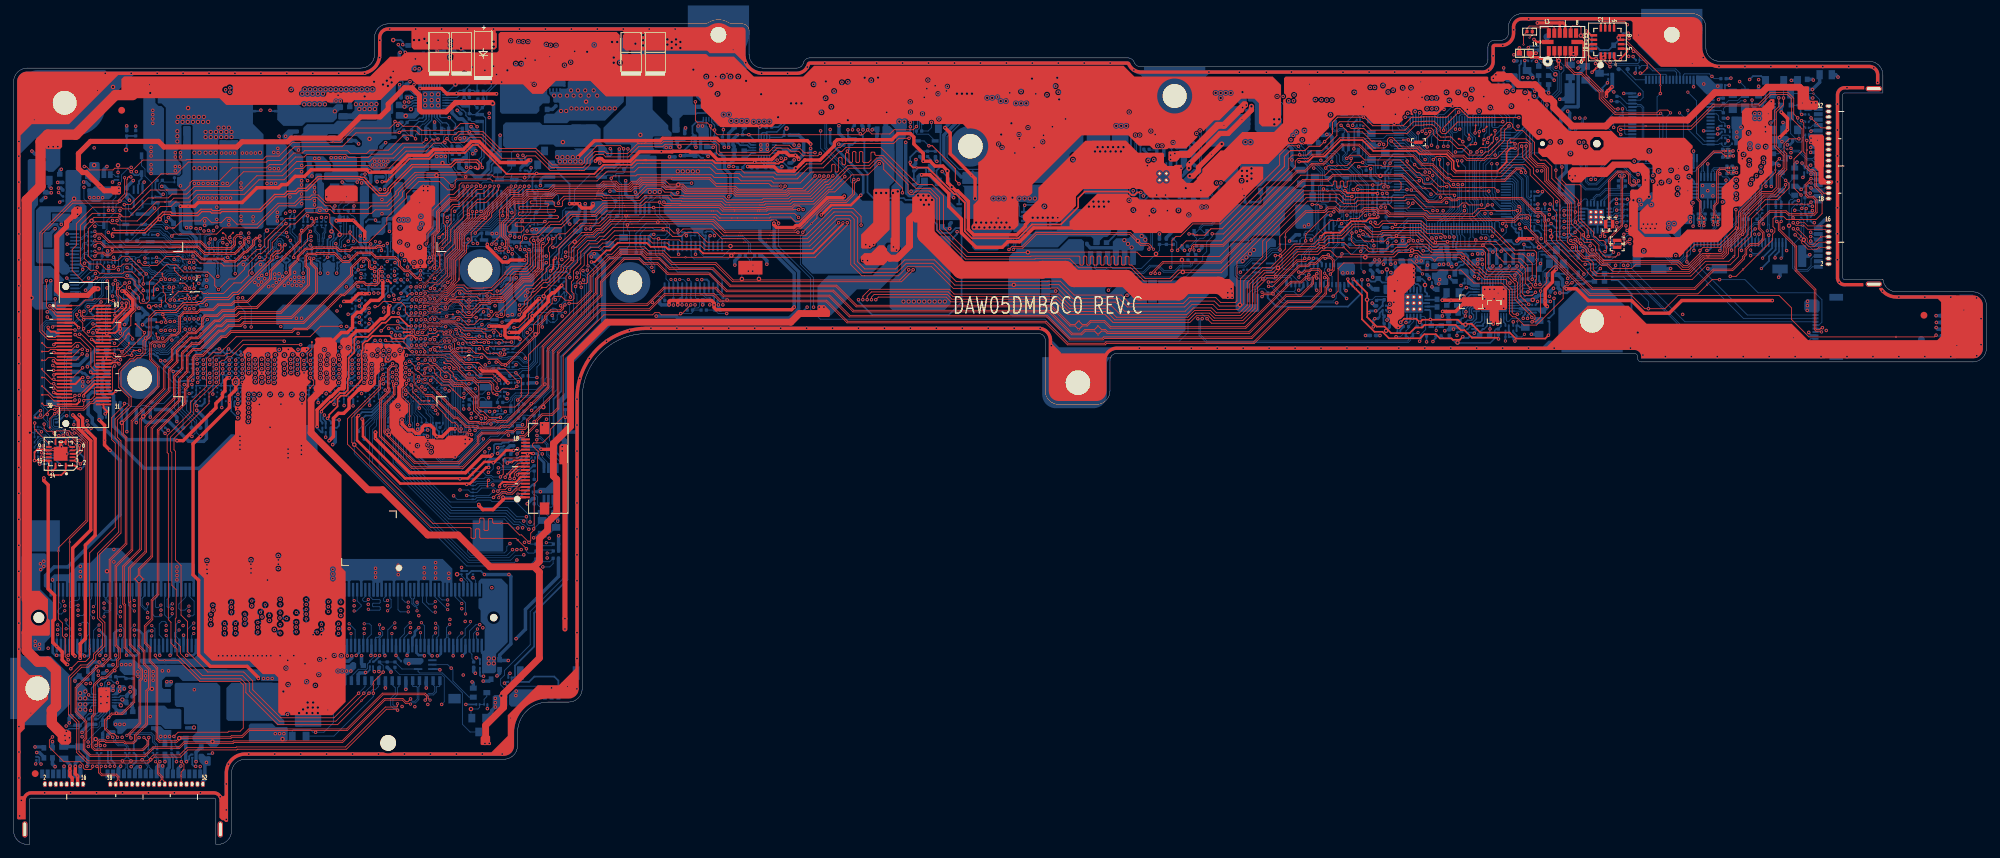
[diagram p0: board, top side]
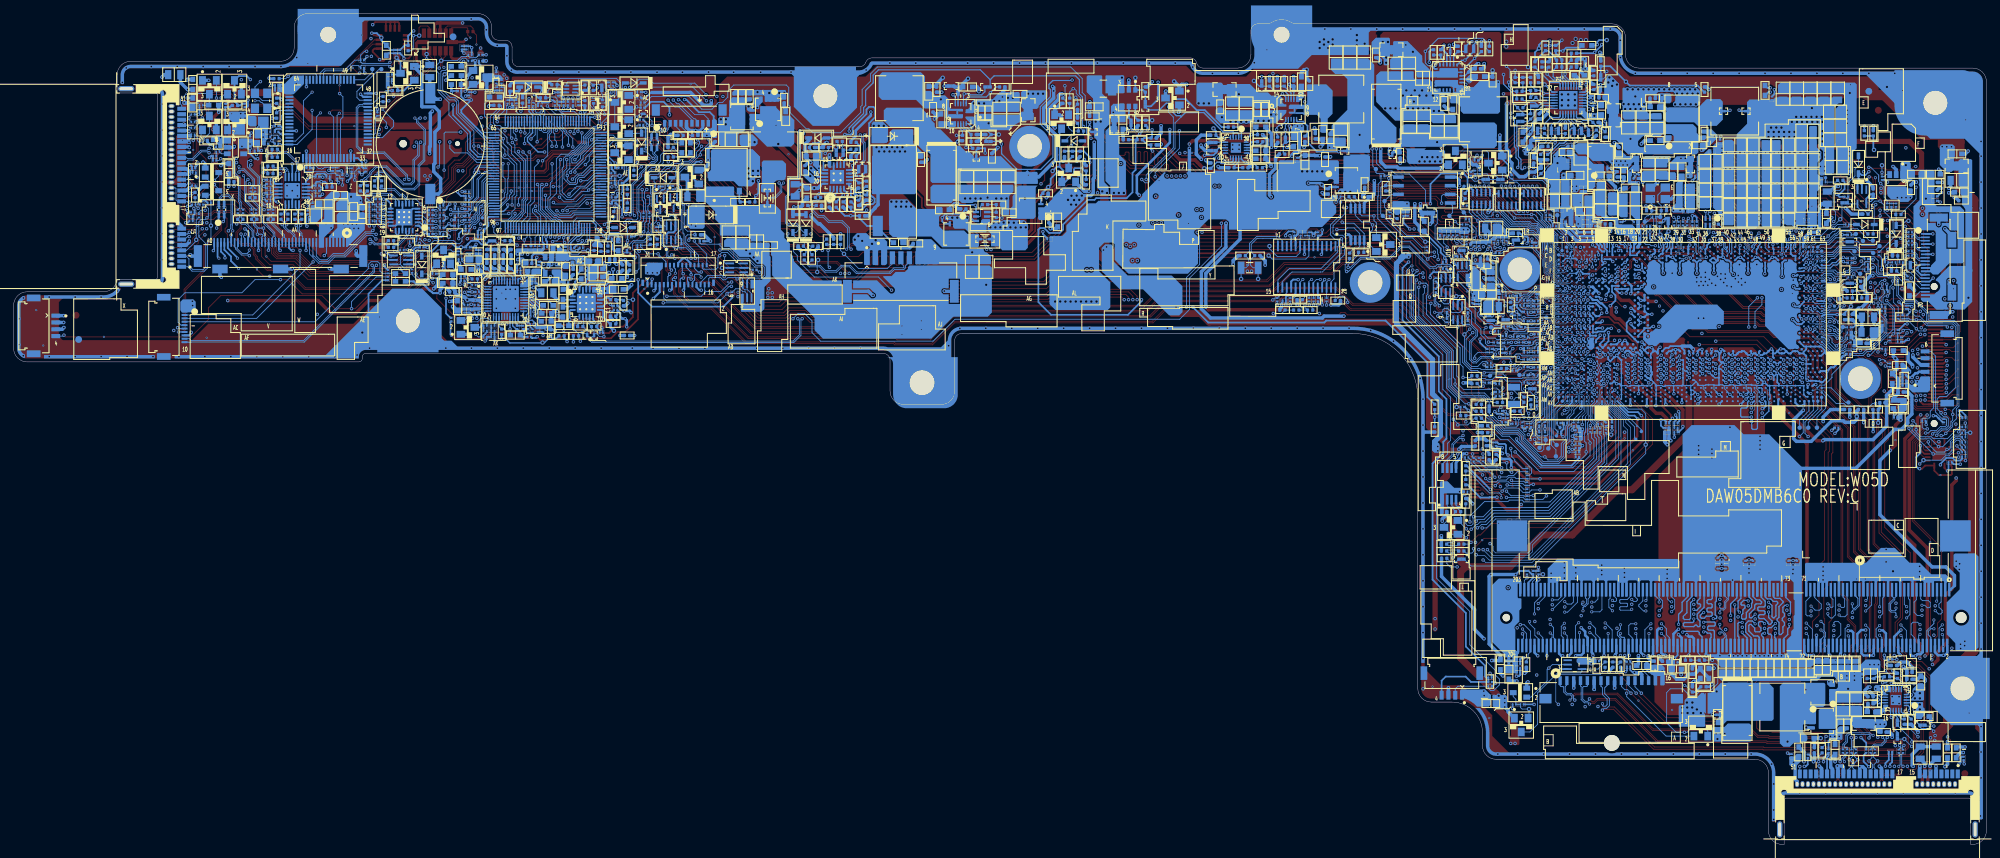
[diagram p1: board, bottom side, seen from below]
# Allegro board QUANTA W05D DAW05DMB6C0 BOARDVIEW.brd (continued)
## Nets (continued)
M_B_DQSN6: JDIM1.169 U20.AN21
M_B_DQSN7: JDIM1.186 U20.AN18
M_B_DQSP0: JDIM1.29 U20.AN58
M_B_DQSP1: JDIM1.47 U20.AN55
M_B_DQSP2: JDIM1.12 U20.AL42
M_B_DQSP3: JDIM1.64 U20.AL49
M_B_DQSP4: JDIM1.137 U20.AM28
M_B_DQSP5: JDIM1.154 U20.AM25
M_B_DQSP6: JDIM1.171 U20.AM21
M_B_DQSP7: JDIM1.188 U20.AM18
M_B_ODT0: JDIM1.116 R460.2
M_B_ODT1: JDIM1.120 R459.2
M_B_RAS#: JDIM1.110 U20.AM35
M_B_WE#: JDIM1.113 U20.AK35
MAG_DRDY: U1.9 U5.35
MAIND: PC116.1 PQ11.4 PU6.10
MAIND3.3V: PC114.1 PQ10.4 PU6.12
MAINON: PR4.2 PR35.2 PR129.2 PU6.2 PU6.4 U7.99
MBATLED0#: CN6.12 R222.2 U7.105
MBCLK: C112.1 PC136.1 PD8.1 PR95.2 PR121.2 R107.2 U7.77
MBCLK2: C134.1 CN11.10 Q21.4 R132.2 R235.2 R485.2 U7.79 U21.8
MBDATA: C119.1 PC135.1 PD7.1 PR96.2 PR120.2 R125.2 U7.78
MBDATA2: C155.1 CN11.9 Q21.1 R151.2 R241.2 R482.2 U7.80 U21.7
MINICAR_PME#: CN5.1 Q12.1 Q13.1 R120.1
MPHY_PWREN: PR51.2 R321.1 R324.1 U20.Y2
MUTE_LED_CNTL: R161.2 R176.1 U7.82 U18.40
NB670BST: PR21.2 PU4.10
NB670BST_S: PC25.1 PR21.1
NB670EN: PC23.2 PR22.1 PU4.13
NB670ENLDO: PR23.1 PR24.2 PU4.12
NB670PG: PR68.1 PU4.4
NB670SW: PC25.2 PL5.1 PR63.2 PU4.8 PU4.9 PU4.15 PU4.16
NB670VOUT: PC80.1 PR78.1 PU4.7
NB671BST: PR43.2 PU5.10
NB671BST_S: PC50.1 PR43.1
NB671EN: PC73.2 PR71.1 PU5.13
NB671FB: PR62.1 PR70.2 PR76.2 PU5.12
NB671PG: PR26.1 PU5.4
NB671SW: PC50.2 PL4.1 PR30.2 PU5.8 PU5.9 PU5.15 PU5.16
NBSWON1#: C230.1 CN10.4 Q5.3 R84.2 U7.19
OS1_1: R147.2 R167.1 U12.4
OS2_1: R133.2 R134.1 U12.15
OVT_DETC: D4.2 Q8.2 R53.1
PCH_DISP_ON: R91.2 U8.3 U20.C6
PCH_DPST_PWM: R168.2 R248.1 R249.1 U20.B8
PCH_DPST_PWM_R: C219.1 CN7.17 R249.2 R262.1
PCH_EDP_BLON: R127.1 R128.1 R129.1 U20.A9
PCH_HOME_BUTTON#: R345.1 U7.45 U20.Y3
PCH_INVRMEN: R423.2 U20.AV7
PCH_OPI_RCOMP: R439.2 U20.AW15
PCH_POWER_BUTTON#: R219.1 U7.47 U20.L3
PCH_ROTATE#: R204.1 U7.46 U20.R5
PCH_SLP_S0_N: R142.1 R444.2 U20.AF3
PCH_SLP_WLAN_N: TP51.1 U20.AM5
PCH_SPI1_CLK: R238.2 U20.AA3
PCH_SPI1_CLK_R: C98.1 R144.1 R238.1 TP72.1 U9.6
PCH_SPI1_SI: R87.2 U20.AA2
PCH_SPI1_SI_R: R87.1 R210.1 TP66.1 U9.5
PCH_SPI1_SO: R159.2 U20.AA4
PCH_SPI1_SO_R: R159.1 R229.1 TP70.1 U9.2
PCH_SPI_CS0#: R173.2 U20.Y7
PCH_SPI_CS0#_R: R145.1 R173.1 TP73.1 U9.1
PCH_SPI_IO2: R131.2 U20.Y6
PCH_SPI_IO3: R141.1 U20.AF1
PCH_SUSCLK: R228.2 R311.2 TP20.1
PCH_SUSCLK_L: R311.1 U20.AE6
PCH_THRMTRIP#: R213.1 U20.D60
PCH_VOL_DOWN#: R190.1 U7.44 U20.U7
PCH_VOL_UP#: R273.1 U7.43 U20.L4
PCI_PME#: TP39.1 U20.AD4
PCI_SERR#: R214.1 TP29.1 U7.68 U20.V6
PCIE_CLKREQ0#: R291.1 U20.U2
PCIE_CLKREQ3#: R199.1 U20.N1
PCIE_CLKREQ4#: R216.1 U20.U5
PCIE_CLKREQ5#: R294.1 U20.T2
PCIE_CLKREQ_CR#: CN13.10 R313.1 U20.Y5
PCIE_CLKREQ_WLAN#: R152.2 R338.1 U20.AD1
PCIE_IREF: R164.2 U20.B27
PCIE_RCOMP: R174.1 U20.A27
PCIE_RXN2_CARD: CN13.2 U20.F15
PCIE_RXN3_WLAN: CN5.23 U20.G11
PCIE_RXP2_CARD: CN13.1 U20.G15
PCIE_RXP3_WLAN: CN5.25 U20.F11
PCIE_TXN2_CARD: C173.2 CN13.5
PCIE_TXN2_CARD_C: C173.1 U20.B31
PCIE_TXN3_WLAN: C171.2 CN5.31
PCIE_TXN3_WLAN_C: C171.1 U20.C29
PCIE_TXP2_CARD: C174.2 CN13.4
PCIE_TXP2_CARD_C: C174.1 U20.A31
PCIE_TXP3_WLAN: C172.2 CN5.33
PCIE_TXP3_WLAN_C: C172.1 U20.B30
PCIE_WAKE#: CN13.12 Q12.3 R360.1 U7.72 U20.AJ5
PD#: D10.2 Q18.3 R237.1 R245.2 U18.39
PIRQC#: R203.1 U20.N4
PIRQD#: R272.2 R285.1 U20.N2
PIRQD#_L: R39.1 R212.1 R239.1 R272.1
PLTRST#: CN5.17 CN5.22 CN13.11 R307.1 R383.2 U7.13 U15.16 U20.AG7
PM_BATLOW#: R428.1 U20.AN4
PM_EXTTS#0: JDIM1.198 R462.2 U21.6
PM_THRMTRIP#: C19.1 Q4.1 R32.1 R213.2
PROC_DETECT#: TP81.1 U20.D61
PROC_OPI_RCOMP: R440.2 U20.AY15
PROCHOT#: R261.2 U20.K63
PROCPWRGD: R200.2 TP78.1 U20.C61
PWR_DEBUG: CN1.53 R96.1 R97.2 TP67.1 U20.H59
R_SPK+: C210.1 CN6.39 U18.37
R_SPK-: C211.1 CN6.38 U18.36
REGN6V: PC87.2 PD4.2 PR109.2 PU7.16
REQ_WLAN#: CN5.7 R152.1
RF_LINK#: CN5.46 R52.1 U7.114
RF_OFF: Q6.2 R396.1 TP55.1 U20.AM2
RSMRST#: R401.2 R409.1 U7.95 U20.AW6
RTC_RST#: C15.1 R22.2 R31.2 R447.2 U20.AU7
RTC_X1: C278.1 R386.1 U20.AW5 Y4.1
RTC_X2: C281.1 R386.2 U20.AY5 Y4.2
S5_ON: PR22.2 PR71.2 U7.101
SATA0GP: R304.1 TP10.1 U7.48 U20.U1
SATA1GP: CN14.51 R303.1 R314.1 TP88.1 U20.V1
SATA_IREF: R155.2 U20.A12
SATA_RCOMP: R169.2 U20.C12
SATA_RXN0: C64.1 R4.1 U20.J8
SATA_RXN0_C: C64.2 U10.4
SATA_RXN0_DC: C159.2 CN6.16 R487.2
SATA_RXN0_DC_1: R4.2 R487.1
SATA_RXN0_DC_L: C159.1 U10.12
SATA_RXN1: C353.1 U20.J5
SATA_RXN1_C: C353.2 CN14.25
SATA_RXP0: C74.1 R5.1 U20.H8
SATA_RXP0_C: C74.2 U10.5
SATA_RXP0_DC: C158.2 CN6.17 R488.2
SATA_RXP0_DC_1: R5.2 R488.1
SATA_RXP0_DC_L: C158.1 U10.11
SATA_RXP1: C354.1 U20.H5
SATA_RXP1_C: C354.2 CN14.23
SATA_TXN0: C57.1 R3.1 U20.A17
SATA_TXN0_C: C57.2 U10.2
SATA_TXN0_DC: C160.2 CN6.15 R486.2
SATA_TXN0_DC_1: R3.2 R486.1
SATA_TXN0_DC_L: C160.1 U10.14
SATA_TXN1: C351.1 U20.B15
SATA_TXN1_C: C351.2 CN14.31
SATA_TXP0: C52.1 R2.1 U20.B17
SATA_TXP0_C: C52.2 U10.1
SATA_TXP0_DC: C161.2 CN6.14 R481.2
SATA_TXP0_DC_1: R2.2 R481.1
SATA_TXP0_DC_L: C161.1 U10.15
SATA_TXP1: C350.1 U20.A15
SATA_TXP1_C: C350.2 CN14.33
SCLK: PR57.1 PR97.2 PU3.5
SDIO: PR55.1 PR89.2 PU3.3
SDIO_CLK: RP2.3 U20.E3
SDIO_CMD: RP2.2 U20.F4
SDIO_D1: RP2.1 U20.E4
SDIO_D2: RP3.2 U20.C3
SDIO_D3: RP2.9 U20.E2
SDVO_CLK: CN8.26 R184.2 U20.B9
SDVO_DATA: CN8.6 R185.2 U20.C9
SENSE_A: CN8.1 R327.2
SENSE_A_1: C361.2 R327.1 R334.1 U18.13
SERIRQ: R215.1 U7.3 U15.27 U20.T4
SIO_EXT_SCI#: R426.1 TP102.1 U7.20 U20.AU2
SIO_EXT_SMI#: R337.1 U7.32 U20.AC1
SLATE_EC_RESET: Q14.1 U7.49
SLP_A#: R449.2 TP63.1 U20.AL5
SLP_LAN#: TP45.1 U20.AJ7
SLP_S0#_EC: R142.2 U7.1
SLP_S5#: R452.2 U20.AP5
SLP_SUS#: R382.1 U20.AP4
SLP_SUS#_EC: R382.2 U7.115
SLP_SUS_ON: R247.1 U7.100
SM_DRAMRST#: R456.1 U20.AV15
SM_INTRUDER#: R410.2 U20.AU6
SM_RCOMP_0: R394.1 U20.AU60
SM_RCOMP_1: R393.1 U20.AV60
SM_RCOMP_2: R417.1 U20.AU61
SM_VREF: C342.1 R467.1 U20.AP49
SMB_ME0_CLK: R378.2 U20.AN1
SMB_ME0_DAT: R369.2 U20.AK1
SMB_ME1_CLK: Q21.3 R264.2 U20.AU3
SMB_ME1_DAT: Q21.6 R268.2 U20.AH3
SMB_PCH_CLK: Q22.6 R315.2 U20.AP2
SMB_PCH_DAT: Q22.3 R300.2 U20.AH1
SMB_RUN_CLK: CN1.57 JDIM1.202 Q22.1 R299.2 R332.2
SMB_RUN_DAT: CN1.56 JDIM1.200 Q22.4 R312.2 R331.2
SMBALERT#: R377.1 U20.AN2
SMC: CN9.5 PR121.1
SMD: CN9.6 PR120.1
SMDDR_VREF_DQ1_M1: R355.2 R367.1 R376.2 R384.2 R387.1
SMDDR_VREF_DQ1_M3: C279.1 R376.1 U20.AP51
SML0ALERT#: R370.2 U20.AL2
SML1ALERT#: R403.2 TP96.1 U20.AU4
SPKR: R305.2 R309.2 U20.V2
SRTC_RST#: C16.1 R23.2 R31.1 U20.AV6
SUS_STAT#: TP44.1 U20.AG4
SUSACK#: R371.2 R372.1 R390.2 U20.AK2
SUSACK#_EC: R371.1 U7.17
SUSB#: R442.2 R443.2 U7.6 U20.AT4
SUSC#: R450.2 U7.16 U20.AJ6
SUSON: PR131.2 U7.98
SUSWARN#: R390.1 R397.2 R404.1 U20.AV4
SUSWARN#_EC: R397.1 U7.112
SWCLK: TP64.1 U5.49
SWDIO: TP65.1 U5.46
SWN: PR1.2 PR39.1
SYS_I: PC118.1 PR99.1 R207.1 U7.66
SYS_PWROK: C275.1 R230.1 R342.1 R346.1 U16.4 U20.AG2
SYS_RESET#: R356.1 R357.1 R446.2 U20.AC3
TD_IREF: R172.1 U20.B12
TEMP_MBAT: PC43.2 PR118.2 U7.63
TEST_A4: TP71.1 U20.A4
TEST_A60: TP79.1 U20.A60
TEST_A62: TP80.1 U20.A62
TEST_AV1: TP105.1 U20.AV1
TEST_AW1: TP103.1 U20.AW1
TEST_AW63: TP98.1 U20.AW63
TEST_AY60: TP97.1 U20.AY60
TEST_B2: TP13.1 U20.B2
THER_CPU: R69.1 R72.2
THER_GPU: R68.1 R71.2
THRM_ALERT_HW#1: R49.2 U7.103
THRM_MOINTOR: C22.2 C45.2 R61.1 R62.2 U7.74
THRM_MOINTOR1: C43.2 C194.2 R62.1 R68.2 R69.2 R206.1
TPM_PP: R194.1 R195.1 U15.7
TPM_XIN: C202.1 U15.13 Y3.2
TPM_XOUT: C203.1 U15.14 Y3.1
TS_INTB#: R293.1 U20.P4
TS_ON: C55.1 CN11.2 R25.2 R70.1 R73.2 U7.29
TSENSE: PC27.1 PR17.1 PU3.13
UART0_CTS: RP3.6 U20.G1
UART0_RTS: RP1.9 U20.J2
UART0_RXD: RP1.7 U20.J1
UART0_TXD: RP2.7 U20.K3
UART1_CTS: RP1.6 U20.J4
UART1_RST: RP1.8 U20.J3
UART1_RXD: RP3.4 U20.K4
UART1_TXD: RP3.7 U20.G2
UNDOCK_INT#: R162.2 R211.1 U7.81
UNDOCK_INT#_L: C189.2 CN8.27 R211.2 R212.2
USB30_RX1+: C96.1 R7.1 U20.H20
USB30_RX1+_C: C96.2 U12.12
USB30_RX1+_DC: CN6.33 R7.2 U12.19
USB30_RX1-: C97.1 R6.1 U20.G20
USB30_RX1-_C: C97.2 U12.11
USB30_RX1-_DC: CN6.34 R6.2 U12.20
USB30_RX3+: R474.2 U20.F17
USB30_RX3+_R: CN14.20 R474.1
USB30_RX3-: R473.2 U20.G17
USB30_RX3-_R: CN14.22 R473.1
USB30_TX1+: C90.1 R8.1 U20.B34
USB30_TX1+_C: C90.2 U12.9
USB30_TX1+_DC: C187.2 CN6.31 R8.2
USB30_TX1+_DC_C: C187.1 U12.22
USB30_TX1-: C91.1 R9.1 U20.C33
USB30_TX1-_C: C91.2 U12.8
USB30_TX1-_DC: C193.2 CN6.32 R9.2
USB30_TX1-_DC_C: C193.1 U12.23
USB30_TX3+: C348.2 U20.C31
USB30_TX3+_R: C348.1 CN14.38
USB30_TX3-: C349.2 U20.C30
USB30_TX3-_R: C349.1 CN14.36
USB+_CAMERA: L2.3 R63.1 U20.AP8
USB+_COMBO: CN8.23 U20.AM8
USB+_CR: CN8.20 U20.AT10
USB+_LEFT: CN8.11 U20.AT7
USB+_SENSOR: R34.1 U5.45 U20.AL15
USB+_TP: CN8.8 U20.AN13
USB+_TS: L12.2 R135.1 U20.AP13
USB+_WLAN: CN5.38 U20.AN11
USB-_CAMERA: L2.2 R64.1 U20.AR8
USB-_COMBO: CN8.9 U20.AN8
USB-_CR: CN8.12 U20.AR10
USB-_LEFT: CN8.22 U20.AR7
USB-_SENSOR: U5.44 U20.AM15
USB-_TP: CN8.25 U20.AM13
USB-_TS: L12.3 R136.1 U20.AR13
USB-_WLAN: CN5.36 U20.AP11
USB_BIAS: R380.1 U20.AJ10 U20.AJ11
USB_OC1#: R373.1 TP92.1 U20.AL3
USB_OC2#: R407.1 TP104.1 U20.AT1
USB_OC3#: R379.1 TP52.1 U20.AH2
USB_OC4#: R422.1 TP101.1 U20.AV3
USBP2+_C: CN3.10 L2.4 R63.2
USBP2-_C: CN3.9 L2.1 R64.2
USBP7+_C: CN11.6 L12.1 R135.2
USBP7-_C: CN11.7 L12.4 R136.2
VBOOT: PR15.1 PU3.14
VIBRATOR _OUT#: C276.1 CN12.3 R38.2 R274.1 U7.54
VOL_DOWN#: C283.1 CN12.5 R224.2 U7.109
VOL_UP#: C284.1 CN12.6 R225.2 U7.110
VOLMUTE#: D10.1 U7.121
VR_HOT#: PR54.1 PU3.2
VR_RDY: PR60.1 PU3.6
VR_SVID_ALERT#: C235.2 PR56.2 R276.2 R277.2
VR_SVID_CLK: PR57.2 U20.N63
VR_SVID_DATA: PR55.2 R55.2 R265.2
VREFOUT_C: C265.1 R322.1 U18.19
VRON: PR52.2 U7.34
WLAN_LED#: CN5.44 R48.2 R52.2
XCLK_BIASREF: R180.2 U20.C26
XDP_BPM0: CN1.41 U20.J60
XDP_BPM1: CN1.42 U20.H60
XDP_DBRESET_N: C260.2 CN1.7 R308.1
XDP_PRDY#_CPU: CN1.33 TP61.1 U20.J62
XDP_PREQ#_CPU: CN1.32 TP62.1 U20.K62
XDP_RST: CN1.8 R307.2
XDP_TCK0: CN1.59 R270.2 R278.2 R295.2 U20.E60
XDP_TCK1: CN1.58 R301.2
XDP_TDI: CN1.3 R424.2 R427.1
XDP_TDI_CPU: R253.2 U3.6 U20.F63
XDP_TDI_R: R427.2 R429.1 U3.5
XDP_TDO: CN1.5 R433.2 R436.2 R437.2 U3.2
XDP_TDO_CPU: R258.2 U3.3 U20.F62
XDP_TMS: CN1.2 R416.2 U3.9
XDP_TMS_CPU: R244.2 U3.8 U20.E61
XDP_TRST#: CN1.4 U3.12
XDP_TRST#_CPU: R361.2 U3.11 U20.AU62 U20.E59
XTAL24_IN: C137.1 R154.1 TP76.1 U20.A25 Y2.1
XTAL24_OUT: C138.1 R154.2 TP74.1 U20.B25 Y2.3
XTL_IN: C25.2 U5.5 Y1.3
XTL_OUT: C36.2 U5.6 Y1.1
N52444: PC140.2 PR122.2 PU8.5
N175071: PC47.1 PC60.1 PR37.2 PR41.1
N175281: PR52.1 PR53.2 PU3.1
N180533: PR46.1 PU2.5
N220342: PC120.1 PR81.1 PR82.1 PR83.2 PU7.6
N242734: PR11.2 PR17.2 PR28.1
N243140: PC29.2 PR35.1 PU2.1
N16845323: C28.2 C33.2 U4.1
N16845325: C14.2 U4.3
N16846403: Q5.2 R24.2
N16847081: Q5.1 R28.2
N16889934: R67.2 R70.2 U6.3
N16894218: CN14.12 R476.1
N16894369: CN7.18 R269.2
N16944248: PQ4.2 PR33.1 PR34.2
N16946334: PR51.1 PU6.1
N16946514: PC104.1 PQ5.4 PU6.9
N16955305: PQ12.6 PR110.1 PR111.2 PR114.2
N16955311: PQ12.5 PR114.1
N16955315: PQ12.2 PR110.2
N16955333: PQ12.1 PR113.1
N17009890: PC77.2 PR63.1
N17010003: PR76.1 PR88.1
N17010113: PC28.2 PR30.1
N17010150: PC79.2 PU5.11
N17010852: PC26.2 PR25.1 PU5.6
N17011739: PR67.1 PU4.3
N17011968: PR27.1 PU5.3
N17026582: Q18.2 R260.1
N17026606: C218.1 U18.1
N17026675: R252.2 U14.3
N17026679: C209.1 U14.4
N17026786: C261.2 U18.25
N17026790: C256.2 U18.26
N17027367: C266.1 U18.20
N17027369: C267.1 U18.21
N17027467: C270.1 Q23.3 R317.2
N17027622: C238.2 U18.29
N17056548: R58.1 R60.2 U5.15
N17056549: R65.1 R66.2 U5.16
N17056550: R88.2 R89.1 U5.17
N17056551: R76.2 R77.1 U5.20
N17056552: R78.2 R79.1 U5.21
N17056553: R80.2 R86.1 U5.22
N17056596: R34.2 U5.43
N17056616: R20.2 U5.60
N17056622: C37.2 R56.2 U5.7
N17056680: C8.1 U1.6
N17056681: C1.1 U1.12
N17056682: C1.2 U1.13
N17057085: D9.2 R129.2 R143.2
N17058760: R310.2 R318.2 R319.2 R330.2
N17058774: C226.1 U19.17
N17058778: C234.2 U19.15 U19.16
N17058793: C254.1 U19.4
N17058795: C240.1 U19.2
N17058821: C226.2 U19.18
N17058851: R335.1 U19.6
N17096515: R137.2 R146.2 U12.5
N17096516: R130.2 R138.2 U12.7
N17096525: R122.2 R123.2 U12.14
N17099741: C213.2 R234.1
N17099744: C212.2 R233.1
N17099747: C210.2 R231.1
N17099750: C211.2 R232.1
N17118471: CN14.44 R472.2
N17161794: Q19.3 R483.2 R484.2
N17161796: Q19.5 Q19.6 R221.2
N17179576: R193.2 U15.9
N17179620: C251.2 R297.1
N17184096: Q20.2 Q20.5 R257.2
N17184191: CN14.14 R475.1
N17187862: R45.2 U7.56
N17232057: D2.1 R49.1 R50.1
N17274037: TP1.1 U7.57
N17345972: C342.2 R470.2
N17367414: C363.1 U23.14
N17439687: TP75.1 U7.91
N17486948: R105.2 R109.1 U10.8
N17486952: R106.2 R111.1 U10.18
N17486954: R126.1 R139.2 U10.17
N17486955: R115.1 R119.2 U10.9
N17486967: R99.2 R101.1 U10.19
N17486969: R95.1 R98.2 U10.7
N17490098: TP9.1 U7.55
N17490148: TP5.1 U7.59
N17490164: TP2.1 U7.60
N17490215: TP8.1 U7.61
N17490231: TP4.1 U7.62
N17490548: R39.2 U7.51
N17490556: TP6.1 U7.52
N17490564: TP3.1 U7.53
N17679694: C34.2 Q7.2 R43.2
N19259806: R302.1 U20.U3
N19299291: R171.1 U20.C35
N19299303: R170.1 U20.C34
N19299315: R434.1 U20.AK8
N19299327: R432.1 U20.AL8
N19301607: TP22.1 U20.P60
N19301610: TP87.1 U20.P61
N19301613: TP23.1 U20.N59
N19301616: TP26.1 U20.N61
N19301674: TP95.1 U20.AW14
N19301676: TP100.1 U20.AY14
N19341308: Q27.1 R459.1 R460.1
N20856073: C279.2 R395.1
N20883509: C185.2 C191.2 U7.124
N20883800: R206.2 R207.2 U7.102
N20883858: TP77.1 U7.106
N20884583: D8.2 U7.116
N20884623: R1.1 U7.30
N21174483: C128.1 R110.1
N21758480: Q4.2 R40.1 R46.1
N21762370: TP82.1 U20.C62
N21762386: TP83.1 U20.C63
N21762388: TP99.1 U20.AV63
N21762392: TP94.1 U20.AU63
N21810180: C26.2 D3.2 R29.1 R35.2 R36.1
N21813127: CN2.3 R445.1 R448.1
N21954661: C208.2 R247.2 R254.2 R255.1 U17.3
N22163425: R451.1 U21.4
N22182298: CN1.1 R344.1
N22183490: CN2.15 R443.1 R444.1
N22646069: C345.2 Q25.3 Q26.2 R471.2
N24211466: R235.1 U13.8
N24211476: R241.1 U13.7
N24212148: Q3.3 R43.1 R44.2
N24468332: CN5.45 R54.1
N24811948: R17.1 U7.69
N31839427: C133.1 R108.2
N33084308: PQ9.3 PR102.2
N38782190: PC152.2 PR132.1
N41545033: PR47.2 PR48.2 PU2.6
N41545044: PR48.1 PR59.2
N41545080: PC68.1 PR49.2 PU2.4
N41583684: PR6.2 PU1.6
N41583721: PC21.1 PR16.1
N41583760: PC42.2 PR36.1
N41915855: PC40.2 PR38.1
N41915908: PR10.2 PR40.1
N41916085: PC22.2 PR18.2 PR19.1
N41916105: PR2.2 PR3.2 PR29.2
N41916134: PC31.1 PR32.2
N41916242: PR14.2 PU3.16
N44133821: TP40.1 U20.AL32
N44134111: TP57.1 U20.AP32
N73864983: PQ8.3 PR82.2
N73866209: PR72.1 PR87.1 PU7.10
N73866453: PQ4.3 PQ8.2 PR94.2 PR98.2
N73866532: PC41.1 PR42.1
N80459806: CN5.5 R124.1
N122990257: CN1.35 R366.2
N124847733: CN2.2 R442.1
N124847739: CN2.4 R452.1
N124847742: CN2.6 R449.1
N124847745: CN2.9 R447.1
N124847750: CN2.11 R441.1
N124847755: CN2.13 R446.1
N124847822: CN2.5 R450.1
N167749240: TP11.1 U20.B51
N167821380: TP106.1 U20.AV2
N1677602219: TP12.1 U20.A51
N1677602244: TP85.1 U20.L60

Pads without a net: CN2 16 17 18 19 20; CN3 11 12; CN5 3 30 32 42 47 49 53 54; CN8 32 33; CN10 5 6; CN11 11 12; CN12 7 8; CN13 17 18; CN14 1 3 5 7 8 10 11 13 16 17 19 30 32 42 45 46 47 49 53 54; FAN1 5 6; JDIM1 77 122 125 207 208; PU4 5; PU5 5; PU6 3 7 11; U1 8; U5 2 3 4 8 9 10 11 14 23 24 25 29 30 33 34 37 38 39 40 41 42 50 51 52 53 54 56 57 61 62; U6 4; U7 21 39 40 41 58 85 86 87 88 89 104 107 108; U11 1; U12 24; U13 6; U15 1 2 3 6 12; U18 4 14 15 16; U20 A5 A6 A8 A21 A23 A29 A33 A37 A39 A49 A53 AA23 AA59 AB21 AB23 AC2 AC4 AC20 AC58 AC59 AD2 AD23 AD59 AD60 AE59 AE60 AF2 AF4 AF20 AG58 AH60 AH61 AH62 AH63 AJ61 AJ62 AK60 AK61 AK62 AK63 AL1 AL11 AM10 AM11 AM60 AM61 AM62 AM63 AN10 AN61 AN62 AP7 AP33 AP35 AP36 AP60 AP61 AP62 AP63 AR32 AR35 AR36 AR38 AR51 AT2 AU10 AU12 AU15 AU17 AU19 AU21 AU23 AU25 AU27 AU29 AU31 AU34 AU35 AU36 AU37 AU39 AU40 AU41 AU42 AU43 AU44 AU52 AU54 AU56 AU58 AV10 AV17 AV18 AV19 AV21 AV22 AV23 AV25 AV26 AV27 AV29 AV30 AV31 AV35 AV37 AV40 AV42 AV44 AV50 AV52 AV53 AV54 AV56 AV57 AV58 AV62 AW10 AW17 AW18 AW19 AW21 AW22 AW23 AW25 AW26 AW27 AW29 AW30 AW31 AW34 AW36 AW39 AW41 AW43 AW49 AW52 AW53 AW54 AW56 AW57 AW58 AY8 AY17 AY19 AY21 AY23 AY25 AY27 AY29 AY31 AY34 AY36 AY37 AY39 AY41 AY42 AY43 AY52 AY54 AY56 AY58 B5 B6 B14 B21 B22 B23 B29 B33 B37 B38 B39 B43 B49 B50 B53 B54 C5 C15 C17 C21 C22 C23 C37 C42 C43 C46 C47 C49 C50 C51 C53 D1 D9 D11 D15 D17 D58 E1 E5 E6 E8 E10 E13 E15 E18 F5 F6 F8 F10 F13 F18 F22 G10 G13 H6 H10 H18 H22 J6 J20 J21 J58 K10 K18 K21 L11 L59 M20 M21 N23 N58 N60 P20 R20 R23 T23 T59 U10 U59 V21 V59 W23 Y4 Y20 Y22; U22 1; U* 1; U*#2 1; U*#3 1; U*#4 1; U*#5 1; U*#6 1; Y1 2 4

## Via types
v1: diameter 0.305, hole 0.152, TOP to BOTTOM, 212 vias
v2: diameter 0.508, hole 0.254, TOP to BOTTOM, 2873 vias
v3: diameter 0.457, hole 0.254, TOP to BOTTOM, 237 vias
v4: diameter 0.66, hole 0.33, TOP to BOTTOM, 109 vias
v5: diameter 0.61, hole 0.356, TOP to BOTTOM, 309 vias

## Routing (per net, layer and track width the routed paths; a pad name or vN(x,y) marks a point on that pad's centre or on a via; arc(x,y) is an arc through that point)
51216VBST:
  vias: v2(15.11,19.27)
51216VBST_S: length 1.2
  BOTTOM w0.508: PC143.1 17.4,20.14 17.49,20.05 PR125.1
51216VDDQSNS: length 32
  IN1 w0.508: v2(13.96,23.65) 13.96,24.06 15.28,25.38 17.39,25.38 18.13,26.12 23.89,26.12 25.8,24.21 34.03,24.21 37.94,20.3 39.01,20.3 v2(40.23,19.08)
  BOTTOM w0.178: PU8.9 13.68,23.06 13.71,23.09 13.71,23.4 v2(13.96,23.65)
  BOTTOM w0.254: PR126.1 40.17,19.03 v2(40.23,19.08)
81101VCC: length 7.6
  BOTTOM w0.178: PU3.28 64.08,108.08 64.38,107.78
  BOTTOM w0.508: 64.38,107.78 64.38,107.42 65.28,106.52 PC61.2 65.91,106.52 66.54,105.9 66.54,105.01 v2(66.92,104.63) 66.92,104.42 67.68,103.66 67.68,103.51 PR66.1
81101VRMP: length 7.2
  BOTTOM w0.178: PU3.7 60.19,106.79 60.06,106.66 59.56,106.66 59.22,106.33 58.09,106.33 PC64.1
  BOTTOM w0.203: PC64.1 57.2,105.44 57.06,105.44 56.68,105.06 56.42,105.06 PR64.1 55.87,104.76 55.87,106.02 v2(56,106.15)
81101VSN: length 5.5
  BOTTOM w0.178: PC47.2 67.32,108.92 66.26,108.92 66.02,108.68 PR37.1 65.78,108.44 65.34,108.88 PU3.26
81101VSP: length 5.8
  BOTTOM w0.178: PU3.27 65.19,108.48 65.81,107.85 66.01,107.85 66.41,107.45 66.41,107.03 PC60.2 67.29,106.15 PR45.1
+0.75V_DDR_VTT: length 1.1
  BOTTOM w0.178: PU8.1 11.53,20.4 11.3,20.17 v2(11.3,19.66)
  vias: v5(9.77,22.2) v5(9.77,21.44) v5(10.53,22.46) v5(10.51,21.44) v5(69.77,27.31) v5(69.77,26.57) v5(70.53,27.31) v5(70.5,26.57)
+1.5V: length 439.5
  TOP w0.508: v2(54.1,82.79) 54.22,82.67 54.22,80.5 53.61,79.89 52.44,79.89 51.55,79 51.55,78.72 50.97,78.14 50.46,78.14 49.78,77.45 49.78,75.93 49.01,75.16 48.13,75.16 46.6,73.64 ; v2(77.46,58.02) 78.86,58.02 79.27,58.43 ; v2(228.01,81.59) 229.51,81.59 231.23,79.86 237.6,79.86 239.45,78.01 243.12,78.01 244.98,79.86 v2(258.26,79.86)
  TOP w1.016: 262.63,110.83 262.27,111.18 257.52,111.18 256.74,110.39 249.83,110.39 245.81,106.38 234.74,106.38 233.85,105.49 228.87,105.49 226.18,108.18 226.18,108.97 225.67,109.48 225.05,109.48 224.4,110.13 224.4,110.57 223.41,111.56 221,111.56 219.8,112.76 218.56,112.76 ; 76.43,40.77 77.21,41.55 77.21,44.94 78.42,46.15 78.42,47.27 79.75,48.6 79.75,53.6 79.27,54.08 79.27,58.86 81.78,61.37 81.78,71.33 87.14,76.69 114.14,76.69 115.41,77.96 119.37,77.96 ; 76.43,40.77 69.94,40.77 65.28,45.43 60.81,45.43 54.17,52.08 52.04,52.08 43.68,60.43 43.68,65.26 44.95,66.53 ; 76.43,40.77 77.21,40 77.21,27.36 71.95,22.1 71.95,20.12 69.31,17.48 69.31,15.63 69.46,15.47
  IN1 w0.508: CN5.6 266.04,86.83 259.07,79.86 v2(258.26,79.86)
  IN1 w1.016: v2(217.67,113.01) 217.67,112.88 v2(217.29,112.5) 217.24,112.45 212.93,112.45 212.88,112.4 182.57,112.4 177.84,107.68 172.71,107.68 171.86,106.83 167.97,106.83 162.12,112.68 136.01,112.68 132.99,109.66 132.99,109.07
  IN2 w0.508: CN14.6 6.2,9.93 6.09,10.04 v2(6.09,11.41) ; CN14.48 26.2,9.91 26.23,9.94 26.23,10.57 26.74,11.08 v2(26.74,11.46) ; CN14.28 18.2,9.89 18.15,9.94 ; 16.96,9.94 17.26,10.24 v2(17.26,11.41)
  IN2 w1.016: 6.19,9.94 28.24,9.94 32.45,14.15 50.31,14.15 53.18,17.02 56.84,17.02 58.51,15.35 68.57,15.35
  BOTTOM w0.254: v2(17.26,11.41) 18.03,12.17 18.03,13.07 C352.1 ; C359.1 26.23,11.74 26.51,11.46 v2(26.74,11.46) ; C73.1 262.95,98.06 262.83,97.95 v2(262.76,97.95) ; v2(264.43,91.29) 264.15,91.29 263.9,91.55 C167.1 ; U20.J15 54.4,82.49 v2(54.1,82.79) ; L16.1 226.79,83.8 R260.2
  BOTTOM w0.508: C356.1 5.71,11.79 v2(6.09,11.41) ; v2(77.46,58.02) 77.06,58.43 75.14,58.43 R431.2 ; v2(228.01,81.59) 227.45,82.15 227.45,82.94 226.71,83.67 L16.1
  vias: v1(262.68,108.87) v2(69.21,14.83) v2(69.85,14.83) v2(118.31,78.9) v2(118.99,78.9) v2(129.2,87.74) v2(129.66,87.28) v2(264.03,108.9) v2(264.66,108.9) v5(129.13,95.66) v5(129.84,95.89) v5(130.07,106.15) v5(130.8,106.15)
+1.05V: length 168.7
  TOP w0.254: CN1.9 6.27,75.11 6.09,75.29 5.45,75.29 5.07,75.67 v2(5.07,75.93) ; v2(15.66,75.7) 15.51,75.7 14.93,75.11 CN1.52
  TOP w0.508: v2(15.92,81.26) 16.2,81.26 v1(16.56,80.89) 17.5,79.95 17.5,78.63 15.56,76.69 15.56,75.8 v2(15.66,75.7) ; v2(117.05,102.85) 116.55,103.35 103.62,103.35 103.28,103.69 95.3,103.69 94.96,103.35 92.81,103.35 85.3,103.35 v5(82.87,100.92)
  IN1 w0.508: v2(5.07,75.93) 5.07,76.43 6.37,77.73 6.37,77.86 7.54,79.02 10.89,79.02 v2(10.94,78.97) 11.19,79.23 11.19,80.12 12.03,80.96 13.17,80.96 13.24,81.02 14.35,81.02 14.47,81.13 15.79,81.13 v2(15.92,81.26)
  IN2 w0.508: v2(193.39,107.14) 191.28,107.14 189.9,105.76 187.56,105.76 185.74,103.94 179.9,103.94 172.52,96.56 167.6,96.56 165.63,98.53 156.64,98.53 154.36,100.81 144.25,100.81 143.95,101.11 143.95,104.08 142.16,105.86 138.7,105.86 136.85,104.02 136.44,104.02 135.6,104.86 134.69,104.86 133.16,103.33 132.17,103.33 130.94,102.1 119.58,102.1 118.83,102.85 v2(117.05,102.85)
  BOTTOM w0.254: 55.14,72.55 54.76,72.92 U20.AG14 ; 55.14,72.55 55.51,72.92 U20.AG13 ; 55.14,72.55 v2(55.11,72.55) ; C250.1 11.08,79.11 v2(10.94,78.97) ; v2(50.59,73.77) 50.21,73.39 U20.AF22 ; U20.AG17 53.16,72.92 v2(53.5,72.58) 53.85,72.92 U20.AG16 ; R46.2 196.97,108.18 196.11,109.05 194.25,109.05 193.39,108.18 v2(193.39,107.14)
  BOTTOM w0.305: v2(55.74,78.12) 55.74,78.72 56.47,79.45 56.67,79.45 57.17,79.95 U20.P9 57.83,79.99 57.83,80.02 U20.N8 ; U20.J11 56.31,82.49 v2(56,82.81) 56.1,82.91 56.17,82.91 U20.H11 ; U20.H15 54.18,83.46 v2(54.11,83.46)
  BOTTOM w0.508: v2(53.84,96.17) 53.81,96.17 53.74,96.25 53.18,96.25 L11.2 ; v2(21.76,96.63) 22.17,96.63 22.92,95.87 R118.1
  vias: v2(15.66,75.06) v2(44.21,100.74) v2(44.85,100.74) v2(52.72,99.78) v2(53.03,100.34) v2(53.36,99.78) v2(53.69,100.34) v2(53.99,99.78) v2(54.32,100.34) v2(54.35,78.19) v2(54.37,78.8) v2(54.65,99.78) v2(54.96,100.34) v2(56.63,91.7) v2(57.27,91.7) v2(57.9,91.7) v2(58.4,74.22) v2(58.46,73.31) v5(79.82,100.92) v5(80.21,100.28) v5(80.59,100.92) v5(80.97,100.28) v5(81.35,100.92) v5(81.73,100.28) v5(82.11,100.92) v5(82.49,100.28) v5(83.25,100.28)
+1.05V_MODPHY: length 68.1
  TOP w0.508: v2(115.28,100.61) 115.28,100.75 114.89,101.15 113.92,101.15 113.45,101.62 112.37,101.62 111.5,100.75 111.32,100.58 103.34,100.58 102.24,101.68 99.34,101.68 99.24,101.78 96.8,101.78 96.72,101.71 91.91,101.71 90.54,100.34 86.69,100.34 86.34,100.69 85.78,100.69 v2(85.44,100.35)
  IN2 w0.508: v2(85.44,100.35) 85.44,99.9 82.42,96.88 78.43,96.88 77.92,97.39 72.76,97.39 72.38,97.01 72.38,96.95 71.07,95.64 64.48,95.64 63.62,96.5 61.61,96.5 61.1,95.99 v2(60.83,95.99)
  BOTTOM w0.381: U20.L10 57.78,80.93 U20.M9 ; U20.L10 57.33,81.38 v2(56.89,80.93) ; U20.L10 57.78,81.82 U20.K9 57.81,81.88 v2(58.34,81.88)
  BOTTOM w0.508: v2(115.28,100.61) 116.02,101.35 116.02,103.43 115.31,104.15 PR65.1
  vias: v1(59.63,94.24) v2(58.82,84.77) v2(59.73,84.87) v2(60.19,96.65) v2(60.19,96.02) v2(60.83,96.63)
+1.05V_S2:
  vias: v4(80.66,103.13)
+1.05VS5:
  vias: v2(19.4,74.35)
+1.8VREF: length 4.5
  BOTTOM w0.178: PU8.6 12.48,23.16 12.31,23.32 12.31,23.73 12.94,24.36 PC139.1 13.08,24.36 13.45,24.36 13.71,24.62 PR124.1 14.21,24.86 v2(14.85,25.51)
+1.35VSUS: length 110.8
  TOP w0.102: 37.84,67.52 37.84,67.52 37.84,71.58 37.84,71.58
  TOP w0.127: 41.8,71.99 41.14,71.33 41.14,68.71 41.17,68.69
  TOP w0.152: 34.03,68.94 34.03,71.43 ; 36.92,68.33 36.92,68.79 ; 35.93,70.34 35.93,71.61 ; 36.82,71.61 36.89,71.54 36.89,69.51 ; 40.2,69.58 40.2,70.21 ; 34.99,68.94 34.99,71.46 ; 35.96,68.15 35.96,67.57
  TOP w0.178: 42.16,69.58 42.16,71.35
  IN1 w0.508: v2(73.78,30.21) 71.62,30.21 69.77,28.35 65.57,28.35 65.22,28 65.22,27.36 64.39,26.54 58.04,26.54 v2(58.03,26.52) v2(42.79,26.52)
  BOTTOM w0.178: U20.AN33 42.91,69.5 v2(42.65,69.24)
  BOTTOM w0.203: U20.AR48 33.94,68.2 33.59,67.85 v2(33.57,67.85)
  BOTTOM w0.254: v2(32.91,64) 32.75,64 32.41,64.33 32.41,64.98 U20.AY50 ; v2(39.25,64.66) 39.24,64.66 U20.AY40 ; U20.AY44 35.67,65.03 v2(36.08,64.61) ; U20.AJ31 44.34,72.52 44.73,72.91 44.73,73.17 46.42,73.17 46.68,72.91 47.11,72.91 U20.AH26 ; U20.AY35 41.96,65.08 v2(42.36,64.68) ; U20.AP43 36.92,68.93 36.64,69.21 v2(36.45,69.21) ; U20.AJ37 40.34,72.2 v2(40.34,72.68) ; U20.AJ33 v2(43.04,72.71)
  BOTTOM w0.356: JDIM1.118 42.95,30.24 43.22,30.51 43.7,30.51 v2(43.98,30.79) ; JDIM1.124 44.75,30.34 v2(45.2,30.79)
  BOTTOM w0.508: R466.1 43.17,26.14 v2(42.79,26.52) ; v2(73.78,30.21) 75.16,31.59 75.16,34.5 80.01,39.35 R455.2 ; R384.1 11.52,66.43 10.94,65.84 10.94,63.2 11.55,62.59 11.55,61.88 12.49,60.94 13.45,60.94 19.17,55.22 29.58,55.22 ; 44.73,73.17 43.5,73.17 v2(43.04,72.71)
  vias: v1(46.14,19.74) v2(28.39,41.05) v2(28.39,40.39) v2(28.42,39.76) v2(30.09,27.69) v2(30.73,27.69) v2(31.36,27.69) v2(32,27.69) v2(32.63,27.69) v2(33.24,59.92) v2(33.24,59.29) v2(33.24,58.65) v2(33.24,58.02) v2(33.27,27.69) v2(33.92,27.69) v2(34.56,27.69) v2(34.84,41.15) v2(34.86,40.5) v2(34.86,39.86) v2(35.2,27.69) v2(35.85,27.7) v2(36.49,27.69) v2(37.13,27.69) v2(37.28,38.82) v2(37.66,61.26) v2(37.78,27.7) v2(38.87,41.78) v2(38.87,41.14) v2(39.13,27.72) v2(40.3,58.04) v2(40.3,57.41) v2(40.3,56.77) v2(41.14,27.72) v2(42.26,58.54) v2(42.26,57.9) v2(42.26,57.27) v5(9.77,20.55) v5(9.77,19.82) v5(10.53,20.55) v5(10.53,19.79) v5(41.93,19.28) v5(42.51,19.82) v5(43.05,19.28) v5(43.17,20.83) v5(43.2,20.1) v5(43.93,20.1) v5(43.88,19.28) v5(43.98,20.83) v5(44.67,20.1) v5(44.67,19.28)
+1.35VSUS_S:
  vias: v4(39.61,22.45)
+3.3VS5_S:
  vias: v4(92.04,104.2)
+3V: length 468.6
  TOP w0.254: 231.26,116.74 231.26,117.25 231.52,117.51 U23.15 ; 231.26,116.74 231.26,115.88 231.72,115.42 v2(232.38,115.42) 232.76,115.04 233.08,115.04 ; 231.26,116.74 231.38,116.86 U23.16 ; v2(5.7,54.84) 5.73,54.84 6.15,55.26 U3.14 ; 233.08,115.04 233.08,114.68 v1(232.44,114.04) v2(231.79,113.39) ; 233.08,115.04 U23.1 ; U23.5 236.7,116.86 236.97,116.59 236.97,116.39 235.96,115.37 v2(235.96,115.25) 235.78,115.07 235.37,115.07 235.03,115.41 U23.4
  TOP w0.381: U1.14 223.64,117.84 v2(223.26,118.22) ; C2.2 222.6,115.8 222.83,115.58 223.94,115.58 224.15,115.37 225.21,115.37 225.45,115.61 U1.1
  TOP w0.508: v2(223.56,116.18) C2.2 ; v2(114.62,78.9) 114.24,78.52 103.19,78.52 102.86,78.85 v2(102.86,79.23) 102.86,79.49 102.49,79.86 97.53,79.86 ; v2(96.26,79.23) 96.26,79.74 96.39,79.86 97.53,79.86 ; 97.53,79.86 v2(97.53,79.23) ; 72.43,76.05 72.15,75.77 72.15,74.71 72.46,74.4 74.13,74.4 v2(74.36,74.18) ; 72.43,76.05 73.3,76.92 74.28,76.92 75.01,77.66 75.01,77.99 77.18,80.16 v2(77.18,80.17) ; 72.43,76.05 71.42,76.05 71.37,76.1 v2(69.82,76.1) ; v2(55.24,79.1) 55.06,78.92 55.06,77.88 54.37,77.2 53.92,77.2 52.14,75.42 50.36,75.42 49.17,74.22 ; v2(44.57,61.37) 44.57,63.81 46.52,65.77 46.68,65.77 47.82,66.91 48.25,66.91
  IN1 w0.254: v2(201.08,111.44) 201.08,110.7 200.42,110.04 197.3,110.04 197.2,109.94 196.44,109.94 195.85,110.52 192.32,110.52 v2(191.18,109.38) ; v2(221.63,112.63) 220.36,112.63 218.31,110.57 215.59,110.57 214.83,109.81 214.32,109.81 v2(214.01,109.5)
  IN1 w0.508: 24,10.19 23.92,10.27 v2(23.92,12.15) ; CN14.24 16.6,10.19 16.6,10.19 ; 22.6,10.19 22.6,11.77 v2(22.22,12.15) ; v2(14.17,11.46) 14.17,10.32 14.29,10.19 ; CN14.2 4.6,10.18 4.59,10.19 ; v2(3.24,11.82) 3.09,11.97 1.95,11.97 ; v2(69.13,39.63) 69.13,48.75 69,48.87 69,51.59 68.37,52.23 68.37,55.2 69.16,55.99 69.97,55.99 71.06,57.08 v2(71.06,57.41) ; v2(3.4,13.49) 2.02,13.49 1.95,13.57 ; v2(72.64,27.01) 72.89,26.75 v2(72.89,25.13) 74.67,23.35 74.67,21.19 70.2,16.72 53.69,16.72 51.76,14.79 33.47,14.79 30.73,12.04 v2(28.31,12.04) 28.31,10.57 27.8,10.06 CN14.52
  IN1 w1.524: 27.93,10.19 2.71,10.19 1.95,10.95 1.95,16.52 7.1,21.67 7.1,22.59
  IN2 w0.508: v2(77.64,75.98) 79.09,77.42 v2(79.09,77.68) 79.09,77.98 77.18,79.89 v2(77.18,80.17) 79.37,80.17 v2(79.54,79.99) 80.43,79.99 81.68,81.23 v2(81.68,83.24) ; v2(115.33,102.67) 115.61,102.67 116.07,102.21 v2(117.04,102.21) ; v2(237.81,115.7) 237.81,113.57 v2(238.12,113.26) ; v2(67.81,25.13) 68.06,25.38 72.64,25.38 v2(72.89,25.13) ; v2(72.74,39.63) 71.49,40.87 71.49,44.05 73.09,45.65 76.01,45.65 76.51,46.14 76.51,49.11 77.36,49.97 v2(77.36,51.8) ; v2(235.96,115.25) 235.93,115.22 235.93,114.66 235.33,114.06 235.33,113.24
  BOTTOM w0.127: v2(237.99,100.34) C72.2
  BOTTOM w0.254: R106.1 244.7,95.99 v2(244.37,96.32) 244.8,96.75 R99.1 ; C358.1 28.59,12.32 v2(28.31,12.04) ; v2(226.2,80.19) 226.2,77.98 225.53,77.31 R310.1 ; R128.2 v2(13.94,93.12) ; v2(201.08,111.44) 201.08,111.59 201.4,111.9 R25.1 ; R139.1 246.75,92.35 246.75,90.91 v2(246.63,90.78) ; CN14.41 23.4,12.77 23.18,12.98 C347.1 23.92,12.72 v2(23.92,12.15) ; Q22.5 v2(77.64,75.98) ; C4.2 C3.2 223.87,116.49 v2(223.56,116.18) ; R53.2 197.24,105.45 196.89,105.11 196.89,102.21 v2(196.82,102.14) ; U15.24 98.19,80.78 98.16,80.75 C242.1 97.9,80.23 97.53,79.86 v2(97.53,79.23) ; Q21.2 79.39,83.8 79.62,84.03 81.25,84.03 81.68,83.6 v2(81.68,83.24) ; R47.2 236.29,107.98 v2(236.26,108.01) ; RP1.5 75.43,96.12 75.68,96.37 v2(75.68,96.65) ; R337.2 68.87,74.63 v2(68.39,74.63) 67.9,74.63 R338.2 ; U10.16 246.39,94.99 246.25,94.85 246.25,94.59 v2(246.63,94.21) ; C360.1 3.34,11.92 v2(3.24,11.82) ; v2(201.01,95.59) 201.01,95.13 201.13,95 R116.1 ; R77.2 v2(241.57,98.9) 241.42,98.75 R89.2 ; v2(58.41,78.03) 58.23,77.84 U20.V8 58.05,77.57 57.78,77.3 U20.W9 ; R469.2 72.65,24.89 v2(72.89,25.13) ; v2(44.57,61.37) 44.57,61.14 45.18,60.53 C291.2 C289.1 ; U5.32 239.15,100.78 238.52,100.16 238.52,99.47 238.33,99.28 C72.2 ; R98.1 252.6,96.98 v2(252.95,96.63) 252.67,96.35 R105.1 ; JDIM1.199 67.25,38.46 66.57,39.15 C307.1 66.75,39.67 67.23,40.15 R457.2 68.61,40.15 v2(69.13,39.63) ; C38.2 250.53,104.32 v2(250.23,104.32) 250.19,104.28 U5.13 ; R302.2 68.27,78.21 68.94,78.88 R291.2 69.41,79.2 69.77,78.84 R290.1 69.59,78.58 69.59,78.06 69.79,77.86 v2(69.79,77.69) R305.1 ; R14.2 237.81,115.61 v2(237.81,115.7) ; C84.1 243.77,98.21 244.06,98.51 245.15,98.51 245.34,98.32 C83.1 v2(246.07,98.07) 246.79,97.36 U10.20 ; R299.1 79.24,77.83 v2(79.09,77.68) 79.24,77.53 R312.1 ; RP3.10 69.08,93.38 v2(68.65,92.94) 68.5,93.1 68.5,95.38 68.28,95.6 RP2.5 ; v2(240.68,97.39) 240.08,97.99 R86.2 240.07,98.16 R79.2 ; RP2.10 65.4,93.53 64.84,92.97 v2(64.76,92.97) ; v2(38.98,103.99) 39.11,103.87 EC2.1 ; R160.1 64.1,91.78 63.77,91.45 v2(63.67,91.45) 63.67,91.37 63.68,91.36 R177.2 ; v2(225.39,91.7) R161.1 R151.1 ; U20.K16 U20.K14 54.97,81.13 54.48,80.63 54.48,79.86 v2(55.24,79.1) ; v2(74.36,74.18) 74.36,73.7 73.4,72.74 R356.2 ; R293.2 66.92,79.1 v2(66.87,79.05) 66.4,79.05 R294.2 ; R314.2 66.95,76.81 v2(66.87,76.89) 66.79,76.81 66.37,76.81 R313.2 ; R18.2 238.24,114.01 238.24,113.39 v2(238.12,113.26) ; R119.1 252.57,94.44 v2(252.98,94.85) ; R287.2 66.97,79.86 v2(66.87,79.96) 66.86,79.98 66.68,79.98 66.46,79.76 R288.2 ; Q21.5 79.39,80.14 v2(79.54,79.99) ; R219.2 R218.2 v2(66.74,88.88) ; R308.2 12.31,79.13 v2(12.84,79.66) ; v2(245.66,99.32) 245.69,99.34 C67.2 246.2,99.35 U5.19 ; U10.10 251.31,94.99 251.45,94.85 251.45,94.59 251.2,94.34 v2(250.94,94.34) ; v2(224.86,94.04) 224.86,93.34 R132.1 ; v2(14.17,11.46) 14.17,11.77 13.85,12.08 EC15.1 ; v2(195.01,91.17) 194.68,90.84 R185.1 R184.1 ; v2(77.18,80.17) 77.48,79.87 77.55,79.87 77.64,79.78 Q22.2 ; R346.2 v2(67.58,73.72) R345.2 ; U10.6 251.26,96.99 251.46,97.2 v2(251.46,97.54) ; v2(232.38,115.42) 232.38,115.59 C364.2 C365.2 234.67,116.17 C362.2 ; U20.T9 v2(58.4,79) 58.4,78.7 U20.U8 ; R324.2 69.41,75.7 v2(69.82,76.1) 69.87,76.05 R320.2 ; CN3.1 186.89,106.95 187.47,107.52 189.07,107.52 190.92,109.38 v2(191.18,109.38) ; v2(198.16,89.59) 198.49,89.26 R201.1 ; U15.19 101.44,80.93 101.74,80.62 102.61,80.62 102.88,80.36 C243.1 102.88,79.24 v2(102.86,79.23) ; EC12.1 3.53,62.72 3.86,63.05 v2(3.95,63.05) ; v2(74.03,101.2) 74.03,100.94 74.54,100.44 EC5.1 ; RP1.10 72.89,93.53 73.27,93.15 73.27,92.87 v2(73.17,92.77) 73.14,92.74 73.02,92.74 72.43,93.32 72.43,95.36 72.22,95.57 RP3.5 ; R38.1 v2(214.01,109.5) ; v2(66.87,78.14) 66.84,78.16 66.4,78.16 R304.2 ; R248.2 14.89,86 v2(14.67,86.21) ; v2(69.52,80.54) 69.49,80.57 R273.2 R285.2 ; v2(5.7,54.84) 5.57,54.98 C295.2
  BOTTOM w0.279: 101.62,89.39 101.62,89.01 101.44,88.83 U15.10 ; 101.62,89.39 C181.1 ; 101.62,89.39 101.34,89.39 101.15,89.57 101.15,90.47 101.21,90.53
  BOTTOM w0.305: v2(227.07,80.99) 227.1,80.96 228.12,80.96 228.28,81.11 228.64,81.36 228.64,81.38 229.59,82.32 230.54,82.32 230.61,82.34 230.95,82.68 R259.2 ; U5.48 v2(236.44,110.28) ; v2(187.37,88.6) 187.39,88.58 R209.1
  BOTTOM w0.406: U13.1 91.37,94.19 90.79,94.77 C115.1
  BOTTOM w0.508: v2(214.52,83.39) 214.22,83.7 L14.2 ; R269.1 10.66,81.39 v2(10.56,81.39) ; v2(72.64,27.01) 71.49,27.01 C319.1 71.37,27.79 73.02,29.44 73.02,39.35 v2(72.74,39.63) v2(69.13,39.63) ; C115.1 90.24,95.1 89.88,95.46 v2(89.88,97.46) ; C357.1 4.44,12.83 3.78,13.49 v2(3.4,13.49) ; PR77.2 114.72,101.88 115.33,102.49 v2(115.33,102.67) ; v2(96.26,79.23) 95.12,79.23 94.85,79.49 R286.1 ; CN14.52 27.8,9.25 28.09,9.54 28.09,11.82 v2(28.31,12.04) ; v2(67.81,25.13) 67.56,25.38 R462.1 ; v2(22.22,12.15) C346.1 22.85,12.58 22.85,11.31 22.6,11.06 CN14.39 ; L17.1 226.81,82.25 226.81,81.7 227.07,81.45 v2(227.07,80.99) ; L18.1 225.16,79.84 225.26,79.74 v2(225.67,79.74) ; v2(114.62,78.9) 114.62,83.85 109.59,88.88 109.59,93.07 ; PR61.2 57.77,103.61 v2(57.8,103.61) ; 117.04,98.35 v2(117.04,102.21) ; R197.2 188.28,89.51 v2(187.37,88.6) ; R430.2 72.91,58.54 72.26,57.89 71.65,57.89 71.16,57.41 v2(71.06,57.41)
  vias: v2(3.17,29.82) v2(3.19,29.19) v2(3.8,29.39) v2(3.78,28.76) v2(3.93,41.2) v2(3.98,40.37) v2(4.44,41.59) v2(4.44,40.82) v2(10.15,67.92) v2(10.15,67.29) v2(10.63,23.6) v2(11.17,94.98) v2(11.27,23.65) v2(11.8,94.98) v2(12.44,94.98) v2(12.44,25.46) v2(12.44,24.82) v2(13.07,94.98) v2(47.62,25.46) v2(48.25,25.46) v2(48.89,25.46) v2(49.52,25.46) v2(70.27,89.69) v2(70.93,89.72) v2(76.14,90.28) v2(76.78,90.28) v2(187.9,104.12) v2(188.36,104.58) v2(209.36,85.17) v2(210,85.2) v2(225.54,80.5) v2(226.38,80.96) v2(248.2,111.66) v2(250.26,111.36) v2(253.05,104.6) v2(253.05,103.87) v2(253.66,105.31) v5(97.53,98.84) v5(98.26,98.84) v5(99,98.84) v5(99.74,98.84) v5(100.47,98.84) v5(130.68,79.72) v5(131.44,79.72) v5(132.2,79.72) v5(132.96,79.72) v5(133.72,79.72) v5(134.49,79.72) v5(135.25,79.72) v5(136.01,79.72) v5(136.75,79.72)
+3V_AVDD: length 4.6
  BOTTOM w0.203: U18.22 214.24,78.72 214.09,78.57 214.09,78.06 214.39,77.75 214.39,77.25 214.11,76.97 213.53,76.97 213.2,76.64 v4(213.2,76.33)
  BOTTOM w0.254: R317.1 v2(220.22,76.74)
  vias: v2(209.29,82.3) v2(209.42,82.94) v2(210.15,75.42) v2(211.45,75.67)
+3V_AVDD_2:
  vias: v1(214.11,82.91)
+3V_DEEP_SUS: length 292.7
  TOP w0.305: CN2.1 74.41,50.98 74.22,50.78 72.08,50.78 v2(71.87,50.98)
  TOP w0.508: v2(57.04,62.31) 57.04,61.75 57.93,60.86 58.57,60.86 59.07,60.37 59.56,60.37 60.01,60.82 60.01,61.22 60.34,61.55 61.21,61.55 61.71,61.04 61.71,60.33 v2(62.17,59.87) 62.96,59.87 64.11,61.03 v2(64.83,61.03) ; v2(68.46,69.92) 68.86,69.51 70.87,69.51 72.59,67.8 v2(72.59,67.77) ; v2(69.57,88.12) 69.57,87.75 71.8,85.53 72.66,85.53 72.94,85.81 v2(75.04,85.81) ; v2(68.32,49.92) 68.32,49.74 68.9,49.15 70.4,49.15 71.87,50.63 v2(71.87,50.98) ; v2(72.79,75.19) 74.19,75.19 76.17,77.17 v2(76.17,77.6) 76.42,77.6 78.52,79.69 78.52,80.4 79.13,81.02 79.4,81.02 v2(80.48,82.1) ; v2(9.77,27.34) v1(9.77,28.25) 9.77,29.44 10.53,30.21 10.53,43.95 11.97,45.38 11.97,59.57 10.13,61.41 10.13,62.59 v2(9.64,63.07)
  IN1 w0.508: v2(68.32,49.92) 68.32,51.14 67.66,51.8 67.66,58.22 v2(68.98,59.54) ; v2(70.22,37.7) 69.97,37.95 69.97,48.72 71.87,50.63 v2(71.87,50.98) ; v2(75.04,85.81) 75.68,85.81 77.44,87.56 77.97,87.56 78.68,88.27 78.82,88.27 78.87,88.32 79.91,88.32 79.98,88.4 79.99,88.39 80.52,88.39 80.89,88.76 80.89,88.8 81.68,89.59 v2(81.68,91.09)
  IN2 w0.508: v2(9.77,27.34) 9.77,28.55 10.06,28.84 27.16,28.84 28.94,27.06 42.18,27.06 42.28,27.16 43.68,27.16 44.44,26.4 50.16,26.4 50.52,26.03 50.52,25.23 51.24,24.51 51.96,24.51 52.32,24.87 52.32,26.01 52.87,26.57 55.88,26.57 57.02,27.71 57.02,27.88 57.51,28.38 67.96,28.38 72.18,32.6 72.18,34 70.22,35.96 v2(70.22,37.7) ; v2(17.01,94.59) 17.52,94.09 17.52,84.92 17.72,84.71 17.72,81.21 16.88,80.37 15.89,80.37 15.27,79.75 15.27,79.14 12.57,76.43 v2(11.65,76.43) 12.62,75.47 12.62,65.7 10.59,63.67 10.24,63.67 v2(9.64,63.07) ; v2(81.68,91.09) 81.68,88.5 81.41,88.23
  IN2 w1.016: 73.4,78.72 73.4,79.56 73.44,79.59 73.44,81.12 76.32,84 76.32,84.31
  BOTTOM w0.254: R377.2 67.21,67.65 v2(66.87,67.65) 66.53,67.65 R378.1 ; R348.2 71.76,73.64 71.3,73.64 v2(71.29,73.63) 70.83,73.63 R349.1 ; R413.2 67.76,61 v2(67.76,60.79) 68.14,61.17 R408.2 ; R369.1 66.95,70.08 v2(66.89,70.03) 66.4,70.03 R370.1 ; R333.2 66.82,74.91 v2(66.84,74.88) ; U20.AA9 U20.AC9 57.17,75.19 57.04,75.32 56.1,75.32 55.64,75.77 v2(55.08,75.77) ; v2(71.87,50.98) 72.97,50.98 73.02,50.93 74.31,50.93 76.18,52.8 R448.2 ; v2(62.17,59.87) 62.46,60.17 R422.2 62.1,60.98 62.1,61.6 62.06,61.64 R404.2 R403.1 ; v2(55.95,71.89) 56.35,72.29 U20.AH11 ; U20.AE21 51.23,73.79 U20.AE20 52.82,75.38 52.82,76.59 52.32,77.1 v2(52.32,77.13) ; R372.2 68.8,69.58 v2(68.46,69.92) ; R264.1 80.51,82.32 80.51,82.1 ; R400.2 70.3,63.18 70.55,63.43 70.55,63.51 v2(70.63,63.58) 70.71,63.66 R396.2 ; R315.1 v2(76.17,77.6) R300.1 ; v2(68.39,72.8) 67.95,72.8 R352.2 R358.2 ; R373.2 67.15,68.89 66.95,69.09 v2(66.9,69.09) 66.6,69.09 R374.2 ; U11.5 17.63,94.84 17,95.48 C109.2 ; v2(80.48,82.1) 80.51,82.1 ; 80.51,82.1 80.51,81.94 80.61,81.84 80.61,81.83 R268.1 ; v2(72.79,75.19) 72.34,75.19 R325.2 ; R326.2 12.85,75.56 11.97,76.43 v2(11.65,76.43) ; R438.2 59.82,56.72 60.91,55.63 65.3,55.63 68.98,59.31 v2(68.98,59.54) ; R425.1 65.65,60.74 65.71,60.8 v2(65.71,61.02) 65.71,61.18 65.65,61.24 R406.2 ; R205.2 69.47,88.22 v2(69.57,88.12) ; R379.2 72.61,67.8 v2(72.59,67.77) 72.14,67.77 72.14,67.75 R381.2 ; R412.1 56.24,62.31 v2(57.04,62.31) ; R363.2 66.95,71.2 v2(66.87,71.28) 66.79,71.2 R364.2 ; R426.2 64.81,61.02 v2(64.83,61.03) 64.83,61.53 R407.2
  BOTTOM w0.508: v2(81.68,91.09) 81.35,91.42 R140.1 ; C109.2 16.63,94.98 v2(17.01,94.59)
  vias: v2(72.59,77.65) v2(73.22,77.81)
+3V_DVDD: length 11.3
  TOP w0.508: v2(225.21,79) 224.91,79.3 v1(224.91,79.81) 224.91,81.51 225.98,82.58 225.98,83.93 v2(226.51,84.46)
  BOTTOM w0.203: 221.18,78.72 221.17,78.72 U18.9
  BOTTOM w0.254: 225.21,86.29 224.9,86.61 R237.2
  BOTTOM w0.508: v2(226.51,84.46) 226.51,86.06 226.28,86.29 225.21,86.29
+3V_DVDD-IO: length 8.3
  BOTTOM w0.203: 221.06,79.67 220.91,79.52 U18.7
  BOTTOM w0.508: 221.06,79.67 221.3,79.91 222.24,79.91 222.29,79.96 v4(223.08,79.96) 223.51,80.4 223.72,80.4 223.94,80.62 224.52,80.62 224.9,81.01 C236.1 224.9,81.35 225.19,81.64 L17.2 L16.2
+3V_RTC: length 270
  IN2 w0.508: 56.89,66.65 56.89,65.84 59.68,63.05 59.68,62.21 59.96,61.93 59.96,61.37 59.55,60.97 v2(59.31,60.97) 59.31,59.66 59.94,59.03 59.94,57.94 61.89,55.99 63.33,55.99 64.85,54.46 66.16,54.46 68.58,52.04 68.58,51.94 70.25,50.27 73.8,50.27 74.73,51.2 v2(74.73,60.5) v2(74.73,61.63) 74.74,61.64 74.74,63.56 75.66,64.47 75.66,69.47 76.31,70.12 76.31,71.85 86.45,82 86.45,83.9 88.89,86.34 92.42,86.34 92.63,86.14 93.65,86.14 94.91,86.14 96.84,84.21 102.58,84.21 106.09,80.7 111.96,80.7 112.69,81.44 127.33,81.44 127.6,81.17 152.01,81.17 152.55,80.62 153.8,80.62 156.89,77.54 172.12,77.54 172.92,78.34 183.13,78.34 186.28,81.49 186.28,86.19 188.38,88.3 188.38,88.84 189.18,89.64 190.46,89.64 190.67,89.85 194.96,89.85 196.04,90.92 196.29,90.92 196.5,90.92 196.89,91.32 198.28,91.32 199.04,90.56 200.14,90.56 202.67,93.08 202.87,93.08 203.28,93.5 205.73,93.5 206.98,94.75 208.32,94.75 209.52,95.94 213.02,95.94 213.78,96.7 218.33,96.7 219.55,95.48 219.55,88.88 220.95,87.48 228.03,87.48 228.54,86.97 229.23,86.97 229.99,87.74 229.99,88.98 230.62,89.62 230.62,99.45 v2(228.62,101.45) ; v2(220.21,110.72) 220.59,111.1 222.36,111.1 222.89,110.57 224.3,110.57 226.81,108.06 227.83,108.06 v2(228.21,107.68)
  BOTTOM w0.254: v2(56.76,72.55) 57.13,72.92 U20.AG10
  BOTTOM w0.508: v2(228.21,107.68) 228.5,107.38 228.5,102.53 228.62,102.42 v2(228.62,101.45) ; v2(220.21,110.72) D1.3 ; R415.2 74.58,61.47 v2(74.73,61.63) ; R423.1 74.05,60.5 v2(74.73,60.5)
+3V_RTC_0: length 35.8
  IN1 w0.508: v2(229.74,114) 229,114 227.7,115.3 226.43,115.3 225.49,114.36 221.02,114.36 v2(220.31,115.07)
  BOTTOM w0.254: R15.1 v2(220.31,115.07)
  BOTTOM w0.508: CN4.1 227.32,95.51 226.99,95.84 226.99,97.8 228.01,98.81 228.01,99.85 227.83,100.03 227.83,104.6 227.2,105.23 227.2,107.6 227.91,108.31 229.68,108.31 229.76,108.39 229.76,113.04 230.85,114.13 Q1.1 229.99,114.25 v2(229.74,114)
+3V_RTC_1: length 5.9
  BOTTOM w0.254: v2(223.39,110.6) 222.37,111.61 D1.1 221.68,111.61 221.12,112.17 221.12,114.42 221.36,114.66 R15.2
+3V_WLAN_P: length 11.9
  BOTTOM w0.254: C150.1 263.9,92.82 v2(264.15,93.07) 264.15,92.45 C157.1 ; C92.1 263,96.64 262.55,96.2 v2(262.5,96.2) ; R120.2 261.55,94.54 v2(262.09,94.54) ; R42.2 262.41,107.36 v2(262.58,107.19) R48.1
  BOTTOM w0.305: C68.1 263.02,99.53 262.63,99.93 v2(262.63,100.06)
  BOTTOM w0.508: v2(262.5,96.2) 262.42,96.2 261.97,96.65 Q13.2 ; C366.1 265.21,111.91 v2(264.15,110.85) 264.13,110.88 C11.1 ; v2(261.89,100.18) 261.87,100.18 261.56,99.88 Q12.2
  vias: v1(264.89,103.41) v2(255.69,107.32) v2(255.72,106.63) v2(256.35,107.32) v2(256.35,106.61) v2(263.95,103.71) v2(263.95,103.08)
+3VLCD_CON:
  vias: v4(8.88,94.82)
+3VPCU: length 649.1
  TOP w0.254: v2(195.5,96.02) 195.85,95.66 200.19,95.66 v2(200.3,95.56) ; v2(191.95,89.21) 192.57,89.83 192.68,89.83 192.69,89.83 193.43,89.83 193.43,89.83 193.79,89.83 193.8,89.83 194.77,89.83 196.46,91.52 198.59,91.52 199.03,91.95 200.14,91.95 v2(200.35,92.16) ; v2(79.54,86.11) 79.27,85.83 79.27,84.8 79.18,84.71 79.18,84.55 v2(78.83,84.21)
  TOP w0.508: v2(8.7,63.05) 9.49,62.26 9.49,61.11 11.33,59.27 11.33,46.17 8.68,43.52 8.68,28 v2(9.01,27.67) ; v2(220.77,88.63) 221.1,88.96 v1(222.19,88.96) v2(223.08,88.96)
  TOP w0.762: v2(12.39,81.59) 11.84,81.59 10.87,80.62 7.1,80.62 6.34,81.39 6.34,89.29 7.76,90.71 7.76,91.34 8.69,92.26
  IN1 w0.254: 231.39,86.54 233.01,84.92 v2(233.01,84.56) ; v2(215,86.72) 214.47,87.25 207.08,87.25 v2(207,87.18)
  IN1 w0.381: v2(220.31,115.96) 221.07,115.96 v2(221.91,115.12)
  IN1 w0.508: v2(215,86.72) v2(215.69,86.72) 215.97,86.72 217,87.75 219.02,87.75 219.35,88.08 220.01,88.08 220.22,88.08 v2(220.77,88.63) ; v2(222.37,112.58) v2(223.08,112.58) 225.87,112.58 v2(226.23,112.22) 226.56,111.89 245.66,111.89 246.14,112.37 250.56,112.37 251.15,111.79 251.15,111.21 251.58,110.77 252.95,110.77 254.47,112.3 v2(256.25,112.3) ; 231.39,86.54 230.13,86.54 229.01,87.66 v2(228.92,87.66) 225.62,87.66 v2(224.32,88.96) v2(223.08,88.96)
  IN1 w0.762: v2(9.39,92.54) v2(9.39,93.43) 9.39,97.45 11.22,99.28 11.22,100.36 14.37,103.51 14.37,105.32 19.75,110.7 28.87,110.7 30.75,108.82 32.96,108.82 35.73,106.05 41.98,106.05 45.79,102.24 48.53,102.24 49.88,100.89 51.27,100.89 52.37,101.99 57.8,101.99 58.62,102.8 59.3,102.8 59.81,103.31 59.81,103.84 60.35,104.38 62.86,104.38 63.11,104.63 68.38,104.63 69.24,105.49 70.55,105.49 71.62,106.56 71.62,109.83 71.75,109.96 71.75,110.6 77.08,115.93 84.45,115.93 86.4,113.98 98.47,113.98 99.18,113.26 99.18,107.42 100.45,106.15 ; v2(185.54,109.83) v2(186.43,109.83) 187.88,111.28 198.19,111.28
  IN2 w0.254: v2(197.99,82.91) 198.62,83.55 199.12,83.55 199.37,83.8 199.8,83.8 200.13,83.47 202.61,83.47 204.34,85.2 204.34,86.35 205.17,87.18 v2(207,87.18)
  IN2 w0.508: v2(8.7,63.05) 10.13,64.47 10.49,64.47 11.98,65.96 11.98,72.37 10.33,74.02 10.33,75.75 11.02,76.43 11.02,76.79 11.42,77.2 12.18,77.2 14,79.01 14,80.46 12.87,81.59 v2(12.39,81.59) ; v2(101.97,101.05) 101.97,98.84 101.29,98.15 97.16,98.15 97.02,98.29 92.08,98.29 90.06,96.27 90.06,95.43 89.37,94.75 84.6,94.75 v2(83.94,94.09) ; v2(9.01,27.67) 9.01,29.22 9.26,29.48 27.42,29.48 28.47,28.43 45.5,28.43 46.87,27.06 50.64,27.06 51.68,26.01 v2(51.68,25.25) ; v2(256.25,112.3) 255.26,111.31 255.26,109.33 v2(255.29,109.3) 254.53,108.54 254.53,106.23 256.94,103.82 257.37,103.82 258.56,102.62 258.56,97.11 258.12,96.66 v2(258.12,96.61) 258.12,91.11 259.05,90.18 259.05,88.52 v2(260.37,87.2) ; v2(196.64,105.59) 196.64,105.38 196.2,104.94 195.63,104.94 195.62,104.94 195.38,104.69 194.09,104.69 193.82,104.96 192.65,104.96 190.63,102.94 190.11,102.94 189.03,101.86 183.91,101.86 182.92,100.87 180.08,100.87 178.71,99.5 178.71,96.18 175.15,92.62 174.8,92.62 174.8,92.62 174.34,92.62 174.16,92.44 v2(172.59,92.44)
  IN2 w0.762: 101.34,104.88 101.54,104.68 101.57,104.7 101.59,104.68 113.26,104.68 114.13,105.54 117.72,105.54 118.61,106.43 120.26,106.43 121.15,105.54 v2(121.2,105.54) 123.82,108.16 127.91,108.16 129.61,109.86 132.02,109.86 132.94,108.95 141.34,108.95 142.11,109.71 142.11,110.22 142.44,110.55 146.35,110.55 147.19,109.71 150.89,109.71 153.05,107.55 v2(163.82,107.55) 165.9,107.55 168.24,105.21 172.28,105.21 174.81,107.74 178.09,107.74 180.2,109.85 185.52,109.85 v2(185.54,109.83) v2(186.43,109.83)
  BOTTOM w0.178: PU4.6 101.7,105.28
  BOTTOM w0.203: C195.1 207.88,88.34 206.93,89.29 206.7,89.29 206.3,89.69 U7.125 ; U7.22 202.65,100.56 v2(202.14,100.04) ; U7.9 202.61,95.36 202.33,95.08 202.33,94.32 202.1,94.09 201.83,94.09 ; 220.08,91.37 220.08,92.03 219.96,92.16 U7.96 ; C192.1 211.84,88.23 212.03,88.42 212.03,89.39 211.9,89.52 U7.111 ; v2(204.36,106.79) 204.94,106.79 205.1,106.64 U7.33
  BOTTOM w0.254: v2(191.95,89.21) 191.64,88.89 R220.1 ; R44.1 255.45,108.27 255.29,108.44 v2(255.29,109.3) ; v2(223.87,91.5) 223.66,91.7 R162.1 ; R125.1 223.77,93.96 v2(223.84,94.04) ; C30.1 v2(208.93,108.03) ; R482.1 79,84.21 v2(78.83,84.21) ; R178.1 R186.1 223.87,90.12 224.32,89.67 v2(224.32,88.96) ; 199.81,97.41 200.09,97.13 R479.1 200.41,96.84 200.3,96.73 v2(200.3,95.56) 200.22,95.48 200.22,94.57 ; R226.1 206.58,87.55 207,87.13 v2(207,87.18) 207.05,87.13 207.66,87.13 207.88,87.34 C195.1 ; U4.6 209.77,110.43 C23.2 v2(210.42,110.43) ; R478.2 232.28,83.83 v2(233.01,84.56) ; v2(196.64,105.59) 196.64,105.81 R50.2 ; C31.1 208.32,108.08 v2(208.27,108.03) ; 212.35,109.21 212.08,108.95 211.15,108.95 v2(210.84,109.26) 210.82,109.28 210.47,109.28 R37.1 ; 212.35,109.21 R33.1 212.64,109.63 213.12,110.11 v2(213.2,110.11) ; 212.35,109.21 212.7,108.85 R480.1 ; R107.1 v2(223.84,95.86) ; 201.83,94.09 C125.1 201.83,94.43 201.69,94.57 200.22,94.57 ; v2(228.92,87.66) 228.95,87.69 R221.1 ; C323.2 52.3,25.62 51.94,25.25 v2(51.68,25.25) ; R179.1 82.54,89.92 80.14,87.52 80.14,86.93 79.54,86.33 v2(79.54,86.11) 79.33,85.9 R485.1 ; C32.1 v2(207.56,108.03) ; v2(220.77,88.63) 221.04,88.89 C184.1 C179.1 220.72,89.82 220.57,89.97 R223.1 220.38,90.42 219.98,90.82 219.98,91.27 220.08,91.37 ; R477.1 184.17,80.27 185.46,78.97 195.95,78.97 197.99,81.01 v2(197.99,82.91) ; R24.1 202.62,111.9 202.73,111.79 202.73,110.9 v2(202.58,110.75) ; v2(221.91,115.12) 222.36,115.12 R16.1 ; CN6.40 260.25,87.32 v2(260.37,87.2) ; 200.22,94.57 200.22,93.43 200.35,93.3 v2(200.35,92.16) ; R104.1 194.99,96.61 R100.1 195,96.26 195.24,96.02 v2(195.5,96.02) ; R84.1 201.43,98.72 201.88,99.18 C65.1 201.88,99.79 v2(202.14,100.04) ; R13.1 v2(220.31,115.96) ; R27.1 204.34,110.72 203.98,111.08 v2(203.98,111.1)
  BOTTOM w0.381: PR72.2 166.75,103.3 166.03,104.02 166.03,104.83 163.82,107.04 v2(163.82,107.55) ; L1.2 225.54,112.91 v2(226.23,112.22) ; D3.1 212.34,111.21 212.13,111 v2(212.13,110.44) ; v2(221.91,115.12) 221.91,113.98 D1.2 ; v2(199.28,99.22) 199.28,97.95 199.81,97.41
  BOTTOM w0.508: v2(83.94,94.09) 83.94,91.42 83.28,90.76 83.28,90.25 83.08,90.05 R179.1 ; 100.88,104.58 100.88,101.88 101.19,101.58 101.62,101.58 101.97,101.22 v2(101.97,101.05) ; v2(223.08,112.58) 223.08,112.81 D1.2 ; v2(258.12,96.61) C87.1 258.12,98.5 C69.1 ; CN13.13 50.6,24.96 50.82,25.18 51.6,25.18 v2(51.68,25.25) ; v2(121.2,105.54) 121.2,104.44 R61.2 ; v2(172.59,92.44) 172.59,92.19 171.53,91.13 171.31,91.13 169.28,89.11 PR119.1
  vias: v2(100.53,105.49) v2(101.16,105.49) v2(199.23,111.16) v2(199.86,111.16) v2(223.74,98.91) v2(224.4,98.91)
+3VPCU_EC: length 13.6
  BOTTOM w0.203: U7.67 220.26,103.76
  BOTTOM w0.254: L1.1 C12.1 223.96,111.57 C18.1 223.96,109.83 223.46,109.33 v2(222.5,109.33) 223.96,107.87 223.96,107.45 220.26,103.76
+3VS5: length 232.3
  TOP w0.076: 54.59,73.26 54.7,73.14 54.7,71.66 54.68,71.63 ; 57.27,72.56 57.27,72.62 56.99,72.9 56.99,73
  TOP w0.102: 55.52,71.58 55.52,72.22
  TOP w0.305: CN2.7 74.45,53.98 74.23,53.75 74.23,53.68 73.73,53.18 72.46,53.18 72.42,53.22 71.82,53.22 71.37,52.76 v2(71.37,52.53)
  TOP w0.508: 56.89,71.2 56.89,67.44 56.58,67.14 56.58,65.36 57.14,64.8 57.14,64.22 v2(56.71,63.78)
  IN1 w0.508: v2(72.66,60.1) 71.87,59.31 71.87,55.61 72.13,55.35 73.83,55.35 74.67,54.51 74.67,53.95 v2(72.84,52.13) 72.66,51.95 71.95,51.95 v2(71.37,52.53)
  IN2 w0.381: v2(235.37,94.75) 235.73,94.75 236.06,94.42 236.06,90.63 236.52,90.18 237.18,90.18 237.47,90.47 v2(237.47,90.82)
  IN2 w0.508: v2(66.32,59.48) 66.3,59.46 v2(66.3,58.83) 66.3,58.82 ; v2(66.32,59.48) 66.95,59.48 v2(66.96,59.47) ; v2(66.32,59.48) 66.32,60.29 66.36,60.33 66.36,61.63 65.78,62.21 65.78,63.63 66.08,63.94 v2(66.1,63.94) ; v2(56.71,63.78) 55.82,62.9 55.82,60.43 54.75,59.37 47.51,59.37 v2(46.86,58.71) ; 97.53,92.56 v2(97.53,90.23)
  IN2 w1.016: 126.2,88.5 126.33,88.63 129.76,88.63 131.79,86.59 142.78,86.59 143.05,86.33 154.18,86.33 157.38,83.13 164.3,83.13 165.47,81.96 170.39,81.96 171.18,82.75 173.96,82.75 174.75,82.75 182.32,90.32 182.96,90.32 187.74,95.1 191.02,95.1 191.29,95.37 192.78,95.37 192.78,95.37 193.59,95.37 195.53,97.31 198.82,97.31 199.22,97.71 199.28,97.71 199.28,97.72 200.22,97.72 200.32,97.82 200.35,97.82 201.09,98.56 205.73,98.56 206.85,99.67 208.22,99.67 208.86,99.04 213.02,99.04 213.61,98.46 219.78,98.46 221.15,99.83 225.52,99.83 ; 92.91,92.84 92.73,92.66 91.99,92.66 90.24,90.91 87.91,90.91 86.69,90.91 85.12,89.34 84.49,89.34 82.05,86.89 82.05,85.85 81.87,85.68 81.87,85.67 79.9,83.7 79.9,83.09 79.04,82.23 76.22,82.23 75.68,81.69
  BOTTOM w0.254: R360.2 70.54,72.17 v2(71.49,72.17) ; v2(97.53,90.23) 97.53,89.63 97.76,89.4 C182.1 98.16,89.03 98.19,89.01 U15.5 ; v2(73.78,70.44) 73.42,70.08 R368.2 ; R122.1 R133.1 R149.1 R165.1 v2(237.47,90.82) ; R137.1 227.78,93.15 v2(227.68,93.05) ; C5.2 47.1,58.94 46.86,58.71 v2(46.86,58.71) ; v2(66.1,63.94) 66.03,64 R389.2 ; U12.1 230.19,90.86 229.3,89.97 v2(229.3,89.9) 229.05,89.64 C180.2 228.71,89.42 228.49,89.21 228.02,89.21 227.89,89.08 227.47,89.08 227.34,89.21 226.85,89.21 226.6,89.46 R192.1 ; R405.2 70.05,61.78 v2(70.1,61.73) 70.2,61.83 70.25,61.83 70.4,61.98 R402.2 ; C287.1 54.98,62.59 56.18,63.78 v2(56.71,63.78) ; R445.2 76.33,55.61 v2(72.84,52.13) ; R385.2 72.29,65.51 72.41,65.51 v2(72.46,65.46) ; C34.1 258.45,108.75 v2(258.11,109.1) ; U12.13 234.33,94.11 234.97,94.75 v2(235.37,94.75) C118.2 ; R147.1 226.48,92.41 v2(226.08,92) 226.53,91.55 R163.1 ; R428.2 66.13,59 v2(66.3,58.83) ; U20.AH10 56.84,71.91 v2(56.74,71.91) ; v2(226.6,94.37) R130.1
  BOTTOM w0.508: v2(105.02,95.1) 105.28,95.36 105.28,98.4 104.39,99.29 104.39,100.8 PR84.1
  BOTTOM w1.524: 128.57,99.04 128.57,101.83
  vias: v1(257.68,107.29) v2(75.18,80.55) v2(75.51,81.11) v2(125.14,88.07) v2(125.72,87.81) v2(126.31,88.07) v2(228.52,98.18) v2(228.92,97.64) v2(229.3,98.18) v2(257.24,105.36) v2(257.27,104.65) v5(93.41,95.81) v5(94.15,95.81) v5(94.89,95.81) v5(126.66,95.66) v5(127.4,95.66) v5(128.14,95.66)
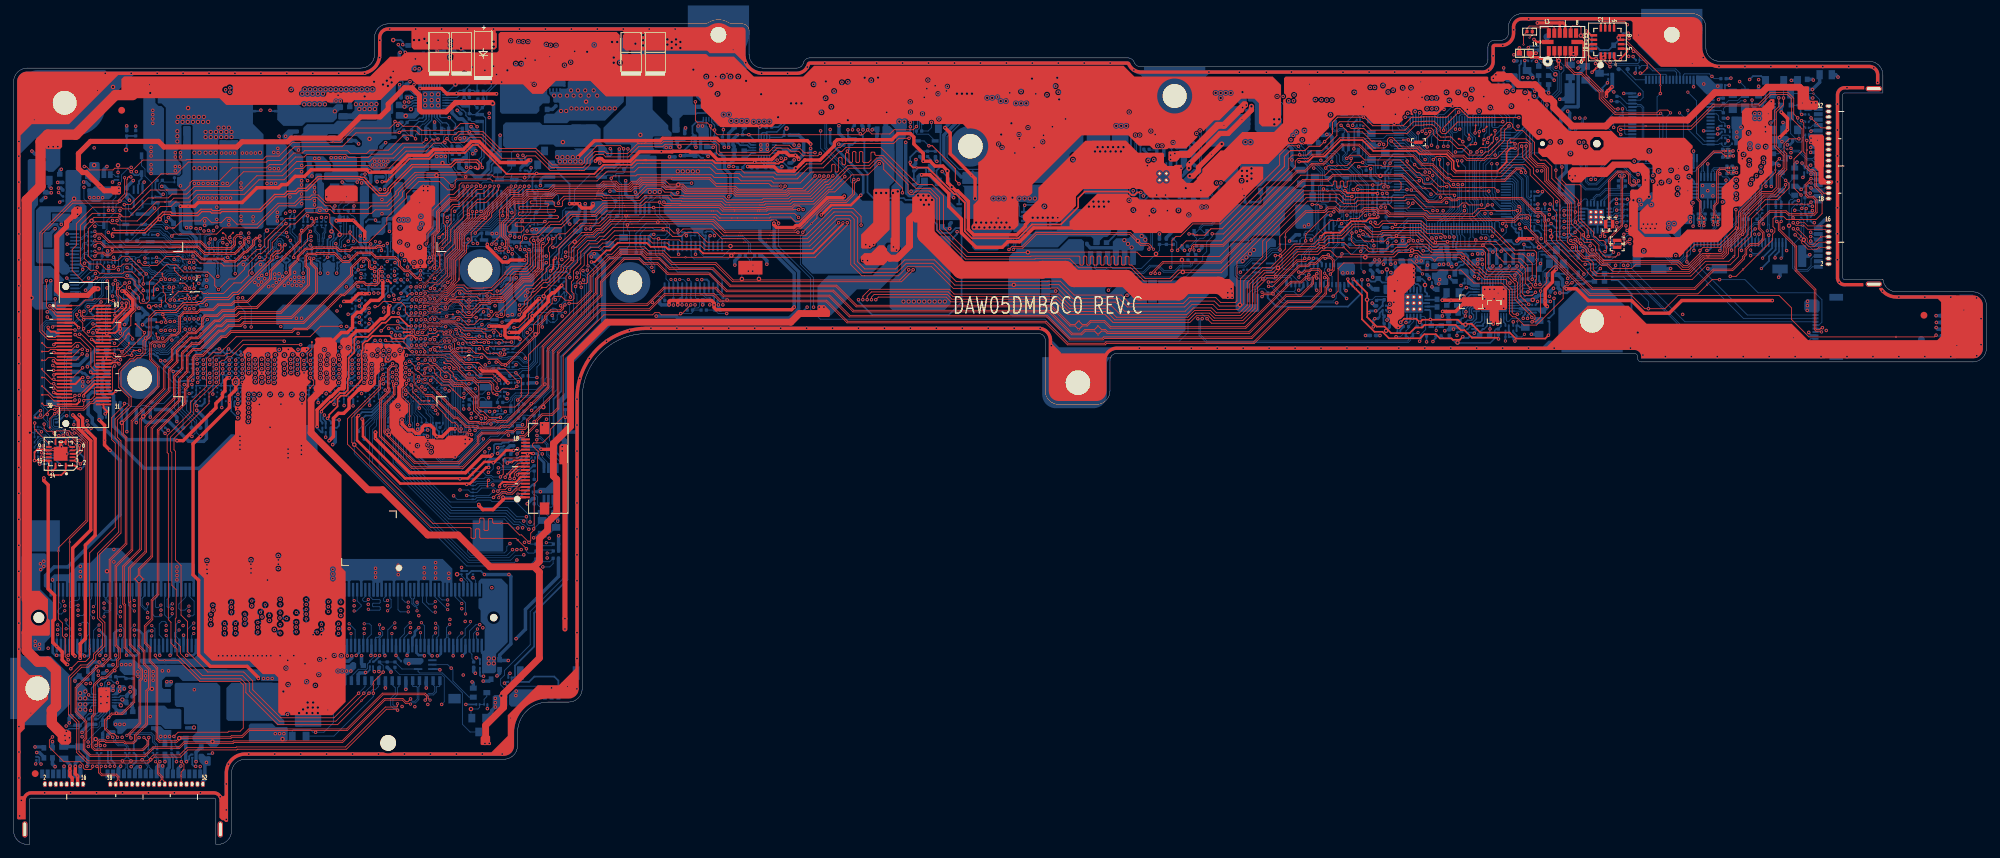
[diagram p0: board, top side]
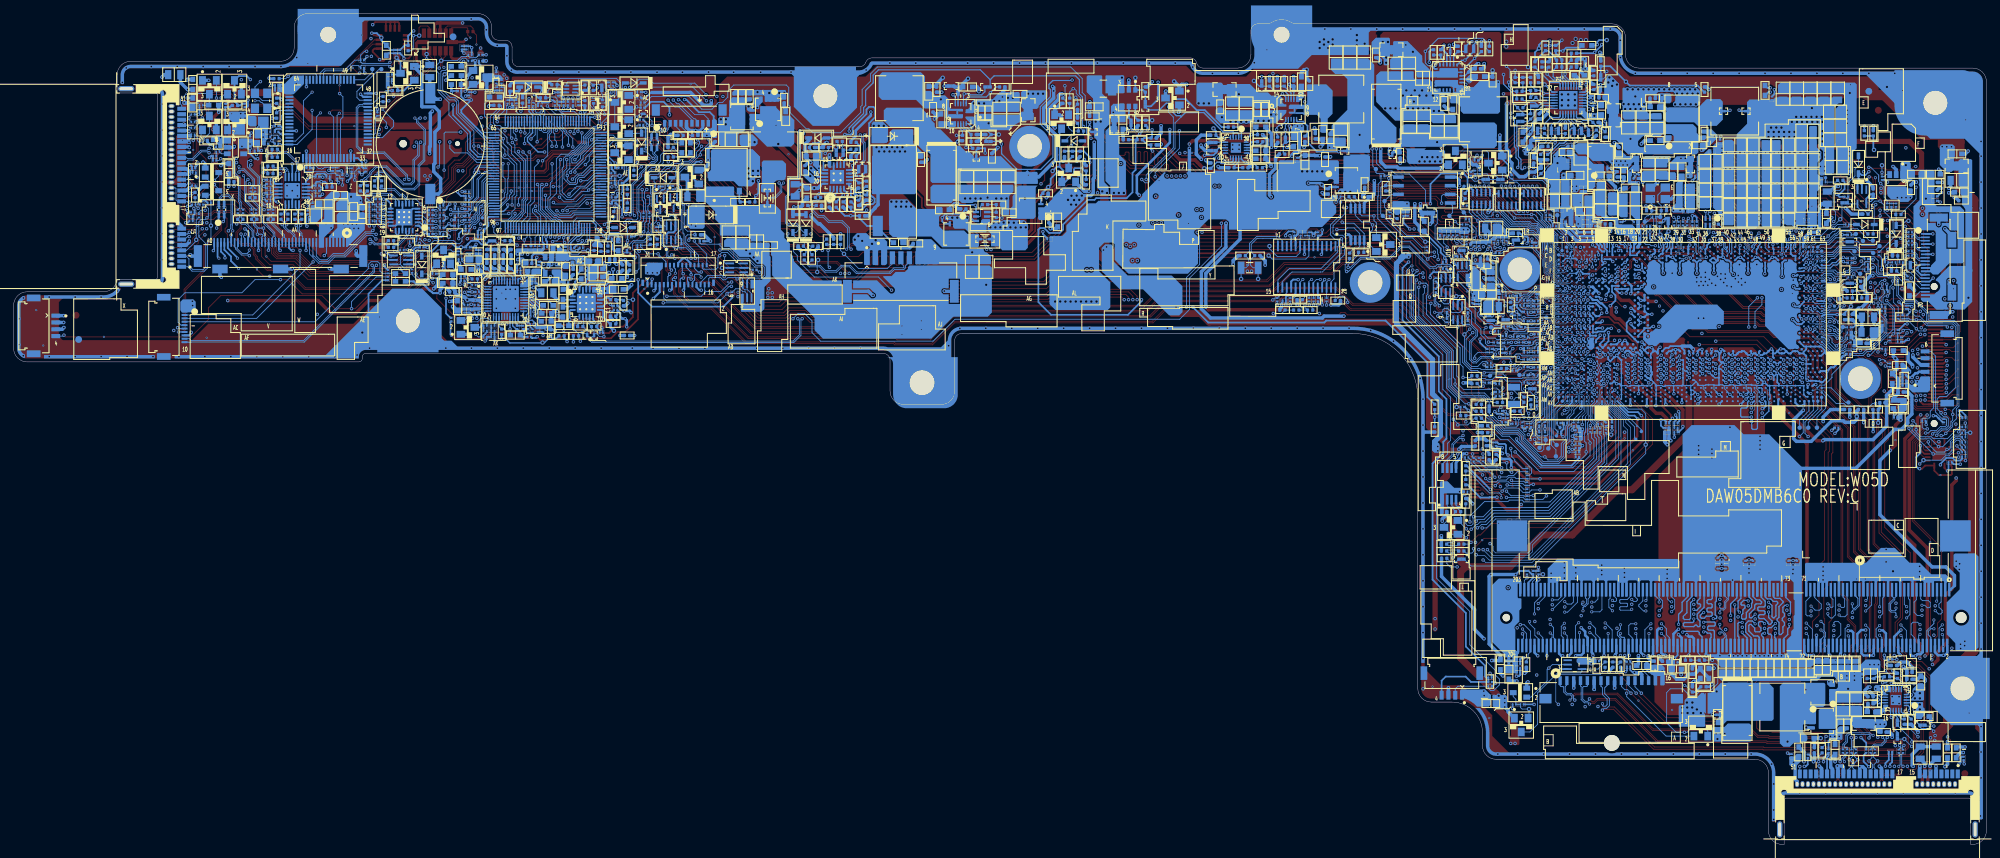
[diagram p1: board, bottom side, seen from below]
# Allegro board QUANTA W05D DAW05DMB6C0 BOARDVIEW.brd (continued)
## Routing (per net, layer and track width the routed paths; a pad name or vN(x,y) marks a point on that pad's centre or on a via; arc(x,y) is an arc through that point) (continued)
+3VSPI: length 18.8
  TOP w0.508: v2(81.64,94.09) v1(82.31,94.09) v2(83.1,94.09) 83.1,93.83 83.48,93.45 84.73,93.45 85.08,93.81 v2(85.08,94.09)
  BOTTOM w0.254: v2(81.64,94.09) 81.64,96.97 80.08,98.53 v2(76.8,98.53) 76.19,97.92 76.19,96.04 76.55,95.69 R112.2
  BOTTOM w0.508: R179.2 82.82,91.8 R140.2 83.1,92.99 v2(83.1,94.09)
+5V: length 322.6
  TOP w0.508: v2(259.58,107.52) 260.49,106.61 v1(260.49,104.96) v2(259.33,103.79)
  TOP w0.762: v2(80.96,31.63) v2(80.96,33.15) 80.96,56.3
  TOP w1.016: 128.01,86.72 128.64,86.09 129.76,86.09 131.56,87.89 131.56,91.8 132.2,92.44
  TOP w2.54: 133.98,92.05 133.98,89.51 139.13,84.36 151.05,84.36 151.11,84.42 154.44,84.42 155.76,83.1 163.38,83.1 165.33,81.15 171.05,81.15 172,82.1 176.95,82.1 177.03,82.02
  IN1 w0.508: v2(73.75,21.85) 73.75,21.26 69.85,17.35 53.38,17.35 51.5,15.47 33.14,15.47 30.45,12.78 27.91,12.78 27.63,13.06 20.49,13.06 19.8,12.38 11.57,12.38 10.76,11.56 v2(10.76,11.46)
  IN2 w0.381: 93.29,88.63 93.54,88.63 93.82,88.35 96.18,88.35 96.18,88.76 94.73,90.2 93.18,90.2 92.45,89.46 92.45,88.63
  IN2 w0.508: v2(88.94,102.11) 88.94,101.73 89.2,101.48 90.82,101.48 92.75,103.41 106.75,103.41 108.73,101.43 110.96,101.43 112.23,102.7 v2(114.62,102.7) 114.62,103.06 115.3,103.74 121.33,103.74 122.09,102.98 130.88,102.98 v2(131.01,103.1)
  IN2 w0.762: v2(85.26,86.75) 85.91,86.75 87.79,88.63 93.29,88.63 ; 124.4,85.76 111.6,85.76 109.92,87.43 97.02,87.43 96.45,88 96.45,88.08 96.18,88.35 ; 74.64,22.48 75.43,22.48 80.96,28.01 v2(80.96,31.63) v2(80.96,33.15)
  BOTTOM w0.508: v2(114.62,102.7) 114.24,103.08 PR73.1 ; v2(88.94,102.11) 88.94,100.23 88.2,99.48 86.54,99.48 86.35,99.29 80,99.29 79.49,99.8 Q10.2 ; R476.2 R475.2 10.89,13.19 10.89,11.59 v2(10.76,11.46) ; v5(132.83,95.28) 131.51,95.28 131.16,95.64 131.16,97.72 131.01,97.87 v2(131.01,103.1) ; R41.1 v2(259.58,107.52)
  BOTTOM w0.762: 85.88,86.05 86.63,85.3 86.63,76.51 81.32,71.2 81.32,66.15 80.18,65 80.18,60 81.02,59.16 81.02,58.91
  vias: v2(73.8,22.51) v2(80.56,58.43) v2(80.56,57.79) v2(84.83,86.26) v2(124.68,85.73) v2(125.39,85.73) v2(178.3,81.01) v2(178.3,80.32) v2(178.81,81.59) v2(178.94,80.96) v2(178.94,80.32) v2(205.99,86.29) v2(206.06,85.65) v2(206.7,85.68) v2(215,85.88) v2(215,85.25) v2(215.64,85.88) v2(222.45,86.59) v2(223.08,86.59) v2(243.07,91.17) v2(243.07,90.53) v2(243.83,91.17) v2(259.68,103.21) v5(133.22,94.65) v5(133.6,95.28) v5(133.67,93.93) v5(133.98,94.62) v5(134.36,95.26) v5(134.41,93.96) v5(134.87,94.65)
+5V_AMP: length 10.5
  IN2 w0.381: v2(203.33,75.93) 204.23,75.93 206.37,73.79 v2(207.49,73.79)
  BOTTOM w0.254: R330.1 203.22,75.2 203.22,75.81 v2(203.33,75.93) ; v2(205.61,83.29) 205.61,82.59 205.92,82.28 206.21,82.28 206.61,81.89 U19.20 ; v2(202.68,79.61) 202.68,79.48 203.18,78.98 U19.12 ; R335.2 v2(207.49,73.79)
  vias: v1(203.24,82.78) v2(205.61,84.56) v2(205.61,83.93)
+5V_PVDD: length 5.3
  BOTTOM w0.203: v2(220.46,83.6) 220.34,83.72 218.84,83.72 218.42,83.3 U18.38 ; U18.31 215.62,82.96 215.49,83.09 v2(215.1,83.09) 215.1,83.55 215.27,83.71 C222.1 C216.1
  vias: v2(221.48,84.82)
+5VALW: length 21.2
  IN2 w0.508: v2(117.47,111.61) 116.96,111.1 102.86,111.1 v2(102.35,111.61)
  BOTTOM w0.178: PU4.11 101.7,110.65
  BOTTOM w0.508: 118.51,111.28 118.18,111.61 v2(117.47,111.61) ; 118.51,111.28 PD2.1 ; 118.51,111.28 v4(119.27,112.04) ; v2(102.35,111.61) 102.09,111.35 PC24.2 101.7,111.33 101.7,110.65
+5VPCU: length 428.5
  TOP w0.508: v2(233.9,109.89) 233.9,110.42 v1(234.17,110.69) v2(234.71,111.23)
  IN1 w0.762: 56.63,103.03 55.77,103.89 52.87,103.89 50.94,101.96 50.39,101.96 49.19,103.15 46.13,103.15 42.32,106.96 36.09,106.96 33.34,109.71 31.13,109.71 29.25,111.59 19.38,111.59 13.48,105.69 13.48,103.94 v2(11.83,102.29) ; 58.62,104.32 59.58,105.29 62.2,105.29 62.43,105.52 65.91,105.52 66.82,106.43 69.16,106.43
  IN2 w0.508: v2(11.83,102.29) 8.7,102.29 1.41,95 1.41,28.73 3.38,26.76 4.07,26.76 6.72,24.11 6.72,19.18 4.04,16.5 4.04,13.81 5.73,12.12 6.32,12.12 6.72,11.71 6.72,11.11 7,10.83 16.15,10.83 16.43,11.11 16.43,11.71 16.83,12.12 18.84,12.12 19.3,11.66 19.3,11.18 19.6,10.88 25.11,10.88 26.03,11.79 26.03,12.3 26.51,12.78 29.82,12.78 32.09,15.04 49.49,15.04 52.47,18.03 62.08,18.03 64.61,20.55 v2(66.41,20.55) ; 218.28,111.87 222.49,111.87 223.15,111.21 225.59,111.21 226.61,110.19 228.01,110.19 229.35,108.84 232.86,108.84 v2(233.9,109.89)
  IN2 w0.762: 218.28,111.87 218,111.59 215.64,111.59 214.9,112.32 176.49,112.32 174.82,110.65 174.82,110.05 171.61,106.84 169.11,106.84 164.58,111.36 v2(153.03,111.36) 151.3,113.09 136.34,113.09 134.71,111.46 133.93,111.46 133.19,112.2 128.57,112.2 126.99,110.62 v2(120.49,110.62) 119.75,111.36 118.36,111.36 116.91,109.91 104.56,109.91 104.11,109.45 103.18,109.45 102.01,108.29 99.76,108.29 99.33,108.72 99.33,112.35 96.61,115.07 90.26,115.07 88.82,116.52 84.75,116.52 84.07,117.2 80.76,117.2 79.88,116.31 72.46,116.31 68.57,112.43 68.57,107.93 69.21,107.29
  BOTTOM w0.254: v2(66.41,20.55) R471.1
  BOTTOM w0.508: v2(153.03,111.36) PR25.2 ; PD2.3 120.54,110.57 v2(120.49,110.62)
  vias: v2(69.84,107.37) v2(69.84,106.74)
+5VS5: length 321.3
  TOP w0.508: v2(59.68,111) 62.83,111 63.62,110.22 v2(70.91,110.22) ; v5(141.19,94.85) 141.19,97.77 v1(140.68,98.28) 137.53,101.42 137.53,104.48 v2(136.77,105.24) ; v2(121.99,95.18) 121.77,94.96 119.5,94.96 116.11,91.57 116.11,91.56 115.55,91 115.54,91 115.38,90.85 114.84,90.85 114.58,90.58 112.07,90.58 111.65,91 v2(111.65,91.22)
  IN1 w0.508: v2(66.03,24.87) 61.84,24.87 61.46,25.25 55.47,25.25 v2(55.41,25.3)
  IN2 w0.508: v2(121.99,95.18) 123.06,94.11 131.29,94.11 132.42,92.98 132.93,92.47 136.97,92.47 137.01,92.51 138.62,92.51 138.66,92.55 138.66,92.55 140.91,94.8 141.14,94.8 v5(141.19,94.85) ; v2(17.11,22.41) 17.31,22.2 23.74,22.2 25.01,23.47 26.79,23.47 27.68,22.59 49.65,22.59 50.18,23.12 53.23,23.12 v2(55.41,25.3) ; v2(66.03,24.87) 67.37,26.21 68,26.21 68.83,27.03 68.83,27.34 71.45,29.97 71.88,29.97 74.29,32.37 74.29,36.17 80.69,42.58 80.69,46.84 81.32,47.48 81.32,70.34 88.18,77.2 93.97,77.2 v2(94.35,77.58) ; v2(67.18,105.42) 67.18,105.36 67.78,104.75 69.46,104.75 71.04,106.33 71.04,109.15 70.91,109.28 v2(70.91,110.22) 70.91,112.55 72.38,114.03 74.16,114.03 74.57,114.43 v2(74.57,114.64) 74.77,114.43 v2(80.89,114.43) 80.89,115.1 81.44,115.65 83.08,115.65 85.46,113.26 96.18,113.26 97.76,111.69 97.76,108.03 99.64,106.15 102.83,106.15 103.54,105.44 112.95,105.44 113.81,106.3 117.14,106.3 118.33,107.5 v2(118.64,107.5) 121.66,107.5 123.14,108.97 127.5,108.97 129.2,110.67 132.38,110.67 133.22,109.83 135.35,109.83 v2(135.74,110.23)
  BOTTOM w0.178: PU8.12 15.47,21.6 15.69,21.82 16.49,21.82 PC142.1 ; PU3.15 60.19,112.05 60.52,112.37 PC18.2
  BOTTOM w0.203: v2(80.89,114.43) 80.89,114.41 81.15,114.15 81.15,114.03 81,113.88 PU1.7 ; PU1.21 76.58,112.88 76.07,113.39
  BOTTOM w0.508: v2(17.11,22.41) 16.62,21.92 PC142.1 ; v2(111.65,91.22) 111.68,91.19 111.68,87.7 115.28,84.09 115.28,78.66 113.93,77.31 97.52,77.31 97.25,77.58 v2(94.35,77.58) ; PC18.2 60.37,112.96 59.68,112.27 v2(59.68,111) ; v2(135.74,110.23) 136,110.23 136.26,109.96 136.26,109.43 137.79,107.9 137.79,106.27 136.77,105.25 v2(136.77,105.24) ; v2(74.57,114.64) 74.74,114.64 75.06,114.32 PC17.2 75.56,113.9 76.07,113.39 ; PR66.2 67.94,104.73 67.79,104.73 67.18,105.34 v2(67.18,105.42) ; R464.1 55.41,25.45 v2(55.41,25.3) ; PD2.2 118.51,107.63 v2(118.64,107.5)
+5VS5_S: length 34.5
  IN2 w0.508: v2(137.13,111.31) 137.4,111.59 150.56,111.59 151.76,110.39 v2(151.76,110.09)
  BOTTOM w0.178: PU5.7 151.41,109.75 v2(151.76,110.09)
  BOTTOM w0.508: v2(137.13,111.31) 136.97,111.16 v2(136.97,110.65) 136.97,109.62 138.45,108.14 138.45,106 136.61,104.16 136.61,100.58 139.16,98.02 PJP3.1
+12VALW: length 5.8
  BOTTOM w0.203: PC101.1 112.99,100.18 112.54,100.18 112.36,100.01 111.9,100.01 111.78,99.88 110.65,99.88 110.2,100.33 PU6.13
  BOTTOM w0.305: v4(114.85,99.29) PC101.1
+V1.05A_AOSCSUS: length 25.9
  TOP w0.254: v2(45.2,63.53) 45.2,63.71 46.47,64.98 46.63,64.98 47.92,66.27 48.63,66.27 49.07,66.71 49.07,68.36 49.2,68.49 49.2,71.38 50.03,72.22 50.03,74.27 50.28,74.53 52.02,74.53 54.1,76.61 54.62,76.61 55.47,77.45 56.63,77.45 TP34.1 57.95,76.14 v2(58.4,76.14)
  BOTTOM w0.254: U20.AB8 58.23,75.96 v2(58.4,76.14) ; C286.2 45.35,61.94 45.08,62.21 45.08,63.4 v2(45.2,63.53)
+V1.05A_SUS_PCH: length 2.7
  TOP w0.254: v2(58.47,75.22) 57.33,75.22 TP35.1
  BOTTOM w0.254: v2(58.47,75.22) 58.23,74.98 U20.AD8 U20.AD10
+V1.05A_USB2SUS: length 1.3
  TOP w0.127: TP49.1 55.15,71.39 55.15,71.88 v2(55.12,71.9)
  BOTTOM w0.127: U20.AH13 55.2,71.9 v2(55.12,71.9)
+V1.05A_VCCUSB3SUS: length 1.4
  TOP w0.254: TP18.1 55.01,82.81 v2(54.88,82.81)
  BOTTOM w0.254: U20.J13 55.14,82.81 v2(54.88,82.81)
+V1.05S_APLLOPI: length 22.5
  IN1 w0.508: v2(47.49,78.34) 48,77.83 48.05,77.83 48.66,77.22 49.73,77.22 50.33,76.62 v2(50.77,76.62)
  IN2 w0.508: v2(44.98,93.12) 45.79,93.12 46.7,92.21 46.7,90.45 45.36,89.11 45.36,88.32 45.84,87.84 45.84,87.74 46.73,86.85 46.73,85.45 46.78,85.4 46.78,83.19 46.96,83.01 46.96,79.49 47.36,79.08 47.36,78.47 v2(47.49,78.34)
  BOTTOM w0.305: U20.W21 51.13,76.98 v2(50.77,76.62) 51.13,76.26 U20.AA21
  vias: v2(45.97,93.12)
+V1.05S_ASATA3PLL: length 8.5
  BOTTOM w0.254: U20.B11 56.12,87.07 56.44,87.07 56.89,87.52 56.89,87.85 57.24,88.2 57.24,88.34 57.58,88.68 57.78,88.68
  BOTTOM w0.508: 57.78,88.68 60.19,88.68 61.41,89.9 61.61,89.9 62.37,90.66 62.37,91.14
  vias: v4(62.1,98.25)
+V1.05S_AUSB3PLL: length 7.5
  TOP w0.508: v2(51.55,88.96) 51.55,89.97 v1(49.88,91.65) 47.46,91.65 v2(47.39,91.57)
  BOTTOM w0.254: R174.2 47.96,91.32 47.59,91.32 47.36,91.55 v2(47.39,91.57)
  BOTTOM w0.381: R164.1 47.07,91.94 47.39,91.62 v2(47.39,91.57)
+V1.05S_AXCK_DCB: length 25.4
  TOP w0.508: v2(48.51,79.74) 49.52,79.74 50.67,80.89 v1(51.38,80.89) v2(52.24,80.89)
  IN2 w0.508: v2(50.46,97.26) 50.46,96.83 50.64,96.65 50.64,91.75 47.97,89.08 47.97,87.48 48,87.46 48,85.98 48.05,85.93 48.05,85.28 48.76,84.57 48.76,83.26 48.23,82.72 48.23,80.02 v2(48.51,79.74)
  BOTTOM w0.305: v2(52.24,80.89) 52.12,81.01 U20.K19 52.59,82.49 U20.J18
+V1.05S_AXCK_LCPLL:
  vias: v2(50.92,89.36)
+V1.05S_SSCF100: length 21.5
  IN1 w0.508: v2(53.03,82.82) 52.28,82.82 52.01,82.56 49.55,82.56 v2(48.86,81.87)
  IN2 w0.508: v2(51.1,97.13) 51.27,96.96 51.27,91.34 50.51,90.58 50.51,88.22 49.9,87.61 49.9,86.09 49.4,85.58 49.4,82.92 48.86,82.38 v2(48.86,81.87)
  BOTTOM w0.305: U20.J17 53.35,82.49 v2(53.03,82.82)
  vias: v2(52.32,98.91)
+V1.05S_SSCFF: length 27
  IN1 w0.508: v3(48,79.06) v2(50.77,79.06)
  IN2 w0.508: v2(43.81,98.15) 44.57,98.15 44.95,97.77 44.95,94.88 47.27,92.56 47.62,92.56 48.13,92.05 48.13,90.89 47.11,89.87 47.11,88.91 46.68,88.48 46.68,87.8 47.36,87.11 47.36,85.72 47.41,85.66 47.41,85.02 48.13,84.31 48.13,83.52 47.59,82.99 47.59,79.75 48,79.35 v3(48,79.06)
  BOTTOM w0.305: U20.R21 51.13,79.42 v2(50.77,79.06) 51.13,78.7 U20.T21
+V1.05S_VCCST: length 362.4
  TOP w0.762: 14.98,95.99 13.33,95.99 v1(12.68,96.64) 10.66,98.66 10.15,98.66 9.52,99.29 9.52,101.45 11.3,103.23 21.28,103.23 22.09,102.42 32.78,102.42 33.55,103.18 40.25,103.18 40.78,103.71 47.79,103.71 50.92,106.84 53.83,106.84 55.01,108.02 55.01,108.72 57.4,111.1 58.49,111.1 59.61,109.99 59.61,107.88 59.91,107.57 63.52,107.57 64.89,108.95 70.22,108.95 v5(70.35,108.82)
  IN1 w0.508: v2(21.96,95.48) 21.07,96.37 15.49,96.37 v2(15.46,96.35) ; v2(61.82,106.08) 62.78,107.04 65.68,107.04 67.45,108.82 v5(70.35,108.82)
  IN1 w0.762: 16.43,91.62 17.24,91.62 20.11,88.75 22.37,88.75 23.98,87.14 26.66,87.14 27.44,86.36 27.44,85.51 29.2,83.75 29.2,80.55 32.48,77.27 v2(41.52,77.27) v2(42.28,77.27)
  IN2 w0.178: 179.42,110.66 179.15,110.66 178.93,110.88 176.07,110.88 175.66,110.47 175.66,108.59 175.7,108.55
  IN2 w0.432: 175.7,108.55 177.88,108.55 179.42,110.09 179.42,110.66
  IN2 w0.508: v2(6.75,55.73) 7.36,56.34 7.36,58.02 7.74,58.4 7.74,59.24 8.27,59.77 9.17,59.77 9.87,60.47 9.87,62.36 10.53,63.02 10.84,63.02 13.25,65.43 13.25,76.15 15.85,78.75 v2(18.39,78.75)
  IN2 w0.61: v5(70.35,108.82) 70.12,109.05 70.12,112.81 72.74,115.42 80.24,115.42 81.16,116.34 83.41,116.34 85.74,114 96.46,114 98.49,111.97 98.49,108.36 100.02,106.84 102.61,106.84 103.75,107.98 111.47,107.98 112.46,106.99 116.81,106.99 117.34,107.52 117.34,109.07 118.61,110.34 119.5,110.34 120.13,109.71 127.25,109.71 128.92,111.38 132.71,111.38 133.47,110.62 135.15,110.62 136.8,112.27 150.95,112.27 152.44,110.78 152.44,109.99 154.02,108.41 166.38,108.41 168.77,106.02 171.94,106.02 174.47,108.55 175.7,108.55 ; v2(187.25,109.2) 187.25,110.17 186.75,110.66 179.42,110.66
  BOTTOM w0.254: 195.95,110.42 196.11,110.42 196.97,109.56 197.47,109.56 R32.2 ; R253.1 R258.1 16.93,84.43 v2(16.65,84.71) ; v2(6.75,55.73) 6.75,55.89 5.88,56.75 4.95,56.75 4.56,56.37 3.83,56.37 3.56,56.64 R437.1 ; R96.2 20.82,97.27 20.82,96.25 21.58,95.48 v2(21.96,95.48) 21.58,95.1 R114.2 ; R244.1 16.76,85.96 v2(16.63,85.83)
  BOTTOM w0.508: v5(70.35,108.82) 70.48,108.69 70.48,102.14 70.07,101.74 70.07,100.44 69.68,100.05 69.68,99.13 68.6,98.05 67.81,98.05 67.75,98.11 67.69,98.11 67.25,98.56 67.07,98.74 66.29,98.74 65.72,99.3 PR97.1 65.4,99.93 65.45,99.98 PR89.1 ; R328.2 18.34,76 18.29,76.05 C259.1 18.92,77.45 19.31,77.84 C258.1 18.76,78.75 v2(18.39,78.75) 17.51,79.64 R277.1 17.51,80.96 R266.2 18.16,81.91 17.77,82.3 17.77,82.78 17.01,83.55 16.71,83.55 v2(16.68,83.52) ; PR89.1 65.84,100.56 66.11,100.83 PC100.2 66.46,101.43 65.4,102.49 PR75.1 ; PR89.1 PR90.1 ; v2(61.82,106.08) 61.82,105.2 R55.1 ; 195.95,110.42 190.29,110.42 188.41,108.54 187.44,108.54 187.25,108.74 v2(187.25,109.2)
  vias: v2(14.52,91.62) v2(15.18,91.6) v2(15.49,95.71)
+V3.3DX_1.5DX_ADO: length 37.3
  TOP w0.508: v2(53.13,60.53) 53.15,60.51 53.15,60.48 53.13,60.46 v1(53.13,59.62) 58.17,54.58 66.35,54.58 68.78,57 70.07,57 v2(70.25,57.18)
  IN2 w0.127: 54.68,71.07 54.7,71.1 54.7,72.17 v2(54.32,72.55)
  IN2 w0.229: v2(54.32,72.55) 53.81,72.03 53.81,70.99 53.81,70.99
  IN2 w0.508: 54.55,65.54 54.55,63.56 53.21,62.21 53.21,60.61 v2(53.13,60.53)
  BOTTOM w0.254: v2(70.25,57.18) 70.55,57.49 70.55,58.63 70.73,58.81 71.59,58.81 71.81,59.02 C294.1 72.67,59.02 72.95,59.3 73.4,59.3 ; U20.AH14 54.41,72.55 v2(54.32,72.55)
  BOTTOM w0.508: R431.1 74.8,59.54 73.64,59.54 R430.1 73.4,59.3
+V3.3M_PSPI: length 24
  IN2 w0.254: v3(67.48,88.24) 66.03,88.24 64.64,86.85 64.64,82.54 66.01,81.17 66.01,80.73 64.51,79.23 64.51,78.34 64.25,78.08 63.24,78.08 62.98,77.83 61.13,77.83 60.85,77.55 58.89,77.55 58.43,77.09 v2(58.41,77.09)
  BOTTOM w0.254: v2(58.41,77.09) 58.23,76.9 U20.Y8 ; v3(67.48,88.24) 67.32,88.41 C186.1 67.32,89.12 67.45,89.26 68,89.26 68.29,89.56 68.29,89.57 68.5,89.77 R187.1 68.74,88.8 R205.1
+VCC_CORE: length 21.6
  IN1 w0.508: 23.11,100.06 21.2,100.06 20.82,100.44 18.92,100.44 18.03,99.55 v2(18.03,98.79)
  IN2 w0.508: v2(18.03,98.79) 18.03,98.28 18.2,98.1 18.2,86.92 19.02,86.11 v2(19.27,86.11)
  BOTTOM w0.203: U20.F59 26.87,84.16 27.93,84.16 U20.G57
  BOTTOM w0.254: v2(19.27,86.11) 19.45,86.11 19.5,86.06 R243.2
  vias: v2(23.74,101.58) v2(23.74,100.94) v2(23.74,99.55) v2(23.74,98.91) v2(24.38,99.55) v2(26.54,97.07) v2(27.17,97.07) v2(27.25,94.91) v2(27.83,97.07) v2(27.88,94.91) v2(28.06,91.55) v2(28.06,90.91) v2(28.36,82.86) v2(28.54,97.07) v2(28.52,94.91) v2(29.18,97.07) v2(29.15,94.91) v2(29.81,97.07) v2(29.79,94.91) v2(29.84,93.58) v2(29.84,91.78) v2(33.39,97.13) v2(33.39,96.5) v2(33.39,92.23) v2(33.39,91.6) v2(33.6,101.53) v2(33.72,85.16) v2(34.23,101.53) v2(34.87,101.53) v2(35.17,92.16) v2(35.17,91.52) v2(35.43,82.53) v2(35.5,101.53) v2(35.93,82.15) v2(35.98,83.09) v2(36.26,85.15) v2(36.44,83.55) v2(36.42,82.58) v2(36.87,83.06) v2(37.46,81.89) v2(38.09,82.02) v2(38.35,83.75) v2(38.35,83.11) v2(38.57,82.5) v2(38.98,83.8) v2(39.03,82.96) v2(39.49,83.42) v2(39.77,82.1) v2(40.33,82.4) v2(40.58,95.08) v2(40.68,82.96) v2(40.91,82.12) v2(41.27,84) v2(41.27,83.29) v2(41.27,82.66) v2(41.57,82.1) v2(41.9,83.29) v2(41.9,82.66) v2(42.21,82.05) v2(42.31,99.7) v2(42.28,98.79) v2(42.28,97.47) v2(42.28,96.83) v2(42.28,95.51) v2(42.31,94.09) v2(42.54,83.24) v2(42.54,82.61) v2(46.14,83.88) v4(25.62,108.13) v5(24.05,106.1) v5(24.05,104.73) v5(24.05,103.99) v5(24.05,103.23) v5(24.17,106.84) v5(24.81,106.1) v5(24.93,106.84) v5(25.57,106.1) v5(25.7,106.84) v5(26.33,106.1) v5(26.46,106.84) v5(26.54,101.58) v5(26.54,99.29) v5(27.07,106.1) v5(27.2,106.84) v5(27.3,101.58) v5(27.3,99.29) v5(27.81,106.1) v5(27.93,106.84) v5(28.06,99.29) v5(28.19,104.63) v5(28.19,103.87) v5(28.19,101.58) v5(28.57,106.1) v5(28.82,99.29) v5(28.95,104.63) v5(28.95,103.87) v5(28.92,101.58) v5(29.58,99.29) v5(29.71,104.63) v5(29.71,103.87) v5(29.66,101.58) v5(30.09,105.26) v5(30.47,104.63) v5(30.47,103.87) v5(30.85,105.26) v5(31.23,104.63) v5(31.23,103.87) v5(31.62,105.26) v5(32,104.63) v5(32,103.87) v5(36.19,101.58)
+VCC_TS: length 3.9
  BOTTOM w0.254: v2(254.98,102.21) 254.98,101.43 254.25,100.69 v2(253.87,100.69) ; v2(253.31,101.88) C53.1 253.83,102.94 R59.2
  vias: v2(254.98,102.85) v2(256.18,102.49) v2(263.44,79.76) v2(263.42,79.13) v2(263.39,78.42)
+VCCIO_OUT: length 69.9
  TOP w0.508: v2(24.5,93.71) v1(25.62,93.71) 26.55,93.71 27.11,94.26 33.56,94.26 35.73,96.43 38.91,96.43 39.37,96.89 40.14,96.89 41.34,98.1 42.71,98.1 43.68,99.07 51.88,99.07 52.24,98.71 55.43,98.71 57.91,101.19 60.81,101.19 61.66,102.04 66.05,102.04 67.23,103.22 68.36,103.22 71.44,100.13 75.24,100.13 75.59,100.49 v2(75.91,100.49)
  BOTTOM w0.254: 74.54,99.42 74.41,99.29 R82.2
  BOTTOM w0.381: 26.79,88.75 26.79,88.34 26.91,88.22 U20.A59
  BOTTOM w0.508: 74.54,99.42 74.92,99.8 75.4,99.8 75.91,100.31 v2(75.91,100.49) ; C163.1 23.49,93.32 23.36,93.45 R118.2 24.13,94.08 v2(24.5,93.71) 24.5,90.28 24.88,89.9 25.9,89.9 26.79,89.01 26.79,88.75
+VCCIOA_OUT: length 7.7
  IN1 w0.254: v2(49.14,88.58) 49.27,88.45 49.27,88.17 49.9,87.53 49.9,85.58 50.59,84.89 v2(51.1,84.89)
  BOTTOM w0.254: U20.E20 51.44,84.89 v2(51.1,84.89) ; 49.41,89.92 R181.1 ; 49.41,89.92 49.41,88.97 49.14,88.7 v2(49.14,88.58) ; 49.41,89.92 v2(49.41,89.92)
+VCCRTCEXT: length 24.1
  TOP w0.254: v2(59.17,74.25) 59.08,74.25 58.59,74.73 57.85,74.73 57.4,74.27 55.62,74.27 55.24,74.66 52.7,74.66 51.94,73.89 51.65,73.89 51.25,73.49 51.25,72.6 51.1,72.45 51.1,71.34 51.14,71.29 51.14,68.28 50.82,67.95 50.82,67.87 v1(50.53,67.58) 48.84,65.89 48.08,65.89 47.57,65.38 47.57,64.32 46.35,63.1 46.35,62.79 46.12,62.57 v2(46.09,62.57)
  BOTTOM w0.254: U20.AE7 59.17,74.05 v2(59.17,74.25) ; C285.1 46.59,62.07 v2(46.09,62.57)
+VIN: length 102.4
  TOP w1.524: 2.23,31.37 1.92,31.07 1.92,28.45 3.55,26.83 5,26.83 6.22,25.61 6.22,20.3 5.61,19.69 5.61,17.76 ; 1.92,36.05 1.92,94.59 3.95,96.63 3.95,103.18 5,104.22 9.14,104.22 14.95,110.04 17.49,110.04
  BOTTOM w0.508: PR70.1 148.07,103.23 v2(147.69,103.61) ; PR24.1 v2(103.12,112.76)
  vias: v1(19.96,111.56) v2(5.12,102.44) v2(5.81,102.44) v2(6.49,102.47) v2(7.54,15.98) v2(7.59,15.27) v2(8.2,15.65) v2(14.97,17.63) v2(15.6,17.63) v2(16.24,17.63) v5(54.25,111.59) v5(54.81,112.15) v5(54.96,111.38) v5(55.36,112.63) v5(55.52,111.89) v5(87.88,117.84) v5(88.13,115.55) v5(88.13,114.79) v5(88.64,117.84) v5(114.17,108.82) v5(114.93,108.82) v5(115.69,108.82) v5(138.52,110.24) v5(139.26,110.24) v5(140,110.24) v5(140.73,110.24) v5(141.06,90.61) v5(141.34,91.32) v5(141.8,90.61) v5(142.08,91.32) v5(142.56,90.58) v5(142.82,91.29) v5(143.32,90.61) v5(143.58,91.32) v5(144.06,90.61) v5(144.31,91.32) v5(144.8,90.61) v5(145.05,91.32) v5(145.53,90.61) v5(145.79,91.32) v5(146.27,90.61) v5(185.11,106.48) v5(185.13,105.75) v5(185.84,106.48)
+VIN_1.05V: length 14
  IN1 w0.152: v2(85.26,117.4) 84.5,116.64 74.31,116.64 72.99,117.96 v2(72.99,118.01)
  BOTTOM w0.152: v2(72.99,118.01) PR6.1
  vias: v4(84.22,116.39)
+VIN_3VS5:
  vias: v4(109.77,110.17)
+VIN_5VS5:
  vias: v4(146.52,105.9)
+VIN_BLIGHT: length 10.5
  BOTTOM w1.016: 2.79,93.71 2.58,93.5 2.58,84.26 3.29,83.55
  vias: v4(2.63,80.27)
+VIN_DDR:
  vias: v2(20.06,18.78)
+VIN_VCC_CORE: length 1.1
  BOTTOM w0.508: PR64.2 54.92,103.86
  vias: v4(52.27,103.61)
AGND: length 28.1
  TOP w0.508: v2(217.92,76.43) 217.92,76.81 R11.1 217.29,77.19 v2(217.29,76.43)
  BOTTOM w0.254: C268.2 C269.2 211.96,75.15 v2(211.96,74.73) ; U19.9 205.1,76.82 204.92,76.64 v2(204.46,76.64) 204.46,76.93 204.61,77.07 U19.10 ; C266.2 C265.2 214.72,75.53 214.72,75.42 214.62,75.32 214.62,75.19 v2(214.5,75.06) 214.4,75.15 C267.2 ; C361.1 208.85,74.37 208.42,73.94 v2(208.42,73.84) ; v3(219.07,73.92) 219.07,74.51 R340.2 C271.2 ; U19.19 206.11,80.78 U19.24 ; C231.2 v2(208.29,81.87) ; U19.29 U19.13 ; U19.23 U19.3
  BOTTOM w0.381: C229.1 211.42,82.68 210.86,83.24 v2(210.86,83.37)
  BOTTOM w0.508: v2(199.51,79.48) 199.9,79.09 C246.1 ; C225.1 202.96,83.34 202.33,83.98 v2(202.25,83.98) ; C273.1 v2(200.65,74.73) ; v2(209.82,77.6) 209.67,77.6 209.52,77.45 C254.2 ; v2(207.89,83.06) 207.89,83.31 C221.1 ; C215.1 199.59,83.99 v2(199.59,83.29) ; C234.1 199.61,81.51 v2(198.95,82.17) ; C217.1 202.91,84.77 v2(202.91,85.37) ; v2(200.98,84.05) 200.54,84.05 C214.1 ; v2(201.68,77.01) 202.06,77.38 C257.1 ; v2(202.25,85.2) 202.19,85.26 C206.1 ; C240.2 208.64,81.51 v2(208.29,81.87) ; Q23.1 v2(222.88,74.91)
  vias: v2(195.19,83.93) v2(195.88,83.93) v2(196.61,83.93)
GND: length 1022.4
  TOP w0.254: 233.75,120.76 233.27,120.76 233.08,120.57 U23.12 ; 233.75,120.76 234.38,120.76 ; 233.75,120.76 233.73,120.74 U23.11 ; CN2.12 74.36,56.47 74.28,56.39 73.47,56.39 73.19,56.11 v1(73.14,56.11) 72.67,56.11 72.56,56 v2(72.51,56) ; v2(15,66.58) 14.54,66.11 CN1.34 ; v2(236.97,120.38) 236.59,120.76 235.04,120.76 ; CN1.46 14.65,72.11 v2(14.83,71.94) ; 235.04,120.76 235.03,120.74 U23.9 ; 235.04,120.76 234.38,120.76 ; CN2.10 74.05,55.47 72.89,54.31 v2(72.89,53.73) ; 234.38,120.76 234.38,120.75 U23.10 ; v2(11.46,74.16) 11.51,74.16 12.06,73.61 CN1.49 ; v2(15.49,70.56) 15.28,70.77 14.5,70.77 14.34,70.61 CN1.43 ; v2(230.95,119.46) 231.01,119.46 231.66,118.81 U23.13 ; CN1.40 11.56,69.11 v2(11.32,69.35) ; v2(237.1,119.13) 236.78,118.81 U23.8
  TOP w0.279: v2(9.67,65.26) 9.67,65 9.28,64.61 CN1.30 ; v2(11.25,78.42) 11.95,79.11 CN1.60 ; CN1.27 6.33,66.11 6.22,66.22 6.04,66.22 v2(5.88,66.38) ; v2(5.91,68.94) 6.04,68.94 6.22,69.11 CN1.21 ; CN1.37 11.87,67.61 10.28,66.02 v2(10.28,65.84) ; v2(13.45,63.23) 13.71,63.48 13.71,63.61 13.19,64.12 CN1.31 ; v2(5.91,72.24) 6.04,72.11 CN1.15 ; CN1.55 14.52,76.61 14.72,76.81 14.72,77.07 16.54,78.88 v2(16.54,79.48) ; v2(9.57,75.88) 9.57,75.93 8.88,76.61 CN1.6 ; v2(5.91,73.39) 6.14,73.61 CN1.12 ; CN1.24 9.08,67.61 10.03,68.56 v2(10.15,68.56) ; v2(5.83,71.02) 5.88,71.02 6.3,70.61 CN1.18
  TOP w0.305: U3.7 7.03,59.08 v2(6.98,59.14) ; v2(73.98,54.26) 74.2,54.47 CN2.8 ; CN2.14 76,57.47 76.09,57.38 76.29,57.38 v2(76.31,57.4)
  TOP w0.381: 227.07,120.63 227.05,120.61 U1.11 ; U1.10 227.85,120.33 227.55,120.63 ; v2(229.74,114.89) 230.24,114.89 230.55,115.19 230.55,117.66 230.37,117.84 U1.7
  TOP w0.508: U3.15 6.9,59.06 v2(6.98,59.14) ; 227.55,120.63 v2(223.77,120.63) ; C2.1 v2(221.12,116.95)
  BOTTOM w0.102: U20.AP10 56.94,69.2 56.94,69.41 56.84,69.51 56.84,69.77 56.94,69.87 56.94,70.05 56.77,70.22 56.77,70.35 57.09,70.67 57.09,70.87 U20.AL10
  BOTTOM w0.127: 41.7,67.4 41.58,67.28 41.58,66.9 41.22,66.54 U20.AV36 ; v2(25.19,84.65) 25.18,84.66 25.18,84.89 25.15,84.91 25.15,85.21 24.84,85.52 U20.D62 ; U20.AV49 33.34,66.54 33.71,66.9 33.71,67.27 33.81,67.38 ; U20.AV41 38.07,66.54 38.43,66.9 38.43,67.34 38.47,67.37 ; U20.AV43 36.49,66.54 36.86,66.9 36.86,67.18 37.1,67.43 ; U20.AV39 39.64,66.46 40.01,66.83 40.01,67.46 ; U20.AV46 34.92,66.54 35.28,66.9 35.28,67.17 35.27,67.18 35.27,67.49
  BOTTOM w0.152: U20.G5 60.29,83.87 61.17,83.87 U20.G3 ; U20.AU16 53.11,67.36 53.1,67.38 52.81,67.38 52.71,67.27 52.37,67.27 U20.AU18
  BOTTOM w0.178: U15.25 97.54,82.52 97.18,82.87 v2(97.18,82.94) ; U20.Y59 27.12,77.08 v2(27.12,77.16) ; v2(48.53,64.45) 48.5,64.48 U20.AY24 U20.AW24 U20.AV24 U20.AU24 ; U20.AU33 43.2,67.38 42.65,67.94 ; U20.AU33 44.18,67.38 44.2,67.36 U20.AU30 ; U20.AU33 43.41,67.36 U20.AV33 ; 42.65,67.94 42.38,67.67 U20.AT35 42.28,67.4 41.26,67.4 41.17,67.49 U20.AT37 40.04,67.49 39.97,67.43 39.3,67.43 U20.AT40 38.73,67.49 38.61,67.37 38.47,67.37 38.47,67.38 37.77,67.38 U20.AT42 37.17,67.49 37.08,67.4 36.17,67.4 U20.AT43 36.05,67.47 35.29,67.47 35.27,67.49 U20.AT46 34.44,67.43 33.87,67.43 33.81,67.38 33.79,67.4 32.97,67.4 U20.AT49 ; 42.65,67.94 42.91,68.2 U20.AR33 ; U20.AU18 52.25,67.39 51.6,67.39 51.56,67.35 51.27,67.35 51.26,67.36 U20.AU20 ; 36.08,66.07 36.39,66.39 U20.AV43 ; 36.08,66.07 v2(36.08,66.06) ; 36.08,66.07 35.74,65.74 U20.AW44 ; U20.Y63 23.64,76.79 v2(23.61,76.81) ; U20.AN31 44.5,69.87 44.5,70.42 U20.AM31 44.5,70.52 44.5,71.07 U20.AL31 ; U20.AN31 44.23,69.5 U20.AN32 43.99,69.43 43.76,69.2 43.61,69.2 v2(43.6,69.19) ; U20.AN31 U20.AP31 U20.AR31 44.55,67.52 U20.AU30 ; U20.AY51 31.74,65.5 31.74,65.97 U20.AW51 U20.AV51 U20.AU51 31.32,67.36 31.3,67.38 31.02,67.38 31,67.36 U20.AU53 30.07,67.36 30.06,67.38 29.77,67.38 29.75,67.36 U20.AU55 ; U20.AU20 50.58,67.36 50.56,67.38 50.27,67.38 50.26,67.36 U20.AU22 49.82,67.33 49.35,67.33 48.89,67.78 48.89,67.86 48.87,67.87 ; U20.AU20 U20.AV20 ; v2(29.25,66.13) 29.27,66.14 U20.AV55 U20.AU55 ; v2(42.65,70.46) 42.99,70.8 U20.AL33 ; U20.AU55 28.78,67.36 28.76,67.38 28.48,67.38 28.46,67.36 U20.AU57 27.54,67.36 27.52,67.38 27.23,67.38 27.22,67.36 U20.AU59 U20.AV59 U20.AW59 ; U20.AV41 37.97,66.39 v2(37.66,66.08) 37.32,65.74 U20.AW42 ; 48.87,67.87 48.5,67.48 U20.AU24 ; 48.87,67.87 49.2,68.2 U20.AR23 ; U20.AY33 U20.AW33 ; U20.AW33 43.36,66.66 U20.AV33 ; U20.AW33 43.12,66.06 U20.AV34 ; U20.AL17 U20.AM17 U20.AN17 U20.AP17 U20.AR17 U20.AU16 U20.AV16 U20.AW16 53.59,65.45 U20.AY16 ; U20.AV33 43.12,66.71 U20.AV34 ; U20.AU24 48.48,67.38 47.63,67.38 47.5,67.25 47.26,67.25 U20.AU26 46.74,67.36 46.72,67.38 46.43,67.38 46.42,67.36 U20.AU28 ; U20.AN60 26.46,69.74 26.48,69.76 26.48,70.04 26.46,70.06 U20.AL60 26.46,71.03 26.48,71.05 26.48,71.33 26.46,71.35 U20.AJ60 ; v2(40.73,69.3) 40.75,69.3 40.95,69.5 U20.AN36 ; U20.AV34 42.71,66.39 v2(42.39,66.06) ; U20.AU28 U20.AV28 45.93,66.24 45.89,66.2 v2(45.89,66.17) ; U20.AU28 45.44,67.36 45.43,67.38 45.14,67.38 45.12,67.36 U20.AU30 ; v2(23.23,74.06) 23.42,74.06 23.84,74.48 24.12,74.48 U20.AD63 ; v2(148.96,105.26) 149.55,105.84 PU5.14 ; v2(57.57,66.08) 57.67,66.08 U20.AV8 ; v2(34.5,65.46) 34.22,65.74 U20.AW47 ; U20.AP52 31.23,68.72 31.22,68.71 31.22,68.34 31.23,68.32 U20.AR52 ; PU3.11 58.84,109.28 58.77,109.2 58.56,109.2 58.41,109.05 58.05,109.05 v2(58.03,109.02) ; v2(40.69,70.62) 40.74,70.62 40.91,70.8 U20.AL36 ; v2(103.37,110.22) 102.9,109.75 PU4.14 ; PU8.7 v2(12.88,23.5)
  BOTTOM w0.203: U7.113 211.1,89.69 211.52,89.26 v2(211.52,89.18) ; U20.AP54 30.56,69.2 v2(30.71,69.2) ; U20.AL46 35.28,70.53 v2(35.47,70.53) 35.67,70.53 U20.AL45 ; v2(61.81,71.13) 61.51,71.43 U20.AK3 ; U20.AN40 39.01,69.82 U20.AN39 ; v2(45.05,71.11) 45.14,71.11 U20.AL29 ; PU1.19 76.71,111.88 v2(76.45,111.61) ; U20.AR39 U20.AP39 U20.AN39 ; U20.AR39 39.27,67.54 U20.AT40 ; U20.AR39 39.85,68.52 U20.AP38 40.25,68.85 40.7,69.3 v2(40.73,69.3) ; U7.24 202.59,101.36 202.38,101.15 202.38,101.05 201.39,100.06 v2(201.34,100.06) ; v2(34.52,69.28) 34.74,69.5 U20.AN46 ; v2(34.52,69.91) 34.1,69.5 U20.AN48 ; U20.B52 U20.A52 31.34,87.49 v2(31.34,88.1) ; v2(49.72,70.45) 49.51,70.65 49.43,70.65 U20.AL23 ; v2(49.72,70.45) 49.94,70.68 49.99,70.68 U20.AL22 ; v2(49.72,70.45) 49.54,70.27 49.41,70.27 U20.AM23 ; U20.AG1 63.39,73 v2(63.42,73.03) ; v2(41.68,69.13) 42.05,69.5 U20.AN35 ; 36.47,67.89 v2(36.45,67.89) ; 36.47,67.89 36.78,68.2 U20.AR43 ; 36.47,67.89 36.08,67.5 U20.AT43 ; v2(63.36,66.89) 63.25,67.01 62.87,67.01 U20.AU1 ; v2(11.02,21.95) 11.36,21.6 PU8.4 ; U20.B48 U20.A48 33.52,87.61 33.52,87.81 33.27,88.07 v2(33.27,88.37) ; U20.AN39 39.27,70.21 U20.AL40 ; U20.E17 53.17,85.47 v2(53.05,85.47) ; U20.AN42 37.61,69.24 v2(37.35,69.24) 37.18,69.24 U20.AN43 ; U20.K1 63.33,81.99 v2(63.35,82.01) ; v2(30.71,69.2) 31.06,68.85 U20.AP52 ; v2(30.71,69.2) 30.77,69.2 31.06,69.5 U20.AN52 ; U20.U61 25.84,78.6 v2(25.84,78.66) ; v2(26.31,68.17) 26.51,68.37 26.51,69.28 U20.AN60 ; U20.AP20 51.69,69.17 v2(51.63,69.17) ; v2(26.48,84.66) 27.08,84.66 27.14,84.59 U20.F58 ; U20.AV14 54.84,66.53 54.75,66.53 v2(54.57,66.71) ; CN7.15 8.33,82.65 v2(7.82,83.16) ; v2(25.19,81.66) 25.49,81.36 U20.L61 ; PR7.2 78.73,117.18 78.86,117.3 v2(78.86,117.35) ; v2(51.1,66.21) 51.06,66.24 U20.AV20 ; U20.AC61 25.19,75.55 v2(25.19,75.66) ; v2(25.19,84.65) 25.19,84.54 U20.F61 ; U20.AM1 63.32,70 v2(63.32,70) ; U20.V3 61.51,77.42 v2(61.82,77.12) ; v2(61.81,80.12) 61.51,80.42 U20.N3 ; v2(205.81,107.6) 205.9,107.51 U7.35 ; U20.AW60 26.49,65.74 U20.AW59 ; U7.94 217.76,92.96 217.14,93.58 v2(217.14,93.91) ; U18.35 217.22,81.71 v2(217.42,81.51) ; U20.AN49 33.31,69.25 33.51,69.25 v2(33.57,69.19) ; U20.AD3 61.51,74.42 v2(61.81,74.12) ; U18.34 216.82,81.55 v2(216.78,81.51) ; v2(36.16,87.97) 36.16,87.89 36.25,87.8 U20.A44 U20.B44 ; U7.11 v2(204.61,96.16) ; U20.D2 61.75,86.06 61.18,86.06 v2(61.09,86.15) ; U20.T1 63.29,78.99 v2(63.4,78.89)
  BOTTOM w0.229: U20.AB22 49.38,75.82 49.14,76.05 v2(48.89,76.05) ; R262.2 11.57,83.42 v2(12.01,83.85)
  BOTTOM w0.254: U20.D57 U20.C57 28.04,86.42 28.41,86.42 U20.B56 U20.A56 28.73,87.99 28.69,88.03 v2(28.69,88.32) ; C3.1 C4.1 222.65,117.21 v2(222.43,117) R12.2 ; v2(43.17,97.47) 42.81,97.83 C76.1 ; v2(37.31,71.86) 37.19,71.98 U20.AH42 ; v2(37.31,71.86) 36.78,71.86 U20.AJ43 36.31,72.33 35.99,72.33 U20.AH44 35.56,72.43 U20.AJ45 35.01,71.87 v2(34.52,71.87) ; v2(37.31,71.86) 37.6,71.86 U20.AJ41 ; U20.G22 50.21,83.97 v2(50.6,84.37) ; v2(65.32,73.59) 65.32,73.48 65.87,72.93 R353.1 R359.1 ; v2(63.44,76.03) 63.44,76 63.44,76 U20.AA1 ; U20.D34 42.85,85.76 U20.D33 ; U20.D34 42.2,85.76 U20.D35 ; U20.D34 U20.F34 v2(42.52,83.89) ; v2(52.19,76.47) 52.19,76.34 51.67,75.82 U20.AB20 ; C293.2 60.39,59.54 v2(60.8,59.95) 60.57,60.18 C292.2 ; v2(211.52,89.18) 211.52,88.7 211.36,88.54 C192.2 ; R409.2 60.6,61.24 60.81,61.03 v2(60.81,60.84) 60.79,60.81 C290.2 ; U20.AJ27 46.62,72.43 U20.AH28 46.06,72.66 v2(45.64,72.66) ; v2(59.15,80.9) 59.15,81.1 U20.L7 ; v2(45.83,59.8) C291.1 ; v2(29.76,68.52) 29.84,68.52 30.17,68.85 U20.AP54 ; U20.G8 U20.G6 59.26,83.86 59.63,84.23 v2(59.76,84.23) 59.86,84.23 60.21,83.88 U20.G5 ; v2(38.65,86.21) 39.25,86.21 U20.C39 U20.D39 ; v2(38.65,86.21) 38.76,86.33 U20.B40 U20.A40 ; v2(38.65,86.21) 38.2,85.76 U20.D41 37.83,85.76 U20.D42 U20.F42 37.51,84.12 37.15,83.77 v2(37.15,83.72) ; R127.2 v2(14.57,93.12) ; v2(56.76,90.53) 57.02,90.78 C176.2 ; U20.U20 51.63,78.29 52.06,78.72 v2(52.19,78.72) ; v2(244.34,95.48) 244.59,95.23 R111.2 ; U20.AH53 30.35,72.77 v2(30.19,72.77) 29.73,72.77 U20.AH55 ; U20.AH53 31.01,72.1 U20.AJ52 ; U20.AH53 30.36,72.1 U20.AJ54 29.71,72.1 U20.AH55 ; U20.AL31 45.04,71.12 v2(45.05,71.11) ; v2(14.83,71.94) 14.81,71.95 R354.2 ; U20.D63 23.75,85.74 v2(23.56,85.92) ; R101.2 242.93,97.23 v2(243.1,97.39) 243.29,97.58 C84.2 ; C285.2 47.07,62.15 47.26,62.34 v2(47.79,62.34) 47.79,61.5 47.46,61.17 C288.1 ; U12.29 232.6,93.11 U12.10 ; C33.1 205.91,108.55 C28.1 ; R60.1 251.38,103.74 v2(251.78,103.33) 251.35,102.9 R66.1 ; 56.06,85.44 U20.E11 ; 56.06,85.44 v2(56,85.44) ; 56.06,85.44 56.24,85.44 56.48,85.68 56.48,86.5 U20.C11 ; U15.11 102.09,89.22 102.23,89.36 102.25,89.36 v2(102.28,89.39) ; v2(35,83.9) U20.F46 U20.D46 ; v2(23.61,79.93) 23.76,79.78 U20.P63 U20.P62 ; v2(23.44,69.45) 23.44,68.48 24.05,67.87 U20.AT63 24.35,67.87 24.5,68.02 U20.AT62 25.06,68.08 U20.AT61 26.22,68.08 v2(26.31,68.17) ; C244.1 75.3,79.34 C245.1 74.44,79.34 v2(74.29,79.2) ; C241.1 71.57,79.91 71.61,79.87 C249.1 ; v2(78.22,86.39) 77.73,86.39 R242.1 ; v2(36.44,69.86) 36.31,69.86 U20.AN45 ; U20.AF18 52.69,73.64 53.06,74.01 v2(53.08,74.01) 53.13,74.01 53.5,73.64 U20.AF17 ; C186.2 67.8,88.77 68.11,88.45 v2(68.11,88.24) ; v2(45.64,72.66) U20.AJ29 ; v2(45.64,72.66) 45.23,72.66 U20.AH30 ; v2(11.46,74.16) 11.59,74.03 11.84,74.03 12.06,73.82 C274.1 ; U20.D23 49.44,86.2 v2(49.24,86.4) 48.9,86.74 U20.B24 48.63,86.9 48.63,87.23 U20.A24 ; U20.AH55 29.06,72.1 U20.AJ56 28.74,72.1 28.41,72.43 U20.AH57 27.74,72.43 27.44,72.12 U20.AJ58 26.86,72.1 ; v2(42.44,71.89) 42.39,71.94 42.39,72.42 U20.AH34 42.13,72.68 v2(41.77,72.68) 41.74,72.66 U20.AJ35 ; v2(56.71,74.78) 56.71,74.66 57.34,74.03 U20.AE10 ; v2(235.45,91.32) 235.55,91.42 235.87,91.42 R166.2 ; U20.AJ13 55.54,71.24 U20.AL13 54.72,71.45 U20.AJ14 54.49,71.59 v2(54.27,71.81) ; U20.U9 57.78,78.01 U20.V10 56.9,77.57 56.48,77.98 v2(56.48,78.01) ; U20.C25 47.78,86.74 U20.B26 47.54,87.21 47.41,87.34 47.41,88.12 v2(47.31,88.22) ; U20.AP29 45.14,69.16 v2(45.05,69.16) ; C82.2 51.14,98.43 v2(51.6,98.43) 51.6,98.07 51.81,97.87 C85.1 ; v2(32.91,65.4) 32.91,65.42 32.6,65.74 U20.AW50 ; v2(223.87,92.26) 223.4,92.26 C155.2 ; R123.1 235.5,93.99 v2(235.37,94.11) ; v2(35.29,66.06) 34.96,66.39 U20.AV46 ; U20.D38 40.25,85.44 U20.D37 40.25,86.09 U20.C38 39.69,85.76 U20.D39 ; U20.D38 39.78,85.44 U20.D39 ; U20.D38 U20.F38 v2(40.01,83.95) ; U20.AW4 60.84,65.13 U20.AY4 60.89,64.87 61.54,64.22 v2(61.59,64.22) ; v2(234.99,110.5) 234.79,110.7 R30.2 ; v2(70.52,75.21) R336.1 ; v2(43.6,71.9) 43.6,72.33 U20.AH32 ; R134.2 235.48,93.22 v2(235.4,93.15) ; U20.AG60 26.77,73.11 U20.AE58 ; U20.AG60 U20.AG61 U20.AG62 U20.AG63 24.28,73.11 23.74,72.57 23.74,72.27 24.25,71.76 U20.AJ63 ; U20.AG60 26.46,72.7 26.86,72.3 26.86,72.1 ; R138.1 226.31,93.15 226.1,93.35 226.1,93.58 v2(225.65,94.04) ; v2(31.66,69.17) 31.56,69.17 U20.AP52 ; v2(197.83,87.1) 198.1,87.37 C189.1 ; U20.AH16 53.91,72.17 v2(54.27,71.81) ; v2(252.98,97.52) 252.87,97.62 R95.2 ; CN6.21 250.75,87.42 v2(250.56,87.23) ; v2(14.52,97.26) 14.84,97.58 R91.1 ; v2(25.39,12.15) 25.77,12.53 25.77,12.93 26.04,13.2 C359.2 ; v2(4.03,11.79) 3.78,12.04 3.78,12.71 3.61,12.87 C360.2 ; C310.2 56.51,27.3 56.51,27.39 v2(56.15,27.74) ; v2(257.75,89.46) CN6.35 ; v2(201.34,100.06) 201.4,99.99 C65.2 C66.1 ; v2(103.5,79.23) 103.5,79.48 103.36,79.62 C243.2 ; v2(50.6,84.37) 50.55,84.41 50.55,85.27 U20.D21 ; v2(50.6,84.37) 51.56,84.37 U20.F20 ; v2(67.94,27.41) 68.22,27.41 C308.2 C313.2 ; C237.1 v2(222.37,81.13) 222.38,81.14 C239.1 ; v2(223.79,79.75) 223.79,79.52 C247.1 ; U20.AN51 32.36,69.19 v2(32.62,69.19) ; v2(252.98,95.48) 252.75,95.71 R109.2 R115.2 ; U12.26 231.1,93.36 U12.6 ; v2(44.95,27.16) 44.95,26.85 45.08,26.73 C312.2 ; U20.AH49 33.4,72.31 v2(33.4,71.87) ; v2(47.78,69.12) 47.66,69.12 47.38,68.85 U20.AP26 ; v2(254.04,101.3) 254.31,101.57 C53.2 ; v2(28.81,69.18) 28.69,69.18 28.36,68.85 U20.AP57 ; v2(52.98,25.37) 52.78,25.56 C323.1 ; C352.2 17.65,14.92 v2(18.42,15.69) ; v2(40.63,88.7) 40.63,88.37 41.01,87.99 41.01,87.64 U20.A36 U20.B36 ; v2(3.95,63.68) 3.75,63.68 3.05,62.99 EC12.2 ; v2(28.34,83.52) 27.85,83.52 U20.H57 ; C255.1 221.97,77.88 221.68,77.59 v2(221.68,77.25) ; v2(27.12,77.16) 27.44,77.48 U20.V58 ; v2(243.4,98.99) 243.31,98.9 R76.1 ; 30.71,70.47 30.39,70.8 U20.AL54 ; 30.71,70.47 v2(30.71,70.47) ; 30.71,70.47 31.05,70.81 31.22,70.81 U20.AL52 ; CN7.7 v2(7.87,86.65) ; U20.AH22 50.64,73 v2(50.64,73.05) ; U20.AH22 49.8,72.16 U20.AJ23 ; U20.AH22 49.8,72.97 U20.AG23 49.18,72.97 v2(49.14,72.94) 48.89,72.69 U20.AH24 ; v2(32.62,67.88) 32.9,67.6 U20.AT49 ; v2(32.62,67.88) 32.74,67.88 U20.AR49 33.38,68.52 v2(33.57,68.52) 33.63,68.52 U20.AP48 ; v2(32.62,67.88) 32.09,67.36 U20.AU51 ; R171.2 42.54,92.05 42.79,92.31 v2(43.17,92.31) R170.2 ; R97.1 24.25,97.12 24.25,96.77 ; R195.2 99.05,89.88 98.93,89.75 98.93,89.51 v2(98.8,89.39) 98.67,89.51 98.67,89.77 98.56,89.88 C182.2 ; U20.AK52 31.34,71.55 U20.AJ52 ; R321.2 68.42,75.98 v2(68.78,76.33) ; R176.2 225.47,90.86 v2(225.77,91.17) 226.38,90.56 R183.2 ; R78.1 v2(240.73,98.23) ; U20.AV39 39.32,66.06 v2(39.25,66.06) 39.14,66.06 U20.AW40 ; U20.B20 51.3,86.73 U20.C20 U20.C18 52.32,86.53 52.32,87.6 U20.A18 52.21,87.95 52.44,88.18 v2(52.44,88.17) ; v2(28.44,77.07) 27.81,76.43 27.49,76.43 U20.AA58 27.15,76.38 U20.Y59 ; v2(33.4,71.87) 32.87,71.87 U20.AJ50 32.31,72.1 U20.AH51 31.66,72.75 v2(31.56,72.75) 31.34,72.53 U20.AJ52 ; v2(33.4,71.87) 33.71,71.87 U20.AJ47 34.19,72.1 34.42,71.87 v2(34.52,71.87) ; CN7.4 v2(7.87,88.15) ; U20.AB22 50.21,75.64 51.13,74.72 U20.AD21 ; v2(34.52,71.87) 34.52,72.36 U20.AH46 ; v2(251.93,111.49) C13.1 C17.1 ; v2(59.08,78.06) 58.88,77.86 U20.V7 ; C170.2 52.12,91.78 53.04,91.78 v2(53.14,91.67) 53.14,91.66 53.41,91.39 C169.1 ; R435.1 R434.2 59.63,58.22 v2(59.3,58.55) 59.61,58.86 R432.2 ; U20.P59 26.79,79.66 27.44,79.01 U20.T58 28.07,78.99 v2(28.31,79.23) ; v2(14.98,27.77) 14.98,27.16 14.85,27.03 14.46,27.03 C309.1 ; C184.2 C179.2 221.52,90.11 v2(221.2,90.43) ; Q19.4 v2(230.79,85.18) ; C38.1 251.31,104.9 251.12,105.09 v2(250.26,105.09) 250.26,105.26 250.51,105.52 C37.1 ; v2(56.71,88.45) 56.71,88.17 56.45,87.91 U20.A11 ; R167.2 227.73,91.52 v2(227.7,91.5) ; v2(14.83,11.49) 14.83,11.92 14.33,12.41 EC15.2 ; v2(254.78,104.48) 254.98,104.27 C41.1 ; v2(16.3,76.33) 16.04,76.33 15.58,76.8 C262.1 ; C119.2 C112.2 224.02,95.23 224.5,95.71 v2(224.5,95.86) ; C311.2 52.93,26.83 53.74,27.64 v2(53.74,27.74) ; v2(102.91,89.39) 102.91,89.59 102.48,90.02 101.76,90.02 C181.2 ; 26.86,72.1 26.52,71.76 U20.AJ60 ; C242.2 v2(98.16,79.23) ; U20.J59 26.84,82.74 v2(27.2,82.38) ; C125.2 201.21,94.14 200.79,93.71 v2(200.79,93.57) ; C209.2 212.25,85.56 v2(211.85,85.17) ; U20.W20 52.21,78.02 v2(52.21,78.06) ; C31.2 208.32,109.56 v2(208.27,109.61) ; C56.2 193.6,100.27 v2(193.57,100.23) ; C358.2 29.04,13.25 v2(29.2,13.42) ; C128.2 263.71,93.71 v2(264.15,93.71) ; U16.3 77.78,84.98 v2(78.22,85.43) ; v2(84.68,90.38) 85.59,91.29 C152.2 C153.1 ; R73.1 C55.2 260.72,101.1 v2(260.95,100.87) ; U20.AH24 48.57,72.43 U20.AJ25 48.24,72.68 v2(47.92,73) ; U20.AH24 49.29,72.03 U20.AK23 ; U20.C14 54.93,86.56 54.93,87.57 U20.A14 54.88,87.81 v2(54.88,88.24) ; R88.1 242.18,97.39 v2(241.98,97.19) ; R414.1 66.84,61.17 67,61.02 v2(67,60.79) ; v2(3.83,55.83) 4.81,55.83 C295.1 ; C222.2 C216.2 215.75,85.15 v2(215.7,85.2) ; R92.1 C89.1 201.43,96.92 201.21,96.7 v2(201.21,96.55) ; v2(138.55,89.97) 138.55,89.64 137.9,88.99 EC9.2 ; R383.1 72.28,66.45 v2(72.56,66.17) ; v2(196.87,110.44) 197.1,110.44 197.12,110.47 C19.2 ; C282.2 13.57,63.11 v2(13.45,63.23) ; U20.V23 49.8,77.85 U20.W22 ; U20.V23 v2(49.12,77.85) ; U20.V23 50.11,78.26 U20.U22 U20.R22 ; C294.2 71.89,58.4 71.24,58.4 v2(71.09,58.25) ; CN6.18 249.25,87.57 248.91,87.23 v2(248.66,87.23) ; v2(66.87,63.94) 66.87,64.51 C278.2 ; v2(22.24,60.36) 21.72,60.88 R417.2 ; U20.D12 U20.D14 55.18,85.93 v2(54.86,85.6) ; U20.AL26 47.02,70.46 v2(46.97,70.46) ; R200.1 21.16,89.51 v2(21.18,89.53) ; v2(54.27,71.81) 54.27,71.73 53.67,71.13 U20.AL17 ; v2(19.3,85.45) 19.32,85.43 R251.2 ; CN6.13 246.75,88.39 v2(246.75,87.23) ; U20.AL20 51.87,70.94 51.82,70.94 v2(51.63,71.13) ; R357.2 72.37,72.74 72.26,72.62 v2(72,72.62) 71.9,72.73 C275.2 ; R392.2 76.55,64.22 v2(76.07,63.73) ; C287.2 54.98,60.84 v2(54.98,60.84) ; v2(237.1,119.13) 236.36,119.13 v4(235.7,118.47) 235.68,118.5 235.68,118.06 C362.1 234.27,116.65 C365.1 C364.1 232.28,117.34 C363.2 231.77,118.72 231.03,119.46 v2(230.95,119.46) ; v2(31.13,110.83) 31.13,110.18 EC1.2 ; U20.AH38 39.47,72.43 U20.AJ39 ; U20.B28 U20.A28 46.09,87.58 46.09,88.8 46.47,89.18 v2(46.47,89.26) ; v2(22.9,15.85) 22.9,15.47 23.18,15.19 C347.2 ; R255.2 72.47,85.31 73.13,85.97 C208.1 73.27,86.67 v2(73.22,86.72) ; C340.2 72.36,23.86 72.18,23.68 v2(72.08,23.68) 72.53,23.22 C341.2 ; v2(7.79,62.95) 7.38,62.95 7.02,62.59 7.02,62.58 6.88,62.44 6.41,61.97 C284.2 ; v2(53.05,85.47) 52.71,85.8 U20.D18 ; C22.1 v2(221.96,110.46) ; v2(6.6,95.74) 7.18,95.15 C113.2 ; v2(255.74,90.38) 255.67,90.38 255.14,89.85 255.14,89.3 255.25,89.18 CN6.30 ; CN6.27 253.75,87.24 v2(253.74,87.23) ; v2(248.79,99.93) U10.3 ; C83.2 244.42,98.07 v2(244.31,97.97) ; v2(30.71,69.2) 30.71,67.86 30.48,67.63 U20.AU53 ; C72.1 238.1,98.8 v2(238.55,98.35) R80.1 ; v2(53.84,74.02) 53.84,73.89 54.3,73.43 U20.AF15 U20.AF14 ; v2(263.24,93.38) 263.24,93.3 263.12,93.19 C150.2 263.12,92.57 263.4,92.29 C157.2 C167.2 ; EC8.2 v2(80.26,89.02) ; U20.R8 U20.R10 ; R270.1 14.48,81.31 14.62,81.45 v2(14.62,82.28) ; v2(45.64,63.05) 45.64,62.92 45.46,62.74 45.46,62.45 45.83,62.08 C286.1 C289.2 ; U20.AN40 38.36,69.18 v2(38.27,69.18) ; U20.D53 30.99,86.21 v2(31.43,86.21) 31.48,86.21 U20.D51 ; R148.1 64,92.41 v2(63.67,92.08) ; U20.D45 36.01,86.21 v2(36.13,86.21) 36.5,86.21 U20.D43 ; v2(69,78.21) 68.57,77.78 R303.2 ; v2(234.94,86.97) 234.45,86.48 Q19.1 ; U12.31 232.6,91.11 U12.21 ; U20.D5 60.31,86.04 60.99,86.04 v2(61.09,86.15) 61.09,86.86 U20.B4 ; U20.AL61 U20.AL60 ; C26.1 216.53,108.62 216.31,108.4 R45.1 v2(216.86,108.21) ; U20.K12 55.89,82.01 U20.L13 55.45,81.17 55.87,80.75 55.87,80.7 v2(55.82,80.65) ; R399.1 71.08,63.23 71.87,63.23 v2(72.2,63.56) ; v2(57.39,109.02) 58.03,109.02 v2(58.03,109.02) ; R245.1 224.36,85.45 v2(224.22,85.31) ; C18.2 225.14,110.65 v2(225.42,110.37) ; v2(74.8,101.2) 75.16,100.83 EC5.2 ; C29.2 C30.2 v2(208.93,109.61) 209.28,109.95 C23.1 ; C32.2 v2(207.56,109.61) ; U20.D59 26.91,85.81 v2(26.35,86.38) 26.26,86.47 26.26,86.95 U20.B60 ; U10.13 v2(248.79,95.99) ; R150.2 235.48,92.33 v2(235.37,92.23) ; U20.H13 55.15,83.44 v2(55.01,83.44) ; v2(62.6,25.63) 62.49,25.75 U22.3 ; v2(235.25,85.04) 235.25,84.85 C220.1 ; R81.2 75.46,98.95 R85.2 75.99,98.98 v2(75.99,99.37) ; U20.AV36 40.89,66.06 v2(40.84,66.06) 40.72,66.06 U20.AW37 ; v2(206.19,88.65) 206.19,88.5 206.54,88.14 206.86,88.14 C195.2 ; v2(263.95,96.4) 263.83,96.4 C92.2 ; v2(60.42,68.3) 60.38,68.34 U20.AR5 ; v2(29.98,83.42) U20.F54 U20.D54 29.66,85.76 U20.D55 ; C16.2 C15.2 219.08,110.71 v2(219.27,110.52) ; CN7.1 v2(7.87,89.65) ; U17.2 72.64,82.97 72.37,82.97 71.94,82.55 71.94,82.26 C233.1 ; v2(227.68,89.59) 227.73,89.64 C180.1 ; v2(56.58,80.12) 56.89,80.42 U20.N10 ; v2(53.54,80.96) 53.88,80.96 U20.L15 U20.L17 U20.L18 52.59,81.47 52.9,81.16 v2(52.9,80.96) ; C302.2 34.45,41.79 v2(34.86,41.79) 35.08,41.79 35.25,41.62 C301.2 ; U20.AM23 49.29,70.06 49.22,69.99 49.22,69.65 49.29,69.59 U20.AN23 ; U20.AL57 28.31,70.71 28.08,70.48 v2(27.85,70.48) ; v2(12.27,84.77) R250.2 ; U12.34 233.6,90.86 U12.18 ; U20.AU16 53.87,67.64 v2(54.3,67.64) U20.AR15 55,67.69 U20.AT13 ; U20.D50 U20.F50 32.49,83.83 32.52,83.81 v2(32.54,83.81) ; R90.2 69.72,98.4 70.19,98.87 70.19,99.76 71.09,100.67 Q11.1 ; U20.AH36 41.09,72 v2(40.99,71.9) ; v2(223.84,93.4) 223.77,93.32 C134.2 ; U20.AJ39 39.21,72.03 39.21,71.19 U20.AL39 38.95,70.8 U20.AL40 38.36,70.47 v2(38.3,70.47) ; U20.AJ39 38.93,72.31 38.93,72.6 v2(39.01,72.68) 38.75,72.68 U20.AH40 ; 237.58,78.01 237.58,80.85 235.59,82.85 C230.2 ; v2(8.85,61.64) 8.85,62.11 C283.2 ; C194.1 222.22,87.69 v2(221.78,88.12) C199.2 C200.2 ; U20.J22 50.21,82.3 v2(50.59,81.92) 50.94,81.57 51.57,81.57 U20.L20 ; C305.2 v2(38.87,40.51) C306.2 ; v2(222.32,77.25) 222.32,77.68 222.74,78.1 C253.2 C252.2 ; CN6.24 252.25,87.29 v2(252.28,87.27) ; C303.2 29.01,41.69 v2(28.39,41.69) 27.87,41.69 C304.2 ; C73.2 263.43,99.04 263.5,99.12 C68.2 263.5,99.58 263.67,99.75 v2(263.9,99.75) ; U20.D47 34.36,85.76 v2(33.92,86.2) 33.49,86.2 U20.D49 ; PR9.2 79.83,116.7 79.24,116.1 PU1.4 ; U20.D8 58.66,85.57 v2(58.79,85.43) ; C300.2 38.64,42.42 v2(38.87,42.42) 39.07,42.42 C299.2 ; U20.G18 52.92,83.47 v2(53.02,83.47) 53.22,83.47 U20.H17 ; R182.2 v2(227.68,90.56) ; C260.1 11.25,78.11 v2(11.25,78.42) 11.47,78.63 C250.2 ; C345.1 v2(69.57,19.93) ; C224.2 C228.2 224.15,82.64 v2(224.15,82.23) ; v2(6.77,94.32) 6.85,94.32 7.05,94.52 C122.1 ; R146.1 v2(227.7,92.41) ; v2(28.31,81.89) 28,81.59 U20.L58 ; U20.AY11 v2(56.44,64.42) ; U4.2 206.6,110.93 206.41,110.74 C14.1 ; R323.2 19.55,75.93 19.17,76.31 v2(18.93,76.31) ; v2(65.78,40.67) R458.2 C307.2 ; PU7.14 PU7.25 ; 49.29,68.85 U20.AR23 ; U20.AB10 57.17,75.83 v2(56.38,75.83) ; U20.D31 44.5,85.73 44.74,85.73 U20.D30 U20.F30 v2(45.03,83.9) ; EC4.2 100.95,100.83 100.58,101.2 100.07,101.2 ; U20.AL51 31.73,70.47 v2(31.66,70.47) 31.56,70.47 U20.AM52 ; v2(47.44,83.89) 47.54,83.99 U20.F26 U20.D26 47.78,85.44 U20.D25 ; C118.1 v2(237,94.75) ; U20.D27 U20.C27 46.6,86.41 46.41,86.23 v2(46.09,86.23) 46.06,86.23 U20.D29 ; CN7.10 9.69,85.15 10.15,84.69 v2(10.15,84.43) 10.15,84.21 9.6,83.65 CN7.13 ; v2(56.08,74.78) 56.13,74.73 56.13,74.11 56.76,73.48 U20.AF11 56.76,73.33 U20.AG11 55.94,73.33 U20.AF12 55.94,73.44 55.49,73.89 v2(55.49,75.16) ; C9.2 v2(218.81,114.03) ; v2(69,24.69) 68.62,24.69 68.47,24.84 C338.2 C324.2 ; v2(22.22,71.01) 21.65,71.01 21.61,71.05 v2(21.58,71.05) 21.58,71.1 21.19,71.49 21.19,71.61 R362.1 21.06,71.7 20.96,71.8 20.79,71.8 20.64,71.95 20.64,71.99 20.59,72.04 R361.1
  BOTTOM w0.279: U11.3 18.93,97.02 v2(19.17,97.26) ; U15.18 102.09,82.67 101.82,82.94 v2(101.06,82.94) ; v2(97.66,86.66) 97.54,86.77 U15.4 ; U15.8 v2(100.14,86.67) ; Q16.1 193.81,89.63 193.57,89.87 192.8,89.87 192.51,90.16 Q16.4 192.51,92.04 192.88,92.41 v2(193.41,92.41)
  BOTTOM w0.305: v2(60.46,74.25) 60.46,74.04 U20.AE5 ; v2(59.05,76.14) 59.05,75.84 U20.AB7 ; U20.J10 57.3,82.49 v2(56.89,82.91) ; U20.AY59 26.73,64.57 v2(26.89,64.41) 27.61,64.41 28.05,64.85 U20.AY57 ; U20.AY30 44.71,64.88 v2(44.72,64.88) ; U20.AR23 49.56,68.47 49.73,68.47 50.11,68.85 U20.AP22 ; v2(238.75,110.17) 238.37,109.78 U5.47 ; v2(61.23,68.13) 61.24,68.14 61.26,68.14 61.51,68.4 U20.AP3 ; v2(188.71,81.39) 188.97,81.39 189.42,81.84 CN8.13 ; v2(246.7,101.81) U5.18 246.7,99.36 C67.1 ; v2(47.06,64.62) 47.11,64.62 47.15,64.66 U20.AY26 ; U20.R10 56.63,78.77 v2(56.63,78.67) ; CN8.21 190.32,85.38 190.87,85.93 v2(190.87,86.06) 191.43,86.06 192.12,85.37 CN8.24 ; U20.AN23 49.14,69.35 49.14,68.99 U20.AP23 49.29,68.85 ; U20.AH20 51.17,72.24 50.78,71.85 v2(50.61,71.85) 50.61,72.35 U20.AG21 ; U20.AR11 56.26,68.34 v2(56.2,68.34) ; CN8.10 191.22,81.52 v2(191.36,81.39) ; CN11.8 263.93,74.75 263.62,75.06 v2(263.62,75.19) ; U5.31 v2(240.2,101.83) ; v2(30.57,64.15) 30.57,65.33 U20.AY53 ; v2(201.77,88.35) 201.86,88.44 C185.1 ; U5.63 v2(246.7,111.26) ; U20.AP10 57.48,69.31 v2(57.55,69.31) ; v2(49.85,64.39) 49.87,64.42 49.87,65.39 U20.AY22 ; U20.N21 51.13,80.27 v2(50.74,79.89) 50.74,79.88 U20.P22 U20.M22 ; U20.AY18 v2(52.28,64.5) ; v2(23.56,82.9) 23.68,82.78 U20.J63 ; v2(56.4,76.85) 56.63,76.61 U20.Y10 ; v2(193.36,81.39) 193.16,81.39 193.02,81.53 CN8.7 ; v2(42.36,65.41) 42.29,65.41 U20.AW35 ; 23.74,72.27 22.48,71.01 v2(22.22,71.01) ; U5.12 v2(248.18,104.78) ; U20.B32 U20.A32 43.78,87.8 v2(43.55,88.02) ; v2(59.45,69.96) 59.39,69.96 U20.AN7 ; U20.AH17 52.86,72.48 52.53,72.48 U20.AH19 51.98,71.93 51.77,71.93 v2(51.58,71.73) ; U20.AN63 24.34,69.5 23.49,69.5 v2(23.44,69.45) 22.83,70.06 22.42,70.06 21.61,70.87 21.61,71.02 v2(21.58,71.05) ; v2(50.77,77.44) U20.W22 ; U20.AY6 59.44,64.32 59.45,64.3 59.45,64.22 59.58,64.09 v2(59.58,64.06)
  BOTTOM w0.356: JDIM1.8 7.55,28.21 7.1,27.77 v2(6.32,27.77) 6.11,27.77 5.75,28.13 JDIM1.2 ; JDIM1.195 66.05,38.54 v2(65.73,38.87) ; v2(64.55,27.7) JDIM1.190 ; JDIM1.44 18.35,28.07 18.03,27.74 16.63,27.74 v2(16.58,27.79) 16.55,27.82 JDIM1.38 ; v2(62.22,27.69) 62.43,27.69 62.75,28.02 JDIM1.184 ; JDIM1.162 v2(56.15,27.74) ; JDIM1.136 48.35,31.48 48.14,31.69 v2(47.71,31.69) ; v2(15.68,31.43) 15.2,31.43 14.75,30.98 JDIM1.32 ; v2(50.31,27.74) 50.75,28.18 JDIM1.144 ; JDIM1.66 v2(24.95,30.71) ; v2(20.29,31.36) 19.8,31.36 19.55,31.11 JDIM1.48 ; JDIM1.156 54.35,28.07 54.53,27.89 v2(54.53,27.72) ; JDIM1.168 57.95,28.17 57.78,28 v2(57.78,27.74) ; JDIM1.60 23.15,27.96 22.98,27.79 v2(22.98,27.77) ; JDIM1.178 60.95,28.1 61.36,27.69 v2(61.46,27.69) ; JDIM1.26 12.95,28.18 12.67,27.89 v2(12.67,27.77) ; v2(52.47,27.74) 52.47,27.84 52.55,27.93 JDIM1.150 ; v2(25.42,27.77) 26.38,27.77 26.75,28.14 JDIM1.72 ; v2(21.46,27.77) 21.46,28.02 21.35,28.13 JDIM1.54 ; v2(12.55,31.48) 13.55,30.48 JDIM1.28 ; v2(45.2,31.6) 45.25,31.6 45.95,30.91 JDIM1.128 ; v2(17.73,31.48) 18.38,31.48 18.95,30.91 JDIM1.46 ; JDIM1.20 11.15,27.9 10.91,27.67 v2(10.41,27.67) 10.15,27.92 9.66,27.92 9.35,28.22 JDIM1.14 ; JDIM1.134 47.75,28.13 47.46,27.84 47.19,27.84 v2(47.08,27.74) ; v2(60.32,27.69) 60.22,27.79 59.48,27.79 59.15,28.12 JDIM1.172 ; JDIM1.196 66.35,28.16 v2(65.88,27.69) ; JDIM1.138 48.95,27.76 v2(49.01,27.69)
  BOTTOM w0.381: C27.2 v2(264.2,109.61) ; v2(219.96,108.41) 219.83,108.54 PC43.1 ; C98.2 87.61,95.96 v2(87.57,95.92) ; C12.2 v2(225.42,110.37) ; R17.2 223.97,114.64 v2(223.61,114.99) ; 214.11,111.82 216.6,111.82 216.81,111.61 R29.2 ; 214.11,111.82 214.14,111.79 v2(214.14,110.85) 214.95,110.04 C24.2 ; 214.11,111.82 210.92,111.82 R26.2 ; v2(252.19,112.53) 252.11,112.45 R20.1 ; U21.5 77.88,56.07 77.11,56.85 77.11,57.1 76.83,57.38 76.34,57.38 76.32,57.41 76.32,57.4 v2(76.31,57.4) ; R470.1 40.63,23.14 v2(40.3,23.47) ; R395.2 16.63,63.83 v2(16.63,60.61) ; C36.1 v2(251.74,106.65) ; v2(69.92,63.56) 69.84,63.63 C281.2 ; JDIM1.170 58.55,30.34 58.92,30.71 58.92,31.24 v2(59.5,31.82) ; v2(79.65,117.35) 79.65,117.18 PR9.2 ; C44.2 261.27,103.16 260.88,102.77 260.52,102.77 v2(260.47,102.72) ; U9.4 77.79,98 77.36,97.57 v2(77.36,96.75) ; v2(205.2,111.13) 205.2,111.05 205.51,110.74 C14.1 ; v2(250.36,109.38) 250.57,109.59 C25.1 ; v2(199.79,92.54) 199.79,92.99 199.59,93.2 C133.2 ; C87.2 v2(257.34,96.65) ; CN3.3 188.49,105.26 188.92,104.83 v2(189.55,104.83) ; PC89.2 165.97,101.97 166.75,101.19 PR87.2 ; C191.1 201.44,87.18 201.77,87.51 v2(201.77,88.35) ; C28.1 v2(205.81,107.6)
  BOTTOM w0.406: v2(94.01,89.58) 93.98,89.58 93.95,89.54 93.62,89.54 93.32,89.25 U13.5 ; v2(50,93.76) 49.91,93.67 C137.2 ; v2(47.19,93.76) 46.97,93.54 C138.2
  BOTTOM w0.457: CN5.43 264.05,104.83 v2(263.95,104.73) ; C251.1 103.76,78.63 103.5,78.9 v2(103.5,79.23) ; v2(165.9,95.22) 165.9,95.24 166.16,95.5 166.16,95.99 165.76,96.39 165.63,96.39 PC113.2
  BOTTOM w0.508: CN5.21 264.32,96.03 v2(263.95,96.4) ; CN6.41 243,84.49 243.07,84.56 v2(243.32,84.56) ; v2(22.27,15.85) 22.22,15.8 C346.2 ; PC136.2 171.56,87.62 v2(171.95,87.23) ; Q26.1 70.22,19.44 70.22,19.66 v2(70.73,20.17) ; v2(121.18,102.83) 121.28,102.72 C45.1 ; PC94.2 86.07,100.78 v2(86.07,100.06) ; v2(259.83,106.02) 259.94,105.92 Q6.1 ; v2(145.15,102.34) 146.03,101.46 PC95.2 ; v2(267.91,112.68) 267.56,113.04 C366.2 ; PR47.1 124.73,105.42 v2(124.73,104.93) ; C259.2 16.55,77.4 16.55,76.58 v2(16.3,76.33) ; v2(89.02,114.79) 89.02,115.17 89.39,115.54 PC7.2 ; PC23.1 v2(105.28,112.76) ; PR127.1 PR128.1 10.05,16.63 v2(10.05,16.44) ; v2(199.89,85.83) 199.89,85.71 199.28,85.1 C215.2 ; v2(56.68,111.56) 56.68,110.66 56.9,110.44 PC39.2 ; CN9.10 164.17,81.22 163.57,80.62 v2(163.49,80.62) ; PU2.2 125.93,112.2 v2(125.95,112.22) ; R231.2 R232.2 218.7,87.36 v2(218.44,87.11) ; CN7.24 5.05,81.87 5.45,82.28 v2(5.45,82.78) ; PC142.2 17.82,22.12 17.82,22.62 17.35,23.09 v2(17.11,23.09) ; CN14.29 v2(18.6,11.41) 18.15,11.41 17.8,11.06 CN14.27 ; PC151.2 14.22,16.49 13.84,16.11 v2(13.84,15.73) ; C273.2 v2(198.52,74.73) ; C236.2 225.68,81.22 v2(226.13,81.67) ; R461.2 48.12,27.45 v2(48.12,27.7) ; EC14.1 EC13.1 v2(80.04,45.32) ; C163.2 23.49,91.3 22.73,92.05 v2(22.73,92.05) ; PC24.1 v2(101.72,112.76) ; PR62.2 v2(147.64,104.25) PC73.1 ; CN9.11 152.99,81.22 v2(153.03,81.26) ; v2(15.71,11.49) 15.4,11.17 CN14.21 ; EC10.1 101.22,79.26 v2(101.19,79.23) ; C94.1 10.64,97.26 v2(10.28,97.26) ; FAN1.3 v2(79,22.98) ; v2(3.14,14.31) 4.31,14.31 C357.2 ; v2(55.19,90.02) 55.19,91.1 R172.2 ; PR81.2 135.37,100.51 v2(135.58,100.31) ; C40.1 189.21,104.49 v2(189.55,104.83) 190.44,104.83 190.89,105.28 CN3.6 ; C206.2 201.41,85.44 v2(201.16,85.2) ; CN6.45 263.58,86.4 v2(263.77,86.59) ; v2(171.06,93.09) 171.06,93.82 PC122.1 ; PC114.2 97.32,95.5 v2(97.53,95.71) ; PC84.1 102.02,102.49 102.15,102.37 v2(102.73,102.37) ; PC152.1 25.27,12.27 v2(25.39,12.15) ; v2(73.8,83.22) 73.63,83.04 U17.2 ; v2(73.58,89.18) 73.58,90.47 ; 73.58,90.47 C177.1 ; 73.58,90.47 72.92,89.81 v2(72.92,89.39) ; v2(79.9,47.48) 79.9,47.78 79.23,48.45 C297.2 ; C69.2 258.97,99.98 v2(259.25,99.7) ; PR28.2 41.15,111.24 v2(40.76,110.85) ; C249.1 v2(71.61,77.84) ; v2(20.69,93.45) 19.8,92.56 C154.1 ; v2(131.7,107.55) PC59.1 ; PR87.2 166.75,100.57 v2(166.62,100.44) ; R394.2 v2(18.02,61.95) ; PC139.2 13.34,25.13 v2(13.71,25.51) ; CN6.42 248.85,84.49 v2(248.79,84.56) ; PC112.1 v2(91.31,95.79) 91.38,95.71 91.38,95.51 91.57,95.32 C115.2 ; C54.1 3.09,101.4 v2(2.68,101.81) ; PC44.2 v2(133.47,107.29) PR44.2 ; C339.2 69.84,23.98 v2(68.95,23.98) ; PC18.1 59.56,113.47 v2(59.56,113.9) ; v2(104.36,102.37) 104.36,102.7 104.08,102.98 PR67.2 ; PR33.2 135.89,108.81 136.82,107.88 PQ4.1 136.11,107.14 135.88,106.91 v2(135.88,106.53) ; PC120.2 165.41,93.82 164.64,94.59 PC118.2 v2(163.81,94.59) ; U8.2 13.25,99.09 v2(13.71,99.55) ; v2(126.08,104.93) 126.18,105.03 PC68.2 126.81,104.07 126.75,104 C43.1 ; 161.66,87.61 158.11,87.61 157.61,88.11 PC133.2 ; CN13.6 v2(57.6,22.76) ; v2(7,99.14) 6.77,98.91 C75.2 ; v2(48.25,97.26) 49.05,96.46 Y2.4 ; v2(132.5,100.56) 132.45,100.51 132.45,99.94 PR94.1 ; Q2.1 v2(261.05,112.2) ; v2(54.48,96.17) 54.48,96.58 55.39,97.49 PC107.2 ; CN7.22 5.79,77.75 5.33,78.21 v2(4.95,78.21) ; C109.1 16.63,96.55 v2(17.57,97.49) ; R439.1 72.53,56 v2(72.51,56) 72.03,56.49 R440.1 ; PC29.1 123.25,111.24 v2(122.5,111.99) ; C280.2 13.45,63.78 v2(13.45,63.23) ; Q25.1 67.51,23.68 v2(67.33,23.86) ; 100.07,101.2 98.67,101.2 98.62,101.15 v2(97.91,101.15) ; R234.2 216.85,87.36 v2(217.23,86.99) 217.6,87.36 R233.2 ; v2(282.32,75.9) 282.58,75.65 CN10.3 ; v2(5.53,95.69) 4.79,95.69 C110.1 ; CN5.9 264.32,88.03 263.9,88.45 v2(263.9,88.6) ; v2(147.95,110.55) 147.95,110.98 148.2,111.23 PC26.1 ; C319.2 71.37,25.13 v2(70.99,24.74) ; PC98.2 96.41,100.95 96.39,100.97 v2(96.31,100.97) ; C355.2 26.79,13.54 v2(26.79,12.15) ; v2(168.27,89.64) PC131.1 ; CN5.37 263.98,102.43 v2(263.9,102.34) ; PC90.2 53.97,102.39 v2(54.63,103.05) ; v2(8.17,17.84) 8.17,18.55 PC147.2 ; PC45.2 131.67,108.39 v2(131.67,109.05) ; v2(266.31,91.67) 265.93,91.67 265.02,90.76 CN5.15 ; v2(5.5,96.35) 5.26,96.6 C86.2 ; Q11.1 71.09,101.61 71.44,101.96 v2(71.44,104.15) ; PC104.2 PC105.2 53.21,97.52 53.38,97.34 v2(53.38,97.31) ; PC115.2 173.86,94.26 PC121.2 174.09,93.6 v2(174.49,93.6) ; v2(7.4,11.48) CN14.9 ; CN5.27 v2(263.95,98.43) 263.95,98.86 264.31,99.23 CN5.29 ; PR11.1 56.63,116.18 v2(56.76,116.31) ; C11.2 264.18,112.35 v2(264.28,112.25) ; PC5.1 77.95,117.21 v2(78.22,117.48) ; v2(174.06,87.23) 174.11,87.23 174.5,87.62 PC135.2 ; PC101.2 114.22,100.06 114.62,100.46 v2(114.62,100.51) ; 82.67,60.43 82.55,60.55 R72.1 ; C104.1 6.94,96.37 v2(6.6,96.37) ; PC80.2 100.07,102.6 100.2,102.47 v2(100.2,102.37) ; C88.1 v2(6.47,97.21) ; PR91.1 112.64,99.37 v2(112.82,99.55) ; PR108.2 167.88,93.57 v2(167.38,93.07) ; CN13.9 v2(54.6,22.97) ; v2(259.2,83.29) 259.4,83.49 CN6.43 ; C214.2 200.53,85.36 v2(200.53,85.83) ; CN14.15 9.8,11.21 9.77,11.24 v2(9.77,11.49) ; v2(4.72,95) 4.52,95 C121.2 ; C314.2 49.18,26.91 49.65,27.39 v2(49.65,27.69) ; CN7.21 v2(7,91.04) ; R71.1 v2(16.6,105.52) ; v2(200.55,102.8) 200.35,102.6 Q9.1 ; CN14.43 24.2,11.16 v2(24.55,11.51) ; PC137.2 14.47,26.27 v2(14.6,26.4) ; C296.1 76.2,50.79 v2(75.43,50.02) ; CN6.44 239.19,86.4 239.39,86.59 v2(239.39,87.15) ; Q3.1 v2(256.25,111.33) ; v2(151.38,93.71) 151,93.32 PR112.1 ; CN10.1 v2(282.31,77.65) ; v2(9.01,23.98) 9.01,24.24 9.49,24.72 PC141.2 10.13,24.24 PC140.1 ; R465.2 53.64,25.93 v2(53.64,25.38) ; v2(20.07,62.75) 20.07,63.84 R393.2 ; C221.2 207.54,84.96 v2(207.64,85.07) ; PC17.1 73.96,113.9 73.75,114.1 v2(73.75,114.66) ; PR23.2 v2(104.13,112.76) ; v2(66.51,99.42) 66.51,100 PC100.1 ; v2(138.04,94.98) 137.78,95.24 PC116.2 ; v2(131.79,95.92) 132.45,95.92 133.75,97.21 PQ8.1 ; PQ9.1 188.49,99.01 187.72,99.78 v2(187.72,100.51) 187.72,102.14 186.68,103.18 C42.2 ; v2(151.12,103.18) 150.95,103.35 PC79.1 ; PC125.2 137.46,91.08 v2(137.46,90.43) 136.64,90.43 PC126.2 ; v2(60.6,22.97) 60.6,23.73 60.6,23.73 CN13.3 ; v2(105.05,99.55) 105.05,99.83 105.81,100.59 PC96.1 PC91.2 105.81,102.55 105.64,102.72 105.64,103.53 106.26,104.15 PC75.1 ; v2(5.71,15.09) C356.2 ; v2(110.61,85.2) 110.61,85.73 109.87,86.47 C202.2 ; v2(18.93,76.31) 19.68,77.06 C258.2 R306.2 ; PC87.1 PC88.2 170.82,102.64 170.4,103.05 170.3,103.05 v2(170.27,103.08) ; v2(153.41,110.46) PC28.1 ; U6.2 257.4,102.37 v2(257.29,102.47) ; C219.2 v2(13.95,84.89) ; C218.2 223.99,84.71 224.22,84.94 v2(224.22,85.31) ; PC97.2 155.95,100.17 v2(155.56,100.56) ; v2(76.83,67.77) 75.67,67.77 R380.2 ; v2(45.97,95.1) 46.31,94.76 Y2.2 ; PR27.2 144.13,110.86 144.47,110.52 144.47,109.78 v2(144.49,109.76) ; CN10.2 v2(282.36,76.65) ; C320.2 51.1,26.52 v2(51.1,27.72) ; v2(263.9,101.63) CN5.35 ; v2(227.04,109.43) 227.65,109.43 CN4.2 228.59,110.37 C8.2 ; v2(10.79,71.86) 10.79,71.56 9.63,70.4 CN12.4 ; v2(6.09,90.4) 5.05,89.37 CN7.23 ; PD8.2 PD7.2 175.25,93.17 175.13,93.29 v2(175.13,93.6) ; C51.2 193.6,103.88 193.22,104.26 v2(192.85,104.26) 192.71,104.12 C39.1 ; v2(21.1,81.51) 20.7,81.51 C235.1 ; v2(44.82,24.92) 44.82,25.51 44.77,25.56 C337.2 ; C205.1 v2(13.79,87.15) ; PC77.1 98.54,104.91 98.65,105.01 98.65,105.19 v2(98.67,105.21) ; PC6.2 v2(74.16,117.91) ; C203.2 105.91,85.71 v2(105.91,85.07) ; CN14.35 21,11.34 21.18,11.51 v2(21.89,11.51) 21.89,11.24 21.8,11.15 CN14.37
  vias: v1(2.53,19.28) v1(3.04,106.41) v1(12.31,110.72) v1(13.58,22.59) v1(48.89,95.1) v1(72.99,18.55) v1(81.32,23.17) v1(105.66,116.69) v1(108.58,85.07) v1(218,80.96) v1(235.96,77.45) v1(238.63,118.85) v1(246.5,114.66) v1(261.36,74.4) v1(285.36,73.26) v1(286.38,78.47) v2(0.78,103.23) v2(0.77,101.07) v2(0.77,97.26) v2(0.77,93.45) v2(0.77,89.64) v2(0.77,85.83) v2(0.77,82.02) v2(0.77,78.21) v2(0.77,74.4) v2(0.77,70.59) v2(0.77,66.78) v2(0.77,62.97) v2(0.77,59.16) v2(0.77,55.35) v2(0.77,51.54) v2(0.77,47.73) v2(0.77,43.92) v2(0.77,40.11) v2(0.77,36.3) v2(0.77,32.49) v2(0.77,28.68) v2(0.78,17.3) v2(0.78,13.57) v2(0.78,9.76) v2(0.88,4.17) v2(1.14,6.46) v2(4.56,7.57) v2(5.71,38.84) v2(6.47,31.53) v2(7.51,35.03) v2(7.71,30.72) v2(8.37,7.57) v2(9.46,34.4) v2(9.74,31.56) v2(9.8,40.83) v2(9.8,40.07) v2(9.8,39.31) v2(11.72,34.16) v2(11.93,90.76) v2(12.18,7.57) v2(12.57,89.01) v2(12.57,87.48) v2(12.82,21.7) v2(12.82,20.68) v2(13.28,35.42) v2(13.38,14.51) v2(13.45,113.24) v2(13.5,11.46) v2(13.71,20.81) v2(13.84,21.7) v2(13.91,89.87) v2(14.6,23.25) v2(14.6,22.61) v2(14.72,43.31) v2(14.72,41.48) v2(15.68,34.18) v2(15.84,26.4) v2(15.94,15.73) v2(15.99,7.57) v2(16.48,26.4) v2(17.11,26.4) v2(17.26,113.24) v2(17.73,35.07) v2(18.25,25.33) v2(18.25,24.69) v2(19.37,25.38) v2(19.37,24.74) v2(19.37,24.11) v2(19.67,33.31) v2(19.8,7.57) v2(20.19,102.37) v2(20.19,101.73) v2(20.19,101.1) v2(20.19,99.8) v2(20.19,99.17) v2(20.19,98.53) v2(20.44,107.8) v2(20.44,107.17) v2(20.44,106.53) v2(20.44,105.9) v2(20.49,25.38) v2(20.49,24.74) v2(20.49,24.11) v2(21.07,113.24) v2(21.64,34.41) v2(21.61,15.85) v2(21.84,25.48) v2(22.4,31.41) v2(22.75,25.48) v2(23.28,34.6) v2(23.61,7.57) v2(23.98,40.75) v2(23.98,40.11) v2(23.98,39.48) v2(23.98,38.84) v2(24.5,101.58) v2(24.5,100.94) v2(24.5,96.7) v2(24.88,113.24) v2(24.89,32.14) v2(25.39,90.58) v2(25.75,34.28) v2(26.03,90.58) v2(26.45,31.74) v2(27.42,7.57) v2(27.95,90.08) v2(28.69,113.24) v2(28.94,33.03) v2(29.3,34.4) v2(29.84,90.66) v2(30.35,6.99) v2(30.55,101.53) v2(30.6,94.91) v2(30.73,97.07) v2(30.98,31.72) v2(31.18,101.53) v2(31.23,94.91) v2(31.23,8.87) v2(31.23,5.06) v2(31.23,3.66) v2(31.36,97.07) v2(31.54,11.79) v2(31.62,91.62) v2(31.62,90.99) v2(31.82,101.53) v2(31.87,94.91) v2(31.98,34.83) v2(32.5,113.24) v2(32.45,101.53) v2(32.58,31.72) v2(32.92,63.35) v2(33.95,33.1) v2(34.54,89.77) v2(34.51,64.1) v2(34.54,13.26) v2(34.97,35.03) v2(35.84,31.89) v2(36.31,113.24) v2(36.47,33.41) v2(36.7,24.36) v2(37.2,97.07) v2(37.33,24.36) v2(37.63,99.23) v2(37.56,32.9) v2(37.84,97.07) v2(37.97,24.36) v2(38.19,101.63) v2(38.27,99.23) v2(38.3,31.55) v2(38.35,13.26) v2(38.42,16.26) v2(38.47,97.07) v2(38.73,92.82) v2(38.73,92.18) v2(38.73,91.55) v2(38.8,102.21) v2(38.83,101.58) v2(38.9,99.22) v2(39.14,35.99) v2(39.11,33.25) v2(39.06,16.26) v2(39.69,16.26) v2(39.95,103.99) v2(39.95,92.69) v2(40.12,113.24) v2(41.5,31.91) v2(41.84,101.97) v2(42.16,13.26) v2(42.97,35.24) v2(42.97,33.81) v2(43.93,113.24) v2(44.19,96.45) v2(44.19,95.81) v2(44.19,94.54) v2(44.19,93.91) v2(45.97,13.26) v2(46.22,34.9) v2(46.63,100.84) v2(46.88,40.39) v2(46.88,39.71) v2(46.88,39.05) v2(47.31,100.84) v2(47.74,113.24) v2(47.95,100.84) v2(48.04,33.61) v2(48.61,100.84) v2(49.27,31.69) v2(49.78,13.26) v2(50.01,35.04) v2(51.49,31.69) v2(51.55,113.24) v2(52.08,35.26) v2(53.15,40.55) v2(53.15,39.89) v2(53.15,39.23) v2(53.59,13.26) v2(53.74,115.55) v2(53.76,118.09) v2(54.09,94.7) v2(54.09,92.61) v2(54.25,31.73) v2(54.92,35.07) v2(55.24,119.74) v2(55.98,31.81) v2(56.48,41.01) v2(56.48,40.25) v2(56.48,39.61) v2(57.04,20.25) v2(57.4,13.26) v2(57.95,34.86) v2(58.29,31.84) v2(58.92,20.22) v2(59.05,119.74) v2(59.5,33.59) v2(59.68,90.53) v2(59.81,92.23) v2(59.94,91.12) v2(60.29,40.63) v2(60.29,39.86) v2(60.29,39.1) v2(60.83,20.55) v2(61.21,13.26) v2(61.92,34.87) v2(61.97,41.38) v2(61.97,40.63) v2(61.97,39.86) v2(61.97,39.1) v2(61.97,31.76) v2(62.15,101.02) v2(62.78,101.02) v2(62.86,119.74) v2(63.42,101.02) v2(63.74,35.19) v2(63.92,39.81) v2(63.92,39.05) v2(64.07,33.03) v2(65.02,13.26) v2(65.81,34.61) v2(66.31,32.73) v2(66.67,119.74) v2(67.43,101.43) v2(67.89,101.88) v2(68.83,13.26) v2(68.9,31.81) v2(69.74,66.22) v2(69.74,65.59) v2(70.48,119.74) v2(70.73,21.44) v2(70.73,20.81) v2(71.75,13.26) v2(74.29,119.74) v2(74.54,43.29) v2(75.02,44.35) v2(76.85,60.74) v2(78.1,119.74) v2(78.35,42.07) v2(78.66,44.96) v2(81.91,119.74) v2(82.73,65.38) v2(82.73,61.57) v2(82.73,57.76) v2(82.73,53.95) v2(82.73,50.14) v2(82.73,46.33) v2(82.73,42.52) v2(82.73,38.71) v2(82.73,34.9) v2(82.73,31.09) v2(82.73,27.28) v2(82.72,22.84) v2(83.15,68.43) v2(84.55,71.35) v2(85.72,119.74) v2(87.06,73.89) v2(89.53,119.74) v2(90.42,75.47) v2(93.34,119.74) v2(93.59,75.8) v2(95.83,102.34) v2(96.46,102.34) v2(97.15,119.74) v2(97.4,75.8) v2(101.21,75.8) v2(105.02,75.8) v2(107.51,114.79) v2(107.89,84.18) v2(108.53,84.18) v2(108.83,75.8) v2(109.72,102.71) v2(109.75,102.08) v2(109.85,113.24) v2(110.69,102.71) v2(110.69,102.08) v2(112.64,75.8) v2(113.66,113.21) v2(116.45,75.8) v2(116.55,114.15) v2(119.12,114.74) v2(120.26,75.8) v2(122.93,114.74) v2(124.07,75.8) v2(126.74,114.74) v2(127.88,75.8) v2(130.55,114.74) v2(131.69,75.8) v2(134.36,114.74) v2(135.5,75.8) v2(138.17,114.74) v2(139.31,75.8) v2(141.98,114.74) v2(143.12,75.8) v2(145.79,114.74) v2(146.93,75.8) v2(149.6,114.74) v2(150.74,75.77) v2(152.39,73.23) v2(153.41,114.74) v2(157.22,114.74) v2(161.03,114.74) v2(164.51,113.72) v2(165.32,72.86) v2(168.27,83.85) v2(169.13,72.86) v2(172.94,72.86) v2(175.53,113.42) v2(176.75,72.86) v2(180,113.39) v2(180.56,72.86) v2(183.96,113.39) v2(184.37,72.86) v2(187.65,113.42) v2(188.18,72.86) v2(189.55,90.78) v2(190.16,91.01) v2(191.48,113.39) v2(191.99,72.86) v2(195.22,113.39) v2(195.8,72.88) v2(198.85,72.88) v2(199.05,113.42) v2(202.81,113.42) v2(203.42,72.88) v2(203.98,88.64) v2(206.7,113.42) v2(207.23,72.88) v2(210.38,113.42) v2(210.69,85.22) v2(211.04,72.88) v2(211.19,84.84) v2(214.44,113.42) v2(214.85,72.88) v2(216.02,81.51) v2(216.02,80.12) v2(216.02,78.72) v2(216.6,113.7) v2(217.26,115.8) v2(217.42,80.12) v2(218.69,117.33) v2(218.66,72.88) v2(218.81,81.51) v2(218.81,80.12) v2(218.81,78.72) v2(220.29,119.61) v2(222.5,121.21) v2(222.47,72.88) v2(226.23,72.88) v2(229.28,106.66) v2(230.85,102.49) v2(232.3,114.66) v2(237.23,118.34) v2(237.16,115.73) v2(237.43,72.88) v2(238.75,94.54) v2(239.01,93.96) v2(239.26,71.86) v2(240.5,93.96) v2(242.56,71.63) v2(245.1,77.83) v2(246.25,92.05) v2(246.25,91.42) v2(246.37,71.63) v2(248.02,96.75) v2(248.02,95.23) v2(248.12,115.55) v2(249.55,96.75) v2(249.55,95.23) v2(250.18,71.63) v2(250.44,114.23) v2(253.99,71.63) v2(254.25,114.23) v2(255.06,97.01) v2(256.94,91.12) v2(257.8,71.63) v2(258.06,114.23) v2(259.88,90.51) v2(261.61,71.63) v2(261.87,114.23) v2(265.42,71.63) v2(265.68,114.23) v2(266.18,75.47) v2(267.84,108.72) v2(267.84,104.91) v2(267.84,101.1) v2(267.84,97.29) v2(267.84,93.48) v2(267.84,89.67) v2(267.84,85.86) v2(268.09,82.56) v2(269.23,111.13) v2(269.23,71.63) v2(269.49,114.23) v2(273.04,71.63) v2(273.17,114.03) v2(273.73,111.89) v2(274.46,81.26) v2(276.85,80.37) v2(276.85,71.63) v2(280.66,80.37) v2(280.66,71.63) v2(284.47,80.37) v2(284.47,71.63) v2(288.26,80.24) v2(288.28,71.76) v2(288.92,77.2) v2(288.92,73.39) v4(13.71,40.11) v4(14.6,111.23) v4(20.06,110.34) v4(20.31,22.84) v4(39.49,15.47) v4(51.55,109.83) v4(62.98,100.06) v4(71.62,21.82) v4(84.07,109.07) v4(91.31,117.58) v4(112.26,106.79) v4(146.68,94.98) v4(165.09,88.63) v4(180.08,79.23) v4(180.46,110.47) v4(238.5,75.16) v4(240.15,95.1) v5(42.38,110.24) v5(42.66,108.67) v5(42.77,110.88) v5(43.15,110.24) v5(43.43,108.68) v5(43.53,110.88) v5(43.91,110.24) v5(44.19,108.67) v5(44.29,110.88) v5(44.67,110.24) v5(44.95,108.67) v5(45.05,110.88) v5(45.43,110.24) v5(45.71,108.67) v5(45.81,110.88) v5(46.55,110.88) v5(47.31,110.88) v5(48.07,110.88) v5(48.84,110.88) v5(49.6,110.88) v5(50.26,108.69) v5(50.36,110.88) v5(50.77,107.98) v5(51.02,108.69) v5(51.12,110.88) v5(51.53,107.98) v5(51.78,108.69) v5(51.94,110.88) v5(52.29,107.98) v5(52.54,108.69) v5(52.7,110.88) v5(53.05,107.98) v5(53.28,108.72) v5(58.79,118.12) v5(59.56,118.12) v5(60.32,118.29) v5(60.77,117.68) v5(70.5,117.89) v5(70.5,117.15) v5(79.37,109.96) v5(80.26,109.96) v5(80.38,107.7) v5(81.15,107.7) v5(81.27,109.96) v5(81.86,110.72) v5(81.91,108.08) v5(82.24,109.96) v5(82.67,108.06) v5(82.87,110.72) v5(83.25,109.96) v5(83.43,108.06) v5(83.94,110.72) v5(84.19,108.06) v5(84.45,109.96) v5(84.96,108.06) v5(85.18,110.72) v5(85.69,109.96) v5(86,108.08) v5(86.76,108.08) v5(87.52,108.08) v5(88.28,108.08) v5(92.45,118.85) v5(92.45,118.09) v5(92.45,117.33) v5(96,118.22) v5(96,117.45) v5(96.64,117.84) v5(96.64,116.95) v5(97.27,118.22) v5(97.27,117.45) v5(97.91,117.84) v5(97.91,116.95) v5(104.26,107.17) v5(105.05,107.17) v5(105.38,106.25) v5(106.14,106.25) v5(106.93,106.25) v5(107.66,106.25) v5(108.68,106.13) v5(109.44,106.13) v5(110.23,106.15) v5(110.99,106.15) v5(142.97,109.63) v5(143.71,109.63) v5(143.88,94.85) v5(144.65,94.85) v5(144.95,109.15) v5(145.41,94.85) v5(145.71,109.15) v5(147.19,108.82) v5(147.69,94.85) v5(147.95,108.82) v5(148.46,94.85) v5(148.71,108.82) v5(149.22,94.85) v5(149.98,94.85) v5(161.92,105.52) v5(162.65,105.52) v5(163.11,88.73) v5(163.39,105.52) v5(163.64,88.19) v5(164.18,87.66) v5(165.65,89.34) v5(166.18,88.8) v5(176.52,110.36) v5(177.26,110.34) v5(177.26,109.61) v5(178,110.36) v5(178.73,110.34) v5(180.48,85.66) v5(180.89,103.13) v5(181.03,86.21) v5(181.63,103.13) v5(181.57,86.75) v5(182.12,87.3)
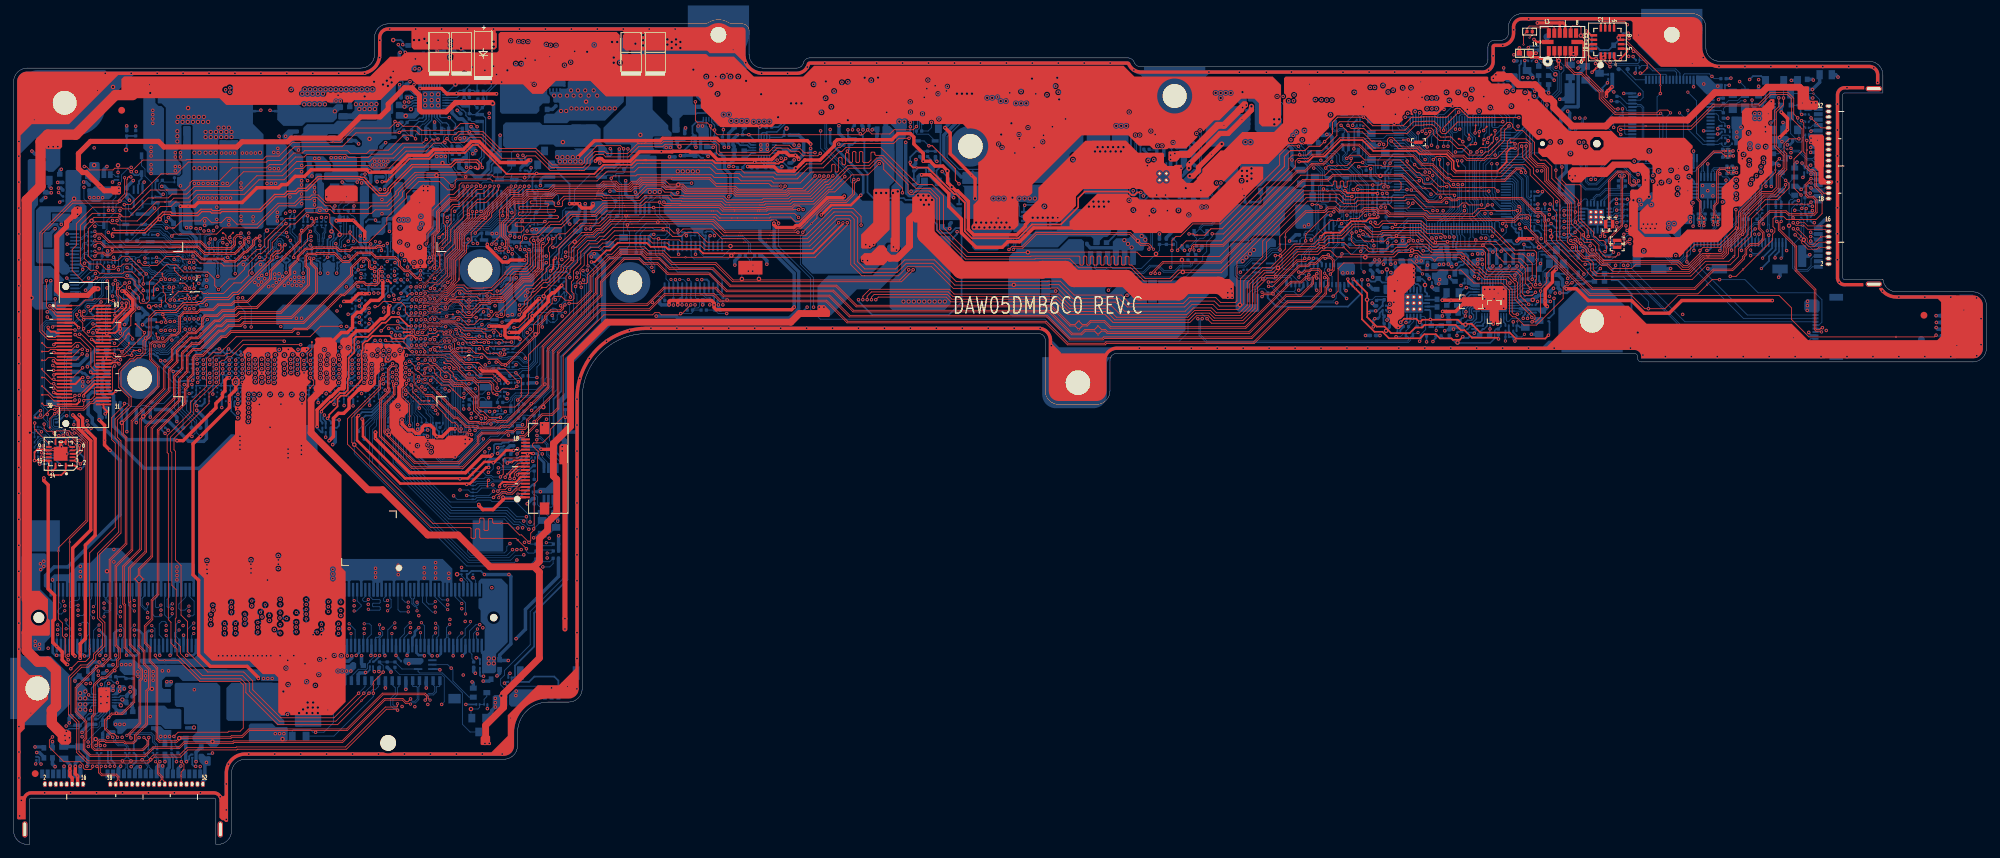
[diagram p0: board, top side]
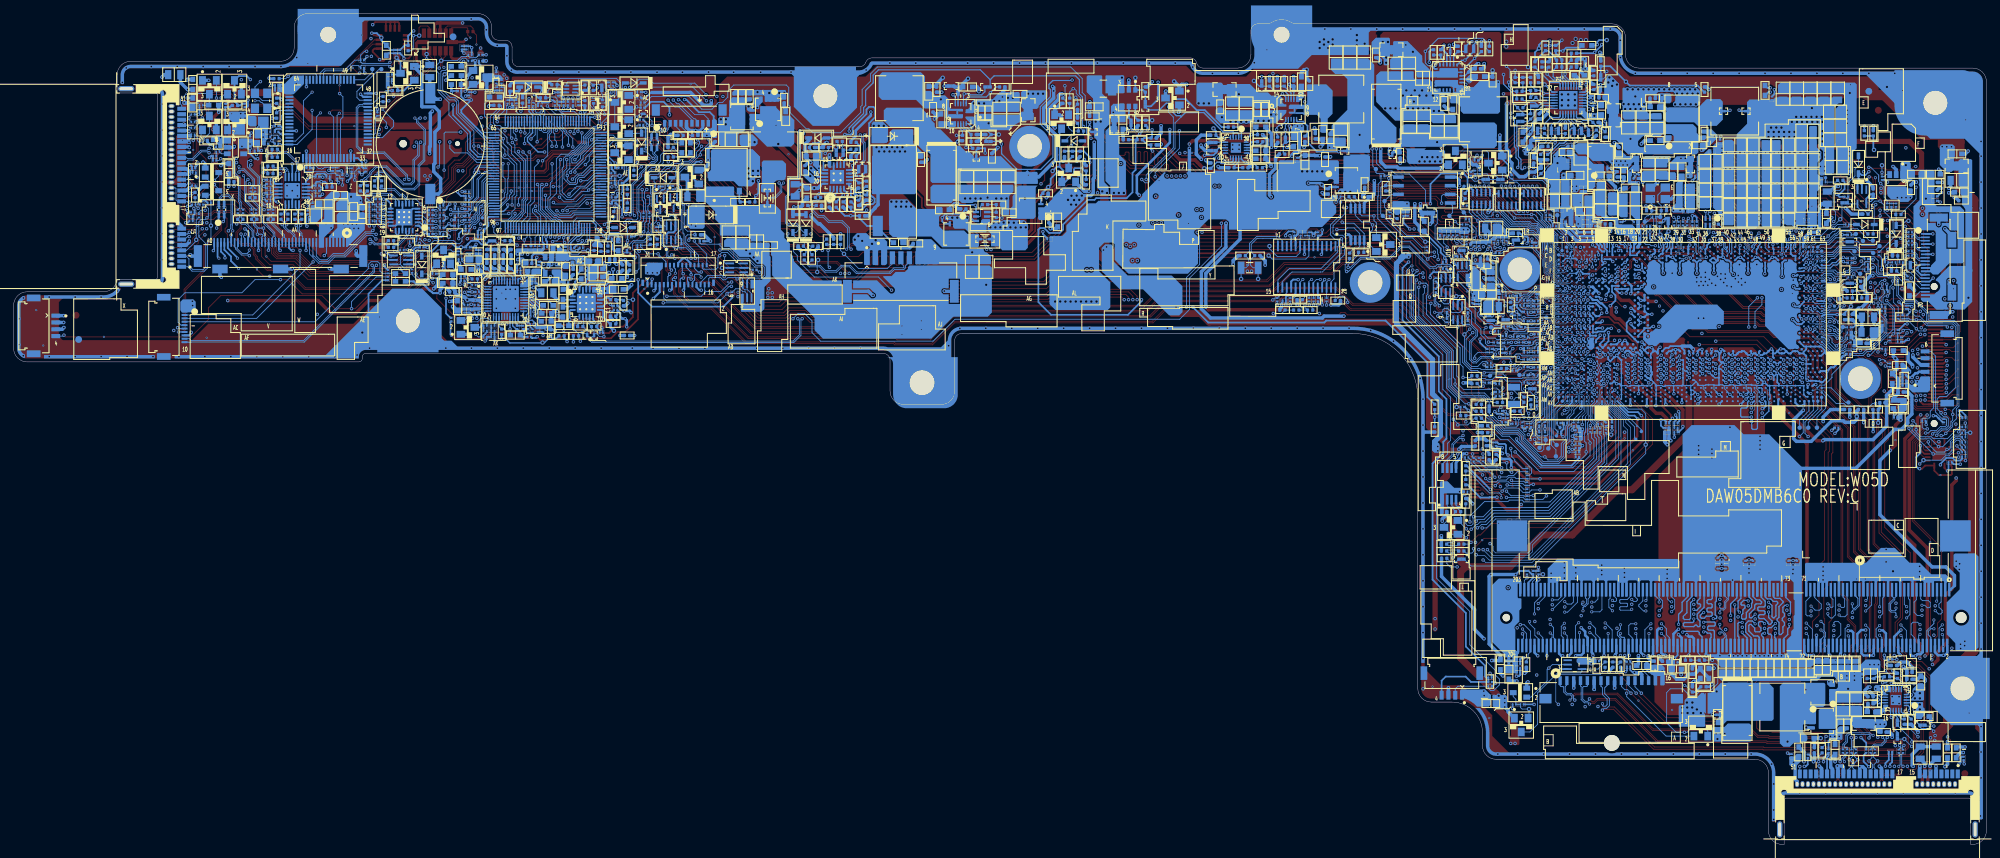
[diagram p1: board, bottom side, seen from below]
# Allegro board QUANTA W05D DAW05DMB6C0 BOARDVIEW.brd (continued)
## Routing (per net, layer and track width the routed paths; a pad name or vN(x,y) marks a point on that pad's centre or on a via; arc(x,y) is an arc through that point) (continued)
VCC_SENSE: length 85.7
  TOP w0.178: v2(14.55,89.31) 14.34,89.51 14.34,89.67 14.48,89.81 19.33,89.81 22.05,92.52 22.92,92.52 23.11,92.33 27.07,92.33 27.65,92.92 28.87,92.92 29.08,92.72 30.37,92.72 30.59,92.93 36.3,92.93 38.47,95.1 39.86,95.1 40.32,95.56 41.49,95.56 41.92,95.99 43.07,95.99 44.81,97.73 50.73,97.73 50.84,97.62 51.31,97.62 51.71,97.22 51.71,97.14 53.59,95.26 54.73,95.26 55.34,95.86 55.34,96.19 58.62,99.47 64.28,99.47 64.99,100.18 67.94,100.18 68.34,99.78 68.34,99.29 68.22,99.17 68.02,99.17 v2(67.79,99.4)
  IN1 w0.203: v3(21,86.21) 21.15,86.06 21.42,86.06 21.63,86.27 21.63,87 21.38,87.25 18.35,87.25 15.79,89.82 14.5,89.82 14.37,89.69 14.37,89.49 v2(14.55,89.31)
  BOTTOM w0.178: R243.1 20.69,86.06 20.85,86.21 v3(21,86.21) 21.15,86.06 21.48,86.06 22.11,85.43 22.62,85.43 23.05,84.99 24.11,84.99 U20.E63 ; PR45.2 68.93,106.05 68.95,106.03 68.95,102.6 68.72,102.36 68.72,100.99 68.34,100.61 68.34,99.19 68.24,99.09 68.1,99.09 v2(67.79,99.4)
VCCRTC_1: length 3.9
  BOTTOM w0.254: v4(233.47,115.52) 232.88,114.94 Q1.3 233.06,113.06 R19.1
VCCRTC_3: length 5.1
  BOTTOM w0.254: Q1.2 232.38,110.7 R30.1 233.31,111.1 v2(234.05,111.84) 234.17,111.96 R21.2
VCCST_PWRGD_XDP: length 17.5
  TOP w0.127: CN1.50 14.36,74.11 14.43,74.19 15.47,74.19 16.12,74.83 16.12,75.14 17.21,76.23 v1(17.21,77.58) 17.21,77.71 17.95,78.44 17.95,80.14 16.55,81.53 16.55,82 17.01,82.45 v2(17.01,82.53)
  IN2 w0.127: v2(15.41,84.38) 15.41,83.85 16.22,83.04 16.76,83.04 17.01,82.78 v2(17.01,82.53)
  BOTTOM w0.127: v2(15.41,84.38) 15.41,86.18 R240.2
VSS_SENSE: length 86.3
  TOP w0.178: v2(68.82,99.41) 68.7,99.53 68.7,99.92 68.08,100.54 66.1,100.54 66.1,100.54 65.81,100.54 64.84,100.54 64.13,99.83 58.47,99.83 58.26,99.62 54.98,96.34 54.98,96.01 54.58,95.61 53.73,95.61 52.06,97.28 52.06,97.36 51.45,97.97 50.99,97.97 50.88,98.09 44.66,98.09 42.92,96.35 41.78,96.35 41.34,95.92 40.17,95.92 39.71,95.45 38.32,95.45 36.15,93.29 30.44,93.29 30.22,93.07 29.22,93.07 29.02,93.27 27.51,93.27 26.92,92.69 23.26,92.69 23.07,92.88 21.9,92.88 19.18,90.16 14.89,90.16 v3(14.7,90.35)
  IN1 w0.203: v3(14.7,90.35) 14.85,90.2 15.94,90.2 18.51,87.64 21.54,87.64 22.01,87.16 22.01,86.11 21.58,85.68 21.1,85.68 v2(21,85.58)
  BOTTOM w0.178: v2(68.82,99.41) 68.7,99.53 68.7,100.46 69.08,100.84 69.08,102.22 69.31,102.45 69.31,106.69 PR41.2 ; R251.1 20.85,85.43 v2(21,85.58) 21.12,85.7 21.33,85.7 21.96,85.07 22.47,85.07 22.9,84.64 24.44,84.64 U20.E62
1237BSTPCH: length 0.5
  BOTTOM w0.203: PU1.20 76.68,112.38 76.67,112.37
  vias: v1(75.98,111.92)
1237ENPCH: length 3.4
  BOTTOM w0.203: PR4.1 PC5.2 78.24,115.78 PU1.2
1237FBPCH: length 2.7
  BOTTOM w0.203: PU1.5 79.74,115.08 80.13,115.47 PR9.1 PR8.1
1237FBPCH_S: length 24.8
  IN2 w0.254: v2(81.81,114.86) 81.96,115.02 82.82,115.02 85.08,112.76 89.78,112.76 90.29,112.25 90.29,105.39 87.62,102.72 v2(87.62,102.16)
  BOTTOM w0.254: PR85.1 87.6,101.1 87.8,101.3 87.8,101.99 v2(87.62,102.16) ; v2(81.81,114.86) 81.81,116.41 81.52,116.7 PR8.2
1237LX:
  vias: v2(71.67,111.94)
1237PFMPCH: length 1.8
  BOTTOM w0.203: 78.74,115.67 v1(78.73,115.68) ; 78.74,115.67 78.74,116.21 PR7.1 ; 78.74,115.67 PU1.3
1237PGPCH: length 3.3
  BOTTOM w0.203: PU1.1 77.06,115.13 76.61,115.13 v2(76.57,115.17) 76.56,115.17 PR5.1
1237SSPCH: length 4.1
  BOTTOM w0.203: PC6.1 v2(75.16,115.43) 76.71,113.88 PU1.23
3920_RST#: length 80.4
  TOP w0.127: v2(206.84,104.72) 207.28,105.17 207.73,105.17 207.76,105.19 208.18,105.19 208.48,104.89 208.48,104.25 209.37,103.36 210.21,103.36 210.89,103.36 212.06,102.19 212.74,102.19 213.71,101.22 215.69,101.22 216.17,101.71 216.55,101.71 218.41,103.56 218.41,105.09 219.35,106.03 219.81,106.03 220.13,105.7 220.13,105.36 220.64,104.86 221.59,104.86 223.33,103.11 223.33,101.34 224.19,100.49 224.32,100.49 224.95,100.49 225.87,99.56 225.87,97.8 229.28,94.4 229.28,91.34 230.7,89.92 230.7,89.18 230.73,89.16 230.73,89.14 231.02,88.84 231.04,88.84 231.06,88.83 231.97,88.83 232.81,87.99 232.81,87.29 233.01,87.08 233.01,87.02 233.77,86.26 v1(234.33,86.26) 235.25,86.26 v2(235.7,86.72)
  BOTTOM w0.127: R26.1 209.57,111.56 208.93,110.93 U4.5 ; R26.1 209.89,111.16 210.08,110.98 210.96,110.98 211.24,110.7 211.24,110.37 211.57,110.05 R33.2 211.17,109.63 211.04,109.76 210.2,109.76 209.89,109.44 209.89,108.68 209.76,108.55 C29.1 209.54,108.05 209.11,107.61 207.35,107.61 206.7,106.96 U7.37 206.7,104.87 v2(206.84,104.72) ; R26.1 209.89,112.05 209.47,112.48 201.16,112.48 200.63,111.94 200.63,111.16 200.78,111 200.78,109.61 Q4.3 Q8.3 ; v2(235.7,86.72) 235.25,86.26 235.04,86.26 234.61,85.83 Q19.2
8008LX1.5V:
  vias: v4(126.94,112.6)
51216DRVH: length 13.5
  IN1 w0.508: v5(26.48,17.17) 22.68,17.17 19.42,20.43 v5(15.74,20.43)
  BOTTOM w0.178: 15.36,20.8 PU8.14
  BOTTOM w0.33: v5(26.48,17.17) PQ15.4
51216DRVL: length 6.8
  IN1 w1.016: 15.87,23.47 16.38,23.98 17.48,23.98 18.24,23.22 21.46,23.22 21.96,23.73
  vias: v2(15.56,23.14) v2(15.56,22.51) v2(16.25,22.84) v2(22.5,23.88) v2(23.13,23.88)
51216MODE: length 2.6
  BOTTOM w0.178: PU8.19 12.88,19.32 12.43,18.86 11.5,18.86 PR128.2
51216PG: length 6.5
  BOTTOM w0.178: PU8.20 12.48,19.45 12.21,19.18 11.07,19.18 10.53,18.65 10.53,18.26 PR130.1 9.78,17.26 9.52,17 8.12,17 v2(7.74,16.62)
51216REFIN: length 6.9
  BOTTOM w0.178: PU8.8 13.28,23.09 13.38,23.19 13.38,23.78 13.73,24.14 14.32,24.14 14.72,23.73 v2(15.23,23.73) 15.23,24.37 PR124.2
  BOTTOM w0.254: PR124.2 16.24,24.62 PC138.1 PR123.1
51216S3: length 77
  IN2 w0.127: v2(62.86,20.55) 61.54,19.23 51.97,19.23 49.45,16.71 38.23,16.71 37.77,16.25 31.58,16.25 29.74,14.41 26.43,14.41 25.35,13.33 16.33,13.33 15.72,12.72 10.8,12.72 10.05,13.47 v2(10.05,15.8)
  BOTTOM w0.102: PR129.1 12.93,18.28 12.57,17.91 12.57,17.38 12.31,17.12 11.37,17.12 v2(10.05,15.8) ; R463.2 56,25.63 56.71,24.92 62.88,24.92 63.24,24.56 63.24,20.93 v2(62.86,20.55)
  BOTTOM w0.178: PU8.17 13.68,19.25 13.07,18.65 PR129.1
51216S5: length 3.9
  BOTTOM w0.178: PU8.16 14.08,18.77 v2(13.96,18.65) 13.76,18.45 13.76,17.18 13.07,16.49 PR131.1
51216SW: length 12.4
  IN2 w0.508: v5(15.97,21.27) 25.09,21.27 v2(26.54,22.71)
  BOTTOM w0.178: v5(15.97,21.27) 15.91,21.2 PU8.13
  vias: v4(29.2,15.09)
51216TRIP: length 2
  BOTTOM w0.178: PR127.2 12.4,18.4 13.28,19.29 PU8.18
81101_BST:
  vias: v4(57.57,106.99)
81101_HG: length 13
  IN2 w0.508: v2(50.67,102.88) 50.67,103.59 51.71,104.63 54.51,104.63 57.09,107.2 57.46,107.2 58.21,107.96 v5(58.34,107.96)
  BOTTOM w0.178: v5(58.34,107.96) 58.34,108.03 58.78,108.48 PU3.9
  BOTTOM w0.508: PR69.1 50.18,103.36 v2(50.67,102.88)
81101_HG_G:
  vias: v1(46.93,103.13)
81101_LG: length 11.4
  IN2 w1.016: 47.74,108.82 48.38,108.82 50.16,107.04 53.59,107.04 56.23,109.68 56.38,109.68
  BOTTOM w0.178: PU3.12 v2(58.46,109.68)
  vias: v2(47.34,109.17) v2(47.64,110.01) v2(47.97,109.17) v2(57.83,109.63)
81101_PH: length 14.1
  IN2 w0.508: v5(47.16,107.65) 47.16,107.35 49.24,105.26 54.25,105.26 56.91,107.93 57.04,107.93 57.4,108.29 v5(57.4,108.34)
  BOTTOM w0.178: PU3.10 58.67,108.88 58.31,108.51 58.11,108.51
81101COM: length 4.4
  BOTTOM w0.178: PR19.2 66.92,111.49 PC30.2 65.45,110.72 v2(65.02,110.29) 65,110.28 64.19,110.28 63.99,110.08 PU3.23
81101DIFFOUT: length 5.2
  BOTTOM w0.178: PU3.25 65.72,109.28 PR31.1 66.63,109.23 67.95,109.23 PR32.1
81101FB: length 11.7
  BOTTOM w0.127: v2(70.48,114.28) 69.97,113.77 69.97,112.63 69.21,111.87 PR18.1
  BOTTOM w0.178: PU3.24 65.11,109.68 65.65,110.22 66.42,110.22 PR31.2 PC30.1 67.56,110.72 67.68,110.6 PC31.2 68.06,110.72 PC22.1 PR18.1
81101ILIM: length 6.1
  BOTTOM w0.178: v4(67.3,114.14) PR12.2 64.01,111.87 62.73,111.87 62.59,111.73 PU3.21
81101IOUT: length 5.5
  BOTTOM w0.178: PC13.1 PR13.2 64.51,113.89 v2(64.51,113.14) 63.62,112.25 62.6,112.25 62.19,111.84 PU3.20
81101ROSC: length 2.9
  BOTTOM w0.178: PU3.22 63.75,110.48 v4(64.88,111.6) 65.13,111.86 PR20.2
81181_AGND: length 14.6
  IN2 w0.508: v2(56.38,105.59) 56.81,105.59 58.13,106.91 59.43,106.91 59.94,106.41 60.32,106.41
  BOTTOM w0.381: v2(64.13,115.6) 64.13,115.05 PR13.1 PC13.2
  BOTTOM w0.508: PC61.1 65.64,107.3 v2(65.14,107.8) ; PC64.2 56.81,106.02 v2(56.38,105.59) ; PR15.2 57.91,113.65 58.16,113.9 v2(58.92,113.9) 58.92,115.27 v2(59,115.35) 60,115.35 PC12.1 PR14.1 ; PC27.2 57.81,111.62 v2(58.21,112.02) ; PR20.1 65.78,112.88 v2(66.16,113.26)
  vias: v2(65.55,103.64) v2(66.18,103.76) v5(60.44,110.14) v5(60.42,109.3) v5(60.44,108.51) v5(61.41,110.14) v5(61.38,109.3) v5(61.41,108.51) v5(62.35,110.14) v5(62.32,109.3) v5(62.35,108.51)
+BATCHG:
  vias: v4(146.88,82.17)
+LCDVCC:
  vias: v4(11.83,99.75)
+PCH_VCCDSW: length 25.9
  TOP w0.076: 52.98,71 53,71.02
  TOP w0.127: 53.92,72.9 53.92,72.27
  TOP w0.254: 52.29,71 52.29,71.36 52.11,71.53 52.11,72.32 v2(51.88,72.55) 51.88,73.2 TP43.1 ; 52.29,71 52.11,70.82 52.11,68.25 51.94,68.07 51.94,67.29 ; 52.29,71 52.98,71 53.11,70.86 53.11,67.67 52.73,67.29
  TOP w0.508: v2(46.35,59.29) 46.96,59.9 46.96,62.57 47.69,63.3 48.48,63.3 49.25,64.07 49.25,65.37 50.79,66.91 51.55,66.91 51.94,67.29
  BOTTOM w0.254: U20.AG19 52.25,72.92 v2(51.88,72.55) 51.51,72.92 U20.AG20
  BOTTOM w0.508: v2(46.35,59.29) 46.62,59.56 C5.1 C288.2
+PRWSRC: length 33.5
  TOP w0.508: v2(133.34,98.33) 134.58,98.33 137.33,95.58 137.33,93.69 139.18,91.83 139.18,89.82 141.32,87.69 145.18,87.69 145.99,88.5 147.74,88.5 149.77,90.53 156.08,90.53
  BOTTOM w0.508: v2(169.44,93.06) 169.44,93.09 PR106.2 ; v2(133.34,98.33) 133.09,98.33 132.83,98.07 132.83,97.26 132.44,96.87 PR98.1
  vias: v1(180.46,96.25) v5(157.9,93.66) v5(158.56,94.39) v5(158.64,93.66) v5(159.33,94.39) v5(159.38,93.66) v5(160.06,94.39) v5(160.14,93.66) v5(160.8,94.39) v5(180.38,98.91) v5(180.41,98.15) v5(181.12,98.91) v5(181.14,98.15) v5(181.14,97.39) v5(181.78,99.27) v5(181.78,98.53) v5(181.78,97.77)
+SMDDR_VREF_DIMM: length 10.1
  BOTTOM w0.254: v2(45.84,27.28) 45.35,27.77 JDIM1.126
  BOTTOM w0.508: R468.1 40.76,24.44 42,25.68 R467.2 42.85,24.99 R466.2 43.69,24.99 44.42,24.26 45.48,24.26 46.25,25.02 C337.1
+SMDDR_VREF_DQ1: length 32.3
  TOP w0.508: v2(12.57,62.34) 13.35,61.55 v1(13.35,59.37) 13.35,58.65 v2(14.14,57.87)
  BOTTOM w0.356: 4.69,37.98 5.27,37.4 JDIM1.1
  BOTTOM w0.508: v2(14.14,57.87) 15.64,56.37 15.64,48.43 7.96,40.75 5.96,40.75 4.69,39.48 4.69,37.98
+VA: length 150.9
  TOP w0.152: v2(221.05,106.74) 213.66,106.74 212.67,107.73 212.67,107.74 212.4,108.01 212.39,108.01 212.34,108.06 211.73,108.06 210.44,106.77 208.95,106.77 208.87,106.85 207.07,106.85 207.04,106.83 206.59,106.83 206.54,106.77 205.29,106.77 204.05,105.54 199.59,105.54 198.34,106.79 194.42,106.79 193.67,106.03 193.67,104.37 191.81,102.52 190.25,102.52 189.62,101.88 187.49,101.88 186.61,101 186.61,99.55 177.46,90.4 175.84,90.4 174.9,89.46 v1(173.78,89.46) 173.45,89.46 173.27,89.65 v2(172.61,89.65) ; v2(134.41,102.6) 134.92,102.6 138.3,99.22 138.3,97.54 v2(138.83,97.01)
  IN2 w0.127: v2(138.83,97.01) 139.21,96.63 140.49,96.63 141.23,96.63 141.44,96.63 151.62,96.63 152.15,96.63 157.23,91.55 165.32,91.55 166.48,91.55 167.37,90.65 169.74,90.65 170.75,89.65 v2(172.61,89.65)
  IN2 w0.152: v2(221.05,106.74) 221.52,106.74 221.75,106.96 228.77,106.96 229.18,107.37 235.96,107.37 237.79,105.54 237.79,103.1 237.18,102.49 237.18,96.78 238.55,95.41 241.88,95.41 244.98,92.31 244.98,87.36 v2(244.09,86.47)
  BOTTOM w0.152: v2(134.41,102.6) 133.7,103.31 PD5.2 ; v2(244.09,86.47) 243.75,86.8 CN6.7
+VA_AIR: length 12.1
  BOTTOM w0.127: PR34.1 134.61,110.47 v2(134.1,110.98) 133.91,110.98 133.66,110.72 133.66,110.28 133.02,109.64 133.02,105.2 132.58,104.75 PR58.1 132.57,104.38 132.66,104.3 134.34,104.3 PD5.1
+VAD: length 71.7
  TOP w0.508: v5(149.65,92.03) 149.6,92.03 148.58,91.01 148.58,90.78 147.32,89.51 140.99,89.51 140.2,90.3 140.2,94.42 138.63,95.99 138.36,95.99 137.15,97.2 137.15,98.91 136.45,99.61 135.31,99.61 134.6,100.33 v2(133.58,100.33) 133.58,101.47 132.2,102.85 132.2,103.88 131.7,104.37 129.86,104.37 128.97,103.48 122.21,103.48 122.21,103.49 121.74,103.49 121.74,103.48 120.93,103.48 120.54,103.09 120.54,102.63 118.41,100.5 117.16,100.5 116.2,100.5 116.18,100.48 115.84,100.14 115.5,99.8 114.58,98.88 112.3,98.88 111.64,99.55 v2(107.79,99.55)
  IN2 w0.508: v2(107.79,99.55) 107.71,99.55 105,102.27 v2(105,102.37)
  BOTTOM w0.508: PR100.1 174.92,95.46 v2(174.34,96.04) ; v2(107.79,99.55) 108.24,99.55 PR92.2 ; v2(133.58,100.33) 133.58,100.52 PR83.1 ; v2(105,102.37) 105,104.37 105.81,105.19 PR50.2 ; 162.76,96.08 162.76,93.96 163.21,93.5 163.21,93.43 163.95,92.69 163.95,92.56 164.2,92.31 PC124.1
  vias: v1(190.29,111.64) v2(239.06,90.45) v2(239.34,91.09) v2(239.72,90.45) v2(239.97,91.09) v2(240.35,90.45) v2(240.61,91.09) v2(241.04,90.45) v2(241.24,91.12) v5(150.39,92.03) v5(151.12,92.03) v5(151.86,92.03) v5(152.6,92.03) v5(158.79,101.76) v5(159.17,102.39) v5(159.55,101.76) v5(159.94,102.39) v5(160.32,101.76) v5(160.7,102.39) v5(161.08,101.76) v5(161.46,102.39) v5(161.84,101.76) v5(162.22,102.39) v5(162.6,101.76) v5(162.98,102.39)
AC_LED_ON#: length 55
  IN2 w0.127: v3(217.06,99.95) 217.54,100.44 219.95,100.44 220.58,101.07 225.39,101.07 226.51,102.19 229.82,102.19 233.39,98.61 233.39,97.77 233.39,97.56 233.39,97.56 233.39,94.73 234.56,93.56 234.56,89.95 235.32,89.18 236.06,89.18 v2(236.47,89.59)
  BOTTOM w0.127: v3(217.06,99.95) 217.06,97.82 217.14,97.74 217.14,95.59 217.26,95.46 217.26,94.82 217.85,94.23 218.32,93.76 U7.92 219.91,93.76 220.11,93.55 220.11,92.61 220.41,92.31 220.41,91.05 R223.2 ; CN6.11 245.75,86.56 244.79,85.6 243.56,85.6 242.64,86.52 241.14,86.52 237.96,89.69 236.57,89.69 v2(236.47,89.59)
AC_PRESENT_EC: length 157.5
  IN2 w0.127: v2(195.79,92.4) 194.85,92.4 193.91,91.46 193.49,91.46 192.97,91.46 192.76,91.46 192.5,91.71 192.19,91.71 191.98,91.71 188.92,91.71 184.29,87.08 184.29,86.3 180.52,82.53 178.75,82.53 175.98,79.76 172.64,79.76 171.65,78.77 170.59,78.77 157.37,78.77 152.95,83.19 136.57,83.19 136.14,82.76 106.03,82.76 103.37,85.41 97.44,85.41 95.51,87.34 93.15,87.34 92.95,87.55 88.31,87.55 85.21,84.45 85.21,83.29 84.27,82.35 83.91,82.35 83.38,81.82 v2(83.35,81.82)
  BOTTOM w0.127: v2(83.35,81.82) 83.35,77.57 78.29,72.51 78.29,68.58 78.02,68.31 v2(78.02,67.59) 78.02,67.32 76.99,66.29 73.69,66.29 73.02,65.61 73.02,65.38 72.53,64.9 R388.1 ; R236.2 199.32,87.64 199.32,88.05 198.67,88.7 197.15,88.7 196.53,89.32 196.28,89.32 196.08,89.51 196.08,91.05 196.03,91.1 196.03,91.14 195.79,91.38 v2(195.79,92.4)
AC_PRESENT_R: length 17.8
  TOP w0.076: 63.49,71.23 63.2,71.52 59.8,71.52 59.63,71.35 59.38,71.35 v2(59.38,71.33)
  TOP w0.127: v2(70.96,66.07) 70.57,66.07 v1(70.42,66.22) 70.22,66.42 70.22,67.42 69.83,67.81 68.08,67.81 67.53,68.36 66.51,68.36 65.12,69.75 65.12,70.06 64.2,70.97 63.75,70.97 63.49,71.23
  BOTTOM w0.076: v2(59.38,71.33) 59.35,71.35 58.97,71.35 58.47,71.85 U20.AJ8
  BOTTOM w0.127: v2(70.96,66.07) 71.21,65.82 R385.1 71.05,65.36 R388.2
ACC_INT1: length 28.1
  TOP w0.127: v3(243.32,107.42) 242.92,107.83 241.7,107.83 241.29,107.42 235.3,107.42 233.11,109.61 233.11,110.51 230.28,113.34 229.28,113.34 228.13,114.48 228.13,115.32 228.65,115.84 U1.5
  BOTTOM w0.127: U5.26 242.7,106.8 v3(243.32,107.42)
ACC_INT2: length 26.5
  TOP w0.127: U1.4 227.85,114.39 229.15,113.09 230.17,113.09 232.85,110.41 232.85,109.49 235.17,107.17 241.67,107.17 v3(241.88,107.37)
  BOTTOM w0.127: v3(241.88,107.37) 242.2,107.05 U5.27
ACCEL_INTA#: length 12.5
  TOP w0.127: v2(71.29,68.18) v1(70.64,68.83) 70.4,69.07 68.6,69.07 67.78,69.88 67.78,69.93 67.2,70.52 66.21,70.52 65.72,71 65.53,71 64.11,72.42 62.04,72.42 v2(61.84,72.63)
  BOTTOM w0.127: v2(71.29,68.18) 71.29,68.18 71.53,67.94 R381.1 ; U20.AG3 61.84,72.71 v2(61.84,72.63)
ACIN: length 152.1
  IN2 w0.127: v2(225.64,103.14) 225.08,103.7 223.98,103.7 223.72,103.43 220.18,103.43 219.85,103.1 217.7,103.1 217.16,103.64 217.16,103.76 216.34,104.59 216.34,105.15 215.97,105.52 213.68,105.52 213.12,106.08 211.3,106.08 210.68,106.69 205.55,106.69 205.18,106.33 203.26,106.33 202.72,105.78 202.13,105.78 199.34,105.78 197.67,105.78 196.38,104.5 196.36,104.5 195.81,104.5 195.56,104.25 193.67,104.25 193.21,103.79 193.04,103.79 192.72,103.79 192.51,103.79 191.21,102.49 190.29,102.49 189.15,101.35 184.85,101.35 183.91,100.41 180.25,100.41 179.19,99.35 179.19,96.03 175.33,92.17 174.99,92.17 174.53,92.17 174.28,91.92 169.15,91.92 167.56,93.52 167.11,93.52 166.74,93.15 v2(164.43,93.15) 163.85,93.15 161.13,95.86 156.27,95.86 153.52,98.61 144.51,98.61 144.04,99.08 137.75,99.08 137.41,99.42 132.43,99.42 131.79,98.79 125,98.79 123.92,99.87 116.77,99.87 115.23,101.4 112.08,101.4 109.78,99.1 106.13,99.1 v2(105.68,99.55)
  BOTTOM w0.127: U7.76 221.68,100.16 223.07,101.54 224.97,101.54 225.64,102.21 v2(225.64,103.14) ; PR93.1 106.13,99.55 v2(105.68,99.55)
  BOTTOM w0.254: v2(164.43,93.15) 164.74,92.84 166.39,92.84 166.74,93.2 PR109.1 166.99,93.57 167.77,94.35 ; 167.77,94.35 167.75,94.35 167.25,94.85 167.25,95.61 167.78,96.13 PU7.5 ; 167.77,94.35 PR108.1
ACZ_BCLK: length 5.3
  BOTTOM w0.127: R419.2 57.52,61.52 58.16,62.16 58.16,64.41 57.57,64.99 57.57,65.37 U20.AW8
ACZ_RST#: length 8
  TOP w0.127: v2(58.16,61.55) v1(58.16,62.9) 58.16,64.72 57.14,65.74 57.14,66.86 57.16,66.88 57.16,66.88 57.4,67.12 57.4,67.12 57.7,67.42 v2(57.7,67.66)
  BOTTOM w0.127: U20.AU8 57.7,67.31 v2(57.7,67.66) ; v2(58.16,61.55) R418.2
ACZ_RST#_AUDIO: length 231
  TOP w0.127: v2(224.24,81.26) 224.24,77.46 223.52,76.74 v2(222.98,76.74) 223.41,77.17 223.41,77.6 220.85,80.17 220.85,82.51 219.63,83.72 216.27,83.72 215.23,84.77 214.85,84.77 212.67,86.95 208.2,86.95 207.4,87.75 205.21,87.75 204.75,87.29 203.19,87.29 202.55,86.66 196.37,86.66 v1(195.32,87.71) 195.22,87.61 191.98,87.61 191.4,87.03 188.52,87.03 185.04,83.55 183.91,83.55 182.3,81.93 182.3,78.72 180.5,76.92 176.16,76.92 175.44,77.64 173.72,77.64 172.72,76.64 161.46,76.64 160.27,77.83 154.83,77.83 152.99,79.67 137.64,79.67 136.94,80.37 126.99,80.37 v2(126.61,79.99)
  IN1 w0.127: v2(126.61,79.99) 123.79,77.17 95.65,77.17 94.8,78.02 94.04,78.02 93.59,77.58 88.1,77.58 81.01,70.48 81.01,51.15 77.21,47.35 v2(75.84,47.35)
  BOTTOM w0.127: U18.11 219.22,76.92 219.32,76.81 219.58,76.81 220.01,77.25 221.05,77.25 221.56,76.74 v2(222.98,76.74) ; v2(75.84,47.35) 75.84,48.21 73.71,50.34 70.26,50.34 70.04,50.56 68.18,50.56 67.91,50.29 64.09,50.29 57.64,56.73 57.64,59.36 57.98,59.7 57.98,60.4 R418.1 ; Q18.1 225.54,85.07 224.59,84.12 224.59,81.86 224.24,81.5 v2(224.24,81.26)
ACZ_SDIN0: length 221.9
  TOP w0.127: v2(125.98,79.99) 125.98,80.37 126.36,80.75 137.09,80.75 137.79,80.05 153.15,80.05 154.96,78.25 160.48,78.25 161.7,77.03 172.57,77.03 173.56,78.02 175.59,78.02 176.32,77.3 180.34,77.3 181.92,78.88 181.92,82.11 183.74,83.93 184.88,83.93 188.36,87.41 191.24,87.41 191.82,87.99 192.71,87.99 193.1,88.38 195.38,88.38 196.18,87.58 198.44,87.58 198.99,87.04 202.39,87.04 203.03,87.67 204.53,87.67 205,88.14 207.54,88.14 208.32,87.36 215.69,87.36 216.15,86.9 216.15,84.56 216.6,84.1 220.69,84.1 221.23,83.57 221.23,80.59 v1(221.9,79.91) v2(222.5,79.32)
  IN1 w0.127: v2(74.92,47.48) 75.3,47.48 75.68,47.86 76.03,47.86 79.49,51.32 79.49,58.31 80.61,59.43 80.61,70.84 87.73,77.96 93.43,77.96 93.88,78.4 94.96,78.4 95.81,77.55 123.63,77.55 125.98,79.89 v2(125.98,79.99)
  BOTTOM w0.127: v2(74.92,47.48) 74.67,47.73 73.75,47.73 72.45,49.03 64.27,49.03 56.88,56.42 56.88,59.74 57.14,60 57.14,61.24 57.31,61.41 57.31,61.63 57.9,62.22 57.9,64.24 57.19,64.96 U20.AY10 ; C247.2 222.58,79.23 v2(222.5,79.32) 222.41,79.23 R289.1
ACZ_SDOUT: length 6.8
  BOTTOM w0.076: U20.AU11 56.51,67.04 56.81,66.73 56.81,66.15 56.9,66.06 56.9,64.87 57.52,64.24
  BOTTOM w0.127: R420.2 56.76,61.19 57,61.43 R411.2 57.2,61.91 57.23,61.91 57.52,62.2 57.52,64.24
ACZ_SDOUT_AUDIO: length 223
  TOP w0.127: v2(124.71,79.99) 124.71,80.5 125.72,81.51 137.41,81.51 138.11,80.82 153.47,80.82 155.2,79.09 161.22,79.09 162.51,77.79 172.26,77.79 173.25,78.78 175.91,78.78 176.63,78.06 180.03,78.06 181.16,79.19 181.16,82.47 183.38,84.69 184.57,84.69 188.05,88.17 190.92,88.17 191.51,88.75 192.24,88.75 192.87,89.39 193.61,89.39 194.96,89.39 196.65,91.08 198.36,91.08 199.46,89.97 200.72,89.97 200.9,90.15 206.57,90.15 208.55,88.17 217.06,88.17 217.75,87.48 217.75,86.57 v1(218.2,86.11) 218.79,85.53 221.03,85.53 221.99,84.57 221.99,82.4 v2(222.72,81.67)
  IN1 w0.127: v2(124.71,79.99) 124.71,79.7 123.32,78.31 96.12,78.31 95.27,79.16 93.56,79.16 93.12,78.72 87.41,78.72 79.85,71.16 79.85,59.74 78.73,58.63 78.73,51.64 76.02,48.93 75.41,48.93 74.41,47.93 74.41,46.97 74.74,46.64 v2(74.74,46.49)
  BOTTOM w0.127: U18.5 220.66,80.32 220.82,80.47 220.82,80.59 C237.2 221.37,81.35 221.68,81.67 v2(222.72,81.67) ; v2(74.74,46.49) 74.64,46.49 74.16,46.97 73.43,46.97 72.23,48.17 64.05,48.17 56.12,56.1 56.12,60.09 56.25,60.23 56.25,61.43 R411.1
ACZ_SPKR: length 190.4
  TOP w0.127: v2(112.34,91.22) 112.34,91.34 111.98,91.7 111.26,91.7 111.17,91.61 108.96,91.61 108.65,91.61 106.47,91.61 106.47,91.61 105.31,91.61 103.57,91.61 103.57,91.61 103.51,91.61 102.99,92.13 102.84,92.13 90.37,92.13 90.37,92.13 87.4,92.13 86.1,90.84 84.73,90.84 83.47,90.84 80.08,87.44 80.08,86.05 79.98,85.95 79.98,85.58 80.08,85.48 80.08,85.15 80,85.08 80,84.64 78.24,82.88 77.68,82.88 77.29,82.49 77.29,82.49 76.87,82.07 76.87,82.06 76.39,81.59 76.39,81.59 75.37,81.59 75.33,81.55 75.32,81.55 75.06,81.29 75.06,81.29 72.13,78.35 72.13,77.72 71.78,77.37 71.24,77.37 70.99,77.63 v2(70.99,77.7) ; v2(175.25,77.2) 175.91,76.54 180.66,76.54 182.68,78.56 182.68,81.76 184.09,83.16 185.2,83.16 188.68,86.64 191.56,86.64 192.14,87.23 193.32,87.23 194.27,86.28 v1(194.89,86.28) 202.71,86.28 203.34,86.91 205.08,86.91 205.38,87.2 206.27,87.2 206.9,86.57 212.49,86.57 214.7,84.36 215.1,84.36 216.12,83.34 219.44,83.34 219.91,82.87 219.91,82.87 220.17,82.61 220.17,82.61 220.46,82.32 220.46,79.99 222.95,77.5 v2(222.95,77.37)
  BOTTOM w0.127: v2(175.25,77.2) 174.52,77.93 173.52,77.93 172.46,76.87 172.46,75.16 171.19,73.89 154.68,73.89 151.46,77.12 118.46,77.12 117.01,78.57 117.01,83.17 112.31,87.87 112.31,91.19 v2(112.34,91.22) ; v2(222.95,77.37) 223.03,77.37 223.46,76.94 Q23.2 ; R309.1 70.99,77.7 v2(70.99,77.7)
ACZ_SYNC: length 8
  BOTTOM w0.076: 56.73,64.73 56.73,65.94 56.48,66.19 U20.AV11 ; v4(55.11,60.18) 55.86,60.93 R421.2
  BOTTOM w0.127: 56.73,64.73 57.17,64.29 57.17,63.61 56.53,62.97 56.25,62.97 55.49,62.21 55.49,61.63 55.65,61.46 R412.2 R421.2
ACZ_SYNC_AUDIO: length 215.4
  TOP w0.127: v2(220.82,77.86) 220.31,77.86 220.06,78.11 220.06,81.46 219.27,82.26 219.27,82.79 219.09,82.96 215.96,82.96 214.99,83.93 214.57,83.93 212.34,86.16 209.14,86.16 v1(208.68,85.7) 208.2,86.19 206.72,86.19 206.09,86.82 205.63,86.82 205.27,86.47 v2(205.17,86.47)
  IN1 w0.127: v2(74.03,46.46) 74.87,45.62 76.95,45.62 77.79,46.46 77.97,46.46 82.16,50.65 82.16,70.03 88.49,76.36 152.6,76.36 154.74,74.22 186.85,74.22 193.82,81.18 193.82,82.64 194.2,83.02 194.2,84.08 193.97,84.31 193.97,85.32 194.61,85.96 197.58,85.96 198.09,86.47 v2(205.17,86.47)
  BOTTOM w0.127: U18.10 220.99,78.32 221.1,78.21 221.37,78.21 C255.2 221.26,77.85 220.83,77.85 v2(220.82,77.86) ; v2(74.03,46.46) 73.4,46.46 72.07,47.79 63.89,47.79 55.74,55.94 55.74,60.31 R421.1
AD_AIR: length 107.4
  IN2 w0.127: v2(220.92,105.47) 220.31,105.47 218.99,106.79 217.6,106.79 216.53,107.85 216.12,107.85 215.57,108.41 214.16,108.41 212.58,110 210.62,110 210.6,109.99 210.24,109.99 209.8,110.42 206.65,110.42 205.81,109.58 203.58,109.58 203.33,109.33 203.33,109.33 202.21,108.21 195.42,108.21 193.77,109.86 190.72,109.86 190.59,109.73 190.59,108.44 189.13,106.98 184.43,106.98 182.68,105.22 177.53,105.22 174.31,102.01 165.58,102.01 163.79,103.8 156.6,103.8 155.53,102.74 147.05,102.74 142.97,106.81 136.8,106.81 136.01,106.02 v2(134.79,106.02)
  BOTTOM w0.127: v2(133.72,109.71) 133.47,109.45 PC44.1 133.98,108.19 133.98,106.4 PR44.1 133.35,105.77 PR58.2 134.29,104.75 134.79,105.26 v2(134.79,106.02) ; U7.65 220.57,104.56 220.92,104.91 v2(220.92,105.47)
AD_ID: length 55
  IN2 w0.127: v2(215.21,107.68) 215.54,107.35 216.32,107.35 219.02,104.65 222.85,104.65 223.06,104.65 223.73,105.33 233.99,105.33 234.47,104.84 235.18,104.84 235.78,105.44 236.21,105.44 236.52,105.14 236.52,103.76 234.21,101.45 234.21,97.72 236.52,95.41 236.52,91.09 v2(236.77,90.84)
  BOTTOM w0.127: R36.2 215.84,108.86 C24.1 214.95,107.93 v2(215.21,107.68) ; CN6.10 245.25,86.42 244.69,85.86 243.66,85.86 242.75,86.77 241.24,86.77 238.07,89.95 237.15,89.95 v2(236.95,90.15) 236.77,90.33 v2(236.77,90.84)
AD_TYPE: length 2.7
  BOTTOM w0.127: U7.64 217.5,107.19 217.29,107.4 v1(217.29,107.93) 217.29,108.44 217.16,108.56 R35.1
ALERT#: length 8.6
  BOTTOM w0.203: PR90.2 64.35,101.33 62.7,102.98 62.04,102.98 61.72,103.3 v1(61.72,103.4) 61.64,103.4 61.16,103.89 61.16,104.91 60.89,105.17 PR56.1 60.52,105.47 61.39,106.34 PU3.4
ALS_INT: length 59.6
  IN2 w0.127: v2(234.97,105.29) 234.39,105.29 234.1,105.58 223.63,105.58 222.95,104.91 219.12,104.91 216.43,107.6 216.02,107.6 215.46,108.16 213.99,108.16 212.41,109.73 210.13,109.73 209.7,110.17 206.9,110.17 205.88,109.15 203.51,109.15 203.43,109.07 203.43,109.07 202.21,107.85 194.99,107.85 194.12,108.72 192.7,108.72 v2(192.07,109.35)
  BOTTOM w0.127: CN3.2 187.69,106.53 188.33,107.17 189.68,107.17 191.86,109.35 v2(192.07,109.35) ; U5.36 236.73,104.28 236.59,104.42 236.59,106.72 R47.1 235.92,107 234.97,106.05 v2(234.97,105.29)
AMP_BEEP: length 1.4
  BOTTOM w0.203: U18.12 218.82,76.71 219.08,76.45 C263.2
AMP_BEEP_L: length 3
  BOTTOM w0.254: C263.1 C271.1 R340.1 R339.2 220.22,74.16 v2(220.46,73.92)
AMP_BEEP_R2: length 2.4
  BOTTOM w0.127: v3(221.86,74.91) 221.48,74.53 R339.1
  BOTTOM w0.254: C270.2 220.22,75.2 220.7,74.72 R339.1
AMP_CLK: length 4.6
  BOTTOM w0.127: U19.8 205.61,76.81 R319.1 204.85,75.78 204.46,75.39 R332.1 204.1,75.01 203.65,74.55 v2(203.01,74.55)
AMP_DAT: length 3.7
  BOTTOM w0.127: v3(206.24,75.16) 206.08,75.01 R331.1 205.48,75.43 R318.1 205.99,76.17 205.99,76.95 206.11,77.07 U19.7
B_TEMP_MBAT: length 12.8
  BOTTOM w0.127: CN9.4 160.65,85.32 161.41,84.56 165.6,84.56 v4(167.76,86.72) 168.27,87.23 PC131.2 PR119.2 PR118.1
BASE_EC_KEY_R: length 1.7
  BOTTOM w0.127: R102.2 193.62,96.13 194.23,95.52 Q15.2
BASE_EC_RESET#: length 80.5
  TOP w0.127: v2(189.6,86.06) 189.37,85.83 188.43,85.83 185.18,82.58 v1(184.83,82.58) v2(184.27,82.58) ; v2(228.85,82.48) 228.7,82.34 228.57,82.34 228.27,82.03 227.82,82.03 227.55,81.76 227.55,80.17 223.64,76.26 221.79,76.26 220.57,77.48 220.13,77.48 219.68,77.92 219.68,81.31 218.55,82.43 214.44,82.43 212.54,84.33 206.75,84.33 205.27,85.82 201.14,85.82 200.71,85.39 195.33,85.39 194.51,84.56 194.51,81.23 v2(193.77,80.5)
  BOTTOM w0.127: Q14.3 192.78,93.83 192.59,94.02 191.57,94.02 191.41,93.86 191.41,89.79 191.25,89.64 191.25,88.29 189.6,86.64 v2(189.6,86.06) ; CN8.15 188.22,81.4 188.02,81.2 ; 188.02,81.2 185.81,81.2 184.42,82.58 v2(184.27,82.58) ; 188.02,81.2 188.71,80.5 v2(193.77,80.5) ; v2(228.85,82.48) 229.18,82.81 230.32,82.81 231.18,83.67 R483.1
BASE_EC_RESET_R: length 1.8
  BOTTOM w0.127: R103.2 192.38,96.21 v2(192.35,96.25) 192.35,96.06 192.28,95.99 Q14.2
BATDIS_G: length 10.9
  BOTTOM w0.254: PC132.2 160.62,88.37 162.81,90.56 PQ7.1 164.36,90.81 165.48,91.94 PC124.2 v2(166.77,92.31) 167.64,92.31 PR107.2
BATDIS_ID_DOD: length 3
  BOTTOM w0.254: PQ6.4 183.13,94.48 PC119.1 PR104.1
BATSHIP: length 43.7
  TOP w0.254: v2(220.49,102.24) 219.83,102.24 v1(219.24,101.66) 219.24,100.21 217.95,98.91 211.83,98.91 211.47,99.27 211.47,100.34 210.46,101.35 206.47,101.35 205.99,101.83 199.66,101.83 198.06,103.43 194.89,103.43 192.49,101.03 190.86,101.03 190.08,100.26 v2(188.76,100.26)
  BOTTOM w0.203: v2(220.49,102.24) 220.41,102.16 U7.71
  BOTTOM w0.254: v2(188.76,100.26) 189.41,100.26 189.98,99.69 189.98,97.87 PQ9.2
BATT+:
  vias: v4(148.94,86.95)
BIOS_CS#: length 15.1
  TOP w0.127: v2(196.54,89.77) 196.46,89.69 v1(196.46,88.98) 196.46,88.58 197.07,87.97 198.62,87.97 199.13,87.46 201.64,87.46 202.3,88.12 204.37,88.12 v2(204.89,88.64)
  BOTTOM w0.127: v2(196.54,89.77) 196.51,89.79 196.51,91.11 196.33,91.28 R145.2 ; v2(204.89,88.64) 205.1,88.84 U7.128
BIOS_RD#: length 28.1
  IN1 w0.127: v2(231.82,87.31) 231.11,87.31 230.73,87.69 230.34,87.69 229.81,88.22 229.17,88.22 229.16,88.23 228.46,88.23 228.29,88.4 225.72,88.4 224.59,89.53 224.56,89.53 222.84,89.53 222.53,89.21 220.69,89.21 219.98,88.5 218.99,88.5 218.84,88.35 216.15,88.35 215.51,88.98 v2(215.51,89.03)
  IN2 w0.127: v2(209.59,89.13) 210,88.73 215.21,88.73 v2(215.51,89.03)
  BOTTOM w0.127: U7.119 208.7,89.7 208.88,89.51 209.21,89.51 v2(209.59,89.13) 209.59,88.96 209.92,88.63 210.43,88.63 v2(210.56,88.5) ; v2(231.82,87.31) R229.2
BIOS_SPI_CLK: length 14.4
  TOP w0.127: v2(206.82,88.69) 206.05,89.46 201.29,89.46 201.03,89.21 199.2,89.21 v1(198.84,89.58) 198.28,90.14 v2(197.78,90.14)
  BOTTOM w0.127: v2(206.82,88.69) 205.9,89.62 U7.126 ; R144.2 197.2,91.57 197.45,91.32 197.45,90.47 v2(197.78,90.14)
BIOS_WP#: length 5.6
  BOTTOM w0.127: U9.3 78.1,96.73 77.68,96.31 77.12,96.31 76.78,96.65 TP68.1 76.7,96.25 77,95.94 77,95.27 R112.1 76.81,94.55 R131.1
BIOS_WR#: length 27.9
  IN1 w0.127: v2(216.17,89.03) 216.43,88.78 218.73,88.78 218.83,88.88 219.3,88.88 219.82,88.88 220.53,89.59 222.36,89.59 222.68,89.91 223.93,89.91 224.75,89.91 225.73,88.93 228.13,88.93 228.45,89.25 229.49,89.25 230.59,88.14 231.28,88.14 v2(231.51,87.91)
  IN2 w0.127: v2(216.17,89.03) 215.49,88.35 209.67,88.35 v2(208.93,89.08)
  BOTTOM w0.127: v2(208.78,88.37) 208.93,88.52 v2(208.93,89.08) 208.3,89.72 U7.120 ; v2(231.51,87.91) 231.55,87.95 R210.2
BIT_CLK_AUDIO: length 223.8
  TOP w0.127: v2(223.49,81.08) 222.99,80.57 221.91,80.57 221.61,80.88 221.61,83.77 220.9,84.49 216.83,84.49 216.63,84.69 216.63,87.17 216.04,87.76 208.42,87.76 206.37,89.82 201.1,89.82 200.88,89.59 199.47,89.59 198.36,90.7 196.8,90.7 195.11,89.01 195.09,89.01 v1(193.77,89.01) 193.03,89.01 192.4,88.37 191.67,88.37 191.08,87.79 188.21,87.79 184.73,84.31 183.56,84.31 181.54,82.29 181.54,79.03 180.18,77.68 176.48,77.68 175.75,78.4 173.41,78.4 172.42,77.41 161.96,77.41 160.7,78.66 155.08,78.66 153.31,80.43 137.95,80.43 137.25,81.13 125.98,81.13 125.34,80.5 v2(125.34,79.99)
  IN1 w0.127: v2(125.34,79.99) 125.31,79.96 125.31,79.77 123.48,77.93 95.96,77.93 95.11,78.78 93.72,78.78 93.28,78.34 87.57,78.34 80.23,71 80.23,59.58 79.11,58.47 79.11,51.48 76,48.37 75.56,48.37 v2(75.3,48.11)
  BOTTOM w0.127: v2(223.49,81.08) 223.45,81.08 223.04,80.66 C239.2 222.89,80.62 222.12,80.62 221.99,80.5 R275.2 ; R419.1 57.52,59.82 57.26,59.56 57.26,56.58 64.38,49.46 72.56,49.46 73.9,48.11 v2(75.3,48.11) 75.38,48.04 75.38,47.07 75.61,46.84 76.19,46.84 76.45,47.1 C296.2
BLON_CON: length 10.9
  BOTTOM w0.127: 12.75,85.83 12.72,85.87 11.87,85.87 11.7,85.7 11.7,84.36 11.32,83.98 11.18,83.98 10.04,82.84 10.04,82.73 9.47,82.15 CN7.16 ; 12.75,85.83 13.01,86.09 C205.2 13.01,87.42 13.25,87.66 D9.1 13.69,88.27 14.47,87.48 v2(14.47,87.36) ; 12.75,85.83 R250.1
BOARD_ID0: length 11.1
  IN1 w0.127: v2(65.96,73.56) 65.96,72.76 65.57,72.36 62.97,72.36 62.25,73.08 61.38,73.08 60.7,73.77 59.63,73.77 v2(59.17,73.31)
  BOTTOM w0.127: U20.AG6 59.53,72.95 v2(59.17,73.31) ; R352.1 R353.2 66.35,73.02 65.96,73.41 v2(65.96,73.56)
BOARD_ID1: length 9.8
  BOTTOM w0.076: 63.39,68.27 63.25,68.27 63.01,68.5 U20.AP1
  BOTTOM w0.127: R413.1 R414.2 66.84,61.79 65.4,63.23 65.4,67.34 64.47,68.27 63.39,68.27
BOARD_ID2: length 16.9
  TOP w0.127: v2(61.16,71.13) 61.65,70.64 61.92,70.64 63.24,69.32 v1(63.54,69.32) 63.75,69.32 64.13,68.94 64.13,68.43 64.78,67.77 66.11,67.77 68.06,65.82 68.06,64.14 68.59,63.61 68.95,63.61 69.84,62.72 71.47,62.72 71.49,62.74 v2(71.49,62.72)
  BOTTOM w0.127: R400.1 R399.2 71.38,62.6 v2(71.49,62.72) ; U20.AL4 61.16,71.01 v2(61.16,71.13)
BOARD_ID3: length 19.4
  TOP w0.127: v2(58.39,67.47) 58.62,67.24 58.62,66.45 59.94,65.13 TP59.1
  IN2 w0.127: v2(58.39,67.47) 58.03,67.11 58.03,66.02 59.05,65 59.68,65 60.16,64.52 60.16,62.51 60.42,62.26 60.42,61.12 60.36,61.05 60.36,59.8 60.38,59.77 60.38,58.5 61.03,57.84 61.13,57.84 v2(61.33,57.64)
  BOTTOM w0.089: v2(58.39,67.47) 58.74,67.47 58.89,67.32 59.3,67.32 59.48,67.5 59.6,67.5 59.79,67.69 U20.AT5
  BOTTOM w0.127: v2(61.33,57.64) 61.28,57.59 R435.2 R438.1
BOARD_ID4: length 11
  TOP w0.076: 64.74,73.59 64.41,73.92 64.41,74.12 64.13,74.4 v1(63.64,74.4) 63.19,74.4 62.41,73.63 60.76,73.63 60.65,73.74 60.24,73.74 v2(59.81,73.31)
  TOP w0.127: 64.74,73.59 64.74,72.72 65.11,72.34 66.79,72.34 v2(66.87,72.42)
  BOTTOM w0.127: R358.1 67.05,72.24 v2(66.87,72.42) 66.69,72.24 R359.2 ; v2(59.81,73.31) 60.18,72.94 U20.AG5
BOARD_ID5: length 15
  TOP w0.076: 65.27,76.43 65.52,76.43
  TOP w0.089: v2(59.71,76.14) 60.15,76.59 60.67,76.59 60.83,76.43 62.51,76.43 62.87,76.79 64.91,76.79 65.27,76.43
  TOP w0.127: 65.52,76.43 65.78,76.43 66.41,75.8 68.7,75.8 68.84,75.66 v1(69.21,75.66) 69.35,75.52 70.17,75.52 70.31,75.66 70.72,75.66 71.3,75.08 71.3,74.97 v2(71.52,74.76)
  BOTTOM w0.127: R336.2 71.02,74.68 71.44,74.68 v2(71.52,74.76) 71.66,74.9 R325.1 ; v2(59.71,76.14) 59.53,75.96 U20.AB6
BPM#2: length 3
  TOP w0.127: TP14.1 23.61,84.31 24.77,83.16 v2(25.19,83.16)
  BOTTOM w0.127: U20.H61 25.49,83.46 v2(25.19,83.16)
BPM#3: length 4
  TOP w0.127: TP15.1 21.84,83.46 v2(22.29,83)
  BOTTOM w0.076: 23.36,83.6 23.69,83.6 24.05,83.24 24.54,83.24 U20.H62
  BOTTOM w0.127: v2(22.29,83) 22.89,83.6 23.36,83.6
BPM#4: length 1.3
  TOP w0.127: v2(26.49,81.66) 26.41,81.74 TP17.1
  BOTTOM w0.127: v2(26.49,81.66) 26.79,81.96 U20.K59
BPM#5: length 6.4
  BOTTOM w0.127: U20.H63 24.14,83.53 23.84,83.83 22.7,83.83 22.32,83.44 20.79,83.44 20.53,83.71 20.17,83.71 19.65,84.23 19.12,84.23 18.69,83.8 TP84.1
BPM#6: length 2.3
  TOP w0.127: TP16.1 25.09,82.4 v2(25.84,81.66)
  BOTTOM w0.127: v2(25.84,81.66) 25.84,81.77 U20.K60
BPM#7: length 7
  TOP w0.127: TP24.1 20.54,81.86 v2(21.66,82.97)
  BOTTOM w0.076: U20.J61 25.23,82.49 24.05,82.49 24.05,82.49 23.27,82.49 23.26,82.5
  BOTTOM w0.127: v2(21.66,82.97) 22.08,82.56 22.7,82.56 22.75,82.5 23.26,82.5
BQACDRV: length 2.6
  BOTTOM w0.254: PU7.4 168.28,95.86 167.86,95.45 v2(167.86,95.36) 167.9,95.36 PR107.1
BQB_1: length 5.2
  BOTTOM w0.508: PD4.1 172.95,103.38 173.47,102.85 173.47,101.99 173.32,101.83 PR86.1 173.32,100.79 v2(172.66,100.13) 173.03,100.13 PC103.1
BQB_2:
  vias: v2(171.44,99.29)
BQBATDRV: length 22.4
  IN1 w0.254: v2(167.43,100.58) 167.3,100.46 167.3,97.34 167.78,96.86 172.26,96.86 173.19,97.8 175.07,97.8 176.62,96.25 179.12,96.25 v2(180.33,97.47)
  BOTTOM w0.254: PR104.2 180.83,95.14 v2(180.69,95.28) 180.33,95.64 v2(180.33,97.47) ; PU7.11 167.78,100.24 v2(167.43,100.58)
BQCLK: length 1.6
  BOTTOM w0.254: PU7.9 165.85,98.52 PR95.1
BQCMSRC: length 2.4
  BOTTOM w0.254: PR106.1 169.16,95.11 v2(169.16,95.36) 168.78,95.74 PU7.3
BQDATA: length 2.8
  BOTTOM w0.254: PU7.8 166.49,98.02 166.37,98.14 165.22,98.14 PR96.1
BQHIDRV: length 13.6
  TOP w0.762: v5(181.78,108.39) 181.78,107.83 v1(180.38,106.43) 178.35,104.4 177.16,104.4 172.59,99.83 v5(172.59,99.29)
BQIOUT: length 2.9
  BOTTOM w0.254: PR99.2 164.83,97.4 165.08,97.14 PC113.1 165.98,97.52 PU7.7
BQLODRV: length 11.9
  TOP w1.016: 170.68,101.07 170.93,101.33 172.53,101.33 176.8,105.59 v1(177.74,105.59) 179.82,107.68
  vias: v2(169.89,101.22) v2(169.89,100.59) v2(180.47,108.21) v2(181.02,108.56)
BQPHASE: length 6.9
  TOP w0.762: v5(172.71,98.15) 173.22,98.15 173.98,98.91 173.98,99.42 v1(175.91,101.35) v5(177.41,102.85)
BQSRN: length 1.6
  BOTTOM w0.127: PR80.2 168.28,100.8 PU7.12
BQSRP: length 1.5
  BOTTOM w0.127: PU7.13 168.78,101.06 PR79.2
BQVCC: length 4.9
  BOTTOM w0.254: PU7.20 170.94,97.02 171.26,96.7
  BOTTOM w0.508: PR100.2 173.91,96.94 173.35,96.37 PC115.1 v4(172.13,96.37) 171.59,96.37 171.26,96.7
BT_COMBO_EN#: length 251
  TOP w0.076: v2(63.59,77.56) 63.59,77.56 63.86,77.83 TP30.1
  TOP w0.127: v2(262.49,95.36) 261.45,96.4 261.45,100.63 262.63,101.81 262.63,105.09 261.1,106.61 261.1,109.48 260.47,110.11 258.06,110.11 256.38,108.44 249.75,108.44 246.3,104.98 v2(236.01,104.98) ; v2(127.12,99.98) 125.47,98.33 123.11,98.33 120.59,95.82 119.72,95.82 115.66,91.76 115.66,91.74 115.37,91.45 114.79,91.45 114.11,92.13 111.16,92.13 111.02,91.99 109.12,91.99 109.12,91.99 108.8,91.99 106.31,91.99 106.31,91.99 105.47,91.99 105.47,91.99 103.73,91.99 103.73,91.99 103.67,91.99 103.15,92.51 103,92.51 102.68,92.51 90.21,92.51 87.24,92.51 85.94,91.22 84.89,91.22 84.89,91.22 84.58,91.22 83.31,91.22 79.78,87.69 v2(79.19,87.69)
  IN1 w0.127: v2(79.19,87.69) 79.19,87.69 78.96,87.46 78.58,87.46 78.22,87.1 77.69,87.1 74.33,83.74 73.61,83.74 73.32,83.45 73.32,82.31 72.81,81.8 72.81,81.68 72.81,81.05 71.35,79.58 70.28,79.58 69.97,79.28 68.45,79.28 67.76,78.59 66.08,78.59 65.93,78.75 65.17,78.75 63.9,77.48 63.68,77.48 v2(63.59,77.56)
  IN2 w0.127: v2(236.01,104.98) 235.17,104.14 223.63,104.14 223.37,103.89 222.53,103.89 218.69,103.89 218.46,104.12 218.31,104.12 218.13,104.3 217.39,104.3 216.84,104.84 216.84,105.36 216.6,105.6 216.6,105.62 216.2,106.02 216.18,106.03 215.97,106.03 215.97,106.02 214.75,106.02 214.72,106.05 214.61,106.05 212.53,108.13 209.92,108.13 209.54,108.51 206.95,108.51 206.52,108.08 203.9,108.08 203.87,108.06 203.85,108.06 202.48,106.69 192.27,106.69 191.99,106.69 191.78,106.69 191.73,106.63 191.7,106.63 190.38,105.31 187.75,105.31 185.93,103.5 182.83,103.5 181.88,102.55 179.18,102.55 172.75,96.11 166.9,96.11 165.28,97.74 156.8,97.74 154.18,100.36 144.06,100.36 143.5,100.92 143.5,103.89 141.98,105.42 138.88,105.42 136.86,103.4 136.28,103.4 135.65,104.02 134.49,104.02 133.06,102.6 132.07,102.6 129.45,99.98 v2(127.12,99.98)
  BOTTOM w0.076: U20.U4 61.21,77.86 61.76,77.86 61.83,77.79 63.26,77.79 63.48,77.56 v2(63.59,77.56)
  BOTTOM w0.127: R124.2 262.39,93.96 262.6,94.18 262.6,95.24 v2(262.49,95.36) ; v2(79.19,87.69) 79.19,87.82 79.7,88.32 79.7,89.14 79.7,89.32 79.6,89.42 R188.1
BT_OFF: length 258.1
  TOP w0.127: v2(131.45,84.38) 131.45,84.2 130.14,82.89 105.68,82.89 103.14,85.43 96.71,85.43 95.34,86.8 93.06,86.8 92.48,87.38 89.1,87.38 87.99,86.28 87.45,86.28 84.67,83.49 84.67,81.32 82.8,79.46 v2(81.57,79.46) ; v2(259.91,109.61) 259.91,108.62 258.84,107.55 258.84,102.55 260.11,101.28 260.11,99.22 259.12,98.23 259.12,96.37 258.36,95.61 256.77,95.61 253.81,92.65 253.81,90.16 251.32,87.67 251.32,86.98 250.86,86.52 249.03,86.52 248.82,86.52 248.61,86.52 248.09,86.52 246,84.43 244.98,84.43 244.21,85.2 238.24,85.2 237.61,84.56 234.77,84.56 234.08,85.25 233.36,85.25 233.33,85.29 233.31,85.29 232.06,86.53 232.04,86.53 231.45,86.53 230.94,87.04 230.94,87.27 230.57,87.64 230.47,87.64 229.51,88.6 229.51,88.6 v2(229.3,88.8)
  IN2 w0.127: v2(131.45,84.38) 131.45,84.45 131.95,84.94 132.45,84.94 132.54,84.85 153.44,84.85 157.42,80.88 161.66,80.88 162.27,81.49 163.44,81.49 164.46,80.47 170.56,80.47 171.19,80.47 172.01,81.29 173.35,81.29 173.35,81.29 175.35,81.29 179.06,84.99 180.83,84.99 182.77,86.93 182.77,88.04 187.97,93.24 190.96,93.24 191.89,94.16 192.07,94.16 192.07,94.16 192.28,94.16 194.46,94.16 194.82,94.52 197.39,94.52 198.64,95.76 199.45,95.76 199.87,95.76 200.18,96.07 202.66,96.07 203.88,97.29 205.5,97.29 206.04,96.75 206.77,96.75 207.26,97.24 208.17,97.24 209.02,98.09 212.6,98.09 213.19,97.5 218.57,97.5 220.26,95.81 220.26,90.25 221.01,89.5 221.45,89.5 222.75,88.19 227.28,88.19 228.22,89.14 228.86,89.14 228.87,89.13 228.97,89.13 v2(229.3,88.8)
  BOTTOM w0.076: 64.43,69.4 64.23,69.6 63.14,69.6 63.04,69.71 62.32,69.71 62.31,69.7 61.85,69.7 U20.AM3
  BOTTOM w0.127: Q2.2 259.91,112.17 v2(259.91,109.61) ; v2(81.57,79.46) 81.65,79.38 81.65,77.83 76.9,73.08 76.9,70.77 75.84,69.7 75.74,69.6 74.74,69.6 73.94,68.8 72.9,68.8 TP93.1 72.62,69.08 71,69.08 70.34,68.42 68.23,68.42 68.15,68.5 66.15,68.5 65.89,68.75 R374.1 65.36,69.4 64.43,69.4
BUTTON_ONKEY_R: length 5.9
  BOTTOM w0.127: U4.4 208.47,111.83 208.32,111.97 v1(206.63,111.97) 205.06,111.97 R27.2 204.5,111.59 203.41,111.59 R28.1
C_TX0_HDMI+: length 9.1
  BOTTOM w0.127: CN6.22 251.25,88.4 251.25,89.16 251.35,89.26 251.35,89.86 252.98,91.49 252.98,92.07 253.41,92.51 253.41,93.52 254.5,94.61 254.5,94.71 R117.1 254.48,95.22 254.48,95.65 254.4,95.72 C102.2
C_TX0_HDMI-: length 9.2
  BOTTOM w0.127: CN6.23 251.75,89.06 251.58,89.24 251.58,89.77 253.2,91.39 253.2,91.98 253.64,92.41 253.64,93.43 254.73,94.52 254.73,94.69 R117.2 254.71,95.29 254.71,95.7 C101.2
C_TX1_HDMI+: length 5.7
  BOTTOM w0.127: CN6.25 252.75,89.2 252.87,89.32 252.87,89.67 253,89.79 v2(253,90.51) 253.72,90.51 254.25,91.04 254.25,91.54 R157.1 254.3,92.11 254.3,92.53 C143.2
C_TX1_HDMI-: length 5.6
  BOTTOM w0.127: C142.2 254.53,92.48 254.53,92.04 R157.2 254.47,91.51 254.47,90.94 253.9,90.37 253.9,89.61 v2(253.9,89.61) 253.89,89.61 253.23,89.61 253.1,89.48 253.1,89.34 253.25,89.2 CN6.26
C_TX2_HDMI+: length 5.8
  BOTTOM w0.127: C141.2 256.3,92.42 256.3,92.09 R156.1 256.28,91.54 256.28,91.42 256.15,91.29 255.57,91.29 254.44,90.16 254.44,89.19 254.25,89.01 CN6.28
C_TX2_HDMI-: length 5.8
  BOTTOM w0.127: CN6.29 254.75,89.01 254.66,89.1 254.67,89.1 254.67,90.06 255.67,91.06 256.25,91.06 256.53,91.35 256.53,91.54 R156.2 256.53,92.06 256.53,92.45 C140.2
C_TXC_HDMI+: length 5.5
  BOTTOM w0.127: CN6.19 249.75,88.96 249.92,89.13 249.92,89.51 251.83,91.42 251.83,91.54 R158.1 251.83,92.06 251.83,92.45 C145.2
C_TXC_HDMI-: length 5.5
  BOTTOM w0.127: C144.2 252.06,92.42 252.06,92.09 R158.2 252.06,91.51 252.06,91.33 250.15,89.41 250.15,89.11 250.25,89.01 CN6.20
CAP+: length 5.3
  BOTTOM w0.203: U18.28 213.72,81.12 v1(213.1,80.5) 212.98,80.38 212.98,80.24 212.47,79.74 211.04,79.74 C248.2
CAP-: length 3.5
  BOTTOM w0.203: U18.27 213.92,80.72 212.36,79.15 C248.1
CATERR#: length 3.3
  TOP w0.127: v2(23.49,81.83) 23.36,81.7 TP21.1
  BOTTOM w0.076: v2(23.49,81.83) 23.58,81.74 24.31,81.74 24.48,81.91 24.48,82.09 24.71,82.32 25.23,82.32 U20.K61
CFG0: length 15.2
  IN1 w0.127: v2(26.49,75.66) 26.49,75.62 25.77,74.91 25.11,74.91 23.56,73.36 23.21,73.36 22.34,72.5 19.22,72.5 18.81,72.09 17.9,72.09 17.61,72.37 17.12,72.37 15.92,71.18 v2(15.69,71.18)
  BOTTOM w0.127: U20.AC60 26.14,75.31 v2(26.49,75.66) ; R366.1 14.51,70.63 TP91.1 15.05,71.18 v2(15.69,71.18)
CFG1: length 31.9
  TOP w0.127: TP60.1 4.49,64.45 6.09,64.45 6.25,64.28 10.12,64.28 10.3,64.47 v2(10.3,65.18) 10.43,65.31 11.35,65.31 11.85,65.82 11.85,66.96 12.01,67.11 CN1.36
  IN1 w0.127: v2(21.89,74.34) 21.88,74.34 21.44,73.89 20.39,73.89 19.75,73.26 18.22,73.26 17.84,72.88 16.91,72.88 16.82,72.79 15.75,72.79 15.35,72.38 15.35,71.8 14.01,70.46 14.01,68.18 11.02,65.18 v2(10.3,65.18)
  BOTTOM w0.076: U20.AC62 24.54,75 23.95,75 23.84,74.88 23.46,74.88 23.36,74.78 23.27,74.78 23.26,74.78
  BOTTOM w0.127: 23.26,74.78 23.25,74.76 22.41,74.76 21.99,74.34 v2(21.89,74.34)
CFG2: length 25
  TOP w0.127: v2(9.64,65.94) 11.81,68.11 CN1.38 ; TP37.1 20.95,74.64 v2(21.25,74.34)
  IN1 w0.127: v2(9.64,65.94) 10.03,66.32 10.79,66.32 13.61,69.14 13.61,71.35 14.64,72.38 14.99,72.38 15.65,73.04 16.71,73.04 16.81,73.14 17.73,73.14 18.11,73.51 19.65,73.51 20.47,74.34 v2(21.25,74.34)
  BOTTOM w0.076: U20.AC63 23.99,75.29 23.79,75.09 23.26,75.09
  BOTTOM w0.127: 23.26,75.09 23.21,75.04 22.32,75.04 22.06,74.78 21.7,74.78 v2(21.25,74.34)
CFG3: length 24.5
  TOP w0.127: v2(10.94,67.92) 11.17,67.92 11.86,68.61 CN1.39
  IN1 w0.127: v2(22.28,75.48) 21.84,75.93 20.62,75.93 19.23,74.53 18.25,74.53 18.12,74.67 17.26,74.67 16.45,73.86 15.09,73.86 v2(14.81,73.58) 14.72,73.49 14.67,73.49 12.84,71.66 12.84,69.47 11.3,67.92 v2(10.94,67.92)
  BOTTOM w0.076: U20.AA63 24.16,76.06 23.34,76.06 23.28,76 23.26,76
  BOTTOM w0.127: R344.2 14.41,73.98 v2(14.81,73.58) ; 23.26,76 23.03,76 22.95,75.93 22.73,75.93 v2(22.28,75.48) 21.84,75.04 21.46,75.04 21.2,75.3 21.2,75.85 TP89.1 20.74,75.98 20.69,75.93 R323.1
CFG4: length 18
  TOP w0.127: v2(18.5,72.54) 17.66,72.54 TP46.1 17.33,72.21 v2(17.33,71.83) 16.57,71.83 16.36,71.62 15.51,71.62 15,71.11 CN1.44
  IN1 w0.127: v2(25.84,75.66) 25.84,75.35 25.65,75.16 24.99,75.16 23.44,73.61 23.1,73.61 22.24,72.75 18.71,72.75 v2(18.5,72.54)
  BOTTOM w0.127: v2(25.84,75.66) 26.14,75.96 U20.AA60 ; R354.1 15.37,72.83 16.07,72.83 17.07,71.83 v2(17.33,71.83)
CFG5: length 16.4
  TOP w0.127: CN1.45 14.43,71.61 14.67,71.37 14.89,71.37 15.4,71.87 16.18,71.87 19.21,74.9 v2(19.21,75.15) 17.98,76.38 17.95,76.38 TP33.1
  IN1 w0.127: v2(19.21,75.15) 20.25,76.18 22.53,76.18 22.98,76.62 v2(22.98,76.79)
  BOTTOM w0.076: 23.26,76.56 23.4,76.42 23.88,76.42 23.95,76.49 24.31,76.49 24.6,76.79 U20.Y62
  BOTTOM w0.127: 23.26,76.56 23.03,76.79 v2(22.98,76.79)
CFG6: length 16.9
  TOP w0.127: TP42.1 16.93,73.34 v2(15.92,72.32) 15.84,72.32 15.55,72.61 CN1.47
  IN1 w0.127: v2(25.19,77.16) 24.2,76.18 24.2,75.4 23.59,74.78 22.98,74.78 22.09,73.89 21.86,73.89 21.61,73.64 20.49,73.64 19.86,73 18.32,73 17.94,72.63 17.02,72.63 16.87,72.48 16.11,72.48 15.94,72.32 v2(15.92,72.32)
  BOTTOM w0.127: v2(25.19,77.16) 25.49,76.86 U20.Y61
CFG7: length 15.5
  TOP w0.127: v2(17.47,74.22) 17.47,74.45 TP36.1 16.5,74.66 16.5,74.4 15.21,73.11 CN1.48
  IN1 w0.127: v2(17.47,74.22) 17.52,74.27 19.33,74.27 20.54,75.48 v2(21.65,75.48)
  BOTTOM w0.076: 25.82,76.43 25.38,76.43 25.32,76.49 24.57,76.49 24.4,76.33 24.04,76.33 23.95,76.24 23.35,76.24 23.33,76.26 23.26,76.26
  BOTTOM w0.089: U20.Y60 25.82,76.43
  BOTTOM w0.127: 23.26,76.26 22.6,76.26 22.42,76.08 22.24,76.08 v2(21.65,75.48)
CFG8: length 27.1
  TOP w0.127: v2(22.34,76.69) 22.34,77.12 22.09,77.37 TP31.1 ; CN1.26 6.41,66.61 6.01,67.01 v2(5.86,67.01)
  IN1 w0.127: v2(5.86,67.01) 5.88,67.01 9.73,70.86 11.32,70.86 13.98,73.52 13.98,73.73 14.61,74.36 15.95,74.36 16.38,74.79 16.38,75.05 17.39,76.07 18.52,76.07 18.72,75.86 19.11,75.86 19.75,76.5 19.77,76.5 20.4,77.13 22.03,77.13 22.34,76.81 v2(22.34,76.69)
  BOTTOM w0.076: 23.26,77.22 23.82,77.22 23.96,77.08 24.48,77.08 24.84,77.44 U20.V62
  BOTTOM w0.127: v2(22.34,76.69) 22.34,76.84 22.74,77.23 23.25,77.23 23.26,77.22
CFG9: length 29
  TOP w0.127: CN1.25 6.42,67.11 v2(5.88,67.65) 5.48,67.65 4.56,68.56 TP54.1
  IN1 w0.127: v2(25.84,77.16) 25.37,77.63 25.02,77.63 24.78,77.39 20.3,77.39 19.66,76.75 18.26,76.75 17.83,76.32 17.29,76.32 16.12,75.15 16.12,74.89 15.85,74.62 14.51,74.62 13.73,73.84 13.73,73.62 11.21,71.11 9.35,71.11 v2(5.88,67.65)
  BOTTOM w0.127: U20.V61 25.49,77.51 v2(25.84,77.16)
CFG10: length 30
  TOP w0.127: TP53.1 4.18,69.7 5.58,68.31 v2(5.91,68.31) 6.1,68.11 CN1.23
  IN1 w0.127: v2(5.91,68.31) 6.09,68.31 9.16,71.38 11.12,71.38 13.47,73.73 13.47,74.13 15.49,76.15 15.84,76.15 16.13,75.86 16.46,75.86 17.18,76.57 17.71,76.57 18.15,77.01 19.56,77.01 20.19,77.64 24.67,77.64 24.99,77.96 25.7,77.96 v2(26.48,77.17)
  BOTTOM w0.127: U20.V60 26.14,77.52 v2(26.48,77.17)
CFG11: length 24.4
  TOP w0.127: v2(10.13,69.98) 8.76,68.61 CN1.22 ; TP32.1 v2(21.7,76.69)
  IN1 w0.127: v2(10.13,69.98) 10.13,70.34 10.38,70.59 11.41,70.59 14.23,73.41 14.23,73.63 14.72,74.11 16.06,74.11 16.63,74.68 16.63,74.94 17.5,75.81 18.42,75.81 18.62,75.61 19.22,75.61 19.85,76.24 19.87,76.24 20.32,76.69 v2(21.7,76.69)
  BOTTOM w0.076: U20.U60 25.82,77.93 24.82,77.93 24.48,77.59 24.48,77.36 24.36,77.24 24.05,77.24 23.87,77.42 23.59,77.42 23.53,77.49 23.26,77.49
  BOTTOM w0.127: v2(21.7,76.69) 22.15,77.15 22.29,77.15 22.63,77.49 23.26,77.49
CFG12: length 28
  TOP w0.127: v2(10.08,72.04) 10.08,72.01 9.17,71.11 CN1.17 6.38,71.11 6.01,71.48 5.07,71.48 4.69,71.1 TP50.1
  IN1 w0.127: v2(10.08,72.04) 9.15,72.04 8.63,72.57 8.63,73.54 8.97,73.88 10.75,73.88 11.17,73.46 11.77,73.46 12.46,74.15 12.46,74.56 15.41,77.51 15.57,77.51 15.64,77.59 17.29,77.59 17.72,78.02 19.13,78.02 19.77,78.66 21.9,78.66 22.73,79.48 23.17,79.48 v2(23.61,79.04)
  BOTTOM w0.127: U20.T63 24.18,79.04 v2(23.61,79.04)
CFG13: length 27.3
  TOP w0.127: CN1.16 8.63,71.61 9.72,72.7 v2(10.08,72.7) ; v2(22.98,79.04) 22.32,79.7 22.32,80.78 21.96,81.13 TP19.1
  IN1 w0.127: v2(10.08,72.7) 9.19,72.7 8.88,73 8.88,73.44 9.07,73.63 10.65,73.63 11.07,73.21 11.87,73.21 12.71,74.05 12.71,74.45 15.52,77.26 15.67,77.26 15.75,77.34 17.4,77.34 17.83,77.77 19.24,77.77 19.87,78.4 22.03,78.4 22.66,79.04 v2(22.98,79.04)
  BOTTOM w0.127: U20.T62 24.47,78.67 23.94,78.67 23.87,78.59 23.42,78.59 v2(22.98,79.04)
CFG14: length 24.8
  TOP w0.127: v2(9.39,73.17) 9.27,73.05 8.96,73.05 8.52,72.61 CN1.14 6.38,72.61 6.31,72.69 5.43,72.69 5.11,72.37 TP47.1
  IN1 w0.127: v2(25.19,78.67) 24.96,78.67 24.44,78.15 19.98,78.15 19.34,77.51 17.93,77.51 17.5,77.08 15.85,77.08 15.78,77.01 15.62,77.01 12.96,74.34 12.96,73.94 11.98,72.95 10.96,72.95 10.55,73.36 9.58,73.36 v2(9.39,73.17)
  BOTTOM w0.127: v2(25.19,78.67) 25.49,78.97 U20.T61
CFG15: length 26.8
  TOP w0.127: TP41.1 4.88,72.94 6.17,72.94 6.34,73.11 CN1.13 8.51,73.11 9.11,73.72 9.7,73.72 10.84,72.58 v2(10.84,72.52)
  IN1 w0.127: v2(10.84,72.52) 10.94,72.62 12.01,72.62 13.22,73.83 13.22,74.24 15.73,76.75 15.88,76.75 15.96,76.83 17.61,76.83 18.04,77.26 19.45,77.26 20.08,77.89 24.57,77.89 24.88,78.21 26.03,78.21 v2(26.48,78.67)
  BOTTOM w0.127: v2(26.48,78.67) 26.14,79.02 U20.T60
CFG16: length 27.2
  TOP w0.127: TP56.1 5.86,65.61 CN1.28 8.7,65.61 v2(9.01,65.92)
  IN1 w0.127: v2(9.01,65.92) 9.01,66.22 9.36,66.58 10.69,66.58 13.35,69.24 13.35,71.45 14.54,72.64 14.88,72.64 15.54,73.3 16.61,73.3 16.7,73.39 17.63,73.39 18,73.77 19.54,73.77 20.56,74.78 22.6,74.78 22.85,75.04 23.17,75.04 v2(23.61,75.48)
  BOTTOM w0.076: v2(23.61,75.48) 23.71,75.58 24.4,75.58 24.84,76.02 U20.AA62
CFG17: length 29.4
  TOP w0.127: TP58.1 5.05,66.02 5.95,65.11 CN1.29 8.86,65.11 v2(9.01,65.26)
  IN1 w0.127: v2(9.01,65.26) 8.81,65.26 8.48,65.59 8.48,66.22 9.09,66.83 10.58,66.83 13.1,69.35 13.1,71.56 14.43,72.89 14.78,72.89 15.44,73.55 16.5,73.55 16.59,73.64 17.52,73.64 17.9,74.02 19.44,74.02 20.45,75.04 22.48,75.04 22.93,75.48 v2(22.98,75.48)
  BOTTOM w0.076: U20.AA61 25.32,76.08 25.06,76.33 24.69,76.33 24.54,76.18 24.54,75.98 24.31,75.75 23.92,75.75 23.79,75.88 23.44,75.88 23.28,75.72 23.26,75.72
  BOTTOM w0.127: 23.26,75.72 23.02,75.48 v2(22.98,75.48)
CFG18: length 26.4
  TOP w0.127: TP27.1 21.71,79.3 21.52,79.11 v2(21.52,79.1) ; v2(5.76,70.34) 5.98,70.11 CN1.19
  IN1 w0.127: v2(5.76,70.34) 5.77,70.35 6.07,70.35 7.36,71.64 7.36,72.99 8.76,74.39 10.32,74.39 10.6,74.67 11.85,74.67 15.2,78.02 15.36,78.02 15.43,78.1 17.08,78.1 18.26,79.28 18.5,79.28 18.72,79.06 19.46,79.06 20,79.61 21.02,79.61 21.52,79.11 v2(21.52,79.1)
  BOTTOM w0.127: U20.U63 24.11,78.36 23.28,78.36 23.06,78.59 22.03,78.59 v2(21.52,79.1)
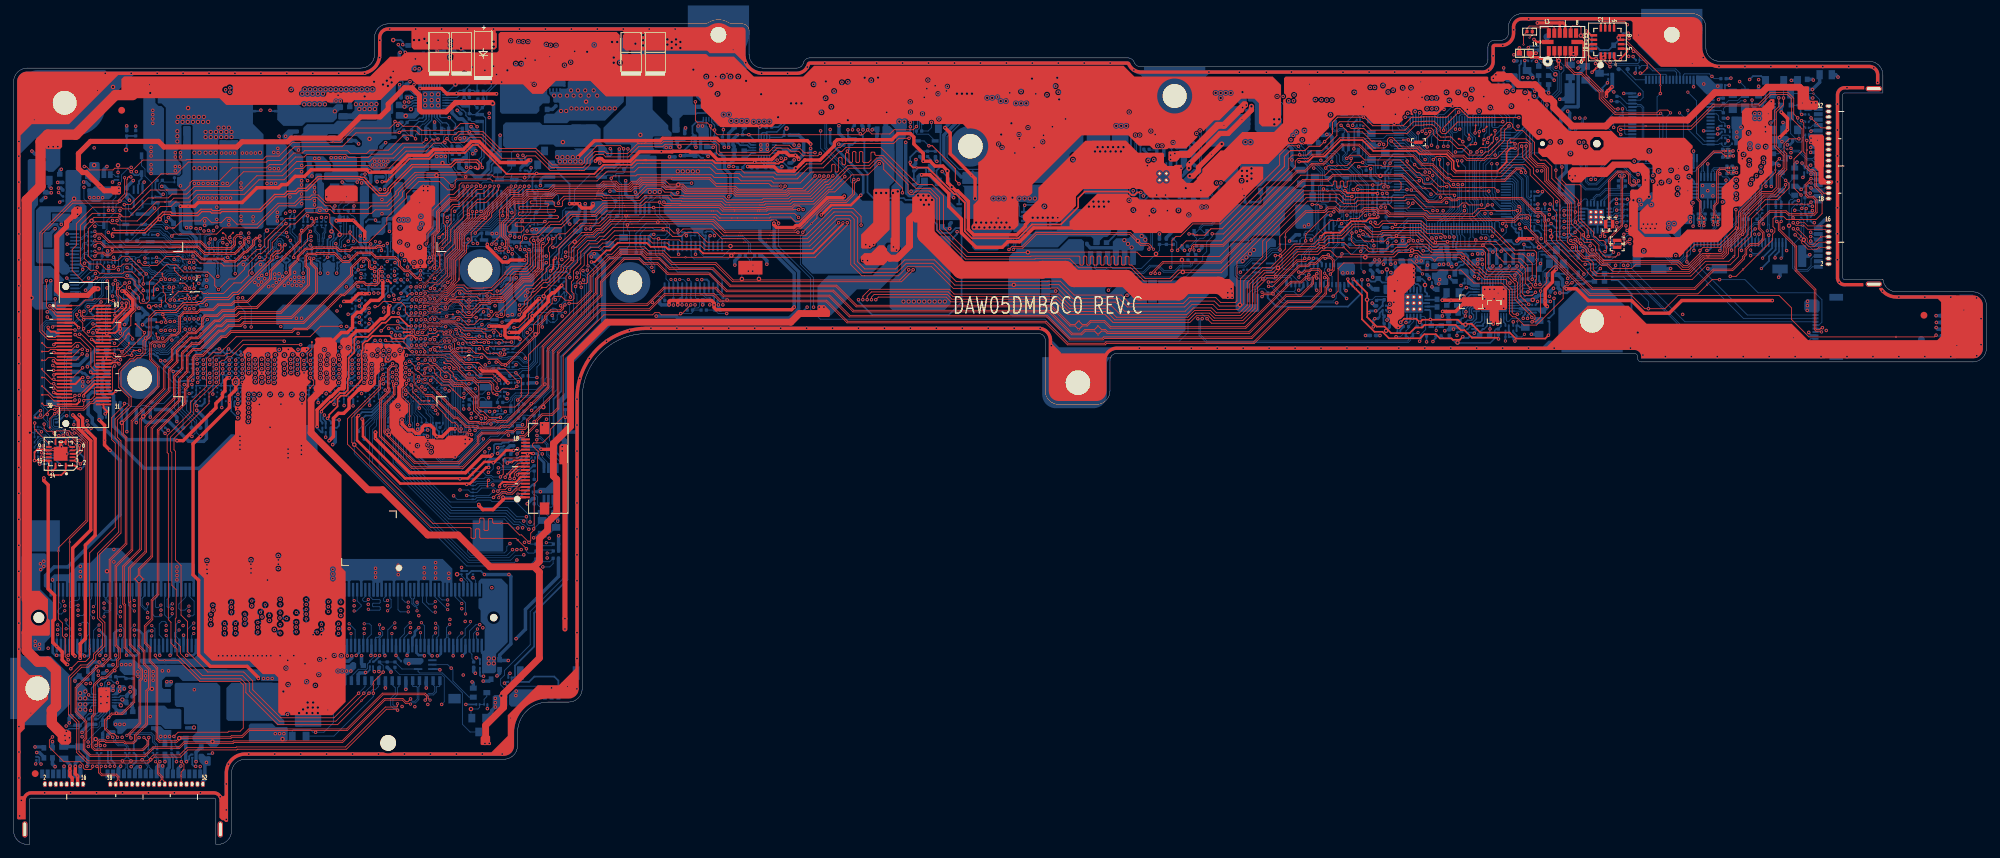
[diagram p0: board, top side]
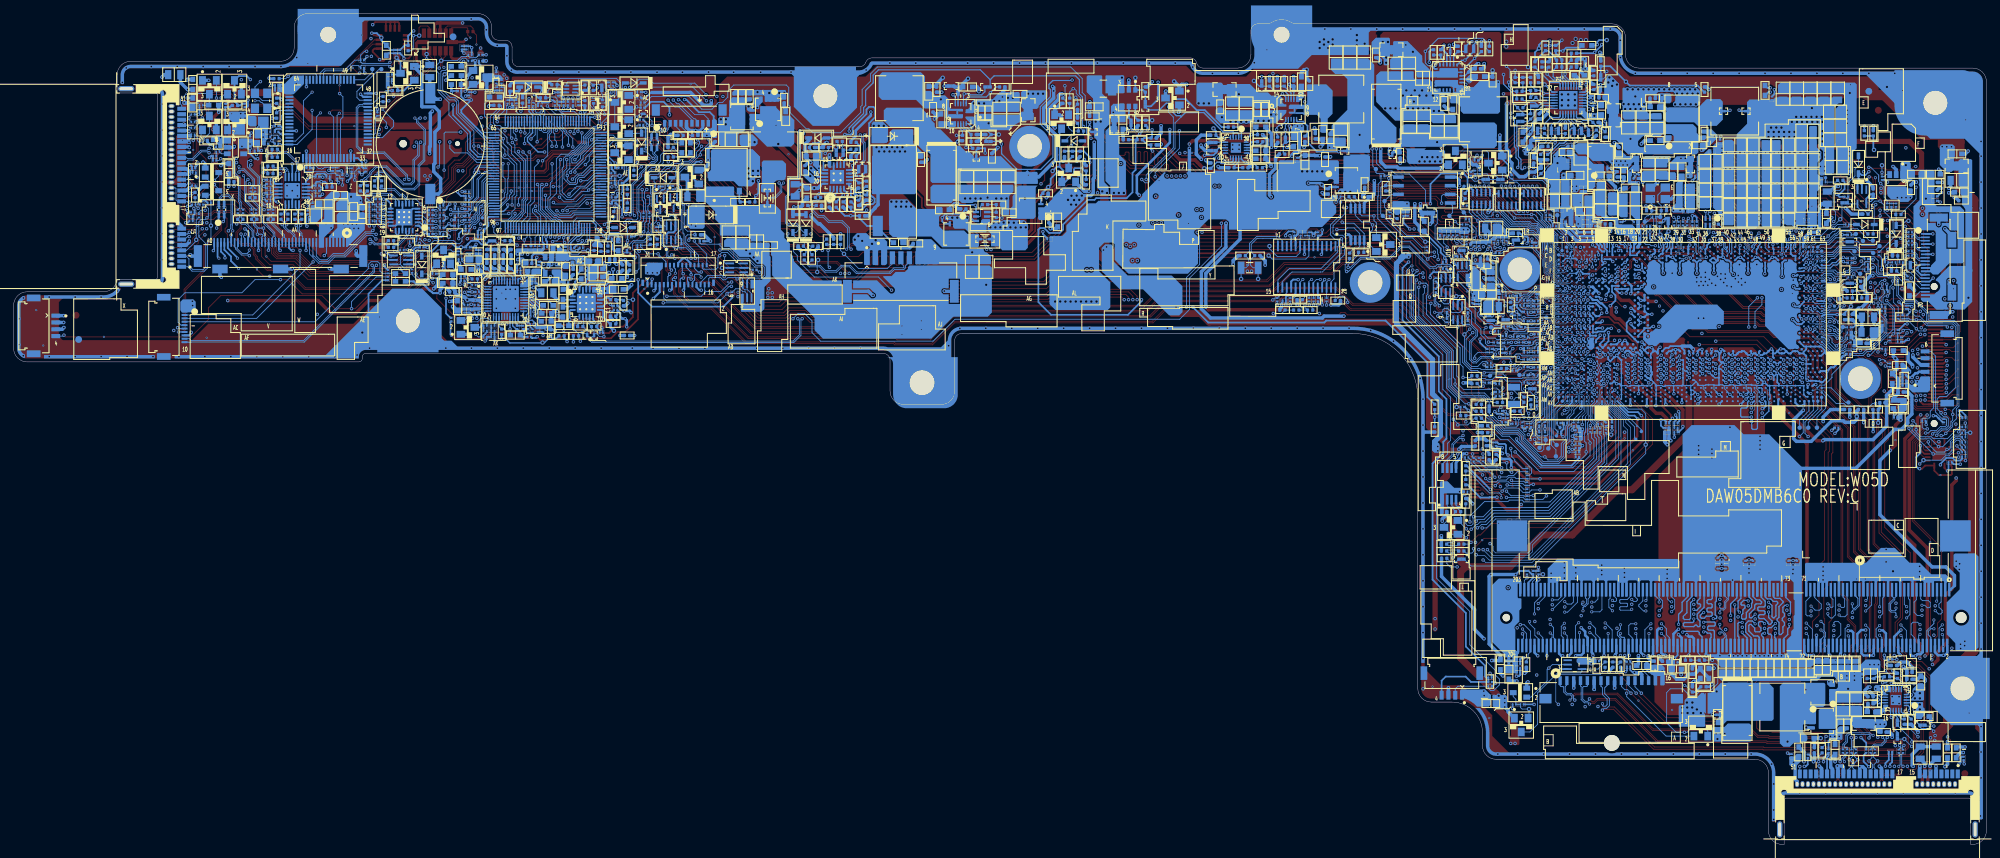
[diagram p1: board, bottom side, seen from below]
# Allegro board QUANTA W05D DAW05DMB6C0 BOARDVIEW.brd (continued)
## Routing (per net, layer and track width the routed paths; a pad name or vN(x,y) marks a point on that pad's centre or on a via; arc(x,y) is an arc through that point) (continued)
CFG19: length 27.7
  TOP w0.127: TP28.1 20.45,79.11 20.87,79.11 v2(20.88,79.1) ; CN1.20 v2(5.87,69.61)
  IN1 w0.127: v2(5.87,69.61) 6,69.61 7.61,71.23 7.61,72.89 8.86,74.14 10.86,74.14 11.28,73.72 11.66,73.72 12.2,74.26 12.2,74.66 15.31,77.77 15.46,77.77 15.54,77.84 17.19,77.84 17.62,78.28 19.03,78.28 19.85,79.1 v2(20.88,79.1)
  BOTTOM w0.127: U20.U62 24.7,78.29 24.38,77.96 24.05,77.96 23.87,78.14 23.13,78.14 22.93,78.34 21.65,78.34 v2(20.88,79.1)
CFG_RCOMP: length 5
  BOTTOM w0.254: U20.V63 24.04,77.68 23.89,77.68 23.77,77.81 v2(21.91,77.81) 21.43,77.81 21.4,77.84 R306.1 20.82,78.06 v4(19.88,79)
CHIP_DOCK_DET#: length 152.6
  TOP w0.127: v2(190.7,93.96) v1(191.36,93.96) 191.61,93.96 v2(191.99,93.58)
  IN2 w0.127: v2(75.43,75.16) 75.99,75.16 77.46,76.63 77.46,78.5 76.57,79.38 76.57,80.37 76.98,80.78 80.41,80.78 81.22,81.59 81.22,83.5 82.08,84.36 82.08,84.36 82.82,85.1 82.82,85.28 83,85.46 83,86.5 84.71,88.21 85.34,88.21 87.09,89.96 87.73,89.96 90.84,89.96 92.43,91.55 95.21,91.55 97.24,89.51 97.45,89.51 97.45,89.51 98.21,89.51 98.56,89.87 109.75,89.87 112.52,87.1 128.64,87.1 130.24,85.5 133.16,85.5 133.3,85.36 153.65,85.36 156.84,82.18 163.67,82.18 164.86,80.98 170.77,80.98 170.98,80.98 171.8,81.79 173.56,81.79 175.14,81.79 182.63,89.29 183.27,89.29 187.85,93.86 190.59,93.86 v2(190.7,93.96)
  BOTTOM w0.127: v2(75.43,75.16) 76.4,74.2 76.4,70.98 75.6,70.19 75.18,70.19 75.18,70.19 74.7,70.19 73.99,70.9 73.43,70.9 R365.1 ; Q16.3 192.51,89.5 191.66,90.35 191.66,93.25 v2(191.99,93.58)
CK_XDP_N: length 80.2
  TOP w0.127: CN1.10 6.27,74.61 6.1,74.44 5.18,74.44 4.18,75.44 4.18,89.67 8.68,94.16 15.39,94.16 16.63,95.4 16.63,97.59 16.74,97.71 16.74,97.91 16.86,98.02 v2(17.21,98.02)
  IN1 w0.114: v2(40.59,92.97) 40.61,92.97 40.98,93.35 40.98,93.86 41.55,94.42 41.55,101.17 41.09,101.63 41.09,102.14 40.53,102.7 35.32,102.7 31.89,106.13 29.55,106.13 27.78,107.9 23.48,107.9 22.39,106.82 22.39,105.42 16.74,99.76 16.74,98.04 16.88,97.9 17.04,97.9 17.16,98.02 v2(17.21,98.02)
  BOTTOM w0.127: RP4.1 40.59,92.26 40.86,92.53 40.86,92.7 v2(40.59,92.97)
CK_XDP_N_R: length 4.5
  BOTTOM w0.076: 41.32,88.5 41.41,88.41 41.41,87.86 41.53,87.74 41.53,87.53 41.74,87.31 41.88,87.31 41.96,87.24 U20.B35
  BOTTOM w0.127: RP4.2 40.59,89.79 41.32,89.06 41.32,88.5
CK_XDP_P: length 80.2
  TOP w0.127: v3(16.3,97.9) 16.3,95.54 15.25,94.49 8.54,94.49 3.85,89.8 3.85,75.31 5.05,74.11 CN1.11
  IN1 w0.114: v2(41.24,92.96) 41.24,93.75 41.8,94.32 41.8,101.28 41.34,101.73 41.34,102.24 40.64,102.95 35.43,102.95 32,106.38 29.66,106.38 27.88,108.16 23.37,108.16 22.14,106.93 22.14,105.52 16.49,99.87 16.49,98.09 v3(16.3,97.9)
  BOTTOM w0.127: RP4.3 41.24,92.39 41.19,92.44 41.19,92.92 v2(41.24,92.96)
CK_XDP_P_R: length 4.5
  BOTTOM w0.076: 41.65,88.5 41.56,88.41 41.56,87.92 41.68,87.8 41.68,87.59 41.81,87.47 41.91,87.47 41.96,87.52 U20.A35
  BOTTOM w0.127: RP4.4 41.24,90.45 41.16,90.38 40.99,90.38 40.92,90.3 40.92,89.93 41.65,89.19 41.65,88.5
CLK_24M_DEBUG: length 259
  IN1 w0.127: v2(263.82,95.64) 264.05,95.86 264.75,95.86 265.8,94.81 265.8,88.37 264.63,87.2 261.15,87.2 260.47,87.89 257.32,87.89 254.65,85.22 250.61,85.22 249.14,83.75 236.9,83.75 236.89,83.74 235.81,83.74 235.53,84.03 235.5,84.03 232.99,86.54 232.99,87.64 231.77,88.85 231.77,89.44 231.34,89.87 230.86,89.87 229.71,91.01 227.09,91.01 226.74,90.66 225.49,90.66 225.13,91.03 225.03,91.03 224.99,91.06 224.06,91.06 224.05,91.05 223.68,91.05 223.67,91.06 223.51,91.06 223.22,91.35 221.76,91.35 221.39,91.72 220.34,91.72 219.3,90.68 218.36,90.68 218.25,90.58 215.52,90.58 213.37,88.42 207.81,88.42 207.19,89.05 206.88,89.36 203.21,89.36 202.91,89.05 201.56,89.05 201.01,88.5 197.1,88.5 195.83,87.23 194.44,87.23 192.91,85.69 192.91,84.92 192.02,84.03 192.02,81.34 185.91,75.23 157.19,75.23 154.95,77.48 129.84,77.48 126.24,81.07 116.07,81.07 113.95,78.95 105.28,78.95 104.42,79.8 93.3,79.8 92.85,79.35 87.15,79.35 79.09,71.29 79.09,61.47 78.78,61.16 78.78,59.57 78.1,58.89 78.1,51.9 75.75,49.56 75.15,49.56 73.53,47.94 73.53,46.03 74.62,44.94 77.59,44.94 v3(78.22,44.3)
  BOTTOM w0.127: CN5.19 264.3,95.23 264.28,95.2 263.61,95.2 R110.2 263.71,95.75 v2(263.82,95.64) ; v3(78.22,44.3) 79.05,44.3 EC13.2 79.02,43.86 77.74,43.86 R453.2
CLK_24M_KBC: length 258.8
  TOP w0.127: v2(201.85,96.56) 201.39,97.01 200.8,97.01 200.62,96.83 v2(199.59,96.83) 197.37,96.83 v2(196.72,96.17)
  IN1 w0.127: v3(78.35,42.78) 77.84,42.27 77.84,41.64 78.35,41.13 78.35,28.1 78.48,27.97 80,27.97 80.13,28.1 80.13,31.98 80,32.11 79.29,32.11 79.16,32.24 79.16,32.62 79.29,32.75 80,32.75 80.13,32.87 80.13,33.25 80,33.38 79.11,33.38 78.99,33.51 78.99,33.89 79.11,34.02 81.25,34.02 81.37,34.14 81.37,34.52 81.25,34.65 79.11,34.65 78.99,34.78 78.99,35.16 79.11,35.29 81.25,35.29 81.37,35.41 81.37,35.79 81.25,35.92 79.11,35.92 78.99,36.05 78.99,36.43 79.11,36.56 81.25,36.56 81.37,36.68 81.37,37.06 81.25,37.19 79.11,37.19 78.99,37.32 78.99,37.7 79.11,37.83 81.25,37.83 81.37,37.95 81.37,38.33 81.25,38.46 79.11,38.46 78.99,38.59 78.99,38.97 79.11,39.1 81.25,39.1 81.37,39.22 81.37,39.6 81.25,39.73 79.11,39.73 78.99,39.86 78.99,40.24 79.11,40.37 81.25,40.37 81.37,40.49 81.37,40.87 81.25,41 79.11,41 78.99,41.13 78.99,41.51 79.11,41.64 81.25,41.64 81.37,41.76 81.37,42.14 81.25,42.27 79.24,42.27 79.11,42.4 79.11,42.78 79.24,42.91 81.25,42.91 81.37,43.03 81.37,43.41 81.25,43.54 77.53,43.54 77.21,43.86 73.87,43.86 72.89,44.84 72.89,48.2 77.09,52.4 77.09,56.86 76.83,57.13 76.83,58.52 78.14,59.83 78.14,61.75 77.67,62.22 77.67,63.94 78.43,64.7 78.43,71.53 86.89,79.99 92.59,79.99 93.11,80.51 104.63,80.51 105.55,79.58 113.68,79.58 115.86,81.76 126.47,81.76 130.01,78.21 155.11,78.21 157.45,75.87 185.57,75.87 190.87,81.17 190.87,83.95 192.16,85.24 192.16,86.43 193.85,88.12 195.57,88.12 197.17,89.72 v2(197.17,89.95)
  BOTTOM w0.127: U7.12 v2(201.85,96.56) ; v2(196.72,96.17) 197.05,95.84 197.05,94.82 196.89,94.67 196.89,93.1 196.79,92.99 196.79,91.47 197.02,91.24 197.02,90.1 v2(197.17,89.95) ; R454.2 77.64,43.22 79.12,43.22 EC14.2 78.95,42.78 v3(78.35,42.78) ; R108.1 v2(199.59,96.83)
CLK_24M_TPM: length 7.7
  BOTTOM w0.127: U15.21 100.14,80.29 EC10.2 100.71,79.72 100.71,78.97 100.51,78.77 100,78.77 R298.2 ; R298.2 R297.2 ; R298.2 99.7,78.14 99.51,77.96 v2(97.96,77.96)
CLK_PCI_EC_R: length 50.9
  TOP w0.127: v2(54.28,69) 53.87,68.59 53.87,68.22 53.68,68.03 53.68,67.15 49.03,62.5 49.03,58.77 61.28,46.51 67.05,46.51 67.18,46.38 67.18,45.06 67.3,44.94 67.68,44.94 67.81,45.06 67.81,46.21 67.94,46.33 68.32,46.33 68.45,46.21 68.45,45.06 68.57,44.94 73.78,44.94 v1(74.03,44.68) v2(75.3,43.41)
  BOTTOM w0.127: v2(75.3,43.41) 75.3,43.03 75.56,42.78 76.41,42.78 R454.1 ; v2(54.28,69) 54.28,69.05 54.54,69.31 U20.AN15
CLK_PCI_LPC_R: length 103.5
  TOP w0.127: v2(99.43,79.23) 97.97,77.77 95.12,77.77 94.8,78.08 94.16,78.08 93.85,77.77 86.69,77.77 80.7,71.77 80.7,62.83 78.86,60.99 78.86,60.14 77.69,58.97 76.84,58.97 76.83,58.96 76.37,58.96 76.19,58.78 76.19,58.53 77.03,57.69 77.03,57.1 76.95,57.02 76.95,53.45 76.45,52.94 76.45,46.21 75.94,45.7 75.94,44.61 v2(75.68,44.35) 74.59,45.45 74.29,45.45 72.59,47.15 v1(71.62,47.15) 70.48,47.15 70.35,47.27 70.35,47.73 70.22,47.86 69.84,47.86 69.72,47.73 69.72,46.21 69.59,46.08 69.21,46.08 69.08,46.21 69.08,47.78 68.95,47.91 68.57,47.91 68.45,47.78 68.45,47.27 68.32,47.15 61.55,47.15 49.66,59.03 49.66,62.68 53.89,66.91 53.89,67.94 v2(54.29,68.34)
  BOTTOM w0.127: U20.AP15 54.61,68.66 v2(54.29,68.34) ; R298.1 98.92,78.71 v2(99.43,79.23) ; R453.1 75.94,44.1 v2(75.68,44.35)
CLK_PCIE_CRN: length 156.9
  TOP w0.127: v2(56.38,19.72) 56.25,19.84 54.74,19.84 48.87,13.98 32.86,13.98 32.76,13.87 25.57,13.87 24.5,12.81 20.65,12.81 19.79,11.94 10.81,11.94 9.26,13.49 9.26,17.85 8.07,19.04 8.07,24.57 9.85,26.35 10.78,26.35 11.73,27.29 11.73,27.92 13.07,29.27 13.07,32.43 12.31,33.19 12.31,42.74 15.44,45.86 15.44,59.13 14.9,59.66 14.9,62.45 16.93,64.48 16.93,65.61 15.44,67.11 15.44,69.65 17.09,71.3 17.53,71.3 18.02,71.79 18.51,71.79 18.99,72.27 18.99,73.94 19.85,74.81 19.85,77.46 20.81,78.42 23.73,78.42 24.87,79.56 26.92,79.56 27.09,79.74 27.62,79.74 28.2,80.32 31.45,80.32 32.21,81.08 32.86,81.08 37.76,85.98 37.76,86.44 38.46,87.14 38.97,87.14 39.26,87.43 39.26,87.99 39.18,88.07 v3(39.01,88.07)
  BOTTOM w0.127: v3(39.01,88.07) 39.16,88.07 39.26,88.17 39.26,88.5 39.13,88.63 39.01,88.63 38.57,88.19 38.57,87.64 38.24,87.3 38.12,87.3 38.07,87.25 38.07,87.07 U20.B41 ; v2(56.38,19.72) 56.13,19.97 55.77,19.97 55.36,20.38 55.36,21.45 56.05,22.14 56.05,22.99 55.6,23.44 CN13.8
CLK_PCIE_CRP: length 156.9
  TOP w0.127: v2(39.87,88.04) 39.67,88.04 39.59,87.97 39.59,87.3 39.11,86.81 38.6,86.81 38.09,86.3 38.09,85.85 33,80.75 32.35,80.75 31.59,79.99 28.34,79.99 27.75,79.41 27.23,79.41 27.05,79.23 25.01,79.23 23.87,78.08 20.95,78.08 20.19,77.32 20.19,74.67 19.32,73.81 19.32,72.13 18.65,71.46 18.15,71.46 17.67,70.97 17.22,70.97 15.77,69.52 15.77,67.25 17.26,65.75 17.26,64.34 15.23,62.31 15.23,59.8 15.77,59.26 15.77,45.73 12.64,42.6 12.64,33.33 13.4,32.57 13.4,29.13 12.06,27.79 12.06,27.16 10.91,26.01 9.98,26.01 8.4,24.43 8.4,19.18 9.59,17.99 9.59,13.63 10.95,12.27 19.65,12.27 20.52,13.14 24.37,13.14 25.43,14.2 32.62,14.2 32.72,14.31 48.73,14.31 54.6,20.17 56.28,20.17 56.38,20.27 v3(56.38,20.66)
  BOTTOM w0.127: v3(56.38,20.66) 56.38,20.43 56.25,20.3 55.91,20.3 55.69,20.51 55.69,21.32 56.38,22 56.38,23.02 56.6,23.24 CN13.7 ; v2(39.87,88.04) 39.72,88.04 39.59,88.17 39.59,88.66 39.3,88.96 38.87,88.96 38.68,88.77 38.68,88.59 38.37,88.28 38.37,87.74 38.17,87.53 38.12,87.53 38.07,87.58 U20.A41
CLK_PCIE_WLANN: length 267.3
  IN1 w0.114: v3(40.24,89.22) 40.43,89.41 41.29,89.41 42.13,90.25 42.13,92.79 43.68,94.34 43.68,96.63 45,97.95 50.56,97.95 50.84,97.67 51.88,97.67 51.99,97.77 57.55,97.77 60.09,100.31 65.52,100.31 65.93,100.72 68.88,100.72 70.4,102.24 73.17,102.24 73.55,102.62 78.88,102.62 79.09,102.82 107.79,102.82 108.35,103.38 117.16,103.38 117.8,102.75 120.46,102.75 121.1,103.38 128.8,103.38 129.28,103.87 131.04,103.87 131.59,104.41 132.57,104.41 133.3,105.15 135.98,105.15 137.14,106.31 142.73,106.31 146.8,102.24 156.31,102.24 157.73,103.66 163.47,103.66 165.07,105.26 167.11,105.26 167.36,105.01 173.07,105.01 173.7,105.64 181.89,105.64 183.96,107.71 187.84,107.71 188.57,108.44 202.61,108.44 203.83,109.66 205.76,109.66 206.21,110.11 209.72,110.11 210.13,109.71 212.51,109.71 213.56,108.67 214.34,108.67 214.65,108.97 215.34,108.97 216.1,109.73 220.32,109.73 221.48,110.89 229.34,110.89 231.06,109.17 234.92,109.17 235.2,109.45 248.96,109.45 249.52,110.01 250.59,110.01 250.97,109.63 254.12,109.63 254.63,110.14 257.73,110.14 260.98,106.89 260.98,103.4 261.87,102.52 261.87,101.15 260.85,100.13 260.85,94.62 263.01,92.46 263.01,89.89 263.41,89.49 263.67,89.49 v2(263.9,89.26)
  BOTTOM w0.076: U20.C41 38.07,86.62 37.71,86.98 37.71,87
  BOTTOM w0.127: v2(263.9,89.26) 264.15,89.26 264.59,88.83 CN5.11 ; 37.71,87 37.71,88.63 38.57,89.49 39.48,89.49 39.58,89.39 39.74,89.39 39.91,89.22 v3(40.24,89.22)
CLK_PCIE_WLANP: length 267.3
  IN1 w0.114: v2(263.9,89.9) 263.75,89.74 263.52,89.74 263.26,90 263.26,92.57 261.1,94.73 261.1,100.03 262.12,101.04 262.12,102.62 261.23,103.51 261.23,106.99 257.83,110.39 254.52,110.39 254.01,109.89 251.07,109.89 250.69,110.27 249.42,110.27 248.86,109.71 235.3,109.71 235.09,109.71 234.81,109.43 231.16,109.43 229.44,111.15 229.23,111.15 229.23,111.15 227.06,111.15 226.47,111.15 221.37,111.15 220.21,109.99 215.99,109.99 215.23,109.23 214.54,109.23 214.24,108.92 213.66,108.92 212.62,109.96 212.41,109.96 210.25,109.96 209.85,110.37 209.83,110.37 209.61,110.37 206.11,110.37 205.65,109.91 203.73,109.91 202.51,108.69 188.46,108.69 187.74,107.97 183.85,107.97 181.78,105.9 173.6,105.9 172.96,105.26 167.47,105.26 167.21,105.52 164.97,105.52 163.36,103.92 157.62,103.92 156.2,102.49 146.91,102.49 142.84,106.56 137.04,106.56 135.87,105.4 133.2,105.4 132.46,104.67 131.49,104.67 130.94,104.12 129.17,104.12 128.69,103.64 120.99,103.64 120.36,103 117.9,103 117.27,103.64 108.25,103.64 107.69,103.08 78.98,103.08 78.78,102.88 73.45,102.88 73.06,102.49 70.3,102.49 68.77,100.97 65.83,100.97 65.42,100.56 59.98,100.56 57.44,98.02 51.88,98.02 51.78,97.92 50.95,97.92 50.67,98.2 44.9,98.2 43.43,96.73 43.43,94.45 41.88,92.9 41.88,90.36 41.19,89.67 40.25,89.67 v2(40.07,89.85)
  BOTTOM w0.127: CN5.13 264.17,89.63 v2(263.9,89.9) ; U20.B42 37.38,86.87 37.38,88.76 38.44,89.82 39.62,89.82 39.72,89.72 39.95,89.72 v2(40.07,89.85)
CLKRUN#: length 194.7
  TOP w0.127: v2(115.94,93.22) 115.36,93.78 114.71,93.78 114.36,93.43 110.66,93.43 110.49,93.26 109.65,93.26 109.65,93.26 109.33,93.26 104.26,93.26 103.71,93.81 97.85,93.81 97.8,93.86 96.51,93.86 96.49,93.83 95.34,93.83 v2(94.86,94.32) 92.79,94.32 92.26,93.78 89.69,93.78 86.71,93.78 85.42,92.49 85.1,92.49 81.85,92.49 80.4,91.04 78.88,91.04 v1(78.56,90.72) 77.05,89.21 76.09,89.21 75.79,88.91 75.79,88.58 76.24,88.12 76.24,85.04 75.33,84.13 74.7,84.13 73.55,84.13 72.92,83.5 72.92,82.74 72.52,82.35 72.52,82.34 71.44,81.26 v2(71.01,81.26)
  IN1 w0.127: v2(71.01,81.26) 70.73,80.98 69.34,80.98 69.19,80.83 66.02,80.83 65.64,80.45 64.97,80.45 64.58,80.07 64.35,80.07 63.7,79.42 63.24,79.42 62.48,78.65 62.48,78.47 62,77.99 60.44,77.99 60.38,78.04 v2(60.38,78.06)
  IN2 w0.127: v2(115.94,93.22) 121.96,93.2 122.34,92.82 131.24,92.82 132.53,91.52 137.37,91.52 137.4,91.56 139.06,91.56 139.89,92.39 146.09,92.39 146.78,92.39 148.44,90.73 155.12,90.73 159.08,86.77 167.63,86.77 168.58,87.72 174.87,87.72 181.74,94.59 182.26,94.59 186.07,98.4 189.49,98.4 189.7,98.4 189.92,98.62 191.27,98.62 192.66,100.02 192.66,100.68 193.17,101.19 193.83,101.19 194.34,101.69 197.02,101.69 199.08,103.75 203.56,103.75 204.08,104.27 204.95,104.27 205.18,104.04 206.43,104.04 206.66,104.26 207.27,104.26 v2(207.4,104.39)
  BOTTOM w0.127: v2(94.86,94.32) 94.86,92.43 96.3,90.99 96.3,89.48 95.65,88.83 95.32,88.83 95.14,88.65 95.14,87.93 95.26,87.81 95.26,87.01 97.71,84.56 102.35,84.56 104.04,82.88 U15.15 ; U20.V5 60.18,77.86 v2(60.38,78.06) ; v2(71.01,81.26) 71.01,80.07 70.56,79.62 R290.2 ; v2(207.4,104.39) 207.4,104.89 207.1,105.19 U7.38
CPUOVERT: length 136.9
  TOP w0.127: v2(122.06,98.05) v1(121.49,97.48) 120.16,96.14 119.66,96.14 117.55,94.03 114.6,94.03 114.25,93.68 110.55,93.68 110.38,93.51 109.75,93.51 109.75,93.52 109.44,93.52 105.68,93.52 105.68,93.52 105.36,93.52 104.36,93.52 103.82,94.06 97.95,94.06 97.9,94.11 95.7,94.11 v2(95.5,94.32)
  IN2 w0.127: v2(188.03,110.06) 188.18,110.06 188.41,109.83 188.41,109.03 188.09,108.7 183.57,108.7 181.88,107.02 174.89,107.02 172.52,104.64 167.9,104.64 165.88,106.66 147.43,106.66 145.85,108.25 129.42,108.25 128.59,107.42 124.1,107.42 121.61,104.93 120.77,104.93 120.25,105.45 119.18,105.45 v2(118.51,104.78)
  BOTTOM w0.127: v2(95.5,94.32) 94.88,94.94 R113.1 94.38,95.13 93.84,94.59 93.63,94.59 93.32,94.29 93.32,94.07 U13.4 ; Q8.1 199.99,106.41 200.5,106.91 200.5,110.83 200.32,111 200.32,111.54 200.12,111.74 199.94,111.74 D2.2 198.39,111.82 197.83,112.37 196.36,112.37 195.78,111.79 189.68,111.79 188.03,110.14 v2(188.03,110.06) ; v2(122.06,98.05) 122.06,98.66 118.51,102.21 v2(118.51,104.78)
CPVSS: length 12.2
  TOP w0.508: v2(209.8,79.91) v1(211.09,79.91) 212.94,79.91 R10.1 211.75,78.26 v2(209.85,78.26)
  BOTTOM w0.254: v2(212.54,82.09) 212.86,82.4 C232.2 C227.2
  BOTTOM w0.508: v2(209.85,78.26) 210.38,78.26 C256.1 210.66,77.37 210.76,77.27 C261.1 ; v2(209.8,79.91) 210.43,80.54 C238.1
CRY1: length 14
  BOTTOM w0.127: v4(198.49,86.21) 199.16,86.88 R236.1 200.02,86.88 200.25,87.1 200.25,89.26 200.83,89.85 202.79,89.85 202.81,89.82 203.32,90.33 203.32,90.53 204.77,91.98 207,91.98 207.5,91.48 U7.122
CRY2: length 10.1
  BOTTOM w0.127: R228.1 C197.2 203.9,87.09 204.03,87.22 R227.2 v4(205.38,87.22) 206.22,87.22 206.77,86.67 207.76,86.67 208.27,87.18 208.27,88.35 207.1,89.52 U7.123
CSCOMP: length 50.6
  IN2 w0.254: v2(64.13,117.96) 61.89,117.96 61.05,117.12 58.34,117.12 55.69,114.48 55.51,114.48 52.84,111.82 32.63,111.82 31.92,111.1 v2(31.74,111.1)
  BOTTOM w0.178: PC14.1 63.62,113.65 63.62,112.76 63.42,112.55 62.48,112.55 61.79,111.87 PU3.19
  BOTTOM w0.254: PC14.1 63.09,114.19 63.09,115.13 PC11.1 63.37,115.41 63.37,115.58 64.35,116.56 PR2.1 65.52,115.8 65.52,115.69 PR12.1 66.29,116.31 v4(65.7,116.9) 65.7,117.4 65.14,117.96 v2(64.13,117.96) ; PR29.1 32.15,111.1 v2(31.74,111.1)
CSIN: length 41.5
  TOP w0.127: v3(167.38,87.41) 167.38,87.42 167.09,87.7 167.09,87.84 166.69,88.24 165.6,88.24 164,89.85 150.11,89.85 148.08,87.81 146.63,87.81 v2(146.17,87.36)
  BOTTOM w0.127: PU7.1 169.78,95.82 169.86,95.74 171.47,95.74 171.72,95.48 171.72,95.24 PC117.2 171.72,94.76 171.72,94.61 171.79,94.54 172.31,94.54 172.61,94.24 172.61,93.93 172.71,93.83 PC121.1 172.56,93.31 172.56,93.05 171.62,92.11 170.81,92.11 170,91.29 168.06,91.29 167.25,90.48 167.25,87.53 v3(167.38,87.41) ; v2(146.17,87.36) 146.89,88.08 146.89,88.8 146.82,88.88 PR116.1
CSIP: length 40.3
  TOP w0.127: v3(146.8,87.36) 147.01,87.56 148.2,87.56 150.23,89.59 163.88,89.59 165.48,87.99 166.57,87.99 166.84,87.72 166.84,87.53 v2(166.72,87.41)
  BOTTOM w0.127: v3(146.8,87.36) 146.8,87.62 147.17,87.99 147.17,88.75 147.3,88.88 PR115.1 ; PU7.2 169.28,95.95 169.74,95.48 171.35,95.48 171.47,95.36 171.47,95.29 PC117.1 171.44,94.74 171.44,94.52 171.67,94.29 172.19,94.29 172.36,94.12 172.36,93.93 172.25,93.83 PC122.2 172.31,93.36 172.31,93.17 171.5,92.36 170.71,92.36 169.92,91.57 167.97,91.57 167,90.6 167,87.69 v2(166.72,87.41)
CSON: length 20.6
  IN1 w0.127: v3(176.65,97.13) 176.9,97.39 176.9,97.64 173.88,100.67 172.22,100.67 170.9,99.34 169.21,99.34 168.29,100.26 168.29,102.31 v3(168,102.6)
  BOTTOM w0.127: PC83.2 v3(168,102.6) 168,102.09 PR80.1 166.87,101.97 PC89.1 ; v3(176.65,97.13) 176.9,96.88 176.9,95.8 177,95.7 177.9,94.8 178.94,94.8 179.02,94.72 PR105.1
CSOP: length 21.5
  IN1 w0.127: v2(168.65,102.6) 168.52,102.47 168.52,100.35 169.3,99.57 170.8,99.57 172.12,100.89 173.98,100.89 177.13,97.74 177.13,97.29 v2(177.28,97.13)
  BOTTOM w0.127: v2(170.53,101.45) 170.04,101.94 PC88.1 169.91,102.47 169.4,102.47 PR79.1 168.65,102.22 v2(168.65,102.6) 168.65,103.1 PC83.1 ; PR101.1 179.02,95.11 178.94,95.03 178,95.03 177.13,95.89 177.13,96.98 v2(177.28,97.13)
CSREF: length 5.6
  BOTTOM w0.178: PU3.17 60.99,111.93 61.87,112.81 v2(61.87,113.12) 61.87,113.64 61.59,113.93 61.59,114.54 PC12.2
  BOTTOM w0.254: PC12.2 PR10.1
CSSUM: length 10.2
  BOTTOM w0.178: PU3.18 61.39,111.9 62.34,112.85 PC14.2
  BOTTOM w0.254: PC14.2 PC11.2 62.34,115.29 63.24,116.18 PR3.1 62.25,116.56 v2(62.2,116.51) 61.71,117 59.73,117 PR1.1
DC_TEST_A3_B3: length 0.7
  BOTTOM w0.089: U20.B3 61.56,87.59 U20.A3
DC_TEST_A61_B61: length 0.7
  BOTTOM w0.127: U20.A61 25.43,87.39 25.5,87.32 U20.B61
DC_TEST_AY2_AW2: length 0.7
  BOTTOM w0.076: U20.AW2 62.15,65.2
  BOTTOM w0.089: 62.15,65.2 U20.AY2
DC_TEST_AY3_AW3: length 0.7
  BOTTOM w0.076: U20.AW3 61.55,65.69 U20.AY3
DC_TEST_AY61_AW61: length 6.7
  BOTTOM w0.127: U20.AW61 25.49,65.17 U20.AY61 25.41,63.75 26.89,62.26 26.89,60.45 27.44,59.9 v2(27.45,59.9)
DC_TEST_AY62_AW62: length 6.8
  BOTTOM w0.127: U20.AW62 24.84,65.17 U20.AY62 24.75,63.89 26.64,62.01 26.64,60.36 v2(26.18,59.9)
DC_TEST_B62_B63: length 0.7
  BOTTOM w0.076: U20.B62 24.32,86.99 U20.B63
DC_TEST_C1_C2: length 0.7
  BOTTOM w0.114: U20.C1 62.69,86.46 U20.C2
DCAP: length 1.8
  BOTTOM w0.203: PU6.16 108.34,101.52 107.51,100.69 PC96.2
DDR3_DRAMRST#: length 81.5
  IN1 w0.127: v2(13.53,27.74) 14.57,28.78 25.67,28.78 27.22,27.23 41.72,27.23 42.18,27.69 45.64,27.69 46.09,27.23 63.44,27.23 65.27,29.06 69.44,29.06 77.72,37.34 v2(77.72,40.75)
  BOTTOM w0.127: v2(13.53,27.74) 13.15,27.36 v2(13.15,27.16) C309.2 13.85,27.25 14.15,27.55 JDIM1.30 ; R456.2 77.85,41.51 78.72,41.51 R455.1 79.23,41.25 78.73,40.75 v2(77.72,40.75)
DDR_PG_CNTL: length 120.2
  TOP w0.127: v2(16.27,64.75) 16.22,64.7 16.22,64.49 14.39,62.66 14.39,59.45 14.93,58.92 14.93,46.56 11.17,42.8 v1(11.17,28.73) 11.17,27.45 10.57,26.85 9.47,26.85 v2(8.4,25.79)
  IN1 w0.127: v2(64.25,25.89) 64.06,26.08 55.12,26.08 55.08,26.04 46.24,26.04 45.64,25.44 39.2,25.44 38.57,26.07 25.47,26.07 24.86,26.68 18.05,26.68 17.26,25.89 14.09,25.89 13.77,26.21 8.82,26.21 v2(8.4,25.79)
  BOTTOM w0.076: 23.68,66.38 24.01,66.71 24.51,66.71 24.55,66.76 25.2,66.76 25.29,66.66 U20.AV61
  BOTTOM w0.127: 23.68,66.38 22.05,64.75 20.92,64.75 20.45,64.28 19.54,64.28 19.38,64.43 18.7,64.43 18.55,64.28 17.18,64.28 16.71,64.75 v2(16.27,64.75) ; Q25.2 66.9,21.62 64.51,24.01 64.51,25.63 v2(64.25,25.89) 63.75,26.4 U22.2
DDR_THERMDA: length 9.4
  BOTTOM w0.127: U21.2 79.18,49.72 78.99,49.52 78.59,49.52 77.98,48.91 C298.1 77.98,48.74 79.65,47.07 Q24.3 78.63,45.55 Q24.2 76.9,45.55 v2(76.37,45.01)
DDR_THERMDC: length 5.7
  BOTTOM w0.127: v2(76.37,46.33) Q24.1 77.2,47.99 C298.2 77.71,49.38 78.1,49.38 78.53,49.82 U21.3
DDR_VTT_PG_CTRL: length 40
  TOP w0.127: v2(52.82,22.2) v1(52.82,23.5) 52.82,23.86 v2(54.27,25.3)
  BOTTOM w0.127: v2(52.82,22.2) 52.82,21.7 47.03,15.91 Q27.2 ; Q26.3 67.03,16.51 65.91,17.63 65.91,22.24 62.97,25.18 59.61,25.18 59.4,25.38 U22.4 57.04,25.75 R463.1 R464.2 R465.1 53.71,26.73 53.97,26.47 54.07,26.47 54.27,26.27 v2(54.27,25.3)
DDR_VTTREF: length 89.1
  TOP w0.508: v2(7.92,26.42) 7.81,26.42 7.13,27.1 7.13,28.28 v1(6.34,29.06) 5.76,29.65 5.76,32.82 6.01,33.08 6.01,36.58 5.07,37.52 5.07,52.79 4.44,53.42 v2(4.44,53.8)
  IN1 w0.508: v2(10.84,70.13) 10.84,69.78 10.36,69.3 9.57,69.3 7.9,67.63 7.9,63.98 6.5,62.57 6.5,60.79 5.99,60.29 5.99,59.49 6.32,59.17 6.32,56.38 4.44,54.5 v2(4.44,53.8) ; v2(7.92,26.42) 8.37,26.42 8.6,26.65 10.15,26.65 10.28,26.78 v2(12.57,26.78) 14.06,26.78 14.42,27.13 26.33,27.13 26.94,26.52 39.36,26.52 v2(40,25.89)
  BOTTOM w0.508: PR122.1 10.91,26.01 11.68,26.78 v2(12.57,26.78) 13.07,26.27 PC137.1 ; v2(40,25.89) 40.05,25.84 R468.2 ; v2(10.84,70.13) 10.84,70.36 11.5,71.02 11.5,72.09 11.93,72.52 R355.1
DE1_1: length 4.8
  BOTTOM w0.127: 227.08,90.59 R183.1 ; 227.08,90.59 227.53,91.04 229,91.04 v2(229.35,91.39) 229.82,91.86 U12.3 ; 227.08,90.59 R163.2
DE2_1: length 3.1
  BOTTOM w0.127: R149.2 R150.1 236.45,92.04 236.34,91.93 235.73,91.93 235.58,91.78 235.15,91.78 235.07,91.86 U12.16
DEVSLP0: length 21.8
  TOP w0.127: v2(77,88.75) 77,84.72 76.97,84.69 76.97,84.68 76.56,84.27 76.55,84.27 75.65,83.37 74.62,83.37 73.7,82.45 73.7,82.45 73.28,82.03 73.28,82.02 71.76,80.5 71.75,80.5 71.65,80.4 71.34,80.4 70.01,80.4 69.71,80.09 68.42,80.09 68.09,80.42 v1(66.06,80.42) 65.07,80.42 64.86,80.22 63.58,80.22 v2(63.41,80.06)
  BOTTOM w0.076: v2(63.41,80.06) 63.4,80.04 62.46,80.04 U20.P2
  BOTTOM w0.127: v2(77,88.75) 77,88.93 76.95,88.98 R198.1
DEVSLP1: length 166.2
  TOP w0.127: v2(23.54,15.85) 24.15,16.46 31.46,16.46 31.62,16.62 33.27,16.62 33.73,17.08 33.73,23.42 33.21,23.93 27.33,23.93 24.23,27.03 v1(22.17,27.03) 21.33,27.03 20.82,27.54 v2(20.82,27.77)
  IN1 w0.127: v2(20.82,27.77) 20.31,28.28 14.8,28.28 13.81,27.28 11.78,27.28 10.63,28.43 5.45,28.43 v2(5.07,28.81) ; v2(71.77,88.17) 71.77,88.22 70.78,89.21 70.78,89.21 70.75,89.24 67.02,89.24 66.93,89.32 66.56,89.32 63.49,86.26 63.49,83.55 61.82,81.87 v2(61.82,81.62) 61.33,81.13 60.95,81.13 60.68,81.41 58.41,81.41 57.52,80.52 56.58,80.52 55.49,81.61 52.9,81.61 52.63,81.35 51.64,81.35 51.13,80.84 47.91,80.84 43.63,76.56 39.44,76.56 39.24,76.36 v2(39.24,76.05)
  IN2 w0.127: v2(5.07,28.81) 5.33,29.06 5.33,34.85 4.95,35.24 4.95,39.12 5.76,39.93 5.76,53.55 7.8,55.59 7.8,57.76 10.34,60.3 11.26,60.3 12.06,61.09 12.06,62.46 13.86,64.27 18.74,64.27 22.12,67.65 22.12,69.25 22.83,69.96 22.83,72.24 25.04,74.45 37.89,74.45 39.11,75.67 39.11,75.93 v2(39.24,76.05)
  BOTTOM w0.127: v2(23.54,15.85) 23.7,15.69 23.7,14.63 R472.1 ; v2(61.82,81.62) 61.82,81.4 61.97,81.24 U20.L2 ; v2(71.77,88.17) 71.7,88.24 R202.1
DEVSLP2: length 19.4
  IN1 w0.089: 62.9,82.45 62.9,81.47 62.19,80.75 60.64,80.75 60.44,80.96 v2(60.43,80.95)
  IN1 w0.127: 62.9,82.45 63.87,83.42 63.87,85.55 66.76,88.44 66.93,88.44 67.47,88.98 70.65,88.98 71.3,88.33 71.3,87.74 v2(71.4,87.64)
  BOTTOM w0.076: U20.N5 60.18,80.52 60.43,80.78 v2(60.43,80.95)
  BOTTOM w0.127: R208.1 72.28,88.31 72.28,87.76 v2(72.15,87.64) v2(71.4,87.64)
DGPU_PWROK: length 25.1
  TOP w0.089: 63.49,79.35 62.73,79.35 62,78.62 v2(61.81,78.62)
  TOP w0.127: v3(77.75,88.24) 77.74,88.24 77.74,88.24 77.51,88.02 77.51,84.51 77.47,84.47 77.47,84.47 76.77,83.76 76.76,83.76 75.86,82.86 74.83,82.86 74.21,82.24 74.21,82.24 73.79,81.82 73.79,81.81 71.97,79.99 71.96,79.99 71.86,79.89 71.86,79.89 71.12,79.89 70.22,79.89 69.92,79.58 68.39,79.58 67.42,78.61 66.65,78.61 65.47,79.79 64.13,79.79 63.7,79.35 63.49,79.35
  BOTTOM w0.089: v2(61.81,78.62) 61.81,78.73 U20.T3
  BOTTOM w0.127: v3(77.75,88.24) 77.74,88.24 77.74,88.24 78.11,88.61 78.11,89.03 R191.1
DIGITAL_CLK: length 49
  TOP w0.127: v2(199.28,91.37) 199.28,91.22 199.89,90.61 200.53,90.61 201.09,91.17 206.6,91.17 207.44,90.33 216.81,90.33 220.44,86.7 v1(221,86.7) 221.63,86.7 223,85.32 v2(223,82.99)
  BOTTOM w0.127: v2(199.28,91.37) 198.06,91.37 197.65,91.77 197.65,92.72 197.88,92.94 197.88,96.35 196.74,97.49 196.74,98.3 196,99.04 195.36,99.04 194.3,100.1 194.3,101.07 193.92,101.45 193.18,101.45 192.82,101.09 C56.1 192.38,100.94 192.37,100.96 190.91,100.96 L4.1 ; v2(223,82.99) 223.44,83.42 C224.1 223.4,83.55 222.89,83.55 R263.1
DIGITAL_CLK_R: length 4.9
  BOTTOM w0.127: v1(189.4,102.93) 189.5,103.03 L4.2 190.31,103.8 C40.2 190.37,104.12 191.69,105.45 CN3.7
DIGITAL_D1: length 50.2
  TOP w0.127: v2(223.5,82.2) 223.53,82.23 223.53,82.92 223.61,83.01 v1(223.61,85.88) 223.61,86.95 223.31,87.25 220.49,87.25 217.04,90.71 207.6,90.71 206.76,91.55 200.93,91.55 200.37,90.99 200.07,90.99 199.94,91.12 v2(199.94,91.32)
  BOTTOM w0.127: L3.1 192.03,101.55 C51.1 193.33,101.83 194.07,101.83 194.68,101.22 194.68,100.26 195.55,99.4 195.99,99.4 197.05,98.34 197.05,97.62 198.16,96.5 198.16,92.82 198.04,92.69 198.04,91.93 198.26,91.7 198.8,91.7 198.92,91.83 199.61,91.83 199.94,91.5 v2(199.94,91.32) ; v2(223.5,82.2) 223.53,82.23 C228.1 223.44,82.78 223.03,82.38 222.58,82.38 R267.2
DIGITAL_D1_R: length 4.4
  BOTTOM w0.127: v2(192.52,103.21) 192.35,103.03 L3.2 191.58,103.79 191.37,104 C39.2 191.89,104.64 191.89,104.88 192.49,105.48 CN3.8
DIMM1_SA0: length 3.3
  BOTTOM w0.127: JDIM1.197 66.65,38.58 65.78,39.45 R458.1 v4(65.12,39.67)
DIMM1_SA1: length 2.4
  BOTTOM w0.127: JDIM1.201 67.85,38.76 v2(67.45,39.16) R457.1
DMIC0: length 2.3
  BOTTOM w0.127: R267.1 221.6,82.15 220.57,81.12 U18.3
DMIC_CLK_R: length 2.5
  BOTTOM w0.127: U18.2 220.57,81.52 221.6,82.55 R263.2
DNBSWON#: length 344.6
  TOP w0.127: v2(9.26,77.81) 9.26,77.45 10.15,76.56 10.15,75.5 11.04,74.61 CN1.51 ; v2(122.42,91.29) 122.42,90.95 118.37,86.9 118.37,86.89 117.69,86.21 v1(98.67,86.21) 96.47,86.21 95.5,87.18 93.24,87.18 92.65,87.76 88.94,87.76 87.83,86.66 87.29,86.66 84.29,83.65 84.29,82.55 84.09,82.35 83.32,82.35 v2(83.22,82.45)
  IN1 w0.127: v2(217.85,99.95) 217.19,99.29 214.5,99.29 214.1,98.9 209.76,98.9 207.69,96.83 205.75,96.83 205.55,97.03 201.01,97.03 200.45,96.47 200.04,96.47 199.64,96.07 198.42,96.07 197.86,96.62 195.03,96.62 193.98,95.57 193.08,95.57 192.81,95.29 192.68,95.29 191.96,94.57 190.32,94.57 184.02,88.28 183.41,88.28 183.41,88.28 181.76,88.28 179.52,86.04 169.46,86.04 168.74,85.31 164.91,85.31 164.56,85.66 162.11,88.1 148.23,88.1 147.96,88.37 134.49,88.37 134.41,88.45 132.03,88.45 129.1,91.38 122.51,91.38 v2(122.42,91.29) ; v2(76.85,68.56) 76.8,68.56 76.29,68.05 76.29,64.62 75.43,63.76 75.43,62.59 75.8,62.22 75.8,56.7 v2(76.24,56.25) 76.46,56.04 76.46,52.67 72.26,48.46 72.26,32.98 68.85,29.57 64.99,29.57 63.62,28.2 27.14,28.2 26.05,29.29 12.59,29.29 12.38,29.5 6.15,29.5 4.95,30.7 4.95,33.81 2.21,36.54 2.21,36.55 2.12,36.65 2.12,55.47 2.56,55.91 3.27,55.91 3.78,56.42 4.25,56.42 4.79,56.96 4.79,58.7 4.56,58.93 4.56,60.94 4.96,61.34 4.96,62.52 4.56,62.92 4.56,64.98 3.8,65.74 3.8,73.43 6.95,76.58 6.95,76.99 7.76,77.81 v2(9.26,77.81)
  BOTTOM w0.127: R441.2 76.56,56.57 v2(76.24,56.25) ; v2(83.22,82.45) 83.18,82.4 82.74,82.4 82.72,82.42 82.31,82.42 82.29,82.4 82.29,82.4 82.06,82.17 82.06,82.17 82.01,82.13 82.01,80.76 82.22,80.56 82.22,77.86 77.28,72.92 77.28,70.54 76.85,70.11 v2(76.85,68.56) 75.82,68.56 R375.1 ; v2(217.85,99.95) 217.85,98.07 217.52,97.74 217.52,95.75 217.64,95.62 217.64,95.05 218.14,94.56 U7.90
DNBSWON#_R: length 23.1
  TOP w0.127: v2(58.14,70.94) 58.19,70.94 58.92,70.21 58.92,69.83 59.3,69.45 59.43,69.45 60.11,68.76 61.51,68.76 62.83,67.44 63.85,67.44 v1(64.52,66.77) 65.68,65.61 v2(66.11,65.61)
  BOTTOM w0.127: U20.AL7 v2(58.14,70.94) ; R389.1 66.03,65.54 v2(66.11,65.61) 66.3,65.8 66.32,65.8 66.58,66.06 66.58,66.08 66.94,66.44 67.98,66.44 68.27,66.73 68.27,67.79 68.52,68.04 70.5,68.04 71.16,68.7 72.12,68.7 72.52,68.29 73.49,68.29 73.61,68.42 74.58,68.42 74.79,68.56 R375.2
DOCK_DET_R: length 41.2
  IN1 w0.127: v2(189.25,103.46) 191.69,105.9 193.97,105.9 194.3,106.23 204.58,106.23 205.5,107.14 206.16,107.14 v2(206.47,107.45)
  BOTTOM w0.127: v2(189.25,103.46) 188.97,103.18 188.97,102.87 189.13,102.7 189.13,102.56 189.68,102.01 189.68,101.16 190.53,100.31 191.42,100.31 191.72,100.01 192.7,100.01 193.44,99.27 193.7,99.27 195.07,97.9 D6.1 195.65,97.31 195.48,97.14 R100.2 195.56,96.6 195.94,96.22 195.94,95.74 195.82,95.62 195.82,93.95 195.06,93.2 195.06,92.21 v2(194.61,91.75) 194.3,91.45 194.3,91.04 194.05,90.79 Q16.6 193.81,91.64 193.65,91.8 193.29,91.8 193.16,91.67 Q16.5 ; U7.36 206.3,107.27 v2(206.47,107.45)
DOCK_ECBASE_INT#: length 13.5
  TOP w0.127: v2(193.87,92.9) 193.06,92.9 v1(189.73,89.57) v2(189.73,88.63)
  BOTTOM w0.127: CN8.17 187.92,86.69 189.73,88.5 v2(189.73,88.63) ; v2(193.87,92.9) 193.87,93.4 194.68,94.21 195.06,94.21 195.23,94.38 Q15.1
DOCK_IN_DET: length 25.6
  TOP w0.127: v2(184.29,81.95) 184.9,81.95 188.54,85.58 189.76,85.58 v2(190.24,86.06)
  BOTTOM w0.127: CN8.5 194.22,80.21 193.79,79.79 186.78,79.79 184.62,81.95 v2(184.29,81.95) ; Q16.2 193.16,87.99 192.79,87.62 v2(192.4,87.62) R220.2 190.95,87.62 190.24,86.91 v2(190.24,86.06)
DPWROK: length 29.3
  BOTTOM w0.076: U20.AV5 59.73,65.97 59.73,64.57 60.04,64.27
  BOTTOM w0.127: 60.04,64.27 60.57,63.73 60.57,63.35 61.26,62.67 61.26,61.57 61.51,61.32 61.51,59.37 62.12,58.76 62.12,56.97 62.89,56.2 65.06,56.2 68.27,59.41 68.27,59.95 68.83,60.51 70.96,60.51 71.88,61.42 72.06,61.42 72.81,62.17 73.73,62.17 R401.1 74.59,63.03 75.4,63.03 75.46,62.97 R398.1 v2(76.44,62.06)
DPWROK_EC: length 177.8
  IN2 w0.127: v2(211.45,96.91) 211.03,97.33 209.45,97.33 208.6,96.47 207.64,96.47 207.13,95.97 205.91,95.97 205.48,95.53 203.25,95.53 202.26,94.54 198.53,94.54 197.74,93.76 195.13,93.76 194.78,93.4 193.18,93.4 192.26,92.47 188.42,92.47 183.53,87.59 183.53,86.62 180.28,83.37 178.51,83.37 175.67,80.52 173.03,80.52 172.32,80.52 171.33,79.53 170.91,79.53 157.68,79.53 153.13,84.09 133.35,84.09 132.85,83.6 130.52,83.6 127.78,86.34 112.13,86.34 110.25,88.22 97.44,88.22 94.88,90.78 92.81,90.78 91.22,89.2 87.41,89.2 85.66,87.44 85.02,87.44 83.84,86.26 83.84,84.75 v2(84.24,84.34)
  BOTTOM w0.127: v2(84.24,84.34) 84.31,84.28 84.31,83.81 84.65,83.47 84.65,77.43 79.3,72.09 79.3,68.15 79.29,68.14 79.29,67.04 77.79,65.54 v4(77.79,64.22) R392.1 77.19,63.61 77.22,63.58 R398.2 ; v2(211.45,96.91) 212.08,96.27 212.08,93.3 210.58,91.8 210.15,91.8 209.85,91.5 209.67,91.5 209.5,91.32 U7.117
DSWVRMEN: length 26.8
  BOTTOM w0.076: 58.89,62.72 58.89,62.79 58.61,63.07 58.61,64.66 58.4,64.87 58.4,65.28 58.69,65.57 U20.AW7
  BOTTOM w0.127: R415.1 72.83,61.07 72.74,61.07 72.59,60.91 72.09,60.91 71.11,59.94 70.05,59.94 65.43,55.31 60.74,55.31 58.77,57.28 v2(58.77,57.64) 58.77,58.96 59,59.19 59,60.43 58.87,60.56 58.87,62.06 58.89,62.08 58.89,62.72
EC_AOCS#: length 99.8
  TOP w0.127: v2(259.22,109.63) v1(259.22,108.92) 259.22,108.36 258.56,107.7 258.56,102.42 259.86,101.12 259.86,99.34 258.84,98.33 258.84,96.5 258.23,95.89 256.68,95.89 256.44,95.65 256.44,95.64 253.56,92.76 253.56,90.27 251.07,87.78 251.07,87.09 250.75,86.77 249.14,86.77 248.93,86.77 248.5,86.77 247.98,86.77 245.96,84.75 245.12,84.75 244.37,85.5 233.47,85.5 233.43,85.54 233.41,85.54 232.1,86.85 231.51,86.85 231.23,87.13 231.23,87.43 230.78,87.89 230.57,87.89 229.76,88.7 229.76,88.98 229.43,89.31 228.89,89.31 228.47,89.74 228.47,94.13 225.11,97.48 225.11,99.25 224.63,99.73 223.74,99.73 222.57,100.89 222.57,102.79 222.3,103.07 221.14,103.07 220.93,102.86 220.93,101.26 218.27,98.6 211.69,98.6 211.14,99.14 211.14,100.21 210.33,101.02 208.93,101.02 v2(208.48,100.56)
  BOTTOM w0.127: v2(208.48,100.56) 208.48,99.24 208.88,98.84 208.88,97.74 208.05,96.91 207.13,96.91 206.9,97.13 206.9,97.62 206.6,97.92 205.94,97.92 204.9,98.96 U7.18 ; Q3.2 258.69,110.17 v2(259.22,109.63)
EC_BASE_EN: length 79.2
  TOP w0.127: v2(170.1,87.23) v1(170.1,88.02) 170.1,88.69 170.7,89.29 171.33,89.29 173.16,91.12 177.23,91.12 185.92,99.8 185.92,101.25 187.27,102.6 188.61,102.6 v2(188.69,102.52)
  IN1 w0.127: v2(180.15,84.03) 171.57,84.03 170.86,84.74 v2(169.89,84.74) ; v2(188.69,102.52) 188.82,102.65 189.42,102.65 189.54,102.76 190.89,104.11 191.66,104.88 197,104.88 197.51,105.39 204.46,105.39 205.66,106.59 207.61,106.59 207.61,106.59 209.31,106.59 209.31,106.59 209.65,106.59 210.63,106.59 211.73,105.49 v2(211.73,105.03)
  BOTTOM w0.127: v2(180.15,84.03) 180.51,84.38 R257.1 ; R103.1 R102.1 193.62,96.88 193.03,97.47 D6.2 192.66,97.9 192.47,98.09 192.47,98.6 192.47,98.81 192.47,98.82 192.47,98.89 191.31,100.06 190.42,100.06 189.43,101.05 189.43,101.63 188.69,102.37 v2(188.69,102.52) ; v2(169.89,84.74) 170.1,84.94 v2(170.1,87.23) ; v2(211.73,105.03) 211.9,105.2 U7.50 211.9,106.97 211.7,107.17 211.7,107.92 R480.2
EC_DEBUG: length 68.3
  TOP w0.127: v2(207.97,104.68) 207.97,104.22 206.85,103.1 R1.2 ; v2(236.02,104.25) 235.55,104.72 235.55,105.24 235.79,105.48 v1(239.67,105.48) 246.36,105.48 249.57,108.69 256.21,108.69 257.92,110.39 260.6,110.39 261.41,109.58 261.41,107.27 v2(261.99,106.69)
  IN2 w0.127: v2(236.02,104.25) 235.66,103.89 228.72,103.89 227.27,102.44 226.4,102.44 225.28,101.33 220.48,101.33 219.92,100.77 214.5,100.77 214.19,101.07 213.53,101.07 211.85,102.75 211.85,102.96 210.67,104.15 208.29,104.15 207.97,104.48 v2(207.97,104.68)
  BOTTOM w0.127: R54.2 262.54,105.82 262.32,105.82 261.99,106.15 v2(261.99,106.69)
EC_HW_STRAP: length 3.2
  BOTTOM w0.127: U7.42 208.7,107.03 209.05,107.38 209.2,107.38 209.75,107.93 v2(210.05,107.93) 210.23,108.11 R37.2
EC_PCIE_WAKE#: length 83.3
  TOP w0.127: v2(222.12,102.55) 222.12,100.93 223.57,99.47 224.53,99.47 224.86,99.14 224.86,97.38 228.21,94.02 v1(228.21,89.08) 228.21,88.4 228.5,88.11 229.13,88.11 229.38,87.86 229.38,87.18 230.54,86.02 231.4,86.02 231.97,85.45 231.97,84.41 232.54,83.84 246.13,83.84 248.3,86.01 251.07,86.01 251.83,86.77 251.83,87.46 254.32,89.95 254.32,92.31 257.09,95.08 258.82,95.08 260.22,96.47 v2(260.22,96.88)
  BOTTOM w0.127: R16.2 223.32,115.45 223.79,115.45 224.43,114.81 225.93,114.81 226.05,114.69 226.05,113.87 226.28,113.64 226.79,113.64 226.97,113.47 226.97,110.57 225.72,109.33 224.93,109.33 224.68,109.07 224.68,107.32 222.12,104.75 v2(222.12,102.55) 222.12,102.14 221.33,101.36 U7.73 ; Q13.3 259.58,96.25 v2(260.22,96.88)
EC_PECI: length 213.1
  TOP w0.127: v2(22.98,79.93) 24.26,81.21 25.89,81.21 26.09,81.01 26.46,81.01 26.66,81.21 27.55,81.21 27.86,80.9 v1(28.49,80.9) 30.82,80.9 32.37,82.45 33.41,82.45 34.54,83.58 34.54,84.18 36.06,85.7 36.66,85.7 37.18,86.23 37.18,86.69 37.97,87.48 37.97,88.37 40.7,91.1 41.33,91.1 42.98,92.75 44.63,92.75 44.72,92.66 46.23,92.66 46.44,92.46 46.44,91.33 48.13,89.64 49.45,89.64 50.72,88.37 52.06,88.37 54.81,91.12 54.81,92.04 57.68,94.91 57.68,95.51 59.5,97.34 62.53,97.34 63.75,96.12 64.46,96.12 64.84,96.5 64.84,97.47 65.09,97.72 70.02,97.72 70.31,97.43 70.8,97.43 70.8,97.43 85.69,97.43 87.02,98.76 91.14,98.76 91.81,99.43 102.21,99.43 102.59,99.05 103.13,98.52 106.09,98.52 106.58,98.52 107.07,98.02 111.52,98.02 111.81,97.73 115.06,97.73 115.16,97.82 115.83,98.5 116.68,99.34 118.89,99.34 119.57,100.02 121.3,101.76 121.65,101.76 122.22,102.33 127.34,102.33 131.02,98.65 132.75,96.92 134.87,96.92 136.56,95.24 136.56,90.54 140.19,86.91 149.1,86.91 149.16,86.97 164.97,86.97 165.61,86.33 177.07,86.33 189.02,98.28 192.6,98.28 193.41,99.09 195.88,99.09 196.94,100.16 v2(198.11,100.16)
  BOTTOM w0.076: 23.26,80.17 23.44,80.35 23.84,80.35 23.97,80.22 24.32,80.22 24.63,80.53 U20.N62
  BOTTOM w0.127: v2(198.11,100.16) 198.11,100.06 198.62,99.55 R83.1 ; v2(22.98,79.93) 23.02,79.93 23.26,80.17
EC_PECI_R: length 24.1
  TOP w0.127: v2(211.6,95.31) 211.42,95.48 208.96,95.48 208.09,96.35 v1(207.28,96.35) 206.88,96.35 203.65,99.57 200.98,99.57 200.83,99.73 199.03,99.73 198.82,99.52 v2(197.53,99.52)
  BOTTOM w0.127: v2(197.53,99.52) 198.09,98.96 198.09,98.38 198.25,98.22 R83.2 ; v2(211.6,95.31) 211.6,93.3 210.35,92.05 210.02,92.05 209.75,91.78 209.49,91.78 209.1,91.38 U7.118
EC_PWROK: length 233.5
  TOP w0.127: v2(74.39,87.37) 74.39,88.35 74.72,88.68 74.72,89.31 75,89.59 76.78,89.59 78.61,91.42 80.13,91.42 81.58,92.87 85.26,92.87 86.56,94.16 89.53,94.16 89.53,94.16 92.1,94.16 92.87,94.94 96.14,94.94 96.59,94.49 98.06,94.49 98.11,94.44 103.97,94.44 104.52,93.9 105.15,93.9 109.91,93.9 110.23,93.9 110.39,94.06 114.09,94.06 114.44,94.41 117.39,94.41 119.5,96.53 119.89,96.53 122.66,99.29 125.77,99.29 126.9,100.42 127.3,100.42 127.78,99.95 127.78,99.12 130.52,96.37 v2(130.52,95.69) ; v2(195.78,100.74) 196.23,101.2 197.71,101.2 198.39,100.51 203.62,100.51 206.19,97.95 206.56,97.95 206.93,97.58 206.93,97.21 207.15,96.98 208.3,96.98 209.34,95.94 v1(213.61,95.94) v2(216.63,95.94)
  IN1 w0.127: v2(130.52,95.69) 130.52,95.15 132.99,92.68 135.57,92.68 136.3,93.41 138.71,93.41 140.91,95.61 153.51,95.61 157.34,91.78 165.37,91.78 165.91,91.24 177.74,91.24 178.36,91.86 182.54,91.86 187.68,97 187.68,97.22 188.76,98.3 190.6,98.3 193.04,100.74 v2(195.78,100.74) ; v2(74.39,87.37) 74.31,87.29 74.31,86.29 72.48,84.46 72.48,82.63 72.05,82.2 72.05,81.36 71.04,80.35 69.96,80.35 69.71,80.09 67.99,80.09 67.67,80.41 66.14,80.41 65.8,80.07 65.09,80.07 64.34,79.32 64.34,79.14 63.67,78.47 62.98,78.47 62.35,77.83 62.35,77.02 62,76.66 60.88,76.66 v2(60.36,76.14)
  IN2 w0.089: 51.96,74.5 51.55,74.91 51.55,77.27 51.86,77.58 57.12,77.58 58.11,76.59 59.91,76.59 v2(60.36,76.14)
  IN2 w0.127: 51.96,74.5 54.75,74.5 55.52,73.74 55.52,72.08 55.53,72.07 55.53,71.73 55.52,71.72 55.52,71.58 55.19,71.25 55.19,66.17 55.77,65.59 56.3,65.59 58.74,63.15 58.74,61.96 59.05,61.65 v2(59.33,61.65)
  BOTTOM w0.076: U20.AY7 58.79,64.98 58.79,63.35 59.14,63.01
  BOTTOM w0.127: 59.14,63.01 59.33,62.82 v2(59.33,61.65) ; U20.AB5 60.18,75.96 v2(60.36,76.14) ; v2(216.63,95.94) 216.63,95.56 216.88,95.31 216.88,94.87 218.4,93.36 U7.93 ; U16.1 76.33,85.66 76.98,86.31 R242.2 77.17,86.56 77.47,86.86 R230.2 77.47,87.57 77.34,87.7 76.34,87.7 76.17,87.52 76.17,87.13 75.91,86.87 74.89,86.87 v2(74.39,87.37) ; v2(195.78,100.74) 196.73,101.69 197,101.69 197.11,101.8 D4.1
EC_RCIN#: length 187.3
  TOP w0.089: 64.74,77.27 64.18,77.27 64.05,77.15 62.4,77.15 61.97,77.58 61.41,77.58 61.18,77.35 v3(61.18,77.11)
  TOP w0.127: v2(115.26,92.07) 114.67,92.66 110.97,92.66 110.81,92.5 109.33,92.5 109.33,92.5 109.02,92.5 106.1,92.5 106.1,92.5 105.68,92.5 105.68,92.5 103.94,92.5 103.88,92.5 103.36,93.02 102.79,93.02 102.78,93.02 102.47,93.02 90,93.02 87.03,93.02 85.73,91.72 85.1,91.72 84.79,91.72 83.1,91.72 81.05,89.67 80.03,89.67 79.37,89.01 79.19,89.01 ; 79.19,89.01 79.06,88.88 79.06,88.21 78.53,87.67 78.53,87.08 78.69,86.91 78.69,85.03 78.27,84.61 78.27,84.19 77.08,83 77.08,83 76.36,82.28 76.36,82.27 76.18,82.1 76.18,82.1 75.14,82.1 74.97,81.93 74.97,81.92 74.55,81.5 74.55,81.5 71.22,78.16 70.78,78.16 70.43,77.81 70.43,77.68 69.87,77.12 68.39,77.12 67.66,76.38 66.57,76.38 65.46,77.5 64.97,77.5 64.74,77.27 ; 79.19,89.01 v2(79.19,88.97)
  IN1 w0.127: v2(210.62,99.94) 210.09,99.41 206.11,99.41 206.08,99.37 205.4,99.37 204.79,98.76 199.99,98.76 199.81,98.58 198.92,98.58 198.61,98.27 195.72,98.27 194.34,98.27 193.29,97.22 192.25,97.22 191.37,96.33 189.74,96.33 183.34,89.93 182.73,89.93 182.72,89.93 182.31,89.93 182.31,89.93 182.13,89.93 181.12,89.93 179.73,89.93 178.05,88.24 169.16,88.24 167.87,86.96 166.3,86.96 163.51,89.75 150.56,89.75 147.8,92.51 141.01,92.51 139.98,91.48 137.85,91.48 136.46,90.1 132.72,90.1 129.78,93.03 118.43,93.03 117.47,92.07 v2(115.26,92.07)
  BOTTOM w0.127: U20.V4 60.86,77.43 v3(61.18,77.11) ; v2(79.19,88.97) 79.19,89.11 78.96,89.34 R189.1 ; U7.2 204.29,92.56 204.39,92.46 207.33,92.46 207.71,92.08 209.67,92.08 209.92,92.33 210.25,92.33 211.24,93.32 211.24,94.9 210.89,95.26 210.89,97.14 210.62,97.4 v2(210.62,99.94)
ECBASE_CLK: length 53.2
  TOP w0.127: v2(221.07,93.66) 221.35,93.38 221.35,92.97 220.26,91.88 207.76,91.88 207.18,92.46 202.07,92.46 201.67,92.87 200.45,92.87 200.07,93.25 198.42,93.25 198.04,92.87 194.56,92.87 194.07,93.35 193.08,93.35 192.52,92.79 192.31,92.79 189.81,92.79 186.76,89.74 v1(186.76,89.18) 186.76,87.42 185.81,86.47 v2(185.29,86.47)
  BOTTOM w0.127: U7.83 220.09,97.36 220.39,97.06 220.39,94.44 220.91,93.92 220.91,93.82 v2(221.07,93.66) 221.28,93.45 221.28,92.59 221.58,92.29 221.58,91.68 221.98,91.28 222.3,91.28 222.8,90.78 R178.2 ; v2(185.29,86.47) 185.29,85.43 185.17,85.31 Q20.1
ECBASE_CLK_R: length 9.2
  BOTTOM w0.127: CN8.18 188.52,84.59 188.38,84.46 186.56,84.46 186.28,84.74 186.28,86.19 v2(186.02,86.44) 186.02,86.62 185.72,86.92 184.88,86.92 183.27,85.31 Q20.6
ECBASE_DATA: length 69.5
  TOP w0.127: v2(185.97,87.29) 185.97,88.11 v1(185.93,88.14) 185.93,89.28 189.7,93.05 192.42,93.05 192.98,93.6 194.2,93.6 194.68,93.12 197.91,93.12 198.29,93.5 200.18,93.5 200.26,93.42 200.56,93.12 201.77,93.12 202.18,92.72 207.33,92.72 207.84,92.21 214.57,92.21 215.43,93.07 v2(220.82,93.07)
  BOTTOM w0.127: U7.84 220.03,96.96 220.13,96.86 220.13,94.27 220.62,93.79 220.62,93.27 v2(220.82,93.07) 220.82,92.69 221.33,92.18 221.33,91.57 221.87,91.03 222.2,91.03 222.46,90.77 222.46,90.59 222.84,90.21 R186.2 222.84,89.81 223.11,89.54 223.39,89.54 223.87,89.06 223.87,88.55 224.2,88.22 224.6,88.22 225.07,88.69 227.94,88.69 228.49,88.14 229.27,88.14 230.03,88.91 R484.1 ; v2(185.97,87.29) 185.96,87.28 184.77,87.28 183.31,85.82 181.87,85.82 180.84,84.79 179.85,84.79 179.71,84.65 179.71,83.84 180.08,83.47 181.94,83.47 Q20.4
ECBASE_DATA_R: length 5.6
  BOTTOM w0.127: Q20.3 185.12,84.01 185.36,83.77 v2(185.36,83.37) 185.51,83.52 187.83,83.52 188.82,82.53 CN8.14
ECBASE_INT#: length 22.8
  TOP w0.127: v2(196.41,100.74) 196.41,100.28 195.8,99.67 v1(194.3,99.67) 193.03,99.67 v2(192.68,99.32)
  BOTTOM w0.127: v2(192.68,99.32) 193.13,98.86 193.41,98.86 194.02,98.25 194.02,96.32 194.21,96.13 R104.2 194.49,96.13 195.06,95.56 195.44,95.56 195.56,95.44 195.56,94.16 195.31,93.91 194.89,93.91 194.73,93.76 Q15.3 ; v2(196.41,100.74) 196.64,100.97 197.81,100.97 198.14,101.3 198.14,103.31 198.5,103.68 201.17,103.68 201.65,104.16 U7.31
EDP_AUXN_R: length 2.7
  BOTTOM w0.127: C204.1 10.72,86.67 10.52,86.67 10.4,86.54 10.4,86.2 9.98,85.79 9.8,85.79 9.67,85.65 CN7.9
EDP_AUXP_R: length 2.7
  BOTTOM w0.127: C198.1 10.93,87.09 10.74,86.9 10.43,86.9 10.17,86.64 10.17,86.3 9.88,86.01 9.79,86.01 9.66,86.15 CN7.8
EDP_DISP_UTIL: length 5.2
  BOTTOM w0.127: R168.1 38.76,90.48 37.53,90.48 v4(37.2,90.15) 36.79,89.74 36.79,87.87 U20.A43
EDP_HPD_L: length 73.8
  TOP w0.127: v2(18.38,85.65) 19.03,85.01 v1(19.96,85.01) 21.06,85.01 22.39,86.34 24.4,86.34 24.8,85.94 26.78,85.94 27.37,85.35 30.47,85.35 30.88,84.94 32.82,84.94 33.58,85.7 34.05,85.7 35.7,87.36 36.29,87.36 36.87,87.94 36.87,88.82 39.98,91.93 41.33,91.93 42.8,93.4 44.39,93.4 44.57,93.58 45.17,93.58 45.5,93.25 46.47,93.25 47.06,92.66 52.56,92.66 53.1,93.2 55.14,93.2 57.09,95.15 57.09,95.75 59.26,97.92 63.14,97.92 v2(64.38,96.68)
  IN1 w0.127: v2(10.41,85.35) 10.71,85.65 15,85.65 16.04,86.7 17.34,86.7 v2(18.38,85.65)
  BOTTOM w0.127: v2(10.41,85.35) 10.52,85.46 R256.2 ; R94.2 71.09,97.75 Q11.2 71.08,99.04 69.81,97.77 R90.1 69.46,97.52 65.2,97.52 64.48,96.8 64.48,96.78 v2(64.38,96.68)
EDP_HPD_R: length 2.9
  BOTTOM w0.127: R256.1 11.16,84.68 9.63,83.15 CN7.14
EDP_RCOMP: length 6.5
  IN1 w0.254: v3(51.38,85.6) 51.38,86.01 50.79,86.59 50.79,87.99 50.21,88.58 v3(49.89,88.58)
  BOTTOM w0.254: v3(49.89,88.58) R181.2 ; v3(51.38,85.6) 51.7,85.93 U20.D20
EDP_TXN0_R: length 2.8
  BOTTOM w0.127: CN7.5 9.68,87.65 9.82,87.51 9.94,87.51 10.13,87.7 10.13,88.16 10.36,88.39 10.7,88.39 C188.1
EDP_TXN1_R: length 2.4
  BOTTOM w0.127: C178.1 10.67,89.64 10.54,89.64 9.95,89.05 9.83,89.05 9.73,89.15 CN7.2
EDP_TXP0_R: length 2.7
  BOTTOM w0.127: C190.1 10.75,88.17 10.45,88.17 10.36,88.07 10.36,87.61 10.03,87.29 9.83,87.29 9.69,87.15 CN7.6
EDP_TXP1_R: length 2.4
  BOTTOM w0.127: C183.1 10.78,89.41 10.63,89.41 10.05,88.83 9.89,88.83 9.72,88.65 CN7.3
EMU_LID: length 392.1
  TOP w0.127: v2(217.97,95.94) 217.47,96.45 v1(215.51,96.45) 211.17,96.45 211,96.61 211,96.72 210.86,96.86 210.61,97.11 210.23,97.11 208.12,99.22 206.34,99.22 v2(205.73,99.83)
  IN2 w0.127: v2(217.97,95.94) 218.84,95.08 218.84,93.02 218.85,93.01 218.85,92.72 217.1,90.96 214.97,90.96 214.72,90.72 208.44,90.72 207.28,89.57 207.28,88.47 207,88.19 204.94,88.19 202.54,85.79 201.12,85.79 200.57,85.25 199.35,85.25 198.9,84.8 198.61,84.51 194.48,84.51 194.31,84.34 193.9,83.93 193.9,83.01 184.56,73.68 155.45,73.68 152.63,76.5 88.47,76.5 82.03,70.06 82.03,42.93 75.18,36.08 75.18,24.87 73.52,23.22 66.29,23.22 61.79,18.73 52.18,18.73 49.2,15.74 31.8,15.74 29.95,13.9 26.64,13.9 25.56,12.82 16.54,12.82 15.93,12.21 7.28,12.21 6.67,12.82 6.05,12.82 4.74,14.13 4.74,15.96 7.72,18.93 7.72,24.11 4.28,27.54 3.85,27.54 2.21,29.18 2.21,54.97 2.14,55.05 2.14,92.42 4.16,94.44 5.38,94.44 5.91,94.98 7,94.98 8.53,96.5 v2(10.33,96.5)
  BOTTOM w0.127: v2(205.73,99.83) 205.17,100.39 205.17,101.05 204.46,101.76 U7.25 ; v2(10.33,96.5) 10.33,94.8 12.53,92.6 R143.1
EQ1_1: length 6.2
  BOTTOM w0.127: v4(225.8,89.26) 225.93,89.39 225.93,89.64 226.31,90.02 226.81,90.02 227.08,89.76 ; U12.2 230.05,91.36 229.88,91.19 229.88,91.19 229.77,91.07 229.77,91.07 229.25,90.56 R182.1 228.71,90.24 228.54,90.07 227.22,90.07 227.08,89.93 227.08,89.76 ; R192.2 227.08,89.76
EQ2_1: length 3.5
  BOTTOM w0.127: R165.2 R166.1 236.45,91.25 235.88,90.68 v2(235.42,90.68) 235.35,90.68 234.97,91.06 234.97,91.19 234.8,91.36 U12.17
EXT_MIC_L: length 25.4
  TOP w0.254: v2(212.82,74.55) 212.36,74.1 211.35,74.1 211.14,74.3 209.47,74.3 208.84,74.92 207.17,74.92 206.57,74.33 201.96,74.33 201.01,75.28 199.84,75.28 198.01,77.11 198.01,80.64 v1(197.08,81.57) 195.93,82.72 v2(195.93,83.01)
  BOTTOM w0.254: R341.1 213.59,74.38 213,74.38 v2(212.82,74.55) ; CN8.2 196.02,82.92 v2(195.93,83.01)
EXT_MIC_L1: length 2.8
  BOTTOM w0.203: U18.17 216.82,76.75 216.81,76.74 v2(216.81,75.7) 216.76,75.65 C272.1
EXT_MIC_R1: length 4.5
  BOTTOM w0.203: R322.2 215.93,75.69 216.42,76.17 U18.18
  BOTTOM w0.254: R341.2 214.93,74.53 215.18,74.78 C272.2 215.28,75.2 R322.2
FAN1_PWM: length 219.5
  TOP w0.127: v2(121.15,91.29) 117.23,87.37 101.89,87.37 101.48,87.37 100.88,87.97 96.33,87.97 96.19,88.11 95.97,88.32 93.79,88.32 93.21,88.91 92.23,88.91 88.47,88.91 87.36,87.8 86.7,87.8 86.09,87.19 84.92,87.19 84.29,86.57 84.29,85.02 v3(84.36,84.95)
  IN1 w0.127: v2(121.15,91.29) 121.15,91.86 121.81,92.52 129.57,92.52 132.51,89.59 137.55,89.59 137.63,89.51 148.77,89.51 149.04,89.24 163.3,89.24 166.09,86.45 168.18,86.45 169.46,87.74 178.26,87.74 179.94,89.42 180.91,89.42 181.92,89.42 182.1,89.42 182.94,89.42 183.55,89.42 189.95,95.83 191.6,95.83 192.48,96.71 193.5,96.71 194.55,97.76 194.56,97.76 195.51,97.76 198.82,97.76 198.97,97.91 198.98,97.91 199.12,98.05 200.14,98.05 200.32,98.23 205.02,98.23 205.61,98.81 207.21,98.81 v2(207.28,98.74)
  BOTTOM w0.127: FAN1.2 78,22.84 77.61,23.22 C341.1 73.13,22.93 72.81,22.61 72.33,22.61 71.52,23.42 71.52,24.29 72.08,24.85 72.08,25.53 75.86,29.32 75.86,34.21 80.74,39.1 80.74,55.7 79.11,57.33 79.11,58.91 78.71,59.31 78.71,65.72 79.82,66.83 79.82,71.89 85.16,77.22 85.16,84.26 84.47,84.94 84.37,84.94 84.36,84.95 v3(84.36,84.95) ; U7.26 204.39,102.16 205.68,100.87 205.68,100.59 207.28,98.99 v2(207.28,98.74)
FAN1SIG: length 220.5
  TOP w0.254: v3(121.79,91.29) 121.79,91.12 117.8,87.13 117.46,86.8 105.86,86.8 105.86,86.8 101.26,86.8 101.24,86.8 100.64,87.39 96.09,87.39 95.95,87.53 95.95,87.53 95.74,87.75 93.55,87.75 92.97,88.33 92.46,88.33 88.7,88.33 87.6,87.23 87.04,87.23 85.34,85.53 v2(84.85,85.53)
  IN1 w0.254: v3(121.79,91.29) 121.79,91.3 121.79,91.67 122.07,91.95 129.33,91.95 132.27,89.02 137.27,89.02 137.34,88.94 148.53,88.94 148.8,88.67 162.35,88.67 165.14,85.88 168.42,85.88 169.18,86.64 179.32,86.64 181.53,88.85 181.68,88.85 181.86,88.85 183.17,88.85 183.78,88.85 190.19,95.26 191.84,95.26 192.11,95.53 192.72,96.14 193.74,96.14 194.79,97.19 194.8,97.19 199.06,97.19 199.21,97.34 199.23,97.34 199.36,97.47 200.42,97.47 200.6,97.64 205.3,97.64 205.88,98.23 207.59,98.23 207.92,98.56 v2(207.92,98.68)
  BOTTOM w0.127: v2(207.92,98.68) 207.92,98.81 206.09,100.64 206.09,101.1 204.24,102.96 U7.28
  BOTTOM w0.254: v2(84.85,85.53) 85.74,84.64 85.74,76.99 80.41,71.66 80.41,66.53 79.29,65.41 79.29,59.57 79.75,59.11 79.75,57.51 81.33,55.93 81.33,38.87 76.43,33.98 76.43,29.05 73.63,26.24 73.63,24.67 73.45,24.49 R469.1 C340.1 75.68,23.86 76.47,24.64 79.39,24.64 80,24.04 FAN1.4
G5934CN: length 1.9
  BOTTOM w0.203: 108.28,102.72 PU6.19
  BOTTOM w0.254: 108.28,102.72 107.82,103.18 PC85.2
G5934CP: length 2.8
  BOTTOM w0.203: 108.12,102.32 PU6.18
  BOTTOM w0.254: 108.12,102.32 107.76,102.67 106.72,102.67 106.26,103.14 PC85.1
G5934DISC1: length 3.4
  BOTTOM w0.203: PU6.5 112.81,103.82 PR65.2
  BOTTOM w0.254: v4(113.5,105.14) 113.14,104.77 PR65.2
G5934DISC2: length 1.5
  BOTTOM w0.203: PU6.6 113.1,103.12 PR73.2
G5934DISC4: length 3.7
  BOTTOM w0.203: PU6.8 112.66,102.32 PR77.1
  BOTTOM w0.254: v2(114.8,101.2) 114.77,101.22 113.48,101.22 113.09,101.61 PR77.1
G5934PG: length 3.1
  BOTTOM w0.203: PR93.2 107.09,99.53 107.59,100.03 108.55,100.03 108.7,100.18 v2(108.83,100.18) 108.95,100.18 109.2,100.44 109.2,100.45 109.4,100.64 PU6.15
G5934VIN: length 3.6
  BOTTOM w0.203: PR50.1 107.28,105.01 107.04,104.76 PC75.2 v2(107.97,104.22) 108.7,103.49 PU6.20
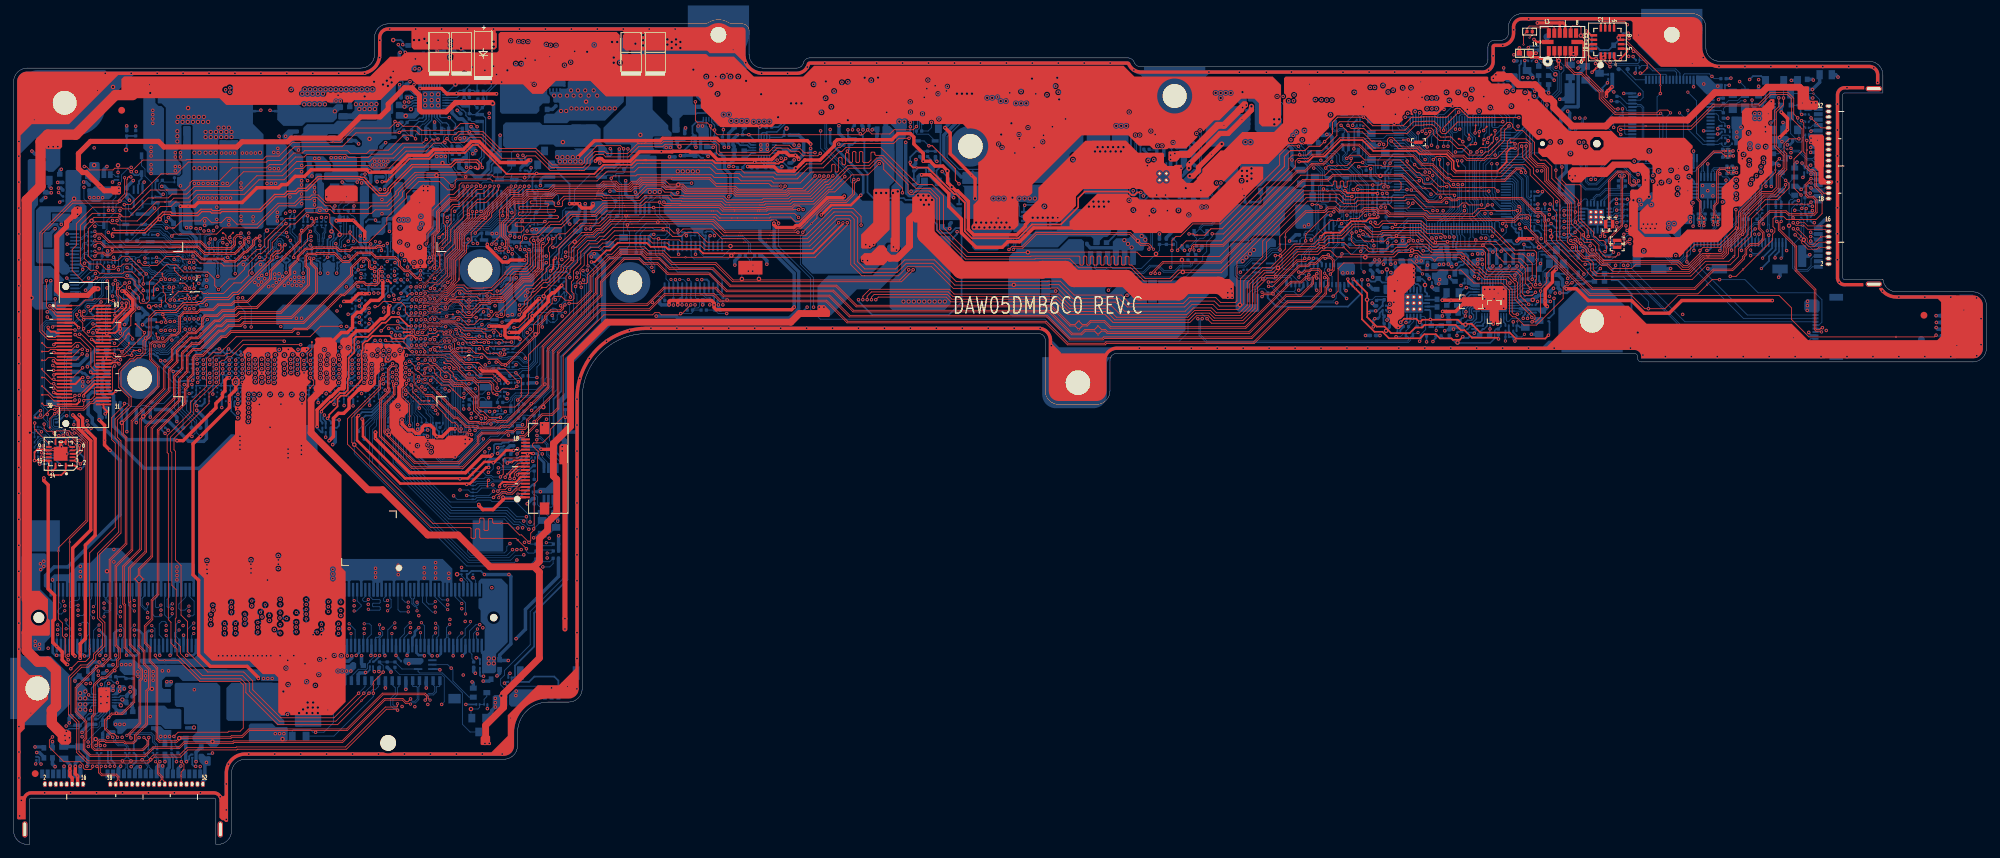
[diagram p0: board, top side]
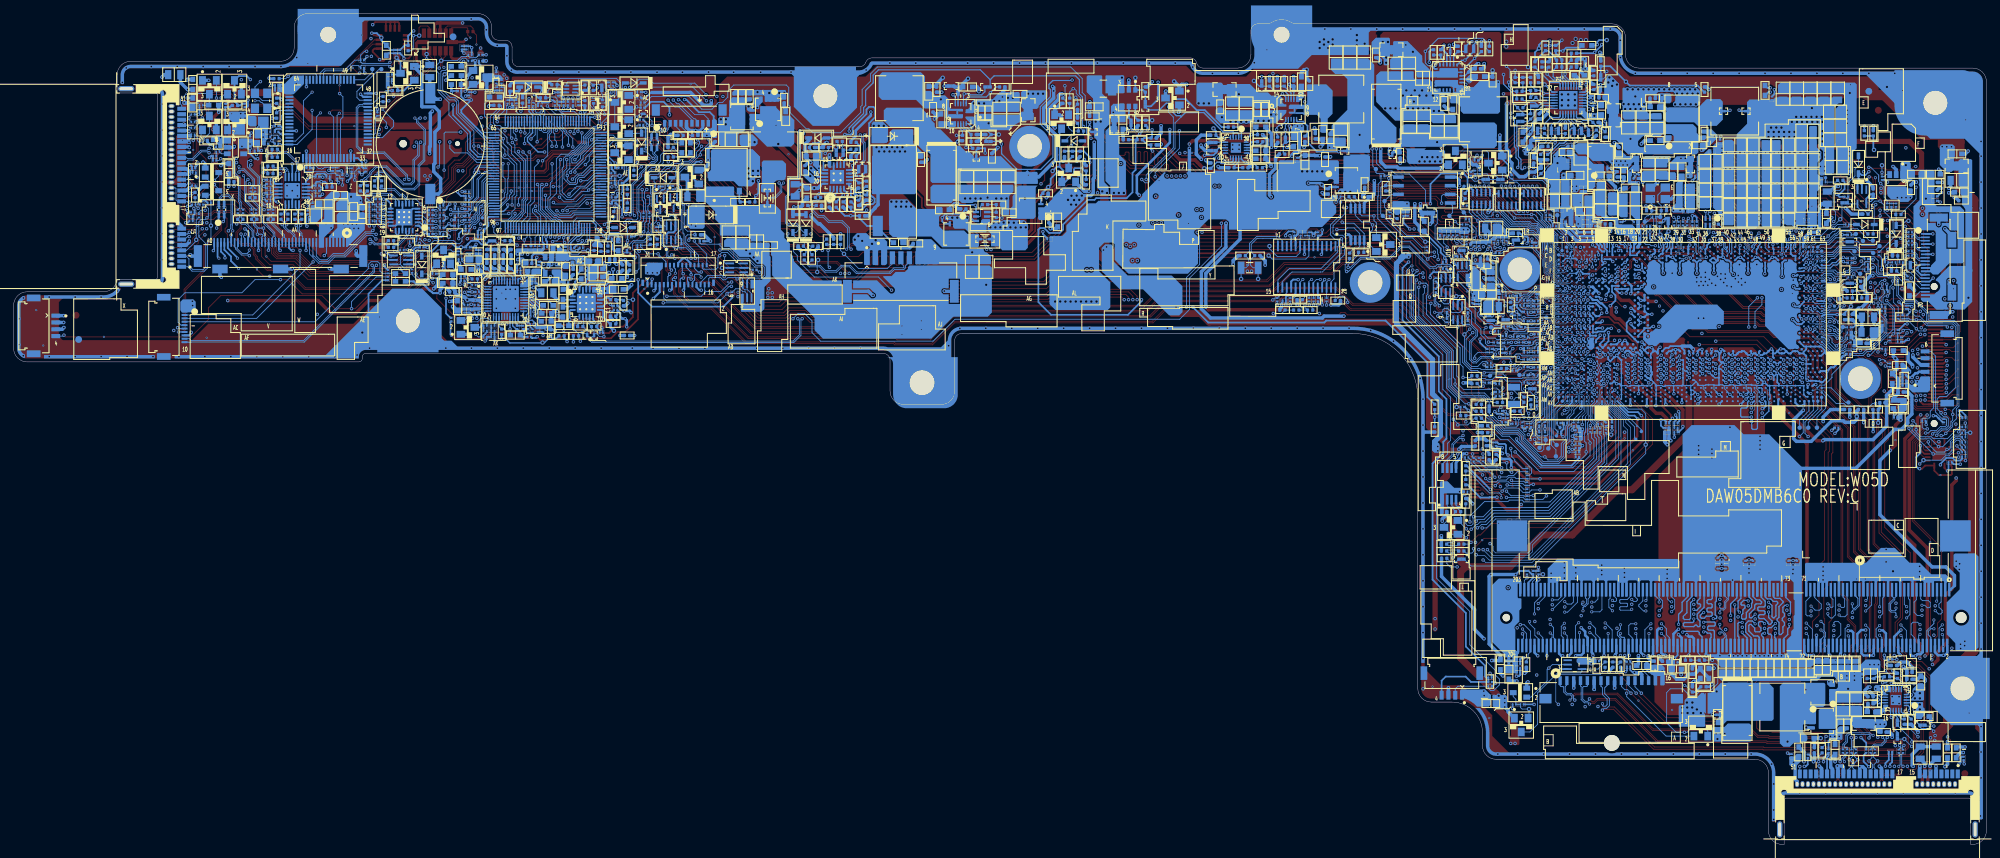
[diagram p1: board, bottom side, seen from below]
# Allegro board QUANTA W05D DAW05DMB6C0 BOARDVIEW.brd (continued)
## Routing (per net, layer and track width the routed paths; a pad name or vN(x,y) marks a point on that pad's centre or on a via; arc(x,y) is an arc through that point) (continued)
G5934VOUT: length 1.4
  BOTTOM w0.203: PC91.1 107.79,101.86 107.85,101.92 PU6.17
G5934VSENSE: length 3
  BOTTOM w0.203: PU6.14 109.8,100.26 110.47,99.59 PR91.2 PR92.1
GPIO13_ULT: length 12
  BOTTOM w0.076: 63.39,67.79 63.23,67.79 62.97,68.05 61.84,68.05 U20.AT3
  BOTTOM w0.127: R425.2 65.84,60.01 66.11,60.28 66.11,60.64 66.18,60.71 66.18,61.65 65.82,62.02 R406.1 64.89,62.78 64.89,67.13 64.23,67.79 63.39,67.79
GPIO14_ULT: length 12.1
  TOP w0.076: 64.48,72.67 64.48,73.31 64.27,73.53 63,73.53 62.93,73.46 60.58,73.46 v2(60.44,73.32)
  TOP w0.127: v2(68.72,71.53) 67.51,71.53 67.28,71.76 66.64,71.76 66.39,71.51 TP48.1 66.16,71.56 65.59,71.56 64.48,72.67 64.48,72.67
  BOTTOM w0.089: v2(60.44,73.32) 60.52,73.24 60.52,72.89 60.76,72.65 60.76,72.47 60.86,72.37 U20.AH4
  BOTTOM w0.127: R363.1 68.39,71.2 v2(68.72,71.53)
GPIO15_ULT: length 12.8
  TOP w0.076: 62.76,76.08 61.11,76.08 60.21,75.19 v2(60.01,75.19)
  TOP w0.089: 62.76,76.08 63.11,76.43 64.74,76.43 65.4,75.78
  TOP w0.127: 65.4,75.78 65.65,75.53 65.65,75.29 65.79,75.14 65.92,75.14 66.63,74.43 67.86,74.43 68.12,74.17 v1(68.72,74.17) 69.28,74.17 v2(69.74,73.72)
  BOTTOM w0.127: v2(69.74,73.72) 69.77,73.69 R349.2 ; U20.AD6 59.54,74.71 v2(60.01,75.19)
GPIO16_ULT: length 11
  BOTTOM w0.076: U20.Y1 62.95,76.61 63.95,76.61 64.08,76.48
  BOTTOM w0.127: TP90.1 71.24,75.93 71.11,76.05 R320.1 70.82,75.81 70.68,75.67 70.3,75.67 69.96,75.33 67.77,75.33 67.44,75.66 65.51,75.66 65.12,76.05 64.51,76.05 64.08,76.48
GPIO24_ULT: length 5.9
  BOTTOM w0.076: U20.AD5 60.46,74.71 60.62,74.87 61.64,74.87 61.71,74.79 62.98,74.79 63.11,74.66 64.47,74.66 64.72,74.91 v1(65.17,74.91) 65.42,74.91
  BOTTOM w0.127: R333.1 65.42,74.91
GPIO25_ULT: length 13.5
  IN1 w0.076: v2(61.19,69.65) 61.44,69.4 63.39,69.4
  IN1 w0.127: v2(69.26,70.41) 69.22,70.37 68.1,70.37 67.3,69.58 65.04,69.58 64.86,69.4 63.39,69.4
  BOTTOM w0.127: U20.AM4 60.86,69.98 v2(61.19,69.65) ; v2(69.26,70.41) 69.47,70.21 70.07,70.21 70.22,70.36 v2(72.2,70.36) 72.48,70.08 R368.1 R365.2
GPIO26_ULT: length 12.3
  BOTTOM w0.076: 63.95,68.69 63.95,68.86 63.71,69.11 63.2,69.11 63.05,68.96 61.98,68.96 61.73,69.22 U20.AN3
  BOTTOM w0.127: 63.95,68.69 64.1,68.53 64.56,68.53 65.65,67.44 65.65,63.34 66.85,62.13 67.97,62.13 R408.1
GPIO27_EC: length 175.6
  TOP w0.127: v2(204.64,100.34) 204.64,100.06 206.01,98.68 206.42,98.68 206.82,98.28 207.69,98.28 209.36,96.6 v1(209.64,96.6) v2(210.46,96.6)
  IN2 w0.127: v2(210.46,96.6) 210.43,96.58 209.47,96.58 208.83,95.94 207.87,95.94 207.38,95.46 206.29,95.46 205.78,94.95 203.39,94.95 202.47,94.04 198.74,94.04 197.95,93.25 195.34,93.25 193.81,91.71 193.6,91.71 192.86,91.71 192.61,91.97 192.3,91.97 192.09,91.97 188.82,91.97 184.04,87.19 184.04,86.41 180.44,82.81 178.67,82.81 175.88,80.02 172.53,80.02 171.54,79.02 170.7,79.02 157.47,79.02 152.91,83.58 136.61,83.58 136.09,83.06 106.16,83.06 103.56,85.67 97.54,85.67 95.6,87.61 94.37,87.61 93.24,87.61 93.05,87.8 88.2,87.8 84.96,84.55 84.96,83.4 84.44,82.89 v2(83.69,82.89)
  BOTTOM w0.127: v2(204.64,100.34) 204.64,100.56 204.25,100.96 U7.23 ; v2(83.69,82.89) 83.8,82.77 83.8,77.66 78.54,72.4 78.54,68.47 78.53,68.46 78.53,67.41 77.07,65.94 74.31,65.94 74.3,65.95 73.72,65.95 73.27,65.51 73.27,65.23 73.02,64.97 R391.1
GPIO27_ULT: length 20.2
  TOP w0.127: v2(68.67,62.54) 68.65,62.57 68.65,62.64 67.56,63.73 67.56,65.58 65.88,67.26 64.57,67.26 63.91,67.92 63.11,67.92 v1(62.03,69) 61.84,69.19 61.84,69.7 61.43,70.11 60.7,70.11 v2(60.42,69.83)
  BOTTOM w0.127: v2(68.67,62.54) 68.67,61.62 69.03,61.27 70.55,61.27 71.1,61.81 R402.1 71.33,62.21 71.62,62.21 72.51,63.1 72.81,63.1 73.02,63.3 R391.2 ; U20.AN5 60.22,69.64 v2(60.42,69.83)
GPIO28_ULT: length 17.4
  TOP w0.089: v2(59.36,75.19) 59.76,75.6 60.38,75.6 61.04,76.26 62.58,76.26 62.94,76.61 64.81,76.61 65.37,76.05 65.52,76.05
  TOP w0.127: 65.52,76.05 66.16,75.42 68.69,75.42 69.03,75.08 69.3,75.08 69.33,75.04 69.33,74.53 69.7,74.16 v1(70.63,74.16) 71.61,74.16 72,73.77 v2(73.12,73.77)
  BOTTOM w0.127: U20.AD7 v2(59.36,75.19) ; R348.1 73.04,73.69 v2(73.12,73.77)
GPIO33_EC: length 188.1
  IN1 w0.127: v2(199.76,87.91) 199.59,87.74 197.35,87.74 196.11,86.49 194.6,86.49 193.58,85.47 193.58,84.16 193.82,83.92 193.82,83.18 192.65,82.01 192.65,80.56 186.69,74.6 156.93,74.6 154.79,76.74 88.33,76.74 81.78,70.19 81.78,50.81 77.81,46.84 77.63,46.84 77.08,46.28 v2(75.66,46.28)
  BOTTOM w0.127: D8.1 199.43,90.58 199.55,90.47 R201.2 v2(199.55,88.65) 199.55,88.46 199.76,88.24 v2(199.76,87.91) ; v2(75.66,46.28) 75.61,46.28 74.92,46.97 74.72,46.97 74.34,47.35 73.59,47.35 72.29,48.65 64.11,48.65 56.5,56.26 56.5,59.92 56.76,60.18 R420.1
GPIO42_EC: length 26.2
  BOTTOM w0.127: U7.75 221.72,100.56 223.07,101.91 223.07,104.4 225.58,106.92 225.58,106.93 225.77,107.12 225.77,108.95 227.25,110.42 227.25,113.21 227.65,113.62 227.65,114.36 v4(226.92,115.09) 224.53,115.09 223.92,115.7 223.17,115.7 R12.1 222.91,115.76 222.72,115.58 221.75,115.58 R13.2
GPIO44_ULT: length 5.5
  BOTTOM w0.076: U20.AK4 61.18,71.86 61.61,71.86 61.67,71.79 62.41,71.79 62.57,71.96 63.12,71.96 63.22,71.86 63.39,71.86
  BOTTOM w0.127: R364.1 65.45,71.2 64.79,71.86 63.39,71.86
GPIO50_ULT: length 5.6
  BOTTOM w0.076: U20.P3 61.65,79.71 61.9,79.45 63.7,79.45 63.98,79.17 64.32,79.17 65.04,79.89 65.42,79.89
  BOTTOM w0.127: 65.42,79.89 65.74,79.89 R288.1 65.87,80.08 66.06,80.27 R274.2
GPIO52_ULT: length 14
  BOTTOM w0.076: U20.L1 62.87,81.18 63.54,81.18 64.65,82.29 64.65,83.66 64.98,83.99 64.98,84.74 65.19,84.95 65.19,85.85 65.42,86.09
  BOTTOM w0.127: 65.42,86.09 65.8,86.47 65.8,86.64 66.74,87.58 R218.1 67.08,87.88 67.18,87.79 69.26,87.79 69.38,87.66 69.99,87.66 70.6,87.05 70.91,87.05 71.14,86.82 R239.2
GPIO66_ULT: length 9.6
  BOTTOM w0.076: 62.93,88.24 62.93,88.04 63.34,87.64 63.34,87.19 63.21,87.06 63.21,85.78 62.95,85.52 62.46,85.52 62.29,85.35 61.84,85.35 U20.D3
  BOTTOM w0.127: R148.2 R160.2 64.65,91.66 64,91.01 64,90.58 62.93,89.51 62.93,88.24
GPIO70_ULT: length 5.9
  BOTTOM w0.076: 61.28,87.91 61.28,87.52 61.13,87.36 60.68,87.36 60.44,87.13 60.44,86.7 U20.C4
  BOTTOM w0.127: R177.1 63.2,90.37 62.48,89.64 62.36,89.64 61.82,89.1 61.82,88.45 61.28,87.91
GPIO76_ULT: length 7.1
  BOTTOM w0.076: U20.P1 62.92,79.64 64.03,79.64 TP86.1 64.44,80.05 64.74,80.05 65.08,80.4 65.08,81.25 65.24,81.41 65.42,81.41
  BOTTOM w0.127: R287.1 67.92,80 67.68,80.24 67.22,80.24 67.05,80.41 67.04,80.41 66.03,81.41 65.42,81.41
GPIO77_ULT: length 22.4
  TOP w0.089: 63.65,80.75 63.26,80.75 61.98,79.47 60.91,79.47 60.84,79.39 60.1,79.39 59.73,79.02 59.73,79.02 v3(59.71,79)
  TOP w0.127: v2(75.05,87.36) 75.48,86.92 75.48,85.36 75.02,84.89 73.07,84.89 72.15,83.98 72.15,83.77 70.12,81.74 69.02,81.74 68.97,81.69 66.62,81.69 66.16,82.15 65.04,82.15 63.65,80.75
  BOTTOM w0.127: R217.1 74.54,87.86 v2(75.05,87.36) ; U20.U6 59.53,78.82 v3(59.71,79)
GPIO86_ULT: length 1.5
  TOP w0.127: TP25.1 58.13,80.85 v2(58.51,80.85)
  BOTTOM w0.127: U20.L8 58.23,81.14 v2(58.51,80.85)
GSPI0_CLK: length 21.8
  TOP w0.076: 62.21,84.46 61.12,83.36 61.12,83.2 60.37,82.45 59.7,82.45 v2(59.1,81.85)
  TOP w0.127: 62.21,84.46 62.54,84.78 62.54,86.41 62.32,86.63 62.32,88.02 63.42,89.11 63.42,90.94 63.16,91.19 63.16,92.64 v1(63.64,93.12) 64.51,93.99 65.43,93.99 67.94,96.49 v2(67.94,96.65)
  BOTTOM w0.127: v2(59.1,81.85) 59.1,81.81 U20.L6 ; v2(67.94,96.65) 67.94,96.58 67.3,95.94 RP2.4
GSPI0_CS: length 26.5
  TOP w0.089: v2(59.79,79.97) 59.82,79.97 60.22,80.37 60.8,80.37 60.96,80.53 62.53,80.53 63.32,81.32 63.58,81.32
  TOP w0.127: v3(74.39,96.65) 73.72,95.98 72.73,95.98 69.6,92.85 69.6,92.55 68.97,91.92 68.72,91.92 66.24,89.44 66.24,87.03 64.91,85.71 64.91,82.81 64.52,82.42 64.52,82.26 63.58,81.32
  BOTTOM w0.127: U20.R6 59.53,79.7 v2(59.79,79.97) ; RP1.3 74.16,96.27 74.39,96.5 v3(74.39,96.65)
GSPI0_MISO: length 18.5
  TOP w0.076: v2(59.78,80.9) 60.23,81.35 60.78,81.35 61,81.13 62.22,81.13 v1(62.57,81.48) 62.91,81.82 62.91,82.27 63.88,83.25
  TOP w0.127: v2(68.01,92.94) 67.81,92.75 67.81,92.09 65.47,89.75 65.47,87.43 64.08,86.04 64.08,83.44 63.88,83.25
  BOTTOM w0.127: U20.N6 59.53,80.65 v2(59.78,80.9) ; RP2.6 67.94,93.02 v2(68.01,92.94)
GSPI1_CLK: length 22.1
  TOP w0.076: v2(59.71,81.89) 60.09,82.28 60.42,82.28 61.28,83.13 61.28,83.29 61.78,83.79 62.03,83.79 62.73,84.49 62.73,86.49 62.53,86.7 62.53,87.61 62.95,88.03 62.95,88.12
  TOP w0.127: v3(69.28,96.65) 69.23,96.65 68.76,96.18 68.05,96.18 65.55,93.68 64.71,93.68 64.24,93.21 64.24,91.15 63.69,90.6 63.69,88.86 62.98,88.16 62.95,88.12
  BOTTOM w0.127: RP3.1 69.08,96.45 v3(69.28,96.65) ; v2(59.71,81.89) 59.81,81.79 59.81,81.75 U20.L5
GSPI1_CS: length 27.3
  TOP w0.089: v2(58.51,79.95) 58.51,80.09 58.87,80.45 v1(59.45,80.45) 60.04,80.45 60.14,80.55 60.72,80.55 60.89,80.71 62.43,80.71 63.3,81.57 63.52,81.57
  TOP w0.127: 63.52,81.57 64.24,82.29 64.24,82.5 64.65,82.91 64.65,85.89 65.98,87.22 65.98,89.54 68.61,92.18 68.87,92.18 69.35,92.65 69.35,92.95 72.63,96.23 73.28,96.23 v2(73.73,96.68)
  BOTTOM w0.127: RP1.2 73.53,96.47 v2(73.73,96.68) ; v2(58.51,79.95) 58.51,79.84 U20.R7
GSPI1_MISO: length 28
  TOP w0.089: 63.49,81.07 63.33,81.07 61.92,79.66 60.8,79.66 60.71,79.57 59.56,79.57 v2(59.16,79.97)
  TOP w0.127: 63.49,81.07 63.65,81.07 64.75,82.16 64.75,82.24 65.42,82.91 v1(65.42,83.06) 65.42,85.86 66.49,86.92 66.49,88 67.19,88.7 67.19,89.86 69,91.67 69.08,91.67 69.85,92.44 69.85,92.74 72.84,95.73 74.13,95.73 75.02,96.62 v2(75.02,96.65)
  BOTTOM w0.127: RP1.4 74.8,96.14 75.02,96.37 v2(75.02,96.65) ; v2(59.16,79.97) 58.88,80.25 U20.N7
GSPI1_MOSI: length 21.2
  TOP w0.127: v3(73.07,96.68) 72.92,96.53 72.56,96.53 69.09,93.06 69.09,92.76 68.76,92.43 68.51,92.43 65.72,89.64 65.72,87.32 64.36,85.96 64.36,83.14 v2(63.75,82.53)
  BOTTOM w0.076: U20.K2 62.23,82.06 62.36,82.06 62.59,82.28 63.05,82.28 63.3,82.53 63.49,82.53
  BOTTOM w0.127: 63.49,82.53 63.49,82.53 v2(63.75,82.53) ; v3(73.07,96.68) 73.07,96.37 72.89,96.2 RP1.1
GYRO_INT1: length 20.5
  TOP w0.127: v2(241.83,110.27) v1(241.83,111.46) 241.83,113.04 236.7,118.16 U23.7
  BOTTOM w0.127: U5.28 241.7,106.45 241.34,106.81 241.34,109.78 v2(241.83,110.27)
GYRO_INT2: length 11.6
  TOP w0.127: U23.6 236.99,117.51 239.9,114.61 v1(239.9,114) 239.16,113.26 v2(238.88,113.26)
  BOTTOM w0.127: U5.55 242.7,112.97 242.59,113.09 239.06,113.09 v2(238.88,113.26)
H_CPU_SVIDALRT#: length 4.9
  BOTTOM w0.076: U20.L62 24.54,80.99 23.88,80.99 23.85,80.97 23.26,80.97
  BOTTOM w0.127: R276.1 20.82,80.24 21.61,81.03 22.9,81.03 22.97,80.97 23.26,80.97
H_CPU_SVIDDAT: length 4.3
  BOTTOM w0.076: U20.L63 23.92,81.28 23.84,81.21 23.23,81.21
  BOTTOM w0.127: R265.1 20.95,82.4 21.73,81.62 22.37,81.62 22.6,81.39 23,81.39 23.18,81.21 23.23,81.21
H_PROCHOT#: length 237.9
  TOP w0.127: v2(194.94,105.59) 195.9,104.63 198.06,104.63 199.41,103.28 v1(199.69,103.28) 200.7,103.28 v2(201.19,102.8) ; v2(118.46,101.48) 118.1,101.12 117.42,101.12 117.42,101.12 115.95,101.12 115.29,101.78 114.16,101.78 113.71,102.24 112.11,102.24 111.07,101.2 103.6,101.2 103.17,101.63 103.17,102.55 102.91,102.81 95.67,102.81 95.32,102.47 91.79,102.47 90.28,100.96 86.95,100.96 86.59,101.31 85.52,101.31 84.65,100.45 84.65,99.83 83.8,98.98 83.44,98.98 83.12,98.98 78.77,98.98 78.61,99.14 76.64,101.11 75.33,101.11 74.98,100.75 71.7,100.75 68.62,103.84 66.97,103.84 66.22,103.09 64.19,103.09 v2(63.64,103.64) 63.49,103.64 62.83,102.98 61.71,102.98 60.55,101.81 57.65,101.81 55.17,99.33 52.54,99.33 52.18,99.69 42.92,99.69 42.49,99.26 41.37,99.26 39.72,97.6 36.02,97.6 33.88,95.46 27.02,95.46 25.89,94.33 23.77,94.33 23.11,93.67 21.54,93.67 18.84,90.96 15.3,90.96 15.13,91.14 14.37,91.14 14.09,91.42 11.96,91.42 10.96,90.42 10.96,86.42 11.55,85.83 14.42,85.83 14.48,85.77 15.32,85.77 15.92,86.37 16.88,86.37 v2(19.47,83.77)
  IN2 w0.127: v2(118.46,101.48) 119.35,100.59 124.22,100.59 125.3,99.51 129.64,99.51 131.79,101.66 136.79,101.66 138.65,99.8 144.34,99.8 144.81,99.33 153.82,99.33 156.39,96.76 161.99,96.76 163.68,95.08 164.84,95.08 165.19,94.72 166.11,94.72 166.46,95.08 174.87,95.08 175.25,95.46 175.25,97.36 179.71,101.82 182.25,101.82 183.2,102.77 187.6,102.77 188.73,103.9 189.99,103.9 192,105.91 192.03,105.91 192.04,105.92 194.61,105.92 v2(194.94,105.59)
  BOTTOM w0.127: R266.1 19.47,83.71 v2(19.47,83.77) 19.49,83.77 19.79,83.47 R261.1 ; C66.2 200.36,100.5 Q9.3 201.19,101.83 v2(201.19,102.8) ; PR75.2 64.37,102.81 63.64,103.54 v2(63.64,103.64) 63.64,103.71 63.87,103.94 PR54.2
H_PROCHOT#_EC: length 6.1
  BOTTOM w0.127: Q9.2 200.02,99.95 200.02,98.63 200.47,98.18 v4(200.73,98.18) 201.77,98.18 201.91,98.04 R92.2 201.95,97.76 U7.15
H_SYS_PWROK_XDP: length 6.2
  TOP w0.127: CN1.54 11.99,76.11 11.83,75.95 11.65,75.95 v2(10.99,75.29)
  BOTTOM w0.127: v2(10.99,75.29) 11.3,75.6 12.08,75.6 v2(12.22,75.46) 12.6,75.08 R326.1 13.03,75.06 R342.2 C274.2
H_VCCST_PWRGD: length 24
  BOTTOM w0.127: D5.2 18.79,99.67 19.3,99.17 19.3,98.15 20.33,97.12 R114.1 20.33,94.32 R121.2 20.27,94.06 U11.4 18.93,93.59 18.53,93.2 18.02,93.2 C154.2 16.88,93.06 16.88,93.95 16.37,94.47 v2(15.61,94.47) 15.03,93.88 15.03,92.94 13.71,91.62 13.71,90.3 13.45,90.05 13.45,89.27 R240.1
H_VCCST_PWRGD_R: length 10.6
  BOTTOM w0.076: U20.B59 26.91,87.14 26.58,87.47 26.58,88.07 26.31,88.35
  BOTTOM w0.127: R121.1 21.21,92.05 v4(21.46,91.8) 22.27,90.99 22.65,90.99 24.22,89.41 25.72,89.41 26.31,88.83 26.31,88.35
H_VR_ENABLE_MCP: length 67.5
  TOP w0.127: v2(67.15,99.42) 66.41,98.68 58.95,98.68 56.13,95.86 56.13,95.54 54.8,94.21 45.87,94.21 44.71,95.37 43.79,95.37 43.47,95.05 42.11,95.05 41.2,94.15 38.82,94.15 35.75,91.08 32.79,91.08 31.79,92.08 31.26,92.08 30.47,91.29 29.08,91.29 28.31,92.05 27.93,92.05 27.42,91.55 24.63,91.55 23.61,90.53 v1(23.44,90.53) v2(22.47,90.53)
  IN2 w0.127: v2(25.84,84.65) 22.73,87.77 22.73,90.28 v2(22.47,90.53)
  BOTTOM w0.127: v2(25.84,84.65) 26.14,84.35 U20.F60 ; R175.2 21.86,91.04 22.37,90.53 v2(22.47,90.53) ; v2(67.15,99.42) 66.97,99.6 66.97,100.21 66.91,100.27 66.91,101.61 65.54,102.98 64.9,102.98 64.38,103.49 64.38,103.86 64.89,104.37 PR53.1
HD_BCLK: length 1.6
  BOTTOM w0.127: U18.6 220.65,79.92 221.23,80.5 R275.1
HD_SDIN0: length 1.5
  BOTTOM w0.127: U18.8 221.38,79.12 R289.2
HDMI_HPD_CON: length 168
  TOP w0.127: v2(117.7,98.18) 115.84,96.32 113.65,96.32 113.3,95.97 106.31,95.97 105.93,96.35 105.3,96.35 98.9,96.35 98.29,96.96 96.26,96.96 95.76,97.45 92.27,97.45 91.68,96.87 91.47,96.87 90.94,96.87 90.45,96.37 88.81,96.37 88.31,96.87 86.78,96.87 86.23,96.32 86.02,96.32 79.47,96.32 78.79,95.64 78.58,95.64 75.46,95.64 74.72,94.89 73.47,94.89 73.26,94.69 73.26,94.69 71.82,93.25 v1(71.82,93.05) v2(71.82,92.33)
  IN1 w0.127: v2(71.82,92.33) 71.66,92.18 69.92,92.18 69.39,91.64 65.84,91.64 64.36,90.15 62.55,90.15 61.43,89.03 61.43,88.37 60.75,87.69 v2(59.61,87.69)
  IN2 w0.127: v2(117.7,98.18) 122.47,93.4 131.37,93.4 132.75,92.03 137.16,92.03 137.19,92.07 138.83,92.07 139.66,92.89 145.88,92.89 146.3,92.89 147,92.89 148.65,91.24 155.33,91.24 156.42,90.15 165.9,90.15 167.8,88.24 173.11,88.24 175.27,90.4 176.08,90.4 181.01,95.32 182.23,95.32 185.82,98.91 189.49,98.91 189.9,99.32 v2(190.92,99.32)
  BOTTOM w0.076: U20.C8 58.59,86.52 59.36,87.29 59.36,87.44 v2(59.61,87.69)
  BOTTOM w0.127: CN8.19 189.12,86.51 191,88.39 191,89.26 190.75,89.51 R197.1 189.61,89.93 189.73,90.05 190.75,90.05 191.15,90.45 191.15,93.97 191.64,94.45 191.64,96.6 191.97,96.93 191.97,98.58 191.23,99.32 v2(190.92,99.32)
HOLD#: length 6.1
  BOTTOM w0.127: U9.7 87.39,95.46 TP69.1 88.38,93.56 R141.2 87.4,92.8 87.09,92.49 87.09,92.23 86.75,91.89 R153.2
HOME_BUTTON_EC: length 48.5
  IN1 w0.127: v2(214.22,86.64) 213.95,86.91 208.56,86.91 206.72,85.07 204.46,85.07 204.08,84.69 199.89,84.69 198.68,83.48 195.25,83.48 194.3,82.53 v2(194.3,79.53)
  IN2 w0.127: v2(214.22,86.64) 214.22,87.71 214.47,87.97 216.68,87.97 218.64,89.92 v2(218.64,90.21)
  BOTTOM w0.127: U7.97 217.5,91.32 217.62,91.45 218.05,91.45 218.18,91.32 218.18,90.67 v2(218.64,90.21) ; Q30.5 181.98,80.84 182.3,81.16 182.62,81.16 183.05,81.59 183.67,81.59 R477.2 184.69,81.09 v2(184.94,80.84) 186.25,79.53 v2(194.3,79.53)
HOME_BUTTON_INT#: length 113.7
  TOP w0.127: v2(252.93,93.22) 252.93,90.53 250.45,88.05 246.87,88.05 245.72,86.91 v1(245.72,86.42) v2(245.72,85.54)
  IN1 w0.127: v2(201.67,95.61) 202.58,95.61 204.59,93.6 205.61,93.6 210.14,98.14 214.46,98.14 214.85,98.53 217.98,98.53 219.4,99.95 222.2,99.95 222.47,100.23 226.31,100.23 226.87,100.79 228.11,100.79 228.28,100.63 230.19,100.63 230.35,100.79 247.77,100.79 248.05,101.07 250.18,101.07 251.25,100.01 253,100.01 253.43,99.57 253.43,93.73 v2(252.93,93.22)
  BOTTOM w0.127: v2(245.72,85.54) 254.01,77.25 CN11.3 ; U7.27 202.34,102.56 201.6,103.29 198.66,103.29 198.57,103.21 198.57,99.98 198.7,99.85 199.46,99.85 199.74,99.57 199.74,98.35 200.41,97.68 200.65,97.68 200.89,97.44 R479.2 200.89,96.89 200.78,96.78 200.78,96.2 200.88,96.09 201.19,96.09 v2(201.67,95.61) 201.86,95.42 R116.2
HOME_BUTTON_LED: length 108.6
  TOP w0.127: v2(190.54,88.73) 193.44,91.62 196,91.62 196.28,91.9 197.43,91.9 198.51,92.98 199.98,92.98 200.35,92.61 201.54,92.61 201.97,92.18 207.03,92.18 207.59,91.62 220.38,91.62 221.22,92.46 222.47,92.46 222.75,92.18 222.75,90.3 223.84,89.21 223.84,88.52 231.51,80.85 247.34,80.85 v1(248.68,82.2) 249.42,82.94 v2(250.51,82.94)
  BOTTOM w0.127: v2(250.51,82.94) 254.25,82.94 256.18,81.01 264.53,81.01 265.55,79.99 265.55,76.69 265.11,76.25 CN11.5 ; Q30.2 181.98,82.91 181.73,83.16 179.84,83.16 179.46,83.55 179.46,84.76 179.74,85.04 180.73,85.04 181.76,86.07 183.21,86.07 184.67,87.53 185.54,87.53 186.15,88.14 188.74,88.14 188.9,88.31 R209.2 188.9,88.79 189.19,89.07 190.49,89.07 190.54,89.02 v2(190.54,88.73)
HOME_BUTTON_LED#: length 10.1
  BOTTOM w0.127: CN8.16 187.62,83.1 187.47,83.25 185.87,83.25 185.54,82.91 185.16,82.91 184.82,83.25 183.66,83.25 v2(183.46,83.04) 183.25,83.25 182.8,83.25 182.63,83.08 Q30.3 182.63,81.69 182.38,81.44 181.91,81.44 181.33,80.86 Q30.6
HOME_BUTTON_SLEEP: length 2.2
  TOP w0.127: TP7.1 220.26,103.1 v2(220.49,102.88)
  BOTTOM w0.127: U7.70 220.17,102.56 v2(220.49,102.88)
HOME_BUTTONE POWER: length 37.6
  BOTTOM w0.127: R259.1 R478.1 233.62,83.95 234.18,83.95 234.27,83.86 C220.2 235.57,83.86 235.91,84.21 235.91,85.25 236.23,85.58 237.2,85.58 237.56,85.22 237.56,84.83 237.56,84.83 237.56,84.61 241.18,80.99 245.43,76.75 CN11.4
HPOUT_L: length 30.6
  IN1 w0.381: v2(213.91,77.45) 212.75,76.29 211.26,76.29 210.88,75.91 210.88,75.03 210.29,74.44 202.65,74.44 201.08,76 201.08,78.57 201.85,79.33 v2(202.07,79.33) 202.07,80.4 204.18,82.5 205.63,82.5 v3(206.9,83.77)
  BOTTOM w0.203: U18.23 214.18,79.12 213.76,78.69 213.76,77.58 213.89,77.45 v2(213.91,77.45)
  BOTTOM w0.254: C223.1 206.34,84.33 v3(206.9,83.77) ; v2(202.07,79.33) 201.85,79.1 R292.2
HPOUT_L_1: length 3.4
  BOTTOM w0.254: C223.2 206.85,83.04 207.26,82.63 v4(207.26,82.15) 207.26,81.21 207.58,80.89 U19.1
HPOUT_R: length 17.9
  IN1 w0.381: v3(202.05,78.21) 202.91,77.35 207.03,77.35 v3(208.91,75.47) 209.73,76.3 209.73,76.56 210.88,77.7 212.77,77.7 v2(213.28,78.21)
  BOTTOM w0.203: U18.24 214.12,79.52 213.28,78.67 v2(213.28,78.21)
  BOTTOM w0.254: v3(208.91,75.47) 208.91,75.9 209.19,76.18 C264.1 ; v3(202.05,78.21) 201.78,78.21 R296.2
HPOUT_R_1: length 2.8
  BOTTOM w0.254: U19.5 207.9,78.48 208.04,78.34 v2(208.04,77.09) 208.02,77.07 208.17,76.92 C264.2
HWPG: length 390.5
  TOP w0.127: v2(132.58,105.42) 132.11,104.95 129.29,104.95 128.67,104.32 126.03,104.32 v2(125.42,104.93) 124.71,104.22 v1(106.34,104.22) 103.33,104.22 102.35,105.2 v2(102.35,105.49) 101.9,105.95 100.47,105.95 100.12,106.3 v2(100.12,109.05) ; v2(68.06,105.39) 67.59,105.86 65.6,105.86 64.61,104.86 59.88,104.86 59.29,105.45 57.21,105.45 56.61,106.05 56.09,106.05 55.24,105.2 50.09,105.2 47.98,103.09 40.97,103.09 38.95,101.07 37.11,101.07 36.61,100.58 25.4,100.58 25.33,100.5 18.98,100.5 v2(17.26,98.79) 16.76,99.29 14.85,99.29 14.6,99.04 11.17,99.04 10.66,99.55 v2(10.38,99.55)
  TOP w0.254: U3.10 4.72,57.86 4.56,58.02 3.5,58.02 3.07,57.59 v2(3.07,56.37) 3.07,56.36 U3.13 5.18,55.58 5.07,55.48 5.07,54.39 5.22,54.23 v1(6.75,54.23) 7,54.23 7.65,54.88 U3.1 8.98,55.63 9.44,55.17 v2(9.8,55.17) ; U3.4 9.11,57.36 9.68,57.93 v2(9.68,58.55)
  IN2 w0.127: v2(167,104.75) 167.66,104.09 171.09,104.09 171.39,103.79 174.12,103.79 177.01,106.69 181.99,106.69 183.68,108.37 188.45,108.37 189.15,109.07 189.15,110.65 189.78,111.28 194.43,111.28 195.75,109.96 201.31,109.96 v2(201.85,110.5) ; v2(68.06,105.39) 68.06,106.79 67.63,107.22 67.63,112.43 72.66,117.45 74.41,117.45 v2(74.85,117.89) 75.29,117.44 77.5,117.44 78.07,118.01 85.69,118.01 86.43,117.28 89.27,117.28 90.57,115.98 96.84,115.98 100.12,112.71 v2(100.12,109.05) ; v2(10.38,99.55) 10.38,98.99 11.02,98.35 11.02,96.55 10.3,95.84 9,95.84 6.87,93.71 4.32,93.71 2.65,92.03 2.65,56.79 v2(3.07,56.37) 2.72,56.03 2.72,36.24 5.07,33.89 5.07,32.47 4.34,31.73 4.34,28.55 4.77,28.12 4.77,27.77 8.22,24.32 8.22,18.68 7.72,18.17 v2(7.72,17.38)
  BOTTOM w0.127: PR130.2 8.87,17.38 v2(7.72,17.38) ; v2(201.85,110.5) 202.02,110.32 202.43,110.32 202.76,109.99 202.76,109 202.88,108.88 203.84,108.88 204.21,109.25 204.87,109.25 205.12,109 205.12,108.62 203.85,107.35 203.85,105.75 204.16,105.44 204.54,105.44 206.04,103.95 206.04,103.77 206.04,103.77 206.04,102.98 207.38,101.63 207.58,101.63 208.12,101.1 208.33,101.1 208.6,101.1 208.93,100.77 208.93,99.55 209.14,99.34 209.14,95.79 208.37,95.03 207.89,95.03 206.52,96.4 205.61,96.4 204.65,97.36 U7.14 202.45,97.36 202.23,97.13 C89.2
  BOTTOM w0.178: 146.29,112.28 147.75,113.75 162.69,113.75 163.47,112.97 163.47,111.84 164.58,110.72 164.58,108.5 164.89,108.19 164.89,107.32 167,105.21 v2(167,104.75) ; 146.29,112.28 PR26.2 ; 146.29,112.28 145.71,112.86 133.74,112.86 133.19,112.31 133.19,110.22 132.75,109.77 132.75,105.58 v2(132.58,105.42) ; PR84.2 103.24,101.59 103.24,102.79 PR68.2 102.62,103.1 102.35,103.36 v2(102.35,105.49)
  BOTTOM w0.203: PR5.2 75.3,117.43 v2(74.85,117.89)
  BOTTOM w0.254: PR46.2 125.61,105.2 125.42,105 v2(125.42,104.93) ; U11.2 18.28,96.88 18.41,97.01 18.41,97.39 18.79,97.77 D5.1 18.53,98.5 18.31,98.28 17.77,98.28 v2(17.26,98.79) ; v2(9.8,55.17) 9.97,55.17 10.3,55.5 10.3,56.85 9.68,57.48 v2(9.68,58.55)
I2C0_SCL: length 16.3
  BOTTOM w0.076: U20.F3 61.71,84.2 61.97,83.95 62.96,83.95 63.22,84.2 63.22,84.41 63.66,84.85 63.66,85.29 63.87,85.5 63.87,86.78 64.05,86.97 64.05,87.89 63.95,88 63.95,88.24
  BOTTOM w0.127: 63.95,88.24 63.95,89.24 65.04,90.33 65.04,90.58 65.22,90.76 65.81,91.34 65.81,91.34 65.96,91.5 66.1,91.5 66.6,91.99 66.84,91.99 v2(69.29,91.99) 70.35,93.05 RP3.8
I2C0_SDA: length 12.2
  BOTTOM w0.076: 63.44,88.24 63.44,88.04 63.71,87.77 63.71,87.09 63.54,86.92 63.54,85.64 63.33,85.43 63.33,84.99 62.96,84.62 62.55,84.62 U20.F2
  BOTTOM w0.127: RP2.8 66.67,93.1 66.58,93.01 66.13,93.01 65.38,92.26 65.38,91.63 64.46,90.71 64.46,90.39 63.44,89.38 63.44,88.24
I2C1_SCL: length 67.1
  TOP w0.127: U1.2 226.25,115.78 226.59,115.45 226.59,114.94 226.79,114.74 226.79,114.38 v3(226.51,114.1) ; U23.2 233.73,114.91 v2(234.43,114.2)
  IN1 w0.114: v2(234.43,114.2) 234.43,113.9 233.42,112.88 229.02,112.88 227.45,114.46 226.86,114.46 v3(226.51,114.1) 226.07,113.66 220.08,113.66 217.92,111.5 213.32,111.5 212.94,111.13 205.87,111.13 205.38,110.65 203.42,110.65 202.2,109.43 194.33,109.43 193.97,109.78 193.3,109.78 v2(192.83,109.31)
  BOTTOM w0.127: v2(234.43,114.2) 234.43,114.22 234.64,114.42 238.6,114.42 238.74,114.28 R18.1 239.09,114.38 239.92,114.38 240.71,113.59 243.96,113.59 244.2,113.35 U5.58 ; v2(192.83,109.31) 192.28,108.77 192.02,108.77 189.81,106.56 189.63,106.56 189.29,106.22 CN3.4
I2C1_SCL_PCH: length 14.2
  BOTTOM w0.076: 63.7,88.24 63.7,88.02 63.87,87.84 63.87,87.02 63.7,86.85 63.7,85.57 63.49,85.36 63.49,84.92 62.85,84.28 U20.F1
  BOTTOM w0.127: 63.7,88.24 63.7,89.31 64.69,90.3 64.69,90.61 65.89,91.82 65.89,92.04 66.35,92.5 v2(66.79,92.5) 69.08,92.5 69.72,93.13 69.72,93.87
I2C1_SDA: length 68.9
  TOP w0.127: v2(234.43,114.84) 234.38,114.89 U23.3 ; v2(227.2,114) 227.02,114.18 227.02,114.84 226.84,115.02 226.84,115.55 227.05,115.76 U1.3
  IN1 w0.114: v2(234.43,114.84) 234.92,114.36 234.92,113.95 233.57,112.6 228.59,112.6 v2(227.2,114) 226.59,113.39 220.16,113.39 218.06,111.29 213.41,111.29 213.02,110.9 205.94,110.9 205.46,110.42 203.5,110.42 202.28,109.2 193.69,109.2 v2(193.59,109.3)
  BOTTOM w0.127: R14.1 238.74,115.92 238.19,116.46 v2(237.86,116.46) ; R14.1 239.59,115.17 240.89,113.87 244.09,113.87 244.7,113.26 U5.59 ; R14.1 238.74,114.9 238.51,114.67 234.6,114.67 v2(234.43,114.84) ; v2(193.59,109.3) 192.57,108.29 191.99,108.29 190.09,106.39 CN3.5
I2C1_SDA_PCH: length 20
  TOP w0.076: 63.24,86.52 63.24,84.54 v2(61.82,83.11)
  TOP w0.127: v3(70.58,96.65) 70.58,96.27 69.05,94.75 68.14,94.75 66.62,93.22 66.62,91.98 64.71,90.07 64.71,88.44 64.7,88.43 64.7,88.18 63.24,86.72 63.24,86.52
  BOTTOM w0.076: U20.G4 61.28,83.11 v2(61.82,83.11)
  BOTTOM w0.127: v3(70.58,96.65) 70.58,96.47 70.35,96.25 RP3.3
IDEA_G: length 8.5
  BOTTOM w0.254: PQ13.4 153,91.14 153.33,91.48 v2(153.33,92.03) 153.33,92.11 152.85,92.59 150.46,92.59 150.11,92.94 150.11,93.06 PR112.2 149.84,93.19 149.09,92.44 149.09,91.95 148.7,91.56 PQ12.3
IMVP_PWRGD: length 114.5
  TOP w0.127: v2(89.58,102.14) 89.11,102.61 85.66,102.61 83.84,100.78 83.84,100.17 83.46,99.79 79.11,99.79 76.71,102.19 71.42,102.19 68.94,104.67 65.31,104.67 64.87,104.23 59.62,104.23 59.05,104.79 57.01,104.79 56.78,104.56 v2(56.64,104.56) 56.56,104.49 50.28,104.49 48.24,102.46 41.23,102.46 39.21,100.44 37.37,100.44 37.13,100.2 25.65,100.2 23.93,98.47 v1(22.57,98.47) 21.65,98.47 17.14,93.96 v2(16.25,93.96)
  BOTTOM w0.127: U16.2 76.98,85.63 77.08,85.73 77.7,85.73 77.9,85.93 78.5,85.93 79.7,87.13 79.7,87.71 80.44,88.45 80.44,88.46 80.97,88.99 80.97,90.84 80.64,91.17 80.64,93.04 81.05,93.45 81.93,93.45 82.36,93.88 82.36,96.07 84.75,98.46 86.83,98.46 87.29,98.91 88.44,98.91 89.58,100.05 v2(89.58,102.14) ; v2(16.25,93.96) 16.25,93.8 16.47,93.58 D7.1 16.62,90.89 R196.2 ; v2(56.64,104.56) 56.94,104.56 PR61.1 57.31,104.89 58.09,104.11 PR60.2
IMVP_PWRGD_R: length 219.3
  TOP w0.127: v2(23.23,89.34) 23.51,89.62 v1(24.5,89.62) 29.81,89.62 30.74,90.54 35.76,90.54 38.98,93.77 41.36,93.77 42.26,94.67 43.63,94.67 43.95,94.99 44.56,94.99 45.76,93.78 46.48,93.78 47,93.26 52,93.26 52.49,93.76 54.88,93.76 56.51,95.38 56.51,95.71 59.1,98.3 70.26,98.3 70.55,98.01 85.44,98.01 86.44,99 86.79,99.36 90.91,99.36 91.57,100.02 92.38,100.02 102.46,100.02 102.96,99.51 103.37,99.1 105.85,99.1 106.82,99.1 107.31,98.61 111.76,98.61 112.06,98.31 114.82,98.31 115.25,98.74 116.07,99.56 116.44,99.93 116.92,99.93 116.92,99.93 118.65,99.93 118.98,100.26 121.06,102.34 121.41,102.34 121.98,102.91 129.21,102.91 129.98,103.69 v2(131.49,103.69)
  BOTTOM w0.076: U20.C59 26.91,86.5 26.53,86.88 26.53,87.26 26.42,87.38 26.42,87.89 25.87,88.43
  BOTTOM w0.127: R40.2 196.9,108.95 196.01,109.83 190.52,109.83 188.65,107.97 187.15,107.97 186.38,108.74 186.38,108.78 186.21,108.95 185.62,108.95 184.83,109.73 184.83,110.62 183.94,111.51 176.24,111.51 175.88,111.15 175.88,108.55 175.66,108.34 175.66,107.45 173.3,105.09 172.92,105.09 172.33,104.5 168.29,104.5 165.3,107.5 165.3,108.36 165.09,108.56 165.09,110.85 163.87,112.07 163.87,113.14 162.86,114.15 134.46,114.15 132.78,112.48 132.78,110.42 132.34,109.97 132.34,106.61 132.14,106.41 132.14,104.34 v2(131.49,103.69) ; R196.1 18.8,91.04 D7.2 R175.1 20.2,90.78 20.33,90.66 21.63,90.66 22.27,90.02 22.55,90.02 v2(23.23,89.34) 23.56,89.01 25.57,89.01 25.87,88.7 25.87,88.43
IN_CLK: length 275.9
  IN1 w0.114: v2(29.34,90.15) 29.14,89.95 29.14,89.67 28.87,89.4 28.38,89.4 28.15,89.17 28.15,88.16 29.55,86.76 29.55,85.92 31.37,84.09 31.37,82.65 33.05,80.97 33.86,80.97 35.29,79.55 43.67,79.55 45.75,81.63 45.75,82.66 46.64,83.55 46.64,88.51 47.01,88.88 47.51,88.88 48.95,90.32 51.55,90.32 52.44,91.22 53.32,91.22 55.41,93.31 55.54,93.31 58.53,93.31 59.35,94.13 61.6,94.13 62.69,95.22 62.69,95.23 62.69,95.41 63.48,96.21 63.66,96.21 71.35,96.21 71.39,96.24 71.4,96.24 71.65,96.5 71.65,96.51 71.82,96.68 71.82,96.93 72.95,98.05 78.18,98.05 78.68,97.55 87.42,97.55 87.58,97.4 87.94,97.4 88.2,97.65 88.2,97.91 88.45,98.16 96.5,98.16 97.03,97.64 97.17,97.64 97.91,96.9 99.15,96.9 99.38,96.67 99.74,96.67 100,96.93 100,97.05 106.93,97.05 107.4,96.58 112.05,96.58 112.49,96.15 119.94,96.15 120.61,96.82 124.67,96.82 125.54,97.68 131.1,97.68 131.28,97.68 132.55,96.41 139.1,96.41 140.31,97.62 162.29,97.62 163.97,95.94 163.97,95.68 164.76,94.89 164.76,94.74 165.43,94.07 166.67,94.07 166.77,94.16 172.22,94.16 173.27,93.12 177.26,93.12 177.7,93.56 181.89,93.56 185.97,97.64 185.97,98.25 186.33,98.61 187.48,99.76 187.66,99.76 189.28,99.76 191.71,102.19 194.15,102.19 194.86,102.9 197.86,102.9 198.42,103.46 201.47,103.46 202.06,102.86 205.77,102.86 206.37,103.46 210.39,103.46 210.65,103.2 210.93,103.2 210.99,103.14 211.14,103.14 212.21,103.14 212.67,102.68 213.03,102.68 213.49,103.14 213.92,103.14 214.95,104.17 215.87,104.17 216.22,104.53 217.01,104.53 217.21,104.32 221.65,104.32 222.6,105.28 227.89,105.28 228.5,104.66 229.68,104.66 231.52,104.66 232.87,106.01 238.31,106.01 239.91,104.41 247.5,104.41 248.15,103.76 250.64,103.76 250.99,104.12 252.16,104.12 255.31,100.97 255.31,100.24 v2(254.87,99.8)
  BOTTOM w0.127: C145.1 251.73,93.34 251.73,93.65 252.04,93.96 252.8,93.96 253.48,94.65 253.48,96.92 253.59,97.03 253.59,98.02 255.03,99.46 255.03,99.64 v2(254.87,99.8) ; U20.B57 28.04,87.23 28.36,87.55 28.36,87.88 28.27,87.97 28.27,88.12 28.21,88.18 28.21,89.19 28.43,89.41 28.81,89.41 29.13,89.72 29.13,89.93 v2(29.34,90.15)
IN_CLK#: length 275.9
  IN1 w0.114: v2(28.62,90.15) 28.8,90.15 28.92,90.02 28.92,89.76 28.78,89.62 28.29,89.62 27.93,89.26 27.93,88.07 29.33,86.67 29.33,85.83 31.16,84 31.16,82.56 32.96,80.75 33.77,80.75 35.2,79.33 43.76,79.33 45.97,81.54 45.97,82.57 46.86,83.46 46.86,88.42 47.1,88.67 47.6,88.67 49.04,90.11 51.64,90.11 52.53,91 53.41,91 55.5,93.1 58.62,93.1 59.44,93.92 61.69,93.92 62.9,95.13 62.9,95.32 63.57,95.99 71.44,95.99 71.47,96.02 71.48,96.02 71.87,96.41 71.87,96.42 72.04,96.59 72.04,96.84 73.04,97.83 78.09,97.83 78.59,97.34 87.33,97.34 87.49,97.18 88.03,97.18 88.42,97.56 88.42,97.82 88.54,97.95 96.41,97.95 96.94,97.42 97.08,97.42 97.82,96.68 99.06,96.68 99.29,96.46 99.83,96.46 100.21,96.83 106.84,96.83 107.31,96.37 111.96,96.37 112.4,95.93 120.03,95.93 120.7,96.6 124.58,96.6 124.58,96.6 124.76,96.6 125.63,97.47 131.19,97.47 132.46,96.2 139.19,96.2 140.4,97.4 162.2,97.4 163.75,95.85 163.75,95.59 164.54,94.8 164.54,94.65 165.34,93.85 166.76,93.85 166.86,93.95 172.13,93.95 173.18,92.91 177.35,92.91 177.79,93.34 181.98,93.34 186.19,97.55 186.19,98.16 186.48,98.46 186.97,98.94 187.57,99.55 189.37,99.55 191.8,101.97 194.24,101.97 194.95,102.68 197.95,102.68 198.51,103.24 201.38,103.24 201.97,102.65 205.86,102.65 206.46,103.24 210.3,103.24 210.56,102.98 210.84,102.98 210.9,102.93 211.23,102.93 212.12,102.93 212.41,102.64 212.58,102.47 213.12,102.47 213.58,102.93 214.01,102.93 215.04,103.95 215.96,103.95 216.31,104.31 216.92,104.31 217.12,104.11 221.74,104.11 222.69,105.06 227.8,105.06 228.41,104.44 229.77,104.44 229.77,104.44 231.61,104.44 232.96,105.8 238.22,105.8 239.82,104.2 247.41,104.2 248.06,103.55 250.73,103.55 251.08,103.9 252.07,103.9 255.1,100.88 255.1,100.49 255.05,100.44 v3(254.87,100.44)
  BOTTOM w0.127: v2(28.62,90.15) 28.82,90.15 28.9,90.07 28.9,89.82 28.72,89.64 28.34,89.64 27.98,89.29 27.98,88.08 28.04,88.02 U20.A57 ; C144.1 252.02,93.18 251.96,93.25 251.96,93.55 252.14,93.73 252.89,93.73 253.71,94.55 253.71,96.83 253.81,96.93 253.81,97.92 255.34,99.45 255.34,100.34 255.24,100.44 v3(254.87,100.44)
IN_D0: length 269.8
  IN1 w0.114: v3(256.61,99.52) 256.66,99.47 256.66,99.29 256.53,99.17 256.18,99.17 256.02,99.32 256.02,101.46 255.73,101.75 255.73,104.54 254.25,106.02 239.31,106.02 238.56,106.77 232.59,106.77 231.19,105.37 229.39,105.37 228.8,105.37 228.18,105.99 222.31,105.99 221.89,105.57 221.35,105.03 218.28,105.03 217.82,105.49 214.67,105.49 213.09,103.9 213.08,103.9 213.02,103.85 212.51,103.85 211.28,103.85 211.23,103.91 211.12,103.91 210.65,104.39 210.62,104.39 210.44,104.39 210.44,104.39 209.81,104.39 208.82,105.38 207.11,105.38 206.19,105.38 204.99,104.18 198.09,104.18 197.55,103.64 194.1,103.64 193.54,103.08 191.58,103.08 189.72,101.21 187.2,101.21 184.42,98.43 184.42,97.1 181.59,94.27 173.13,94.27 172.52,94.87 166.46,94.87 166.37,94.78 165.72,94.78 165.47,95.04 165.47,95.18 165.09,95.56 165.09,96.25 163.01,98.33 162.87,98.33 162.87,98.33 162.83,98.33 162.83,98.33 137,98.33 137,98.33 136.82,98.33 136.16,97.67 132.3,97.67 131.57,98.39 130.81,98.39 123.07,98.39 122.2,97.53 117.58,97.53 117.31,97.8 98.02,97.8 97.47,98.35 97.33,98.35 97.04,98.63 97.04,98.87 88.16,98.87 88.12,98.84 85.06,98.84 84.49,98.27 78.97,98.27 78.48,98.76 78.35,98.76 78.21,98.9 71.16,98.9 69.59,97.33 63.6,97.33 61.97,95.7 61.97,95.52 61.3,94.84 59.06,94.84 58.24,94.02 55.83,94.02 55.05,94.02 54.55,93.53 53.65,93.53 51.47,91.35 51.18,91.06 48.65,91.06 47.51,89.91 46.19,89.91 45.8,89.53 45.8,87.28 45.43,86.91 45.43,85.44 45.47,85.4 45.47,83.61 44.96,83.1 44.96,81.88 43.34,80.26 35.59,80.26 33.99,81.86 33.23,81.86 32.1,82.99 32.1,84.44 30.41,86.13 30.41,86.91 29.35,87.97 29.35,88.83 29.43,88.91 v2(29.58,88.91)
  BOTTOM w0.127: v2(29.58,88.91) 29.41,88.91 29.35,88.85 29.35,87.78 U20.A55 ; C102.1 254.47,96.59 254.47,96.63 254.32,96.79 254.32,97.69 255.83,99.19 256.61,99.19 256.68,99.27 256.68,99.45 v3(256.61,99.52)
IN_D0#: length 269.8
  IN1 w0.114: v2(256.61,98.74) 256.48,98.86 256.39,98.95 256.09,98.95 255.81,99.23 255.81,101.37 255.52,101.66 255.52,104.45 254.16,105.81 239.22,105.81 238.47,106.56 232.68,106.56 231.28,105.15 229.48,105.15 229.48,105.15 228.71,105.15 228.09,105.77 222.4,105.77 222.11,105.48 222.11,105.48 221.44,104.82 218.19,104.82 217.73,105.28 214.76,105.28 213.18,103.69 213.17,103.69 213.11,103.64 212.42,103.64 211.19,103.64 211.14,103.69 211.01,103.69 210.53,104.17 209.72,104.17 208.73,105.16 207.02,105.16 206.28,105.16 205.08,103.96 198.18,103.96 197.64,103.42 194.19,103.42 193.63,102.86 191.67,102.86 189.81,101 187.29,101 184.64,98.34 184.64,97.01 181.68,94.05 173.04,94.05 172.43,94.66 166.55,94.66 166.46,94.56 165.63,94.56 165.25,94.95 165.25,95.09 164.87,95.47 164.87,96.16 162.92,98.11 136.91,98.11 136.25,97.45 132.21,97.45 131.48,98.18 130.9,98.18 123.16,98.18 122.29,97.31 120.4,97.31 120.23,97.31 120.23,97.31 117.49,97.31 117.23,97.58 97.93,97.58 97.38,98.13 97.24,98.13 96.82,98.54 96.82,98.66 88.25,98.66 88.21,98.62 85.15,98.62 84.57,98.05 78.88,98.05 78.39,98.54 78.26,98.54 78.12,98.68 71.24,98.68 69.68,97.12 63.69,97.12 62.19,95.61 62.19,95.43 61.39,94.63 59.15,94.63 58.33,93.81 55.74,93.81 55.15,93.81 55.14,93.81 54.64,93.31 54.42,93.31 53.74,93.31 51.69,91.26 51.27,90.84 48.74,90.84 47.6,89.7 47.42,89.7 47.42,89.7 46.28,89.7 46.02,89.44 46.02,87.19 45.65,86.82 45.65,85.53 45.69,85.49 45.69,83.52 45.18,83.01 45.18,81.79 43.43,80.04 35.5,80.04 33.9,81.64 33.14,81.64 31.88,82.9 31.88,84.35 30.19,86.04 30.19,86.82 29.14,87.88 29.14,88.66 v2(28.9,88.91)
  BOTTOM w0.127: v2(28.9,88.91) 29.13,88.68 29.13,87.91 29.08,87.87 29.08,87.57 29.42,87.23 U20.B55 ; C101.1 254.7,96.54 254.7,96.73 254.55,96.88 254.55,97.59 255.92,98.96 256.43,98.96 256.61,98.79 v2(256.61,98.74)
IN_D1: length 274.5
  IN1 w0.114: v2(26.79,90.44) 26.79,88.19 28.54,86.44 28.54,85.58 30.43,83.68 30.43,82.01 32.16,80.28 32.16,80.13 33.67,78.62 44.14,78.62 46.83,81.31 46.83,82.33 48.13,83.62 48.13,84.54 47.97,84.69 47.97,88.02 49.35,89.39 51.95,89.39 52.84,90.29 53.73,90.29 55.59,92.16 59.02,92.16 59.99,93.12 62.04,93.12 64.13,95.2 71.48,95.2 71.8,95.2 72.46,95.86 72.52,95.86 72.52,95.87 72.93,95.87 73.11,95.87 73.11,95.86 78.45,95.86 78.99,96.4 88.72,96.4 88.98,96.67 95.48,96.67 97.1,95.05 99.43,95.05 100.21,95.83 106.51,95.83 106.91,95.43 106.92,95.43 111.9,95.43 112.1,95.22 120.32,95.22 120.93,95.83 125.68,95.83 126.37,96.51 130.53,96.51 131.12,95.93 131.12,95.37 133.29,93.2 134.87,93.2 135.6,93.93 138.4,93.93 140.87,96.41 161.65,96.41 163.06,95 163.06,93.58 164.29,92.35 165.51,92.35 166.09,91.76 177.55,91.76 178.19,92.4 180.99,92.4 181.16,92.4 181.17,92.4 181.75,92.4 182.37,92.4 187.14,97.17 187.14,97.78 188.15,98.8 189.64,98.8 192.11,101.26 196.98,101.26 197.66,101.94 205.86,101.94 206.08,101.71 209.49,101.71 209.56,101.71 209.56,101.71 209.67,101.71 209.83,101.87 210.36,101.87 211.18,101.87 211.52,102.21 211.83,102.21 212.34,101.71 213.38,101.71 213.87,102.2 214.89,102.2 215.08,102.39 217.62,102.39 218.62,103.4 221.76,103.4 222.03,103.4 222.35,103.71 231.89,103.71 232.17,103.99 234.03,103.99 234.69,103.33 247.18,103.33 247.81,102.71 251.36,102.71 251.54,102.53 252.43,102.53 253.22,101.74 253.22,101.16 254.22,100.16 254.22,98.71 v2(255.29,97.64)
  BOTTOM w0.089: U20.C58 27.48,86.29 27.17,86.6 27.17,86.87 27.28,86.98 27.28,88.42 27.25,88.45
  BOTTOM w0.127: v2(255.29,97.64) 255.57,97.36 255.57,94.63 C143.1 ; 27.25,88.45 27.25,89.55 26.92,89.88 26.92,90.31 v2(26.79,90.44)
IN_D1#: length 274.5
  IN1 w0.114: v3(255.92,98.2) 255.82,98.1 255.14,98.1 254.44,98.8 254.44,100.25 253.43,101.25 253.43,101.83 252.52,102.75 251.63,102.75 251.45,102.93 247.9,102.93 247.27,103.55 234.78,103.55 234.12,104.21 232.08,104.21 231.8,103.93 222.26,103.93 221.94,103.61 221.85,103.61 218.53,103.61 217.53,102.61 214.99,102.61 214.8,102.42 213.78,102.42 213.29,101.92 212.43,101.92 211.92,102.43 211.61,102.43 211.61,102.43 211.43,102.43 211.09,102.08 210.82,102.08 209.74,102.08 209.58,101.93 206.17,101.93 205.95,102.15 197.57,102.15 196.89,101.48 192.02,101.48 189.55,99.01 188.24,99.01 188.24,99.02 188.2,99.02 188.2,99.01 188.06,99.01 186.92,97.87 186.92,97.26 182.28,92.62 181.67,92.62 181.08,92.62 178.1,92.62 177.46,91.98 166.18,91.98 165.6,92.56 164.38,92.56 163.28,93.67 163.28,95.09 161.74,96.63 140.78,96.63 138.31,94.15 135.51,94.15 134.78,93.41 133.38,93.41 131.34,95.46 131.34,96.02 130.62,96.73 126.28,96.73 125.59,96.04 120.84,96.04 120.23,95.44 112.19,95.44 111.99,95.64 107,95.64 106.6,96.04 100.12,96.04 99.34,95.27 97.19,95.27 95.57,96.88 88.89,96.88 88.63,96.61 78.9,96.61 78.36,96.08 73.2,96.08 73.2,96.08 73.02,96.08 72.43,96.08 72.43,96.08 72.37,96.08 71.71,95.42 64.04,95.42 61.95,93.34 59.9,93.34 58.93,92.37 55.5,92.37 53.64,90.51 52.75,90.51 51.86,89.61 49.26,89.61 47.76,88.11 47.76,84.6 47.91,84.45 47.91,83.71 46.61,82.42 46.61,81.4 44.05,78.83 33.76,78.83 32.38,80.22 32.38,80.37 30.65,82.1 30.65,83.77 28.76,85.67 28.76,86.53 27,88.28 27,90.03 27.23,90.26 27.23,90.34 27.33,90.44 v2(27.42,90.44)
  BOTTOM w0.089: 27.47,88.45 27.44,88.42 27.44,86.77 U20.B58
  BOTTOM w0.127: C142.1 254.75,93.5 255.8,94.54 255.8,98.07 v3(255.92,98.2) ; v2(27.42,90.44) 27.14,90.16 27.14,89.97 27.47,89.64 27.47,88.45
IN_D2: length 274.9
  IN1 w0.114: v2(256.96,100.13) 256.52,100.58 256.52,101.87 256.62,101.97 256.62,104.44 253.97,107.09 251.05,107.09 250.53,106.57 239.5,106.57 238.76,107.31 232.42,107.31 230.97,105.87 229.18,105.87 229,105.87 228.39,106.48 222.28,106.48 221.44,107.32 220.89,107.32 220.39,106.83 216.64,106.83 215.8,105.99 214.46,105.99 212.82,104.35 212.71,104.35 211.49,104.35 211.43,104.41 211.33,104.41 210.85,104.88 210.85,105.25 210.23,105.87 209.6,105.87 209.6,105.87 209.43,105.87 207.32,105.87 207.32,105.87 205.99,105.87 205.68,105.56 204.79,104.67 197.85,104.67 197.34,104.16 193.86,104.16 193.31,103.6 191.39,103.6 189.59,101.8 186.32,101.8 183.82,99.31 183.82,97.2 181.39,94.76 173.33,94.76 172.72,95.37 166.73,95.37 163.28,98.82 162.63,98.82 138.59,98.82 136.12,101.29 132.54,101.29 131.86,100.6 131.22,100.6 129.54,98.93 115.24,98.93 115.02,98.7 101.43,98.7 100.79,99.33 97.53,99.33 97.53,99.37 87.95,99.37 87.91,99.33 84.79,99.33 84.26,98.8 79.15,98.8 78.14,99.81 71.45,99.81 71.36,99.81 69.38,97.83 63.4,97.83 61.48,95.91 61.48,95.72 61.1,95.34 58.85,95.34 58.03,94.52 56.04,94.52 56.04,94.52 54.86,94.52 54.84,94.52 54.35,94.02 54.08,94.02 53.45,94.02 50.98,91.55 49.08,91.55 48.4,91.55 47.3,90.45 46.02,90.45 45.31,89.74 45.31,87.58 44.86,87.14 44.86,84.35 44.45,83.95 44.45,82.14 43.11,80.79 35.77,80.79 33,83.56 33,84.32 31.91,85.41 31.91,86.38 31.3,86.99 31.04,86.99 30,88.03 30,88.59 30.25,88.83 30.57,88.83 v2(30.73,88.99)
  BOTTOM w0.076: U20.C55 29.66,86.65 29.66,86.85 29.86,87.06
  BOTTOM w0.127: C141.1 256.28,93.44 256.28,94.31 256.46,94.49 256.46,97.9 257.19,98.63 257.19,99.9 v2(256.96,100.13) ; v2(30.73,88.99) 30.56,88.83 30.24,88.83 29.86,88.45 29.86,87.06
IN_D2#: length 274.8
  IN1 w0.114: v3(256.96,100.77) 256.74,100.99 256.74,101.78 256.84,101.88 256.84,104.53 254.06,107.31 250.96,107.31 250.44,106.79 239.59,106.79 238.85,107.52 232.33,107.52 230.88,106.08 229.09,106.08 228.48,106.7 228.38,106.7 222.37,106.7 221.53,107.54 221.5,107.54 220.8,107.54 220.3,107.04 216.55,107.04 215.71,106.2 214.31,106.2 212.68,104.56 211.58,104.56 211.52,104.62 211.42,104.62 211.07,104.97 211.07,105.34 210.32,106.09 210.04,106.09 209.52,106.09 209.51,106.09 207.41,106.09 207.4,106.09 205.9,106.09 205.46,105.65 204.7,104.89 197.76,104.89 197.25,104.37 193.78,104.37 193.22,103.82 191.3,103.82 189.5,102.02 186.23,102.02 183.61,99.4 183.61,97.29 181.3,94.98 173.42,94.98 172.81,95.59 166.82,95.59 163.37,99.04 162.54,99.04 162.54,99.04 138.68,99.04 136.21,101.5 136.03,101.5 136.03,101.5 132.45,101.5 131.77,100.82 131.13,100.82 129.46,99.14 115.15,99.14 114.93,98.91 101.52,98.91 100.88,99.55 97.75,99.55 97.75,99.59 87.86,99.59 87.83,99.55 84.7,99.55 84.17,99.01 79.24,99.01 78.23,100.02 71.54,100.02 71.27,100.02 69.29,98.04 63.31,98.04 61.26,96 61.26,95.81 61.01,95.55 58.76,95.55 57.94,94.73 56.13,94.73 54.75,94.73 54.28,94.26 54.23,94.26 54.21,94.24 54.17,94.24 54.17,94.24 53.36,94.24 50.89,91.77 49.17,91.77 49.17,91.77 48.31,91.77 47.21,90.67 45.93,90.67 45.09,89.83 45.09,87.67 44.65,87.23 44.65,84.44 44.24,84.04 44.24,82.23 43.02,81.01 35.86,81.01 33.22,83.65 33.22,84.41 32.12,85.5 32.12,86.47 31.39,87.2 31.13,87.2 30.22,88.12 30.22,88.5 30.34,88.62 30.46,88.62 v2(30.73,88.36)
  BOTTOM w0.076: 30.09,87.1 30.29,86.9 30.29,86.59 30.12,86.42 29.89,86.42 29.81,86.34 29.81,86.26 29.98,86.09 U20.C54
  BOTTOM w0.127: v2(30.73,88.36) 30.48,88.6 30.34,88.6 30.09,88.35 30.09,87.1 ; C140.1 256.51,93.46 256.51,94.21 256.68,94.39 256.68,97.8 257.42,98.54 257.42,100.31 v3(256.96,100.77)
INT_BT_OFF#: length 8.6
  BOTTOM w0.127: CN5.51 265.02,108.54 265.19,108.72 265.19,109.38 v1(264.3,110.27) 261.05,110.27 Q2.3 260.95,108.67 R41.2 261.08,108.54 R42.1
INT_EDP_AUXN: length 30.7
  TOP w0.127: v2(11.93,86.39) 11.96,86.39 12.29,86.73 13.15,86.73 13.44,86.44 14.13,86.44 14.59,86.9 26.54,86.9 27.58,85.86 30.68,85.86 31.01,85.53 32.61,85.53 33.95,86.87 34.21,86.87 35.33,88 35.33,88.61 35.65,88.93 35.97,88.93 36.16,88.74 v3(36.16,88.6)
  BOTTOM w0.076: v3(36.16,88.6) 36.16,88.85 36.06,88.96 35.7,88.96 35.58,88.83 35.58,88.19 35.22,87.84 35.22,87.57 35.34,87.45 35.5,87.45 35.56,87.51 U20.A45
  BOTTOM w0.127: v2(11.93,86.39) 11.85,86.47 C204.2
INT_EDP_AUXP: length 30.8
  TOP w0.127: v2(36.16,89.34) 35.99,89.16 35.56,89.16 35.1,88.71 35.1,88.09 34.11,87.1 33.86,87.1 32.51,85.76 31.11,85.76 30.78,86.09 27.68,86.09 26.64,87.13 14.5,87.13 14.04,86.67 13.53,86.67 13.24,86.96 12.07,86.96 v3(11.93,87.1)
  BOTTOM w0.076: v2(36.16,89.34) 35.93,89.11 35.64,89.11 35.43,88.89 35.43,88.26 35.07,87.9 35.07,87.51 35.28,87.3 35.49,87.3 35.56,87.23 U20.B45
  BOTTOM w0.127: C198.2 v3(11.93,87.1)
INT_EDP_HPD: length 14.1
  BOTTOM w0.127: v2(75.05,97.9) 75.05,98.44 R81.1 R82.1 73.34,98.47 73.14,98.27 R93.2 R94.1 71.76,97.91 73.12,99.27 Q11.3 73.12,101.58 73.37,101.83 Q10.3
INT_EDP_HPD_Q: length 28.2
  TOP w0.127: v2(68.57,96.65) 68.57,96.75 68.19,97.13 65.75,97.13 65.42,96.81 65.42,96.25 64.64,95.46 63.9,95.46 61.58,93.14 61.58,90.45 60.85,89.71 60.85,88.42 v3(60.6,88.17)
  BOTTOM w0.076: v3(60.6,88.17) 60.59,88.16 60.59,87.53 60.01,86.95 60.01,86.92 59.44,86.36 U20.D6
  BOTTOM w0.127: Q10.1 76.95,99.32 75.85,98.22 R85.1 75.71,97.9 75.2,97.39 74.8,97.39 74.54,97.64 R93.1 73.92,97.26 73.79,97.13 70.35,97.13 70.22,97.26 68.95,97.26 68.57,96.88 v2(68.57,96.65)
INT_EDP_TXN0: length 28.8
  TOP w0.127: v2(34.54,89.13) 34.43,89.03 34.35,89.03 33.95,89.03 33.72,88.8 33.72,88.16 32.46,86.9 28.08,86.9 27.11,87.86 13.46,87.86 12.83,88.5 12.06,88.5 v3(11.93,88.63)
  BOTTOM w0.076: v2(34.54,89.13) 34.75,88.92 34.97,88.92 35.17,88.71 35.17,88.3 34.89,88.02 34.89,87.38 35.25,87.03 35.25,86.92 35.56,86.61 U20.C45
  BOTTOM w0.127: C188.2 11.56,88.47 11.78,88.47 v3(11.93,88.63)
INT_EDP_TXN1: length 27.1
  TOP w0.127: v2(33.39,89.77) 33.17,89.55 32.79,89.55 32.33,89.08 32.33,88.11 31.85,87.64 28.48,87.64 27.52,88.6 14.06,88.6 12.92,89.74 12.16,89.74 11.93,89.97 v3(11.93,90.05)
  BOTTOM w0.127: U20.A47 34.44,87.91 34,88.35 34,89.16 v2(33.39,89.77) ; C178.2 11.85,89.9 11.93,89.97 v3(11.93,90.05)
INT_EDP_TXP0: length 28.7
  TOP w0.127: v3(34.54,88.45) 34.54,88.5 34.23,88.8 34.05,88.8 33.95,88.71 33.95,88.07 32.56,86.67 27.98,86.67 27.02,87.64 13.37,87.64 12.73,88.27 12.31,88.27 12.17,88.13 12.1,88.13 11.93,87.97 v2(11.93,87.86)
  BOTTOM w0.076: v3(34.54,88.45) 34.54,88.58 34.73,88.77 34.9,88.77 35.02,88.65 35.02,88.36 34.74,88.08 34.74,87.32 35.09,86.96 35.09,86.83 U20.B46
  BOTTOM w0.127: v2(11.93,87.86) 11.93,88.03 11.74,88.22 11.64,88.22 C190.2
INT_EDP_TXP1: length 27.1
  TOP w0.127: v2(11.93,89.34) 12.11,89.51 12.83,89.51 13.97,88.37 27.42,88.37 28.39,87.41 31.95,87.41 32.55,88.01 32.55,88.99 32.88,89.32 33.21,89.32 v3(33.39,89.13)
  BOTTOM w0.127: U20.B47 34.44,87.25 34.1,87.58 34.1,87.92 33.77,88.25 33.77,89.06 33.7,89.13 v3(33.39,89.13) ; C183.2 11.85,89.26 v2(11.93,89.34)
INT_RF_OFF#: length 16.8
  TOP w0.127: v2(263.33,103.37) v1(263.33,101.99) 263.33,99.6 263.8,99.13 264.24,99.13 264.76,98.6 264.76,96.69 265.83,95.63 CN5.20
  BOTTOM w0.127: v2(263.33,103.37) 263.12,103.57 R57.1 262.73,103.83 262.73,103.36 262.5,103.13 261.92,103.13 261.71,103.33 261.71,103.64 260.95,104.4 Q6.3
IO_THERMDA_IO: length 10.8
  BOTTOM w0.127: C114.1 92.82,95.05 92.02,94.26 U13.2 92.02,92.62 91.71,92.31 v2(89.93,92.31) 89.93,91.63 89.58,91.28 Q17.2 88.56,88.09 Q17.3
IO_THERMDC_IO: length 10.6
  BOTTOM w0.127: C114.2 93.6,95.05 92.67,94.13 U13.3 92.67,92.35 91.71,91.39 90.57,91.39 v2(90.14,90.96) 90.14,90.25 90.44,89.95 90.44,87.94 Q17.1
JTAG_TCK_PCH: length 16.6
  BOTTOM w0.127: U20.AE62 24.7,73.79 24.35,73.44 24.15,73.44 22.67,71.96 21.94,71.96 21.46,71.96 21.24,72.18 R362.2 20.96,72.18 20.64,72.5 19.85,72.5 19.82,72.46 19.45,72.09 18.18,72.09 17.62,72.65 17.13,72.65 16.65,73.13 16.55,73.13 14.62,75.06 14.62,77.1 14.87,77.34 v2(14.87,77.7) R301.1 R295.1
JTAG_TDI_PCH: length 36.8
  IN2 w0.127: v2(10.91,61.57) 11.38,62.04 11.38,62.58 13.95,65.14 13.95,72.21 14.44,72.7 15.13,72.7 15.86,73.44 16.58,73.44 16.66,73.51 17.9,73.51 18.03,73.64 19.63,73.64 19.73,73.74 20.82,73.74 v2(21.37,73.2)
  BOTTOM w0.076: 23.26,73.61 23.35,73.61 23.98,74.25 25.16,74.25 U20.AD61
  BOTTOM w0.127: v2(10.91,61.57) 10.91,60.81 9.66,59.56 8.18,59.56 v2(7.03,58.4) 6.4,58.4 4.69,60.11 3.9,60.11 R424.1 ; R343.2 20.43,74.16 21.28,73.31 21.28,73.28 v2(21.37,73.2) 21.84,72.73 22.19,72.73 23.08,73.61 23.26,73.61
JTAG_TDO_PCH: length 38.7
  IN2 w0.127: v2(11.37,61.09) 11.68,61.4 11.68,62.46 14.2,64.99 14.2,72.1 14.55,72.45 15.23,72.45 15.97,73.18 16.69,73.18 16.76,73.26 18.01,73.26 18.14,73.39 20.52,73.39 v2(20.71,73.2)
  BOTTOM w0.076: 23.33,73.39 23.36,73.39 24.06,74.08 25.16,74.08 U20.AE61
  BOTTOM w0.127: 23.33,73.39 22.42,72.47 21.73,72.47 21.45,72.75 21.11,72.75 20.71,73.15 v2(20.71,73.2) 20.19,73.72 R347.2 ; R433.1 3.08,58.44 3.56,58.92 R429.2 3.56,59.22 3.94,59.61 4.48,59.61 5.05,59.04 5.05,57.84 5.56,57.33 v2(7.82,57.33) 11.37,60.89 v2(11.37,61.09)
JTAG_TMS_PCH: length 37.1
  IN2 w0.127: v2(22.01,73.21) 21.38,73.84 21.1,73.84 20.95,74 19.63,74 19.52,73.89 17.92,73.89 17.8,73.77 16.55,73.77 16.48,73.69 15.76,73.69 15.02,72.95 14.34,72.95 13.7,72.31 13.7,65.25 10.94,62.49 10.94,62.36 v2(10.79,62.21)
  BOTTOM w0.076: 23.26,74.5 23.39,74.5 23.59,74.71 23.92,74.71 24.04,74.83 24.54,74.83 U20.AD62
  BOTTOM w0.127: 23.26,74.5 22.95,74.5 22.67,74.22 22.67,73.74 22.15,73.21 v2(22.01,73.21) 21.33,73.89 21.07,73.89 20.74,74.22 20.74,74.68 20.43,75 R329.2 ; v2(10.79,62.21) 10.32,61.74 v2(10.32,60.89) 10.32,60.57 9.6,59.86 8.08,59.86 7.8,59.58 5.72,59.58 4.01,61.3 R416.1
JTAGX_PCH: length 57.5
  IN1 w0.127: v2(4.34,58.53) 3.57,59.29 3.57,62.06 2.89,62.74 2.89,77.68 4.94,79.74 5.71,79.74 5.96,79.48 9.43,79.48 12.1,82.15 13.07,82.15 13.21,82.29 13.97,82.29 14.48,82.8 14.89,82.8 v2(14.93,82.83)
  BOTTOM w0.127: v2(14.93,82.83) 15.38,82.83 15.73,82.49 15.73,82.25 16.43,81.55 16.43,80.98 16.16,80.71 R278.1 16.78,80.17 16.98,79.96 16.98,79.41 17.19,79.2 v2(17.19,78.85) 16.76,78.42 16.04,78.42 15.84,78.21 15.84,77.95 14.88,76.99 14.88,75.16 16.65,73.39 16.75,73.39 17.16,72.98 18.86,72.98 19.18,72.66 R351.2 19.54,72.75 20.75,72.75 21,72.5 21.35,72.5 21.63,72.22 21.84,72.22 22.56,72.22 24.13,73.79 U20.AE63 ; R436.1 3.56,57.7 4.34,58.48 v2(4.34,58.53)
L_SPK+: length 50.9
  IN1 w0.635: v3(256.84,86.09) 252.97,82.22 235.05,82.22 234.38,82.89 233.02,82.89 232.01,83.9 232.01,84.57 231.46,85.12 231.46,85.46 231.07,85.86 229.69,85.86 229.15,86.39 226.38,86.39 225.84,86.94 223.8,86.94 223.33,87.41 219.73,87.41 218.69,86.37 218.41,86.37 217.23,85.18 v2(217.23,84.93)
  BOTTOM w0.203: U18.32 216.02,83.54 216.27,83.8 216.27,84.17 C213.1
  BOTTOM w0.254: CN6.36 258.25,87.58 256.84,86.16 v3(256.84,86.09)
  BOTTOM w0.508: v2(217.23,84.93) 216.85,84.55 C213.1
L_SPK-: length 51
  IN1 w0.635: v2(218.38,84.94) 218.46,84.94 218.99,85.48 219.05,85.48 219.83,86.25 219.83,86.31 220.08,86.57 221.45,86.57 222.17,85.86 223.66,85.86 223.84,86.04 225.62,86.04 226.03,85.63 228.82,85.63 230.03,84.42 230.88,84.42 231.27,84.03 231.27,83.38 232.66,82 234.02,82 234.7,81.31 235.52,81.31 235.54,81.33 253.43,81.33 v3(256.66,84.56)
  BOTTOM w0.203: U18.33 216.42,83.31 216.65,83.55 216.79,83.55 C212.1
  BOTTOM w0.254: CN6.37 258.75,87.31 257.78,86.34 257.78,85.68 v3(256.66,84.56)
  BOTTOM w0.508: C212.1 217.99,84.55 v2(218.38,84.94)
LAD0: length 309.1
  TOP w0.102: CN5.16 v1(265.47,90.83) 263.48,90.83 263.01,91.29 v2(261.99,91.29)
  IN1 w0.102: v2(261.99,91.29) 261.99,91.76 259.79,93.96 254.88,93.96 253.68,92.76 249.96,92.76 247.99,94.72 239.36,94.72 237.05,97.03 237.05,98.74 236.21,99.57 230.84,99.57 230.69,99.42 228.15,99.42 228.04,99.32 228.04,99.32 227.42,98.7 227.17,98.45 226.76,98.45 222.8,98.45 222.79,98.44 222.77,98.44 222.71,98.38 222.36,98.03 219.35,98.03 218.88,97.57 218.88,97.57 218.55,97.24 215.31,97.24 214.93,96.86 213.35,96.86 212.49,95.99 210.48,95.99 v2(209.54,95.05)
  IN2 w0.102: v2(73.91,41.76) 74.11,41.56 76.09,41.56 79.44,44.91 79.44,48.25 80.05,48.86 80.05,58.7 80.75,59.4 80.75,70.55 87.98,77.78 93.59,77.78 94.35,78.54 96.21,78.54 96.89,79.23 ; 96.89,79.23 99.13,76.99 152.83,76.99 155.65,74.17 184.36,74.17 190.87,80.69 190.87,81.52 192.02,82.66 192.02,83.96 192.87,84.82 194.08,84.82 194.1,84.83 194.27,85.01 198.4,85.01 199.69,86.29 202.34,86.29 204.44,88.39 204.44,89.03 205.86,90.45 207.4,90.45 208.17,91.22 214.52,91.22 214.76,91.46 216.89,91.46 218.33,92.9 218.33,93.91 217.9,94.34 211.93,94.34 210.89,95.38 209.87,95.38 v2(209.54,95.05) ; 96.89,79.23 v2(96.89,79.2)
  BOTTOM w0.076: U20.AU14 55.34,66.68 55.34,66.28 55.24,66.18 55.24,64.93 55.1,64.79 55.1,64.44
  BOTTOM w0.102: 55.1,64.44 52.95,62.29 52.95,61.96 52.24,61.24 52.24,55.88 66.73,41.38 73.53,41.38 v2(73.91,41.76) ; U7.10 204.42,95.76 204.79,95.38 206.09,95.38 207.1,94.37 208.86,94.37 v2(209.54,95.05) ; R284.2 v2(96.89,79.2)
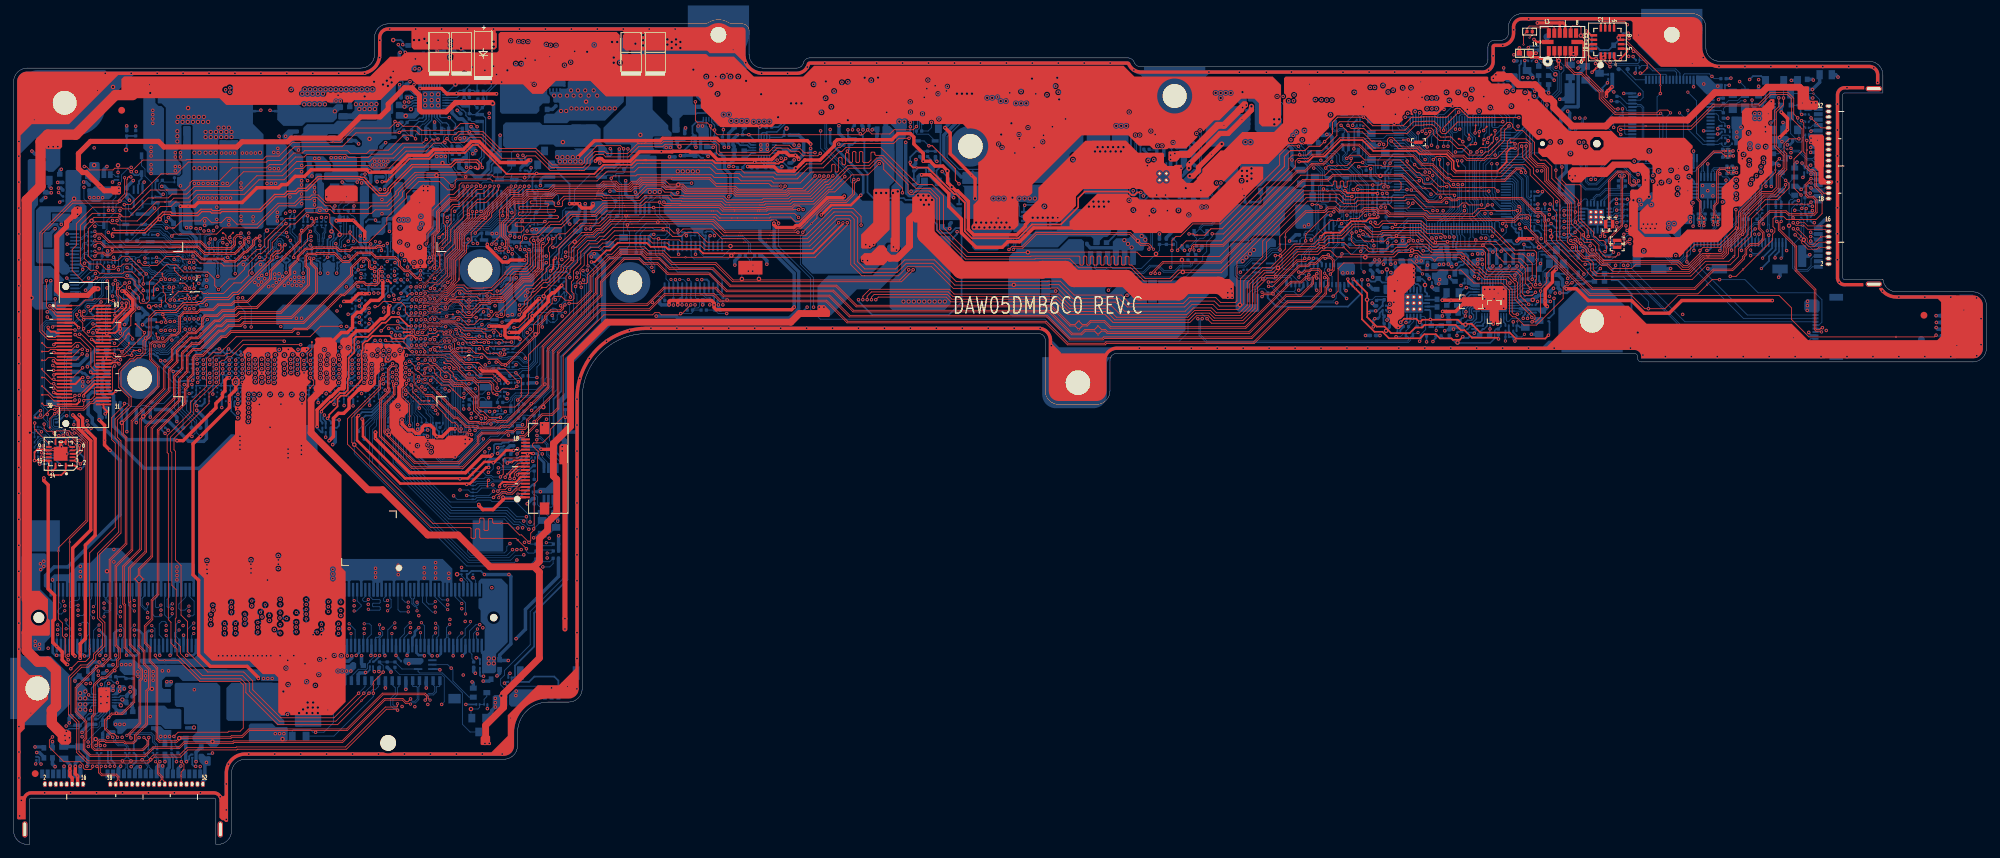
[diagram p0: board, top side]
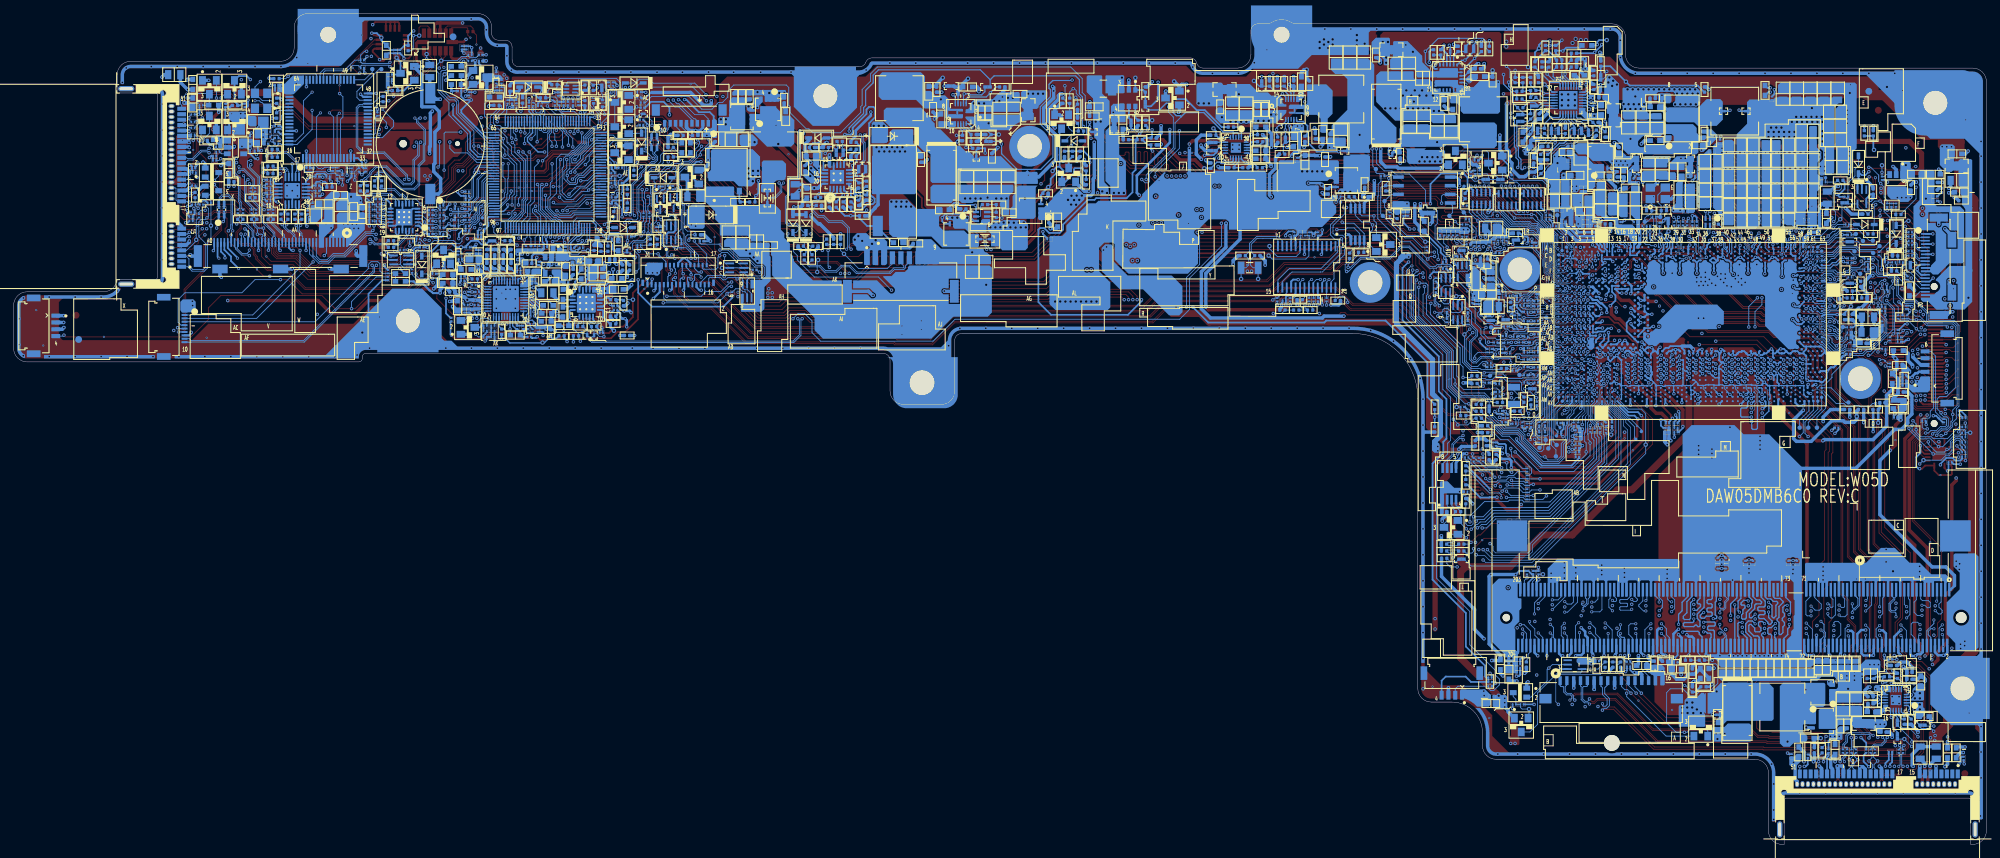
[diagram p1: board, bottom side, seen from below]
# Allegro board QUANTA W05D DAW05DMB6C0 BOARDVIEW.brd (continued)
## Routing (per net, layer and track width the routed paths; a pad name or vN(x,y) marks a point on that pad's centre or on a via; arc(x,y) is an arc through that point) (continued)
LAD0_T: length 2.9
  BOTTOM w0.127: R284.1 96.89,80.23 U15.26 96.89,82.59 96.53,82.95 v3(96.53,82.96)
LAD1: length 302.8
  TOP w0.102: CN5.14 266.32,90.03 266.01,90.33 263.47,90.33 262.94,90.86 v1(262.7,90.86) 261.76,90.86 v2(261.33,91.29)
  IN1 w0.102: v2(261.33,91.29) 261.33,91.91 259.64,93.6 255.03,93.6 253.83,92.4 249.81,92.4 248.81,93.4 238.82,93.4 238.02,94.21 238.02,95 234,99.01 233.79,99.22 230.99,99.22 230.83,99.07 228.29,99.07 228.19,98.96 227.32,98.09 226.91,98.09 222.95,98.09 222.93,98.08 222.92,98.08 222.86,98.02 222.77,97.93 222.77,97.93 222.51,97.67 222.4,97.67 219.5,97.67 219.03,97.21 219.03,97.21 218.7,96.88 215.46,96.88 214.95,96.37 213.38,96.37 211.88,94.87 211.04,94.87 v2(210.43,94.26)
  IN2 w0.102: v2(73.27,43.29) 74.62,41.94 75.97,41.94 77.59,43.56 77.59,44.56 79.04,46.01 79.04,48.42 79.65,49.03 79.65,58.8 80.4,59.55 80.4,70.83 87.7,78.14 93.44,78.14 94.97,79.66 98.37,79.66 v2(98.8,79.23) 100.68,77.35 152.98,77.35 155.8,74.53 184.21,74.53 190.52,80.84 190.52,81.66 190.77,81.92 190.77,84 191,84.23 191.49,84.23 191.78,84.23 192.72,85.17 193.94,85.17 193.95,85.19 194.13,85.36 198.26,85.36 199.54,86.64 202.19,86.64 203.5,87.95 203.5,88.8 205.5,90.81 207.26,90.81 208.02,91.57 214.37,91.57 214.61,91.81 216.74,91.81 217.4,92.47 217.4,92.83 217.15,93.08 217.06,93.17 214.57,93.17 213.96,92.56 212.13,92.56 v2(210.43,94.26)
  BOTTOM w0.076: 55.72,64.38 55.72,64.55 55.98,64.81 55.98,65.44 U20.AW12
  BOTTOM w0.102: U7.8 204.52,94.96 204.59,95.03 205.76,95.03 206.75,94.04 210.2,94.04 v2(210.43,94.26) ; v2(73.27,43.29) 72.43,42.45 67.18,42.45 66.67,42.96 66.67,43.97 54.02,56.62 54.02,62.51 55.72,64.22 55.72,64.38 ; R283.2 v2(98.8,79.23)
LAD1_T: length 3.5
  BOTTOM w0.127: R283.1 98.8,80.75 98.84,80.79 U15.23 98.84,82.49 98.37,82.96 v3(97.81,82.96)
LAD2: length 287.3
  TOP w0.102: v2(261.99,90.4) 263.39,89.01 263.39,88.5 263.77,88.12 264.28,88.12 265.39,89.23 v1(265.47,89.23) CN5.12
  IN1 w0.102: v2(209.06,93.07) 209.06,93.32 209.57,93.83 211.4,93.83 213.58,96.02 215.1,96.02 215.61,96.53 218.84,96.53 219.17,96.86 219.18,96.86 219.64,97.32 222.25,97.32 222.25,97.32 222.66,97.32 223.07,97.73 223.08,97.73 223.09,97.74 227.05,97.74 227.47,97.74 228.08,98.35 228.08,98.36 228.34,98.61 228.34,98.61 228.44,98.71 230.98,98.71 231.13,98.86 233.65,98.86 237.66,94.85 237.66,94.06 238.68,93.05 246.37,93.05 247.37,92.05 253.98,92.05 255.18,93.25 259.49,93.25 260.85,91.89 260.85,91.16 261.17,90.85 261.55,90.85 v2(261.99,90.4)
  IN2 w0.102: v2(209.06,93.07) 208.55,92.56 207.99,92.56 206.95,91.52 205.2,91.52 203.07,89.39 202.66,89.39 202.05,88.78 201.5,88.78 201.1,88.37 199.37,88.37 198.67,87.67 197.58,87.67 196.91,87 192.85,87 191.74,85.88 191.74,85.52 191.29,85.07 190.19,85.07 189.43,84.3 189.43,80.95 183.72,75.24 156.09,75.24 153.25,78.08 103.37,78.08 v2(102.23,79.23) 101.06,80.39 94.58,80.39 93.04,78.85 87.32,78.85 78.87,70.4 78.87,63.48 79.43,62.92 79.43,61.38 78.75,60.69 78.69,60.64 78.69,49.08 78.02,48.41 78.02,46 75.94,43.92 74.29,43.92 73.91,43.54 v2(73.91,43.29)
  BOTTOM w0.102: U20.AY12 55.64,65.04 55.64,64.75 55.49,64.6 55.49,64.29 53.66,62.46 53.66,55.46 67.03,42.09 72.71,42.09 v2(73.91,43.29) ; v2(209.06,93.07) 208.4,93.73 206.54,93.73 205.61,94.67 204.59,94.67 204.47,94.56 U7.7 ; R281.2 v2(102.23,79.23)
LAD2_T: length 3.9
  BOTTOM w0.127: v3(100.37,82.96) 100.79,82.54 U15.20 100.79,80.89 100.96,80.73 101.19,80.73 101.68,80.23 R281.1
LAD3: length 286.5
  TOP w0.102: CN5.10 265.09,88.43 264.43,87.76 263.62,87.76 263.01,88.38 263.01,88.75 v1(262.48,89.29) v2(261.36,90.4)
  IN1 w0.102: v2(261.36,90.4) 261.11,90.4 260.49,91.02 260.49,91.75 259.35,92.89 255.32,92.89 254.12,91.69 247.22,91.69 246.22,92.69 237.74,92.69 236.36,94.06 236.36,95.07 232.93,98.51 231.34,98.51 229.76,96.93 228.36,96.93 227.91,97.38 227.2,97.38 223.24,97.38 223.23,97.37 223.21,97.37 222.81,96.96 222.01,96.96 219.96,96.96 219.96,96.96 219.79,96.96 219.33,96.5 219.32,96.5 218.33,95.51 213.58,95.51 211.55,93.48 209.72,93.48 209.49,93.25 209.49,92.77 209.36,92.64 208.86,92.64 v2(208.42,93.07)
  IN2 w0.102: v2(208.42,93.07) 207.99,93.07 206.8,91.88 205.05,91.88 202.91,89.74 202.4,89.74 201.82,89.16 201.38,89.16 200.95,88.73 199.2,88.73 198.5,88.03 197.43,88.03 196.79,87.38 192.73,87.38 191.38,86.03 191.38,85.83 190.97,85.43 189.2,85.43 188.16,84.38 188.16,80.42 183.33,75.6 156.24,75.6 153.4,78.44 104.94,78.44 v2(104.16,79.23) 104.16,79.36 102.76,80.75 94.44,80.75 92.89,79.2 87.18,79.2 78.52,70.54 78.52,63.33 79.08,62.78 79.08,61.52 78.6,61.05 78.6,61.05 78.34,60.79 78.34,49.23 77.54,48.43 77.54,46.02 76.33,44.81 73.53,44.81 v2(72.89,44.18)
  BOTTOM w0.076: U20.AW11 56.15,65.44 56.15,64.7 56.03,64.58
  BOTTOM w0.102: R280.2 104.13,79.25 v2(104.16,79.23) ; 56.03,64.58 55.93,64.48 55.93,64.05 54.42,62.54 54.42,56.72 63.37,47.78 63.37,47.77 67.02,44.12 67.02,43.1 67.32,42.8 72.08,42.8 72.43,43.16 72.43,43.72 v2(72.89,44.18) ; v2(208.42,93.07) 208.12,93.38 205.07,93.38 204.69,93.76 U7.5
LAD3_T: length 3.3
  BOTTOM w0.127: U15.17 102.74,80.99 102.98,80.75 103.62,80.75 R280.1 104.5,80.23 v2(104.78,79.95)
LAN_DISABLE#: length 16.1
  TOP w0.127: v2(69.31,62.59) 69.31,62.69 68.9,63.1 68.6,63.1 67.81,63.89 67.81,65.69 65.98,67.52 64.68,67.52 63.97,68.23 63.24,68.23 62.67,68.8 62.67,69.51 61.82,70.36 61.18,70.36 60.95,70.59 v1(60.16,70.59) v2(59.5,70.59)
  BOTTOM w0.127: v2(59.5,70.59) 59.38,70.59 U20.AM7 ; v2(69.31,62.59) 69.09,62.38 R405.1
LFRAME#: length 291.9
  TOP w0.102: CN5.8 v1(265.17,87.63) 265.04,87.63 264.82,87.41 263.48,87.41 262.58,88.3 262.58,88.55 v2(261.61,89.51)
  IN1 w0.102: v2(261.61,89.51) 261.49,89.51 260.14,90.87 260.14,91.6 259.2,92.54 255.64,92.54 253.46,90.35 246.09,90.35 244.11,92.33 237.53,92.33 236.01,93.86 236.01,94.93 232.78,98.15 231.48,98.15 229.91,96.58 228.22,96.58 228.01,96.78 227.77,97.03 227.35,97.03 223.39,97.03 223.37,97.01 223.36,97.01 222.95,96.61 221.87,96.61 219.96,96.61 219.89,96.54 219.88,96.55 218.48,95.15 218.48,95.15 213.73,95.15 211.62,93.05 v2(209.92,93.05)
  IN2 w0.102: v2(74.92,42.52) 76.05,42.52 77.23,43.71 77.23,44.71 78.38,45.86 78.38,48.26 79.27,49.15 79.27,58.95 80.04,59.72 80.04,71.06 87.47,78.49 93.21,78.49 94.76,80.04 99.26,80.04 v2(100.07,79.23) 101.57,77.73 153.1,77.73 155.95,74.88 183.86,74.88 189.78,80.8 189.78,84.16 190.21,84.59 191.64,84.59 192.58,85.53 193.79,85.53 193.98,85.72 198.11,85.72 199.39,87 202.04,87 202.51,87.46 202.51,88.7 202.84,89.03 203.22,89.03 205.35,91.17 207.1,91.17 208.15,92.21 209.08,92.21 v2(209.92,93.05)
  BOTTOM w0.076: U20.AV12 55.65,66.23 55.4,65.98 55.4,64.86 55.28,64.73 55.28,64.34
  BOTTOM w0.102: R282.2 99.67,79.75 100.07,79.35 v2(100.07,79.23) ; v2(209.92,93.05) 209.8,93.05 209.39,92.64 208.22,92.64 207.84,93.02 204.79,93.02 204.46,93.36 U7.4 ; v2(74.92,42.52) 74.8,42.4 73.65,42.4 72.99,41.74 66.88,41.74 52.7,55.92 52.7,60.86 53.31,61.47 53.31,62.37 55.28,64.34
LFRAME#_T: length 3
  BOTTOM w0.127: R282.1 99.43,80.75 99.49,80.81 U15.22 99.49,82.66 99.19,82.96 v3(99.08,82.96)
LID_EC#: length 222.6
  TOP w0.127: v2(205.55,88.65) 205.06,89.13 201.87,89.13 201.31,88.58 v1(200.75,88.58) 198.37,88.58 v2(197.55,89.39)
  IN2 w0.127: v2(197.55,89.39) 196.44,88.27 194.77,88.27 192.38,88.27 191.64,87.53 191.22,87.53 191.22,87.53 189.02,87.53 187.23,85.74 187.23,81.04 182.68,76.5 156.58,76.5 153.62,79.46 138.42,79.46 137.66,80.21 130.06,80.21 129.3,79.46 121.23,79.46 120.49,80.19 112.8,80.19 112.35,79.74 105.66,79.74 103.24,82.15 95.29,82.15 92.58,84.87 92.12,84.87 91.6,85.39 89.39,85.39 87.53,83.53 87.53,81.68 77.36,71.51 77.36,62.52 76.04,61.2 76.04,58.3 77.21,57.13 77.21,53.19 76.65,52.63 76.65,50.24 75.73,49.32 74.57,49.32 70.6,45.36 70.6,39.25 69.77,38.42 69.77,35.78 71.74,33.81 71.74,32.79 67.77,28.82 54.18,28.82 v2(53.1,27.74)
  BOTTOM w0.127: CN13.14 49.6,24.7 50.61,25.71 51.82,25.71 51.95,25.84 51.95,26.47 C311.1 52.3,26.94 v2(53.1,27.74) ; R226.2 206.1,88.1 v2(205.55,88.65) 205.5,88.7 U7.127
LINEOUT_L: length 5.5
  BOTTOM w0.127: R279.2 201.61,80.43 199.95,80.43 199.51,79.99 v4(198.75,79.99)
  BOTTOM w0.254: R279.2 202.34,80.27 202.84,80.27 203.12,79.98 U19.14
LINEOUT_L_C: length 11.2
  IN1 w0.381: v2(195.67,81.31) 196.33,81.31 199.31,78.34 v2(200.02,78.34)
  BOTTOM w0.254: v2(200.02,78.34) 200.21,78.34 200.97,79.1 R292.1 201.05,79.63 201.28,79.86 R279.1 200.26,79.99 C246.2
  BOTTOM w0.305: CN8.3 195.42,81.57 v2(195.67,81.31)
  BOTTOM w0.381: v2(199.03,78.08) 199.03,78.16 199.2,78.34 v2(200.02,78.34)
LINEOUT_R: length 4.2
  BOTTOM w0.254: U19.11 203.21,78.48 203.14,78.42 203.14,77.45 202.13,76.43 R316.2
  BOTTOM w0.381: R316.2 202.06,75.94 v4(201.54,75.43)
LINEOUT_R_C: length 13.3
  IN1 w0.381: v2(199.89,77.2) 198.72,77.2 v2(195.75,80.17)
  BOTTOM w0.254: R316.1 201.16,76.55 201.16,77.33 201.28,77.45 C257.2 201.05,77.81 R296.1 200.6,78.02 200.6,77.48 200.45,77.32
  BOTTOM w0.305: CN8.4 194.82,81.1 v2(195.75,80.17)
  BOTTOM w0.381: 200.45,77.32 200.32,77.2 v2(199.89,77.2) 199.66,76.97 v2(199.66,76)
LPCPD#_TPM: length 4.6
  BOTTOM w0.127: U15.28 95.59,81.04 95.63,81 R286.2 95.62,79.86 94.99,80.5 94.35,80.5 93.79,79.94 v2(93.79,79.61)
M_B_A0: length 42.7
  IN1 w0.076: v2(38.27,68.52) 38.27,68.49 37.84,68.06 37.84,67.45 38.09,67.2 38.09,60.94
  IN1 w0.203: v3(36.95,35.18) 36.95,35.97 36.56,36.36 36.56,38.2 36.26,38.5 36.26,48.72 39.84,52.3 39.84,55.88 39.49,56.24 39.49,58.53 38.6,59.42 38.6,60.43 38.09,60.94
  BOTTOM w0.191: U20.AP40 38.5,68.66 38.41,68.66 v2(38.27,68.52) ; v3(36.95,35.18) JDIM1.98
M_B_A1: length 41.7
  IN1 w0.076: 38.6,61.02 38.29,61.32 38.29,67.53 38.24,67.58 v2(38.24,67.83)
  IN1 w0.203: 38.6,61.02 38.98,60.64 38.98,59.52 39.82,58.68 39.82,56.56 40.3,56.07 40.3,52.11 36.72,48.53 36.72,38.69 37.08,38.33 37.08,36.56 37.56,36.07 v3(37.56,33.61)
  BOTTOM w0.191: v3(37.56,33.61) 37.56,35.28 36.65,36.19 JDIM1.97 ; U20.AR40 38.54,68.05 38.46,68.05 v2(38.24,67.83)
M_B_A2: length 46.3
  IN1 w0.076: v2(37.4,68.57) 36.92,68.08 36.92,61.82 37.05,61.69 37.05,60.53 37.91,59.67
  IN1 w0.203: 37.91,59.67 37.91,58.58 38.83,57.66 38.83,55.63 38.93,55.53 38.93,52.68 35.34,49.1 35.34,38.12 35.59,37.88 35.59,33.34 35.72,33.22 35.97,33.22 36.28,32.91 36.86,32.91 37.2,32.57 37.2,32.41 36.83,32.04 36.41,32.04 v3(35.86,32.6)
  BOTTOM w0.191: v3(35.86,32.6) 36.34,32.6 36.49,32.45 36.49,30.59 36.35,30.45 JDIM1.96 ; v2(37.4,68.57) 37.68,68.85 U20.AP42
M_B_A3: length 43.4
  IN1 w0.076: 37.58,60.56 37.25,60.89 37.25,61.8 37.09,61.96 37.09,65.27 37.27,65.45 37.27,66.23 37.09,66.4 37.09,67.82 37.23,67.96 v2(37.43,67.96)
  IN1 w0.203: v3(36.26,34.1) 36.51,34.1 36.8,33.81 36.97,33.81 37.1,33.94 37.1,34.47 36.95,34.63 36.2,34.63 36.05,34.78 36.05,35.18 36.2,35.34 36.33,35.34 36.48,35.49 36.48,35.79 36.33,35.95 36.2,35.95 36.05,36.1 36.05,38.07 35.8,38.31 35.8,48.91 39.39,52.49 39.39,55.69 39.16,55.92 39.16,58.1 38.22,59.03 38.22,59.92 37.58,60.56
  BOTTOM w0.191: U20.AR42 37.73,68.2 37.58,68.05 37.52,68.05 v2(37.43,67.96) ; JDIM1.95 36.05,36.13 36.47,35.72 36.47,34.31 v3(36.26,34.1)
M_B_A4: length 49.7
  IN1 w0.076: v2(35.5,67.93) 35.54,67.93 36.49,66.99 36.49,61.65 36.69,61.45 36.69,60.23 37.3,59.62 37.3,59.39
  IN1 w0.203: v3(35.86,31.18) 36.23,31.55 36.44,31.55 36.85,31.15 37.05,31.15 37.23,31.32 37.23,31.79 37.4,31.96 37.57,31.96 37.81,31.71 37.81,30.82 37.69,30.69 35.63,30.69 35.35,30.97 35.35,32.8 35.12,33.03 35.12,34.19 34.46,34.85 34.46,36.45 33.9,37.01 33.9,43.54 34.41,44.05 34.41,49.45 38.02,53.06 38.02,57.08 37.3,57.79 37.3,59.39
  BOTTOM w0.191: JDIM1.92 35.15,30.32 35.86,31.02 v3(35.86,31.18) ; U20.AR45 35.68,67.93 v2(35.5,67.93)
M_B_A5: length 48.9
  IN1 w0.076: v2(36.45,68.57) 36.37,68.57 35.98,68.18 35.98,67.75 36.67,67.06 36.67,61.76 36.87,61.56 36.87,60.33 37.61,59.59
  IN1 w0.203: v3(34.97,35.74) 35.12,35.89 35.12,36.78 34.97,36.94 34.64,36.94 34.36,37.22 34.36,37.39 34.51,37.55 34.69,37.55 34.84,37.7 34.84,38 34.69,38.16 34.51,38.16 34.36,38.31 34.36,38.61 34.51,38.77 34.71,38.77 34.87,38.92 34.87,39.22 34.71,39.38 34.51,39.38 34.36,39.53 34.36,42.12 34.51,42.27 34.73,42.27 34.89,42.42 34.89,42.73 34.73,42.88 34.51,42.88 34.36,43.03 34.36,43.34 34.51,43.49 34.73,43.49 34.89,43.64 34.89,49.29 38.47,52.87 38.47,57.26 37.61,58.12 37.61,59.59
  BOTTOM w0.191: v3(34.97,35.74) 35.07,35.84 35.64,35.84 36.02,35.46 36.02,35.24 35.92,35.13 35.58,35.13 35.45,35.01 35.45,34.74 35.77,34.42 35.77,33.88 35.95,33.7 35.95,33.21 35.83,33.08 35.45,33.08 35.25,33.28 35.25,34.04 34.49,34.8 34.49,35.39 34.36,35.51 34.36,35.84 34.85,36.34 JDIM1.91 ; U20.AP45 35.94,68.69 36.06,68.57 v2(36.45,68.57)
M_B_A6: length 54.3
  IN1 w0.076: 37,59.57 36.19,60.38 36.19,60.55 36.19,60.56 36.19,63.7 35.29,64.6 v2(35.29,65.41)
  IN1 w0.203: 37,59.57 37,57.54 37.56,56.98 37.56,53.25 33.95,49.64 33.95,44.25 33.44,43.74 33.44,36.81 34,36.25 34,34.62 34.66,33.97 34.66,32.77 34.89,32.54 34.89,30.71 35.37,30.23 38.14,30.23 38.3,30.08 38.3,29.77 38.14,29.62 35.22,29.62 34.31,30.54 34.31,32.29 34.21,32.39 v3(33.95,32.39)
  BOTTOM w0.191: v2(35.29,65.41) 35.1,65.6 35.06,65.6 U20.AW46 ; JDIM1.90 34.55,30.37 35.35,31.17 35.35,32.39 34.94,32.8 34.36,32.8 v3(33.95,32.39)
M_B_A7: length 53.5
  IN1 w0.076: v2(34.5,62.76) 35.33,61.93 35.33,60.11 36,59.44 36,59.35 36.03,59.31
  IN1 w0.203: v3(32.58,32.43) 32.44,32.43 32.07,32.06 32.07,31.12 31.77,30.82 31.59,30.82 31.46,30.94 31.46,32.26 32.12,32.92 32.43,32.92 32.63,33.13 32.63,35.64 32.07,36.2 32.07,41.38 31.92,41.53 31.64,41.53 31.49,41.69 31.49,41.99 31.64,42.14 31.92,42.14 32.07,42.3 32.07,42.6 31.92,42.75 31.31,42.75 30.93,43.13 30.93,48.56 31.23,48.86 31.6,48.86 31.76,49.02 31.76,49.39 36.19,53.82 36.19,56.06 36.03,56.22 36.03,59.31
  BOTTOM w0.191: v3(32.58,32.43) 32.87,32.72 33.32,32.72 33.47,32.57 33.47,32.14 33.11,31.78 33.11,31.4 33.29,31.22 33.9,31.22 34.03,31.35 34.03,31.78 34.55,32.3 34.74,32.3 34.89,32.15 34.89,31.35 34.16,30.61 33.57,30.61 33.35,30.39 JDIM1.86 ; U20.AY46 35.07,64.93 35.07,64.27 35.25,64.09 35.93,64.09 36.09,63.94 36.09,62.91 35.93,62.76 v2(34.5,62.76)
M_B_A8: length 51.6
  IN1 w0.076: v2(34.51,64.78) 35.02,64.28 35.02,63.79 35.88,62.93 35.88,60.33 36.7,59.52
  IN1 w0.203: 36.7,59.52 36.7,57.08 37.1,56.67 37.1,53.44 33.49,49.83 33.49,49.31 33.34,49.15 32.83,49.15 32.68,49 32.68,48.7 32.83,48.54 33.27,48.54 33.42,48.39 33.42,48.09 33.27,47.94 32.02,47.94 31.84,47.76 31.84,47.5 32.02,47.33 33.27,47.33 33.42,47.17 33.42,46.87 33.27,46.72 32.02,46.72 31.84,46.54 31.84,46.28 32.02,46.11 33.34,46.11 33.49,45.95 33.49,45.67 33.32,45.5 32.02,45.5 31.84,45.32 31.84,45.07 32.02,44.89 33.32,44.89 33.49,44.71 33.49,44.46 32.99,43.95 32.99,36.61 33.55,36.05 33.55,34.02 33.75,33.81 v3(33.95,33.81)
  BOTTOM w0.191: v3(33.95,33.81) 33.95,33.79 34.46,33.28 34.69,33.28 34.8,33.39 34.8,33.86 34.03,34.63 34.03,35.12 33.82,35.32 33.14,35.32 33.01,35.45 33.01,35.62 33.29,35.9 33.77,35.9 34.25,36.38 JDIM1.89 ; v2(34.51,64.78) 34.33,64.96 34.21,64.96 U20.AY47
M_B_A9: length 54.1
  IN1 w0.076: v2(34.52,66.08) 34.04,65.6 34.04,61.79 34.92,60.91 34.92,59.84 35.36,59.4 35.36,59.17
  IN1 w0.203: 35.36,59.17 35.36,54.29 30.01,48.94 30.01,42.73 30.29,42.45 30.29,38.61 30.7,38.21 31.06,38.21 31.16,38.11 31.16,35.44 31.49,35.11 31.49,34.88 31.36,34.75 30.93,34.75 30.8,34.62 30.8,34.3 30.96,34.14 31.34,34.14 31.46,34.02 31.46,33.79 31.21,33.53 30.5,33.53 30.37,33.41 30.37,33.03 30.47,32.92 31.47,32.92 32.17,33.62 32.17,33.93 v3(31.98,34.12)
  BOTTOM w0.191: JDIM1.85 33.05,36.28 32.48,35.71 32.48,35.03 32.63,34.88 33.42,34.88 33.57,34.73 33.57,34.46 33.42,34.31 32.66,34.31 32.5,34.16 32.5,33.89 32.66,33.74 33.32,33.74 33.47,33.58 33.47,33.32 33.32,33.17 32.64,33.17 32.1,32.62 32.1,32.49 31.93,32.32 31.72,32.32 31.46,32.58 31.46,32.79 31.98,33.31 v3(31.98,34.12) ; U20.AU46 34.62,67.04 34.52,66.93 v2(34.52,66.08)
M_B_A10: length 57
  IN1 w0.076: 41.01,62.36 41.01,62.51 40.26,63.27 40.26,67.45 40.17,67.54 40.17,70.72 v2(40.67,71.22)
  IN1 w0.203: v3(40.1,33.15) 40.3,32.96 40.3,32.23 40.48,32.04 40.48,31.83 40.3,31.65 40.3,31.43 40.45,31.28 40.89,31.28 41.04,31.13 41.04,30.82 40.89,30.67 39.96,30.67 39.81,30.82 39.81,32.53 39.59,32.75 39.59,33.48 40.65,34.54 40.65,36.46 39.46,37.65 39.46,39.67 39.36,39.77 39.36,42.44 39.51,42.59 39.87,42.59 40.02,42.74 40.02,43.05 39.87,43.2 39.26,43.2 39.1,43.35 39.1,43.66 39.26,43.81 40.26,43.81 40.53,44.08 40.53,45.53 40.33,45.73 40.33,45.95 40.53,46.15 40.53,47.42 40.32,47.63 40.12,47.63 39.88,47.88 39.88,48.19 40.13,48.44 40.33,48.44 40.53,48.65 40.53,48.8 42.74,51.01 42.74,58.74 41.01,60.47 41.01,62.36
  BOTTOM w0.191: JDIM1.107 39.65,35.74 39.82,35.57 39.82,33.71 39.6,33.49 39.6,33.27 39.72,33.15 v3(40.1,33.15) ; v2(40.67,71.22) 41.01,71.22 U20.AK36
M_B_A11: length 53.7
  IN1 w0.076: v2(34.52,63.43) 35.6,62.34 35.6,60.18 36.36,59.42
  IN1 w0.203: 36.36,59.42 36.36,56.84 36.64,56.56 36.64,53.63 32.22,49.21 32.22,48.57 32.05,48.39 31.54,48.39 31.39,48.24 31.39,44.58 31.54,44.43 32.38,44.43 32.53,44.28 32.53,43.97 32.38,43.82 31.54,43.82 31.39,43.67 31.39,43.36 31.54,43.21 32.38,43.21 32.53,43.06 32.53,36.4 33.09,35.84 33.09,33.81 33.42,33.48 33.42,33.23 33.06,32.87 33.06,32.67 33.42,32.31 33.42,32.11 33.09,31.78 33.09,31.55 33.22,31.43 33.7,31.43 33.85,31.27 33.85,30.97 33.7,30.82 33.09,30.82 32.91,30.64 32.91,30.36 33.06,30.21 33.98,30.21 34.16,30.03 34.16,29.77 34.01,29.62 31.54,29.62 31.41,29.75 31.41,30.1 31.54,30.23 32.2,30.23 32.4,30.43 32.4,30.79 32.58,30.97 v3(32.58,31.01)
  BOTTOM w0.076: U20.AV47 33.8,66.09 33.8,64.9 34.09,64.61 34.09,63.86 v2(34.52,63.43)
  BOTTOM w0.191: JDIM1.84 32.75,30.42 33.01,30.68 33.01,30.85 32.86,31.01 v3(32.58,31.01)
M_B_A12: length 49.7
  IN1 w0.076: v2(34.46,62.11) 35.09,61.48 35.09,60.02 35.69,59.42 35.69,59.15
  IN1 w0.203: 35.69,59.15 35.69,53.97 30.47,48.75 30.47,42.93 31.03,42.37 31.03,41.99 30.75,41.71 30.75,41.25 30.9,41.1 31.46,41.1 31.62,40.95 31.62,40.65 31.46,40.49 30.9,40.49 30.75,40.34 30.75,40.04 30.9,39.88 31.46,39.88 31.62,39.73 31.62,39.43 31.46,39.27 30.9,39.27 30.75,39.12 30.75,38.82 30.9,38.66 31.44,38.66 31.62,38.49 31.62,35.71 31.77,35.56 v3(31.98,35.56)
  BOTTOM w0.076: 33.62,64.29 33.63,64.3 33.63,66.42 34.04,66.83 U20.AU47
  BOTTOM w0.191: v2(34.46,62.11) 34.46,61.09 34.31,60.94 33.77,60.94 33.62,61.09 33.62,64.29 ; v3(31.98,35.56) 31.49,35.07 31.49,33.46 31.31,33.28 31.17,33.28 30.9,33.55 30.9,35.11 30.65,35.36 30.65,35.54 30.79,35.68 31.3,35.68 31.67,36.05 32.17,36.05 32.45,36.32 JDIM1.83
M_B_A13: length 58
  IN1 w0.076: v2(42.62,71.06) 42.09,70.53 42.09,67.64 41.64,67.19 41.64,63.23 42.31,62.56 42.31,62.46
  IN1 w0.203: v3(42.97,35.95) 42.63,35.95 42.48,36.1 42.48,37.29 42.26,37.51 42.26,37.84 42.48,38.06 42.48,41.53 42.63,41.68 43.01,41.68 43.43,42.1 43.43,43.01 43.59,43.16 44.42,43.16 44.57,43.31 44.57,43.62 44.42,43.77 43.59,43.77 43.43,43.92 43.43,44.23 43.59,44.38 44.42,44.38 44.57,44.53 44.57,44.84 44.42,44.99 43.59,44.99 43.43,45.14 43.43,45.45 43.59,45.6 44.42,45.6 44.57,45.75 44.57,46.06 44.42,46.21 43.59,46.21 43.43,46.36 43.43,46.67 43.59,46.82 44.42,46.82 44.57,46.97 44.57,47.27 44.42,47.43 43.59,47.43 43.43,47.58 43.43,47.88 43.59,48.04 44.42,48.04 44.57,48.19 44.57,48.49 44.42,48.65 43.59,48.65 43.43,48.8 43.43,49.1 43.59,49.26 44.42,49.26 44.57,49.41 44.57,58.64 42.31,60.9 42.31,62.46
  BOTTOM w0.191: JDIM1.119 43.25,36.38 43.98,35.64 43.98,34.02 44.51,33.5 44.51,33.19 44.34,33.03 43.6,33.03 43.45,33.18 43.45,35.47 v3(42.97,35.95) ; v2(42.62,71.06) 43.01,71.45 U20.AK33
M_B_A14: length 54.3
  IN1 w0.076: 34.82,59.39 34.76,59.45 34.76,60.84 33.86,61.73 33.86,65.98 35.09,67.2 35.09,68.15 v2(35.47,68.54)
  IN1 w0.203: v3(30.98,32.43) 30.62,32.43 30.5,32.3 30.5,30.28 30.37,30.16 30.07,30.16 29.56,30.66 28.97,30.66 28.59,30.28 28.31,30.28 27.98,30.61 27.98,31.02 28.24,31.27 29.74,31.27 29.91,31.45 29.91,33.61 30.35,34.04 30.35,35.11 30.7,35.46 30.7,37.55 29.84,38.41 29.84,42.25 29.56,42.52 29.56,49.13 35.03,54.6 35.03,59.17 34.82,59.39
  BOTTOM w0.191: v3(30.98,32.43) 31.58,31.83 31.95,31.83 32.1,31.68 32.1,31.02 31.95,30.87 31.7,30.87 31.55,30.71 JDIM1.80 ; v2(35.47,68.54) 35.35,68.54 U20.AR46
M_B_A15: length 54.4
  IN1 w0.076: v2(35.47,69.22) 35.47,69.09 34.91,68.53 34.91,67.26 33.7,66.05 33.7,61.66 34.24,61.12 34.24,59.51 34.41,59.34
  IN1 w0.203: 34.41,59.34 34.7,59.05 34.7,54.92 29.1,49.32 29.1,42.32 29.38,42.04 29.38,38.21 30.24,37.34 30.24,37.01 30.07,36.84 30.07,36.56 30.24,36.38 30.24,35.73 29.74,35.22 29.74,34.95 29.89,34.8 29.89,34.24 29.46,33.81 29.46,31.86 29.33,31.73 28.38,31.73 28.23,31.88 28.23,32.03 27.94,32.31 27.73,32.31 27.6,32.19 27.6,31.27 27.22,30.89 27.22,30.66 27.93,29.95 27.93,29.75 28.06,29.62 28.62,29.62 29.08,30.08 29.43,30.08 29.89,29.62 30.8,29.62 30.95,29.77 30.95,30.46 30.98,30.49 v3(30.98,31.01)
  BOTTOM w0.191: JDIM1.78 30.95,30.23 31.08,30.36 31.08,30.9 v3(30.98,31.01) ; v2(35.47,69.22) 35.28,69.22 35.01,68.96 U20.AP46
M_B_BS#0: length 57.5
  IN1 w0.076: 41.67,62.46 41.67,62.67 41.28,63.06 41.28,67.2 41.14,67.34 41.14,68.3 41.12,68.32 41.12,70.67 41.24,70.8 41.33,70.8 v2(41.65,70.48)
  IN1 w0.203: 41.67,62.46 41.67,60.68 43.65,58.69 43.65,50.63 42.52,49.49 42.52,48.84 42.37,48.69 41.72,48.69 41.57,48.54 41.57,48.23 41.72,48.08 42.37,48.08 42.52,47.93 42.52,47.62 42.37,47.47 41.72,47.47 41.57,47.32 41.57,47.01 41.72,46.86 42.37,46.86 42.52,46.71 42.52,46.4 42.37,46.25 41.72,46.25 41.57,46.1 41.57,45.79 41.72,45.64 42.37,45.64 42.52,45.49 42.52,45.18 42.37,45.03 41.72,45.03 41.57,44.88 41.57,44.57 41.72,44.42 42.37,44.42 42.52,44.27 42.52,43.97 42.37,43.81 41.72,43.81 41.57,43.66 41.57,43.36 41.72,43.2 42.37,43.2 42.52,43.05 42.52,42.75 42.37,42.59 41.72,42.59 41.57,42.44 41.57,38.44 40.94,37.81 40.94,37.47 41.57,36.84 41.57,34.09 v3(41.52,34.04)
  BOTTOM w0.191: JDIM1.109 40.25,36.12 40.43,35.95 40.85,35.95 41.01,35.79 41.01,35.49 40.85,35.34 40.42,35.34 40.26,35.18 40.26,34.87 40.4,34.73 40.89,34.73 41.04,34.57 41.04,34.27 40.89,34.12 40.42,34.12 40.26,33.97 40.26,33.66 40.42,33.51 41.14,33.51 41.44,33.21 41.86,33.21 42.01,33.36 42.01,33.63 41.6,34.04 v3(41.52,34.04) ; U20.AL35 41.97,70.68 41.86,70.68 v2(41.65,70.48)
M_B_BS#1: length 58
  IN1 w0.076: 41.34,62.26 41.34,62.44 40.44,63.34 40.44,67.56 40.33,67.67 40.33,69.62 v2(40.69,69.97)
  IN1 w0.203: 41.34,62.26 41.34,60.57 43.2,58.72 43.2,50.82 41.11,48.73 41.11,43.5 40.96,43.35 40.68,43.35 40.53,43.2 40.53,42.89 40.68,42.74 40.96,42.74 41.11,42.59 41.11,42.28 40.96,42.13 39.97,42.13 39.81,41.98 39.81,41.67 39.97,41.52 40.96,41.52 41.11,41.37 41.11,41.06 40.96,40.91 39.97,40.91 39.81,40.76 39.81,40.45 39.97,40.3 40.96,40.3 41.11,40.15 41.11,39.85 40.96,39.69 40.07,39.69 39.92,39.54 39.92,39.24 40.07,39.08 40.96,39.08 41.11,38.93 41.11,38.63 40.96,38.47 40.07,38.47 39.92,38.32 39.92,37.84 41.11,36.65 41.11,34.35 40.51,33.75 40.51,33.54 40.63,33.41 41.13,33.41 41.24,33.3 41.24,33.1 40.75,32.61 40.75,32.42 40.88,32.29 41.19,32.29 v3(41.52,32.62)
  BOTTOM w0.191: JDIM1.108 39.95,31.31 40.1,31.46 40.78,31.46 40.94,31.62 40.94,31.91 40.78,32.06 39.97,32.06 39.82,32.21 39.82,32.5 39.97,32.66 41.48,32.66 v3(41.52,32.62) ; U20.AM36 41.06,69.97 v2(40.69,69.97)
M_B_BS#2: length 53.9
  IN1 w0.076: 34.16,59.16 34.02,59.29 34.02,61.11 33.53,61.59 33.53,65.65 33.1,66.09 v2(32.94,66.09)
  IN1 w0.203: 34.16,59.16 34.37,58.95 34.37,55.24 28.64,49.51 28.64,42.12 28.9,41.86 28.9,39.55 28.62,39.27 28.62,39 28.9,38.72 28.9,38.33 28.62,38.06 28.62,37.75 28.8,37.57 29.37,37.57 29.66,37.28 29.66,37.07 29.56,36.96 28.8,36.96 28.62,36.79 28.62,36.53 28.8,36.35 29.61,36.35 29.79,36.17 29.79,35.92 29.61,35.74 28.77,35.74 28.62,35.59 28.62,35.03 28.77,34.88 29.02,34.88 v3(29.25,35.11)
  BOTTOM w0.191: v3(29.25,35.11) 29.58,35.11 29.89,34.8 29.89,34.14 29.66,33.91 29.66,33.51 29.96,33.2 29.96,32.9 29.66,32.59 29.66,32.16 29.89,31.93 29.89,31.09 30.17,30.82 30.36,30.82 30.46,30.92 30.46,32.59 30.73,32.86 30.73,33.09 30.46,33.36 30.46,34.92 29.86,35.51 29.86,35.68 30.31,36.12 31.06,36.12 31.25,36.32 JDIM1.79 ; U20.AU49 33.05,67.04 32.94,66.93 v2(32.94,66.09)
M_B_CAS#: length 57.3
  IN1 w0.076: 42.64,62.53 41.82,63.35 41.82,67.12 42.26,67.56 42.26,69.47 v2(42.65,69.86)
  IN1 w0.203: 42.64,62.53 42.64,61 45.03,58.62 45.03,42.58 44.9,42.45 44.04,42.45 43.91,42.32 43.91,41.97 44.04,41.84 44.87,41.84 45,41.71 45,41.51 44.72,41.23 43.17,41.23 42.97,41.03 42.97,40.75 43.1,40.62 44.59,40.62 44.72,40.49 44.72,40.11 44.62,40.01 43.06,40.01 42.94,39.88 42.94,39.53 43.06,39.4 44.49,39.4 44.59,39.3 44.59,38.97 44.42,38.79 43.06,38.79 42.94,38.66 42.94,38.38 43.14,38.18 43.83,38.18 44.04,37.98 44.04,37.78 43.83,37.57 43.1,37.57 42.97,37.44 42.97,37.09 43.1,36.96 43.76,36.96 43.89,36.84 43.89,36.59 43.48,36.17 43.48,35.95 43.89,35.54 43.89,35.36 43.48,34.95 43.48,34.75 43.6,34.63 43.91,34.63 44.04,34.5 44.04,33.86 43.91,33.74 43.76,33.74 v3(42.97,34.52)
  BOTTOM w0.191: v2(42.65,69.86) 42.8,69.86 U20.AM33 ; v3(42.97,34.52) 42.82,34.38 42.53,34.38 41.98,34.93 41.98,35.21 42.11,35.34 42.33,35.34 42.46,35.46 42.46,35.74 42.05,36.15 JDIM1.115
M_B_CKE0: length 39.4
  IN1 w0.076: v2(32.92,64.72) 33.37,64.27 33.37,61.53 33.83,61.06 33.83,59.12 34.04,58.91 34.04,58.78
  IN1 w0.203: 34.04,58.78 34.04,55.91 27.91,49.78 27.91,34.14 28.31,33.74 v3(28.97,33.74)
  BOTTOM w0.191: U20.AY49 33.18,64.93 33.13,64.93 v2(32.92,64.72) ; v3(28.97,33.74) 28.77,33.94 28.77,35.59 29.45,36.27 JDIM1.73
M_B_CKE1: length 42.3
  IN1 w0.076: v2(32.91,62.66) 33.2,62.36 33.2,61.43 33.65,60.99 33.65,58.91 33.71,58.84 33.71,58.65
  IN1 w0.203: 33.71,58.65 33.71,56.23 27.45,49.97 27.45,33.81 v3(28.95,32.31)
  BOTTOM w0.076: U20.AU50 32.15,66.78 32.15,65.28 31.95,65.07
  BOTTOM w0.191: v3(28.95,32.31) 28.95,31.88 29.18,31.65 29.18,30.82 29.75,30.24 JDIM1.74 ; v2(32.91,62.66) 31.95,63.62 31.95,65.07
M_B_CLKN0: length 49.7
  IN1 w0.076: v2(39.77,69.86) 39.12,69.22 39.12,67.55 39.87,66.8 39.87,63 40.14,62.73 40.14,62.29 40.11,62.26
  IN1 w0.114: 40.11,62.26 40.11,60.06 41.6,58.58 41.6,57 41.85,56.75 41.85,51.44 38.99,48.58 38.99,48.13 38.91,48.04 38.45,48.04 38.22,47.82 38.22,47.22 38.45,46.99 39.5,46.99 39.65,46.84 39.65,46.52 39.5,46.37 38.47,46.37 38.22,46.11 38.22,45.54 38.45,45.31 39.5,45.31 39.65,45.16 39.65,44.84 39.5,44.69 38.45,44.69 38.22,44.46 38.22,39.68 38.58,39.32 38.58,37.29 39.6,36.26 39.6,35.86 39.77,35.69 39.77,34.9 39.46,34.6 39.29,34.6 39.14,34.74 v3(39.14,35.28)
  BOTTOM w0.114: U20.AM38 40.05,70.15 v2(39.77,69.86) ; v3(39.14,35.28) 39.14,34.76 39.01,34.63 38.66,34.63 38.47,34.81 38.47,35.62 38.05,36.04 38.05,36.14 38.45,36.53 JDIM1.103
M_B_CLKN1: length 48.1
  IN1 w0.076: v2(39.77,71.86) 39.77,71.54 39.52,71.29 39.45,71.29 38.8,70.64 38.8,69.58 38.68,69.45 38.68,64.3 38.9,64.08 39.04,64.08 39.29,63.82 39.29,62.24 39.27,62.21 39.27,62.15
  IN1 w0.114: v3(39.14,31.03) 39.14,31.61 39.06,31.69 38.79,31.69 38.25,32.24 38.25,36.35 37.74,36.85 37.74,38.97 37.38,39.33 37.38,48.16 41.01,51.8 41.01,56.39 40.75,56.66 40.75,58.23 39.27,59.71 39.27,62.15
  BOTTOM w0.114: JDIM1.104 38.75,30.06 38.35,30.45 38.35,30.58 38.52,30.75 38.52,30.86 38.85,31.19 38.99,31.19 39.14,31.03 v3(39.14,31.03) ; U20.AK38 40.05,71.6 40.02,71.6 v2(39.77,71.86)
M_B_CLKP0: length 49.4
  IN1 w0.076: v2(39.77,69.13) 39.57,69.32 39.46,69.32 39.29,69.15 39.29,67.62 40.04,66.87 40.04,63.07 40.31,62.8 40.31,62.28 40.33,62.26
  IN1 w0.114: v3(39.14,34) 39.14,34.25 39.27,34.38 39.55,34.38 39.98,34.82 39.98,35.78 39.82,35.95 39.82,36.35 38.8,37.38 38.8,39.41 38.44,39.77 38.44,44.37 38.54,44.47 39.59,44.47 39.86,44.75 39.86,45.25 39.59,45.53 38.54,45.53 38.44,45.63 38.44,46.02 38.56,46.15 39.59,46.15 39.86,46.43 39.86,46.93 39.59,47.2 38.54,47.2 38.44,47.31 38.44,47.73 38.54,47.83 39,47.83 39.21,48.04 39.21,48.49 42.07,51.35 42.07,56.84 41.81,57.09 41.81,58.67 40.33,60.15 40.33,62.26
  BOTTOM w0.114: v3(39.14,34) 39.14,34.34 39.06,34.42 38.57,34.42 38.27,34.72 38.27,35.53 37.85,35.95 JDIM1.101 ; U20.AN38 40.14,69.5 v2(39.77,69.13)
M_B_CLKP1: length 48
  IN1 w0.076: v2(39.72,70.55) 39.72,71 39.59,71.13 39.52,71.13 38.97,70.57 38.97,69.51 38.84,69.38 38.84,64.37 38.97,64.24 39.11,64.24 39.46,63.89 39.46,62.24 39.48,62.21
  IN1 w0.114: 39.48,62.21 39.48,59.8 40.96,58.32 40.96,56.75 41.23,56.48 41.23,51.71 37.6,48.08 37.6,39.42 37.96,39.06 37.96,36.94 38.46,36.44 38.46,32.33 38.88,31.91 39.01,31.91 39.14,32.04 v3(39.14,32.3)
  BOTTOM w0.114: v3(39.14,32.3) 39.14,31.77 38.32,30.94 38.32,30.83 38.15,30.66 JDIM1.102 ; U20.AL38 39.96,70.8 v2(39.72,70.55)
M_B_CS#0: length 46.7
  IN1 w0.076: 43.27,62.46 43.27,62.62 43.06,62.84 43.06,67.92 43.21,68.08 43.21,70.02 43.27,70.08 43.48,70.08 43.6,69.96 v2(43.6,69.84)
  IN1 w0.203: 43.27,62.46 43.27,61.23 46.19,58.31 46.19,41.03 45.94,40.78 45.94,38.56 45.2,37.83 45.2,33 44.7,32.49 44.7,31.27 v3(44.59,31.17)
  BOTTOM w0.191: v2(43.6,69.84) 43.81,69.84 43.99,70.01 U20.AM32 ; v3(44.59,31.17) 44.48,31.29 42.35,31.29 42.16,31.09 42.16,30.87 41.75,30.46 JDIM1.114
M_B_CS#1: length 47.5
  IN1 w0.076: v2(43.58,71.09) 44.02,70.65 44.02,67.63 43.28,66.89 43.28,62.94 43.6,62.62 43.6,62.46
  IN1 w0.203: v3(45.2,32.31) 45.66,32.77 45.66,37.62 46.4,38.36 46.4,40.59 46.65,40.84 46.65,58.29 43.6,61.33 43.6,62.46
  BOTTOM w0.191: JDIM1.121 43.85,36.39 44.68,35.55 44.68,34.31 45.2,33.79 v3(45.2,32.31) ; v2(43.58,71.09) 43.75,71.26 43.8,71.26 U20.AK32
M_B_DQ0: length 48
  IN1 w0.076: v2(27.03,68.52) 27.03,68.44 27.45,68.03 27.45,67.63
  IN1 w0.127: 27.45,67.63 26.23,66.42 26.23,65.92 25.65,65.33 25.65,63.66 24.68,62.69 24.68,61.63 15.54,52.48 15.54,49.53 15.24,49.23 15.24,45.63 15.53,45.34 15.53,35.37 15.24,35.08 15.24,32.88 15.07,32.71 14.79,32.71 14.59,32.91 14.41,32.91 14.22,32.71 14.22,32.52 14.59,32.14 v3(15.68,32.14)
  BOTTOM w0.127: JDIM1.36 15.95,30.26 16.2,30.51 16.2,31.63 v3(15.68,32.14) ; v2(27.03,68.52) 27.24,68.73 27.29,68.73 U20.AP58
M_B_DQ1: length 46.6
  IN1 w0.076: v2(27.03,67.85) 27.03,67.66 26.36,66.99 25.98,66.99 25.37,66.37 25.37,65.92
  IN1 w0.127: v3(15.68,30.72) 14.72,30.72 14.47,30.97 14.47,31.76 13.86,32.37 13.86,32.86 14.88,33.89 14.88,35.22 15.18,35.52 15.18,45.19 14.88,45.49 14.88,49.38 15.18,49.68 15.18,52.63 24.4,61.85 24.4,62.79 25.39,63.78 25.39,65.61 25.37,65.64 25.37,65.92
  BOTTOM w0.127: U20.AR58 27.26,68.05 27.24,68.05 v2(27.03,67.85) ; JDIM1.34 15.35,30.39 v3(15.68,30.72)
M_B_DQ2: length 49.4
  IN1 w0.076: 24.46,64.1 24.65,64.29 24.65,67.72 26.03,69.09 26.03,69.51 26.71,70.19 27.49,70.19 v2(27.85,69.82)
  IN1 w0.127: v3(12.55,32.22) 12.62,32.29 12.62,35.43 13.66,36.47 13.66,40.68 13.24,41.09 13.24,52.83 20.69,60.28 20.69,60.33 24.46,64.1
  BOTTOM w0.127: U20.AM57 28.17,70.01 28.04,70.01 v2(27.85,69.82) ; JDIM1.22 11.75,31.42 v3(12.55,32.22)
M_B_DQ3: length 51.4
  IN1 w0.076: v2(27.85,71.12) 27.33,71.64 26.76,71.64 26.15,71.04 26.15,70.75 25.26,69.86 25.26,69.09 24.12,67.94 24.12,65.27 23.99,65.14
  IN1 w0.127: v3(12.55,30.69) 12.1,31.14 12.1,32.25 11.27,33.08 11.27,35.85 11.69,36.26 11.69,40.85 12.17,41.33 12.17,53.27 17.65,58.74 17.65,58.8 23.99,65.14
  BOTTOM w0.127: U20.AK57 28.18,71.45 v2(27.85,71.12) ; JDIM1.24 12.35,30.49 v3(12.55,30.69)
M_B_DQ4: length 49.4
  IN1 w0.076: v2(26.96,70.59) 26.49,70.59 25.77,69.87 25.77,69.09 24.47,67.79 24.47,64.62 24.36,64.51
  IN1 w0.127: v3(11.72,33.26) 12.06,33.26 12.26,33.46 12.26,35.57 13.3,36.61 13.3,40.53 12.88,40.95 12.88,52.97 18.32,58.41 18.32,58.47 24.36,64.51
  BOTTOM w0.127: v2(26.96,70.59) 27.16,70.8 U20.AL58 ; JDIM1.21 11.45,36.1 11.25,35.89 11.25,33.73 v3(11.72,33.26)
M_B_DQ5: length 50.6
  IN1 w0.076: v2(26.92,71.25) 26.92,71.25 25.52,69.85 25.52,69.09 24.29,67.87 24.29,64.94 24.19,64.84
  IN1 w0.127: v3(11.72,34.91) 11.72,35.79 12.82,36.89 12.82,37.14 12.69,37.27 12.17,37.27 12.05,37.4 12.05,37.65 12.17,37.78 12.69,37.78 12.82,37.9 12.82,38.16 12.69,38.29 12.17,38.29 12.05,38.41 12.05,38.67 12.17,38.79 12.69,38.79 12.82,38.92 12.82,39.17 12.69,39.3 12.17,39.3 12.05,39.43 12.05,39.68 12.17,39.81 12.69,39.81 12.82,39.94 12.82,40.19 12.69,40.32 12.17,40.32 12.05,40.44 12.05,40.7 12.17,40.83 12.4,40.83 12.53,40.95 12.53,53.12 17.98,58.58 17.98,58.63 24.19,64.84
  BOTTOM w0.127: v2(26.92,71.25) 27.21,71.25 U20.AK58 ; JDIM1.23 12.05,35.24 v3(11.72,34.91)
M_B_DQ6: length 48.3
  IN1 w0.127: v2(27.85,68.51) 27.87,68.49 27.87,67.23 27.16,66.52 27.16,65.5 26.15,64.5 26.15,63.43 25.19,62.46 25.19,61.13 24.62,60.56 24.62,60.38 24.63,60.37 24.63,60.19 24.45,60.01 24.27,60.01 24.26,60.02 24.08,60.02 21.64,57.58 21.64,57.19 21.37,56.93 21.19,56.93 21.18,56.94 21,56.94 20.82,56.76 20.82,56.58 20.83,56.57 20.83,56.39 20.65,56.21 20.47,56.21 20.46,56.22 20.28,56.22 20.1,56.04 20.1,55.86 20.11,55.85 20.11,55.67 19.93,55.49 19.75,55.49 19.74,55.5 19.56,55.5 19.38,55.32 19.38,55.14 19.39,55.13 19.39,54.95 19.21,54.77 19.03,54.77 19.02,54.78 18.84,54.78 18.66,54.6 18.66,54.42 18.67,54.41 18.67,54.23 18.49,54.05 18.31,54.05 18.3,54.06 18.12,54.06 17.94,53.88 17.94,53.7 17.96,53.69 17.96,53.51 17.78,53.33 17.6,53.33 17.58,53.34 17.4,53.34 17.22,53.16 17.22,52.98 17.24,52.97 17.24,52.79 16.8,52.36 16.8,51.72 16.67,51.59 16.38,51.59 16.25,51.47 16.25,51.21 16.38,51.08 16.67,51.08 16.8,50.96 16.8,50.7 16.67,50.58 16.38,50.58 16.25,50.45 16.25,50.2 16.38,50.07 16.67,50.07 16.8,49.94 16.8,44.62 16.24,44.07 16.24,33.98 v3(15.68,33.42)
  BOTTOM w0.127: JDIM1.33 15.05,36.36 15.23,36.17 15.23,33.87 v3(15.68,33.42) ; v2(27.85,68.51) 28.04,68.32 28.18,68.32 U20.AR57
M_B_DQ7: length 49
  IN1 w0.076: v2(27.85,69.17) 27.46,68.78 27.46,68.3 27.65,68.11 27.65,67.47
  IN1 w0.127: 27.65,67.47 26.94,66.76 26.94,65.66 25.9,64.62 25.9,63.48 24.91,62.49 24.91,61.35 15.89,52.34 15.89,49.89 16.07,49.72 16.32,49.72 16.44,49.59 16.44,49.34 16.32,49.21 15.72,49.21 15.6,49.08 15.6,48.83 15.72,48.7 16.32,48.7 16.44,48.57 16.44,48.32 16.32,48.19 15.72,48.19 15.6,48.07 15.6,47.81 15.72,47.69 16.32,47.69 16.44,47.56 16.44,47.3 16.32,47.18 15.72,47.18 15.6,47.05 15.6,46.8 15.72,46.67 16.32,46.67 16.44,46.54 16.44,46.29 16.32,46.16 15.72,46.16 15.6,46.03 15.6,45.78 15.72,45.65 16.32,45.65 16.44,45.53 16.44,45.27 16.32,45.15 16.01,45.15 15.89,45.02 15.89,35.1 v3(15.68,34.89)
  BOTTOM w0.127: v2(27.85,69.17) 28.05,69.37 28.17,69.37 U20.AN57 ; JDIM1.35 15.65,34.93 v3(15.68,34.89)
M_B_DQ8: length 45.4
  IN1 w0.076: v2(28.81,68.52) 28.66,68.37 28.66,68.26 28.41,68.01 28.41,66.91 27.7,66.21 27.7,63.35 27.06,62.71
  IN1 w0.127: v3(17.7,35.82) 17.7,36.1 18.15,36.55 18.15,36.91 18.02,37.03 17.72,37.03 17.59,37.16 17.59,37.41 17.72,37.54 18.02,37.54 18.15,37.67 18.15,37.92 18.02,38.05 17.72,38.05 17.59,38.18 17.59,38.43 17.72,38.56 18.02,38.56 18.15,38.68 18.15,38.94 18.02,39.07 17.72,39.07 17.59,39.19 17.59,39.45 17.72,39.57 18.02,39.57 18.15,39.7 18.15,39.95 18.02,40.08 17.72,40.08 17.59,40.21 17.59,40.46 17.72,40.59 18.02,40.59 18.15,40.72 18.15,40.97 18.02,41.1 17.72,41.1 17.59,41.22 17.59,41.48 17.72,41.61 18.02,41.61 18.15,41.73 18.15,41.99 18.02,42.11 17.72,42.11 17.59,42.24 17.59,42.49 17.72,42.62 18.02,42.62 18.15,42.75 18.15,43 18.02,43.13 17.72,43.13 17.59,43.26 17.59,43.51 17.72,43.64 18.02,43.64 18.15,43.76 18.15,51.8 26.08,59.73 26.08,61.88 26.9,62.71 27.06,62.71
  BOTTOM w0.127: U20.AP55 29.16,68.75 29.04,68.75 v2(28.81,68.52) ; v3(17.7,35.82) 17.45,36.07 JDIM1.41
M_B_DQ9: length 45.2
  IN1 w0.076: 27.91,66.13 28.6,66.82 28.6,67.64 v2(28.81,67.85)
  IN1 w0.127: 27.91,66.13 27.91,63.2 26.43,61.73 26.43,59.58 18.5,51.65 18.5,36.4 18.18,36.08 18.18,34.52 18.66,34.04 18.66,33.38 18.41,33.13 17.98,33.13 17.73,33.38 v3(17.73,34.28)
  BOTTOM w0.127: U20.AR55 29.16,68.1 29.06,68.1 v2(28.81,67.85) ; JDIM1.39 16.85,35.16 v3(17.73,34.28)
M_B_DQ10: length 47.6
  IN1 w0.076: v2(30.71,69.84) 30.55,69.99 30.42,69.99 30.32,69.89 30.32,69.01 30.5,68.83 30.5,65.54
  IN1 w0.127: 30.5,65.54 29.53,64.57 29.53,62.17 28.52,61.15 28.52,58.03 21.63,51.14 21.63,46.53 21.5,46.4 21.4,46.4 21.28,46.28 21.28,46.02 21.4,45.9 21.5,45.9 21.63,45.77 21.63,45.52 21.5,45.39 21.4,45.39 21.28,45.26 21.28,45.01 21.4,44.88 21.5,44.88 21.63,44.75 21.63,44.5 21.5,44.37 21.4,44.37 21.28,44.25 21.28,43.99 21.4,43.86 21.5,43.86 21.63,43.74 21.63,43.48 21.5,43.36 21.4,43.36 21.28,43.23 21.28,42.98 21.4,42.85 21.5,42.85 21.63,42.72 21.63,42.47 21.5,42.34 21.4,42.34 21.28,42.21 21.28,41.96 21.4,41.83 21.5,41.83 21.63,41.71 21.63,41.45 21.5,41.32 21.4,41.32 21.28,41.2 21.28,40.94 21.4,40.82 21.5,40.82 21.63,40.69 21.63,40.44 21.5,40.31 21.4,40.31 21.28,40.18 21.28,39.93 21.4,39.8 21.5,39.8 21.63,39.67 21.63,39.42 21.5,39.29 21.4,39.29 21.28,39.17 21.28,38.91 21.4,38.78 21.5,38.78 21.63,38.66 21.63,38.4 21.5,38.28 21.4,38.28 21.28,38.15 21.28,37.9 21.4,37.77 21.5,37.77 21.63,37.64 21.63,37.39 21.5,37.26 21.4,37.26 21.28,37.13 21.28,36.88 21.4,36.75 21.5,36.75 21.63,36.63 21.63,36.37 21.5,36.24 21.4,36.24 21.28,36.12 21.28,35.86 21.63,35.51 v3(21.63,35.14)
  BOTTOM w0.127: JDIM1.53 21.05,36.3 20.82,36.07 20.82,34.9 20.95,34.78 21.27,34.78 v3(21.63,35.14) ; v2(30.71,69.84) 30.52,69.84 U20.AM54
M_B_DQ11: length 48.8
  IN1 w0.076: 30.26,65.68 30.32,65.74 30.32,68.75 30.15,68.92 30.15,70.73 v2(29.76,71.12)
  IN1 w0.127: v3(21.63,33.69) 21.18,34.14 21.18,35.46 20.87,35.77 20.87,46.47 21,46.6 21.09,46.6 21.22,46.72 21.22,46.98 21.09,47.11 21,47.11 20.87,47.23 20.87,47.49 21,47.61 21.09,47.61 21.22,47.74 21.22,47.99 21.09,48.12 21,48.12 20.87,48.25 20.87,48.5 21,48.63 21.09,48.63 21.22,48.76 21.22,49.01 21.09,49.14 21,49.14 20.87,49.26 20.87,49.52 21,49.65 21.09,49.65 21.22,49.77 21.22,51.23 28.16,58.17 28.16,61.3 29.28,62.42 29.28,64.7 30.26,65.68
  BOTTOM w0.127: v3(21.63,33.69) 21.37,33.43 20.77,33.43 20.45,33.75 JDIM1.51 ; v2(29.76,71.12) 30.08,71.45 U20.AK54
M_B_DQ12: length 47.2
  IN1 w0.076: 27.16,63.11 27.53,63.48 27.53,66.3 28.24,67.01 28.24,68.08 28.41,68.25 28.41,70.09 v2(28.81,70.48)
  IN1 w0.127: v3(17.73,32.19) 17.23,32.69 17.23,43.66 17.79,44.21 17.79,51.95 25.72,59.88 25.72,61.91 26.79,62.97 27.02,62.97 27.16,63.11
  BOTTOM w0.127: U20.AL55 29.15,70.69 29.02,70.69 v2(28.81,70.48) ; v3(17.73,32.19) 17.15,31.61 JDIM1.40
M_B_DQ13: length 48
  IN1 w0.076: 27.06,63.34 27.35,63.63 27.35,66.37 28.07,67.1 28.07,68.16 28.25,68.34 28.25,70.59 v2(28.81,71.15)
  IN1 w0.127: v3(17.73,30.72) 16.88,31.57 16.88,43.81 17.43,44.36 17.43,52.09 25.42,60.08 25.42,61.98 26.66,63.23 26.94,63.23 27.06,63.34
  BOTTOM w0.127: U20.AK55 29.1,71.45 v2(28.81,71.15) ; v3(17.73,30.72) 17.75,30.7 JDIM1.42
M_B_DQ14: length 46.2
  IN1 w0.127: v3(20.29,32.12) 19.77,31.6 19.43,31.6 19.17,31.86 19.17,32.61 19.43,32.87 19.92,32.87 20.44,33.38 20.44,35.19 20,35.63 20,51.02 27.45,58.47 27.45,61.49 28.82,62.86 28.82,65 29.76,65.94 v2(29.76,67.87)
  BOTTOM w0.127: v2(29.76,67.87) 29.96,68.07 30.08,68.07 U20.AR54 ; JDIM1.52 20.75,31.66 v3(20.29,32.12)
M_B_DQ15: length 47.6
  IN1 w0.076: 30.09,67.16 30.09,67.48 30.15,67.54 30.15,68.68 29.93,68.91 29.93,69 v2(29.76,69.17)
  IN1 w0.127: 30.09,67.16 30.09,65.89 29.05,64.85 29.05,62.69 27.81,61.45 27.81,58.32 20.52,51.03 20.52,50.53 20.64,50.4 20.72,50.4 20.85,50.27 20.85,50.02 20.72,49.89 20.64,49.89 20.52,49.77 20.52,35.62 20.8,35.34 20.8,33.95 21.22,33.52 21.22,33 21.09,32.88 20.82,32.88 20.69,32.75 20.69,32.49 20.82,32.37 21.09,32.37 21.22,32.24 21.22,31.99 21.09,31.86 20.85,31.86 20.72,31.73 20.72,31.48 20.85,31.35 21.09,31.35 21.22,31.22 21.22,30.98 21.08,30.84 20.51,30.84 v3(20.28,30.62)
  BOTTOM w0.127: v3(20.28,30.62) 20.15,30.49 JDIM1.50 ; v2(29.76,69.17) 29.95,69.37 30.07,69.37 U20.AN54
M_B_DQ16: length 71.9
  IN1 w0.076: v2(38.44,71.89) 38.35,71.89 36.38,73.86 29.27,73.86 29.08,73.67 28.8,73.67
  IN1 w0.127: 28.8,73.67 25.37,73.67 24.05,72.34 23.64,72.34 22.75,71.46 20.99,71.46 20.64,71.1 17.79,71.1 17.72,71.03 17.26,71.03 15.87,69.64 15.87,67.67 15.99,67.54 15.99,66.15 15.66,65.82 15.66,64.04 13.2,61.57 13.2,60.93 8.64,56.37 8.64,55.28 6.51,53.15 6.51,39.56 6.63,39.43 6.76,39.43 6.89,39.3 6.89,39.05 6.76,38.92 6.63,38.92 6.51,38.8 6.51,38.54 6.63,38.42 6.76,38.42 6.89,38.29 6.89,38.03 6.76,37.91 6.63,37.91 6.51,37.78 6.51,37.53 6.63,37.4 6.76,37.4 6.89,37.27 6.89,37.02 6.76,36.89 6.63,36.89 6.51,36.76 6.51,34.82 6.82,34.5 6.82,32.67 6.93,32.57 6.93,31.27 v3(6.47,30.82)
  BOTTOM w0.127: U20.AK40 38.71,71.62 v2(38.44,71.89) ; JDIM1.4 6.35,30.7 v3(6.47,30.82)
M_B_DQ17: length 72.5
  IN1 w0.076: 28.96,74.03 36.94,74.03 38.85,72.12 38.85,71.7 v2(38.3,71.14)
  IN1 w0.127: 28.96,74.03 25.21,74.03 23.88,72.7 23.49,72.7 22.6,71.81 20.73,71.81 20.37,71.46 17.65,71.46 17.57,71.38 17.12,71.38 15.51,69.78 15.51,67.52 15.61,67.42 15.61,66.27 15.31,65.97 15.31,64.19 12.82,61.7 12.82,61.05 8.2,56.44 8.2,55.35 6.15,53.3 6.15,34.66 6.47,34.35 v3(6.47,32.24)
  BOTTOM w0.127: v3(6.47,32.24) 6.95,31.76 JDIM1.6 ; U20.AK42 38.17,71.14 v2(38.3,71.14)
M_B_DQ18: length 69.4
  IN1 w0.076: v2(36.43,70.5) 36.43,70.51 36.03,70.91 36.03,71.44 34.72,72.76 32.96,72.76 32.38,72.18 26.38,72.18 24.54,70.34 24.54,69.49 24.38,69.32
  IN1 w0.127: v3(9.46,33.62) 9.51,33.62 9.93,34.04 9.93,35.28 9.71,35.49 9.71,36.57 9.84,36.7 10.21,36.7 10.35,36.84 10.35,37.06 10.2,37.21 9.84,37.21 9.71,37.34 9.71,37.59 9.84,37.72 10.16,37.72 10.28,37.85 10.28,38.1 10.16,38.23 9.84,38.23 9.71,38.35 9.71,38.61 9.84,38.74 10.16,38.74 10.35,38.92 10.35,41.15 10.22,41.27 9.91,41.27 9.79,41.4 9.79,41.66 9.91,41.78 10.22,41.78 10.35,41.91 10.35,42.16 10.22,42.29 9.91,42.29 9.79,42.42 9.79,42.67 9.91,42.8 10.22,42.8 10.35,42.93 10.35,51.41 10.47,51.54 10.7,51.54 10.83,51.66 10.83,51.92 10.7,52.04 10.47,52.04 10.35,52.17 10.35,52.43 10.47,52.55 10.7,52.55 10.83,52.68 10.83,53.84 15.13,58.14 15.13,58.27 14.72,58.68 14.72,58.81 14.95,59.03 15.11,59.03 15.49,58.65 15.61,58.65 16.18,59.23 16.18,60.8 18.94,63.56 20.5,63.56 23.36,66.42 23.36,68.31 24.38,69.32
  BOTTOM w0.127: v2(36.43,70.5) 36.57,70.5 U20.AM43 ; v3(9.46,33.62) 10.15,33.62 10.61,34.08 10.61,35.59 10.25,35.95 JDIM1.17
M_B_DQ19: length 69
  IN1 w0.076: 24.72,69.28 24.72,70.21 26.51,72 32.43,72 33.03,72.59 34.63,72.59 35.87,71.35 35.87,70.3 v2(35.47,69.91)
  IN1 w0.127: 24.72,69.28 23.66,68.23 23.66,66.22 20.65,63.2 19.14,63.2 18.74,62.8 18.74,62.58 19.3,62.03 19.3,61.85 16.74,59.29 16.74,59.25 11.18,53.69 11.18,51.32 11.05,51.19 10.83,51.19 10.7,51.06 10.7,50.81 10.83,50.68 11.05,50.68 11.18,50.55 11.18,50.3 11.05,50.17 10.83,50.17 10.7,50.05 10.7,36.67 10.28,36.26 10.28,33 10.05,32.77 9.36,32.77 8.5,31.91 8.5,31.73 8.63,31.6 9.07,31.6 v3(9.74,32.27)
  BOTTOM w0.127: U20.AM45 35.79,70 35.57,70 v2(35.47,69.91) ; v3(9.74,32.27) 10.09,32.62 10.79,32.62 11.04,32.36 11.04,30.84 10.55,30.35 JDIM1.18
M_B_DQ20: length 69.1
  IN1 w0.076: v2(35.47,71.16) 35.47,71.49 34.54,72.43 33.1,72.43 32.49,71.82 26.69,71.82 24.92,70.05 24.92,69.03 24.73,68.84
  IN1 w0.127: 24.73,68.84 23.92,68.04 23.92,65.97 20.24,62.29 19.87,62.29 19.66,62.08 19.66,61.71 17.07,59.12 17.07,59.07 11.54,53.53 11.54,49.82 11.41,49.69 11.18,49.69 11.06,49.56 11.06,49.31 11.18,49.18 11.41,49.18 11.54,49.06 11.54,48.8 11.41,48.68 11.18,48.68 11.06,48.55 11.06,48.29 11.18,48.17 11.41,48.17 11.54,48.04 11.54,47.79 11.41,47.66 11.18,47.66 11.06,47.53 11.06,47.28 11.18,47.15 11.41,47.15 11.54,47.02 11.54,46.77 11.41,46.64 11.18,46.64 11.06,46.52 11.06,46.26 11.18,46.14 11.41,46.14 11.54,46.01 11.54,45.75 11.41,45.63 11.18,45.63 11.06,45.5 11.06,45.25 11.18,45.12 11.41,45.12 11.54,44.99 11.54,44.74 11.41,44.61 11.18,44.61 11.06,44.48 11.06,44.23 11.18,44.1 11.41,44.1 11.54,43.98 11.54,43.72 11.41,43.6 11.18,43.6 11.06,43.47 11.06,43.21 11.18,43.09 11.41,43.09 11.54,42.96 11.54,42.71 11.41,42.58 11.18,42.58 11.06,42.45 11.06,42.2 11.18,42.07 11.41,42.07 11.54,41.94 11.54,41.61 11.43,41.51 11.16,41.51 11.06,41.41 11.06,41.11 11.06,41.11 11.06,36.53 10.64,36.11 10.64,32.36 10.77,32.24 11.21,32.24 11.47,31.98 11.47,30.99 11.33,30.85 11.09,30.85 10.96,30.97 10.96,31.6 10.83,31.73 10.58,31.73 10.45,31.6 10.45,30.97 10.33,30.85 v3(9.74,30.85)
  BOTTOM w0.127: JDIM1.16 9.95,30.64 v3(9.74,30.85) ; U20.AK45 35.65,71.16 v2(35.47,71.16)
M_B_DQ21: length 70.6
  IN1 w0.076: v2(36.43,71.22) 36.43,71.5 35,72.92 32.89,72.92 32.32,72.35 26.23,72.35 24.34,70.46 24.34,70.3 24.15,70.11
  IN1 w0.127: 24.15,70.11 23.92,69.89 23.92,69.29 23,68.37 23,66.56 20.36,63.92 18.8,63.92 15.56,60.68 15.56,60.1 15.83,59.84 15.83,59.58 15.67,59.42 15.49,59.42 15.23,59.67 15.07,59.67 12.66,57.26 12.66,57.08 13.02,56.72 13.02,56.53 12.85,56.37 12.65,56.37 12.3,56.72 12.12,56.72 11.94,56.54 11.94,56.36 12.31,55.99 12.31,55.82 12.13,55.64 11.94,55.64 11.58,56 11.4,56 11.13,55.73 11.13,54.65 9.99,53.51 9.99,48.56 9.86,48.43 9.48,48.43 9.35,48.31 9.35,48.05 9.48,47.92 9.86,47.92 9.99,47.8 9.99,47.54 9.86,47.42 9.48,47.42 9.35,47.29 9.35,47.04 9.48,46.91 9.86,46.91 9.99,46.78 9.99,46.53 9.86,46.4 9.48,46.4 9.35,46.27 9.35,46.02 9.48,45.89 9.86,45.89 9.99,45.77 9.99,45.51 9.86,45.38 9.48,45.38 9.35,45.26 9.35,45 9.48,44.88 9.86,44.88 9.99,44.75 9.99,44.5 9.86,44.37 9.48,44.37 9.35,44.24 9.35,43.99 9.48,43.86 9.86,43.86 9.99,43.73 9.99,43.45 9.89,43.35 9.46,43.35 9.35,43.25 9.35,35.22 v3(9.46,35.11)
  BOTTOM w0.127: JDIM1.15 9.65,36.05 9.39,35.79 8.5,35.79 8.25,35.54 8.25,34.88 8.37,34.75 8.68,34.75 9.04,35.11 v3(9.46,35.11) ; v2(36.43,71.22) 36.69,71.22 U20.AK43
M_B_DQ22: length 70.2
  IN1 w0.076: 28.57,73.31 29.16,73.31 29.55,73.7 36.29,73.7 37.91,72.08 37.91,69.93 38.01,69.82 v2(38.3,69.82)
  IN1 w0.127: v3(7.51,34.32) 6.86,34.97 6.86,35.9 7.5,36.54 7.5,39.54 6.86,40.18 6.86,49.76 7.18,50.08 7.18,53.32 9,55.13 9,56.22 13.58,60.81 13.58,61.32 18.03,65.77 19.59,65.77 21.15,67.33 21.15,69.7 22.01,70.57 22.37,70.57 23.79,71.99 24.21,71.99 25.53,73.31 28.57,73.31
  BOTTOM w0.127: JDIM1.5 6.65,35.61 6.98,35.29 6.98,34.85 6.5,34.37 6.5,34.04 6.7,33.84 7.03,33.84 v3(7.51,34.32) ; v2(38.3,69.82) 38.63,70.15 U20.AM40
M_B_DQ23: length 70
  IN1 w0.076: 28.69,72.95 29.26,72.95 29.84,73.53 36.2,73.53 37.74,71.99 37.74,70.28 37.35,69.88 v2(37.35,69.87)
  IN1 w0.127: v3(7.31,35.72) 7.86,36.27 7.86,40.07 7.73,40.2 7.35,40.2 7.22,40.32 7.22,40.58 7.35,40.7 7.73,40.7 7.86,40.83 7.86,41.09 7.73,41.21 7.35,41.21 7.22,41.34 7.22,41.59 7.35,41.72 7.73,41.72 7.86,41.85 7.86,42.1 7.73,42.23 7.35,42.23 7.22,42.36 7.22,42.61 7.35,42.74 7.73,42.74 7.86,42.86 7.86,43.12 7.73,43.24 7.35,43.24 7.22,43.37 7.22,43.63 7.35,43.75 7.73,43.75 7.86,43.88 7.86,44.13 7.73,44.26 7.35,44.26 7.22,44.39 7.22,44.64 7.35,44.77 7.73,44.77 7.86,44.9 7.86,45.15 7.73,45.28 7.35,45.28 7.22,45.4 7.22,45.66 7.35,45.78 7.73,45.78 7.86,45.91 7.86,46.27 7.31,46.82 7.31,49.7 7.54,49.93 7.54,53.17 9.35,54.99 9.35,56.08 14.06,60.79 14.06,61.3 18.18,65.42 19.74,65.42 21.51,67.18 21.51,69.45 22.27,70.21 22.52,70.21 23.94,71.63 24.38,71.63 25.7,72.95 28.69,72.95
  BOTTOM w0.127: U20.AM42 37.62,70.15 v2(37.35,69.87) ; v3(7.31,35.72) 7.25,35.77 JDIM1.7
M_B_DQ24: length 51.1
  IN1 w0.076: 32.43,61.22 32.33,61.32 32.33,66.28 32.71,66.66 33.41,66.66 34.29,67.55 34.29,68.47 34.91,69.1 34.91,70.37 34.74,70.55 v2(34.52,70.55)
  IN1 w0.127: 32.43,61.22 32.43,56.4 26.19,50.17 26.19,46.4 26,46.21 26,35.36 26.19,35.17 26.19,33.29 25.46,32.56 25.46,31 25.62,30.85 25.86,30.85 26.01,31 26.01,32.05 v3(26.45,32.5)
  BOTTOM w0.127: v2(34.52,70.55) 34.75,70.32 34.84,70.32 U20.AM46 ; JDIM1.68 25.55,31.59 v3(26.45,32.5)
M_B_DQ25: length 50.1
  IN1 w0.076: 32.66,61.25 32.5,61.41 32.5,66.22 32.77,66.49 33.47,66.49 34.46,67.48 34.46,68.39 35.08,69.01 35.08,70.64 v2(34.52,71.2)
  IN1 w0.127: 32.66,61.25 32.78,61.13 32.78,56.25 26.78,50.25 26.78,49.89 26.55,49.66 26.55,49.38 26.78,49.16 26.78,48.88 26.55,48.65 26.55,48.37 26.78,48.14 26.78,47.86 26.55,47.63 26.55,47.35 26.78,47.12 26.78,46.11 26.65,45.98 26.54,45.98 26.41,45.86 26.41,45.6 26.54,45.48 26.65,45.48 26.78,45.35 26.78,45.09 26.65,44.97 26.54,44.97 26.41,44.84 26.41,44.59 26.54,44.46 26.65,44.46 26.78,44.33 26.78,44.08 26.65,43.95 26.54,43.95 26.41,43.82 26.41,43.57 26.54,43.44 26.65,43.44 26.78,43.32 26.78,43.06 26.65,42.94 26.54,42.94 26.41,42.81 26.41,42.55 26.54,42.43 26.65,42.43 26.78,42.3 26.78,42.05 26.65,41.92 26.54,41.92 26.41,41.79 26.41,41.54 26.54,41.41 26.65,41.41 26.78,41.28 26.78,32.8 26.92,32.66 26.92,31.55 26.45,31.09 v3(26.45,30.97)
  BOTTOM w0.127: JDIM1.70 26.15,30.67 v3(26.45,30.97) ; U20.AK46 34.77,71.45 v2(34.52,71.2)
M_B_DQ26: length 48.4
  IN1 w0.076: v2(32.62,69.82) 32.22,69.43 32.22,67.55 31.31,66.64 31.31,64.98
  IN1 w0.127: 31.31,64.98 31.23,64.89 31.23,63.6 30.73,63.1 30.73,61.13 30.22,60.62 30.22,57.32 23.33,50.43 23.33,45.44 23.46,45.31 23.67,45.31 23.79,45.18 23.79,44.93 23.67,44.8 23.46,44.8 23.33,44.67 23.33,44.42 23.46,44.29 23.67,44.29 23.79,44.17 23.79,43.91 23.67,43.78 23.46,43.78 23.33,43.66 23.33,43.4 23.46,43.28 23.67,43.28 23.79,43.15 23.79,42.9 23.67,42.77 23.46,42.77 23.33,42.64 23.33,42.39 23.46,42.26 23.67,42.26 23.79,42.13 23.79,41.25 23.54,41 23.54,38.66 23.79,38.4 23.79,34.37 23.3,33.88 v3(23.29,33.88)
  BOTTOM w0.127: U20.AM49 32.9,70 32.79,70 v2(32.62,69.82) ; JDIM1.57 22.25,36.38 22.18,36.3 22.18,33.69 22.61,33.25 22.91,33.25 23.29,33.63 v3(23.29,33.88)
M_B_DQ27: length 47.2
  IN1 w0.076: v2(32.62,71.12) 32.25,71.12 32.06,70.93 32.06,67.64 31.07,66.65 31.07,65.04
  IN1 w0.127: v3(23.3,35.32) 23.1,35.32 22.97,35.44 22.97,36 23.1,36.13 23.31,36.13 23.44,36.26 23.44,36.51 23.31,36.64 23.1,36.64 22.97,36.77 22.97,37.02 23.1,37.15 23.31,37.15 23.44,37.27 23.44,37.53 23.31,37.65 23.1,37.65 22.97,37.78 22.97,38.04 23.18,38.24 23.18,38.59 22.97,38.8 22.97,39.05 23.18,39.26 23.18,39.61 22.97,39.81 22.97,40.07 23.18,40.28 23.18,40.62 22.97,40.83 22.97,41.25 23.1,41.38 23.31,41.38 23.44,41.51 23.44,41.76 23.31,41.89 23.1,41.89 22.97,42.02 22.97,50.58 29.86,57.46 29.86,60.77 30.47,61.38 30.47,63.28 31.01,63.82 31.01,64.98 31.07,65.04
  BOTTOM w0.127: JDIM1.59 22.85,36.3 22.53,35.98 22.53,34.92 22.63,34.82 22.88,34.82 22.98,34.92 22.98,35.19 23.11,35.32 v3(23.3,35.32) ; v2(32.62,71.12) 32.62,71.34 32.76,71.48 33.05,71.48 U20.AK49
M_B_DQ28: length 49.9
  IN1 w0.076: 31.83,62.81 31.83,66.4 32.56,67.12 33.4,67.12 33.96,67.68 33.96,69.64 33.78,69.82 v2(33.57,69.82)
  IN1 w0.127: v3(25.75,33.56) 25.29,34.02 25.29,46.05 25.19,46.16 24.94,46.16 24.83,46.27 24.83,46.54 24.96,46.67 25.36,46.67 25.48,46.79 25.48,47.05 25.36,47.17 24.96,47.17 24.83,47.3 24.83,47.56 24.96,47.68 25.36,47.68 25.48,47.81 25.48,48.06 25.36,48.19 24.96,48.19 24.83,48.32 24.83,48.57 24.96,48.7 25.36,48.7 25.48,48.83 25.48,49.08 25.36,49.21 24.96,49.21 24.83,49.33 24.83,49.59 24.95,49.71 25.3,49.71 25.48,49.89 25.48,50.46 31.72,56.7 31.72,62.69 31.83,62.81
  BOTTOM w0.127: U20.AM48 33.82,70.01 33.75,70.01 v2(33.57,69.82) ; v3(25.75,33.56) 26.31,33.56 26.51,33.76 26.51,35.72 25.85,36.38 JDIM1.69
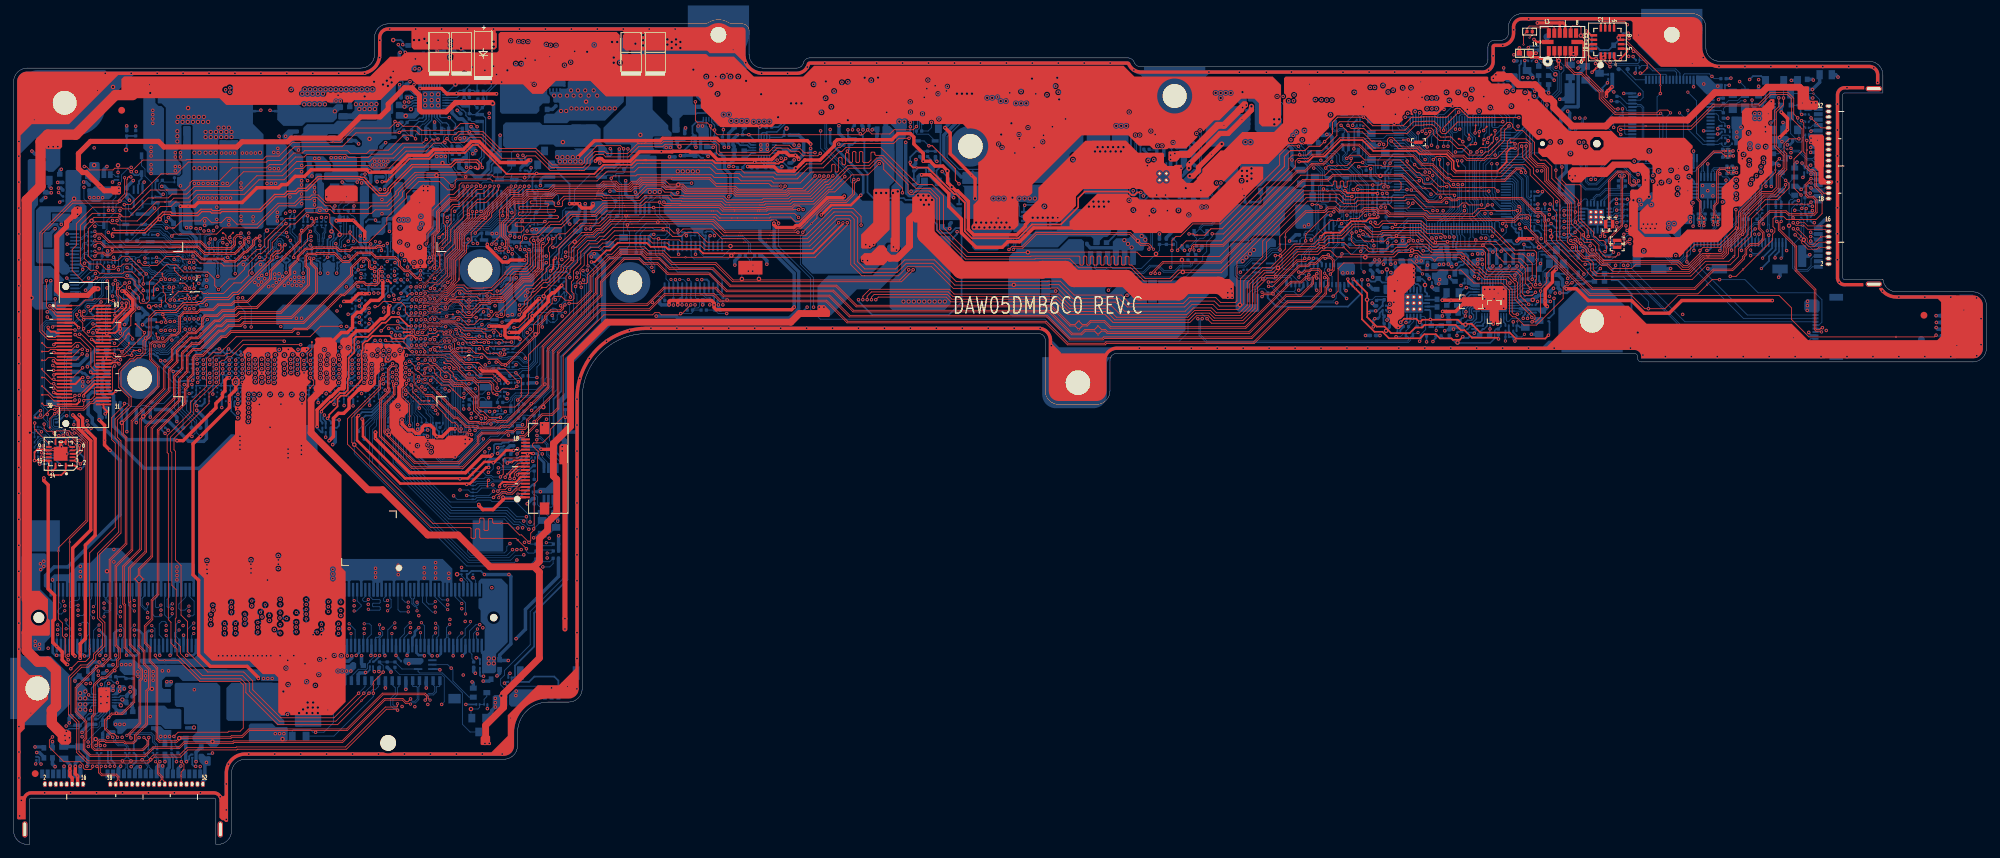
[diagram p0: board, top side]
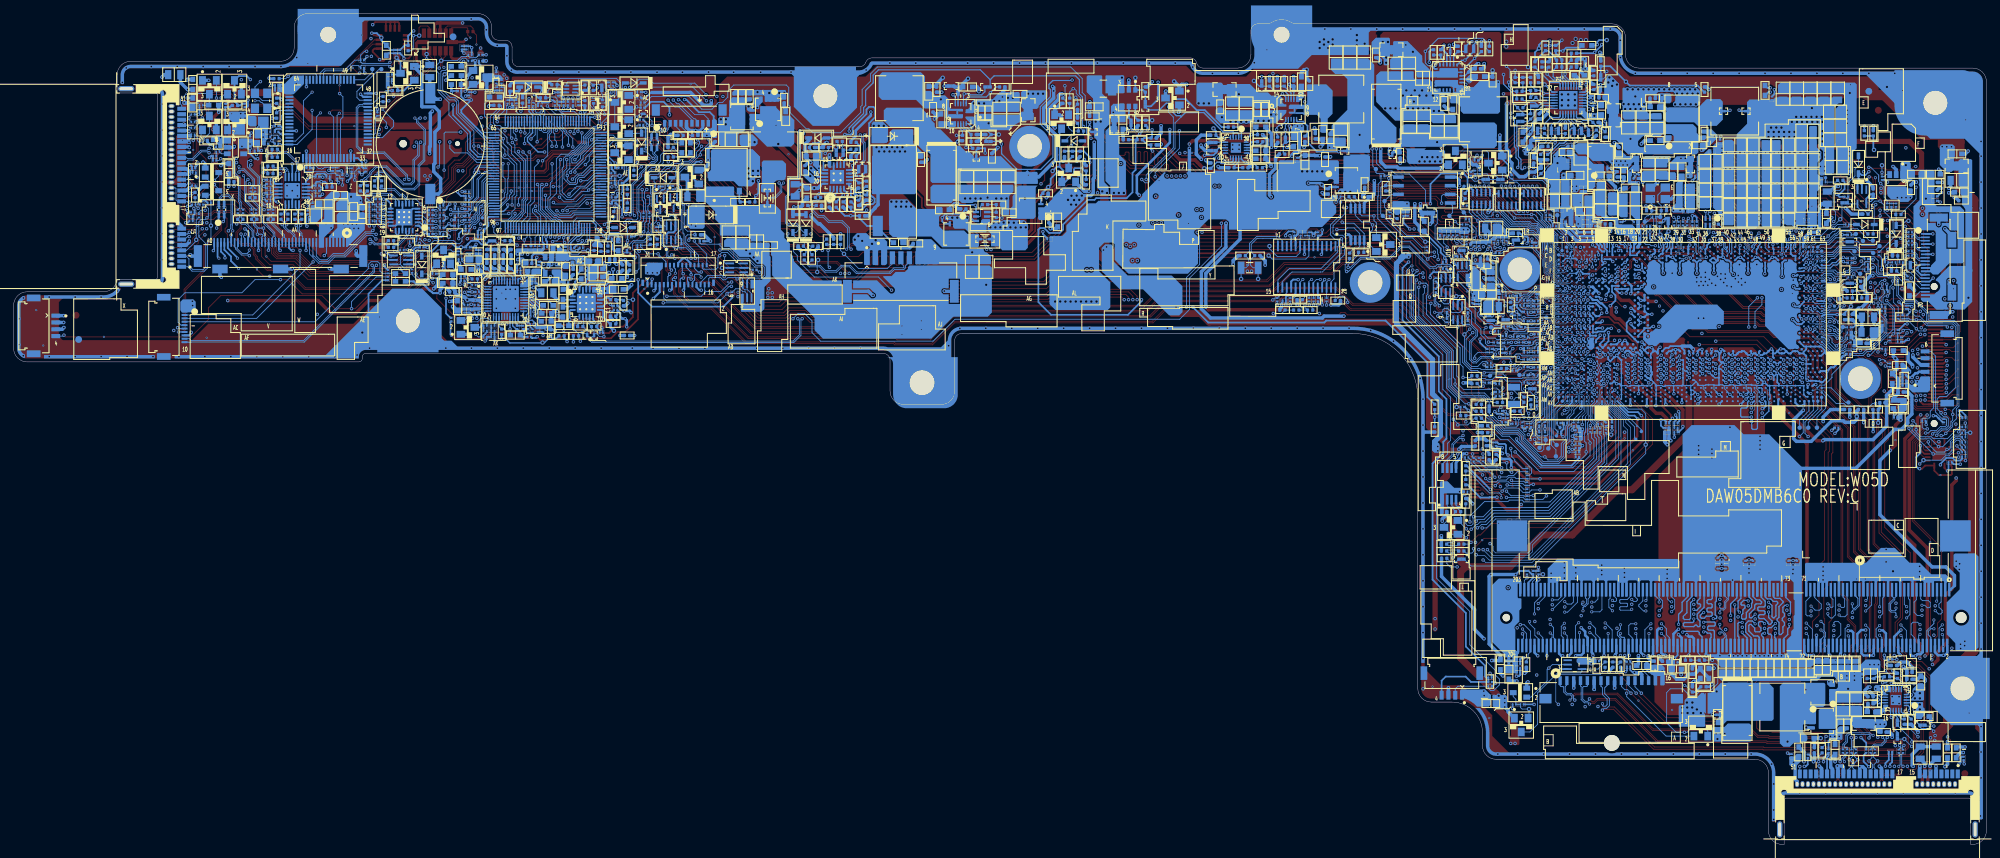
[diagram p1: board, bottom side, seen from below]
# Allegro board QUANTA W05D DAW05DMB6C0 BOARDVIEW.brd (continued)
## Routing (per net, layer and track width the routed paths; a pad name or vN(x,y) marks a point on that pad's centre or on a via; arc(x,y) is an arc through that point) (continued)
M_B_DQ29: length 49.7
  IN1 w0.076: v2(33.57,71.13) 33.17,71.13 33.01,71.29 33.01,72.03 33.24,72.26 33.56,72.26 34.13,71.7 34.13,71.06 34.05,70.98 33.96,70.98 33.88,70.91 33.88,70.76 33.96,70.68 34.05,70.68 34.13,70.6 34.13,70.45 34.05,70.38 34.01,70.38 33.93,70.3 33.93,70.15 34.01,70.07 34.05,70.07 34.13,69.99 34.13,67.61 33.35,66.84 32.53,66.84 32.02,66.34 32.02,62.51 32.07,62.46
  IN1 w0.127: 32.07,62.46 32.07,56.55 25.84,50.31 25.84,46.65 25.65,46.46 25.65,35.09 v3(25.75,34.99)
  BOTTOM w0.127: v2(33.57,71.13) 33.77,71.33 33.87,71.33 U20.AK48 ; JDIM1.67 25.25,36.29 24.25,35.29 24.25,34.65 24.5,34.4 25.16,34.4 v3(25.75,34.99)
M_B_DQ30: length 47.3
  IN1 w0.076: 30.88,65.16 30.88,67.06 31.27,67.44 31.27,69.42 v2(31.66,69.81)
  IN1 w0.127: 30.88,65.16 30.11,64.39 30.11,61.52 29.51,60.92 29.51,57.61 22.62,50.72 22.62,33.25 22.21,32.84 22.21,32.33 v3(22.4,32.14)
  BOTTOM w0.127: JDIM1.56 21.95,30.21 21.39,30.77 21.39,32.36 21.77,32.75 22.22,32.75 22.4,32.57 v3(22.4,32.14) ; v2(31.66,69.81) 31.86,70 31.91,70 U20.AM51
M_B_DQ31: length 46.8
  IN1 w0.076: 30.69,65.35 30.69,67.17 31.1,67.58 31.1,70.12 31.23,70.24 31.23,70.69 v2(31.66,71.12)
  IN1 w0.127: v3(22.4,30.67) 21.85,31.22 21.85,32.99 22.26,33.4 22.26,50.87 29.15,57.76 29.15,61.07 29.84,61.75 29.84,64.5 30.69,65.35
  BOTTOM w0.127: v3(22.4,30.67) 22.55,30.52 JDIM1.58 ; v2(31.66,71.12) 31.84,71.29 31.92,71.29 U20.AK51
M_B_DQ32: length 45.4
  IN1 w0.076: 43.73,63.28 43.73,66.45 44.48,67.2 44.48,69.9 v2(45.05,70.47)
  IN1 w0.127: v3(46.22,34.17) 46.51,34.17 46.69,34.36 46.69,36.01 47.03,36.35 47.03,36.66 46.69,37 46.69,37.2 46.9,37.41 47.08,37.41 47.29,37.2 47.47,37.2 47.65,37.38 47.65,37.56 47.44,37.77 47.44,37.95 47.71,38.21 47.71,53.99 47.85,54.13 48.3,54.13 48.46,54.29 48.46,58.32 45.38,61.4 45.38,61.63 43.73,63.28
  BOTTOM w0.127: U20.AM29 45.25,70.35 45.18,70.35 v2(45.05,70.47) ; v3(46.22,34.17) 45.78,34.62 45.78,35.91 46.25,36.38 JDIM1.129
M_B_DQ33: length 47.6
  IN1 w0.076: v2(45.05,71.72) 44.78,71.99 44.32,71.99 44.06,71.73 44.06,71.23 44.3,70.99 44.3,67.4 43.53,66.63 43.53,63.07
  IN1 w0.127: v3(46.22,35.62) 46.33,35.73 46.33,37.34 47.07,38.08 47.07,38.59 47.33,38.84 47.33,54.36 47.45,54.49 47.97,54.49 48.1,54.62 48.1,54.87 47.97,55 47.45,55 47.33,55.12 47.33,55.38 47.45,55.5 47.97,55.5 48.1,55.63 48.1,55.89 47.97,56.01 47.45,56.01 47.33,56.14 47.33,56.39 47.45,56.52 47.97,56.52 48.1,56.65 48.1,56.9 47.97,57.03 47.45,57.03 47.33,57.16 47.33,57.41 47.45,57.54 47.97,57.54 48.1,57.66 48.1,57.93 47.99,58.04 47.5,58.04 47.39,58.16 47.39,58.32 47.57,58.5 47.57,58.7 45.03,61.24 45.03,61.57 43.53,63.07
  BOTTOM w0.127: v3(46.22,35.62) 46.43,35.62 46.85,36.05 JDIM1.131 ; v2(45.05,71.72) 45.23,71.72 U20.AK29
M_B_DQ34: length 46.3
  IN1 w0.076: 48.38,62.26 48.38,62.47 46.3,64.55 46.3,65.33 46.47,65.51 46.47,66.38 45.97,66.89 45.97,67.26 46.47,67.77 46.47,68.05 46.41,68.12 46.41,69.32 46.22,69.51 46.22,69.77 46.41,69.96 46.41,71.04 46.29,71.16 v2(45.98,71.16)
  IN1 w0.127: 48.38,62.26 48.38,61.35 51.73,57.99 51.73,45.93 51.38,45.57 50.92,45.57 50.65,45.3 50.65,35.85 50.41,35.62 50.41,35.4 50.65,35.16 50.65,34.53 50.39,34.28 v3(50.01,34.28)
  BOTTOM w0.127: v2(45.98,71.16) 46.25,71.16 46.41,71 U20.AL28 ; JDIM1.143 50.45,35.75 51.05,35.16 51.05,34.97 50.35,34.28 v3(50.01,34.28)
M_B_DQ35: length 46.7
  IN1 w0.076: v2(46.16,71.89) 46.57,71.48 46.57,68.26 46.66,68.18 46.66,64.44 48.61,62.49 48.61,62.03
  IN1 w0.127: 48.61,62.03 48.61,61.47 51.95,58.13 51.95,57.26 52.09,57.12 52.09,45.78 51,44.69 51,34.38 49.71,33.09 49.71,31.13 v3(49.55,30.97)
  BOTTOM w0.127: JDIM1.140 v3(49.55,30.97) ; U20.AK28 46.41,71.65 v2(46.16,71.89)
M_B_DQ36: length 43.6
  IN1 w0.076: 44.27,63.68 44.27,65.11 44.83,65.67 44.83,68.18 45.05,68.4 v2(45.05,68.53)
  IN1 w0.127: 44.27,63.68 46.09,61.85 46.09,61.7 49.17,58.63 49.17,53.98 48.42,53.23 48.42,37.11 48,36.69 48,36.26 47.4,35.67 47.4,32.7 v3(47.71,32.4)
  BOTTOM w0.127: JDIM1.130 46.55,30.36 46.98,30.79 46.98,31.67 v3(47.71,32.4) ; v2(45.05,68.53) 45.26,68.32 45.33,68.32 U20.AR29
M_B_DQ37: length 45.2
  IN1 w0.076: v2(45.05,69.83) 44.65,69.43 44.65,65.82 44.47,65.64 44.19,65.64 44.06,65.51 44.06,63.45
  IN1 w0.127: 44.06,63.45 45.74,61.77 45.74,61.55 48.81,58.48 48.81,54.13 48.06,53.38 48.06,37.26 47.62,36.82 47.62,36.39 47.05,35.82 47.05,31.16 47.23,30.97 v3(47.71,30.97)
  BOTTOM w0.127: v3(47.71,30.97) 47.15,30.42 JDIM1.132 ; v2(45.05,69.83) 45.3,69.58 45.37,69.58 U20.AN29
M_B_DQ38: length 43.4
  IN1 w0.076: 46.09,65.51 46.3,65.71 46.3,66.32 45.75,66.87 45.75,67.6 v2(46,67.86)
  IN1 w0.127: 46.09,65.51 46.09,64.37 46.47,63.99 46.48,63.99 47.24,63.23 47.24,62.16 51.02,58.37 51.02,57.85 51.15,57.72 51.25,57.72 51.38,57.59 51.38,57.34 51.25,57.21 51.15,57.21 51.02,57.08 51.02,56.83 51.15,56.7 51.25,56.7 51.38,56.58 51.38,56.32 51.25,56.2 51.15,56.2 51.02,56.07 51.02,55.81 51.15,55.69 51.25,55.69 51.38,55.56 51.38,55.31 51.25,55.18 51.15,55.18 51.02,55.05 51.02,54.8 51.15,54.67 51.25,54.67 51.38,54.54 51.38,54.29 51.25,54.16 51.15,54.16 51.02,54.04 51.02,53.78 51.15,53.66 51.25,53.66 51.38,53.53 51.38,53.27 51.25,53.15 51.15,53.15 51.02,53.02 51.02,52.77 51.15,52.64 51.25,52.64 51.38,52.51 51.38,52.26 51.25,52.13 51.15,52.13 51.02,52 51.02,51.75 51.15,51.62 51.25,51.62 51.38,51.5 51.38,51.24 51.25,51.12 51.15,51.12 51.02,50.99 51.02,50.73 51.15,50.61 51.25,50.61 51.38,50.48 51.38,50.23 51.25,50.1 51.15,50.1 51.02,49.97 51.02,49.72 51.15,49.59 51.25,49.59 51.38,49.46 51.38,49.21 51.25,49.08 51.15,49.08 51.02,48.96 51.02,48.7 51.15,48.58 51.25,48.58 51.38,48.45 51.38,48.19 51.25,48.07 51.15,48.07 51.02,47.94 51.02,47.69 51.15,47.56 51.25,47.56 51.38,47.43 51.38,47.18 51.25,47.05 50.67,47.05 50.55,46.92 50.55,46.67 50.67,46.54 51.25,46.54 51.38,46.42 51.38,46.16 51.25,46.04 50.55,46.04 50.29,45.78 50.29,36.09 v3(50.01,35.8)
  BOTTOM w0.127: v2(46,67.86) 46.07,67.86 U20.AR28 ; v3(50.01,35.8) 49.85,35.96 JDIM1.141
M_B_DQ39: length 44.6
  IN1 w0.076: v2(46.01,68.51) 46.01,68.44 45.43,67.86 45.43,66.05 45.81,65.66
  IN1 w0.127: v3(49.27,32.4) 48.6,32.4 48.49,32.51 48.49,33.79 48.74,34.04 48.92,34.04 49.02,33.94 49.2,33.94 49.38,34.12 49.38,34.5 49.56,34.69 49.56,36.14 49.94,36.51 49.94,46.82 50.67,47.55 50.67,58.4 47.01,62.06 47.01,63.07 45.81,64.27 45.81,65.66
  BOTTOM w0.127: U20.AP28 46.35,68.85 v2(46.01,68.51) ; JDIM1.142 50.15,31.52 v3(49.27,32.4)
M_B_DQ40: length 47.7
  IN1 w0.076: v2(46.98,69.17) 47.24,69.17 47.4,69.01 47.4,68.29 47.17,68.06 47.17,67.36 47.62,66.91 47.62,64.28 49.04,62.86 49.04,61.78
  IN1 w0.127: 49.04,61.78 52.41,58.41 52.41,57.79 53.21,56.99 53.31,56.99 53.43,56.86 53.43,56.61 53.31,56.48 53.18,56.48 53.08,56.38 53.08,56.08 53.18,55.97 53.31,55.97 53.43,55.85 53.43,55.59 53.31,55.47 53.21,55.47 53.08,55.34 53.08,55.09 53.21,54.96 53.31,54.96 53.43,54.83 53.43,54.58 53.31,54.45 53.21,54.45 53.08,54.32 53.08,54.07 53.21,53.94 53.31,53.94 53.43,53.82 53.43,53.56 53.31,53.43 53.21,53.43 53.08,53.31 53.08,53.05 53.21,52.93 53.31,52.93 53.43,52.8 53.43,52.55 53.31,52.42 53.21,52.42 53.08,52.29 53.08,52.04 53.21,51.91 53.31,51.91 53.43,51.78 53.43,51.53 53.31,51.4 53.21,51.4 53.08,51.28 53.08,51.02 53.21,50.89 53.31,50.89 53.43,50.77 53.43,50.51 53.31,50.39 53.21,50.39 53.08,50.26 53.08,50.01 53.21,49.88 53.31,49.88 53.43,49.75 53.43,49.5 53.31,49.37 53.21,49.37 53.08,49.24 53.08,48.99 53.21,48.86 53.31,48.86 53.43,48.74 53.43,48.48 53.31,48.35 53.21,48.35 53.08,48.23 53.08,47.97 53.21,47.85 53.31,47.85 53.43,47.72 53.43,47.47 53.31,47.34 53.21,47.34 53.08,47.21 53.08,46.96 53.21,46.83 53.31,46.83 53.43,46.7 53.43,46.45 53.31,46.32 53.21,46.32 53.08,46.2 53.08,45.76 53.21,45.63 53.33,45.63 53.43,45.53 53.43,45.19 53.31,45.06 53.17,45.06 53.04,45.19 52.9,45.19 52.7,44.99 52.7,44.81 53.3,44.2 53.3,44.06 53.09,43.84 52.95,43.84 52.34,44.45 52.16,44.45 51.99,44.28 51.99,44.07 52.51,43.56 52.51,43.26 52.41,43.16 52.12,43.16 51.99,43.03 51.99,36.06 v3(52.08,35.97)
  BOTTOM w0.127: JDIM1.147 51.65,36.43 51.25,36.03 51.25,35.87 51.45,35.67 51.78,35.67 v3(52.08,35.97) ; v2(46.98,69.17) 47.31,69.5 U20.AN26
M_B_DQ41: length 46.6
  IN1 w0.076: v2(46.98,68.52) 46.98,67.01 47.45,66.53 47.45,64.13 48.84,62.75 48.84,61.63
  IN1 w0.127: v3(51.49,30.97) 51.49,29.93 51.38,29.82 50.45,29.82 50.35,29.93 50.35,32.83 51.64,34.12 51.64,44.43 52.72,45.51 52.72,57.13 52.19,57.66 52.19,58.27 48.84,61.63
  BOTTOM w0.127: v3(51.49,30.97) 51.35,30.84 JDIM1.146 ; U20.AR26 47.04,68.51 46.98,68.51 v2(46.98,68.52)
M_B_DQ42: length 46.6
  IN1 w0.076: 49.45,62.06 49.45,62.95 48,64.4 48,67.55 v2(47.73,67.82)
  IN1 w0.127: v3(51.49,32.4) 50.95,31.86 50.79,31.86 50.71,31.94 50.71,32.68 51.97,33.95 52.13,33.95 52.96,34.78 52.96,38.79 52.71,39.04 52.71,40.73 52.96,40.99 52.96,41.38 52.71,41.64 52.71,41.9 52.96,42.15 52.96,42.69 54.14,43.87 54.14,56.98 52.84,58.29 52.84,58.67 49.45,62.06
  BOTTOM w0.127: v3(51.49,32.4) 52.26,32.4 52.52,32.14 52.52,30.85 51.95,30.28 JDIM1.148 ; U20.AR25 48.1,68.2 v2(47.73,67.82)
M_B_DQ43: length 47.3
  IN1 w0.076: 49.24,61.91 49.24,62.9 47.82,64.33 47.82,66.96 47.34,67.44 47.34,67.99 47.79,68.45 v2(47.79,68.52)
  IN1 w0.127: v3(52.08,34.53) 52.21,34.53 52.6,34.92 52.6,36.18 52.35,36.43 52.35,36.68 52.6,36.94 52.6,37.16 52.35,37.41 52.35,37.73 52.6,37.99 52.6,38.33 52.35,38.59 52.35,42.6 53.79,44.04 53.79,44.25 53.61,44.43 53.61,44.71 53.79,44.89 53.79,57.03 53.44,57.38 53.12,57.38 52.62,57.88 52.62,58.53 49.24,61.91
  BOTTOM w0.127: U20.AP25 47.99,68.52 v2(47.79,68.52) ; JDIM1.149 52.25,36.44 52.74,35.96 53.74,35.96 53.84,35.86 53.84,35.51 53.74,35.41 52.8,35.41 52.7,35.31 52.7,35.01 52.8,34.9 53.74,34.9 53.84,34.8 53.84,34.5 53.74,34.4 52.22,34.4 v3(52.08,34.53)
M_B_DQ44: length 49.9
  IN1 w0.076: v2(46.97,71.12) 47.34,71.49 47.34,71.99 47.58,72.23 47.91,72.23 49.15,70.99 49.15,68.14 49.01,68 49.01,66.06 50.62,64.45 50.62,63.92 51.74,62.79 51.93,62.79 53.92,60.81 53.92,60.51
  IN1 w0.127: v3(55.98,32.52) 56.15,32.69 56.15,39.32 56.04,39.43 56.04,41.19 56.29,41.45 56.29,42.36 56.71,42.78 56.71,57.31 53.92,60.1 53.92,60.51
  BOTTOM w0.127: U20.AK26 47.29,71.45 v2(46.97,71.12) ; JDIM1.158 54.95,31.49 v3(55.98,32.52)
M_B_DQ45: length 48.4
  IN1 w0.076: v2(46.97,69.81) 47.39,70.23 47.39,70.57 47.64,70.81 47.96,70.81 48.65,70.12 48.65,68.34 48.51,68.21 48.51,65.54 49.27,64.78 49.27,64.11 50.08,63.3 50.08,62.57 50.23,62.41
  IN1 w0.127: v3(55.55,30.97) 54.82,30.97 54.69,31.09 54.69,32.53 54.46,32.76 54.46,42.03 55.64,43.22 55.64,56.85 53.71,58.78 53.71,58.93 50.23,62.41
  BOTTOM w0.127: v3(55.55,30.97) JDIM1.160 ; U20.AM26 47.31,70.15 v2(46.97,69.81)
M_B_DQ46: length 49.6
  IN1 w0.076: v2(47.74,71.83) 48.03,71.83 48.98,70.88 48.98,68.21 48.84,68.07 48.84,65.97 50.44,64.37 50.44,63.85 51.94,62.34 52.13,62.34 53.53,60.94 53.53,59.98 53.64,59.87
  IN1 w0.127: v3(54.92,34.31) 54.92,32.88 55.04,32.75 55.45,32.75 55.79,33.1 55.79,39.17 55.68,39.28 55.68,41.34 55.94,41.59 55.94,42.51 56.35,42.92 56.35,57.16 53.64,59.87
  BOTTOM w0.127: v2(47.74,71.83) 47.92,71.83 U20.AK25 ; v3(54.92,34.31) 55.44,34.83 55.44,35.95 55.25,36.14 JDIM1.159
M_B_DQ47: length 49
  IN1 w0.076: 50.4,62.6 50.26,62.74 50.26,63.38 49.45,64.19 49.45,64.86 48.68,65.63 48.68,68.14 48.82,68.28 48.82,70.49 48.09,71.21 v2(47.84,71.21)
  IN1 w0.127: 50.4,62.6 51.06,61.94 51.95,61.94 52.61,61.28 52.61,60.39 56,57 56,43.07 55.58,42.65 55.58,42.28 55.33,42.02 54.95,42.02 54.81,41.89 54.81,41.64 54.94,41.52 55.23,41.52 55.33,41.41 55.33,41.11 55.23,41.01 54.94,41.01 54.81,40.88 54.81,40.63 54.94,40.5 55.23,40.5 55.33,40.4 55.33,40.09 55.23,39.99 54.94,39.99 54.81,39.86 54.81,39.61 54.94,39.48 55.23,39.48 55.33,39.38 55.33,39.08 55.23,38.98 54.94,38.98 54.81,38.85 54.81,38.59 54.94,38.47 55.33,38.47 55.44,38.37 55.44,38.06 55.33,37.96 54.94,37.96 54.81,37.83 54.81,37.58 54.94,37.45 55.31,37.45 55.44,37.32 55.44,37.07 55.31,36.94 54.94,36.94 54.81,36.82 54.81,36.58 54.96,36.44 55.26,36.44 55.44,36.26 55.44,35.61 55.31,35.49 55.07,35.49 54.92,35.64 v3(54.92,35.83)
  BOTTOM w0.127: U20.AL25 48.14,70.97 48.09,70.97 v2(47.84,71.21) ; JDIM1.157 54.65,36.43 54.31,36.09 54.31,35.79 54.44,35.67 54.75,35.67 v3(54.92,35.83)
M_B_DQ48: length 43.7
  IN1 w0.076: v2(51.45,67.84) 51.45,67.2 52.04,66.61 52.04,66 56.56,61.47 56.56,61.45
  IN1 w0.127: v3(61.92,35.65) 61.82,35.76 61.82,38.23 61.52,38.52 61.52,41.51 61.18,41.85 61.18,44.19 61.31,44.31 61.4,44.31 61.52,44.44 61.52,44.69 61.4,44.82 61.31,44.82 61.18,44.95 61.18,45.2 61.31,45.33 61.4,45.33 61.52,45.46 61.52,45.71 61.4,45.84 61.31,45.84 61.18,45.96 61.18,46.22 61.31,46.35 61.4,46.35 61.52,46.47 61.52,46.73 61.4,46.85 61.31,46.85 61.18,46.98 61.18,47.23 61.31,47.36 61.4,47.36 61.52,47.49 61.52,47.74 61.4,47.87 61.31,47.87 61.18,48 61.18,48.25 61.31,48.38 61.4,48.38 61.52,48.5 61.52,48.76 61.4,48.89 61.31,48.89 61.18,49.01 61.18,49.27 61.31,49.39 61.4,49.39 61.52,49.52 61.52,49.77 61.4,49.9 61.31,49.9 61.18,50.03 61.18,50.28 61.31,50.41 61.4,50.41 61.52,50.54 61.52,54.87 61.13,55.27 61.13,57.21 60.19,58.15 60.19,58.83 59.73,59.29 58.67,59.29 56.56,61.4 56.56,61.45
  BOTTOM w0.127: v3(61.92,35.65) 61.55,35.29 60.95,35.29 60.65,35.59 JDIM1.177 ; U20.AR21 51.09,68.2 v2(51.45,67.84)
M_B_DQ49: length 44.3
  IN1 w0.076: v2(49.57,67.78) 49.34,67.54 49.34,66.23 50.97,64.59 50.97,64.07 51.89,63.15 52.14,63.15 54.35,60.94 54.35,60.56
  IN1 w0.127: 54.35,60.56 57.7,57.21 57.7,42.37 57.28,41.95 57.28,38.97 57.14,38.83 57.14,33.65 v3(58.23,32.56)
  BOTTOM w0.127: U20.AR22 49.99,68.2 v2(49.57,67.78) ; v3(58.23,32.56) 57.39,31.72 57.39,31.72 57.39,30.92 56.75,30.28 JDIM1.164
M_B_DQ50: length 47.1
  IN1 w0.076: v2(50.63,70.47) 51.05,70.04 51.05,68.31 50.88,68.14 50.88,67.26 51.68,66.46 51.68,65.89 56.19,61.38 56.19,61 56.51,60.69
  IN1 w0.127: v3(59.75,31.09) 60.33,31.67 60.33,33.95 61.11,34.73 61.11,37.94 60.75,38.29 60.75,40.95 60.47,41.23 60.47,50.81 60.67,51.01 60.67,54.72 60.37,55.02 60.37,56.83 56.51,60.69
  BOTTOM w0.127: U20.AL21 50.95,70.8 v2(50.63,70.47) ; JDIM1.174 v3(59.75,31.09)
M_B_DQ51: length 46.8
  IN1 w0.076: v2(49.72,69.82) 49.99,69.82 50.1,69.71 50.1,69.02 49.87,68.79 49.87,68.27 50.17,67.97 50.17,67.31 50.03,67.18 49.78,67.18 49.67,67.07 49.67,66.38 51.33,64.72 51.33,64.2 52.02,63.51 52.29,63.51 54.51,61.28 55.15,61.28 55.39,61.04 55.39,60.56
  IN1 w0.127: v3(57.95,35.57) 57.85,35.67 57.85,36.1 57.98,36.23 59.12,36.23 59.25,36.36 59.25,36.61 59.12,36.74 57.98,36.74 57.85,36.86 57.85,37.12 57.98,37.25 58.67,37.25 58.79,37.37 58.79,37.63 58.67,37.75 57.98,37.75 57.85,37.88 57.85,38.35 58.26,38.76 58.26,41.92 58.41,42.07 58.41,57.38 55.39,60.4 55.39,60.56
  BOTTOM w0.127: U20.AM22 50.11,69.94 49.99,69.82 v2(49.72,69.82) ; v3(57.95,35.57) 57.49,35.57 57.05,36.01 JDIM1.165
M_B_DQ52: length 45.6
  IN1 w0.076: v2(49.7,69.19) 49.7,68.2 49.98,67.93 49.98,67.62 49.5,67.15 49.5,66.32 51.15,64.67 51.15,64.14 51.97,63.33 52.21,63.33 54.52,61.01 54.52,60.65 54.86,60.32 55.04,60.32
  IN1 w0.127: 55.04,60.32 58.06,57.3 58.06,42.22 57.64,41.8 57.64,41.45 57.77,41.32 57.78,41.32 57.9,41.19 57.9,40.94 57.78,40.81 57.77,40.81 57.64,40.68 57.64,40.43 57.77,40.3 57.78,40.3 57.9,40.18 57.9,39.92 57.78,39.79 57.77,39.79 57.64,39.67 57.64,39.41 57.77,39.29 57.78,39.29 57.9,39.16 57.9,38.91 57.78,38.78 57.64,38.78 57.49,38.63 57.49,34.31 57.65,34.15 v3(57.95,34.15)
  BOTTOM w0.127: U20.AN22 49.99,69.38 49.88,69.38 49.7,69.2 v2(49.7,69.19) ; v3(57.95,34.15) 56.76,34.15 56.45,34.46 JDIM1.163
M_B_DQ53: length 45
  IN1 w0.076: 56.3,60.51 56,60.81 56,61.33 51.5,65.83 51.5,66.39 50.7,67.19 50.7,68.48 v2(50.66,68.52)
  IN1 w0.127: 56.3,60.51 59.94,56.87 59.94,54.84 60.32,54.46 60.32,51.16 59.92,50.77 59.92,41.09 59.85,41.01 59.85,38.69 60.75,37.79 60.75,34.88 59.94,34.07 59.94,32.62 v3(59.88,32.56)
  BOTTOM w0.127: v3(59.88,32.56) 60.35,32.09 JDIM1.176 ; U20.AP21 50.88,68.66 50.8,68.66 v2(50.66,68.52)
M_B_DQ54: length 47.4
  IN1 w0.076: 56.51,61.07 56.35,61.22 56.35,61.44 51.86,65.94 51.86,66.54 51.05,67.35 51.05,68.05 51.23,68.24 51.23,69.57 51.23,69.58 51.23,70.54 v2(50.65,71.12)
  IN1 w0.127: 56.51,61.07 58.54,59.03 59.46,59.03 59.78,58.71 59.78,57.76 60.77,56.77 60.77,55.12 61.03,54.86 61.03,50.86 60.83,50.66 60.83,41.38 61.11,41.1 61.11,38.44 61.46,38.08 61.46,34.56 v3(61.92,34.1)
  BOTTOM w0.127: JDIM1.175 60.05,35.55 61.5,34.1 v3(61.92,34.1) ; v2(50.65,71.12) 50.87,71.35 50.96,71.35 U20.AK21
M_B_DQ55: length 47.5
  IN1 w0.076: 54.14,60.25 54.14,60.84 52.01,62.97 51.82,62.97 50.8,64 50.8,64.52 49.17,66.14 49.17,67.93 49.31,68.07 49.31,70.72 v2(49.72,71.12)
  IN1 w0.127: v3(58.23,31.1) 56.78,32.55 56.78,38.98 56.93,39.12 56.93,42.1 57.35,42.51 57.35,57.05 54.14,60.25
  BOTTOM w0.127: U20.AK22 50,71.28 49.88,71.28 v2(49.72,71.12) ; JDIM1.166 57.35,30.34 58.12,31.1 v3(58.23,31.1)
M_B_DQ56: length 50.7
  IN1 w0.076: v2(51.63,69.83) 51.63,69.83 52.2,69.26 52.2,68.19 52.02,68.01 52.02,67.66 52.39,67.29 52.39,66.29 56.85,61.82 56.96,61.82 57.07,61.72
  IN1 w0.127: 57.07,61.72 58.86,59.92 60.01,59.92 60.44,59.49 61.09,59.49 62.13,58.45 62.13,55.72 62.51,55.34 62.51,41.97 62.91,41.57 62.91,32.82 63.37,32.36 63.37,32.01 63.24,31.88 62.99,31.88 62.86,31.76 62.86,31.5 62.99,31.37 63.24,31.37 63.37,31.25 63.37,30.99 63.24,30.87 62.99,30.87 62.86,30.74 62.86,30.46 62.73,30.33 62.13,30.33 61.97,30.49 v3(61.97,31.05)
  BOTTOM w0.127: U20.AN20 51.92,69.59 51.86,69.59 51.63,69.83 v2(51.63,69.83) ; JDIM1.180 61.55,30.63 v3(61.97,31.05)
M_B_DQ57: length 49.4
  IN1 w0.076: 56.81,61.57 52.21,66.17 52.21,66.67 51.84,67.04 51.84,68 51.63,68.21 v2(51.63,68.52)
  IN1 w0.127: v3(61.97,32.47) 61.61,32.11 61.1,32.11 60.96,32.26 60.96,33.52 61.1,33.66 62.36,33.66 62.55,33.86 62.55,41.42 62.16,41.82 62.16,42.17 62.03,42.3 61.94,42.3 61.82,42.43 61.82,42.68 61.94,42.81 62.03,42.81 62.16,42.94 62.16,43.19 62.03,43.32 61.94,43.32 61.82,43.44 61.82,43.7 61.94,43.82 62.03,43.82 62.16,43.95 62.16,55.14 61.78,55.52 61.78,58.5 61.14,59.14 60.49,59.14 59.94,59.7 58.68,59.7 56.81,61.57
  BOTTOM w0.127: v3(61.97,32.47) 62.43,32.02 62.43,30.66 62.15,30.39 JDIM1.182 ; v2(51.63,68.52) 51.69,68.52 U20.AR20
M_B_DQ58: length 51.5
  IN1 w0.076: v2(53.34,71.78) 53.51,71.6 53.51,69.85 53.86,69.5 ; 56.15,66.48 55.47,66.48 54.72,67.23 54.03,67.23 53.86,67.4 53.86,68.53
  IN1 w0.089: 53.86,69.5 53.86,68.53
  IN1 w0.127: 56.15,66.48 59,63.63 60.47,63.63 61.21,62.9 61.6,62.9 65.91,58.59 65.91,56.88 66.72,56.06 66.72,44.21 67.43,43.49 67.43,33.07 v3(67.08,32.73)
  BOTTOM w0.127: v3(67.08,32.73) 67.08,32.42 66.31,31.65 66.31,30.71 65.75,30.15 JDIM1.194 ; U20.AK18 53.11,71.59 53.15,71.59 v2(53.34,71.78)
M_B_DQ59: length 50.9
  IN1 w0.076: v2(52.59,70.47) 52.98,70.09 52.98,69.62 53.32,69.28 53.32,66.63 54.19,65.77 54.48,65.77
  IN1 w0.127: v3(65.81,35.37) 66.22,35.79 66.22,40.85 65.65,41.43 65.65,42.84 65.14,43.34 65.14,48.47 65.27,48.6 65.52,48.6 65.65,48.72 65.65,48.98 65.52,49.11 65.27,49.11 65.14,49.23 65.14,49.49 65.27,49.61 65.52,49.61 65.65,49.74 65.65,49.99 65.52,50.12 65.27,50.12 65.14,50.25 65.14,50.5 65.27,50.63 65.52,50.63 65.65,50.76 65.65,51.01 65.52,51.14 65.27,51.14 65.14,51.26 65.14,51.52 65.27,51.65 65.52,51.65 65.65,51.77 65.65,52.03 65.52,52.15 65.27,52.15 65.14,52.28 65.14,52.53 65.27,52.66 65.52,52.66 65.65,52.79 65.65,53.04 65.52,53.17 65.27,53.17 65.14,53.3 65.14,53.55 65.27,53.68 65.52,53.68 65.65,53.8 65.65,54.06 65.52,54.19 65.27,54.19 65.14,54.31 65.14,54.57 65.27,54.69 65.52,54.69 65.65,54.82 65.65,55.07 65.52,55.2 65.27,55.2 65.14,55.33 65.14,55.84 64.84,56.14 64.84,58.15 63.11,59.87 63.11,60.36 61.26,62.21 60.98,62.21 60.22,62.97 58.67,62.97 55.87,65.77 54.48,65.77
  BOTTOM w0.127: U20.AL18 52.71,70.54 52.66,70.54 v2(52.59,70.47) ; JDIM1.191 64.85,36.34 v3(65.81,35.37)
M_B_DQ60: length 52.3
  IN1 w0.076: v2(52.67,71.89) 52.67,71.51 53.33,70.85 53.33,69.77 53.68,69.42 53.68,67.02 54.45,66.25
  IN1 w0.127: v3(66.37,33.84) 67.05,34.52 67.05,41.03 66.36,41.72 66.36,42.08 66.49,42.2 66.69,42.2 66.82,42.33 66.82,42.58 66.69,42.71 66.49,42.71 66.36,42.84 66.36,43.09 66.49,43.22 66.69,43.22 66.82,43.35 66.82,43.6 66.69,43.73 66.49,43.73 66.36,43.85 66.36,55.68 65.55,56.49 65.55,58.44 63.75,60.24 63.75,60.41 61.47,62.68 61.12,62.68 60.39,63.4 58.89,63.4 56.05,66.25 54.45,66.25
  BOTTOM w0.127: v2(52.67,71.89) 52.23,71.45 U20.AK20 ; JDIM1.193 65.45,36.38 66.37,35.46 v3(66.37,33.84)
M_B_DQ61: length 51.8
  IN1 w0.076: v2(51.63,70.48) 52.02,70.87 52.77,70.87 53.15,70.49 53.15,69.7 53.5,69.35 53.5,66.93 54.41,66.02
  IN1 w0.127: v3(65.81,31.05) 65.81,33.92 66.58,34.69 66.58,41 66.01,41.57 66.01,55.48 65.19,56.29 65.19,58.29 63.47,60.02 63.47,60.36 61.36,62.46 61.03,62.46 60.31,63.19 58.78,63.19 55.95,66.02 54.41,66.02
  BOTTOM w0.127: v3(65.81,31.05) 65.15,30.39 JDIM1.192 ; v2(51.63,70.48) 51.96,70.15 U20.AM20
M_B_DQ62: length 48.3
  IN1 w0.076: 57.46,62.53 57.28,62.71 56.23,62.71 52.62,66.31 52.62,67.65 v2(52.42,67.85)
  IN1 w0.127: 57.46,62.53 57.52,62.46 57.52,61.57 58.7,60.39 61.07,60.39 61.26,60.2 61.26,59.63 62.49,58.4 62.49,55.87 62.87,55.49 62.87,54.99 63,54.86 63.16,54.86 63.29,54.74 63.29,54.48 63.16,54.36 63,54.36 62.87,54.23 62.87,53.98 63,53.85 63.16,53.85 63.29,53.72 63.29,53.47 63.16,53.34 63,53.34 62.87,53.21 62.87,52.96 63,52.83 63.16,52.83 63.29,52.71 63.29,52.45 63.16,52.32 63,52.32 62.87,52.2 62.87,51.94 63,51.82 63.16,51.82 63.29,51.69 63.29,51.44 63.16,51.31 63,51.31 62.87,51.18 62.87,50.93 63,50.8 63.16,50.8 63.29,50.67 63.29,50.42 63.16,50.29 63,50.29 62.87,50.17 62.87,49.91 63,49.78 63.16,49.78 63.29,49.66 63.29,49.4 63.16,49.28 63,49.28 62.87,49.15 62.87,48.9 63,48.77 63.16,48.77 63.29,48.64 63.29,48.39 63.16,48.26 63,48.26 62.87,48.13 62.87,47.88 63,47.75 63.16,47.75 63.29,47.63 63.29,47.37 63.16,47.24 63,47.24 62.87,47.12 62.87,46.86 63,46.74 63.16,46.74 63.29,46.61 63.29,46.36 63.16,46.23 63,46.23 62.87,46.1 62.87,45.85 63,45.72 63.16,45.72 63.29,45.59 63.29,45.34 63.16,45.21 63,45.21 62.87,45.09 62.87,44.83 63,44.7 63.16,44.7 63.29,44.58 63.29,44.32 63.16,44.2 63,44.2 62.87,44.07 62.87,43.82 63,43.69 63.16,43.69 63.29,43.56 63.29,43.31 63.16,43.18 63,43.18 62.87,43.05 62.87,42.11 63.27,41.72 63.27,36.38 v3(63.74,35.9)
  BOTTOM w0.127: v3(63.74,35.9) 62.9,35.9 62.45,36.35 JDIM1.183 ; U20.AR18 52.62,67.85 v2(52.42,67.85)
M_B_DQ63: length 49.1
  IN1 w0.076: 57.73,62.67 57.52,62.87 56.31,62.87 52.82,66.36 52.82,68.3 v2(52.59,68.52)
  IN1 w0.127: 57.73,62.67 58.18,62.21 59.46,62.21 60.38,61.3 61,61.3 61.26,61.04 61.26,60.76 61.64,60.38 61.64,59.75 62.87,58.51 62.87,58.02 63,57.89 63.21,57.89 63.34,57.77 63.34,57.51 63.21,57.38 63,57.38 62.87,57.26 62.87,57 63,56.88 63.21,56.88 63.34,56.75 63.34,56.5 63.21,56.37 63,56.37 62.87,56.24 62.87,55.99 63.64,55.21 63.64,40.72 64.38,39.98 64.38,38.73 64.26,38.61 63.75,38.61 63.62,38.48 63.62,38.23 63.75,38.1 64.26,38.1 64.38,37.97 64.38,37.72 64.26,37.59 63.75,37.59 63.62,37.46 63.62,37.21 63.75,37.08 64.26,37.08 64.38,36.96 64.38,34.88 63.98,34.48 v3(63.74,34.48)
  BOTTOM w0.127: v2(52.59,68.52) 52.79,68.72 52.84,68.72 U20.AP18 ; JDIM1.181 61.85,36.37 v3(63.74,34.48)
M_B_DQSN0: length 48.8
  IN1 w0.076: v2(26.97,69.79) 26.97,69.73 26.61,69.37 26.61,69.28 25.58,68.25 25.58,67.08 24.94,66.44 24.94,65.04 24.91,65
  IN1 w0.127: v3(13.28,34.7) 13.28,33.99 13.4,33.86 13.64,33.86 14.01,34.24 14.01,35.58 14.29,35.86 14.29,40.94 13.87,41.36 13.87,42.02 14.29,42.44 14.29,42.78 13.87,43.2 13.87,43.86 14.29,44.28 14.29,44.84 14.01,45.12 14.01,49.73 14.32,50.04 14.32,50.91 14.01,51.21 14.01,52.23 14.32,52.53 14.32,53.01 21.56,60.25 21.56,60.64 24.91,63.99 24.91,65
  BOTTOM w0.127: JDIM1.27 13.25,36.43 13.45,36.22 13.45,35.92 14.08,35.3 14.08,34.49 13.91,34.32 13.39,34.32 13.28,34.44 v3(13.28,34.7) ; U20.AM58 27.05,69.79 v2(26.97,69.79)
M_B_DQSN1: length 46.5
  IN1 w0.076: 29.17,67.29 29.2,67.32 29.2,69.45 29.01,69.63 29.01,70.13 29.22,70.34 29.61,70.34 v2(29.76,70.49)
  IN1 w0.127: 29.17,67.29 29.17,67 28.34,66.17 28.34,63.12 26.81,61.59 26.81,59.05 19.14,51.37 19.14,36.13 18.81,35.81 18.81,34.78 19.12,34.47 19.52,34.47 19.69,34.31 v3(19.69,34.04)
  BOTTOM w0.127: v2(29.76,70.49) 29.42,70.15 U20.AM55 ; v3(19.69,34.04) 19.69,34.31 19.55,34.45 19.27,34.45 18.65,35.07 JDIM1.45
M_B_DQSN2: length 70.6
  IN1 w0.076: v2(37.35,70.5) 36.97,70.87 36.97,71.05 36.82,71.2 36.82,71.52 35.14,73.19 30,73.19 29.34,72.53 26.06,72.53 24.28,70.75 24.05,70.75 23.54,70.24 23.54,70.21 23.52,70.19
  IN1 w0.127: 23.52,70.19 22.37,69.04 22.37,66.83 20.09,64.55 18.54,64.55 14.93,60.94 14.93,60.43 10.5,56 10.5,54.91 9.34,53.75 9.34,53.29 9.05,53.01 8.59,53.01 8.4,52.82 8.4,52.52 8.55,52.37 9.09,52.37 9.36,52.11 9.36,51.54 9.09,51.28 8.53,51.28 8.4,51.15 8.4,50.77 8.53,50.64 9.09,50.64 9.36,50.38 9.36,49.81 9.09,49.55 8.38,49.55 8.17,49.34 8.17,49.08 8.72,48.53 8.72,48.02 8.17,47.47 8.17,47.17 8.72,46.62 8.72,33.04 8.41,32.73 8.11,32.73 7.71,32.33 v3(7.71,31.66)
  BOTTOM w0.127: v2(37.35,70.5) 37.05,70.8 U20.AL43 ; v3(7.71,31.66) 8.16,31.66 8.53,31.29 8.53,30.78 8.15,30.39 JDIM1.10
M_B_DQSN3: length 48.8
  IN1 w0.076: 31.31,62.59 31.28,62.62 31.28,62.97 31.67,63.36 31.67,66.5 32.45,67.29 32.87,67.29 33.17,67.6 33.17,70.35 33.28,70.46 v2(33.57,70.46)
  IN1 w0.127: 31.31,62.59 31.31,60.69 31.08,60.46 31.08,56.96 24.19,50.07 24.19,46 24.66,45.54 24.66,33.88 23.83,33.05 23.61,33.05 23.41,32.85 23.41,32.52 23.61,32.32 24.07,32.32 24.3,32.54 v3(24.3,32.75)
  BOTTOM w0.127: v3(24.3,32.75) 23.85,32.31 23.85,31.34 23.63,31.13 23.63,30.47 23.75,30.36 JDIM1.62 ; U20.AL48 33.8,70.64 33.76,70.64 v2(33.57,70.46)
M_B_DQSN4: length 45.4
  IN1 w0.076: 45.43,65 45.4,65.04 45.4,65.57 45.24,65.73 45.24,67.93 45.61,68.3 45.61,69.11 45.7,69.2 v2(45.94,69.2)
  IN1 w0.127: v3(48.04,34.32) 48.04,34.49 48.22,34.67 48.55,34.67 48.93,35.05 48.93,36.4 49.3,36.78 49.3,47.44 49.43,47.57 49.77,47.57 50.03,47.83 50.03,48.4 49.77,48.66 49.43,48.66 49.3,48.79 49.3,49.17 49.43,49.3 49.77,49.3 50.03,49.56 50.03,50.13 49.77,50.39 49.43,50.39 49.3,50.52 49.3,50.9 49.43,51.02 49.77,51.02 50.03,51.28 50.03,51.85 49.77,52.12 49.43,52.12 49.3,52.24 49.3,52.88 50.03,53.61 50.03,58.62 46.78,61.88 46.78,62.94 45.43,64.29 45.43,65
  BOTTOM w0.127: v3(48.04,34.32) 48.04,34.33 47.59,34.78 47.59,35.8 48.05,36.25 JDIM1.135 ; U20.AN28 46.11,69.2 v2(45.94,69.2)
M_B_DQSN5: length 48
  IN1 w0.076: v2(47.8,69.74) 47.8,69.86 48.06,70.12 48.19,70.12 48.32,69.99 48.32,68.48 48.18,68.34 48.18,65.37 48.93,64.63 48.93,63.84 49.68,63.09 49.68,62.25 49.97,61.96 49.97,61.89
  IN1 w0.127: v3(53.74,30.97) 53.74,31.65 53.64,31.76 52.54,31.76 52.32,31.98 52.32,33.22 53.59,34.5 53.59,42.4 54.78,43.58 54.78,56.85 53.1,58.53 53.1,58.76 49.97,61.89
  BOTTOM w0.127: v2(47.8,69.74) 47.96,69.9 48.11,69.9 48.31,69.7 U20.AN25 ; v3(53.74,30.97) 53.84,30.87 53.84,30.7 53.56,30.42 53.22,30.42 53.15,30.35 JDIM1.152
M_B_DQSN6: length 45.4
  IN1 w0.076: 56.16,60.29 56.15,60.3 56.11,60.3 55.75,60.66 55.75,61.3 53.06,63.99 52.19,63.99 51.81,64.37 51.81,64.88 50.44,66.25 50.44,66.95 50.53,67.04 50.53,68.1 50.26,68.36 50.26,68.71 50.43,68.87 50.43,69.07 50.54,69.18 v2(50.66,69.18)
  IN1 w0.127: 56.16,60.29 59.29,57.16 59.29,54.25 59.68,53.85 59.68,53.28 59.29,52.89 59.29,52.52 59.68,52.13 59.68,51.55 59.29,51.16 59.29,41.62 59.12,41.46 59.12,38.52 60.11,37.53 60.11,35.14 59.83,34.85 59.38,34.85 59.24,34.72 v3(59.24,34.3)
  BOTTOM w0.127: v3(59.24,34.3) 59.24,34.78 59.11,34.9 58.92,34.9 58.49,35.34 58.49,36.05 58.25,36.29 JDIM1.169 ; v2(50.66,69.18) 50.98,69.5 U20.AN21
M_B_DQSN7: length 50
  IN1 w0.076: v2(52.59,69.17) 52.67,69.25 52.87,69.25 52.99,69.13 52.99,66.46 54.2,65.26 54.27,65.26 55.16,64.37 55.16,64.32 55.18,64.31
  IN1 w0.127: 55.18,64.31 56.36,63.12 57.62,63.12 58.23,62.51 60.02,62.51 60.93,61.6 61.16,61.6 62.65,60.11 62.65,59.4 63.97,58.08 63.97,55.78 64.28,55.48 64.28,42.87 64.54,42.61 64.66,42.61 64.79,42.48 64.79,42.1 64.66,41.97 64.54,41.97 64.28,41.71 64.28,40.98 65.02,40.24 65.02,34.47 64.79,34.24 64.79,32.21 64.55,31.97 64.27,31.97 64.05,32.19 v3(64.05,32.32)
  BOTTOM w0.127: v2(52.59,69.17) 52.78,69.36 52.82,69.36 U20.AN18 ; JDIM1.186 63.35,30.14 63.57,30.36 63.57,31.84 v3(64.05,32.32)
M_B_DQSP0: length 48.6
  IN1 w0.076: 25.14,65 25.11,65.04 25.11,66.37 25.75,67.01 25.75,68.18 26.78,69.21 26.97,69.21 v2(26.99,69.18)
  IN1 w0.127: v3(13.28,33.43) 13.48,33.63 13.73,33.63 14.24,34.14 14.24,35.49 14.52,35.77 14.52,41.03 14.1,41.45 14.1,41.92 14.52,42.34 14.52,42.87 14.1,43.29 14.1,43.76 14.52,44.18 14.52,44.94 14.24,45.22 14.24,49.64 14.55,49.94 14.55,51 14.24,51.31 14.24,52.13 14.55,52.44 14.55,52.91 21.79,60.15 21.79,60.54 25.14,63.89 25.14,65
  BOTTOM w0.127: U20.AN58 27.09,69.18 v2(26.99,69.18) ; v3(13.28,33.43) 13.28,33.97 13.42,34.1 14,34.1 14.29,34.4 14.29,35.39 13.67,36.01 13.67,36.26 13.85,36.44 JDIM1.29
M_B_DQSP1: length 46.2
  IN1 w0.076: v2(29.76,69.85) 29.43,70.17 29.29,70.17 29.18,70.06 29.18,69.7 29.36,69.52 29.36,67.32 29.4,67.29
  IN1 w0.127: v3(19.69,35.32) 19.69,34.84 19.55,34.7 19.22,34.7 19.04,34.88 19.04,35.72 19.36,36.04 19.36,51.28 27.04,58.96 27.04,61.5 28.57,63.02 28.57,66.08 29.4,66.91 29.4,67.29
  BOTTOM w0.127: U20.AN55 29.36,69.61 29.51,69.61 v2(29.76,69.85) ; v3(19.69,35.32) 19.69,34.8 19.55,34.66 19.36,34.66 18.87,35.16 18.87,36.13 19.25,36.51 JDIM1.47
M_B_DQSP2: length 70.5
  IN1 w0.076: 23.36,70.36 23.37,70.37 23.41,70.37 23.97,70.93 24.21,70.93 25.99,72.71 29.26,72.71 29.92,73.37 35.22,73.37 37,71.59 37,71.28 37.1,71.17 v2(37.35,71.17)
  IN1 w0.127: 23.36,70.36 22.14,69.14 22.14,66.92 20,64.78 18.44,64.78 14.7,61.04 14.7,60.52 10.27,56.09 10.27,55 9.11,53.85 9.11,53.39 8.95,53.23 8.5,53.23 8.17,52.91 8.17,52.43 8.46,52.14 9,52.14 9.13,52.01 9.13,51.63 9,51.51 8.43,51.51 8.17,51.25 8.17,50.68 8.43,50.41 9,50.41 9.13,50.29 9.13,49.91 9,49.78 8.29,49.78 7.94,49.43 7.94,48.98 8.49,48.44 8.49,48.11 7.94,47.56 7.94,47.08 8.49,46.53 8.49,33.14 8.31,32.96 v3(7.71,32.96)
  BOTTOM w0.127: JDIM1.12 8.75,31.38 7.71,32.42 v3(7.71,32.96) ; U20.AL42 37.72,70.8 v2(37.35,71.17)
M_B_DQSP3: length 48.2
  IN1 w0.076: v2(32.62,70.47) 32.87,70.47 33.01,70.34 33.01,67.67 32.8,67.46 32.38,67.46 31.5,66.57 31.5,63.43 31.11,63.04 31.11,62.62 31.08,62.59
  IN1 w0.127: 31.08,62.59 31.08,60.79 30.85,60.56 30.85,57.05 23.97,50.17 23.97,45.91 24.43,45.44 24.43,33.97 23.74,33.28 23.52,33.28 23.18,32.95 23.18,32.42 23.51,32.09 24.12,32.09 24.3,31.91 v3(24.3,31.48)
  BOTTOM w0.127: v3(24.3,31.48) 23.85,31.03 23.85,30.56 24.35,30.06 JDIM1.64 ; U20.AL49 32.93,70.67 32.81,70.67 v2(32.62,70.47)
M_B_DQSP4: length 45.1
  IN1 w0.076: 45.2,65 45.24,65.04 45.24,65.5 45.07,65.66 45.07,68 45.44,68.37 45.44,69.18 45.53,69.27 45.53,69.4 46,69.86 v2(46,70.47)
  IN1 w0.127: v3(48.04,35.6) 48.04,35.08 48.23,34.9 48.46,34.9 48.7,35.14 48.7,36.5 49.07,36.87 49.07,47.54 49.33,47.8 49.67,47.8 49.8,47.92 49.8,48.31 49.67,48.43 49.33,48.43 49.07,48.69 49.07,49.26 49.33,49.52 49.67,49.52 49.8,49.65 49.8,50.03 49.67,50.16 49.33,50.16 49.07,50.42 49.07,50.99 49.33,51.25 49.67,51.25 49.8,51.38 49.8,51.76 49.67,51.89 49.33,51.89 49.07,52.15 49.07,52.97 49.8,53.7 49.8,58.53 46.55,61.78 46.55,62.85 45.2,64.2 45.2,65
  BOTTOM w0.127: v3(48.04,35.6) 48.04,35.94 48.65,36.55 JDIM1.137 ; v2(46,70.47) 46.32,70.15 U20.AM28
M_B_DQSP5: length 48.1
  IN1 w0.076: v2(47.8,70.42) 47.93,70.29 48.25,70.29 48.49,70.06 48.49,68.41 48.35,68.28 48.35,65.44 49.09,64.7 49.09,63.91 49.84,63.16 49.84,62.32 50.17,61.99 50.19,61.99
  IN1 w0.127: 50.19,61.99 53.33,58.85 53.33,58.62 55.01,56.95 55.01,43.49 53.82,42.3 53.82,34.41 52.54,33.13 52.54,32.08 52.64,31.98 53.48,31.98 v3(53.74,32.24)
  BOTTOM w0.127: JDIM1.154 53.75,30.28 54.2,30.73 54.2,31.15 53.74,31.6 v3(53.74,32.24) ; v2(47.8,70.42) 48.01,70.21 48.25,70.21 U20.AM25
M_B_DQSP6: length 45.3
  IN1 w0.076: 56,60.12 55.99,60.14 55.99,60.18 55.94,60.23 55.58,60.59 55.58,61.23 52.99,63.82 52.12,63.82 51.64,64.3 51.64,64.81 50.27,66.18 50.27,67.02 50.36,67.11 50.36,68.03 50.1,68.29 50.1,68.77 50.27,68.94 50.27,69.36 50.65,69.74 v2(50.65,69.86)
  IN1 w0.127: 56,60.12 59.06,57.07 59.06,54.15 59.45,53.76 59.45,53.38 59.06,52.98 59.06,52.42 59.45,52.03 59.45,51.65 59.06,51.26 59.06,41.72 58.89,41.55 58.89,38.42 59.89,37.43 59.89,35.24 59.73,35.08 59.39,35.08 59.24,35.24 v3(59.24,35.57)
  BOTTOM w0.127: v2(50.65,69.86) 50.83,70.03 50.95,70.03 U20.AM21 ; JDIM1.171 58.85,36.17 58.7,36.02 58.7,35.43 59.01,35.12 59.34,35.12 59.43,35.21 59.43,35.38 v3(59.24,35.57)
M_B_DQSP7: length 49.9
  IN1 w0.076: 55.34,64.47 55.33,64.48 55.28,64.48 54.34,65.42 54.26,65.42 53.15,66.53 53.15,69.19 52.59,69.76 v2(52.59,69.82)
  IN1 w0.127: 55.34,64.47 56.46,63.35 57.72,63.35 58.33,62.74 60.11,62.74 61.03,61.83 61.28,61.83 62.88,60.22 62.88,59.49 64.2,58.17 64.2,55.88 64.51,55.57 64.51,42.96 64.64,42.83 64.76,42.83 65.02,42.57 65.02,42 64.76,41.74 64.64,41.74 64.51,41.62 64.51,41.07 65.25,40.34 65.25,34.37 65.02,34.14 65.02,32.11 64.65,31.74 64.23,31.74 64.05,31.56 v3(64.05,31.05)
  BOTTOM w0.127: JDIM1.188 63.95,30.21 63.78,30.37 63.78,30.79 v3(64.05,31.05) ; U20.AM18 52.82,70 52.77,70 v2(52.59,69.82)
M_B_ODT0: length 3.7
  BOTTOM w0.127: v2(40.25,27.03) 40.28,27.06 R460.2 41.39,27.15 42.35,28.11 JDIM1.116
M_B_ODT1: length 2.4
  BOTTOM w0.127: JDIM1.120 43.55,28.17 44.2,27.52 R459.2
M_B_RAS#: length 57.2
  IN1 w0.076: v2(41.67,69.8) 41.59,69.88 41.34,69.88 41.28,69.82 41.28,68.43 41.3,68.41 41.3,67.48 41.46,67.32 41.46,63.13 41.98,62.62 41.98,62.46
  IN1 w0.203: 41.98,62.46 41.98,60.8 44.11,58.67 44.11,49.92 43.93,49.73 43.41,49.73 42.98,49.3 42.98,42.29 42.82,42.14 42.18,42.14 42.02,41.98 42.02,38.25 41.55,37.77 41.55,37.51 42.02,37.03 42.02,35.6 42.18,35.45 42.33,35.45 42.49,35.29 42.49,34.98 42.33,34.83 42.18,34.83 42.02,34.68 42.02,34.37 42.18,34.22 42.33,34.22 42.49,34.07 42.49,33.76 42.33,33.61 41.85,33.61 41.7,33.46 41.7,33.12 41.85,32.97 42.36,32.97 42.51,32.82 42.51,32.37 42.36,32.22 42.13,32.22 41.98,32.07 41.98,31.55 42.13,31.4 42.13,30.36 42.28,30.21 44.75,30.21 44.9,30.06 44.9,29.76 44.75,29.6 41.67,29.6 41.52,29.76 v3(41.52,31.2)
  BOTTOM w0.191: U20.AM35 41.98,70.04 41.91,70.04 v2(41.67,69.8) ; JDIM1.110 40.55,30.26 40.43,30.38 40.43,30.87 40.58,31.02 40.99,31.02 41.24,31.27 41.44,31.27 v3(41.52,31.2)
M_B_WE#: length 57.5
  IN1 w0.076: v2(41.66,71.15) 42.05,71.15 42.36,71.46 42.84,71.46 43.04,71.25 43.04,68.2 42.82,67.97 42.82,62.72 42.94,62.59 42.94,62.46
  IN1 w0.203: v3(42.97,33.1) 42.97,32.18 42.59,31.8 42.59,31.61 42.73,31.48 43.58,31.48 43.98,31.88 43.98,32.79 44.49,33.29 44.49,38.13 45.23,38.87 45.23,41.08 45.48,41.33 45.48,58.59 42.94,61.13 42.94,62.46
  BOTTOM w0.191: v3(42.97,33.1) 42.97,32.73 43.12,32.58 44.34,32.58 44.49,32.43 44.49,32.14 44.34,31.98 42.97,31.98 42.77,32.19 42.56,32.19 42.36,31.98 42.16,31.98 42.05,32.09 42.05,32.78 42.46,33.18 42.46,33.81 41.45,34.82 JDIM1.113 ; U20.AK35 41.79,71.15 v2(41.66,71.15)
MAG_DRDY: length 24.7
  TOP w0.127: U1.9 228.65,119.92 228.9,120.17 229.94,120.17 230.17,119.94 230.17,118.75 230.93,117.99 v1(230.93,114.05) 230.93,113.09 233.39,110.62 233.39,109.73 235.12,108.01 v2(235.6,108.01)
  BOTTOM w0.127: v2(235.6,108.01) 233.9,106.3 233.9,105.44 235.56,103.78 U5.35
MAIND: length 33.2
  IN2 w0.127: v2(112.72,100.77) 112.72,100.54 113.64,99.61 123.82,99.61 124.9,98.53 131.46,98.53 132.61,97.39 135.42,97.39 136.35,98.32 v2(136.35,98.81)
  BOTTOM w0.127: v2(112.72,100.77) 112.72,100.79 111.99,101.52 PU6.10
  BOTTOM w0.254: PQ11.4 138.85,95.32 PC116.1 138.56,95.73 v4(137.76,96.53) 137.41,96.88 137.41,97.76 v2(136.35,98.81)
MAIND3.3V: length 20.7
  IN2 w0.508: v2(112.13,100.49) 111.93,100.49 110.01,98.57 103.23,98.57 102.19,97.53 102.19,97.53 101.77,97.11 v2(99.56,97.11)
  BOTTOM w0.203: PU6.12 110.6,100.39 110.79,100.21 111.6,100.21 111.88,100.49 v2(112.13,100.49)
  BOTTOM w0.381: PQ10.4 96.4,96.54 PC114.1 97,96.28 v4(97.6,96.88) 97.83,97.11 v2(99.56,97.11)
MAINON: length 398
  TOP w0.127: v2(124.03,97.64) 123.46,97.07 123.46,95.46 122.27,94.26 119.79,94.26 117.97,92.44 117.97,91.97 v1(117.18,91.18) v2(115.89,89.9)
  IN2 w0.127: v2(124.03,97.64) 124.26,97.87 131.19,97.87 132.31,96.75 136.01,96.75 137.72,98.47 143.73,98.47 144.3,97.9 152.32,97.9 157.65,92.56 164.9,92.56 166.9,92.56 167.79,91.67 174.38,91.67 174.63,91.92 175.09,91.92 175.44,91.92 179.44,95.93 179.44,99.24 180.36,100.16 184.12,100.16 185.06,101.1 189.25,101.1 190.4,102.24 191.32,102.24 192.62,103.54 192.93,103.54 193.25,103.54 193.31,103.54 193.77,103.99 195.67,103.99 195.92,104.24 195.94,104.24 196.26,104.24 196.49,104.24 197.78,105.53 198.18,105.53 199.82,105.53 202.82,105.53 203.34,106.05 205.27,106.05 205.65,106.44 210.58,106.44 211.2,105.82 212.65,105.82 214.5,103.97 214.83,103.97 215.74,103.05 216.43,103.05 v2(216.45,103.08) ; v2(121.63,111.92) 121.3,112.25 117.44,112.25 116.76,111.56 106.98,111.56 106.3,112.24 106.3,112.25 105.78,112.76 105.78,112.98 105.48,113.29 100.04,113.29 96.97,116.36 91,116.36 88.99,118.37 87.6,118.37 87.5,118.27 77.91,118.27 77.35,117.71 75.71,117.71 v2(75.53,117.89) ; v2(10.94,15.04) 10.3,14.41 10.3,13.57 10.91,12.97 15.62,12.97 16.23,13.58 25.24,13.58 26.32,14.66 29.64,14.66 31.48,16.5 37.67,16.5 38.13,16.96 49.32,16.96 54.31,21.95 63.46,21.95 64.11,22.6 64.11,23.71 67.05,26.65 67.8,26.65 68.38,27.23 68.38,27.52 71.27,30.41 71.7,30.41 73.65,32.36 73.65,40.24 72.45,41.45 72.45,44.37 73.26,45.18 76.17,45.18 77.12,46.13 77.12,48.53 77.97,49.38 77.97,60.63 77.97,60.94 78.71,61.68 78.71,62.62 78.15,63.18 78.15,70.9 86.82,79.57 92.74,79.57 94.43,81.26 102.78,81.26 105.22,78.82 113.56,78.82 114.09,79.35 117.01,79.35 v2(117.47,78.9)
  BOTTOM w0.127: U7.99 216.7,91.38 215.05,93.02 215.05,94.62 214.79,94.89 214.79,96.34 214.79,96.34 214.79,100.34 216.1,101.65 216.1,102.72 v2(216.45,103.08) ; v2(115.89,89.9) 115.89,89.69 115.54,89.34 115.54,85.18 117.47,83.25 v2(117.47,78.9) ; v2(10.94,15.04) 10.94,15.36 PR129.2 ; v2(124.03,97.64) 123.55,97.16 123.06,97.16 122.9,97.31 122.9,98.42 119.14,102.18 119.14,105.95 118.23,106.86
  BOTTOM w0.203: v2(75.53,117.89) 75.77,117.89 PR4.2 ; 110.48,104.5 109.97,104.5 109.8,104.33 PU6.2 ; 110.48,104.5 110.6,104.38 PU6.4 ; 110.48,104.5 110.6,104.62 112.07,104.62 114.93,107.47 117.62,107.47 118.23,106.86 118.38,107.02 118.97,107.02 119.42,107.47 119.42,108.59 119.68,108.84 120.44,108.84 121.43,107.85 123.06,107.85 PR35.2
  BOTTOM w0.254: PR35.2 123.43,108.39 122.67,108.39 121.63,109.43 v2(121.63,111.92)
MBATLED0#: length 62.5
  IN2 w0.127: v2(212.67,100.38) 213.13,100.38 214.05,99.46 219.33,99.46 220.69,100.82 225.49,100.82 226.61,101.94 229.71,101.94 233.14,98.51 233.14,94.62 234.23,93.53 234.23,89.72 235.04,88.91 v2(236.49,88.91)
  BOTTOM w0.127: R222.2 214.72,88.1 v2(214.72,88.75) 214.72,88.78 214.3,89.21 U7.105 214.3,91.47 213.86,91.9 213.86,93.8 213.23,94.44 213.23,99.45 212.67,100.01 v2(212.67,100.38) ; CN6.12 246.25,86.7 244.9,85.35 243.45,85.35 242.54,86.26 241.03,86.26 237.86,89.44 237.02,89.44 v2(236.49,88.91)
MBCLK: length 106.1
  TOP w0.127: v3(222.04,98.68) 222.04,98.91 221.63,99.32 220.62,99.32 218.89,97.59 211.17,97.59 210.81,97.95 210.43,97.95 208.43,99.95 206.89,99.95 205.6,101.25 199.22,101.25 197.65,102.82 195.29,102.82 195.1,102.82 192.28,100.01 190.83,100.01 190.64,100.01 189.63,98.99 188.47,98.99 177.56,88.09 173.25,88.09 172.99,87.83 172.99,87.56 v2(172.71,87.28)
  IN1 w0.114: v2(173.73,104.4) 173.73,103.87 173.51,103.65 172.93,103.65 172.12,104.46 167.34,104.46 166.53,103.65 165.31,103.65 165.16,103.8 165.16,103.96 v2(165.37,104.17)
  BOTTOM w0.127: v2(173.73,104.4) 174.17,103.95 174.17,97.93 174.45,97.66 175.62,97.66 175.79,97.5 175.79,95.34 176.14,94.98 176.14,91.36 175.92,91.14 174.65,91.14 174.11,90.6 174.11,90.32 173.65,89.87 PD8.1 173.35,89.36 173.71,89 173.71,88.82 172.75,87.86 PC136.1 172.71,87.49 v2(172.71,87.28) 172.71,86.86 PR121.2 ; U7.77 219.98,99.76 220.08,99.65 221.53,99.65 222.04,99.14 v3(222.04,98.68) 222.04,98.37 222.39,98.02 222.39,95.18 222.6,94.98 222.72,94.98 222.84,95.09 C112.1 R107.2 ; v2(165.37,104.17) 165.16,103.95 165.16,103.2 164.89,102.93 164.89,100.51 165.22,100.18 165.22,99.94 PR95.2
MBCLK2: length 277.8
  IN1 w0.114: v2(76.85,60.05) 77.17,60.05 77.3,60.18 77.3,61.4 76.74,61.96 76.74,64.2 77.56,65.03 77.56,71.86 87.79,82.09 87.79,83.64 89.44,85.29 91.9,85.29 92.75,84.43 93.41,84.43 v2(93.72,84.74) 93.97,84.74 94.4,84.31 94.4,83.9 96.93,81.37 111.74,81.37 112.97,82.61 126.89,82.61 130.44,79.06 155.46,79.06 157.8,76.71 185.14,76.71 189.34,80.91 189.34,84.47 190.02,85.16 190.86,85.16 191.31,85.61 191.31,86.78 193.56,89.03 194.66,89.03 195.37,89.74 196.15,90.52 196.56,90.52 196.82,90.79 197.87,90.79 198.05,90.79 198.7,90.14 202.8,90.14 202.86,90.2 207.23,90.2 207.54,89.9 213.61,89.9 215.13,91.42 217.9,91.42 218.91,92.44 219.85,92.44 219.99,92.57 221.26,92.57 221.63,92.94 225.24,92.94 v2(225.52,93.22) 225.8,92.94 226.53,92.94 227.35,93.76 228.16,93.76 231.15,90.77 231.65,90.77 232.54,89.88 232.54,88.92 233.62,87.84 233.98,87.84 234.41,87.41 234.41,86.42 234.94,85.88 235.45,85.88 235.96,85.38 235.96,84.79 236.16,84.59 236.54,84.59 236.62,84.66 236.62,84.84 v2(236.42,85.04)
  BOTTOM w0.127: U21.8 79.83,55.88 78.48,57.23 78.48,58.78 77.41,59.85 77.06,59.85 v2(76.85,60.05) ; R132.2 224.39,92.95 224.38,92.94 ; R485.2 79.81,85.28 ; 79.81,85.28 79.66,85.13 78.74,85.13 78.14,84.53 78.14,82.59 78.68,82.05 79.66,82.05 79.97,81.74 79.97,81.68 80.04,81.6 Q21.4 ; 79.81,85.28 79.95,85.15 80.66,85.15 80.97,84.84 81.68,84.84 84.7,87.86 86,87.86 87.67,86.19 91.94,86.19 92.7,85.43 92.7,85.43 93.39,84.74 v2(93.72,84.74) 93.72,85.15 92.2,86.66 R235.2 ; v2(225.52,93.22) 225.24,92.94 224.38,92.94 ; CN11.10 263.66,73.75 263.64,73.77 247.02,73.77 242.42,78.36 241.65,79.13 236.69,84.07 236.69,84.77 v2(236.42,85.04) ; 224.38,92.94 222.93,92.94 222.84,93.03 C134.1 222.71,93.2 222.52,93.2 222.45,93.27 222.45,94.28 221.66,95.07 221.66,97.69 220.52,98.84 220.08,98.84 219.96,98.96 U7.79
MBDATA: length 106.4
  TOP w0.127: v3(173.35,87.28) 173.22,87.41 173.22,87.74 173.34,87.86 177.66,87.86 188.56,98.76 189.72,98.76 190.74,99.78 192.37,99.78 195.19,102.6 197.55,102.6 199.13,101.02 205.5,101.02 206.8,99.73 208.33,99.73 209.7,98.36 210.33,97.72 210.71,97.72 210.94,97.5 211.07,97.36 218.98,97.36 220.69,99.07 221.23,99.07 221.4,98.89 v2(221.4,98.68)
  IN1 w0.114: v2(174.24,104.78) 174.24,104.25 173.94,103.95 173.94,103.78 173.6,103.43 172.84,103.43 172.03,104.25 167.43,104.25 166.62,103.43 165.22,103.43 164.95,103.71 164.95,103.96 v2(164.74,104.17)
  BOTTOM w0.127: v2(174.24,104.78) 174.4,104.62 174.4,98.03 174.54,97.89 175.72,97.89 176.01,97.59 176.01,95.46 176.37,95.1 176.37,91.27 176.01,90.91 174.74,90.91 174.34,90.5 174.34,90.32 174.8,89.87 PD7.1 175.25,89.51 174.74,89.01 174.21,89.01 173.6,88.39 173.6,87.98 PC135.1 173.35,87.49 v3(173.35,87.28) 173.35,86.86 PR120.2 ; v2(164.74,104.17) 164.93,103.98 164.93,103.29 164.66,103.03 164.66,100.42 164.99,100.09 164.99,99.96 PR96.2 ; R125.2 C119.1 222.69,94.75 222.5,94.75 222.17,95.08 222.17,97.92 v2(221.4,98.68) 221.4,99.34 221.33,99.42 220.08,99.42 220.02,99.36 U7.78
MBDATA2: length 273.5
  IN1 w0.114: v2(76.83,59.42) 76.84,59.42 77.51,60.09 77.51,61.49 76.95,62.05 76.95,64.11 77.78,64.94 77.78,71.77 88,82 88,83.55 89.53,85.07 91.81,85.07 92.66,84.22 93.86,84.22 v2(93.95,84.13) 93.95,84.05 96.84,81.16 111.83,81.16 113.06,82.39 126.8,82.39 130.35,78.84 155.37,78.84 157.71,76.5 185.23,76.5 189.55,80.82 189.55,84.38 190.11,84.94 190.95,84.94 191.53,85.52 191.53,86.69 193.65,88.82 194.49,88.82 194.75,88.82 195.46,89.53 196.24,90.31 196.65,90.31 196.91,90.58 197.96,90.58 198.61,89.93 202.89,89.93 202.95,89.98 207.14,89.98 207.45,89.68 213.7,89.68 215.22,91.2 217.99,91.2 219,92.22 219.94,92.22 220.08,92.35 221.35,92.35 221.72,92.73 225.28,92.73 v2(225.52,92.49) 225.76,92.73 226.62,92.73 227.44,93.54 228.07,93.54 231.06,90.56 231.56,90.56 232.33,89.79 232.33,88.83 233.53,87.62 233.89,87.62 234.19,87.32 234.19,86.33 234.85,85.67 235.36,85.67 235.74,85.29 235.74,84.7 236.07,84.37 236.63,84.37 236.83,84.57 236.83,84.83 v2(237.05,85.04)
  BOTTOM w0.127: v2(237.05,85.04) 236.92,84.92 236.92,84.17 241.74,79.35 242.51,78.59 242.51,78.59 247.11,74 263.64,74 263.9,74.25 CN11.9 ; R482.2 79.81,84.61 ; 79.81,84.61 79.81,84.63 79.54,84.9 78.83,84.9 78.37,84.44 78.37,83.3 78.55,83.12 Q21.1 ; 79.81,84.61 80.11,84.91 80.47,84.91 80.76,84.61 81.77,84.61 84.8,87.64 85.9,87.64 87.58,85.96 91.84,85.96 93.67,84.13 v2(93.95,84.13) 94.16,84.35 94.16,85.13 93.51,85.78 R241.2 ; U21.7 79.18,56.2 78.25,57.14 78.25,58.69 77.32,59.62 77.03,59.62 v2(76.83,59.42) ; 224.4,92.71 224.39,92.7 R151.2 ; 224.4,92.71 222.97,92.71 222.84,92.58 C155.1 222.62,92.55 222.62,92.77 222.36,93.04 222.22,93.18 222.22,94.19 221.43,94.98 221.43,97.6 220.42,98.61 220.08,98.61 220.03,98.56 U7.80 ; 224.4,92.71 225.29,92.71 v2(225.52,92.49)
MINICAR_PME#: length 19.3
  BOTTOM w0.127: CN5.1 264.14,84.83 263.49,84.18 261.69,84.18 261.23,84.64 261.23,88.58 260.72,89.08 v4(260.72,90.86) 260.72,94.2 R120.1 260.74,94.48 260.98,94.72 261.23,94.72 261.56,95.05 Q13.1 261,95.33 260.72,95.61 260.72,97.16 Q12.1
MPHY_PWREN: length 100.9
  TOP w0.127: v2(74.29,78.54) 74.36,78.54 75,79.18 75,79.69 76.07,80.75 76.07,80.98 v1(76.27,81.18) 76.53,81.18 77.25,81.9 77.25,81.91 77.45,82.11 77.45,82.11 77.84,82.5 78.46,82.5 80.38,84.42 80.38,84.92 81.53,86.07 81.53,87.95 83.43,89.85 83.86,89.85 83.86,89.85 84.99,89.85 85.6,90.45 86.26,90.45 87.56,91.75 90.53,91.75 102.81,91.75 104.48,90.09 114.71,90.09 115.03,90.4 115.57,90.4 115.72,90.56 115.73,90.56 116.55,91.37 116.55,91.39 119.68,94.52 122.16,94.52 123.18,95.54 123.18,97.43 v2(123.39,97.63)
  IN2 w0.127: v2(120.08,108.31) 119.25,109.15 v2(119.25,109.58)
  BOTTOM w0.076: 64.66,76.33 64.2,76.79 63.26,76.79 63.01,77.04 62.46,77.04 U20.Y2
  BOTTOM w0.127: v2(74.29,78.54) 74.29,78.47 74.69,78.06 74.69,77.58 73.6,76.48 72.48,76.48 72.18,76.18 71.34,76.18 71.07,76.46 70.1,76.46 69.99,76.56 69.64,76.56 68.89,75.81 R324.1 68.79,75.6 68.01,75.6 67.75,75.86 R321.1 67.68,75.91 65.64,75.91 65.22,76.33 64.66,76.33 ; v2(123.39,97.63) 123.39,98.3 119.4,102.29 119.4,106.81 120.08,107.5 v2(120.08,108.31)
  BOTTOM w0.254: v2(119.25,109.58) 119.11,109.44 117.58,109.44 115.97,107.83 114.78,107.83 112.29,105.34 PR51.2
MUTE_LED_CNTL: length 34.3
  TOP w0.127: v2(225.67,90.18) 225.85,90 v1(225.85,89.34) 225.85,88.68 230.6,83.93 v2(230.6,83.75)
  IN1 w0.127: v2(228.08,82.48) 227.25,82.48 226.92,82.15 224.88,82.15 224.32,82.71 223.36,82.71 223.13,82.48 219.78,82.48 v2(219.73,82.43)
  BOTTOM w0.127: R176.1 R161.2 ; R176.1 224.39,90.42 224.63,90.18 v2(225.67,90.18) ; R176.1 224.2,90.86 224.02,91.04 223.69,91.04 223.44,91.29 222.65,91.29 222.41,91.53 222.08,91.53 221.84,91.78 221.84,92.39 221.53,92.7 221.53,93.88 220.67,94.75 220.67,97.21 220.12,97.76 U7.82 ; v2(219.73,82.43) 219.44,82.72 U18.40 ; v2(230.6,83.75) 230.6,83.57 230.09,83.06 228.8,83.06 228.21,82.48 v2(228.08,82.48)
NB670BST_S: length 3.4
  BOTTOM w0.508: PC25.1 99.81,112.51 v4(99.81,113.77) 100.2,113.77 100.58,113.39 PR21.1
NB670EN: length 6.6
  BOTTOM w0.178: v4(107.56,112.12) 106.79,111.35 PR22.1 PC23.2 104.65,110.72 103.14,110.72 102.5,110.08 PU4.13
NB670ENLDO: length 5.8
  BOTTOM w0.102: PR23.1 104.5,111.35 104.77,111.61 v2(104.77,113.21)
  BOTTOM w0.178: PU4.12 102.1,110.33 PR24.2 PR23.1
NB670PG: length 2.8
  BOTTOM w0.178: PU4.4 102.5,106.06 102.94,105.62 v2(102.94,104.91) PR68.1
NB670VOUT: length 10.9
  BOTTOM w0.203: PU4.7 101.3,106.27 101.19,106.15 100.32,106.15
  BOTTOM w0.254: PR78.1 94.86,101.83 94.96,101.73 v2(95.12,101.73) 98.32,101.73 99.56,102.98 99.56,103.87 99.7,104 PC80.1 99.69,104.38 99.69,105.52 100.32,106.15
NB671BST:
  vias: v2(152.54,105.39)
NB671BST_S: length 2.3
  BOTTOM w0.508: 153.74,107.27 154.41,107.27 PC50.1 ; 153.74,107.27 v2(154.47,106.53) ; 153.74,107.27 PR43.1
NB671EN: length 7.4
  BOTTOM w0.178: PC73.2 146.69,104.78 149.17,104.78 149.65,105.26 150.03,105.26 150.21,105.45 PU5.13 ; PC73.2 v4(145.03,104.25) ; PC73.2 146.94,103.47 PR71.1
NB671FB: length 5.6
  BOTTOM w0.102: v2(149.85,102.34) 149.73,102.21 PR76.2
  BOTTOM w0.178: PR76.2 149.1,102.47 PR70.2 PR62.1 149.81,104.96 150.16,104.96 150.61,105.42 PU5.12
NB671PG: length 5.5
  BOTTOM w0.178: PU5.4 150.21,110.11 v2(150.11,110.22) 149.34,110.22 149.19,110.06 147.54,110.06 147.07,110.54 PR26.1
NB671SW:
  vias: v4(153.54,109.4)
NBSWON1#: length 120.9
  TOP w0.127: v2(222.01,90.58) 222.04,90.56 222.14,90.56 223.56,89.13 223.56,88.42 231.39,80.6 237.61,80.6 239.54,78.67 v2(240.07,78.67) 242.49,78.67 244.42,80.6 259.28,80.6 261.09,78.78 261.09,77.08 263.65,74.53 v1(276.45,74.53) 282.06,74.53 v2(282.31,74.78)
  IN2 w0.127: v2(222.01,90.58) 222.01,91.39 221.66,91.75 221.66,94.78 218.68,97.76 213.32,97.76 212.73,98.34 208.51,98.34 v2(208.4,98.23)
  BOTTOM w0.127: v2(282.31,74.78) 282.45,74.65 CN10.4 ; C230.1 236.45,83.33 240.07,79.71 v2(240.07,78.67) ; Q5.3 204.53,108.43 203.55,107.45 203.55,105.52 203.88,105.19 204.23,105.19 204.23,105.19 204.44,105.19 205.78,103.84 205.78,103.67 205.78,102.87 207.27,101.38 207.48,101.38 208.01,100.84 208.02,100.84 208.02,99.27 208.45,98.84 208.45,98.28 v2(208.4,98.23) 208.4,97.62 207.94,97.16 207.28,97.16 207.18,97.26 207.18,97.74 206.72,98.2 206.11,98.2 204.96,99.36 U7.19 202.54,99.36 202.25,99.07 202.25,98.66 202.15,98.56 R84.2
OS1_1: length 4.4
  BOTTOM w0.127: R147.2 227.08,92.09 227.22,91.95 228.54,91.95 228.71,91.79 R167.1 228.82,91.52 229.65,92.36 U12.4
OS2_1: length 3.2
  BOTTOM w0.127: R133.2 R134.1 236.45,92.88 236.31,92.74 235.68,92.74 235.63,92.69 235.17,92.69 234.84,92.36 U12.15
OVT_DETC: length 3.8
  BOTTOM w0.127: Q8.2 198.29,104.37 198.24,104.42 D4.2 197.48,104.88 197.72,105.12 R53.1 198.04,105.64 v1(198.21,105.47)
PCH_DISP_ON: length 78.8
  IN1 w0.127: v2(55.92,80.02) 55.73,79.82 51.87,79.82 51.3,79.26 51.3,76.21 51.09,76 50.11,76 49.34,76.77 45.63,76.77 44.4,75.54 40.4,75.54 39.92,75.06 38.72,75.06 37.97,75.81 35.06,75.81 v2(34.89,75.98)
  IN2 w0.127: v2(15.33,98.68) 16.58,99.93 19.04,99.93 19.68,99.29 19.68,98.28 20.08,97.87 22.37,97.87 23.33,96.91 23.33,94.21 21.96,92.84 21.96,90.21 22.27,89.9 22.27,86.55 24.58,84.24 24.58,82.83 25.21,82.2 26.71,82.2 28.16,80.75 33.19,80.75 33.62,80.32 v2(33.62,80.27) ; v2(59.76,85.53) 59.28,85.04 59.28,84.56 58.29,83.57 58.29,82.53 57.45,81.69 56.81,81.69 56.28,81.16 56.28,80.47 55.92,80.12 v2(55.92,80.02)
  BOTTOM w0.076: v2(59.76,85.53) 59.35,85.53 59.04,85.84 U20.C6
  BOTTOM w0.127: v4(15.33,99.73) v2(15.33,98.68) R91.2 15.02,98.06 14.72,98.36 U8.3 ; v2(33.62,80.27) 34.89,79 v2(34.89,75.98)
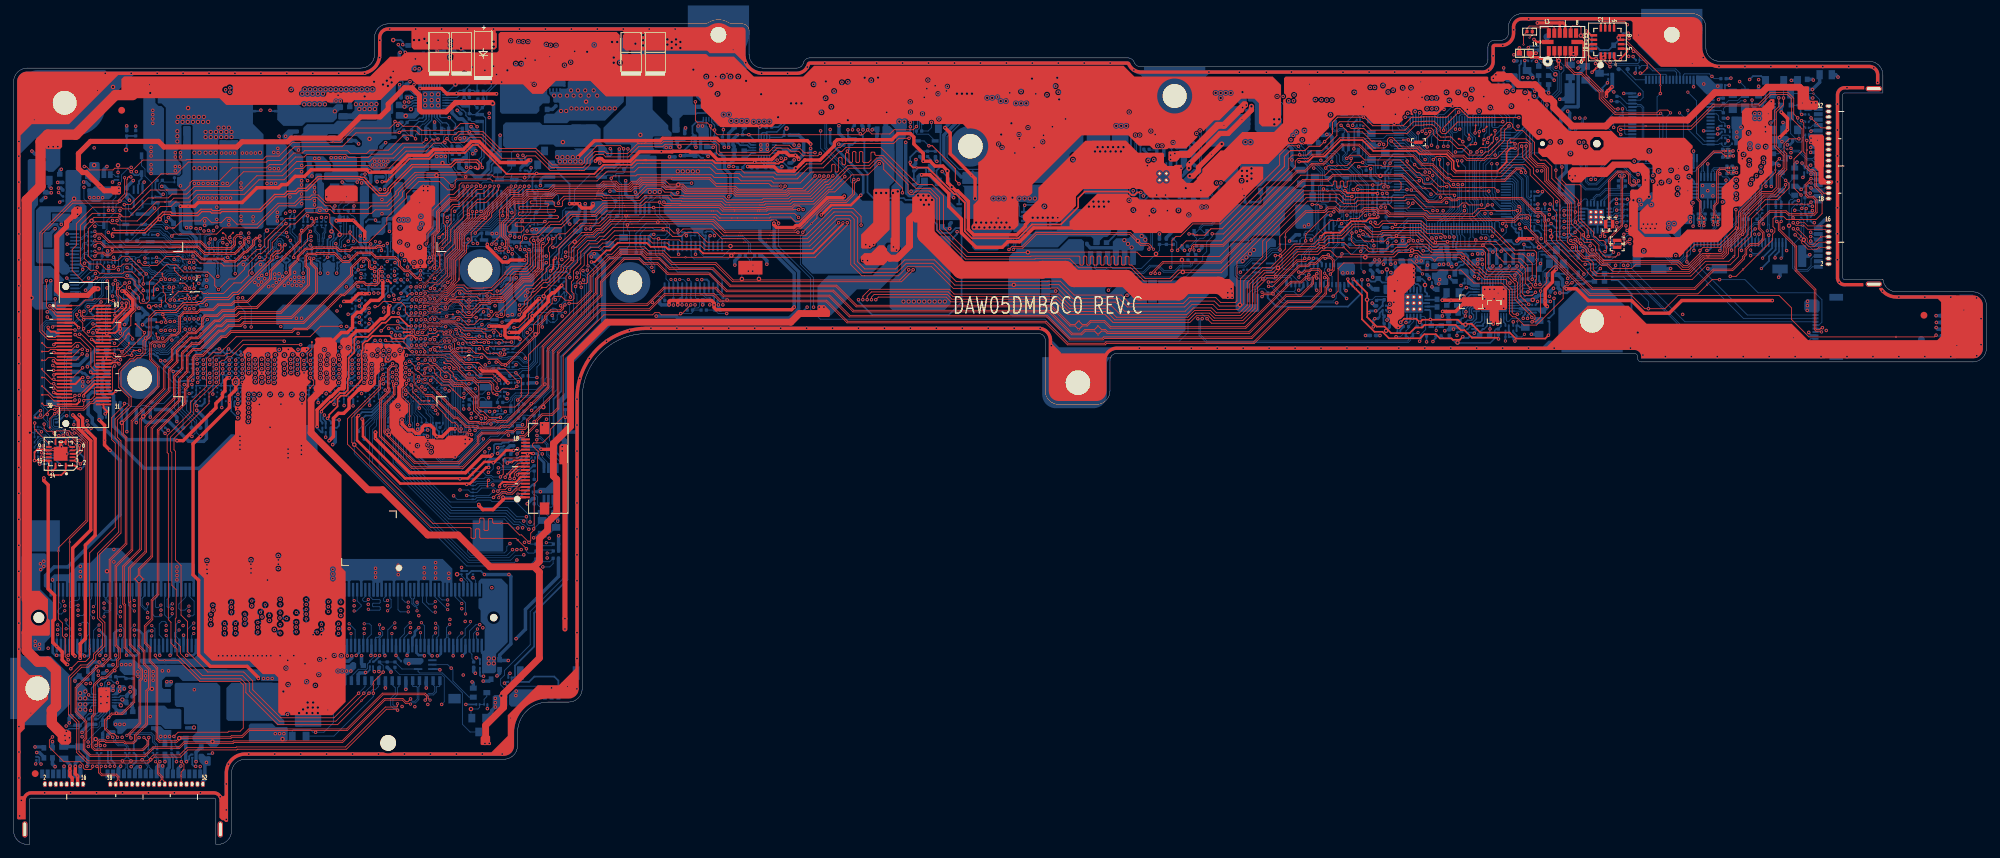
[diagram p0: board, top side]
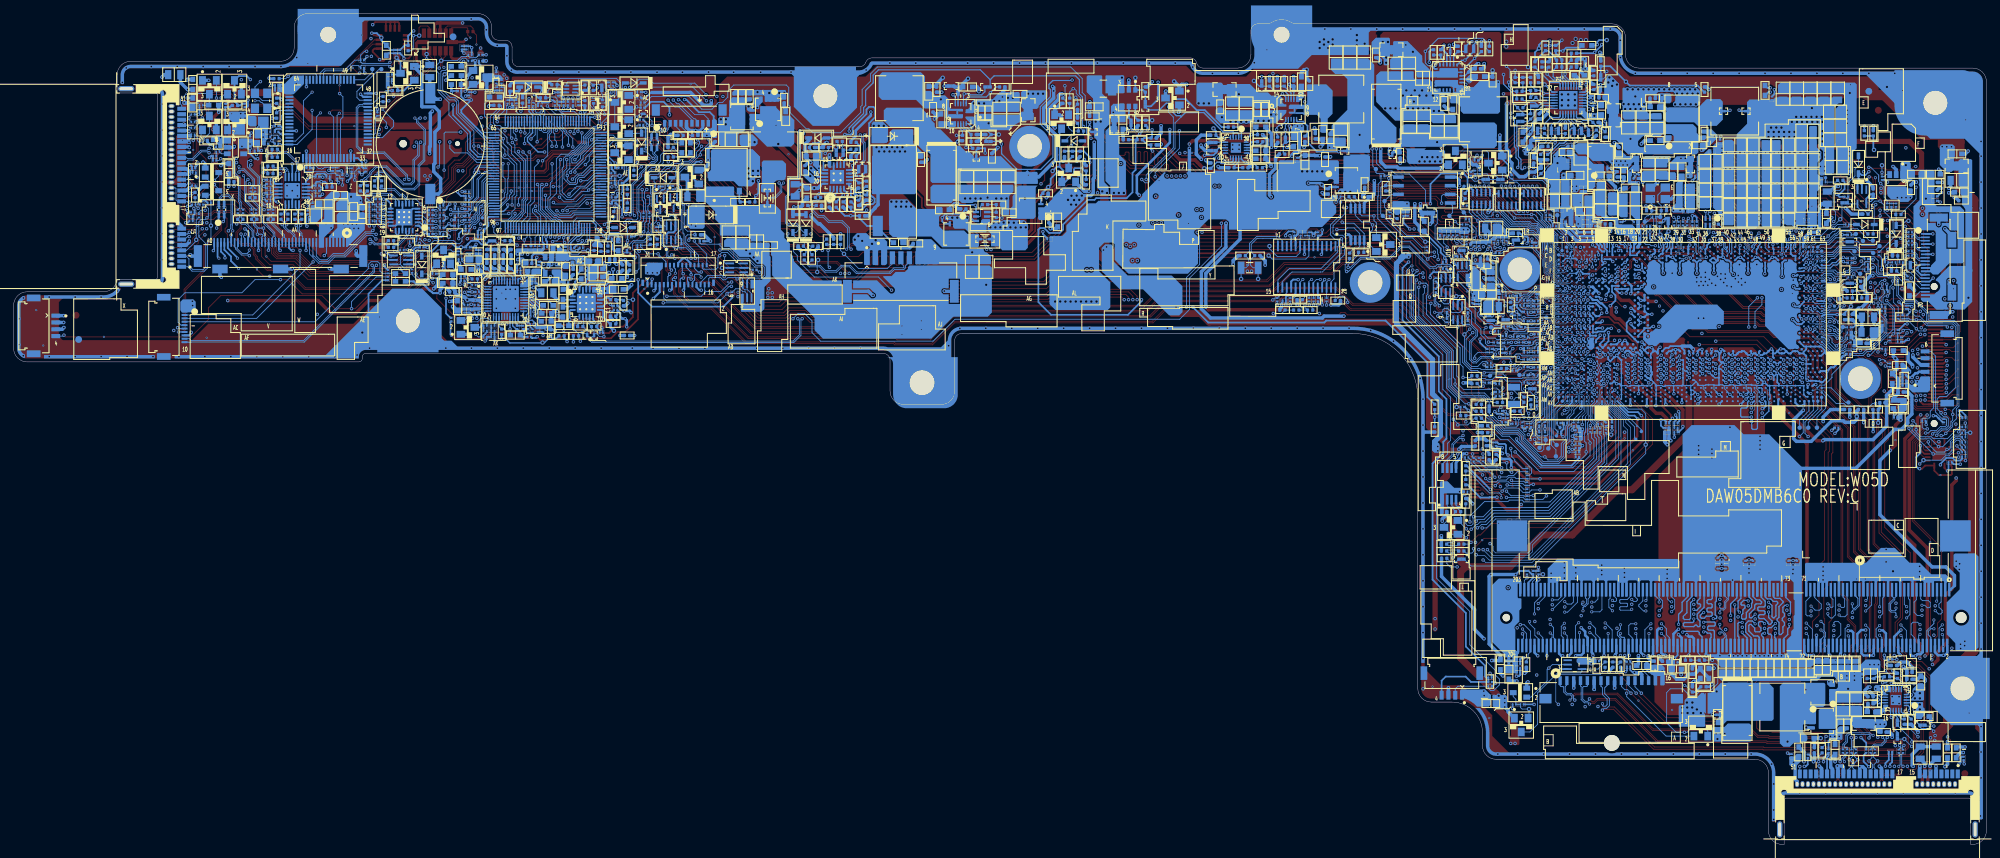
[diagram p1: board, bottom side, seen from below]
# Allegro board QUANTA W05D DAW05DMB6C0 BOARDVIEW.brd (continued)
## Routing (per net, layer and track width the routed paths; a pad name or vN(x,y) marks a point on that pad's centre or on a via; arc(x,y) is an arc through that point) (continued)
PCH_DPST_PWM: length 79
  TOP w0.127: v2(17.01,81.79) 17.66,81.15 17.73,81.15 v1(18.01,80.87) 18.46,80.42 18.46,79.67 18.66,79.47 19.54,79.47 19.93,79.86 19.93,82.63 22.48,85.18 23.83,85.18 24.96,84.05 28.49,84.05 29.53,83.01 29.53,82.05 v2(30.09,81.49) 31.64,83.04 32.48,83.04 33.9,84.46 33.9,84.68 36,86.77 36.43,86.77 37.38,87.72 37.38,88.61 39.93,91.17 v2(40,91.17)
  IN1 w0.127: v2(30.09,81.49) 30.09,80.83 32.81,78.11 44.42,78.11 47.69,81.39 50.96,81.39 51.43,81.86 52.35,81.86 52.62,82.12 55.97,82.12 56.3,82.45 58.01,82.45 58.39,82.83 58.39,83.9 57.85,84.43 v2(57.85,84.79)
  IN2 w0.127: v2(17.01,81.79) 16.13,81.79 15.87,82.05 15.87,82.66 14.65,83.88 v2(14.65,84.89)
  BOTTOM w0.127: R249.1 R248.1 14.41,85.36 14.65,85.12 v2(14.65,84.89) ; R168.2 39.66,91.86 39.9,91.62 39.9,91.27 v2(40,91.17) ; v2(57.85,84.79) 57.83,84.82 57.83,85.37 58.29,85.83 58.29,86.01 57.92,86.37 U20.B8
PCH_DPST_PWM_R: length 6.6
  BOTTOM w0.127: CN7.17 9.7,81.65 10.76,82.71 11.36,82.71 R262.1 11.88,82.92 v2(12.15,83.19) C219.1 13.17,85.16 13.34,85.34 R249.2
PCH_EDP_BLON: length 79.5
  IN1 w0.127: v2(33.98,76) 34.41,76.43 38.07,76.43 38.9,75.6 39.67,75.6 40.12,76.05 43.91,76.05 48.19,80.33 54.95,80.33 v2(55.11,80.5)
  IN2 w0.127: v2(57.83,88.04) 58.09,87.78 58.09,85.71 57.37,84.99 57.37,82.5 57.12,82.25 56.61,82.25 55.11,80.75 v2(55.11,80.5) ; v2(17.26,99.42) 18.79,99.42 19.17,99.04 19.17,98.02 19.83,97.36 22.16,97.36 22.83,96.7 22.83,94.42 21.46,93.05 21.46,90 21.76,89.69 21.76,86.34 24.07,84.03 24.07,81.72 24.97,80.82 26.6,80.82 27.14,80.27 v2(32.96,80.27)
  BOTTOM w0.127: R129.1 R128.1 R127.1 14.57,94.59 15.02,95.04 15.02,96.53 v2(15.51,97.03) 15.84,97.36 15.84,98.3 16.96,99.42 v2(17.26,99.42) ; U20.A9 57.5,87.71 v2(57.83,88.04) ; v2(33.98,76) 33.98,78.24 32.96,79.25 v2(32.96,80.27)
PCH_HOME_BUTTON#: length 186.5
  TOP w0.076: 65.52,74.68 v1(65.19,75.01) 65.19,75.37 v2(64.97,75.6)
  TOP w0.127: 65.52,74.68 65.57,74.63 66.06,74.63 66.55,74.15 67.38,74.15 67.4,74.16 67.77,74.16 67.78,74.15 67.78,74.15 68.22,73.72 v2(69.11,73.72)
  IN2 w0.127: v2(209.1,102.41) 207.99,101.3 206.99,101.3 206.76,101.07 203.94,101.07 203.41,100.54 202.77,100.54 202.5,100.54 202.29,100.54 202.29,100.54 202.07,100.54 199.97,100.54 197.96,98.53 196.93,98.53 195.03,98.53 193.08,96.58 190.79,96.58 190.52,96.31 187.15,96.31 182.67,91.83 182.08,91.83 174.82,84.56 170.86,84.56 170.3,84 169.41,84 168.74,84.68 158.23,84.68 154.36,88.55 139.73,88.55 139.05,87.86 132.26,87.86 131.82,88.31 130.25,89.87 125.7,89.87 125.53,89.71 120.98,89.71 120.34,90.35 115.22,90.35 115.21,90.34 114.31,90.34 112.98,91.66 112.98,93.99 111.17,95.8 110.96,95.8 102.98,95.8 102.4,95.23 97.2,95.23 95.87,96.56 95.66,96.56 92.87,96.56 92.6,96.29 92.6,94.87 89.78,92.05 85.64,92.05 85.12,91.53 81.3,91.53 80.95,91.19 80.95,90.24 80.95,88.73 80.55,88.32 80.32,88.32 79.66,87.66 79.66,87.52 79.37,87.23 78.89,87.23 78.83,87.29 77.08,87.29 76.18,86.39 74.65,86.39 74.25,85.99 74.25,82.92 72.74,81.41 72.74,79.88 72.4,79.55 70.52,79.55 70.26,79.29 70.26,78.92 70.65,78.52 70.65,78.03 70.43,77.81 70.43,75.77 69.94,75.29 69.94,75.27 69.49,74.81 69.49,74.79 69.11,74.41 v2(69.11,73.72)
  BOTTOM w0.076: 63.87,76.26 63.7,76.43 61.79,76.43 U20.Y3
  BOTTOM w0.127: U7.45 209.9,105.44 209.1,104.65 v2(209.1,102.41) ; v2(64.97,75.6) 64.76,75.8 64.33,75.8 63.87,76.26 ; R345.1 v2(69.11,73.72)
PCH_INVRMEN: length 28.2
  BOTTOM w0.076: U20.AV7 58.65,66.13 58.34,65.82 58.34,65.6 58.23,65.49 58.23,64.71 58.44,64.5 58.44,62.06
  BOTTOM w0.127: R423.2 73.14,60.56 72.45,60.56 71.32,59.43 70.26,59.43 65.59,54.76 60.58,54.76 58.2,57.13 v2(58.2,58.93) 58.2,59.18 58.49,59.47 58.49,60.15 58.59,60.25 58.59,61.91 58.44,62.06
PCH_OPI_RCOMP: length 35
  TOP w0.381: v2(51.17,62.46) 51.3,62.34 v1(51.3,61.45) 51.3,59.92 57.47,53.75 66.69,53.75 69.11,56.16 70.63,56.16 72.32,57.86 v2(73.41,57.86)
  BOTTOM w0.076: 53.84,64.24 54.49,64.89 54.49,65.44 U20.AW15
  BOTTOM w0.254: v2(51.17,62.46) 51.68,62.97 52.57,62.97 53.84,64.24
  BOTTOM w0.381: v2(73.41,57.86) 73.02,57.47 R439.2
PCH_POWER_BUTTON#: length 180.3
  TOP w0.127: v3(112.67,96.68) 111.27,96.68 110.89,97.06 103.14,97.06 102.25,97.95 96.74,97.95 96.73,97.96 92.06,97.96 91.47,97.38 90.73,97.38 90.24,96.88 89.02,96.88 88.51,97.39 86.56,97.39 86,96.83 79.21,96.83 78.55,96.17 75.28,96.17 74.54,95.43 72.94,95.43 70.2,92.69 70.2,92.18 v2(67.78,89.77)
  IN2 w0.127: v2(210.63,102.52) 209.77,103.39 206.86,103.39 206.75,103.28 206.01,103.28 205.17,102.44 202.85,102.44 202.24,101.83 198.42,101.83 196.38,99.8 194.51,99.8 192.56,97.86 192.25,97.86 190.23,97.86 189.97,97.59 186.5,97.59 182.48,93.57 181.79,93.57 174.19,85.96 158.8,85.96 154.94,89.82 139.21,89.82 138.85,89.46 136.77,89.46 136.31,89.92 132.05,89.92 129.98,91.99 120.86,91.99 120.49,91.63 115.05,91.63 114.31,92.37 114.31,96.41 113.6,97.12 113.12,97.12 112.67,96.68 v3(112.67,96.68)
  BOTTOM w0.076: U20.L3 61.71,81.2 61.97,80.95 62.29,80.95 62.48,81.13 62.48,81.51 62.57,81.6 63.53,81.6 64.3,82.38 64.3,83.55 64.81,84.06 64.81,84.81 65.02,85.02 65.02,86.09 65.42,86.49
  BOTTOM w0.127: v2(210.63,102.52) 210.63,103.13 211.01,103.5 211.01,104.22 210.7,104.53 210.7,105.17 210.7,105.17 U7.47 ; 65.42,86.49 65.52,86.59 65.52,86.72 66.11,87.31 R219.1 66.01,87.88 65.74,88.15 65.74,88.69 66.69,89.64 67.66,89.64 v2(67.78,89.77)
PCH_ROTATE#: length 182.7
  TOP w0.127: v2(70.22,88.14) v1(71,88.92) 71.42,89.34 71.42,92.11 71.38,92.15 71.38,93.16 71.57,93.35 71.57,93.35 73.15,94.94 73.16,94.94 73.34,95.12 73.4,95.18 74.65,95.18 75.36,95.89 78.68,95.89 79.37,96.58 86.12,96.58 86.67,97.12 88.42,97.12 88.91,96.63 90.34,96.63 90.84,97.12 91.58,97.12 92.16,97.71 96.62,97.71 96.64,97.69 102.15,97.69 103.21,96.63 106.01,96.63 106.42,96.22 112.86,96.22 v2(113.3,96.66)
  IN1 w0.076: 64.76,82.66 64.76,82.53 63.49,81.26 63.2,81.26 62.35,80.41 62.35,79.86 62.21,79.72 60.71,79.72 60.47,79.97 v2(60.43,79.97)
  IN1 w0.127: v2(70.22,88.14) 70.22,88.07 69.68,87.53 66.65,87.53 64.76,85.65 64.76,82.66
  IN2 w0.127: v2(113.3,96.66) 113.3,96.66 113.3,95.11 114,94.41 114,92.31 114.94,91.37 120.6,91.37 120.96,91.74 129.88,91.74 132.4,89.21 138.96,89.21 139.31,89.57 154.83,89.57 158.69,85.7 174.46,85.7 181.97,93.21 182.5,93.21 186.62,97.33 190.06,97.33 190.34,97.6 192.14,97.6 192.46,97.6 192.67,97.6 194.61,99.55 196.49,99.55 198.5,101.55 199.55,101.55 202.38,101.55 202.96,102.14 205.25,102.14 205.38,102.27 206.08,102.27 206.74,102.93 206.74,102.93 206.84,103.02 206.86,103.02 206.96,103.13 209.39,103.13 v2(210,102.52)
  BOTTOM w0.127: R204.1 70.22,88.41 v2(70.22,88.14) ; v2(210,102.52) 210,103.23 210.23,103.46 210.23,104.32 210.44,104.54 210.44,105.07 210.3,105.21 U7.46 ; U20.R5 60.18,79.72 v2(60.43,79.97)
PCH_SLP_S0_N: length 199.2
  IN2 w0.127: v2(201.44,93.58) 200.98,93.12 200.3,93.12 200.14,93.27 198.36,93.27 198.26,93.17 198.24,93.17 197.4,92.33 196.56,92.33 196.11,91.88 194.69,91.88 194.02,91.2 193.81,91.2 193.39,91.2 193.07,91.2 192.65,91.2 192.4,91.46 192.09,91.46 191.88,91.46 189.03,91.46 184.57,87 184.57,86.22 180.5,82.15 178.73,82.15 176.09,79.51 172.74,79.51 171.75,78.52 170.49,78.52 157.26,78.52 152.84,82.94 136.68,82.94 136.25,82.5 105.92,82.5 103.27,85.16 97.31,85.16 95.38,87.09 93.26,87.09 93.02,87.09 92.82,87.29 88.47,87.29 85.46,84.29 85.46,83.13 82.25,79.91 80.99,79.91 80.62,79.55 79.94,79.55 79.7,79.3 79.7,77.41 74.67,72.38 74.67,65.23 73.53,64.09 73.53,60.33 71.54,58.35 71.54,56.64 70.21,55.31 70.21,55.13 v2(69.72,54.64) 68.43,54.64 64.05,59.02 64.05,61.12 63.24,61.93 63.24,64.83 62.48,65.59 62.48,72.9 63.05,73.47 63.5,73.47 v2(63.95,73.92)
  BOTTOM w0.076: U20.AF3 61.79,73.44 62.27,73.44 62.52,73.69 62.52,73.94 62.73,74.15 62.89,74.15 63.07,74.33 63.54,74.33 v2(63.95,73.92)
  BOTTOM w0.127: v2(201.44,93.58) 201.44,93.05 R142.1 ; v2(69.72,54.64) 69.92,54.64 70.44,55.16 v2(70.44,56.04) 71.34,56.04 71.82,55.56 73.21,55.56 R444.2
PCH_SLP_WLAN_N: length 7.2
  TOP w0.127: v2(64.66,69.88) 64.66,70.01 64.08,70.59 63.37,70.59 TP51.1
  BOTTOM w0.076: U20.AM5 60,70.37 61.71,70.37 61.79,70.3 62.37,70.3 62.54,70.46 62.94,70.46 63.13,70.64 63.39,70.64
  BOTTOM w0.127: v2(64.66,69.88) 64.66,70.01 64.03,70.64 63.42,70.64 63.39,70.64
PCH_SPI1_CLK: length 27.2
  IN1 w0.127: v2(61.84,75.62) 62.4,75.62 63.21,76.43 63.62,76.43 63.8,76.61 64.23,76.61 65.22,77.6 67.07,77.6 67.4,77.93 68.52,77.93 69.26,77.2 70.1,77.2 70.48,77.58 70.48,77.83 70.86,78.21 71.34,78.21 72.76,79.63 72.76,79.73 73.7,80.67 73.7,80.68 73.7,81.43 74.21,81.94 74.21,82.14 74.25,82.14 74.88,82.77 74.88,82.84 75.27,83.22 75.27,83.32 77.85,85.91 78.48,85.91 78.99,86.42 79.22,86.42 79.4,86.59 79.68,86.59 80.06,86.97 v2(81.07,86.97)
  BOTTOM w0.127: U20.AA3 61.51,75.95 v2(61.84,75.62) ; R238.2 81.94,86.97 v2(81.07,86.97)
PCH_SPI1_CLK_R: length 197.1
  TOP w0.127: v2(87.76,97.83) 88.1,98.18 91.38,98.18 91.55,98.34 97.32,98.34 98.06,98.34 98.06,98.34 98.47,98.34 98.8,98.34 98.8,98.34 99.21,98.34 99.21,98.34 99.53,98.34 100.27,98.34 100.27,98.34 100.68,98.34 102.48,98.34 102.89,97.94 104.32,97.94 104.32,97.93 104.81,97.93 104.81,97.94 106.33,97.94 106.35,97.92 106.83,97.44 111.28,97.44 111.57,97.14 115.51,97.14 115.89,97.51 115.89,97.52 117.11,98.74 117.42,98.74 120.01,98.74 120.13,98.86 120.13,99.75 120.26,99.88 120.52,99.88 120.64,99.75 120.64,98.86 120.77,98.74 120.97,98.74 121.15,98.92 121.15,100.77 121.28,100.9 121.53,100.9 121.66,100.77 121.66,99.93 121.79,99.81 122.04,99.81 122.17,99.93 122.17,101.45 122.29,101.58 122.55,101.58 122.67,101.45 122.67,100.25 122.8,100.12 123.06,100.12 123.18,100.25 123.18,101.62 123.31,101.75 123.56,101.75 123.69,101.62 123.69,100.25 123.82,100.12 124.07,100.12 124.2,100.25 124.2,101.62 124.33,101.75 124.58,101.75 124.71,101.62 124.71,100.25 124.83,100.12 125.52,100.12 125.9,100.5 125.9,101.54 126.03,101.66 126.35,101.66 126.48,101.54 126.48,101.32 126.61,101.19 127.66,101.19 132.51,96.33 134.63,96.33 135.97,94.99 135.97,90.3 139.94,86.33 149.34,86.33 149.4,86.39 156.46,86.39 156.58,86.26 156.58,85.2 156.71,85.07 156.96,85.07 157.09,85.2 157.09,86.26 157.22,86.39 157.47,86.39 157.6,86.26 157.6,85.2 157.73,85.07 157.98,85.07 158.11,85.2 158.11,86.26 158.23,86.39 158.49,86.39 158.62,86.26 158.62,85.2 158.74,85.07 159,85.07 159.12,85.2 159.12,86.26 159.25,86.39 159.5,86.39 159.63,86.26 159.63,85.2 159.76,85.07 160.01,85.07 160.14,85.2 160.14,86.26 160.27,86.39 160.52,86.39 160.65,86.26 160.65,85.2 160.77,85.07 161.03,85.07 161.16,85.2 161.16,86.26 161.28,86.39 161.54,86.39 161.66,86.26 161.66,85.2 161.79,85.07 162.04,85.07 162.17,85.2 162.17,86.26 162.3,86.39 162.55,86.39 162.68,86.26 162.68,85.2 162.81,85.07 163.11,85.07 163.24,85.2 163.24,86.24 163.36,86.37 163.67,86.37 163.8,86.24 163.8,85.2 163.92,85.07 164.19,85.07 166.15,83.11 169.81,83.11 171.03,84.33 177.19,84.33 189.64,96.78 193.67,96.78 193.79,96.91 193.79,97.29 193.92,97.41 194.18,97.41 194.3,97.29 194.3,96.5 194.43,96.37 194.68,96.37 194.81,96.5 194.81,97.29 194.94,97.41 195.19,97.41 195.32,97.29 195.32,96.59 195.45,96.46 195.7,96.46 195.83,96.59 195.83,97.29 195.95,97.41 203.47,97.41 203.75,97.13 203.75,96.32 203.5,96.07 v1(202.71,96.07) 200.78,96.07 200.68,96.17 v2(197.4,96.17)
  BOTTOM w0.127: R144.1 197.2,94.47 197.4,94.67 v2(197.4,96.17) ; C98.1 88.21,96.96 87.76,97.4 v2(87.76,97.83) ; C98.1 88.2,96.73 U9.6 ; C98.1 88.31,96.64 88.74,96.64 88.93,96.45 88.93,95.07 88.94,95.05 88.94,92.61 TP72.1 85.39,89.06 84.24,89.06 82.88,87.7 R238.1
PCH_SPI1_SI: length 42.3
  IN1 w0.076: v2(64.13,75.24) 64.23,75.14 65.09,75.14 65.26,75.3 65.42,75.3
  IN1 w0.127: v2(81.04,86.34) 80.33,86.34 80,86.02 80,85.93 79.21,85.15 78.57,85.15 78.41,84.98 78.16,84.98 74.34,81.16 74.34,80.41 73.4,79.47 73.4,79.37 72.12,78.09 72.12,77.42 71.87,77.17 71.52,77.17 70.91,76.56 69.64,76.56 68.57,75.49 66.13,75.49 65.97,75.33 65.45,75.33 65.42,75.3
  BOTTOM w0.076: v2(64.13,75.24) 64.13,75.39 63.9,75.61 63.17,75.61 63.08,75.71 62.46,75.71 U20.AA2
  BOTTOM w0.127: R87.2 88.9,97.38 89.31,96.97 89.31,95.23 89.37,95.16 89.37,91.9 85.97,88.5 84.62,88.5 82.08,85.96 v2(82.03,85.96) 81.65,86.34 v2(81.04,86.34)
PCH_SPI1_SI_R: length 174.5
  TOP w0.127: v2(231.23,89.29) 231.23,90.12 229.79,91.57 229.79,94.61 226.48,97.91 v2(226.48,99.01)
  IN2 w0.127: v2(224.05,104.6) 223.55,104.6 223.22,104.27 222.69,104.27 218.84,104.27 217.24,105.88 217.24,105.88 216.46,106.66 216.46,106.66 216.43,106.69 214.88,106.69 212.79,108.77 210.19,108.77 209.81,109.15 206.56,109.15 206.18,108.77 203.67,108.77 203.59,108.69 203.59,108.69 202.22,107.32 194.86,107.32 193.95,108.23 191.13,108.23 189.48,106.58 187.97,106.58 187.19,106.58 185.42,104.82 177.66,104.82 174.42,101.58 172.18,101.58 170.4,99.8 169.49,99.8 167.91,101.38 165.68,101.38 163.63,103.42 156.75,103.42 155.69,102.35 146.87,102.35 142.79,106.43 137.08,106.43 136.15,105.51 134.27,105.51 133.12,104.35 129.28,104.35 128.78,103.85 122.14,103.85 121.67,104.32 113.89,104.32 113.55,103.98 91.89,103.98 90.21,102.3 v2(90.21,102.14)
  BOTTOM w0.127: U9.5 86.94,98 87.22,98.28 88,98.28 88.16,98.13 R87.1 88.42,98.42 88.54,98.53 89.51,98.53 89.65,98.68 TP66.1 90.11,99.62 90.11,102.04 v2(90.21,102.14) ; v2(226.48,99.01) 226.48,104.41 226.29,104.6 v2(224.05,104.6) ; R210.1 231.07,89.12 v2(231.23,89.29)
PCH_SPI1_SO: length 28.5
  IN1 w0.127: v2(61.2,75.6) 61.2,75.86 61.47,76.13 62.2,76.13 62.98,76.92 62.98,77.62 63.34,77.98 64,77.98 65.52,79.51 67.81,79.51 67.99,79.69 69.84,79.69 70.12,79.96 71.19,79.96 72.43,81.2 72.43,81.52 72.43,81.52 72.43,81.97 72.86,82.4 72.86,82.47 72.86,84.3 74.69,86.13 74.69,86.33 75.23,86.87 75.94,86.87 76.17,87.1 76.17,87.51 76.16,87.51 75.87,87.8 75.39,87.8 75.18,88.02 75.18,88.98 v2(75.2,89.01)
  BOTTOM w0.127: v2(61.2,75.6) 60.86,75.94 U20.AA4 ; R159.2 75.95,91.46 74.93,90.44 74.93,89.27 v2(75.2,89.01)
PCH_SPI1_SO_R: length 192.7
  TOP w0.127: v2(233.7,87.05) 233.93,87.29 233.93,87.88 233.72,88.09 233.72,88.43 233.46,88.69 232.83,88.69 232.31,89.2 232.15,89.2 232.03,89.32 232.03,89.88 230.17,91.75 230.17,94.45 230.17,94.45 230.17,94.76 230.17,94.76 230.17,96.69 229.98,96.88 228.06,96.88 227.37,97.56 v2(227.37,99.47) ; v2(80,94.16) 80,94.38 80.8,95.18 85.54,95.18 85.54,95.18 86.39,95.18 86.64,94.93 87.03,94.93 87.04,94.92 88.77,94.92 88.77,94.93 91.66,94.93 93.05,96.31 95.09,96.31 95.63,95.78 96.56,95.78 97.07,95.27 98.36,95.27 98.43,95.2 104.29,95.2 104.84,94.66 109.91,94.66 110.08,94.82 113.78,94.82 114.13,95.18 117.03,95.18 119.14,97.29 119.18,97.29 119.42,97.29 v2(120.31,98.18)
  IN2 w0.127: v2(227.14,103.18) 226.56,103.18 225.09,101.71 216.53,101.71 215.08,103.15 215.07,103.15 214.86,103.37 214.39,103.37 214.16,103.14 213.55,103.14 212.52,104.17 211.93,104.17 211.23,104.87 211.23,105.25 210.42,106.06 205.81,106.06 205.42,105.67 203.5,105.67 202.98,105.15 202.4,105.15 199.07,105.15 199.07,105.15 198.34,105.15 198.34,105.15 197.97,105.15 196.69,103.86 196.1,103.86 195.85,103.61 193.93,103.61 193.47,103.15 193.09,103.15 193.09,103.15 192.77,103.15 191.48,101.86 190.56,101.86 189.4,100.7 188.58,100.7 187.93,100.06 185.34,100.06 181.78,96.5 180.56,96.5 175.59,91.54 175.25,91.54 175.25,91.54 174.79,91.54 174.54,91.29 167.63,91.29 166.74,92.18 165.06,92.18 157.49,92.18 152.29,97.39 144.27,97.39 143.66,98 137.79,98 136.17,96.37 132.07,96.37 131.37,97.07 121.42,97.07 v2(120.31,98.18)
  BOTTOM w0.127: R229.1 233.18,87.05 v2(233.7,87.05) ; v2(227.37,99.47) 227.14,99.7 v2(227.14,103.18) ; R159.1 76.43,92.5 TP70.1 77.39,93.45 77.39,95.03 77.82,95.46 U9.2 79.75,95.46 80,95.2 v2(80,94.16)
PCH_SPI_CS0#: length 31.5
  IN1 w0.076: v2(59.17,77.02) 58.71,76.56 58.29,76.56 57.65,77.2 57.65,79.13 58.08,79.55 62.42,79.55 62.73,79.86 62.73,80.24 63.37,80.88 63.49,80.88 65.14,82.53 65.14,82.66
  IN1 w0.127: v2(75.4,90.07) 75.4,90 75.05,89.64 73.65,89.64 73.45,89.85 72.74,89.85 72.43,89.54 72.43,88 71.45,87.02 70.41,87.02 70.27,87.15 66.84,87.15 65.14,85.45 65.14,82.66
  BOTTOM w0.089: U20.Y7 58.88,76.73 v2(59.17,77.02)
  BOTTOM w0.127: v2(75.4,90.07) 75.4,90.37 v1(75.82,90.78) 76.08,91.04 R173.2
PCH_SPI_CS0#_R: length 193.4
  TOP w0.127: v2(196.53,95.15) 195.72,95.15 194.9,95.98 v1(192.96,95.98) 189.38,95.98 177.35,83.95 171.19,83.95 169.97,82.73 165.99,82.73 164.04,84.69 156.42,84.69 155.09,86.01 150.03,86.01 149.97,85.95 139.79,85.95 135.59,90.14 135.59,94.84 134.47,95.95 132.54,95.95 132.06,95.47 131.61,95.47 131.35,95.73 131.35,96.92 127.46,100.81 126.75,100.81 125.61,99.67 122.45,99.67 119.68,96.91 119.66,96.91 119.32,96.91 117.21,94.8 114.29,94.8 113.93,94.44 110.23,94.44 110.07,94.28 109.75,94.28 104.68,94.28 104.13,94.82 98.27,94.82 98.22,94.87 96.82,94.87 96.37,95.32 92.71,95.32 91.94,94.54 88.93,94.54 86.88,94.54 86.88,94.54 86.8,94.54 86.8,94.54 86.48,94.54 86.23,94.8 85.39,94.8 80.96,94.8 80.59,94.42 80.59,94.11 80.59,94.11 80.59,93.81 80.43,93.66 79.57,93.66 79.39,93.83 79.39,94.24 79.14,94.49 78.1,94.49 75.99,94.49 75.86,94.37 75.86,94.21 75.99,94.09 78.5,94.09 78.58,94.01 78.58,93.83 78.45,93.71 74.39,93.71 74.24,93.55 74.24,93.35 74.33,93.25 79.47,93.25 79.59,93.13 79.59,93.03 79.42,92.85 74.29,92.85 74.16,92.72 74.16,92.46 74.29,92.33 79.88,92.33 80,92.21 80,92.05 79.88,91.93 73.78,91.93 72.56,90.71 72.56,90.02 72.69,89.9 74.54,89.9 74.92,90.28 74.92,90.66 74.8,90.78 73.78,90.78 73.65,90.91 73.65,91.17 73.78,91.29 77.84,91.29 v2(78.02,91.47)
  BOTTOM w0.127: v2(196.53,95.15) 196.33,94.96 196.33,93.99 196.56,93.76 196.56,93.15 196.33,92.92 R145.1 ; R173.1 77.59,91.04 v2(78.02,91.47) TP73.1 78.39,92.78 78.39,93.83 U9.1
PCH_SPI_IO2: length 32.4
  IN1 w0.076: 65.42,82.25 65.19,82.02 64.89,82.02 63.49,80.62 63.42,80.62 62.98,80.19 62.98,79.74 62.64,79.39 58.19,79.39 57.9,79.1 57.9,77.83 58.16,77.58 59.27,77.58 59.81,77.04 v2(59.83,77.04)
  IN1 w0.127: 65.42,82.25 65.54,82.36 65.54,85.31 67,86.77 70.07,86.77 70.27,86.57 71.54,86.57 73.7,88.73 73.88,88.73 74.26,89.11 v2(74.26,89.16)
  BOTTOM w0.076: v2(59.83,77.04) 59.83,76.92 U20.Y6
  BOTTOM w0.127: R131.2 76.17,93.81 75.94,93.58 75.94,92.82 v2(74.67,91.55) 74.54,91.42 74.54,89.44 v2(74.26,89.16)
PCH_SPI_IO3: length 35.9
  IN1 w0.076: 65.42,74.4 65.24,74.4 65.14,74.5 64.48,74.5 64.3,74.33 63.72,74.33 v2(63.31,73.92)
  IN1 w0.127: 65.42,74.4 65.78,74.4 66.29,73.89 67.12,73.89 67.4,74.17 67.78,74.17 68.01,73.94 68.7,73.94 68.92,74.16 70.19,74.16 71.04,75.01 71.04,75.22 72.97,77.15 73.42,77.15 73.78,77.51 73.78,79.31 74.72,80.25 74.72,80.26 74.72,81 78.32,84.6 78.57,84.6 78.73,84.77 79.39,84.77 v2(80.51,85.88)
  BOTTOM w0.076: v2(63.31,73.92) 62.98,73.92 U20.AF1
  BOTTOM w0.127: v2(80.51,85.88) 80.48,85.91 80.48,86.64 80.59,86.75 80.59,87.34 81.75,88.5 v4(82.39,88.5) 82.42,88.5 83.35,89.44 85.16,89.44 87.62,91.9 R141.1
PCH_SUSCLK: length 220.1
  TOP w0.127: v2(115.18,89.9) 115.12,89.83 111.37,89.83 106.85,89.83 106.85,89.83 106.64,89.83 104.37,89.83 102.71,91.5 90.63,91.5 87.66,91.5 86.37,90.2 85.7,90.2 85.09,89.59 84.88,89.59 84.29,89.59 84.29,89.59 84.24,89.59 83.92,89.59 81.89,87.56 81.89,85.85 80.76,84.72 80.76,84.33 78.2,81.77 TP20.1 77.02,81.2 77.02,81.19 75.43,79.61 75.43,79.05 74.54,78.16 74.54,78.08 v2(74.24,77.78)
  IN1 w0.127: v2(221.12,91.09) 220.6,91.09 219.28,89.77 215.61,89.77 213.63,87.79 203.8,87.79 v2(203.01,88.58)
  IN2 w0.127: v2(115.18,89.9) 115.63,89.45 116.69,89.45 125.65,89.45 125.82,89.62 130.15,89.62 131.23,88.53 132.15,87.61 139.16,87.61 139.79,88.24 153.61,88.24 157.78,84.08 164.69,84.08 165.48,83.29 170.29,83.29 170.7,83.7 174.35,83.7 182.1,91.45 182.66,91.45 187.27,96.06 190.63,96.06 190.89,96.32 193.18,96.32 195.14,98.28 196.19,98.28 197.03,98.28 197.04,98.28 198.29,98.28 198.78,98.77 199.95,98.77 200.73,99.55 202.78,99.55 204.05,100.82 206.86,100.82 207.08,101.03 210.32,101.03 211.61,99.74 213.41,99.74 213.95,99.21 219.44,99.21 220.79,100.56 228.85,100.56 230.09,99.32 230.09,89.92 229.56,89.39 228.97,89.39 228.97,89.39 228.11,89.39 227.17,88.45 222.86,88.45 221.56,89.75 221.12,89.75 220.69,90.18 220.69,90.66 v2(221.12,91.09)
  BOTTOM w0.127: R228.2 202.43,88.37 202.63,88.58 v2(203.01,88.58) ; R311.2 73.4,76.94 v2(74.24,77.78)
PCH_SUSCLK_L: length 14.8
  IN1 w0.089: v2(59.81,74.25) 60.24,74.68 62.53,74.68 62.65,74.81 65.17,74.81 65.27,74.91 65.42,74.91
  IN1 w0.127: v3(71.72,76.69) 70.69,75.66 70.31,75.66 69.74,75.09 67.73,75.09 67,74.35 66.57,74.35 66.01,74.91 65.42,74.91
  BOTTOM w0.127: R311.1 71.98,76.94 v3(71.72,76.69) ; v2(59.81,74.25) 59.53,73.97 U20.AE6
PCH_THRMTRIP#: length 7.1
  BOTTOM w0.076: 25.96,85.91 25.5,86.37 25.5,86.58 25.17,86.92 25.17,87.13 24.97,87.32 24.55,87.32 24.23,87.64 23.88,87.64 23.77,87.53 23.31,87.53
  BOTTOM w0.089: 25.96,85.91 U20.D60
  BOTTOM w0.127: 23.31,87.53 22.83,87.53 21.86,88.5 R213.1
PCH_VOL_DOWN#: length 183.7
  TOP w0.089: v2(59.05,79) 59.53,78.52 60.65,78.52 60.94,78.22 61.98,78.22 62.43,78.67 62.86,78.67 63.06,78.47 63.62,78.47 63.87,78.72 63.87,78.95 64.51,79.59 65.28,79.59 65.52,79.35
  TOP w0.127: 65.52,79.35 65.92,78.95 v1(65.92,78.48) 65.92,78.37 66.62,77.68 67.05,77.68 68.7,79.33 70.03,79.33 70.33,79.63 71.02,79.63 71.02,79.63 71.25,79.63 71.46,79.63 71.96,79.63 71.97,79.63 72.07,79.74 72.07,79.74 74.05,81.71 74.05,81.71 74.47,82.13 74.47,82.14 74.93,82.61 75.97,82.61 76.87,83.51 76.87,83.51 77.73,84.36 77.73,84.37 77.77,84.41 77.77,87.63 78.55,88.42 v2(78.55,88.91)
  IN2 w0.127: v2(208.22,102.67) 207.96,102.67 207.77,102.86 207.05,102.86 206.96,102.77 206.95,102.77 206.85,102.67 206.85,102.67 206.01,101.83 203.62,101.83 203.09,101.3 200.29,101.3 198.62,101.3 196.61,99.29 194.72,99.29 192.76,97.34 192.01,97.34 190.46,97.34 190.2,97.07 186.77,97.07 182.55,92.85 182.03,92.85 174.62,85.44 158.55,85.44 154.88,89.1 154.67,89.31 139.42,89.31 138.73,88.63 132.57,88.63 131.03,90.17 130.57,90.63 125.37,90.63 125.21,90.47 121.3,90.47 120.65,91.11 114.9,91.11 114.89,91.1 114.62,91.1 113.75,91.98 113.75,94.31 111.48,96.58 102.66,96.58 102.07,95.99 98.6,95.99 97.43,97.16 97.4,97.16 97.4,97.16 96.81,97.16 96.63,97.34 95.6,97.34 92.57,97.34 91.81,96.58 91.81,95.51 89.19,92.89 85.7,92.89 85.31,92.89 84.93,92.51 80,92.51 79.27,91.78 79.27,89.74 78.55,89.03 v2(78.55,88.91)
  BOTTOM w0.127: U20.U7 58.88,78.82 v2(59.05,79) ; U7.44 209.5,105.4 208.83,104.73 208.83,104.73 208.73,104.63 208.73,104.4 208.22,103.89 v2(208.22,102.67) ; v2(78.55,88.91) 78.55,89.02 78.53,89.05 78.53,89.25 R190.1
PCH_VOL_UP#: length 181.7
  IN2 w0.127: v2(207.59,102.42) 206.95,102.42 206.11,101.58 203.73,101.58 203.2,101.05 202.99,101.05 202.99,101.05 200.18,101.05 199.71,101.05 197.71,99.04 196.72,99.04 194.82,99.04 192.87,97.08 192.66,97.08 190.57,97.08 190.3,96.82 186.91,96.82 182.62,92.53 182.07,92.53 174.72,85.18 158.44,85.18 154.73,88.9 154.57,89.06 139.52,89.06 138.84,88.37 132.47,88.37 131.66,89.18 130.46,90.38 125.48,90.38 125.31,90.21 121.19,90.21 120.55,90.86 115.01,90.86 115,90.85 114.52,90.85 113.49,91.88 113.49,94.2 111.37,96.32 102.76,96.32 102.18,95.74 98.5,95.74 97.33,96.91 97.17,96.91 97.17,96.91 96.7,96.91 96.52,97.08 92.68,97.08 92.07,96.47 92.07,95.2 89.43,92.56 85.43,92.56 84.91,92.04 80.28,92.04 79.63,91.39 79.63,88.75 79.44,88.55 79.39,88.55 79.37,88.53 78.81,88.53 78.74,88.46 78.62,88.46 77.95,87.79 76.83,87.79 75.93,86.9 74.44,86.9 73.65,86.11 72.28,86.11 v2(72.18,86.21)
  BOTTOM w0.076: U20.L4 61.16,80.91 61.58,80.91 61.7,80.79 63.05,80.79 63.11,80.84 64.07,80.84 65.22,82 65.42,82
  BOTTOM w0.127: v2(72.18,86.21) 71.92,86.21 71.75,86.04 71.75,83.19 71.37,82.82 71.37,82.66 69.92,81.21 69.77,81.21 69.54,80.98 68.77,80.98 68.46,80.67 R273.1 68.17,80.57 67.94,80.8 67.4,80.8 66.21,82 65.42,82 ; v2(207.59,102.42) 207.59,103.66 208.48,104.55 208.48,104.74 209.1,105.36 U7.43 209.1,106.98 209.29,107.17 210.05,107.17 v2(211.32,108.44)
PCI_PME#: length 2
  TOP w0.127: TP39.1 62.15,74.58 61.62,74.58 v2(61.16,74.12)
  BOTTOM w0.089: U20.AD4 61.16,74.24 v2(61.16,74.12)
PCI_SERR#: length 197.4
  TOP w0.089: TP29.1 62.32,78.11 62.26,78.04 61.04,78.04 60.65,77.65 60.14,77.65 v2(59.73,78.06)
  TOP w0.127: v2(118.99,98.15) 116.65,95.81 113.87,95.81 113.51,95.46 106.1,95.46 105.72,95.84 105.51,95.84 98.69,95.84 98.12,96.41 95.89,96.41 95.36,96.94 92.48,96.94 91.89,96.36 91.16,96.36 90.66,95.86 88.6,95.86 88.1,96.36 86.99,96.36 86.44,95.81 85.81,95.81 79.68,95.81 79,95.13 78.37,95.13 78.37,95.13 75.67,95.13 74.9,94.36 74.04,94.36 73.65,94.36 73.47,94.18 73.47,94.18 72.64,93.34 72.64,91.95 71.92,91.24 71.92,89.38 72.48,88.83 72.48,87.24 v2(72.66,87.06)
  IN1 w0.076: v2(59.73,78.06) 60.19,78.52 60.49,78.52 61.13,79.15 62.7,79.15 63.16,79.61 63.62,79.61 64,79.99 64,80.75 64.76,81.51 65.27,81.51 65.42,81.67
  IN1 w0.127: v2(72.66,87.06) 72.66,86.01 71.37,84.71 71.37,83.37 69.74,81.74 69.02,81.74 68.95,81.67 65.42,81.67
  IN2 w0.127: v2(118.99,98.15) 120.95,96.2 124.98,96.2 126.33,94.85 130.41,94.85 130.41,94.85 130.62,94.85 130.62,94.85 131.54,94.85 132.71,93.68 133.22,93.17 136.68,93.17 136.72,93.21 138.33,93.21 140.86,95.74 141.07,95.74 151.78,95.74 156.86,90.66 165.69,90.66 166.11,90.66 168.01,88.75 172.9,88.75 175.05,90.9 175.51,90.9 175.72,90.9 175.87,90.9 180.8,95.83 182.02,95.83 185.61,99.42 189.02,99.42 190.82,101.22 191.79,101.22 193.06,102.49 193.71,102.49 194.19,102.98 196.21,102.98 196.41,103.18 196.43,103.18 196.91,103.18 198.24,104.51 198.33,104.51 198.6,104.51 199.4,104.51 203.24,104.51 203.77,105.03 205.69,105.03 206.07,105.42 210.16,105.42 210.6,104.98 210.6,104.6 212.12,103.08 212.12,102.85 212.83,102.14 214.16,102.14 214.44,101.86 214.44,101.35 214.62,101.17 217.52,101.17 v2(217.57,101.22)
  BOTTOM w0.127: v2(217.57,101.22) 217.57,102.04 218.13,102.6 218.13,103.23 218.25,103.36 U7.68 ; v2(72.66,87.06) 72.66,87.6 R214.1 ; v2(59.73,78.06) 59.53,77.86 U20.V6
PCIE_CLKREQ0#: length 7
  BOTTOM w0.076: U20.U2 62.46,78.54 62.94,78.54 63.15,78.32 63.63,78.32 63.87,78.57 64.53,78.57 64.64,78.67 65.42,78.67
  BOTTOM w0.127: R291.1 68.46,79.04 68.14,78.72 67.75,78.72 67.63,78.61 65.66,78.61 65.6,78.67 65.42,78.67
PCIE_CLKREQ3#: length 21.3
  TOP w0.127: v2(76.37,88.7) 76.62,88.45 76.62,84.88 76.59,84.84 76.59,84.84 76.4,84.65 76.39,84.65 75.49,83.75 74.54,83.75 74.54,83.75 73.71,83.75 73.32,83.36 73.32,82.61 72.9,82.19 72.9,82.18 71.6,80.88 71.59,80.88 71.49,80.78 70.27,80.78 70.07,80.98 69.7,80.98 69.34,80.98 69.21,80.85 v1(68.39,80.85) 66.31,80.85 65.78,81.39 65.19,81.39 64.52,80.71 v2(64.52,80.64)
  BOTTOM w0.076: v2(64.52,80.64) 63.18,80.64 63.03,80.49 U20.N1
  BOTTOM w0.127: v2(76.37,88.7) 76.32,88.75 R199.1
PCIE_CLKREQ4#: length 22.1
  TOP w0.089: 63.49,80.5 63.26,80.5 61.99,79.23 61.08,79.23 61.03,79.18 60.54,79.18 v2(60.36,78.99)
  TOP w0.127: 63.49,80.5 63.77,80.5 65.04,81.77 65.96,81.77 66.49,81.23 v1(67.07,81.23) 67.15,81.31 69.13,81.31 69.18,81.36 69.86,81.36 70.28,81.36 72.53,83.62 72.53,83.7 73.35,84.51 74.86,84.51 74.86,84.51 75.18,84.51 75.86,85.2 75.86,87.18 v2(75.68,87.36)
  BOTTOM w0.127: R216.1 75.18,87.86 v2(75.68,87.36) ; v2(60.36,78.99) 60.18,78.81 U20.U5
PCIE_CLKREQ5#: length 4.2
  BOTTOM w0.076: 65.42,79.13 64.84,79.13 64.48,78.77 63.82,78.77 63.54,78.49 63.22,78.49 63.01,78.7 62.46,78.7 U20.T2
  BOTTOM w0.127: 65.42,79.13 65.57,79.13 65.63,79.08 65.79,79.08 R294.1
PCIE_CLKREQ_CR#: length 130.6
  TOP w0.076: v2(60.47,77.04) 60.06,77.45 59.81,77.45 59.68,77.58
  TOP w0.089: v2(60.47,77.04) 60.6,77.04 61.03,76.61 62.44,76.61 62.79,76.97 65.19,76.97 v2(65.3,77.07)
  TOP w0.127: 59.68,77.58 58.03,77.58 57.52,78.08 57.52,78.97 56.94,79.56 55.67,79.56 55.49,79.74 54.27,79.74 53.51,78.97 v2(53.08,78.97) ; v2(48.1,76.08) 45.05,76.08 43.53,74.55 32.69,74.55 30.88,72.75 30.85,72.75 30.38,72.27 29.3,72.27 28.31,71.29 28.31,67.26 25.95,64.9 25.95,63.44 22.55,60.03 22.55,57.54 22.73,57.36 22.73,33 23.11,32.62 23.11,29.57 v1(23.63,29.05) 24,28.68 24,27.81 27.49,24.31 33.37,24.31 34.11,23.58 34.11,22.29 38.81,17.58 47.57,17.58 v1(51.1,21.11) v2(52.19,22.2)
  IN1 w0.127: v2(53.08,78.97) 53.08,79.06 52.7,79.44 52.02,79.44 51.68,79.1 51.68,76.05 51.25,75.62 49.24,75.62 49.12,75.49 48.68,75.49 v2(48.1,76.08)
  BOTTOM w0.089: U20.Y5 60.18,76.75 v2(60.47,77.04)
  BOTTOM w0.127: CN13.10 53.6,23.21 53.1,22.71 52.7,22.71 v2(52.19,22.2) ; R313.1 65.83,76.84 65.6,77.07 v2(65.3,77.07)
PCIE_CLKREQ_WLAN#: length 228.9
  TOP w0.127: v2(124.45,90.94) 124.45,92.22 123.3,93.38 120.27,93.38 116.34,89.45 111.53,89.45 111.32,89.45 111.32,89.45 111,89.45 111,89.45 107.01,89.45 106.79,89.45 106.79,89.45 106.48,89.45 106.48,89.45 104.74,89.45 104.21,89.45 102.55,91.12 90.79,91.12 90.79,91.11 87.82,91.11 86.52,89.82 85.86,89.82 85.25,89.21 84.5,89.21 84.08,89.21 82.28,87.41 82.28,85.69 81.2,84.61 81.2,84.28 v1(81.17,84.26) 81.17,84.19 80.61,83.63 80.61,83.62 77.94,80.96 77.94,80.08 76.04,78.17 76.01,78.17 75.58,77.75 75.58,77.39 74.09,75.9 v2(73.47,75.9)
  IN1 w0.127: v2(261.56,93.12) 260.19,94.49 256.79,94.49 253.74,97.54 253.74,99.75 253,100.49 251.35,100.49 250.39,101.45 247.79,101.45 247.52,101.17 230.19,101.17 230.03,101.01 228.43,101.01 228.27,101.17 226.71,101.17 226.15,100.61 222.85,100.61 222.31,100.61 222.04,100.34 219.24,100.34 217.82,98.91 214.67,98.91 214.28,98.52 209.94,98.52 207.87,96.45 205.58,96.45 205.43,96.6 202.68,96.6 202.18,96.09 200.2,96.09 199.79,95.69 199.76,95.69 199.74,95.66 196.11,95.66 195.63,95.19 193.24,95.19 192.1,94.05 191.98,94.05 191.8,94.05 191.27,93.52 189.81,93.52 184.19,87.9 183.57,87.9 183.57,87.9 181.92,87.9 179.68,85.65 179.36,85.65 169.62,85.65 168.9,84.93 164.75,84.93 161.96,87.72 148.07,87.72 147.8,87.99 134.16,87.99 134.08,88.07 131.87,88.07 129,90.94 v2(124.45,90.94)
  BOTTOM w0.076: 65.38,74.52 64.58,74.52 64.56,74.49 62.82,74.49 U20.AD1
  BOTTOM w0.127: R152.2 262.5,92.82 262.2,93.12 v2(261.56,93.12) ; v2(73.47,75.9) 73.78,75.6 73.78,74.94 73.19,74.35 72.13,74.35 71.92,74.15 70.63,74.15 70.62,74.16 67.57,74.16 67.34,74.39 R338.1 67.14,74.35 66.46,74.35 66.36,74.45 65.85,74.45 65.79,74.52 65.38,74.52
PCIE_IREF: length 4.7
  BOTTOM w0.203: U20.B27 46.97,87.2 46.5,87.68 46.5,88.52 47.01,89.03 47.01,89.51
  BOTTOM w0.305: 47.01,89.51 47.01,89.69 v4(46.68,90.02) 46.73,90.07 R164.2
PCIE_RCOMP: length 3.6
  BOTTOM w0.203: R174.1 48,89.67 v4(47.87,89.54) 47.34,89.01 47.34,88.91 46.86,88.42 46.86,87.83 U20.A27
PCIE_RXN2_CARD: length 142.3
  TOP w0.127: v2(60.44,21.19) 60.65,21.39 60.65,21.68 60.35,21.98 54.25,21.98 48.99,16.72 34.61,16.72 33.61,15.73 32.07,15.73 31.92,15.58 24.55,15.58 23.97,14.99 21.39,14.99 20.93,15.44 20.93,25.83 19.91,26.86 19.91,28.83 19.19,29.55 19.19,32.1 20.21,33.12 20.21,35.89 21.1,36.78 21.1,60.89 25.07,64.85 25.07,66.9 25.49,67.33 25.49,68.35 26.23,69.09 26.23,71.51 26.66,71.94 27.74,71.94 30.46,74.66 31.11,74.66 31.87,75.42 40.82,75.42 41.2,75.8 43.05,75.8 48.05,80.8 48.49,80.8 50.37,82.68 51.43,82.68 51.79,82.33 53.26,82.33 53.45,82.52 53.45,84.3 53.71,84.56 53.84,84.56 v3(54.04,84.77)
  BOTTOM w0.127: v2(60.44,21.19) 60.64,21.38 60.64,21.83 60.98,22.18 61.56,22.18 61.84,22.46 61.84,23.18 61.6,23.42 CN13.2 ; v3(54.04,84.77) 54.18,84.77 U20.F15
PCIE_RXN3_WLAN: length 253.9
  TOP w0.127: v3(263.95,97.13) 263.64,97.13 263.31,96.81 263.31,95.43 263.57,95.18 264.32,95.18 264.84,94.66 264.84,92.8 264.44,92.4 260.63,92.4 260.22,92.82 257.93,92.82 256.43,91.32 256.43,90.5 257.04,89.89 257.04,88.8 256.23,87.99 255.11,87.99 254.5,87.38 254.5,86.6 254.14,86.25 254.14,85.96 252.44,84.26 249.67,84.26 246.91,81.49 231.79,81.49 224.83,88.45 224.83,89.59 224.83,89.59 224.83,89.69 224.83,89.69 224.83,91.31 224.72,91.42 224.72,92.18 224.19,92.7 223.48,92.7 221.41,94.77 212.21,94.77 211.96,94.52 211.12,94.52 210.86,94.77 210.25,94.77 209.72,94.24 207.75,94.24 207.54,94.45 207.11,94.88 206.02,95.97 203.83,98.15 193.76,98.15 193.02,97.41 189.38,97.41 177.34,85.37 168.85,85.37 167.63,84.16 v2(167.63,83.85)
  IN1 w0.114: v2(167.63,83.85) 167.18,84.3 164.39,84.3 161.88,86.81 145.3,86.81 144.9,87.21 134.05,87.21 133.85,87.41 131.64,87.41 128.76,90.29 119.51,90.29 118.53,91.27 114.57,91.27 112.84,92.99 91.64,92.99 90.87,93.76 87.24,93.76 87.11,93.63 82.61,93.63 82.59,93.6 79.11,93.6 78.57,93.06 74.45,93.06 73.68,92.28 72.99,92.28 72.23,93.05 69.6,93.05 69.04,92.49 65.42,92.49 63.94,91 62.84,91 62.01,91 61.01,90 61.01,90 60.26,89.25 60.26,89.25 60.16,89.16 56.43,89.16 55.06,87.79 55.06,87.53 54.18,86.66 54.18,85.31 54.77,84.73 54.77,84.32 55.36,83.72 55.74,83.72 v2(55.93,83.54)
  BOTTOM w0.127: U20.G11 56.15,83.54 v2(55.93,83.54) ; CN5.23 264.33,96.83 264.03,97.13 v3(263.95,97.13)
PCIE_RXP2_CARD: length 142.3
  TOP w0.127: v2(54.11,84.11) 53.89,84.33 53.81,84.33 53.68,84.21 53.68,82.43 53.35,82.1 51.69,82.1 51.34,82.45 50.46,82.45 48.58,80.57 48.14,80.57 43.14,75.57 41.29,75.57 40.91,75.19 31.96,75.19 31.2,74.43 30.55,74.43 27.83,71.71 26.76,71.71 26.46,71.41 26.46,68.99 25.72,68.26 25.72,67.23 25.29,66.8 25.29,64.76 21.33,60.79 21.33,36.69 20.43,35.79 20.43,33.02 19.42,32.01 19.42,29.64 20.13,28.93 20.13,26.95 21.16,25.93 21.16,15.54 21.48,15.22 23.87,15.22 24.46,15.8 31.83,15.8 31.98,15.96 33.52,15.96 34.51,16.95 48.89,16.95 54.15,22.2 60.44,22.2 60.88,21.77 60.88,21.47 v3(61.16,21.19)
  BOTTOM w0.127: U20.G15 54.18,84.11 v2(54.11,84.11) ; v3(61.16,21.19) 60.87,21.48 60.87,21.74 61.08,21.95 61.66,21.95 62.07,22.36 62.07,23.07 62.17,23.17 62.48,23.17 62.6,23.29 CN13.1
PCIE_RXP3_WLAN: length 253.9
  TOP w0.127: v2(263.95,97.77) 263.09,96.91 263.09,95.34 263.47,94.95 264.23,94.95 264.61,94.57 264.61,92.89 264.34,92.63 260.73,92.63 260.31,93.05 257.83,93.05 256.2,91.41 256.2,90.4 256.81,89.79 256.81,88.9 256.13,88.22 255.01,88.22 254.27,87.48 254.27,86.7 253.92,86.34 253.92,86.05 252.35,84.49 249.58,84.49 246.81,81.72 231.89,81.72 225.06,88.54 225.06,89.5 225.06,91.4 224.95,91.52 224.95,92.27 224.88,92.34 224.29,92.93 224.1,92.93 223.58,92.93 221.51,95 212.11,95 211.86,94.75 211.21,94.75 210.96,95 210.16,95 209.63,94.47 207.84,94.47 203.93,98.38 193.66,98.38 192.93,97.64 189.28,97.64 177.24,85.6 168.76,85.6 167,83.85 v2(167,83.85)
  IN1 w0.114: v3(55.93,84.18) 55.93,84.14 55.72,83.94 55.45,83.94 54.98,84.41 54.98,84.82 54.4,85.4 54.4,86.57 55.28,87.44 55.28,87.7 55.99,88.41 56.52,88.94 60.25,88.94 60.35,89.04 60.35,89.04 61.22,89.91 61.22,89.91 62.09,90.78 62.92,90.78 62.93,90.78 64.03,90.78 65.51,92.27 69.13,92.27 69.69,92.83 72.14,92.83 72.9,92.07 73.77,92.07 74.54,92.84 78.48,92.84 78.66,92.84 79.2,93.39 82.68,93.39 82.7,93.41 87.2,93.41 87.33,93.54 90.78,93.54 91.55,92.78 112.75,92.78 114.48,91.05 118.45,91.05 119.42,90.07 128.67,90.07 131.55,87.19 133.76,87.19 133.96,86.99 144.81,86.99 145.21,86.59 161.79,86.59 164.3,84.09 166.76,84.09 v2(167,83.85)
  BOTTOM w0.127: U20.F11 56.1,84.75 55.93,84.75 55.8,84.61 55.8,84.31 v3(55.93,84.18) ; v2(263.95,97.77) 264.03,97.77 264.17,97.63 CN5.25
PCIE_TXN2_CARD: length 158.2
  TOP w0.127: v2(58.29,21.37) 58.29,21.34 57.88,20.93 57.65,20.93 57.17,21.42 54.45,21.42 48.23,15.19 32.28,15.19 32.16,15.07 25.01,15.07 24.27,14.33 20.46,14.33 19.27,13.14 11.32,13.14 10.46,14 10.46,15.25 10.74,15.52 10.74,18.06 9.26,19.54 9.26,22.92 12.44,26.09 13.02,26.09 14.27,27.34 14.27,41.74 16.63,44.11 16.63,59.8 16.12,60.3 16.12,61.98 21.36,67.22 21.36,70.12 20.21,71.27 20.21,73.39 20.49,73.67 22.21,73.67 23.23,74.68 23.89,74.68 24.5,75.29 24.5,77.45 25.01,77.96 27.01,77.96 27.44,78.39 29.35,78.39 30.08,79.13 32.02,79.13 32.48,79.58 34.38,79.58 37.84,83.04 37.84,84.18 42.16,88.5 42.16,89.51 43.32,90.68 43.65,90.68 44.24,91.27 44.24,91.67 v3(44.49,91.93)
  BOTTOM w0.127: C173.2 44.57,91.85 v3(44.49,91.93) ; CN13.5 58.6,23.27 58.68,23.19 59.15,23.19 59.28,23.06 59.28,21.36 58.93,21.01 58.54,21.01 58.29,21.27 v2(58.29,21.37)
PCIE_TXN2_CARD_C: length 4.5
  BOTTOM w0.076: 44.9,88.51 44.86,88.47 44.86,88.19 44.94,88.12 44.94,87.42 44.73,87.22 44.62,87.22 U20.B31
  BOTTOM w0.127: C173.1 44.37,90.72 44.37,90.1 44.9,89.57 44.9,88.51
PCIE_TXN3_WLAN: length 242.7
  IN1 w0.114: v3(45.92,92.08) 45.6,92.4 45.6,92.7 46,93.1 50.29,93.1 52.44,95.25 52.44,95.43 52.44,95.66 53.41,96.63 57.62,96.63 60.47,99.47 65.91,99.47 66.31,99.88 69.23,99.88 70.76,101.4 73.55,101.4 73.91,101.76 79.35,101.76 79.42,101.83 86.43,101.83 87.34,100.92 92.02,100.92 92.72,101.62 107.75,101.62 108.56,100.81 111.13,100.81 111.63,101.3 115.97,101.3 116.68,100.59 121.81,100.59 123.64,102.42 131.29,102.42 132.44,103.58 132.92,103.58 133.66,104.31 137.11,104.31 138.16,105.35 141.46,105.35 143.6,103.2 143.6,102.95 145.44,101.11 156.75,101.11 157.29,100.56 164.38,100.56 166.16,102.34 166.87,102.34 167.63,103.1 168.96,103.1 169.78,102.28 175.65,102.28 178,104.63 186.3,104.63 188.28,106.61 189.26,107.59 202.95,107.59 204.17,108.81 210.03,108.81 210.45,108.38 212.1,108.38 212.78,107.7 214.57,107.7 215,108.13 215.69,108.13 216.45,108.9 220.66,108.9 220.87,109.1 224.6,109.1 225.63,109.1 226.56,110.03 229.01,110.03 230.85,108.18 235.12,108.18 235.44,108.5 256.42,108.5 258.6,106.32 258.6,103.04 259.77,101.87 260.71,101.87 v2(261,101.58)
  BOTTOM w0.127: C171.2 45.61,91.63 45.61,91.88 45.81,92.08 v3(45.92,92.08) ; v2(261,101.58) 261.13,101.71 262.13,101.71 263.34,100.5 264.09,100.5 264.56,100.03 CN5.31
PCIE_TXN3_WLAN_C: length 4.9
  BOTTOM w0.076: U20.C29 45.59,86.64 45.28,86.95 45.28,87.86 45.51,88.09 45.51,88.5 45.53,88.52
  BOTTOM w0.127: 45.53,88.52 45.53,88.94 45.64,89.04 45.64,89.64 45.84,89.85 C171.1
PCIE_TXP2_CARD: length 158.2
  TOP w0.127: v2(43.76,91.93) 44.01,91.67 44.01,91.37 43.55,90.91 43.23,90.91 41.93,89.61 41.93,88.59 37.61,84.28 37.61,83.13 34.29,79.81 32.38,79.81 31.93,79.35 29.99,79.35 29.25,78.62 27.35,78.62 26.92,78.19 24.92,78.19 24.27,77.54 24.27,75.39 23.8,74.91 23.13,74.91 22.12,73.89 20.4,73.89 19.98,73.48 19.98,71.18 21.13,70.03 21.13,67.31 15.89,62.07 15.89,60.21 16.4,59.7 16.4,44.2 14.04,41.84 14.04,27.43 12.93,26.32 12.34,26.32 9.03,23.01 9.03,19.44 10.51,17.97 10.51,15.62 10.23,15.34 10.23,13.91 11.23,12.91 19.37,12.91 20.56,14.1 24.37,14.1 25.11,14.84 32.25,14.84 32.38,14.97 48.32,14.97 54.54,21.19 57.07,21.19 57.56,20.71 58.18,20.71 v3(58.29,20.6)
  BOTTOM w0.127: C174.2 43.93,91.75 v2(43.76,91.93) ; CN13.4 59.6,23.27 59.5,23.17 59.5,21.27 59.02,20.78 58.46,20.78 v3(58.29,20.6)
PCIE_TXP2_CARD_C: length 4.5
  BOTTOM w0.076: 44.7,88.55 44.7,88.52 44.71,88.51 44.71,88.13 44.79,88.05 44.79,87.48 44.67,87.37 44.53,87.37 44.47,87.43 U20.A31
  BOTTOM w0.127: C174.1 44.14,90.72 44.14,90 44.67,89.47 44.67,88.88 44.7,88.85 44.7,88.55
PCIE_TXP3_WLAN: length 242.7
  IN1 w0.114: v2(261,102.21) 260.88,102.09 259.86,102.09 258.82,103.13 258.82,106.41 256.51,108.72 235.35,108.72 235.03,108.4 230.94,108.4 229.1,110.24 226.47,110.24 225.54,109.31 224.69,109.31 224.69,109.31 220.78,109.31 220.57,109.11 216.36,109.11 215.6,108.35 214.91,108.35 214.48,107.92 212.87,107.92 212.19,108.6 210.54,108.6 210.12,109.02 204.08,109.02 202.86,107.8 189.17,107.8 188.62,107.25 188.13,106.76 186.21,104.84 177.91,104.84 175.56,102.49 169.87,102.49 169.05,103.31 167.54,103.31 166.78,102.56 166.07,102.56 164.29,100.78 157.38,100.78 156.84,101.33 145.53,101.33 143.82,103.04 143.82,103.29 141.55,105.57 138.07,105.57 137.03,104.53 133.57,104.53 132.84,103.79 132.35,103.79 131.2,102.63 123.55,102.63 121.72,100.81 116.77,100.81 116.06,101.52 111.54,101.52 111.04,101.02 108.65,101.02 107.84,101.83 92.63,101.83 91.93,101.14 87.43,101.14 86.52,102.05 79.33,102.05 79.26,101.98 73.82,101.98 73.46,101.62 70.67,101.62 69.14,100.09 66.22,100.09 65.82,99.69 60.38,99.69 57.54,96.84 53.32,96.84 52.23,95.75 52.23,95.34 50.2,93.32 45.91,93.32 45.38,92.79 45.38,92.26 v2(45.2,92.08)
  BOTTOM w0.127: v2(45.2,92.08) 45.38,91.9 45.38,91.58 C172.2 ; CN5.33 264.29,100.83 264.19,100.73 263.43,100.73 262.22,101.94 261.28,101.94 v2(261,102.21)
PCIE_TXP3_WLAN_C: length 4.8
  BOTTOM w0.076: 45.31,88.52 45.36,88.47 45.36,88.16 45.13,87.93 45.13,86.84 U20.B30
  BOTTOM w0.127: C172.1 45.2,90.62 45.27,90.56 45.55,90.56 45.61,90.5 45.61,89.94 45.41,89.74 45.41,89.13 45.31,89.03 45.31,88.52
PCIE_WAKE#: length 386
  TOP w0.127: v2(69.54,72.8) 69.89,73.16 74.08,73.16 76.34,75.42 76.34,76.36 77.28,77.3 77.28,77.65 79.09,79.46 79.09,80.17 79.37,80.45 80.47,80.45 81,79.91 81.52,79.91 81.53,79.9 81.76,79.9 81.8,79.86 81.99,79.86 82.29,80.16 82.29,80.84 81.91,81.22 81.91,82.61 82.21,82.91 82.21,84.19 83.29,85.27 83.29,86.98 84.5,88.19 85.67,88.19 86.28,88.8 86.94,88.8 88.24,90.1 91.21,90.1 91.21,90.1 95.95,90.1 96.77,89.27 98.06,89.27 98.61,89.83 100.44,89.83 101.83,88.44 104.5,88.44 104.5,88.43 107.22,88.43 107.22,88.44 107.43,88.44 110.58,88.44 110.58,88.43 111.74,88.43 111.74,88.44 111.95,88.44 116.77,88.44 120.69,92.36 122.88,92.36 123.44,91.8 123.44,85.35 124.78,84 129.74,84 131.07,85.33 135.01,85.33 138.21,82.14 152.05,82.14 152.11,82.2 153.5,82.2 155.56,80.14 162.34,80.14 163.56,78.92 171.97,78.92 172.83,79.79 176.33,79.79 177.05,79.06 179.61,79.06 180.15,79.61 180.15,83.04 183.43,86.31 183.43,88.59 189.8,94.96 194.44,94.96 195.27,94.14 197,94.14 197.38,94.52 204.31,94.52 204.56,94.77 205.5,94.77 207.18,93.1 207.51,93.1 208.02,92.59 214.24,92.59 215.05,93.4 215.99,93.4 v2(216.5,93.91) ; v2(42.16,73.39) 33.72,73.39 31.94,71.61 31.49,71.61 30.98,71.1 30.6,71.1 30.2,70.7 30.2,67.68 29.74,67.21 29.71,67.21 28.69,66.2 28.69,64.76 23.55,59.62 23.55,57.95 23.78,57.72 23.78,41.76 24.59,40.96 24.59,33.68 25.52,32.75 25.52,28.3 28.5,25.32 33.79,25.32 35.11,23.99 35.11,22.71 39.22,18.6 47.06,18.6 v2(50.67,22.2) ; v2(54.6,74.02) 54.81,73.82 57.22,73.82 58.16,72.88 60.06,72.88 60.38,72.56 v2(60.38,72.33) ; v2(221.45,102.55) 221.45,102.49 221.61,102.34 221.61,100.89 223.2,99.3 223.2,98.5 227.06,94.64 227.06,88.88 230.32,85.63 231.18,85.63 231.59,85.22 231.59,84.25 232.38,83.46 246.29,83.46 248.45,85.62 251.88,85.62 v1(252.58,86.33) 252.77,86.52 252.77,87.64 254.7,89.57 254.7,92.16 257.22,94.67 258.97,94.67 260.72,96.42 260.72,97.01 v2(260.22,97.52)
  IN1 w0.089: 63.39,71.93 62.59,71.93 62.53,71.99 61.13,71.99 60.81,72.31 60.4,72.31 v2(60.38,72.33)
  IN1 w0.127: v2(69.54,72.8) 69.54,72.9 69.18,73.26 67.02,73.26 65.69,71.93 63.39,71.93 ; v2(54.6,74.02) 53.84,74.78 53.13,74.78 50.89,72.55 50.18,72.55 49.09,73.64 42.41,73.64 v2(42.16,73.39)
  BOTTOM w0.127: R360.1 69.98,72.36 v2(69.54,72.8) ; v2(60.38,72.33) 60.38,72.05 U20.AJ5 ; CN13.12 51.6,23.14 v2(50.67,22.2) ; Q12.3 259.58,98.15 v2(260.22,97.52) ; v2(221.45,102.55) 220.63,101.72 219.18,101.72 U7.72 218.2,101.76 218.03,101.58 218.03,101.05 217.67,100.69 217.11,100.69 216.18,99.76 216.18,95.47 216.5,95.15 v2(216.5,93.91)
PD#: length 15
  BOTTOM w0.127: U18.39 218.82,83.29 218.94,83.42 219.8,83.42 220.24,82.99 v2(220.46,82.99) 220.51,82.99 221.91,84.39 221.91,84.94 222.12,85.15 223.33,85.15 223.88,85.69 R245.2 223.88,86.94 224.03,87.09 R237.1 225.26,87.09 225.48,87.31 Q18.3 227.42,87.31 228.34,86.39 D10.2
PIRQC#: length 16.5
  IN1 w0.076: 62.21,80.52 63.12,81.43 63.41,81.43 64.38,82.4 64.38,82.93
  IN1 w0.089: v2(61.16,80.12) 61.56,80.52 62.21,80.52
  IN1 w0.127: v2(70.85,88.14) 70.27,88.73 69.23,88.73 68.29,87.79 66.54,87.79 64.38,85.63 64.38,82.93
  BOTTOM w0.127: v2(61.16,80.12) 60.86,80.42 U20.N4 ; R203.1 71.09,88.38 v2(70.85,88.14)
PIRQD#: length 10.8
  BOTTOM w0.076: U20.N2 62.46,80.2 63,80.2 63.26,80.46 64.13,80.46 64.37,80.22 64.67,80.22 64.91,80.47 64.91,81.34 65.27,81.69 65.42,81.69
  BOTTOM w0.127: 65.42,81.69 66.11,81.69 67.14,80.66 67.16,80.66 67.3,80.52 67.86,80.52 68.14,80.24 68.18,80.24 R285.1 68.46,79.85 68.72,79.58 69.13,79.58 69.33,79.79 69.33,79.81 69.59,80.07 69.77,80.07 70.03,80.33 R272.2
PIRQD#_L: length 195
  TOP w0.127: v2(212.21,107.55) 210.77,106.11 v1(210.77,106.06) 210,105.29 v2(210,104.88) ; v2(70.78,87.51) 70.83,87.51 71.21,87.13 71.9,87.13 72.23,87.46 72.23,88.72 71.67,89.28 71.67,91.34 72.38,92.05 72.38,93.45 73.37,94.43 73.37,94.43 73.57,94.64 74.82,94.64 75.57,95.38 78.47,95.38 78.89,95.38 79.58,96.07 85.91,96.07 86.33,96.07 86.88,96.61 88.21,96.61 88.7,96.12 90.55,96.12 91.05,96.61 91.36,96.61 91.79,96.61 92.37,97.2 95.46,97.2 95.99,96.67 98.22,96.67 98.79,96.09 105.4,96.09 105.83,96.09 106.21,95.71 113.41,95.71 113.76,96.07 116.25,96.07 v2(118.36,98.18)
  IN2 w0.127: v2(118.36,98.18) 118.36,98.16 120.57,95.94 121.89,95.94 123.23,94.59 131.44,94.59 132.61,93.43 133.11,92.92 136.79,92.92 136.83,92.96 138.43,92.96 140.96,95.48 145.79,95.48 146.04,95.23 146.04,93.51 146.41,93.15 153.78,93.15 156.52,90.4 165.79,90.4 166,90.4 167.91,88.5 173.01,88.5 175.16,90.65 175.62,90.65 175.98,90.65 180.9,95.58 182.12,95.58 185.71,99.17 189.12,99.17 190.42,100.46 v2(191.97,100.46) 191.97,100.89 193.15,102.08 193.65,102.08 194.3,102.72 196.33,102.72 196.54,102.93 197.02,102.93 198.35,104.26 198.71,104.26 202.77,104.26 203.35,104.26 203.87,104.78 205.79,104.78 206.18,105.17 209.71,105.17 v2(210,104.88)
  BOTTOM w0.127: v2(70.78,87.51) 70.83,87.51 71.15,87.19 71.91,87.19 72.04,87.07 R239.1 72.27,86.82 72.66,86.43 72.66,86.04 72.38,85.76 72.18,85.76 72.01,85.58 72.01,83.06 71.63,82.68 71.63,82.39 71.44,82.2 71.29,82.2 70.57,81.48 70.57,81.12 70.55,81.11 70.55,80.61 R272.1 ; R39.1 213.31,108.93 213.03,108.66 213.03,107.57 212.89,107.42 212.34,107.42 v2(212.21,107.55) ; v2(191.97,100.46) 192.17,100.26 192.81,100.26 193.49,99.57 193.89,99.57 195.05,98.4 196.18,98.4 196.38,98.2 196.38,96.93 196.19,96.74 196.19,95.61 196.07,95.48 196.07,93.79 195.32,93.04 195.32,91.49 195.83,90.98 195.83,89.52 R212.1
PLTRST#: length 453.5
  TOP w0.076: 64,71.99 60.57,71.99 60.53,71.95 59.31,71.95 59.15,72.11 v2(59.15,72.32)
  TOP w0.114: v2(209.39,100.56) 209.39,99.7 210.64,98.45 211.02,98.45 211.38,98.09 218.48,98.09 220.2,99.82 221.96,99.82 222.7,99.08 222.7,98.29 226.1,94.88 226.1,93.27 226.56,92.82 226.56,88.68 231.09,84.15 231.09,84.04 232.17,82.96 246.5,82.96 248.66,85.12 252.09,85.12 253.28,86.31 253.28,87.43 255.21,89.36 255.21,91.88 257.34,94.01 v1(262.58,94.01) 263.64,94.01 v2(263.95,94.32) ; v2(39.74,73.89) 39.58,74.05 33.68,74.05 31.74,72.11 31.28,72.11 30.91,71.74 29.51,71.74 29.3,71.53 29.3,67.54 26.45,64.69 26.45,63.23 23.05,59.82 23.05,57.74 23.23,57.56 23.23,38.05 23.87,37.41 23.87,33.25 23.74,33.13 23.74,29.82 24.5,29.06 24.5,28.01 27.7,24.81 33.58,24.81 34.61,23.78 34.61,22.5 39.02,18.09 47.31,18.09 v2(51.43,22.2) ; v2(205.48,94.16) 204.77,93.45 202.51,93.45 201.94,94.02 197.59,94.02 197.2,93.64 194.88,93.64 194.05,94.46 190.01,94.46 183.98,88.43 183.98,86.05 180.66,82.73 180.66,79.4 179.82,78.56 176.84,78.56 176.12,79.29 173.04,79.29 172.05,78.29 163.12,78.29 161.79,79.63 155.36,79.63 153.29,81.7 152.32,81.7 152.26,81.63 138,81.63 134.81,84.83 131.28,84.83 129.95,83.5 124.99,83.5 124.57,83.5 122.93,85.14 122.93,91.59 122.67,91.86 120.9,91.86 116.91,87.87 101.69,87.87 101.09,88.47 98.04,88.47 97.73,88.77 96.23,88.77 96.18,88.82 94.82,88.82 v2(94.71,88.93) 93.89,88.93 93.41,89.41 92.02,89.41 88.26,89.41 87.15,88.3 86.49,88.3 85.88,87.69 84.71,87.69 83.79,86.78 83.79,85.06 83.17,84.44 83.17,84.08 83.25,83.99 83.25,83.19 82.71,82.65 82.71,82.12 v2(82.52,81.92) ; v2(71.01,67.04) 71.01,67.75 70.19,68.57 68.39,68.57 67.38,69.58 66.41,69.58 64,71.99
  IN1 w0.127: v2(205.25,96.09) 205.25,94.39 v2(205.48,94.16) ; v2(13.71,81.72) 14.08,81.72 14.2,81.83 15.45,81.83 15.91,82.29 15.91,83.37 16.76,84.23 19.68,84.23 19.96,83.95 22,83.95 22.24,84.18 27.18,84.18 27.73,83.63 27.73,80.85 33.28,75.3 37.41,75.3 38.81,73.89 v2(39.74,73.89) 40.76,73.89 41.39,74.53 49.41,74.53 49.6,74.72 51.81,74.72 52.76,75.67 53.21,75.67 53.46,75.93 54.22,75.93 54.6,75.54 54.6,74.88 55.24,74.25 56.74,74.25 58.17,72.83 58.64,72.83 v2(59.15,72.32)
  BOTTOM w0.114: U20.AG7 59.15,72.53 v2(59.15,72.32) ; CN5.22 265.98,96.43 265.85,96.3 265.85,94.63 265.65,94.43 CN5.17 264.06,94.43 v2(263.95,94.32) ; v2(94.71,88.93) 94.71,88.93 94.56,88.78 94.56,87.81 94.64,87.73 94.64,87.72 94.76,87.6 94.76,86.8 97.5,84.06 97.78,84.06 97.78,84.05 101.97,84.05 103.39,82.64 U15.16 ; v2(82.52,81.92) 82.52,80.97 82.73,80.76 82.73,77.66 77.79,72.72 77.79,68.78 77.44,68.43 77.44,67.47 76.76,66.79 72.81,66.79 72.58,67.02 71.91,67.02 71.51,66.62 R383.2 71.32,66.45 71.01,66.76 v2(71.01,67.04) ; R307.1 12.95,78.9 13.66,79.62 13.66,81.67 v2(13.71,81.72) ; CN13.11 52.6,23.38 v2(51.43,22.2) ; U7.13 204.46,96.96 205.25,96.17 v2(205.25,96.09) 205.45,95.89 206.32,95.89 207.51,94.7 208.55,94.7 209.49,95.64 209.49,100.46 v2(209.39,100.56)
PM_BATLOW#: length 14.2
  BOTTOM w0.076: 63.39,68.04 63.23,68.04 63.05,68.21 61.97,68.21 61.84,68.34 61.84,68.72 61.66,68.9 61.38,68.9 61.06,69.22 U20.AN4
  BOTTOM w0.127: 63.39,68.04 64.34,68.04 65.14,67.23 65.14,63.12 66.44,61.83 66.44,60.28 v2(66.59,60.13) 66.46,60 66.21,60 65.69,59.48 R428.1
PM_EXTTS#0: length 43
  IN1 w0.127: v2(74.01,58.1) 74.38,57.73 74.38,57.22 76.08,55.52 76.08,52.82 71.87,48.62 71.87,36.94 69.08,34.14 69.08,32.81 68.53,32.26 v2(68.45,32.26)
  BOTTOM w0.127: R462.2 67.56,27.03 67.3,27.28 67.3,27.92 66.95,28.27 JDIM1.198 66.95,31.33 67.89,32.26 v2(68.45,32.26) ; v2(74.01,58.1) 74.19,57.92 76.94,57.92 77.52,57.33 v2(77.64,57.33) 77.64,56.86 78.53,55.96 U21.6
PM_THRMTRIP#: length 219.4
  IN1 w0.127: v2(15.61,93.12) 14.6,94.14 14.6,96.5 15.28,97.19 15.28,97.92 15.79,98.43 15.79,99.12 15.66,99.24 15.66,100.36 21.53,106.23 21.53,107.09 23.11,108.67 28.24,108.67 29.94,106.96 32.2,106.96 35.63,103.53 41.38,103.53 42.38,102.52 42.38,101 44.6,98.78 51.14,98.78 51.3,98.94 51.76,98.94 52.09,98.6 57.2,98.6 59.47,100.87 61.28,100.87 61.97,101.56 65.84,101.56 66.91,101.56 67.72,102.37 69.41,102.37 70.1,103.05 72.23,103.05 72.43,103.26 78.12,103.26 78.61,103.74 106.8,103.74 107.28,104.22 117.42,104.22 118.05,103.59 120.03,103.59 120.81,104.36 128.38,104.36 129.19,105.17 130.84,105.17 131.84,106.18 134.05,106.18 135.07,107.19 144.49,107.19 146.55,105.14 148.2,105.14 148.71,104.63 163.26,104.63 164.73,106.09 167.41,106.09 167.61,105.9 172.23,105.9 172.86,106.53 181.6,106.53 183.82,108.76 187.51,108.76 v2(187.95,109.2)
  BOTTOM w0.127: R213.2 18.84,88.5 18.29,87.95 16.44,87.95 15.63,88.77 15.63,92.3 v2(15.61,92.31) v2(15.61,93.12) ; Q4.1 198.75,109.99 198.47,109.71 R32.1 C19.1 198.1,110.7 197.87,110.93 196.41,110.93 196.13,111.21 189.96,111.21 v2(187.95,109.2)
PROC_DETECT#: length 11.2
  BOTTOM w0.076: U20.D61 25.26,86.14 25.26,86.37 24.97,86.66 24.39,86.66 24.32,86.73 24,86.73 23.78,86.95 23.26,86.95
  BOTTOM w0.127: TP81.1 16.18,87.37 18.54,87.37 19.05,87.88 21.65,87.88 22.58,86.95 23.26,86.95
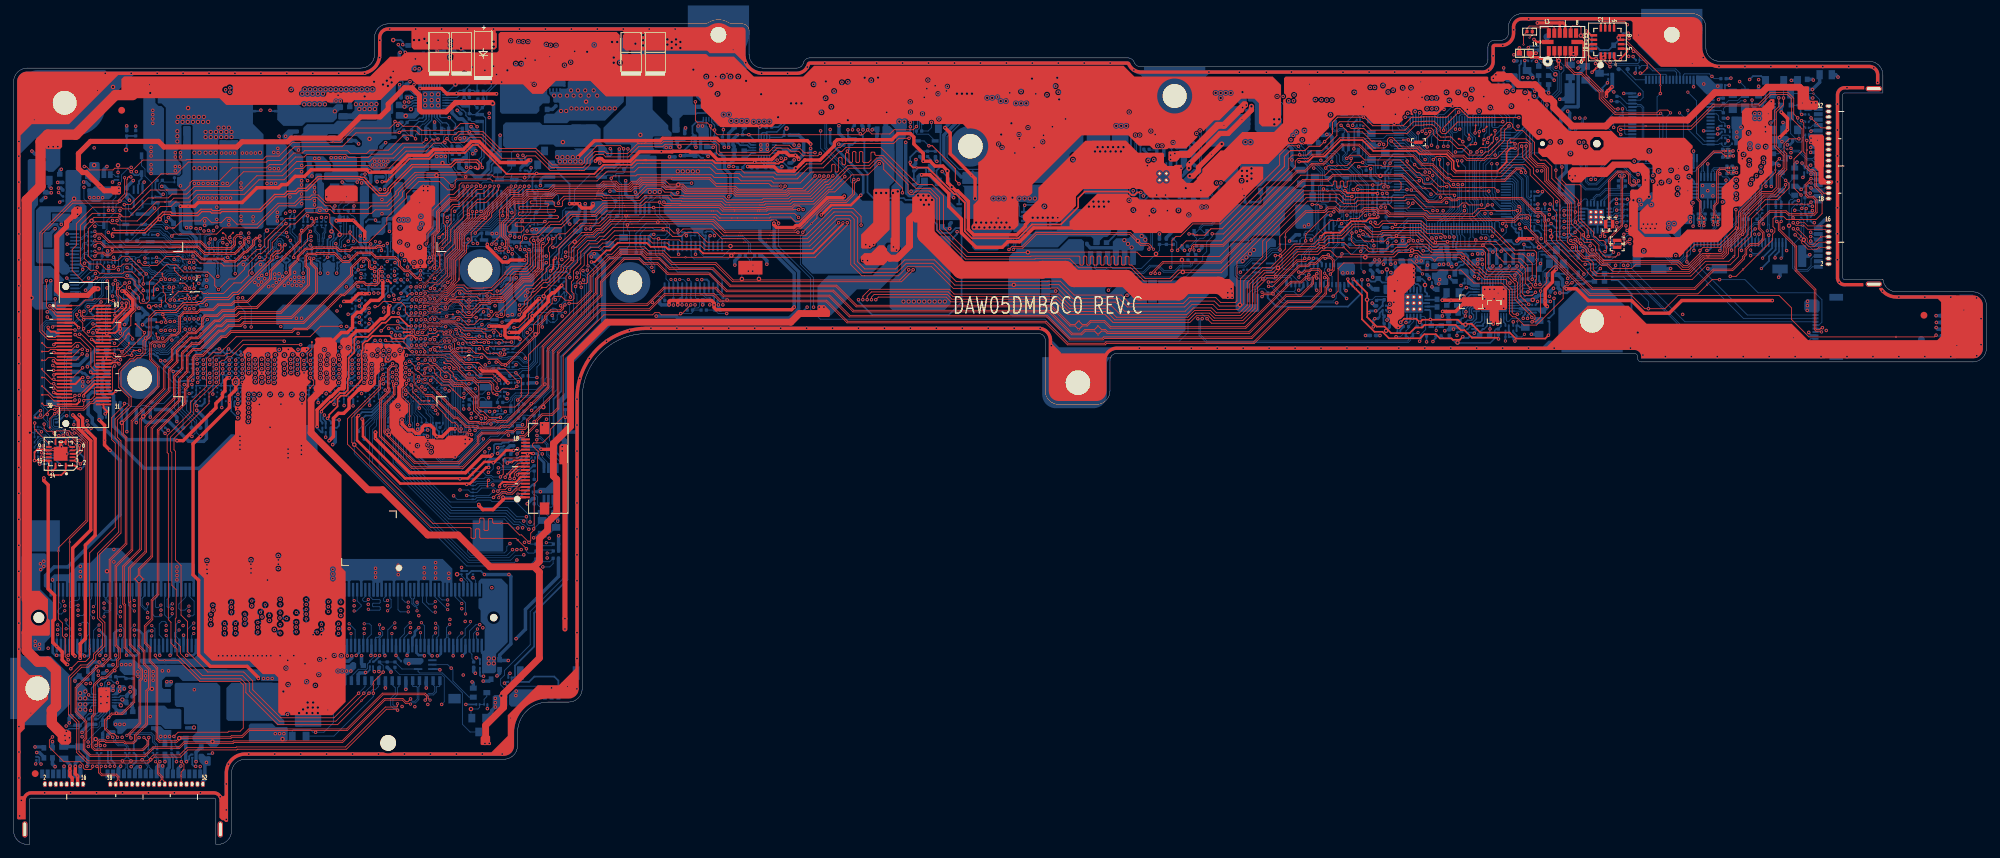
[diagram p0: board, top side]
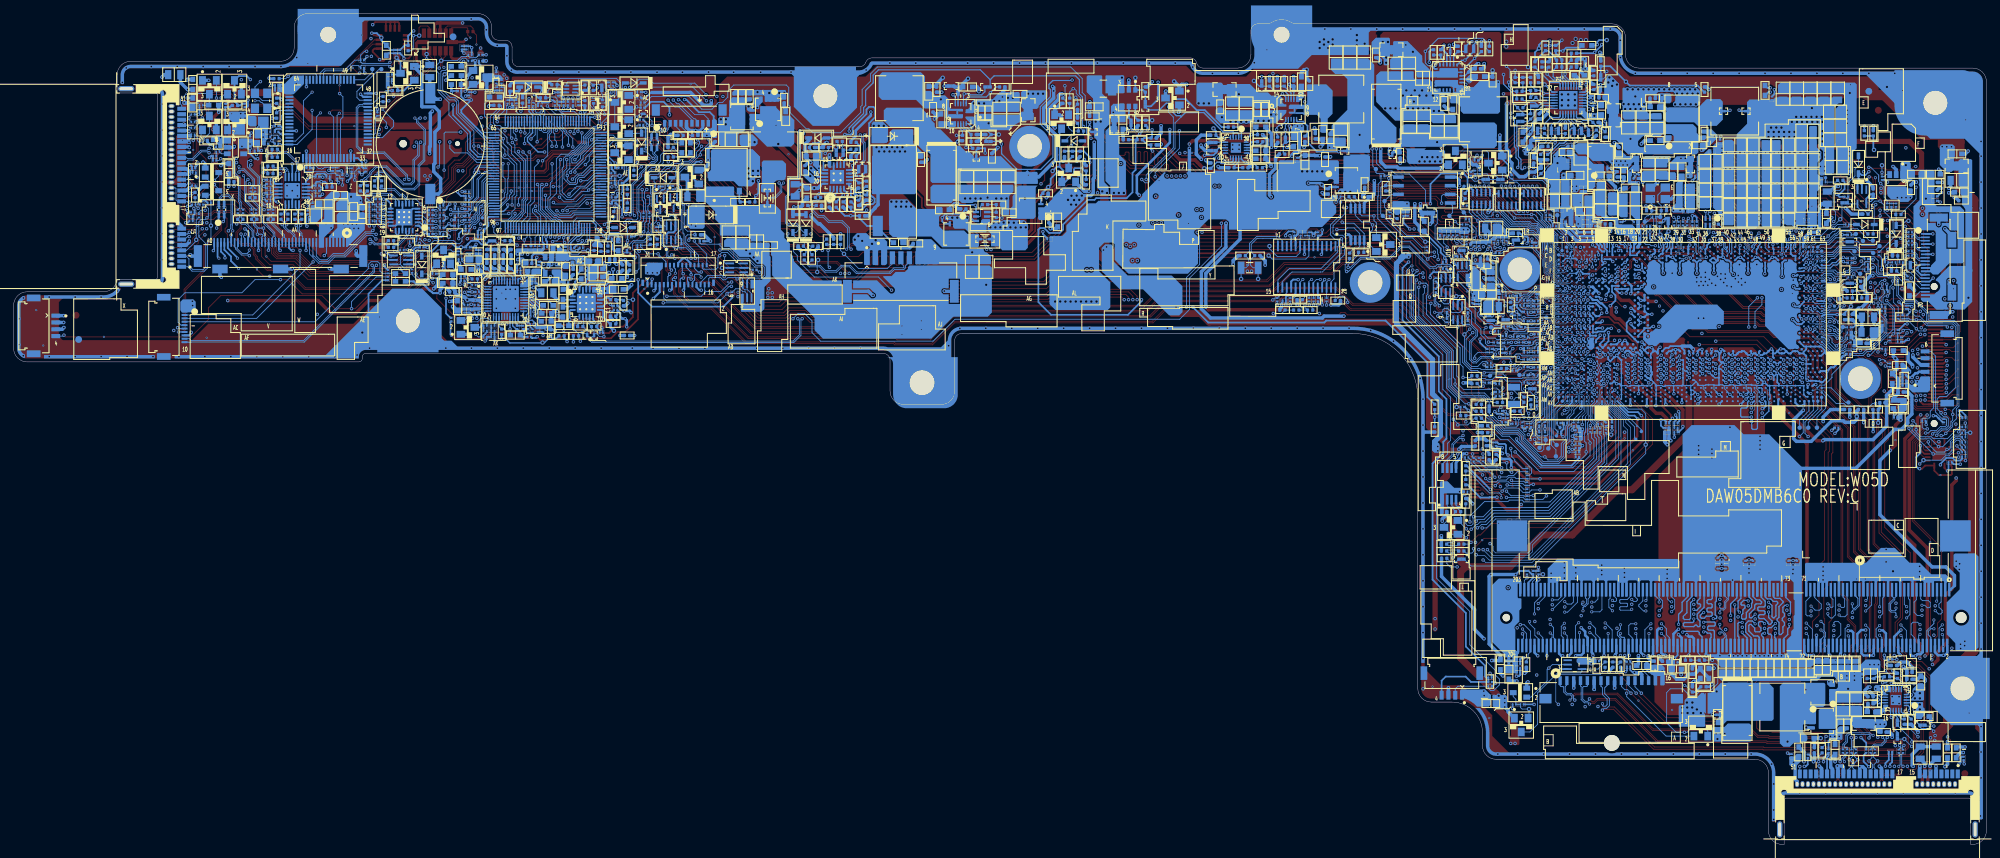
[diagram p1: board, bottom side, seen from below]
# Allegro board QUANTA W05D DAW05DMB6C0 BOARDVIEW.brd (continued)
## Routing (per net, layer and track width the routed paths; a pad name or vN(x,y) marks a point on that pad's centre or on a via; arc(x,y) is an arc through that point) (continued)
PROC_OPI_RCOMP: length 34.7
  TOP w0.381: v2(50.67,62.97) 50.42,62.73 50.42,59.35 v1(51.91,57.86) 56.78,52.99 67.02,52.99 69.38,55.35 v2(69.77,55.35)
  BOTTOM w0.254: U20.AY15 52.59,63.48 51.17,63.48 v2(50.67,62.97)
  BOTTOM w0.381: v2(69.77,55.35) 69.77,56.32 70.06,56.61 71.23,56.61 71.88,57.27 R440.2
PROCHOT#: length 4.6
  BOTTOM w0.076: 23.26,82.28 23.94,82.28 U20.K63
  BOTTOM w0.127: R261.2 20.63,82.91 21.07,82.91 21.91,82.07 22.45,82.07 22.65,82.28 23.26,82.28
PROCPWRGD: length 9.3
  BOTTOM w0.076: U20.C61 25.84,86.5 25.84,87.33 25.76,87.41 25.76,87.86 25.54,88.08 25.22,88.08 25.19,88.12
  BOTTOM w0.127: TP78.1 19.3,89.51 R200.2 19.82,89.73 20.06,89.97 21.38,89.97 21.96,89.39 22.19,89.39 23.2,88.37 24.93,88.37 25.19,88.12
PWR_DEBUG: length 43.2
  TOP w0.127: CN1.53 14.41,75.61 15.11,76.31 15.11,76.98 16.98,78.86 16.98,79.74 16.73,79.99 16.12,79.99 15.36,80.75 15.36,81.51 15.61,81.77 15.69,81.77 v2(16.35,82.43)
  IN1 w0.127: v2(16.35,82.43) 16.5,82.58 16.5,82.78 16.73,83.01 16.88,83.01 17.19,83.32 20.06,83.32 20.19,83.44 22.21,83.44 22.45,83.67 26.97,83.67 v2(27.25,83.39)
  IN2 w0.127: v2(22.42,91.47) 23.11,90.78 23.11,90.15 23.74,89.51 23.74,87.97 25.77,85.94 26.66,85.94 27.25,85.34 v2(27.25,83.39)
  BOTTOM w0.127: U20.H59 27.08,83.57 v2(27.25,83.39) ; TP67.1 23.63,97.88 R97.2 22.1,97.26 R96.1 21.3,96.97 21.3,96.28 21.58,96 22.16,96 22.5,95.67 22.5,93.22 22.17,92.89 22.17,91.72 v2(22.42,91.47)
R_SPK+: length 52
  IN1 w0.635: v3(259.55,86.09) 259.55,84.77 254.35,79.56 254.28,79.56 254.26,79.53 234.7,79.53 233.96,79.53 233.94,79.56 233.9,79.56 233.24,80.22 231.92,80.22 230.81,81.33 230.81,81.55 228.45,83.9 227.96,83.9 227.07,83.01 226.92,82.86 225.54,82.86 224.71,83.7 222.05,83.7 220.82,84.93 v2(220.78,84.93)
  BOTTOM w0.203: C210.1 219.71,84.05 218.66,84.05 218.02,83.41 U18.37
  BOTTOM w0.254: v3(259.55,86.09) 259.75,86.28 CN6.39
  BOTTOM w0.508: v2(220.78,84.93) 220.4,84.55 C210.1
R_SPK-: length 51.1
  IN1 w0.635: v3(219.64,84.93) 220.44,85.73 221.18,85.73 222.32,84.59 225.06,84.59 225.9,83.75 226.76,83.75 227.65,84.64 228.76,84.64 232.29,81.11 233.65,81.11 234.33,80.42 253.89,80.42 258.67,85.2 v2(258.67,86.14)
  BOTTOM w0.203: U18.36 217.62,83.53 218.44,84.36 218.61,84.36 218.8,84.55 C211.1
  BOTTOM w0.254: CN6.38 259.25,87.05 258.67,86.47 v2(258.67,86.14)
  BOTTOM w0.508: C211.1 219.26,84.55 v3(219.64,84.93)
REGN6V: length 37.4
  BOTTOM w0.254: PU7.16 170.71,99.02 170.78,99.09 170.78,100.44 171.05,100.7 171.05,101.57 171.32,101.83 172.46,101.83 172.85,102.22 PC87.2 172.85,102.46 172.33,102.98 171.57,102.98 170.81,103.74 PD4.2 169.54,103.74 169.41,103.87 168.01,103.87 v2(167.63,104.25) 166.74,104.25 166.49,104.5 166.49,105.23 164.46,107.27 164.46,107.93 164.08,108.31 163.44,108.31 163.19,108.06 163.19,106.79 164.08,105.9 164.08,100.11 163.97,100.01 163.97,98.3 163.9,98.23 163.9,95.37 163.64,95.12 163.56,95.12 163.26,94.82 163.26,94.29 163.54,94.01 164.36,94.01 165.11,93.25 166.04,93.25 166.23,93.45 166.23,93.93 166.65,94.35 PR109.2
REQ_WLAN#: length 6.3
  BOTTOM w0.127: CN5.7 264.31,87.23 262.88,88.65 v4(262.88,88.78) 262.88,91.67 262.5,92.05 R152.1
RF_LINK#: length 87.6
  TOP w0.127: v2(252.09,83.42) 252.95,83.42 v1(253.97,84.43) 258.31,88.78 258.31,89.62 258.64,89.95 258.64,90.43 258.36,90.71 258.36,91.9 258.64,92.18 259.94,92.18 260.35,91.76 264.7,91.76 265.57,92.64 265.57,95.48 264.51,96.55 264.51,98.49 264.13,98.87 263.69,98.87 263.07,99.48 263.07,101.49 262.88,101.68 262.88,105.95 v2(262.55,106.28)
  IN1 w0.127: CN5.46 262.8,106.03 v2(262.55,106.28) ; v2(252.09,83.42) 250.11,83.42 249.81,83.11 237.16,83.11 237.16,83.11 235.55,83.11 235.54,83.11 235.5,83.11 232.35,86.26 232.35,86.28 232.35,86.81 232.35,86.81 232.35,87.71 231.51,88.55 231.28,88.55 229.49,90.34 228.6,90.34 228.31,90.05 227.09,90.05 226.59,89.54 225.66,89.54 224.89,90.3 222.54,90.3 222.21,89.97 220.38,89.97 219.72,89.32 219.72,89.31 v2(217.14,89.31)
  IN2 w0.127: v2(217.14,89.31) 216.81,89.64 211.17,89.64 210.86,89.34 v2(210.86,89.18)
  BOTTOM w0.127: R52.1 262.95,106.28 v2(262.55,106.28) ; U7.114 210.7,89.35 v2(210.86,89.18)
RF_OFF: length 258
  TOP w0.127: v2(262.17,103.61) 260.72,103.61 259.99,102.88 259.99,101.83 260.39,101.43 260.39,99.09 259.4,98.1 259.4,96.17 258.59,95.36 257.01,95.36 254.07,92.42 254.07,90.06 251.58,87.57 251.58,86.88 250.97,86.26 248.93,86.26 248.19,86.26 246.03,84.1 234.87,84.1 233.98,84.99 233.21,84.99 231.93,86.28 231.34,86.28 230.66,86.28 229.66,87.28 229.66,87.94 229.24,88.36 228.93,88.36 228.68,88.61 v2(228.68,88.69) ; v2(132.09,84.38) 132.09,84.33 130.4,82.63 105.55,82.63 103.01,85.17 96.61,85.17 95.24,86.54 92.96,86.54 92.37,87.13 89.2,87.13 88.1,86.02 87.56,86.02 84.92,83.39 84.92,81.22 75.6,71.89 75.6,66.19 73.63,64.22 v2(71.29,64.22) 71.19,64.11 68.45,64.11 68.32,64.24 68.32,67.21 67.42,68.1 65.24,68.1 TP55.1 64.56,68.79 64.56,69.17 63.97,69.75 v2(63.97,70)
  IN2 w0.127: v2(132.09,84.38) 132.31,84.6 153.34,84.6 157.9,80.04 171.12,80.04 172.11,81.03 173.25,81.03 175.46,81.03 179.17,84.74 180.94,84.74 183.02,86.83 183.02,87.87 188.14,92.98 192.05,92.98 192.97,93.91 194.57,93.91 194.92,94.26 197.53,94.26 198.32,95.05 199.32,95.05 199.75,95.05 199.75,95.05 202.05,95.05 204.03,97.03 205.35,97.03 205.88,96.5 205.93,96.5 206.9,96.5 207.38,96.98 208.32,96.98 209.17,97.83 212.5,97.83 213.08,97.25 218.44,97.25 220.01,95.68 220.01,90.14 220.91,89.24 221.35,89.24 222.65,87.94 222.86,87.94 222.86,87.94 227.38,87.94 228.14,88.7 228.15,88.69 v2(228.68,88.69)
  BOTTOM w0.076: U20.AM2 62.32,70 62.62,70.3 63.01,70.3 63.13,70.41 63.39,70.41
  BOTTOM w0.127: 63.39,70.41 63.56,70.41 v2(63.97,70) ; Q6.2 262.17,104.73 v2(262.17,103.61) ; R396.1 71.63,63.91 71.33,64.22 v2(71.29,64.22)
RSMRST#: length 199.7
  IN2 w0.127: v2(216.97,92.65) 216.5,92.18 214.46,92.18 214.22,91.94 211.84,91.94 210.25,93.53 207.55,93.53 206.3,92.28 204.82,92.28 202.66,90.12 202.1,90.12 202.05,90.18 201.52,90.18 200.69,89.35 198.94,89.35 198.24,88.65 197.54,88.65 196.65,87.76 194.98,87.76 192.59,87.76 191.85,87.03 190.69,87.03 189.23,87.03 187.79,85.58 187.79,80.57 183.18,75.96 156.39,75.96 153.41,78.95 120.74,78.95 120.01,79.68 114.06,79.68 113.48,79.1 105.3,79.1 102.76,81.64 94.45,81.64 92.63,79.82 86.4,79.82 77.87,71.29 77.87,63.1 78.26,62.71 v2(78.26,62.44)
  BOTTOM w0.076: U20.AW6 59.44,65.68 59.15,65.39 59.15,63.89 59.43,63.61
  BOTTOM w0.127: v2(216.97,92.65) 217.07,92.56 U7.95 ; 59.43,63.61 60.6,62.44 R409.1 60.8,61.94 61,61.74 61,61.37 61.26,61.12 61.26,59.19 61.82,58.63 61.82,56.92 62.78,55.95 65.17,55.95 68.52,59.3 68.52,59.84 68.93,60.25 71.07,60.25 71.98,61.17 72.16,61.17 72.91,61.92 74.39,61.92 74.93,62.45 R401.2 75.18,62.59 76.17,61.6 v2(77.64,61.6) 77.64,61.82 v2(78.26,62.44)
RTC_RST#: length 242.8
  TOP w0.127: v2(57.57,66.71) 59.65,64.62 59.66,64.62 61.82,64.62 63.37,63.06 63.37,62.91 64.38,61.91 64.81,61.91 65.27,61.44 65.27,60.74 65.45,60.56 66.63,60.56 66.82,60.37 67.06,60.37 v2(67.25,60.18) ; v2(215.56,93.91) 213.63,93.91 213.35,94.19 212.74,94.19 212.16,93.6 v1(211.42,93.6) 207.43,93.6 205.71,95.33 204.36,95.33 204.06,95.03 197.17,95.03 196.79,94.65 195.51,94.65 194.69,95.47 189.59,95.47 179.65,85.53 179.65,79.82 179.4,79.57 177.26,79.57 176.54,80.29 172.62,80.29 171.76,79.43 163.91,79.43 162.67,80.68 155.74,80.68 153.71,82.71 151.9,82.71 151.84,82.64 138.42,82.64 137.04,84.02 135.23,85.84 130.86,85.84 129.53,84.51 124.99,84.51 123.94,85.56 123.94,92.01 123.09,92.87 120.48,92.87 116.56,88.94 111.74,88.94 111.53,88.94 111.53,88.94 110.79,88.94 110.79,88.94 107.22,88.94 107.01,88.94 107,88.94 106.27,88.94 106.27,88.94 105.13,88.94 104,88.94 102.57,90.38 98.31,90.38 97.71,89.78 96.98,89.78 96.16,90.61 91,90.61 91,90.61 88.03,90.61 86.73,89.31 86.07,89.31 85.46,88.7 84.29,88.7 82.78,87.2 82.78,85.48 81.7,84.4 81.7,84 81.12,83.42 81.12,81.29 81.78,80.62 v2(81.78,80.37)
  IN1 w0.127: v2(81.78,80.37) 82.03,80.12 82.03,79.29 81.36,78.62 79.93,78.62 79.54,78.24 79.54,75.98 76.16,72.59 76.16,70.44 75.06,69.34 75.06,65.4 73.27,63.61 73.27,62.79 70.5,60.03 70.5,58.04 70.1,57.64 v2(69.21,57.64) 69.31,57.74 69.31,58.83 69.49,59.01 69.49,59.7 69.01,60.18 v2(67.25,60.18)
  BOTTOM w0.127: v2(57.57,66.71) 58.33,66.71 U20.AU7 ; v2(215.56,93.91) 215.56,94.83 215.29,95.1 215.29,96.13 215.3,96.13 215.3,100.13 216.6,101.44 216.6,102.49 217.24,103.13 217.24,103.82 218.48,105.06 218.93,105.06 218.94,105.06 219.87,105.06 220.21,105.41 220.21,106.61 220.54,106.94 220.54,108.74 219.8,109.48 R31.2 219.73,109.83 219.73,110.7 219.23,111.19 C15.1 218.69,111.63 R22.2 ; R447.2 67.12,54.19 66.79,54.53 66.79,55.22 v2(69.21,57.64)
RTC_X1: length 15.6
  IN1 w0.127: v2(67.2,62.59) 63.57,62.59 62.43,63.73 v2(61.97,63.73)
  BOTTOM w0.076: 61.66,63.68 61.46,63.68 61.21,63.94 61.21,64.17 60.56,64.82 60.56,65.37 U20.AW5
  BOTTOM w0.127: 61.66,63.68 61.92,63.68 v2(61.97,63.73) ; Y4.1 69.38,66.65 68.85,66.12 68.38,66.12 67.95,65.7 R386.1 67.3,65.7 67.27,65.7 C278.1 67.1,65.11 67.3,65.11 67.38,65.03 67.38,64.78 67.47,64.66 67.47,64.62 67.54,64.55 67.56,64.53 67.56,63.65 v2(67.2,63.29) v2(67.2,62.59)
RTC_X2: length 14.9
  IN1 w0.127: v3(62.27,63.2) 63.42,62.06 67.51,62.06 67.89,62.44 v3(67.89,62.72)
  BOTTOM w0.076: U20.AY5 60.23,64.9 60.95,64.18 60.95,63.94 61.44,63.46
  BOTTOM w0.127: 61.44,63.46 61.69,63.2 v3(62.27,63.2) ; Y4.2 69.38,65.31 69.08,65.61 68.61,65.61 R386.2 68.06,64.77 68.06,64.08 C281.1 68.26,63.38 68.26,63.09 v3(67.89,62.72)
S5_ON: length 156.2
  TOP w0.127: v2(217.54,104.81) 217.54,104.12 217.34,103.92 217.34,103.26 v1(217.06,102.98) 216.4,102.32 215.41,102.32 214.9,101.81 v2(214.9,101.68)
  IN2 w0.127: v2(217.54,104.81) 217.54,105.03 216.86,105.72 216.86,105.72 216.3,106.28 216.3,106.28 216.27,106.3 214.72,106.3 212.64,108.39 210.03,108.39 209.65,108.77 206.85,108.77 206.41,108.34 203.79,108.34 203.77,108.31 203.75,108.31 202.38,106.94 194.68,106.94 193.77,107.85 191.3,107.85 189.65,106.2 187.81,106.2 187.81,106.2 187.37,106.2 185.6,104.44 178.01,104.44 174.74,101.17 173.19,101.17 171.19,99.17 165.42,99.17 164.23,100.36 156.58,100.36 155.49,101.45 144.9,101.45 144.65,101.71 v2(144.65,102.85) ; v2(134.26,112.25) 133.67,112.83 117.52,112.83 116.53,111.84 107.33,111.84 v2(106.42,112.76)
  BOTTOM w0.127: PR22.2 v2(106.42,112.76) ; U7.101 215.9,91.31 215,92.21 215,92.35 214.55,92.81 214.55,94.41 214.28,94.68 214.28,96.55 214.28,96.55 214.28,96.7 214.28,96.7 214.28,96.91 214.28,96.92 214.28,101.07 214.53,101.33 214.55,101.33 v2(214.9,101.68)
  BOTTOM w0.178: v2(134.26,112.25) 134.33,112.17 137.1,112.17 137.66,111.61 137.66,111.04 137.44,110.83 137.44,109.81 138.93,108.32 138.93,105.77 137.08,103.92 137.08,100.92 138.87,99.12 142.31,99.12 144.62,101.43 144.62,102.82 v2(144.65,102.85) 145.03,103.23 PR71.2
SATA0GP: length 188.6
  TOP w0.076: v2(65.22,78.21) 65.5,78.21 65.52,78.19
  TOP w0.127: v2(70.15,78.24) 69.72,78.67 68.5,78.67 67.18,77.35 66.36,77.35 65.52,78.19 ; v2(212.03,100.39) 212.03,99.73 TP10.1
  IN2 w0.127: v2(212.03,100.39) 211.37,100.39 209.55,102.21 209.55,102.6 209.29,102.86 208.92,102.86 208.66,102.6 208.66,102.35 207.89,101.58 206.91,101.58 206.65,101.33 203.83,101.33 203.3,100.79 202.88,100.79 202.18,100.79 200.08,100.79 199.86,100.79 197.86,98.79 196.82,98.79 194.93,98.79 192.97,96.83 190.68,96.83 190.41,96.56 187.03,96.56 182.62,92.16 182.06,92.16 174.79,84.89 170.71,84.89 170.1,84.28 169.71,84.28 169.08,84.92 168.86,84.92 168.84,84.93 158.34,84.93 156.07,87.2 154.46,88.8 139.63,88.8 138.94,88.12 132.36,88.12 131.8,88.68 130.36,90.12 125.59,90.12 125.54,90.07 125.53,90.07 125.42,89.96 121.09,89.96 120.44,90.6 115.11,90.6 115.1,90.59 114.41,90.59 113.24,91.77 113.24,94.1 111.28,96.06 111.07,96.06 110.86,96.06 102.86,96.06 102.29,95.48 98.39,95.48 97.22,96.65 96.6,96.65 96.43,96.82 95.98,96.82 92.77,96.82 92.35,96.39 92.35,94.98 89.68,92.31 85.54,92.31 85.01,91.79 81.19,91.79 80.7,91.3 80.7,88.84 80.44,88.58 79.82,88.58 79.45,88.21 78.72,88.21 78.06,87.54 76.93,87.54 76.04,86.64 74.54,86.64 73.76,85.86 73.75,85.86 73.3,85.4 73.3,82.33 72.48,81.51 72.48,79.99 72.3,79.8 70.41,79.8 70,79.39 70,78.38 v2(70.15,78.24)
  BOTTOM w0.076: U20.U1 62.95,78.25 63.06,78.14 63.72,78.14 63.8,78.21 v2(65.22,78.21) 65.42,78.21
  BOTTOM w0.127: R304.1 65.42,78.21 ; U7.48 211.1,105.42 210.95,105.28 210.95,104.67 211.27,104.35 211.27,101.15 v2(212.03,100.39)
SATA1GP: length 158.9
  TOP w0.127: v2(5.71,15.78) 5.25,15.32 5.25,14.28 7.38,12.15 9.75,12.15 10.23,11.66 10.23,11.23 10.46,11 11.35,11 11.6,11.26 v2(11.6,11.47)
  IN1 w0.127: v2(11.6,11.47) 11.6,11.49 12.04,11.93 19.99,11.93 20.66,12.6 27.17,12.6 27.4,12.37 v2(27.4,11.44) ; v2(41.78,75.04) 49.2,75.04 49.39,75.23 51.6,75.23 52.8,76.43 52.8,77.96 54.4,79.56 56.68,79.56 57.29,78.95 57.29,77.07 57.88,76.48 57.88,75.93 58.08,75.72 60.37,75.72 61.03,75.06 62.53,75.06 63.09,75.62 63.67,75.62 63.92,75.88 64.41,75.88 64.97,76.43 67.45,76.43 67.91,76.89 v2(67.91,77.37)
  IN2 w0.127: v2(41.78,75.04) 41.5,75.04 41.11,74.66 38.45,74.66 37.99,74.2 25.14,74.2 23.14,72.19 23.11,72.19 23.11,69.83 22.39,69.12 22.39,67.52 18.84,63.96 14.88,63.96 12.64,61.73 12.64,61.32 11.37,60.04 10.44,60.04 8.06,57.65 8.06,55.49 6.01,53.44 6.01,39.83 5.2,39.02 5.2,35.34 5.86,34.68 5.86,27.04 8.48,24.42 8.48,18.55 8.76,18.27 8.76,17.66 8.03,16.93 6.44,16.93 5.7,16.19 5.7,15.79 v2(5.71,15.78)
  BOTTOM w0.076: U20.V1 63.09,77.5 63.44,77.15 64.41,77.15 TP88.1 64.74,77.48 65.42,77.48
  BOTTOM w0.127: CN14.51 v2(27.4,11.44) ; 65.42,77.48 65.75,77.48 65.88,77.35 67.85,77.35 67.87,77.37 v2(67.91,77.37) 67.94,77.35 67.94,76.88 R314.1 68.06,76.81 68.46,77.21 R303.1
SATA_IREF: length 7.7
  BOTTOM w0.254: 55.8,89.06 55.8,88.45 55.7,88.35 U20.A12
  BOTTOM w0.381: 55.8,89.06 56.63,89.9 59.86,89.9 61,91.04 R155.2
SATA_RCOMP: length 9.2
  BOTTOM w0.241: 56.86,89.31 56.2,88.65 56.2,88.27 56.07,88.14 56.07,87.56 55.72,87.21 55.72,86.54 U20.C12
  BOTTOM w0.381: 56.86,89.31 59.99,89.31 61.14,90.47 61.4,90.47 61.76,90.84 61.76,91.19
SATA_RXN0: length 221.5
  TOP w0.127: R4.1 v2(253,99.32)
  IN1 w0.114: v2(253,99.32) 247.67,99.32 246.7,100.28 239.21,100.28 238.63,99.7 237.18,99.7 236.59,100.28 230.55,100.28 230.39,100.13 228.07,100.13 227.91,100.28 227.07,100.28 226.51,99.73 222.68,99.73 222.41,99.45 219.61,99.45 218.14,97.99 215.02,97.99 214.65,97.62 210.51,97.62 208.64,95.75 208.64,95.14 206.6,93.1 204.36,93.1 202.35,95.1 197.12,95.1 196.7,94.68 193.58,94.68 193.3,94.41 192.46,93.57 192.46,93.41 191.94,92.89 189.98,92.89 184.45,87.36 184.16,87.36 179.76,82.96 170.89,82.96 170.43,83.41 164.69,83.41 164.65,83.46 164.05,83.46 161.54,85.97 134.04,85.97 133.44,86.57 131.3,86.57 128.41,89.45 112.58,89.45 109.87,92.16 91.2,92.16 90.57,92.79 85.13,92.79 84.8,92.46 82.69,92.46 82.69,92.46 82.6,92.46 82.29,92.77 80.01,92.77 79.46,92.22 78.91,92.22 75.19,92.22 74.38,91.41 69.87,91.41 69.59,91.13 66.2,91.13 64.66,89.59 63.81,89.59 61.25,87.04 59.3,87.04 58.97,87.37 56.52,87.37 56.02,86.87 56.02,86.09 56.7,85.41 56.7,83.74 57.39,83.04 57.69,83.04 v3(57.83,82.91)
  BOTTOM w0.127: v3(57.83,82.91) 57.89,82.91 U20.J8 ; C64.1 252.38,99.26 252.49,99.14 252.82,99.14 v2(253,99.32)
SATA_RXN0_C: length 3.5
  BOTTOM w0.127: U10.4 249.29,98.74 249.42,98.88 249.42,99.1 249.68,99.36 251.36,99.36 C64.2
SATA_RXN0_DC: length 5.1
  TOP w0.127: R487.2 v3(249.6,90.99)
  BOTTOM w0.127: CN6.16 248.25,89.08 248.4,89.24 248.4,89.53 249.05,90.18 249.3,90.18 249.8,90.68 249.8,90.78 v3(249.6,90.99) 249.8,91.19 249.8,91.41 C159.2
SATA_RXN0_DC_1: length 9.1
  TOP w0.127: R4.2 v1(251.55,99.32) 250.54,99.32 250.08,98.86 250.08,94.28 249.6,93.8 R487.1
SATA_RXN0_DC_L: length 1.9
  BOTTOM w0.127: C159.1 249.61,92.57 249.8,92.77 249.8,92.9 249.29,93.42 U10.12
SATA_RXN1: length 115.7
  TOP w0.127: v2(59.73,82.97) 59.64,83.06 59.07,83.06 58.03,84.1 57.36,84.1 56.56,84.91 56.56,85.53 55.98,86.11 53.11,86.11 52.48,86.75 50.56,86.75 49.29,85.48 48.28,85.48 47.09,86.67 44.54,86.67 44.46,86.59 43.27,86.59 43.02,86.35 43.02,84.97 43.43,84.56 43.43,82.15 39.26,77.98 33.19,77.98 32.73,77.53 30.99,77.53 30.23,76.76 29.58,76.76 27.07,74.25 25.99,74.25 24.12,72.38 24.12,70.8 22.96,69.64 22.96,66.55 18.76,62.36 18.76,43.29 16.25,40.78 16.25,35.41 16.45,35.21 16.45,28.96 17.78,27.63 17.78,20.88 15.96,19.06 14.46,19.06 13.58,18.17 13.58,17.04 14.37,16.25 14.76,16.25 15.26,15.75 v3(15.26,15.73)
  BOTTOM w0.127: v2(59.73,82.97) 60.19,82.52 U20.J5 ; v3(15.26,15.73) 14.95,15.42 14.95,15.19 15.44,14.71 16.5,14.71 16.81,14.41 16.81,14.14 C353.1
SATA_RXN1_C: length 3.7
  BOTTOM w0.127: CN14.25 17,10.91 16.73,11.18 16.73,11.74 v2(17.24,12.25) 17.24,12.3 16.81,12.73 16.81,13.25 C353.2
SATA_RXP0: length 221.5
  TOP w0.127: R5.1 v2(253,98.66)
  IN1 w0.114: v2(253,98.66) 253,98.74 252.63,99.1 247.58,99.1 246.61,100.07 239.3,100.07 238.71,99.48 237.09,99.48 236.5,100.07 230.64,100.07 230.48,99.91 227.98,99.91 227.82,100.07 227.16,100.07 226.6,99.51 222.77,99.51 222.5,99.24 219.7,99.24 218.23,97.77 218.05,97.77 215.11,97.77 214.74,97.4 210.6,97.4 208.86,95.66 208.86,95.05 206.69,92.88 204.27,92.88 202.26,94.89 197.21,94.89 196.79,94.47 193.67,94.47 193.39,94.19 193.39,94.19 192.68,93.48 192.68,93.32 192.03,92.68 190.15,92.68 184.61,87.14 184.25,87.14 179.85,82.74 170.8,82.74 170.34,83.2 164.6,83.2 164.56,83.24 163.96,83.24 161.45,85.76 133.95,85.76 133.35,86.35 131.21,86.35 128.32,89.24 112.49,89.24 109.78,91.94 91.11,91.94 90.48,92.58 85.22,92.58 84.89,92.25 84.77,92.25 82.78,92.25 82.51,92.25 82.2,92.55 80.1,92.55 79.55,92 79,92 75.28,92 74.46,91.19 69.96,91.19 69.68,90.92 66.29,90.92 64.74,89.36 63.88,89.36 61.34,86.82 59.21,86.82 58.88,87.15 56.61,87.15 56.24,86.78 56.24,86.17 56.91,85.5 56.91,83.83 57.48,83.26 57.64,83.26 57.83,83.44 v2(57.83,83.62)
  BOTTOM w0.127: U20.H8 58.39,83.22 58.39,83.42 58.34,83.47 57.98,83.47 v2(57.83,83.62) ; v2(253,98.66) 252.75,98.91 252.49,98.91 252.38,98.79 C74.1
SATA_RXP0_C: length 3.5
  BOTTOM w0.127: U10.5 249.79,98.74 249.65,98.88 249.65,99 249.78,99.13 251.33,99.13 251.6,98.87 C74.2
SATA_RXP0_DC: length 5.1
  TOP w0.127: R488.2 v2(250.26,91.01)
  BOTTOM w0.127: CN6.17 248.75,89.13 248.63,89.25 248.63,89.44 249.14,89.95 249.39,89.95 250.03,90.58 250.03,90.78 v2(250.26,91.01) 250.03,91.24 250.03,91.39 C158.2
SATA_RXP0_DC_1: length 9.1
  TOP w0.127: R488.1 250.26,92.13 v1(249.93,92.46) 249.83,92.56 249.83,93.71 250.31,94.19 250.31,98.76 250.64,99.09 251.33,99.09 251.76,98.66 R5.2
SATA_RXP0_DC_L: length 1.8
  BOTTOM w0.127: U10.11 249.79,93.24 250.03,92.99 250.03,92.77 250.22,92.57 C158.1
SATA_RXP1: length 115.7
  TOP w0.127: v3(59.73,83.62) 59.4,83.29 59.17,83.29 58.13,84.33 57.46,84.33 56.79,85 56.79,85.63 56.08,86.34 53.21,86.34 52.57,86.97 50.46,86.97 49.19,85.7 48.38,85.7 47.19,86.9 44.44,86.9 44.37,86.82 43.17,86.82 42.79,86.44 42.79,84.87 43.2,84.47 43.2,82.24 39.17,78.21 33.1,78.21 32.64,77.75 30.9,77.75 30.14,76.99 29.49,76.99 26.98,74.48 25.9,74.48 23.89,72.48 23.89,70.9 22.73,69.73 22.73,66.65 18.53,62.45 18.53,43.39 16.02,40.87 16.02,35.32 16.22,35.11 16.22,28.87 17.56,27.53 17.56,20.97 15.87,19.28 14.37,19.28 13.35,18.27 13.35,16.95 14.55,15.75 v2(14.55,15.73)
  BOTTOM w0.127: v2(14.55,15.73) 14.72,15.55 14.72,15.1 15.34,14.48 16.41,14.48 16.58,14.31 16.58,14.14 C354.1 ; v3(59.73,83.62) 60.21,83.14 U20.H5
SATA_RXP1_C: length 3.8
  BOTTOM w0.127: CN14.23 16.2,10.98 16.5,11.28 16.5,11.71 v2(15.97,12.25) 16,12.25 16.58,12.83 16.58,13.25 C354.2
SATA_TXN0: length 217.8
  TOP w0.127: R3.1 v2(252.54,101.1)
  IN1 w0.114: v2(252.54,101.1) 252.24,101.1 252.14,101.2 252.14,101.55 252.07,101.62 251.01,101.62 250.66,101.96 247.34,101.96 246.91,102.39 234.87,102.39 234.17,101.69 229.39,101.69 229.2,101.89 228.03,101.89 227.84,101.69 226.52,101.69 225.99,101.16 225.7,101.16 224.93,101.16 224.93,101.16 224.87,101.16 221.95,101.16 221.63,100.84 218.27,100.84 218,100.56 216.78,100.56 216.44,100.22 214.69,100.22 214.13,99.66 211.61,99.66 210.83,100.44 210.42,100.44 209.88,99.91 206.69,99.91 206.31,100.29 205.54,100.29 204.63,99.39 200.23,99.39 199.96,99.66 199.1,99.66 199.09,99.65 199.08,99.65 198.25,98.82 194.19,98.82 194.14,98.77 194.14,98.77 193.08,97.72 192.04,97.72 191.19,96.87 191.19,96.87 191.18,96.86 189.55,96.86 183.13,90.43 182.52,90.43 182.52,90.43 182.34,90.43 181.33,90.43 179.39,90.43 179.1,90.14 177.85,88.89 177.67,88.89 168.97,88.89 168.78,88.7 168.6,88.7 167.53,88.7 166.93,88.1 165.87,88.1 163.69,90.28 156.56,90.28 153.81,93.02 140.81,93.02 139.77,91.98 137.59,91.98 136.23,90.62 132.9,90.62 129.73,93.8 106.31,93.8 106.13,93.62 94.59,93.62 94.24,93.97 94.07,93.97 93.64,94.39 87.11,94.39 86.75,94.76 79.38,94.76 79.05,94.43 73.11,94.43 72.46,93.78 71.07,93.78 70.89,93.78 64.74,93.78 62.58,91.62 62.4,91.62 62.4,91.62 61.75,91.62 60.38,90.26 60.38,90.26 59.92,89.79 56.02,89.79 55.07,88.84 53.75,88.84 53.61,88.7 53.61,88.58 53.76,88.42 v2(53.79,88.42)
  BOTTOM w0.127: v2(252.54,101.1) 252.54,101.12 252.32,101.35 251.84,101.35 251.74,101.25 C57.1 ; v2(53.79,88.42) 53.79,88.17 53.71,88.09 53.33,88.09 53.12,87.88 U20.A17
SATA_TXN0_C: length 6
  BOTTOM w0.127: C57.2 250.96,101.35 250.83,101.48 249.59,101.48 248.14,100.03 248.14,98.88 248.28,98.74 U10.2
SATA_TXN0_DC: length 4.7
  TOP w0.127: R486.2 v2(248.21,90.88)
  BOTTOM w0.127: CN6.15 247.75,89.26 247.59,89.42 247.59,89.67 247.98,90.06 247.98,90.65 v2(248.21,90.88) 248,91.09 248,91.65 248.14,91.79 C160.2
SATA_TXN0_DC_1: length 12.9
  TOP w0.127: R3.2 251.33,101.1 250.82,101.61 249.75,101.61 247.41,99.27 247.41,94.82 247.78,94.46 247.78,92.43 v1(247.87,92.33) 248.21,91.99 R486.1
SATA_TXN0_DC_L: length 1.8
  BOTTOM w0.127: U10.14 248.28,93.46 248.12,93.3 248.12,93.05 248.05,92.97 248.05,92.72 248.19,92.57 C160.1
SATA_TXN1: length 115.8
  TOP w0.127: v3(19.13,15.69) 19.61,15.21 19.61,14.72 18.9,14 11.95,14 11.65,14.3 11.65,18.74 11.97,19.06 11.97,23.39 12.95,24.36 13.58,24.36 15.33,26.12 15.33,27.03 15.66,27.36 15.66,28.73 15.13,29.27 15.13,40.82 17.49,43.19 17.49,62.13 22.22,66.86 22.22,69.96 23.39,71.13 23.39,72.69 25.69,74.99 26.77,74.99 27.82,76.04 27.82,77.2 28.14,77.51 29.94,77.51 30.69,78.26 32.4,78.26 32.86,78.72 35.76,78.72 40.71,83.67 40.71,84.64 41.88,85.81 41.88,86.27 42.94,87.33 43.88,87.33 44.05,87.51 47.37,87.51 47.78,87.1 49.46,87.1 49.85,87.48 53.27,87.48 53.5,87.71 53.94,87.71 54.09,87.56 54.09,87.31 v2(54.02,87.23)
  BOTTOM w0.127: v2(54.02,87.23) 53.84,87.41 53.61,87.41 53.54,87.33 U20.B15 ; C351.1 19.58,14.34 19.58,15.25 v3(19.13,15.69)
SATA_TXN1_C: length 3.9
  BOTTOM w0.127: C351.2 19.4,13.23 19.4,12.93 18.89,12.43 ; v2(18.86,12.43) 18.89,12.43 ; 18.89,12.43 19.45,11.87 19.45,11.7 19.65,11.49 19.65,11.26 19.4,11.01 CN14.31
SATA_TXP0: length 218
  TOP w0.127: R2.1 v2(252.49,101.83)
  IN1 w0.114: v3(53.13,88.55) 53.15,88.55 53.66,89.06 54.98,89.06 55.93,90.01 59.83,90.01 60.17,90.35 60.17,90.35 61.66,91.84 62.49,91.84 64.65,94 70.98,94 71.16,94 72.37,94 73.02,94.65 78.96,94.65 79.29,94.98 86.84,94.98 87.2,94.61 93.73,94.61 94.16,94.18 94.33,94.18 94.68,93.83 106.04,93.83 106.22,94.01 129.82,94.01 132.99,90.84 136.14,90.84 137.5,92.2 139.68,92.2 140.72,93.24 153.9,93.24 156.65,90.49 163.78,90.49 165.96,88.31 166.84,88.31 167.44,88.92 168.69,88.92 168.88,89.11 177.76,89.11 179.01,90.36 179.3,90.65 182.43,90.65 183.04,90.65 189.46,97.07 191.09,97.07 191.1,97.08 191.1,97.08 191.95,97.93 192.99,97.93 194.05,98.99 194.05,98.99 194.1,99.04 198.16,99.04 198.99,99.87 199,99.87 199.01,99.87 200.05,99.87 200.32,99.61 204.54,99.61 205.45,100.51 206.4,100.51 206.78,100.13 209.79,100.13 210.33,100.66 210.92,100.66 211.7,99.88 214.04,99.88 214.6,100.44 216.35,100.44 216.69,100.78 217.91,100.78 218.18,101.05 221.54,101.05 221.86,101.38 222.13,101.38 225.02,101.38 225.9,101.38 226.43,101.91 227.75,101.91 227.94,102.11 229.29,102.11 229.48,101.91 234.08,101.91 234.78,102.61 247,102.61 247.43,102.18 250.75,102.18 251.1,101.83 v2(252.49,101.83)
  BOTTOM w0.127: C52.1 251.74,101.72 251.88,101.58 252.32,101.58 252.49,101.76 v2(252.49,101.83) ; U20.B17 52.77,87.88 53.13,88.24 v3(53.13,88.55)
SATA_TXP0_C: length 6
  BOTTOM w0.127: C52.2 250.61,101.71 249.5,101.71 247.92,100.13 247.92,98.87 247.79,98.74 U10.1
SATA_TXP0_DC: length 4.6
  TOP w0.127: R481.2 247.55,90.9 v3(247.55,90.9)
  BOTTOM w0.127: CN6.14 247.25,89.25 247.36,89.36 247.36,89.76 247.75,90.15 247.75,90.7 v3(247.55,90.9) 247.77,91.12 247.77,91.7 247.68,91.79 C161.2
SATA_TXP0_DC_1: length 12.9
  TOP w0.127: R481.1 247.55,94.37 247.18,94.73 247.18,99.36 249.66,101.83 v1(251.05,101.83) R2.2
SATA_TXP0_DC_L: length 1.8
  BOTTOM w0.127: C161.1 247.6,92.57 247.82,92.79 247.82,93.06 247.9,93.14 247.9,93.32 247.79,93.44 U10.15
SATA_TXP1: length 115.9
  TOP w0.127: v2(19.84,15.69) 19.84,14.62 18.99,13.77 11.85,13.77 11.42,14.2 11.42,18.83 11.74,19.15 11.74,23.48 12.85,24.59 13.49,24.59 15.11,26.21 15.11,27.13 15.44,27.46 15.44,28.64 14.9,29.17 14.9,40.92 17.26,43.28 17.26,62.22 21.99,66.95 21.99,70.06 23.16,71.22 23.16,72.78 25.59,75.22 26.67,75.22 27.59,76.14 27.59,77.29 28.04,77.74 29.84,77.74 30.59,78.49 32.31,78.49 32.76,78.95 35.66,78.95 40.48,83.77 40.48,84.73 41.65,85.9 41.65,86.37 42.84,87.56 43.78,87.56 43.96,87.74 47.46,87.74 47.87,87.33 49.37,87.33 49.75,87.71 53.18,87.71 53.41,87.94 v3(54.32,87.94)
  BOTTOM w0.127: U20.A15 53.87,87.71 54.09,87.71 v3(54.32,87.94) ; C350.1 19.8,15.65 v2(19.84,15.69)
SATA_TXP1_C: length 3.8
  BOTTOM w0.127: CN14.33 20.2,11.05 19.88,11.37 19.88,11.59 19.68,11.79 19.68,12.04 20.06,12.43 v2(20.13,12.43) 19.63,12.93 19.63,13.28 C350.2
SCLK: length 14.5
  BOTTOM w0.127: v2(66.39,98.02) 65.9,98.02 PR97.2 64.77,99.15 64.77,99.28 63.87,100.17 63.87,101.33 62.53,102.67 61.89,102.67 61.59,102.98 60.34,102.98 60.27,103.05 60.19,103.05 59.94,103.31 59.94,104.98 59.75,105.17 PR57.1 60.05,105.77 60.34,105.77 60.99,106.42 PU3.5
SDIO: length 8.2
  BOTTOM w0.127: PR89.2 64.98,101.8 64.34,101.8 63.34,102.8 v2(63.34,103.05) 63.14,103.26 63.14,103.87 63.34,104.07 63.34,105.11 63.28,105.17 PR55.1 62.73,105.3 62.73,105.81 61.79,106.75 PU3.3
SDIO_CLK: length 16.8
  TOP w0.127: v3(67.3,96.68) 67.3,96.58 65.22,94.49 64.3,94.49 62.55,92.74 62.55,90.04 62.41,89.91 62.28,89.78 61.92,89.42 61.92,86.77 61.97,86.72 61.97,84.77 v2(61.81,84.61)
  BOTTOM w0.127: U20.E3 61.51,84.91 v2(61.81,84.61) ; v3(67.3,96.68) 66.67,96.04 RP2.3
SDIO_CMD: length 16.7
  TOP w0.127: v3(61.16,84.61) 61.75,85.2 61.75,86.52 61.68,86.59 61.68,89.5 62.18,90.01 62.32,90.14 62.32,92.84 64.2,94.72 64.97,94.72 66.44,96.2 66.44,96.42 v2(66.67,96.65)
  BOTTOM w0.127: U20.F4 60.86,84.31 v3(61.16,84.61) ; RP2.2 66.03,96.02 v2(66.67,96.65)
SDIO_D1: length 15.9
  TOP w0.127: v2(61.03,85.51) 61.24,85.51 61.54,85.81 61.54,86.37 61.43,86.47 61.43,89.58 62.09,90.23 62.09,92.93 64.11,94.95 64.86,94.95 66.16,96.25 66.16,96.53 v3(66.01,96.68)
  BOTTOM w0.127: U20.E4 60.86,85.35 v2(61.03,85.51) ; RP2.1 65.4,96.07 v3(66.01,96.68)
SDIO_D2: length 15.8
  TOP w0.127: v3(62.93,87.48) 63.03,87.48 64.2,88.64 64.2,90.28 66.03,92.11 66.03,93.44 68.2,95.61 69.05,95.61 69.94,96.5 v2(69.94,96.68)
  BOTTOM w0.076: U20.C3 61.64,86.41 62.02,86.79 62.45,86.79 62.93,87.27
  BOTTOM w0.089: 62.93,87.27 v3(62.93,87.48)
  BOTTOM w0.127: v2(69.94,96.68) 69.94,96.55 69.72,96.32 69.72,95.57
SDIO_D3: length 11.5
  BOTTOM w0.076: U20.E2 62.3,84.85 62.96,84.85 63.16,85.06 63.16,85.5 63.37,85.71 63.37,86.99 63.53,87.15 63.53,87.7 63.19,88.04 63.19,88.24
  BOTTOM w0.127: 63.19,88.24 63.19,89.45 64.23,90.49 64.23,90.8 65.15,91.73 65.15,92.47 66.03,93.35 RP2.9
SDVO_CLK: length 161.4
  TOP w0.127: v2(183.33,80.45) 183.61,80.73 184.75,80.73 188.87,84.84 190.06,84.84 190.42,85.2 191.25,85.2 192.3,86.24 192.42,86.24 192.6,86.06 v3(192.6,86.04) 192.68,86.11 193.32,86.11 193.69,85.74 193.69,84.4 193.62,84.33 v2(193.1,84.33)
  IN1 w0.114: v2(183.33,80.45) 183.56,80.68 183.8,80.68 183.86,80.74 183.86,80.75 184,80.89 184,81.58 183.34,82.24 170.51,82.24 170.05,82.7 164.39,82.7 164.34,82.75 163.76,82.75 161.29,85.21 133.63,85.21 132.99,85.86 130.45,85.86 127.57,88.73 111.82,88.73 109.21,91.34 86.15,91.34 85.74,91.75 85.65,91.75 85.56,91.75 82.3,91.75 82,92.05 80.51,92.05 79.43,90.98 75.21,90.98 74.86,90.62 70.08,90.62 69.89,90.42 66.51,90.42 62.44,86.35 62.44,84.5 61.88,83.94 61.07,83.94 60.58,84.42 60.58,85.69 60.06,86.21 58.41,86.21 58.21,86.42 57.12,86.42 v2(56.96,86.58)
  BOTTOM w0.127: CN8.26 193.32,84.56 v2(193.1,84.33) ; U20.B9 56.96,86.94 v2(56.96,86.58) ; R184.2 195.32,90.08 194.63,89.39 194.63,88.17 193.86,87.39 193.86,86.4 193.63,86.18 193.57,86.12 192.69,86.12 v3(192.6,86.04)
SDVO_DATA: length 161
  TOP w0.127: v2(193.36,83.75) 193.92,84.31 193.92,85.83 193.41,86.34 193.29,86.34 v2(193.06,86.57) 193.03,86.57 192.96,86.49 192.23,86.49 191.16,85.43 190.32,85.43 189.97,85.07 188.77,85.07 184.66,80.96 183.46,80.96 v3(183.33,81.08)
  IN1 w0.114: v2(57.42,85.73) 57.42,86.08 57.54,86.2 58.12,86.2 58.32,86 59.97,86 60.37,85.6 60.37,84.33 60.98,83.72 61.97,83.72 62.65,84.41 62.65,86.26 66.6,90.21 69.98,90.21 70.17,90.4 74.95,90.4 75.3,90.76 79.52,90.76 80.6,91.84 81.91,91.84 82.21,91.53 85.65,91.53 86.06,91.13 109.12,91.13 111.73,88.52 127.48,88.52 130.36,85.64 132.9,85.64 133.54,84.99 161.2,84.99 163.67,82.53 164.25,82.53 164.3,82.49 169.96,82.49 170.42,82.03 183.25,82.03 183.79,81.49 183.79,81.08 v3(183.33,81.08)
  BOTTOM w0.127: U20.C9 57.46,85.78 v2(57.42,85.73) ; R185.2 194.68,89.77 194.4,89.49 194.4,88.26 193.63,87.49 193.63,86.5 193.48,86.35 193.28,86.35 v2(193.06,86.57) ; CN8.6 193.62,83.39 193.36,83.65 v2(193.36,83.75)
SENSE_A: length 29.6
  TOP w0.254: v2(196.69,83.04) 198.77,80.96 v1(198.77,80.07) 198.77,77.42 200.16,76.04 201.33,76.04 202.28,75.09 205.02,75.09 205.83,75.9 206.81,75.9 207.19,76.28 211.77,76.28 212.53,75.52 213.05,75.52 214.16,74.4 217.87,74.4 v2(218.05,74.22)
  BOTTOM w0.254: v2(218.05,74.22) 218.05,74.88 R327.2 ; v2(196.69,83.04) 196.62,82.97 CN8.1
SENSE_A_1: length 12.8
  BOTTOM w0.203: C361.2 209.99,74.32 210.63,74.32 210.81,74.5 210.81,74.61 ; 210.81,74.61 211.73,73.69 v4(212.03,73.69) 212.08,73.64 216.83,73.64 217.49,74.3 217.49,75.47 217.7,75.68 R327.1 218.42,76.07 U18.13 ; 210.81,74.61 R334.1
SERIRQ: length 204.2
  TOP w0.089: v3(61.16,78.62) 61.57,79.02 62.15,79.02 62.73,79.61 63.49,79.61
  TOP w0.127: v2(115.28,93.22) 114.51,93.22 114.46,93.17 110.76,93.17 110.59,93.01 109.54,93.01 109.54,93.01 109.23,93.01 104.09,93.01 103.57,93.53 v2(93.97,93.53) 92.36,93.53 92.36,93.53 89.79,93.53 86.82,93.53 85.52,92.23 85.31,92.23 85,92.23 82.14,92.23 80.43,90.53 79.44,90.53 77.79,88.88 77.64,88.88 77.64,88.88 v2(77.64,88.88) 77.45,88.69 77.45,88.57 77.26,88.38 77.26,84.62 77.22,84.58 77.22,84.57 76.66,84.02 76.66,84.02 75.75,83.11 74.72,83.11 73.96,82.35 73.96,82.34 73.54,81.92 73.54,81.92 71.86,80.24 71.86,80.24 71.76,80.14 71.23,80.14 70.12,80.14 69.81,79.84 67.38,79.84 67.05,79.51 66.67,79.51 66.17,80 64,80 63.61,79.61 63.49,79.61
  IN2 w0.127: v2(206.25,104.48) 205.1,104.48 205.05,104.53 203.98,104.53 203.46,104.01 202.87,104.01 198.46,104.01 197.1,102.65 196.64,102.65 196.46,102.47 194.4,102.47 193.38,101.44 193.07,101.44 192.41,100.78 192.41,100.18 191.11,98.87 189.81,98.87 189.6,98.66 185.95,98.66 182.14,94.85 181.64,94.85 176.93,90.14 175.37,90.14 173.21,87.98 167.71,87.98 165.8,89.89 156.32,89.89 155.22,90.99 148.54,90.99 146.89,92.64 146.2,92.64 145.99,92.64 139.78,92.64 138.96,91.81 137.3,91.81 137.26,91.78 132.64,91.78 131.34,93.07 131.13,93.07 122.44,93.07 121.56,93.95 115.91,93.95 115.28,93.32 v2(115.28,93.22)
  BOTTOM w0.089: v3(61.16,78.62) 61.16,78.73 U20.T4
  BOTTOM w0.127: v2(206.25,104.48) 206.26,104.48 206.29,104.45 206.29,103.08 207.49,101.88 207.69,101.88 208.22,101.35 209.31,101.35 210,100.66 210,95.61 210.94,94.67 210.94,93.35 210.15,92.56 209.72,92.56 209.54,92.39 207.89,92.39 207.54,92.74 204.54,92.74 204.32,92.96 U7.3 ; v2(77.64,88.88) 77.45,88.69 77.45,88.57 77,88.12 R215.1 ; v2(93.97,93.53) 94.2,93.3 94.2,92.61 95.93,90.89 95.93,90.61 95.95,90.58 95.95,89.74 95.67,89.46 94.53,89.46 94.05,88.98 94.05,87.6 94.26,87.4 94.26,86.59 95.8,85.05 95.8,83.04 96.24,82.6 U15.27
SIO_EXT_SCI#: length 197.2
  IN2 w0.127: v2(207.64,97.69) 207.31,97.69 206.62,97.01 206.16,97.01 205.63,97.54 201.54,97.54 200.33,96.32 200.07,96.32 199.77,96.02 199.56,96.02 198.21,96.02 197.83,95.64 196.36,95.64 196.03,95.31 195.25,95.31 194.36,94.42 192.38,94.42 192.17,94.42 192.17,94.42 191.78,94.42 190.86,93.49 187.86,93.49 183.41,89.03 182.74,89.03 175.25,81.54 173.46,81.54 171.9,81.54 171.09,80.73 170.67,80.73 164.59,80.73 163.39,81.92 156.73,81.92 153.55,85.11 132.92,85.11 132.78,85.25 129.86,85.25 128.26,86.85 112.41,86.85 110.53,88.74 97.65,88.74 95.09,91.29 92.53,91.29 90.94,89.71 87.62,89.71 87.2,89.71 85.45,87.95 84.81,87.95 83.25,86.39 83.25,85.35 83.1,85.2 83.1,84.25 v2(82.76,83.92)
  BOTTOM w0.076: U20.AU2 62.48,67.39 62.98,67.39 63.05,67.32 63.34,67.32
  BOTTOM w0.127: 63.34,67.32 63.95,67.32 64.38,66.88 64.38,60.18 64.54,60.01 R426.1 64.81,59.49 TP102.1 64.71,58.86 64.99,58.58 64.99,58.02 65.29,57.72 65.86,57.72 67.76,59.62 67.76,60.16 68.62,61.02 70.75,61.02 71.67,61.93 71.75,61.93 72.58,62.77 73.02,62.77 73.53,63.28 73.53,65.4 73.82,65.7 74.19,65.7 74.2,65.69 77.17,65.69 78.78,67.3 78.78,68.35 78.8,68.36 78.8,72.3 84.14,77.64 84.14,83.26 83.88,83.52 83.61,83.52 83.29,83.84 82.81,83.84 82.77,83.88 82.77,83.92 v2(82.76,83.92) ; U7.20 205.02,99.76 206.32,98.46 206.88,98.46 v2(207.64,97.69)
SIO_EXT_SMI#: length 183.8
  IN1 w0.127: v2(70.7,79.1) 71.24,79.1 73.07,80.94 73.07,80.94 73.07,81.7 73.58,82.21 73.58,82.43 73.92,82.77 73.99,82.77 74.25,83.03 74.25,83.1 74.63,83.48 74.63,83.58 77.89,86.85 78.33,86.85 78.53,87.05 78.96,87.05 79.14,87.23 79.42,87.23 79.89,87.7 81.01,87.7 81.52,88.22 81.88,88.22 v2(84.04,90.38)
  IN2 w0.127: v2(69.94,74.61) 70.6,74.61 70.99,74.99 70.99,76.94 71.39,77.35 71.82,77.35 72.1,77.63 72.1,78.06 71.8,78.36 71.44,78.36 v2(70.7,79.1) ; v2(84.04,90.38) 84.04,90.51 84.52,90.99 85.41,90.99 86.23,91.8 89.93,91.8 92.85,94.72 92.85,96.06 93.11,96.31 95.77,96.31 97.1,94.98 102.53,94.98 103.1,95.55 111.07,95.55 112.73,93.89 112.73,91.56 115,89.29 115.01,89.29 115.09,89.2 116.58,89.2 117.64,89.2 117.64,89.2 125.76,89.2 125.93,89.36 130.04,89.36 130.61,88.79 132.05,87.36 139.29,87.36 139.77,87.84 153.66,87.84 157.67,83.83 164.59,83.83 165.38,83.04 170.19,83.04 170.4,83.04 170.8,83.44 174.25,83.44 174.46,83.44 182.13,91.12 182.74,91.12 187.42,95.8 190.73,95.8 191,96.07 193.29,96.07 195.24,98.02 196.09,98.02 197.8,98.02 198.39,98.02 198.89,98.52 200.06,98.52 200.81,99.27 204.41,99.27 205.71,100.56 v2(207.28,100.56)
  BOTTOM w0.076: U20.AC1 62.81,75.2 63.19,74.82 64.4,74.82 64.77,75.19 65.3,75.19 65.42,75.32
  BOTTOM w0.127: v2(202.73,105.87) 202.48,105.62 202.48,104.75 202.68,104.56 U7.32 204.35,104.56 205.27,103.63 205.27,102.69 206.81,101.15 206.81,100.98 207.23,100.56 v2(207.28,100.56) ; v2(69.94,74.61) 69.94,74.58 69.92,74.55 R337.1 69.42,74.94 69.28,75.08 67.43,75.08 67.1,75.41 65.64,75.41 65.55,75.32 65.42,75.32
SLATE_EC_RESET: length 44.2
  IN1 w0.127: v2(212.36,105.03) 212.36,105.24 210.75,106.84 210.35,106.84 209.55,106.84 209.54,106.84 209.2,106.84 205.56,106.84 204.36,105.64 197.4,105.64 196.9,105.14 191.76,105.14 191.55,105.14 190.78,104.37 189.43,103.02 189.32,102.9 189.02,102.9 188.61,103.31 187.75,103.31 v2(187.57,103.48)
  BOTTOM w0.127: v2(212.36,105.03) 211.88,104.55 211.43,104.55 211.22,104.76 211.22,105.16 211.5,105.44 U7.49 ; v2(187.57,103.48) 187.57,102.95 188.85,101.67 v2(188.85,101.26) 190.32,99.8 191.21,99.8 192.22,98.79 192.22,96.83 191.89,96.5 191.89,94.47 192.06,94.29 193.03,94.29 193.28,94.54 Q14.1
SLP_A#: length 26.1
  TOP w0.127: v2(69.74,53.47) 69.59,53.32 TP63.1
  IN2 w0.127: v2(69.74,53.47) 69.21,53.47 63.73,58.96 63.73,61.06 62.98,61.8 62.98,64.7 62.22,65.46 62.22,69.83 61.69,70.36 61.21,70.36 v2(60.44,71.13)
  BOTTOM w0.127: R449.2 67.77,53.18 67.91,53.32 69.59,53.32 v2(69.74,53.47) ; U20.AL5 60.26,70.94 v2(60.44,71.13)
SLP_LAN#: length 2
  TOP w0.127: v2(58.53,72.36) 58.3,72.36 57.78,72.88 TP45.1
  BOTTOM w0.127: v2(58.53,72.36) 58.53,72.2 U20.AJ7
SLP_S0#_EC: length 3.9
  BOTTOM w0.127: v2(202.94,91.04) 202.68,91.29 202.05,91.29 201.57,91.78 R142.2 201.58,92.16 U7.1
SLP_S5#: length 27.4
  IN2 w0.127: v2(70.48,51.87) 70,51.87 63.08,58.79 63.08,60.56 62.1,61.55 62.1,62.74 61.18,63.66 61.18,64.47 61.7,64.99 61.7,68.48 60.96,69.22 v2(60.37,69.22)
  BOTTOM w0.127: v2(70.48,51.87) 69.81,51.2 67.93,51.2 67.87,51.15 R452.2 67.06,51.15 66.97,51.24 v2(66.54,51.24) ; U20.AP5 60.13,68.99 v2(60.37,69.22)
SLP_SUS#: length 10.1
  IN1 w0.127: v3(66.13,66.25) 65.47,66.25 64.25,65.03 63.24,65.03 60.98,67.29 60.05,67.29 v2(59.95,67.19)
  BOTTOM w0.089: v2(59.95,67.19) 60.54,67.79 60.54,67.83 60.82,68.1 60.82,68.5 U20.AP4
  BOTTOM w0.127: R382.1 66.13,66.77 v3(66.13,66.25)
SLP_SUS#_EC: length 176.6
  IN1 w0.127: v3(67.81,66.91) 67.81,66.93 68.68,67.8 69.82,67.8 71.8,69.79 71.8,70.05 73.26,71.51 73.26,72.19 76.45,75.37 76.45,76.15 77.34,77.04 77.34,78.67 78.34,79.68 78.34,79.77 78.34,80.19 79.11,80.96 79.97,80.96 81.25,82.23 81.45,82.23 82.51,83.29 82.68,83.29 v2(82.69,83.29)
  IN2 w0.127: v2(82.69,83.29) 82.69,83.29 82.76,83.37 83.9,83.37 84.69,84.16 84.69,84.67 84.79,84.77 84.79,84.78 88.07,88.05 93.17,88.05 93.36,87.86 93.8,87.86 95.71,87.86 97.51,86.06 103.52,86.06 106.24,83.34 132.96,83.34 133.45,83.84 153.02,83.84 157.58,79.28 170.8,79.28 171.44,79.28 172.43,80.27 172.93,80.27 175.77,80.27 178.59,83.09 180.36,83.09 183.79,86.51 183.79,87.48 188.52,92.22 192.19,92.22 192.4,92.22 192.71,92.22 192.97,91.97 193.7,91.97 195.24,93.5 197.84,93.5 198.63,94.29 202.37,94.29 203.33,95.26 205.63,95.26 206.09,95.71 207.26,95.71 207.76,96.22 208.73,96.22 209.58,97.07 210.62,97.07 211.24,96.45 211.65,96.45 v2(212.11,96.91)
  BOTTOM w0.127: v2(212.11,96.91) 212.34,96.68 212.34,93.17 210.71,91.55 210.38,91.55 210.3,91.46 U7.115 ; R382.2 v3(67.81,66.91)
SLP_SUS_ON: length 181.7
  TOP w0.127: v2(73.22,87.41) 72.74,87.89 72.74,88.93 72.18,89.49 72.18,90.96 v1(73.3,92.08) 73.63,92.41 73.63,93.97 73.76,94.1 73.94,94.1 75.01,94.1 75.78,94.87 78.26,94.87 79.1,94.87 79.79,95.56 85.7,95.56 86.54,95.56 86.55,95.56 86.8,95.31 87.19,95.31 91.5,95.31 92.89,96.69 95.25,96.69 95.78,96.16 98.01,96.16 98.58,95.59 105.62,95.59 106,95.2 113.62,95.2 113.97,95.56 116.85,95.56 118.97,97.67 119.03,97.67 119.17,97.67 v2(119.65,98.15)
  IN2 w0.127: v2(119.65,98.15) 121.33,96.47 125.06,96.47 126.43,95.1 130.31,95.1 130.52,95.1 130.73,95.1 131.44,95.1 131.65,95.1 132.82,93.93 133.33,93.43 136.58,93.43 136.61,93.46 138.22,93.46 140.75,95.99 140.96,95.99 141.17,95.99 151.68,95.99 151.68,95.99 151.89,95.99 156.97,90.91 165.58,90.91 166.21,90.91 168.12,89.01 172.8,89.01 174.95,91.16 175.41,91.16 175.77,91.16 180.69,96.08 181.91,96.08 185.5,99.67 188.91,99.67 190.71,101.48 191.64,101.48 192.93,102.77 193.63,102.77 194.09,103.23 196.03,103.23 196.26,103.46 196.83,103.46 198.14,104.77 198.15,104.77 198.49,104.77 199.51,104.77 203.14,104.77 203.66,105.29 205.58,105.29 205.97,105.68 210.26,105.68 210.85,105.09 210.85,104.88 210.85,104.71 212.37,103.19 212.37,102.96 212.94,102.39 214.27,102.39 214.47,102.19 215.13,102.19 v2(215.56,101.76)
  BOTTOM w0.127: v2(73.22,87.41) 74.29,86.34 R247.1 ; v2(215.56,101.76) 215.56,101.53 214.53,100.5 214.53,96.44 214.53,96.44 214.53,94.78 214.8,94.51 214.8,92.91 215.28,92.43 215.28,92.36 216.3,91.35 U7.100
SM_DRAMRST#: length 45.9
  BOTTOM w0.076: U20.AV15 54.16,66.21 53.84,65.89 53.84,65.64 53.97,65.51 53.97,65.28 53.84,65.16
  BOTTOM w0.127: R456.1 75.69,40.89 66.53,40.89 50.03,57.38 v4(50.03,58.7) 50.03,63.3 50.65,63.92 52.61,63.92 53.84,65.16
SM_INTRUDER#: length 6.1
  BOTTOM w0.076: 59.68,62.84 58.98,63.55 58.98,65.74 59.3,66.05 59.58,66.05 59.78,66.26 59.78,66.73 U20.AU6
  BOTTOM w0.127: 59.68,62.84 59.94,62.59 R410.2
SM_RCOMP_0: length 22.3
  IN2 w0.508: v2(26.89,63.76) 26.64,63.76 26.26,64.14 26.26,65.49 26.56,65.79 26.56,67.15 v2(26.17,67.54)
  BOTTOM w0.305: U20.AU60 26.25,67.46 v2(26.17,67.54)
  BOTTOM w0.508: R394.1 19.04,63.62 v4(19.04,62.84) 19.04,62.39 19.45,61.98 20.77,61.98 21,62.21 22.7,62.21 25.72,59.19 27.91,59.19 28.31,59.59 28.31,62.34 v2(26.89,63.76)
SM_RCOMP_1: length 10.5
  IN2 w0.254: v3(23.97,62.08) 23.74,62.31 23.74,65.26 24.69,66.2 v3(25.77,66.2)
  BOTTOM w0.305: v3(25.77,66.2) 26.07,66.2 U20.AV60
  BOTTOM w0.508: R393.1 22.85,63.86 23.97,62.74 v3(23.97,62.08)
SM_RCOMP_2: length 8.9
  IN2 w0.254: v2(25.05,67.52) 25.05,67.33 22.7,64.98 v2(22.7,60.81)
  BOTTOM w0.254: R417.1 22.32,61.19 v2(22.7,60.81)
  BOTTOM w0.305: U20.AU61 25.33,67.52 v2(25.05,67.52)
SM_VREF: length 67
  TOP w0.229: 32.15,67.65 32.63,67.16 33.09,67.62 33.09,68.23 32.77,68.55 v2(32.62,68.55) 32.49,68.55 32.15,68.2 32.15,67.65
  TOP w0.508: 32.63,67.16 32.63,66.78 31.69,65.84 v1(31.69,64.88) 31.69,64.17 26.35,58.82 26.35,39.6 27.17,38.78 27.17,27.84 28.87,26.14 34.28,26.14 35.93,24.49 v2(35.93,24.36)
  IN1 w0.508: v2(43.02,23.88) 43.02,23.91 42.77,24.16 39.31,24.16 38.23,25.24 36.56,25.24 35.93,24.62 v2(35.93,24.36)
  BOTTOM w0.254: U20.AP49 33.04,68.85 32.74,68.55 v2(32.62,68.55)
  BOTTOM w0.508: R467.1 42.41,23.96 42.94,23.96 v2(43.02,23.88) 43.17,23.73 C342.1
SMB_ME0_CLK: length 3.7
  BOTTOM w0.076: 64.1,69.04 63.87,69.27 62.83,69.27 U20.AN1
  BOTTOM w0.127: R378.2 64.93,68.76 64.38,68.76 64.1,69.04
SMB_ME0_DAT: length 5.8
  BOTTOM w0.076: 63.39,71.35 63.22,71.35 63.07,71.5 U20.AK1
  BOTTOM w0.127: 63.39,71.35 64.56,71.35 65.42,70.49 67.63,70.49 67.9,70.22 R369.2
SMB_ME1_CLK: length 32.1
  TOP w0.127: v2(70.86,70.82) 71.17,70.82 71.63,70.36 72.43,70.36 77.2,75.13 77.2,76.17 78.17,77.15 78.17,77.5 78.94,78.26 80.36,78.26 80.77,78.68 80.77,79.03 v2(80.97,79.23)
  IN1 w0.114: v2(70.86,70.82) 70.36,70.33 70.36,70.07 69.23,68.94 68.09,68.94 67.25,68.1 65.07,68.1 63.95,66.99 v2(63.95,66.6)
  BOTTOM w0.076: 63.39,66.3 62.96,66.73 62.54,66.73 62.51,66.76 62.02,66.76 61.71,67.07 U20.AU3
  BOTTOM w0.127: Q21.3 80.34,83.12 80.37,83.15 R264.2 80.96,83.15 81.23,82.88 81.23,80.7 81.09,80.56 81.09,79.67 80.89,79.46 80.89,79.3 v2(80.97,79.23) ; 63.39,66.3 63.64,66.3 v2(63.95,66.6)
SMB_ME1_DAT: length 32.2
  TOP w0.127: v3(65.22,72.83) 65.3,72.9 67.02,72.9 67.81,72.12 68.83,72.12 69.68,71.27 71.05,71.27 71.72,70.59 72.34,70.59 76.97,75.22 76.97,76.26 77.94,77.24 77.94,77.6 78.84,78.49 80.26,78.49 80.54,78.76 80.54,78.9 v2(80.33,79.1)
  BOTTOM w0.076: U20.AH3 61.77,71.96 62.29,71.96 62.52,72.2 62.52,72.37 62.69,72.54 62.94,72.54 63.11,72.37 63.49,72.37
  BOTTOM w0.127: v2(80.33,79.1) 80.51,79.28 80.51,79.41 80.87,79.76 R268.2 80.38,80.61 80.38,80.37 80.13,80.12 80.13,79.86 79.65,79.38 79.01,79.38 78.81,79.58 78.81,80.04 78.74,80.11 Q21.6 ; v3(65.22,72.83) 64.46,72.83 64,72.37 63.49,72.37
SMB_PCH_CLK: length 23.9
  IN1 w0.114: v3(69.84,70.75) 69.84,70.26 69.03,69.45 67.89,69.45 67.04,68.6 63.58,68.6 v2(63.47,68.71)
  BOTTOM w0.076: U20.AP2 62.46,68.8 63.39,68.8 v2(63.47,68.71)
  BOTTOM w0.127: Q22.6 76.99,76.47 76.87,76.35 R315.2 75.9,76.35 74.97,75.42 74.97,74.75 75.89,73.84 75.89,71.19 75.39,70.69 74.91,70.69 74.18,71.42 72.73,71.42 72.56,71.25 71.65,71.25 71.58,71.33 69.98,71.33 69.84,71.19 v3(69.84,70.75)
SMB_PCH_DAT: length 27.3
  BOTTOM w0.076: 63.37,72.1 63.34,72.12 62.94,72.12 U20.AH1
  BOTTOM w0.127: 63.37,72.1 64.33,72.1 64.55,72.32 65.14,72.32 65.73,71.73 68.19,71.73 68.47,72.01 69.05,72.01 69.51,71.56 71.67,71.56 71.75,71.48 72.47,71.48 72.64,71.65 74.28,71.65 75,70.92 75.3,70.92 75.66,71.28 75.66,73.74 74.74,74.66 74.74,75.51 75.58,76.35 75.58,78.16 76.05,78.63 R300.2 76.47,78.93 76.47,80.17 76.93,80.62 77.72,80.62 v4(77.84,80.5) 78.23,80.11 78.23,79.9 78.29,79.84 Q22.3
SMB_RUN_CLK: length 323.4
  TOP w0.127: CN1.57 11.91,77.61 11.78,77.48 10.32,77.48 10.08,77.72 10.08,78.03 v2(10.33,78.29)
  IN1 w0.114: v2(10.33,78.29) 10.03,77.98 10.03,77.6 9.5,77.08 8.13,77.08 7.67,76.62 7.67,76.28 4.52,73.13 4.52,66.04 5.3,65.26 5.3,63.2 5.68,62.82 5.68,61.04 5.3,60.66 5.3,59.21 5.52,58.99 5.52,56.6 4.08,55.16 2.95,55.16 2.84,55.05 2.84,36.94 5.68,34.1 5.68,30.98 6.45,30.22 13.44,30.22 13.64,30.02 26.66,30.02 27.74,28.94 63.24,28.94 64.64,30.33 68.24,30.33 68.69,30.78 68.69,31.03 68.53,31.18 68.38,31.18 v2(68.11,30.92) 67.87,31.16 67.54,31.16 67.32,31.38 67.32,32.07 68.36,33.1 68.36,34.43 70.9,36.97 70.9,48.66 72.69,50.46 72.69,51 75.36,53.67 75.36,54.86 72.71,57.51 72.71,58.37 73.92,59.58 73.92,63.47 75.57,65.12 75.57,68.62 76.66,69.72 76.66,72.38 80.1,75.83 80.1,77.75 80.38,78.03 80.92,78.03 v3(81.02,78.14) 81.26,77.89 81.54,77.89 86.05,82.4 86.05,82.99 89.09,86.04 92.3,86.04 92.79,85.54 94.52,85.54 96.46,83.6 101.42,83.6 102.91,82.11 111.23,82.11 112.44,83.32 127.2,83.32 129.74,80.77 139.4,80.77 140.4,79.77 160.97,79.77 162.65,78.08 173.91,78.08 174.36,77.63 174.36,77.37 v2(174.54,77.2)
  BOTTOM w0.127: Q22.1 76.99,78.46 77.34,78.11 78.5,78.11 79.1,78.71 R299.2 79.61,78.71 79.82,78.49 79.82,78.26 79.95,78.14 v3(81.02,78.14) ; v2(174.54,77.2) 174.31,76.97 174.31,74.83 175.23,73.92 204.7,73.92 204.87,74.09 204.87,74.43 204.74,74.56 R332.2 ; JDIM1.202 68.15,30.08 67.96,30.27 67.96,30.76 v2(68.11,30.92)
SMB_RUN_DAT: length 322.9
  TOP w0.127: CN1.56 11.93,77.11 11.8,77.25 10.23,77.25 9.85,77.63 9.85,78.14 v2(9.69,78.29)
  IN1 w0.114: v2(173.91,77.2) 174.15,77.44 174.15,77.54 173.82,77.87 162.56,77.87 160.88,79.55 140.31,79.55 139.31,80.56 129.65,80.56 127.11,83.1 112.53,83.1 111.32,81.89 102.82,81.89 101.33,83.38 96.37,83.38 94.43,85.32 92.7,85.32 92.21,85.82 89.18,85.82 86.26,82.9 86.26,82.31 81.63,77.68 80.66,77.68 v2(80.56,77.58) 80.32,77.34 80.32,75.74 76.88,72.29 76.88,69.63 75.79,68.53 75.79,65.03 74.13,63.38 74.13,59.49 72.93,58.28 72.93,57.6 75.58,54.95 75.58,53.58 72.91,50.91 72.91,50.37 71.11,48.57 71.11,36.88 68.57,34.34 68.57,33.01 67.54,31.98 67.54,31.47 67.63,31.37 67.86,31.37 v3(68.11,31.63) 68.34,31.4 68.62,31.4 68.9,31.12 68.9,30.69 68.33,30.12 64.72,30.12 63.33,28.72 27.65,28.72 26.57,29.8 13.55,29.8 13.35,30 6.36,30 5.47,30.89 5.47,34.01 2.62,36.85 2.62,55.14 2.86,55.38 3.99,55.38 5.3,56.69 5.3,58.9 5.08,59.12 5.08,60.75 5.47,61.13 5.47,62.73 5.08,63.11 5.08,65.17 4.3,65.95 4.3,73.22 7.45,76.37 7.45,76.71 8.04,77.29 9.41,77.29 9.81,77.69 9.81,78.17 v2(9.69,78.29)
  BOTTOM w0.127: Q22.4 78.43,77.06 78.82,76.68 R312.2 79.43,76.68 79.82,77.07 79.82,77.73 80,77.91 80.46,77.91 80.56,77.81 v2(80.56,77.58) ; v2(173.91,77.2) 174.08,77.02 174.08,74.74 175.13,73.69 204.79,73.69 205.1,74 205.1,74.45 205.2,74.56 R331.2 ; JDIM1.200 67.55,30.99 68.11,31.55 v3(68.11,31.63)
SMBALERT#: length 6.6
  BOTTOM w0.076: U20.AN2 62.28,69.25 62.57,69.55 62.97,69.55 63.08,69.44 64.11,69.44 64.51,69.04 64.61,69.04
  BOTTOM w0.127: R377.1 67.87,67.94 67.57,68.24 65.92,68.24 65.12,69.04 64.61,69.04
SMC: length 18.5
  BOTTOM w0.127: 171.7,85.04 171.7,85.7 v4(171.57,85.83) ; 171.7,85.04 171.27,85.04 170.48,84.26 168.95,84.26 168.16,85.04 166.84,85.04 165.85,84.05 161.05,84.05 160.44,84.66 159.06,84.66 158.97,84.75 158.97,84.92 159.4,85.35 CN9.5 ; 171.7,85.04 172.74,85.04 172.87,85.17 172.87,85.41 PR121.1
SMD: length 19.3
  BOTTOM w0.127: 171.7,84.82 172.84,84.82 173.1,85.07 173.1,85.32 PR120.1 ; 171.7,84.82 171.37,84.82 170.58,84.03 168.85,84.03 168.06,84.82 166.94,84.82 165.95,83.83 160.96,83.83 160.35,84.43 158.96,84.43 158.74,84.66 158.74,84.94 158.15,85.53 CN9.6 ; 171.7,84.82 v4(171.7,84.05)
SMDDR_VREF_DQ1_M1: length 8.5
  BOTTOM w0.508: R355.2 13.66,71.66 v4(13.38,71.38) 13.16,71.16 R367.1 13.16,69.77 R376.2 13.72,69.12 12.98,68.38 R384.2 12.98,66.19 13.63,65.54 R387.1
SMDDR_VREF_DQ1_M3: length 30.6
  TOP w0.508: v2(24,59.29) 24.88,59.29 v1(28.97,63.38) 29.71,64.11 29.71,64.75 30.68,65.72 30.68,66.26 31.03,66.62 31.03,68.14 31.39,68.51 v2(31.66,68.51)
  BOTTOM w0.254: v2(31.66,68.51) 31.71,68.51 U20.AP51
  BOTTOM w0.508: R376.1 13.81,66.81 14.67,65.94 14.67,65.07 C279.1 14.65,64.66 14.65,61.42 16.63,59.44 23.84,59.44 v2(24,59.29)
SML0ALERT#: length 4.4
  BOTTOM w0.076: 63.39,71.1 63.23,71.1 63.12,71.21 62.55,71.21 62.16,70.82 U20.AL2
  BOTTOM w0.127: R370.2 65.5,70.06 64.46,71.1 63.39,71.1
SML1ALERT#: length 7.3
  BOTTOM w0.076: U20.AU4 61.16,66.74 61.16,65.31 61.22,65.26 61.22,64.92 61.41,64.73 61.68,64.73 62.07,64.34 62.32,64.34
  BOTTOM w0.127: TP96.1 63.05,61.66 R403.2 63.05,63.65 62.35,64.34 62.32,64.34
SPKR: length 9
  BOTTOM w0.076: 64.69,76.59 64.3,76.97 63.34,76.97 63.1,77.2 62.46,77.2 U20.V2
  BOTTOM w0.127: 64.69,76.59 65.52,76.59 65.8,76.31 v1(66.79,76.31) 67.51,76.31 67.58,76.38 68.04,76.38 68.09,76.43 68.24,76.43 68.6,76.79 68.79,76.79 R305.2 69.57,77.21 69.72,77.07 R309.2
SRTC_RST#: length 203.5
  TOP w0.127: v2(218.69,106.13) 218.64,106.08 212.04,106.08 210.35,104.4 210.24,104.4 210.21,104.37 209.79,104.37 209.49,104.67 209.49,105.31 208.6,106.21 207.34,106.21 207.31,106.18 206.86,106.18 206.8,106.13 205.55,106.13 204.31,104.88 199.31,104.88 198.06,106.13 194.71,106.13 194.33,105.75 194.33,104.09 192.09,101.86 190.52,101.86 189.88,101.22 187.8,101.22 187.27,100.69 187.27,99.25 177.66,89.64 176.04,89.64 v2(176.01,89.67)
  IN1 w0.127: v3(59.08,66.68) 59.08,66.66 59.41,66.32 61.16,66.32 62.98,64.5 64.99,64.5 65.63,65.14 67.49,65.14 68.61,64.01 70.4,64.01 70.48,64.09 70.48,67.29 70.86,67.67 71.41,67.67 71.89,68.16 71.89,69.09 72.31,69.51 72.31,69.84 73.77,71.3 73.77,71.98 76.95,75.16 76.95,75.94 77.84,76.83 77.84,78.46 78.85,79.47 78.85,79.98 79.32,80.45 80.18,80.45 81.46,81.72 81.66,81.72 82.71,82.78 82.9,82.78 82.9,82.78 83.32,83.2 83.32,83.2 83.41,83.29 83.4,83.29 83.91,83.8 84.42,83.8 88.1,87.48 92.83,87.48 93.49,86.82 94.95,86.82 96.5,85.28 101.97,85.28 103.86,83.39 110.63,83.39 111.8,84.56 127.69,84.56 130.19,82.05 159.47,82.05 160.14,81.39 v2(160.77,81.39)
  BOTTOM w0.127: v3(59.08,66.68) 59.37,66.39 U20.AV6 ; v2(218.69,106.13) 218.69,106.71 217.64,107.75 217.64,109.05 218.33,109.73 R31.1 217.77,109.76 217.62,109.91 217.62,111.1 217.71,111.19 C16.1 R23.2 ; v2(176.01,89.67) 176.01,89.26 175.2,88.45 175.2,87.05 174.62,86.47 174.62,85.83 172.1,83.32 162.7,83.32 v2(160.77,81.39)
SUS_STAT#: length 2.2
  TOP w0.127: v2(61.19,72.63) 61.65,73.09 62.47,73.09 TP44.1
  BOTTOM w0.127: U20.AG4 61.19,72.71 v2(61.19,72.63)
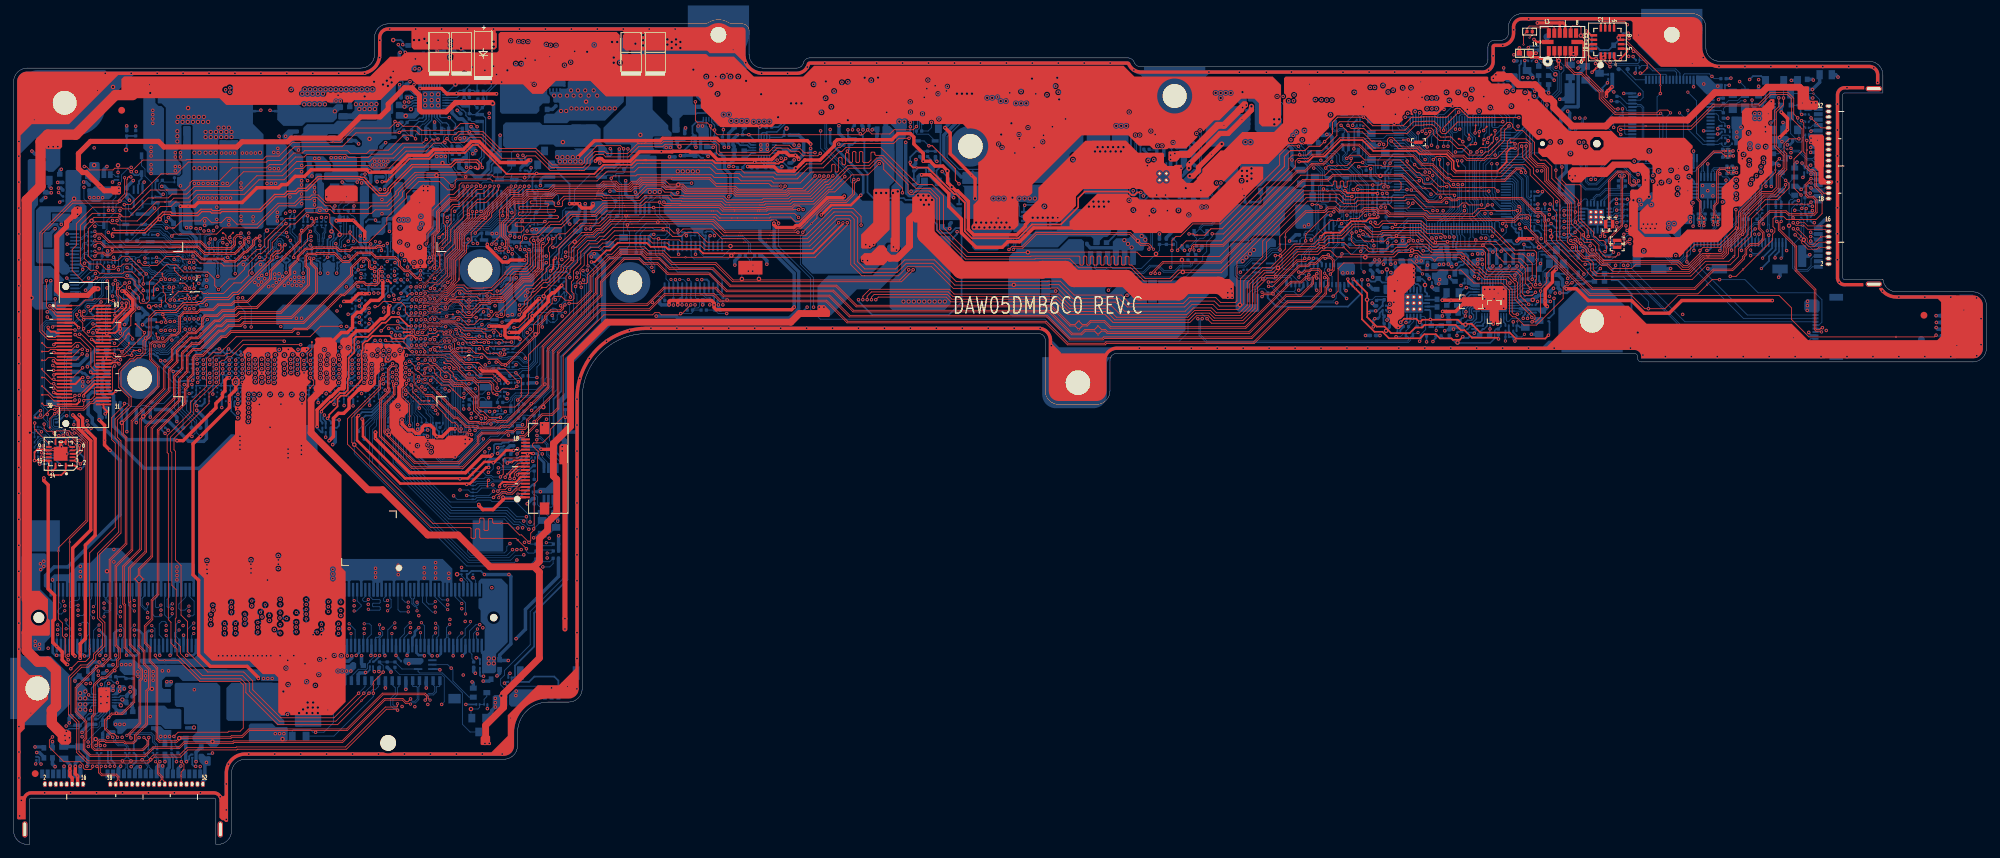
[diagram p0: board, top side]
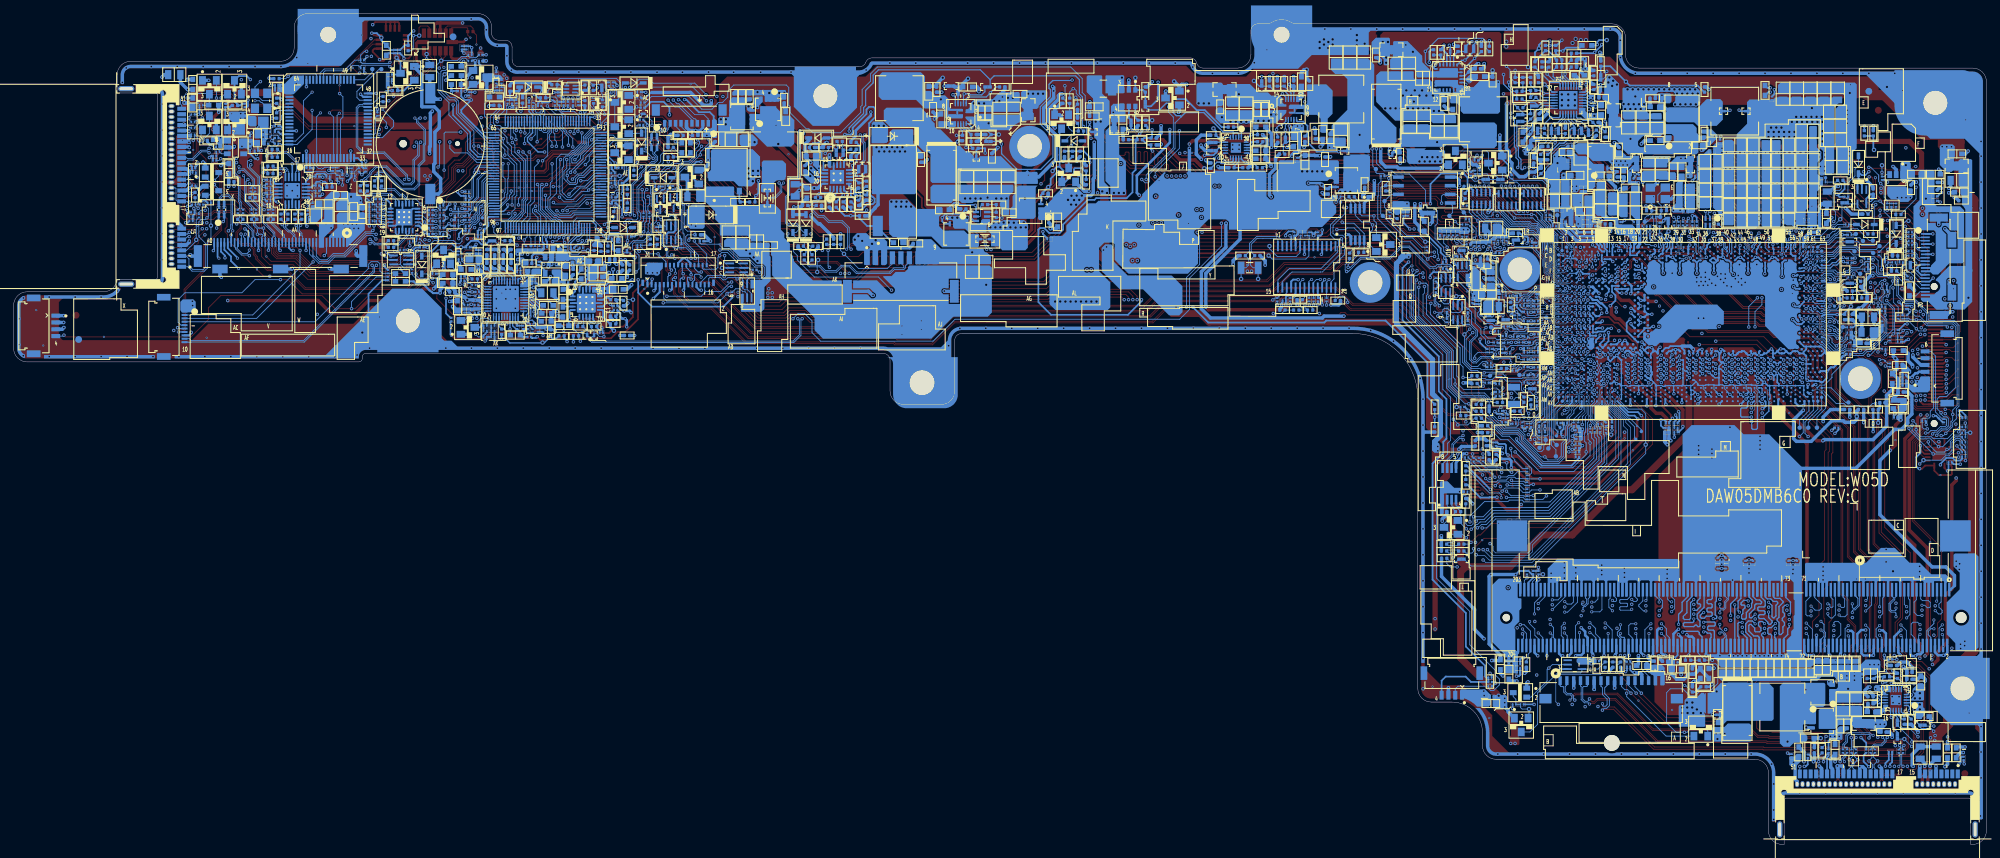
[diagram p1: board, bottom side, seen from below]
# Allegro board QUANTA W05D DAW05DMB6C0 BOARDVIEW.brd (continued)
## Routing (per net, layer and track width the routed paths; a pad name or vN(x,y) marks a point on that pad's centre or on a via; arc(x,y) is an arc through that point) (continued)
SUSACK#: length 19
  TOP w0.127: v2(73.76,69.25) 74.55,68.45 v1(74.55,66.25) 74.55,65.8 v2(74.01,65.25)
  BOTTOM w0.076: 63.39,71.61 63.2,71.61 63.02,71.79 62.69,71.79 62.4,71.5 U20.AK2
  BOTTOM w0.127: 63.39,71.61 64.69,71.61 65.5,70.8 68.22,70.8 69.05,69.96 69.45,69.96 69.57,69.83 R372.1 69.84,69.58 70.17,69.91 R371.2 70.47,69.71 70.85,69.33 73.67,69.33 v2(73.76,69.25) ; R390.2 74.3,65.25 v2(74.01,65.25)
SUSACK#_EC: length 169.1
  IN2 w0.127: v2(75.86,75.67) 76.14,75.67 77.08,76.61 77.08,78.52 76.32,79.28 76.32,80.48 76.87,81.03 80.21,81.03 80.97,81.79 80.97,83.6 81.83,84.46 81.83,84.47 82.57,85.2 82.57,85.39 82.75,85.57 82.75,86.61 84.6,88.46 84.81,88.46 84.81,88.46 85.24,88.46 86.99,90.21 87.83,90.21 90.73,90.21 92.32,91.8 95.31,91.8 97.35,89.77 98.1,89.77 98.46,90.12 109.85,90.12 112.62,87.36 128.77,87.36 130.37,85.76 133.42,85.76 133.56,85.62 153.76,85.62 156.94,82.43 163.79,82.43 164.99,81.23 170.88,81.23 171.69,82.05 173.67,82.05 175.04,82.05 182.61,89.62 183.24,89.62 188.03,94.4 191.31,94.4 191.58,94.67 192.28,94.67 192.28,94.67 192.49,94.67 194.25,94.67 195.14,95.56 195.35,95.56 195.35,95.56 195.93,95.56 196.08,95.71 196.08,96.17 196.52,96.61 197.92,96.61 198.26,96.27 199.66,96.27 199.97,96.58 200.22,96.58 201.44,97.8 201.65,97.8 206.09,97.8 v2(206.42,97.46)
  BOTTOM w0.127: v2(206.42,97.46) 205.43,97.46 204.34,98.56 U7.17 ; R371.1 71.44,69.72 74.17,69.72 74.34,69.88 75.66,69.88 75.73,69.96 75.73,69.96 76.65,70.87 v4(76.65,74.88) v2(75.86,75.67)
SUSB#: length 202
  IN2 w0.127: v2(204.79,94.19) 204.67,94.06 203.21,94.06 202.68,93.53 202.49,93.53 200.66,91.7 200.19,91.7 200.13,91.76 200.06,91.76 199.89,91.93 199.08,91.93 198.95,91.8 196.75,91.8 196.32,91.37 196.11,91.37 196.11,91.37 195.89,91.37 195.85,91.37 195.43,90.95 195.43,90.95 194.78,90.3 193.85,90.3 190.49,90.3 190.28,90.09 189,90.09 187.94,89.03 187.94,88.49 185.76,86.3 185.76,86.28 185.49,86.02 185.48,86.02 181.35,81.89 181.35,80.09 180.26,79 178.6,79 176.3,79 176.3,79 172.95,79 171.94,77.98 157.07,77.98 152.63,82.43 137.42,82.43 136.9,81.91 105.54,81.91 102.79,84.65 97.02,84.65 95.09,86.58 93.47,86.58 92.81,86.58 92.61,86.78 88.68,86.78 85.97,84.08 85.97,82.87 81.46,78.36 81.46,77.77 80.76,77.07 80.46,77.07 75.86,72.47 75.86,70.52 75.18,69.83 75.18,64.92 74.29,64.03 74.29,60.37 72.51,58.6 72.51,56.83 71.32,55.63 71.32,55.43 v2(71.19,55.3) 70.74,54.86 70.74,53.49 71.04,53.19 72.25,53.19 72.57,52.87 72.57,52.49 71.51,51.43 70.08,51.43 62.76,58.75 62.76,60.18 61.84,61.09 61.84,62.46 61.49,62.82 61.49,62.97 60.93,63.53 60.93,66.29 v2(60.42,66.8)
  BOTTOM w0.127: U7.6 204.76,94.16 v2(204.79,94.19) ; v2(60.42,66.8) 60.42,67.27 U20.AT4 ; v2(71.19,55.3) 73.59,55.3 R443.2 74.68,56.25 75.16,56.73 R442.2 75.46,56.89 v2(75.46,57.33)
SUSC#: length 209.6
  IN2 w0.127: v2(208.15,95.48) 207.87,95.2 206.44,95.2 205.91,94.67 203.47,94.67 202.58,93.78 202.38,93.78 201.44,92.84 200.14,92.84 199.97,93.02 198.47,93.02 197.53,92.08 197.51,92.08 196.67,92.08 196.21,91.62 196,91.62 196,91.62 195.79,91.62 195.79,91.62 194.81,91.62 193.74,90.56 190.39,90.56 190.17,90.34 188.27,90.34 184.83,86.9 184.83,86.12 181.09,82.38 181.09,80.19 180.15,79.25 176.2,79.25 176.2,79.25 172.85,79.25 171.86,78.26 171.65,78.26 170.38,78.26 170.38,78.26 157.15,78.26 152.73,82.68 136.78,82.68 136.35,82.25 105.55,82.25 102.9,84.9 97.13,84.9 95.2,86.84 93.36,86.84 92.94,86.83 92.92,86.84 92.71,87.04 88.57,87.04 85.72,84.18 85.72,82.97 81.52,78.77 80.81,78.77 80.51,78.47 80.38,78.47 79.95,78.03 79.95,76.92 75.61,72.57 75.61,71.15 74.92,70.46 74.92,65.03 73.78,63.88 73.78,60.22 72.26,58.7 72.26,57 70.46,55.2 70.46,54.93 70.22,54.7 70.22,52.94 v2(70.38,52.79) 69.44,52.79 63.39,58.84 63.39,60.92 62.73,61.58 62.73,64.5 61.97,65.26 61.97,69.7 61.56,70.11 60.93,70.11 60.6,70.44 60.34,70.44 59.79,70.99 59.79,72.31 v3(59.76,72.34)
  BOTTOM w0.127: U20.AJ6 59.76,72.08 v3(59.76,72.34) ; R450.2 67.95,52.16 68.47,52.68 70.27,52.68 v2(70.38,52.79) ; U7.16 204.3,98.16 205.81,96.65 206.98,96.65 v2(208.15,95.48)
SUSON: length 278.6
  IN2 w0.127: v2(216.07,92.65) 214.57,92.65 214.11,92.19 211.94,92.19 210.35,93.78 207.44,93.78 206.2,92.54 203.67,92.54 203.26,92.13 203.07,92.13 200.54,89.6 198.84,89.6 198.14,88.91 197.43,88.91 196.54,88.02 194.87,88.02 192.48,88.02 191.75,87.28 191.12,87.28 189.12,87.28 187.53,85.69 187.53,80.68 183.07,76.22 156.5,76.22 153.52,79.2 121.12,79.2 120.39,79.93 112.91,79.93 112.33,79.35 105.41,79.35 102.87,81.89 94.23,81.89 92.46,80.13 86.34,80.13 78.81,72.59 77.61,71.4 77.61,62.42 76.29,61.1 76.29,58.4 77.46,57.24 77.46,53.09 76.9,52.53 76.9,50.14 75.83,49.07 74.99,49.07 70.86,44.94 70.86,40.65 73.37,38.13 73.37,32.44 71.59,30.66 71.16,30.66 68.35,27.86 67.75,27.86 67.3,27.41 67.3,27.28 63.81,23.79 63.81,22.65 63.36,22.2 54.13,22.2 49.14,17.21 38.02,17.21 37.56,16.76 31.37,16.76 29.53,14.92 26.22,14.92 25.14,13.84 16.12,13.84 15.51,13.22 11.01,13.22 10.56,13.68 10.56,13.98 v2(10.96,14.38)
  BOTTOM w0.127: PR131.2 v4(12.05,15.47) v2(10.96,14.38) ; U7.98 217.1,91.34 216.07,92.36 v2(216.07,92.65)
SUSWARN#: length 27.4
  BOTTOM w0.076: 61.14,63.16 60.95,63.35 60.95,63.69 60.7,63.94 60.7,64.09 59.9,64.89 59.9,65.88 60.07,66.05 60.49,66.05 U20.AV4
  BOTTOM w0.127: R390.1 R397.2 74.15,63.47 73.14,62.46 72.74,62.46 71.95,61.68 71.77,61.68 70.86,60.76 68.72,60.76 68.01,60.05 68.01,59.51 65.4,56.9 v2(64.84,56.9) 64.39,56.46 63,56.46 62.43,57.03 62.43,58.86 61.76,59.52 61.76,61.45 61.58,61.64 R404.1 61.58,62.73 61.14,63.16
SUSWARN#_EC: length 179.2
  IN2 w0.127: v2(83.61,84.26) 83.51,84.36 83.51,86.29 84.92,87.7 85.55,87.7 87.3,89.45 87.52,89.45 91.11,89.45 92.7,91.04 94.98,91.04 97.54,88.48 97.75,88.48 97.75,88.48 110.35,88.48 112.24,86.59 128.14,86.59 130.79,83.94 132.83,83.94 133.24,84.35 153.23,84.35 157.79,79.79 171.02,79.79 171.23,79.79 172.22,80.78 173.14,80.78 175.56,80.78 179.27,84.49 181.04,84.49 183.28,86.72 183.28,87.76 188.24,92.73 192.15,92.73 193.08,93.65 194.67,93.65 195.03,94.01 197.63,94.01 198.42,94.8 199.43,94.8 199.43,94.8 199.64,94.8 202.15,94.8 203.96,96.6 205.38,96.6 205.76,96.22 207,96.22 207.51,96.73 208.48,96.73 209.33,97.58 212.09,97.58 v2(212.77,96.91)
  BOTTOM w0.127: v2(83.61,84.26) 83.61,84.15 84.4,83.36 84.4,77.54 79.05,72.19 79.05,68.26 79.04,68.25 79.04,67.2 76.54,64.7 v2(76.01,64.7) 75.36,64.05 75.36,63.79 75.18,63.61 R397.1 ; U7.112 211.5,91.95 212.59,93.05 212.59,96.73 v2(212.77,96.91)
SWCLK: length 3.6
  BOTTOM w0.127: U5.49 238.16,112.28 237.02,113.42 TP64.1
SWDIO: length 7.6
  BOTTOM w0.127: TP65.1 236.01,113.85 239.29,110.57 239.29,109.68 238.89,109.28 U5.46
SWN: length 30.3
  IN1 w0.254: v2(37.65,107.8) 39.53,109.68 45.81,109.68 46.45,110.32 54.75,110.32 56.08,111.64 56.08,113.34 57.62,114.89 57.62,117.2 57.37,117.45 v2(57.14,117.45)
  BOTTOM w0.254: v4(55.75,118.12) 56.86,118.12 57.14,117.84 v2(57.14,117.45) 57.27,117.33 PR1.2 ; v2(37.65,107.8) 37.78,107.68 PR39.1
SYS_I: length 84.6
  IN2 w0.127: v2(217.8,103.64) 217.67,103.64 216.59,104.72 216.59,105.25 216.07,105.77 213.83,105.77 213.28,106.33 211.41,106.33 210.79,106.95 205.75,106.95 204.87,107.83 204,107.83 203.78,107.6 203.77,107.6 202.6,106.43 191.88,106.43 191.83,106.38 191.8,106.38 189.8,104.37 189.32,104.37 188.68,105.02 187.84,105.02 186.06,103.24 182.99,103.24 182.03,102.29 179.29,102.29 172.86,95.86 166.72,95.86 166.31,96.27 164.69,96.27 v2(164.41,95.99)
  BOTTOM w0.127: R207.1 217.95,88.65 219.19,89.9 v2(219.19,90.78) 219.19,91.45 218.94,91.7 217.09,91.7 216.53,92.27 216.53,92.89 216.07,93.35 216.07,95.04 215.8,95.31 215.8,95.91 215.8,95.91 215.8,99.92 217.11,101.23 217.11,102.24 217.8,102.93 v2(217.8,103.64) 218.32,104.16 U7.66
  BOTTOM w0.254: PR99.1 164.59,96.62 164.92,96.29 164.92,95.56 164.72,95.37 PC118.1 164.33,95.49 164.33,95.94 164.38,95.99 v2(164.41,95.99)
SYS_PWROK: length 93.2
  TOP w0.127: v2(64.84,74.07) 64.1,74.81 63.14,74.81 63.09,74.86 63.09,75.27 62.96,75.39 62.23,75.39 61.86,75.02 60.96,75.02 v1(60.79,74.85) 60.7,74.76 59.07,74.76 58.89,74.94 58.89,75.44 58.67,75.67 57.28,75.67 56.65,76.31 54.86,76.31 v2(53.97,75.42)
  IN1 w0.127: v2(53.97,75.42) 53.71,75.16 52.97,75.16 52.02,74.21 49.81,74.21 49.62,74.02 41.65,74.02 41.01,73.39 38.6,73.39 37.19,74.79 32.62,74.79 29.2,78.21 27.93,78.21 26.79,79.35 25.04,79.35 24.02,80.37 22.73,80.37 22.34,79.99 19.84,79.99 19.3,79.44 18.88,79.44 18.66,79.66 18.1,79.66 16.92,78.48 15.28,78.48 15.2,78.4 15.04,78.4 11.76,75.12 v2(11.65,75.12)
  BOTTOM w0.127: U20.AG2 62.5,73.34 62.97,73.34 63.11,73.47 64.24,73.47 v2(64.84,74.07) 66.17,74.07 R346.1 66.53,73.5 66.77,73.26 69.87,73.26 70.4,72.73 C275.1 70.57,72.99 70.76,73.18 72.05,73.18 72.1,73.23 73.22,73.23 73.56,73.58 73.56,74.19 74.24,74.86 74.24,75.72 75.07,76.56 75.07,78.72 75.25,78.9 75.58,78.9 75.96,79.28 75.96,81.11 77.63,82.78 U16.4 77.63,84.06 77.54,84.16 76.2,84.16 75.94,84.42 75.94,86.01 76.69,86.76 R230.1 ; R342.1 12.31,74.45 v2(11.65,75.12)
SYS_RESET#: length 37.2
  TOP w0.076: 65.52,74.25 65.37,74.25 65.2,74.43 65.02,74.43 64.64,74.81 64.64,75.32 64.28,75.67 63.95,75.67 v2(63.49,75.21)
  TOP w0.127: 65.52,74.25 65.91,74.25 66.52,73.64 67.02,73.64 67.4,73.26 68.7,73.26 68.95,73 68.95,72.71 69.54,72.12 v1(70.45,72.12) 70.92,72.12 71.31,71.72 71.84,71.72 v2(72.1,71.99)
  IN1 w0.127: v2(75.15,71.4) 75.15,70.16 74.55,69.56 74.55,66.43 72.76,64.64 72.76,63 69.99,60.24 69.99,58.25 69.89,58.15 v2(69.84,58.15)
  BOTTOM w0.076: v2(63.49,75.21) 63.34,75.37 63.16,75.37 62.99,75.54 62.63,75.54 62.5,75.41 62.5,75.08 62.38,74.96 61.92,74.96 61.67,75.21 U20.AC3
  BOTTOM w0.127: v2(75.15,71.4) 75.15,71.76 74.65,72.26 R356.1 R357.1 72.52,72.26 72.26,71.99 v2(72.1,71.99) ; R446.2 68.15,55.21 69.26,56.32 69.26,56.53 69.72,56.98 69.72,57.64 69.84,57.76 v2(69.84,58.15)
TD_IREF: length 4.3
  BOTTOM w0.127: U20.B12 55.35,88.48 55.41,88.55 55.41,89.54 55.98,90.11 R172.1
TEMP_MBAT: length 74.2
  TOP w0.127: v2(219.6,105.52) 218.91,104.83 218.91,103.35 216.76,101.2 216.38,101.2 215.9,100.72 213.48,100.72 212.98,101.21 211.43,101.21 210.71,101.94 206.93,101.94 206.44,102.42 203.88,102.42 202.51,103.79 202.02,103.79 201.77,103.54 201.77,102.67 201.36,102.27 199.76,102.27 198.26,103.76 194.73,103.76 192.32,101.35 190.73,101.35 190.09,100.72 188.59,100.72 188.21,100.33 188.21,99.47 177.36,88.63 172.2,88.63 v1(171.61,88.03) 170.93,87.36 v2(170.93,87.23)
  BOTTOM w0.127: v2(219.6,105.52) 219.7,105.62 219.7,106.89 218.4,108.19 PC43.2 218.1,108.54 218.05,108.49 218.05,108.08 219.22,106.91 219.22,105.85 218.94,105.57 218.28,105.57 217.97,105.26 217.24,105.26 217.1,105.4 U7.63 ; PR118.2 170.32,88.89 170.81,88.4 170.81,87.36 v2(170.93,87.23)
TEST_A4: length 5.6
  BOTTOM w0.127: U20.A4 60.92,87.88 61.54,88.5 61.54,89.18 62.88,90.53 62.88,91.12 63.01,91.24 TP71.1
TEST_A60: length 11.3
  BOTTOM w0.076: 25.5,88.37 26.09,87.78
  BOTTOM w0.089: 26.09,87.78 U20.A60
  BOTTOM w0.127: TP79.1 17.19,88.68 18.92,90.4 19.75,90.4 19.93,90.23 21.51,90.23 22.09,89.64 22.29,89.64 23.31,88.63 25.25,88.63 25.5,88.37
TEST_A62: length 7.4
  BOTTOM w0.127: U20.A62 24.37,88.12 23.08,88.12 22.12,89.08 18.58,89.08 TP80.1
TEST_AV1: length 9
  BOTTOM w0.076: 63.39,65.95 62.95,66.4 U20.AV1
  BOTTOM w0.127: 63.39,65.95 63.57,65.77 63.57,65.75 63.82,65.5 63.82,64.78 64.13,64.47 64.13,58.35 TP105.1
TEST_AW1: length 7.6
  BOTTOM w0.127: TP103.1 63.62,59.16 63.62,64.24 62.81,65.05 U20.AW1
TEST_AW63: length 5.3
  BOTTOM w0.127: TP98.1 26.15,61.98 24.19,63.95 U20.AW63
TEST_AY60: length 4.5
  BOTTOM w0.127: TP97.1 27.42,62.31 26.07,63.67 U20.AY60
TEST_B2: length 2.8
  TOP w0.127: v2(62.48,89.13) 62.98,89.64 TP13.1
  BOTTOM w0.127: v2(62.48,89.13) 62.31,88.96 U20.B2
THER_CPU: length 2.5
  BOTTOM w0.254: R72.2 v2(81.02,62.72) R69.1
THER_GPU: length 3.4
  BOTTOM w0.254: v4(16.5,101.99) 16.6,102.09 R71.2 R68.1
THRM_ALERT_HW#1: length 35.1
  TOP w0.127: v2(213.99,101.68) 213.25,102.42 213.23,102.42 212.95,102.7 212.27,102.7 211.07,103.89 210.65,103.89 210.45,103.89 210.42,103.87 210,103.87 210,103.87 209.58,103.87 208.98,104.46 208.98,105.1 208.39,105.7 207.55,105.7 207.52,105.67 207.07,105.67 207.02,105.62 205.86,105.62 204.61,104.37 199.05,104.37 198.29,105.14 v1(197.45,105.14) 196.41,105.14 v2(195.95,105.59)
  BOTTOM w0.127: R49.2 195.95,106.25 v2(195.95,105.59) ; v2(213.99,101.68) 213.76,101.45 213.76,94.49 214.24,94 214.24,92.24 214.8,91.68 214.8,91.64 215.1,91.35 U7.103
THRM_MOINTOR: length 130.9
  IN2 w0.254: v2(122.52,104.94) 122.52,105.19 124.24,106.91 130.93,106.91 131.33,106.51 133.74,106.51 135.04,107.8 145.66,107.8 148.71,104.75 163.74,104.75 164.17,105.19 165.8,105.19 167.35,103.64 170.76,103.64 171.24,103.15 174.11,103.15 177.2,106.24 182.17,106.24 183.86,107.93 188.64,107.93 189.6,108.9 189.6,110.34 190.09,110.83 194.2,110.83 195.8,109.23 201.85,109.23 203.22,110.6 205.39,110.6 206.28,111.49 214.32,111.49 215.46,110.34 217.01,110.34 217.65,109.71 223.16,109.71 v2(223.33,109.89) 224.63,108.59 v2(225.16,108.59)
  BOTTOM w0.203: U7.74 221.53,100.96 222.65,102.08 222.65,104.58 225.16,107.09 v2(225.16,108.59)
  BOTTOM w0.254: v2(223.33,109.89) 223.24,109.98 C22.2 ; v2(122.45,101.82) 122.68,102.05 C45.2 123.17,102.72 R62.2 123.68,103.74 R61.1 122.52,103.9 v2(122.52,104.94)
THRM_MOINTOR1: length 392.9
  IN1 w0.254: v2(17.92,105.47) 17.92,106.13 21.23,109.43 28.29,109.43 30.19,107.52 32.4,107.52 35.32,104.6 41.44,104.6 43.05,103 43.05,101.15 44.72,99.47 52.04,99.47 52.27,99.24 57.04,99.24 59.28,101.48 61.03,101.48 61.66,102.11 66.54,102.11 67.45,103.03 69.08,103.03 69.66,103.61 71.92,103.61 72.1,103.79 77.9,103.79 78.38,104.27 103.12,104.27 103.6,104.75 117.75,104.75 118.33,104.17 119.83,104.17 120.67,105.01 121.61,105.01 122.27,105.67 123.28,105.67 v2(124.02,104.93) ; v2(124.07,79.99) 117.62,79.99 v2(116.53,78.9)
  IN2 w0.254: v2(230.42,87.15) 230.83,87.56 230.83,88.58 230.9,88.65 232.96,88.65 233.24,88.37 236.31,88.37 236.97,87.71 237.69,87.71 238.04,88.07 238.04,94.67 234.76,97.95 234.76,101.12 237.05,103.41 237.05,105.26 235.65,106.66 233.53,106.66 232.9,106.02 220.61,106.02 216.8,109.83 215.23,109.83 214.8,110.27 213.94,110.27 213.23,110.98 206.49,110.98 205.61,110.09 203.47,110.09 203.41,110.03 203.4,110.03 203.15,109.77 203.14,109.77 202.02,108.65 195.64,108.65 193.97,110.32 190.42,110.32 190.11,110.01 190.11,108.68 188.85,107.42 184.11,107.42 182.38,105.69 177.37,105.69 174.19,102.52 169.64,102.52 169.05,103.1 167.17,103.1 165.59,104.68 164.38,104.68 163.95,104.25 148.46,104.25 145.41,107.29 135.25,107.29 132.8,104.85 131.33,104.85 131.3,104.88 128.01,104.88 126.99,105.9 124.66,105.9 124.02,105.26 v2(124.02,104.93)
  BOTTOM w0.254: v2(124.02,104.93) 124.02,104.68 v2(124.34,104.36) 124.72,103.98 R62.1 ; C43.2 R62.1 ; R62.1 124.93,103.27 124.93,99.07 125.39,98.61 125.39,95.76 126.26,94.9 130.73,94.9 130.98,94.65 131.97,94.65 135.58,91.04 135.58,90.3 136.09,89.79 137.63,89.79 138.35,90.51 138.98,90.51 139.21,90.28 139.21,79.63 137.36,77.78 126.05,77.78 124.07,79.76 v2(124.07,79.99) ; R69.2 82.08,65.7 82.08,70.77 88.23,76.92 96.94,76.92 97.22,76.64 114.27,76.64 v2(116.53,78.9) ; R206.1 220.35,88.12 221,88.12 221.51,88.63 222.52,88.63 222.96,88.18 222.97,88.18 223.22,87.93 C194.2 v4(223.99,87.69) 224.76,87.69 225.32,88.24 227.17,88.24 228.27,87.15 v2(230.42,87.15) ; R68.2 v2(17.92,105.47)
TPM_PP: length 10
  BOTTOM w0.127: R194.1 R195.1 99.43,88.94 99.49,88.88 U15.7 99.49,86.41 99.94,85.96 104.89,85.96 v4(105.4,86.47)
TPM_XIN: length 12.8
  BOTTOM w0.127: v4(109.45,83.04) Y3.2 108.7,84.69 108.32,85.07 108.32,85.97 C202.1 108.21,87.08 108.21,88.23 107.18,89.26 104.01,89.26 103.39,88.64 U15.13
TPM_XOUT: length 11.8
  BOTTOM w0.127: v4(106.95,83.04) Y3.1 107.69,84.69 108.07,85.07 108.07,85.84 C203.1 107.95,86.98 107.95,88.13 107.07,89.01 104.26,89.01 104.04,88.79 U15.14
TS_INTB#: length 8
  BOTTOM w0.076: 65.4,79.51 64.94,79.51 64.41,78.97 63.93,78.97 63.61,79.29 61.69,79.29 61.59,79.39 61.33,79.39 61.02,79.71 U20.P4
  BOTTOM w0.127: 65.4,79.51 65.52,79.51 65.64,79.39 66.58,79.39 66.69,79.49 67.04,79.49 67.05,79.48 67.81,79.48 67.92,79.37 R293.1
TS_ON: length 128.5
  TOP w0.127: v2(202.28,103.31) 203.42,102.16 206.21,102.16 206.7,101.68 210.58,101.68 211.31,100.96 212.86,100.96 213.35,100.46 216,100.46 216.31,100.77 217.82,100.77 219.35,102.29 219.35,103.18 219.78,103.61 222.11,103.61 222.83,102.9 222.83,101 223.85,99.98 224.53,99.98 224.74,99.98 225.37,99.35 225.37,97.59 228.74,94.21 228.74,91.14 230.14,89.74 230.14,88.96 230.73,88.37 231.67,88.37 232.3,87.74 232.3,87.08 232.5,86.87 232.5,86.81 233.52,85.79 233.54,85.79 233.58,85.76 244.48,85.76 245.23,85.01 245.82,85.01 247.64,86.83 v2(247.64,87.23) 248.09,87.67 250.61,87.67 253.31,90.37 253.31,92.89 256.76,96.35 256.76,96.73 258.72,98.68 v1(258.72,99.04) 258.72,100.11 v2(259.3,100.69)
  BOTTOM w0.127: R25.2 201.67,111.38 201.16,110.88 201.16,110.06 201.44,109.78 202.12,109.78 202.25,109.65 202.25,107.04 203.29,106 203.29,105.24 203.6,104.93 204.33,104.93 205.53,103.74 205.53,102.99 205.53,102.99 205.53,102.76 207.17,101.12 207.36,101.12 207.74,100.74 207.74,100.16 207.66,100.08 207.1,100.08 206.44,100.74 206.44,101.2 204.29,103.36 U7.29 202.33,103.36 v2(202.28,103.31) ; v2(247.64,87.23) 247.64,84.7 254.59,77.75 CN11.2 ; R70.1 259.95,101.1 C55.1 R73.2 259.55,100.44 v2(259.3,100.69)
TSENSE: length 5.8
  BOTTOM w0.127: PR17.1 56.45,112.42 56.26,112.42 55.92,112.76 55.92,113.34 v2(55.75,113.52)
  BOTTOM w0.178: PU3.13 58.85,110.08 58.64,110.29 58.59,110.29 58.04,110.84 PC27.1 57.53,110.84 57.17,111.21 57.17,111.97 56.9,112.24 PR17.1
UART0_CTS: length 16
  BOTTOM w0.076: 64.43,87.13 64.43,86.88 64.2,86.65 64.2,85.36 63.99,85.15 63.99,84.71 63.55,84.27 63.55,84.05 62.99,83.49 U20.G1
  BOTTOM w0.127: 64.43,87.13 64.43,89.07 65.5,90.14 65.5,90.2 65.5,90.2 65.5,90.39 65.68,90.57 66.02,90.91 66.84,90.91 67.16,91.23 69.61,91.23 71.24,92.86 71.24,93.07 71.62,93.45 RP3.6
UART0_RTS: length 20.6
  BOTTOM w0.076: 64.66,87.21 64.66,86.88 64.36,86.58 64.36,85.3 64.15,85.09 64.15,84.64 63.71,84.2 63.71,83.95 62.96,83.2 62.48,83.2 62.16,82.89 U20.J2
  BOTTOM w0.127: 64.66,87.21 64.66,88.98 65.59,89.91 65.73,90.05 65.73,90.3 65.91,90.47 66.09,90.66 66.94,90.66 67.26,90.98 69.71,90.98 71.6,92.87 72.36,92.87 72.48,92.74 72.48,92.46 v1(72.51,92.44) 72.69,92.26 73.47,92.26 73.91,92.69 73.91,93.07 73.53,93.45 RP1.9
UART0_RXD: length 19.7
  BOTTOM w0.076: U20.J1 63.03,82.74 64.48,84.19 64.48,84.95 64.69,85.16 64.69,86.44 65.17,86.92 65.17,87.18
  BOTTOM w0.127: RP1.7 v1(74.8,92.82) 73.6,91.62 71.14,91.62 69.99,90.47 67.47,90.47 67.15,90.15 66.48,90.15 66.18,89.86 65.78,89.45 65.78,89.45 65.17,88.84 65.17,87.18
UART0_TXD: length 15.7
  TOP w0.127: v2(61.21,81.64) 61.84,82.28 62.5,82.28 63.69,83.47 63.69,86.03 65.21,87.55 65.21,89.85 67.35,91.99 67.35,92.92 v3(67.37,92.94)
  BOTTOM w0.127: RP2.7 67.3,93.02 v3(67.37,92.94) ; U20.K3 61.21,81.72 v2(61.21,81.64)
UART1_CTS: length 22.5
  BOTTOM w0.076: U20.J4 61.21,82.36 61.6,82.36 61.67,82.28 62.35,82.28 62.52,82.45 62.97,82.45 64.65,84.12 64.65,84.88 64.86,85.09 64.86,86.36 65.42,86.92 65.42,87.1
  BOTTOM w0.127: 65.42,87.1 65.45,87.13 65.45,88.76 66.58,89.9 67.26,89.9 67.58,90.21 70.09,90.21 71.25,91.37 73.86,91.37 74.74,92.25 74.83,92.25 75.43,92.85 RP1.6
UART1_RST: length 21
  BOTTOM w0.076: 64.91,87.15 64.91,86.9 64.53,86.51 64.53,85.23 64.32,85.02 64.32,84.28 63.07,83.03 62.69,83.03 62.5,82.84 62.5,82.66 62.29,82.45 61.77,82.45 U20.J3
  BOTTOM w0.127: 64.91,87.15 64.91,88.91 65.69,89.68 65.96,89.95 65.96,90.2 66.16,90.4 67.05,90.4 67.37,90.72 69.88,90.72 71.04,91.88 73.47,91.88 74.16,92.56 RP1.8
UART1_RXD: length 22.6
  TOP w0.076: 63.47,86.21 63.61,86.35
  TOP w0.089: v3(60.32,81.87) 60.98,82.53 62.13,82.53 63.47,83.87 63.47,86.21
  TOP w0.127: 63.61,86.35 64.96,87.71 64.96,89.96 66.9,91.9 66.9,93.11 68.02,94.24 69.36,94.24 71.21,96.09 v2(71.21,96.68)
  BOTTOM w0.127: v2(71.21,96.68) 71.21,96.35 70.99,96.12 RP3.4 ; U20.K4 60.7,81.87 v3(60.32,81.87)
UART1_TXD: length 16.3
  BOTTOM w0.076: 64.2,88.32 64.23,88.3 64.23,86.91 64.03,86.72 64.03,85.43 63.82,85.22 63.82,84.78 63.38,84.34 63.38,84.12 63.05,83.78 62.46,83.78 U20.G2
  BOTTOM w0.127: 64.2,88.32 64.2,89.17 65.27,90.23 65.27,90.48 65.45,90.66 65.45,90.66 65.85,91.06 65.9,91.12 65.91,91.12 65.96,91.17 66.73,91.17 67.05,91.48 69.5,91.48 70.99,92.97 RP3.7
UNDOCK_INT#: length 44.7
  TOP w0.127: v2(222.27,91.98) 221.56,91.98 v1(221.48,91.9) 221.02,91.9 220.49,91.37 218.86,91.37 v2(218.66,91.17)
  IN2 w0.127: v2(218.66,91.17) 218.02,91.17 217.31,90.45 215.18,90.45 214.94,90.21 208.69,90.21 207.79,89.31 207.79,88.68 207.79,88.22 207.43,87.86 207.39,87.86 207.21,87.69 205.16,87.69 203.83,86.36 203.83,85.66 202.91,84.74 199.56,84.74 198.82,84 198.37,84 v2(198.32,84.06)
  BOTTOM w0.127: R162.2 222.65,91.7 222.37,91.98 v2(222.27,91.98) 222.09,92.16 222.09,92.51 221.78,92.82 221.78,94.01 220.92,94.87 220.92,97.39 220.15,98.16 U7.81 ; v2(198.32,84.06) 197.86,84.52 197.86,86.49 198.8,87.43 198.8,88.19 198.54,88.45 196.89,88.45 196.45,88.89 R211.1
UNDOCK_INT#_L: length 7.8
  BOTTOM w0.127: R212.2 R211.2 196.33,88.11 196.45,87.99 C189.2 197.62,87.75 196.59,86.72 v2(195.06,86.72) 193.92,85.57 CN8.27
USB30_RX1+: length 228.8
  TOP w0.127: R7.1 234.42,91.87 234.42,97.4 235.65,98.63 236.8,98.63 237.15,98.28 237.15,97.09 237.54,96.7 238.14,96.7 238.4,96.96 238.4,97.21 v2(238.63,97.44)
  IN1 w0.114: v2(50.98,83.2) 51.1,83.32 51.63,83.32 52.44,84.13 52.44,87.41 51.99,87.86 51.99,88.35 53.21,89.57 54.09,89.57 55.53,91 59.16,91 59.72,91.56 60.1,91.56 60.95,92.41 62.35,92.41 64.43,94.49 71.19,94.49 71.37,94.49 71.37,94.49 72.15,94.49 72.81,95.15 78.76,95.15 79.13,95.52 87.03,95.52 87.44,95.1 95.85,95.1 96.63,94.33 105.83,94.33 106.01,94.51 106.6,94.51 130.02,94.51 133.16,91.37 135.58,91.37 136.9,92.69 139.47,92.69 140.61,93.83 150.7,93.83 151.08,94.21 153.86,94.21 157.09,90.99 164,90.99 164.52,90.47 178.42,90.47 178.8,90.85 178.8,90.85 179.09,91.14 181.63,91.14 182.83,91.14 188.4,96.71 188.4,96.92 189.06,97.58 190.72,97.58 190.9,97.58 191.75,98.43 192.73,98.43 194.29,99.99 197.26,99.99 198.49,101.22 205.01,101.22 205.23,101 209.2,101 209.2,101 209.26,101 209.57,101 209.97,101 210.12,101.15 211.13,101.15 211.15,101.13 211.3,100.98 211.57,100.98 211.57,100.98 215.83,100.98 216.53,101.68 218.48,101.68 218.6,101.57 221.09,101.57 221.39,101.87 225.23,101.87 225.4,101.87 225.94,102.41 227.54,102.41 227.74,102.6 229.49,102.6 229.69,102.41 230.05,102.41 230.34,102.7 230.34,102.9 v3(230.57,103.13)
  BOTTOM w0.127: v3(230.57,103.13) 230.37,102.93 230.37,101.22 231.06,100.53 231.06,97.41 231.39,97.08 232.38,97.08 234.92,99.62 236.49,99.62 237.41,98.71 237.41,98.53 238.02,97.92 238.14,97.92 v2(238.63,97.44) 238.4,97.21 238.4,96.93 238.59,96.74 C96.1 ; U20.H20 51.04,83.14 v2(50.98,83.2)
USB30_RX1+_C: length 6.4
  BOTTOM w0.127: U12.12 233.6,94.61 234.33,95.33 237.28,95.33 237.43,95.18 237.96,95.18 238.24,95.46 238.24,95.53 238.67,95.96 C96.2
USB30_RX1+_DC: length 31.1
  TOP w0.127: v2(233.65,89.29) 233.44,89.49 233.44,89.72 233.57,89.85 234.15,89.85 234.41,90.11 234.41,90.29 R7.2
  IN1 w0.114: v3(255.08,87.28) 255.08,87.1 254.67,86.68 253.95,86.68 253.71,86.44 245.18,86.44 244.37,85.63 238.98,85.63 237.58,87.03 236.5,87.03 234.85,88.68 233.67,88.68 233.39,88.96 233.39,89.11 233.57,89.29 v2(233.65,89.29)
  BOTTOM w0.127: CN6.33 256.75,87.8 256.89,87.66 256.89,87.53 256.13,86.77 255.41,86.77 255.08,87.1 v3(255.08,87.28) ; v2(233.65,89.29) 233.47,89.46 233.47,89.62 233.6,89.75 U12.19
USB30_RX1-: length 228.8
  TOP w0.127: v2(237.96,97.44) 238.17,97.24 238.17,97.06 238.04,96.93 237.63,96.93 237.38,97.19 237.38,98.37 236.89,98.86 235.56,98.86 234.19,97.5 234.19,91.87 R6.1
  IN1 w0.114: v3(51.02,83.85) 51.02,83.8 51.29,83.53 51.54,83.53 52.23,84.22 52.23,87.32 51.77,87.77 51.77,88.44 53.12,89.78 54.01,89.78 55.44,91.22 59.07,91.22 59.63,91.78 60.01,91.78 60.86,92.63 62.26,92.63 64.34,94.71 71.28,94.71 71.46,94.71 71.46,94.71 72.06,94.71 72.72,95.37 78.67,95.37 79.04,95.74 87.11,95.74 87.53,95.32 95.94,95.32 96.72,94.54 105.74,94.54 105.92,94.72 106.69,94.72 130.11,94.72 133.25,91.59 135.49,91.59 136.81,92.91 139.38,92.91 140.52,94.05 150.61,94.05 151,94.43 153.95,94.43 157.18,91.2 164.09,91.2 164.61,90.68 178.33,90.68 178.58,90.94 179,91.36 181.72,91.36 181.72,91.36 182.13,91.36 182.74,91.36 188.18,96.8 188.18,96.83 188.18,97.01 188.97,97.8 189.15,97.8 190.81,97.8 191.66,98.65 192.64,98.65 194.2,100.21 197.17,100.21 198.4,101.44 205.1,101.44 205.32,101.22 209.29,101.22 209.29,101.22 209.35,101.22 209.66,101.22 209.66,101.22 209.88,101.22 210.03,101.37 211.11,101.37 211.11,101.37 211.22,101.37 211.39,101.2 211.48,101.2 211.48,101.2 215.74,101.2 216.44,101.9 218.57,101.9 218.69,101.78 221,101.78 221.3,102.09 225.32,102.09 225.85,102.62 227.45,102.62 227.65,102.82 229.58,102.82 229.78,102.62 229.96,102.62 230.13,102.79 230.13,102.94 v2(229.94,103.13)
  BOTTOM w0.127: v2(229.94,103.13) 230.14,102.93 230.14,101.12 230.83,100.44 230.83,97.32 231.29,96.86 232.48,96.86 235.02,99.4 236.4,99.4 237.18,98.61 237.18,98.44 237.96,97.65 v2(237.96,97.44) 238.17,97.24 238.17,96.96 237.95,96.74 C97.1 ; U20.G20 51.76,83.68 51.76,83.52 51.71,83.47 51.4,83.47 v3(51.02,83.85)
USB30_RX1-_C: length 6.4
  BOTTOM w0.127: C97.2 238.02,95.7 238.02,95.55 237.87,95.41 237.53,95.41 237.37,95.56 234.23,95.56 233.29,94.62 233.16,94.62 233.1,94.56 U12.11
USB30_RX1-_DC: length 31.1
  TOP w0.127: R6.2 234.18,90.32 234.18,90.2 234.05,90.07 233.48,90.07 233.21,89.81 233.21,89.49 v3(233.01,89.29)
  IN1 w0.114: v3(233.01,89.29) 233.18,89.12 233.18,88.87 233.58,88.46 234.76,88.46 236.41,86.81 237.49,86.81 238.89,85.41 244.46,85.41 245.27,86.23 253.8,86.23 254.04,86.47 v2(255.08,86.47)
  BOTTOM w0.127: CN6.34 257.25,87.77 257.12,87.64 257.12,87.43 256.23,86.54 255.16,86.54 v2(255.08,86.47) ; v3(233.01,89.29) 233.24,89.52 233.24,89.61 233.1,89.76 U12.20
USB30_RX3+: length 104.7
  TOP w0.127: v2(12.11,14.53) 12.31,14.74 12.31,15.09 12.57,15.35 13.45,15.35 13.61,15.19 16.24,15.19 16.42,15.02 17.5,15.02 17.75,15.26 17.75,16.06 19.42,17.73 19.42,22.58 19.82,22.97 19.82,25.68 19.04,26.45 19.04,28.36 18.31,29.1 18.31,38.45 v1(17.78,38.97) 18.31,39.49 18.31,40.46 20.19,42.34 20.19,61.19 24.2,65.21 24.2,68.3 25.37,69.47 25.37,71.87 26.3,72.8 27.38,72.8 30.1,75.52 30.75,75.52 31.51,76.28 33.3,76.28 33.76,76.74 42.52,76.74 49.5,83.72 49.5,84.73 50.98,86.21 51.81,86.21 52.34,85.68 52.34,84.82 52.51,84.66 52.92,84.66 v2(53.03,84.77)
  BOTTOM w0.127: U20.F17 53.45,84.45 53.13,84.77 v2(53.03,84.77) ; R474.2 12.36,14.04 12.36,14.28 v2(12.11,14.53)
USB30_RX3+_R: length 7.3
  TOP w0.127: CN14.20 15,9.17 15.23,9.41 15.23,9.87 15.01,10.09 12.9,10.09 12.46,10.52 12.46,11.23 v2(12.23,11.46)
  BOTTOM w0.127: R474.1 12.44,13.23 12.44,11.66 v2(12.23,11.46)
USB30_RX3-: length 104.7
  TOP w0.127: v2(12.74,14.53) 12.54,14.74 12.54,14.99 12.67,15.12 13.36,15.12 13.51,14.97 16.15,14.97 16.32,14.79 17.59,14.79 17.98,15.17 17.98,15.96 19.65,17.64 19.65,22.48 20.05,22.88 20.05,25.77 19.27,26.55 19.27,28.45 18.53,29.19 18.53,38.45 v1(19.05,38.97) 18.53,39.49 18.53,40.37 20.41,42.25 20.41,61.1 24.43,65.12 24.43,68.21 25.6,69.37 25.6,71.77 26.4,72.57 27.48,72.57 30.19,75.29 30.84,75.29 31.6,76.05 33.39,76.05 33.85,76.51 42.61,76.51 49.73,83.62 49.73,84.64 51.07,85.98 51.71,85.98 52.11,85.58 52.11,84.73 52.41,84.43 52.76,84.43 53.02,84.17 v2(53.02,84.12)
  BOTTOM w0.127: R473.2 12.59,14.19 12.59,14.38 v2(12.74,14.53) ; U20.G17 53.54,83.98 53.27,84.26 53.15,84.26 v2(53.02,84.12)
USB30_RX3-_R: length 7.3
  TOP w0.127: CN14.22 15.8,9.14 15.46,9.48 15.46,9.97 15.11,10.32 12.99,10.32 12.72,10.59 12.72,11.31 v3(12.87,11.46)
  BOTTOM w0.127: R473.1 12.67,13.23 12.67,11.66 v3(12.87,11.46)
USB30_TX1+: length 244.5
  TOP w0.127: v2(236.52,98.18) 236.29,97.95 236.29,90.78 234.46,88.96 234.46,88.4 234.69,88.17 234.97,88.17 235.09,88.29 R8.1
  IN1 w0.114: v2(43.68,89.29) 43.92,89.05 44.1,89.05 44.21,89.16 44.21,90.1 45.57,91.46 46.17,91.46 46.54,91.82 46.54,91.97 47.05,92.48 50.56,92.48 53.56,95.48 57.47,95.48 60.81,98.82 63.11,98.82 69.07,98.82 71,100.76 75.09,100.76 75.47,101.14 78.12,101.14 79.5,99.76 83.72,99.76 85.03,101.07 86.2,101.07 86.99,100.28 87.56,100.28 87.57,100.3 98.46,100.3 98.46,100.28 108.17,100.28 108.53,99.93 112.25,99.93 112.53,100.21 113.89,100.21 114.13,99.97 122.15,99.97 123.97,101.78 131.54,101.78 132.71,102.95 133.27,102.95 133.96,103.65 135.58,103.65 139.48,99.75 162.24,99.75 163.57,99.75 163.75,99.75 167.2,96.3 173.55,96.3 174.46,97.21 174.85,97.21 176.37,95.69 181,95.69 182.85,97.54 182.85,100.28 189.22,106.66 189.4,106.66 193.69,106.66 194,106.96 203.39,106.96 204.7,108.27 206.51,108.27 206.51,108.27 206.69,108.27 207.4,107.56 209.25,107.56 211.19,107.56 211.84,106.91 215.38,106.91 216.22,107.75 220.01,107.75 220.51,108.26 221.81,108.26 222.51,107.56 225.39,107.56 226.62,108.79 228.94,108.79 230.57,107.17 230.57,107.07 230.57,106.98 230.57,106.87 v3(230.78,106.66)
  BOTTOM w0.076: U20.B34 42.59,86.8 42.59,88.04
  BOTTOM w0.127: v3(230.78,106.66) 230.55,106.43 230.55,106 229.43,104.88 229.43,102.92 229.54,102.8 229.54,100.49 230.29,99.74 230.29,96.96 230.9,96.35 232.71,96.35 235.25,98.89 236.06,98.89 236.23,98.71 236.33,98.62 236.33,98.37 v2(236.52,98.18) 236.31,97.97 236.31,97.83 C90.1 ; v2(43.68,89.29) 43.38,88.98 43.2,88.98 42.66,88.44 42.66,88.12 42.59,88.04
USB30_TX1+_C: length 6.1
  BOTTOM w0.127: C90.2 236.09,96.07 233.82,96.07 232.99,95.23 232.55,95.23 232.2,94.87 232.2,94.62 232.1,94.52 U12.9
USB30_TX1+_DC: length 25.9
  TOP w0.127: R8.2 236.25,88.32 236.6,88.32 236.9,88.63 237.13,88.63 v2(237.36,88.85)
  IN1 w0.114: v2(237.36,88.85) 237.36,88.73 237.43,88.65 243.86,88.65 244.14,88.93 255.67,88.93 255.85,89.11 255.85,89.59 255.82,89.62 v3(255.67,89.62)
  BOTTOM w0.127: C187.2 235.05,88.27 236.63,88.27 236.98,88.63 237.15,88.63 237.36,88.83 v2(237.36,88.85) ; CN6.31 255.75,89.01 255.95,89.21 255.95,89.34 v3(255.67,89.62)
USB30_TX1+_DC_C: length 3.6
  BOTTOM w0.127: C187.1 233.89,88.26 233.77,88.14 233.31,88.14 232,89.46 232,89.62 232.1,89.72 U12.22
USB30_TX1-: length 244.5
  TOP w0.127: v2(235.86,98.18) 236.06,97.97 236.06,90.88 234.23,89.05 234.23,88.3 234.59,87.94 234.83,87.94 R9.1
  IN1 w0.114: v2(229.99,106.66) 230.19,106.66 230.35,106.83 230.35,106.98 230.35,107.08 228.86,108.58 226.71,108.58 225.48,107.35 222.6,107.35 222.42,107.35 221.72,108.04 220.6,108.04 220.1,107.54 216.31,107.54 215.47,106.7 211.75,106.7 211.1,107.35 210.56,107.35 210.56,107.35 209.34,107.35 209.34,107.35 207.31,107.35 206.6,108.06 204.79,108.06 203.48,106.75 194.09,106.75 193.78,106.44 189.31,106.44 183.06,100.19 183.06,97.45 181.09,95.47 176.28,95.47 174.76,97 174.55,97 173.64,96.08 167.11,96.08 163.66,99.54 162.33,99.54 139.39,99.54 135.49,103.43 134.05,103.43 133.36,102.74 132.8,102.74 131.63,101.57 124.06,101.57 122.24,99.75 114.04,99.75 113.8,99.99 112.62,99.99 112.34,99.71 108.44,99.71 108.08,100.07 98.25,100.07 98.25,100.08 87.66,100.08 87.65,100.07 86.9,100.07 86.11,100.86 85.12,100.86 83.81,99.55 79.41,99.55 78.03,100.93 75.56,100.93 75.18,100.54 71.09,100.54 69.16,98.61 64.38,98.61 60.9,98.61 57.56,95.27 53.65,95.27 50.65,92.26 49.56,92.26 47.14,92.26 47.08,92.2 46.75,91.88 46.75,91.73 46.26,91.24 45.66,91.24 44.43,90.01 44.43,89.07 44.19,88.83 43.86,88.83 v3(43.68,88.65)
  BOTTOM w0.076: 42.89,88.02 42.74,87.86 42.74,86.96 43.09,86.61 U20.C33
  BOTTOM w0.127: C91.1 236.09,97.86 236.09,97.95 v2(235.86,98.18) 236.07,98.39 236.07,98.55 235.96,98.66 235.35,98.66 232.81,96.12 230.81,96.12 230.07,96.86 230.07,99.65 229.32,100.4 229.32,102.71 229.2,102.82 229.2,104.98 230.32,106.09 230.32,106.56 230.22,106.66 v2(229.99,106.66) ; 42.89,88.02 42.89,88.35 43.27,88.73 43.6,88.73 v3(43.68,88.65)
USB30_TX1-_C: length 6.1
  BOTTOM w0.127: U12.8 231.6,94.61 231.67,94.67 231.92,94.67 231.97,94.72 231.97,94.97 232.46,95.46 232.89,95.46 233.73,96.3 235.81,96.3 235.88,96.37 235.88,96.47 C91.2
USB30_TX1-_DC: length 25.9
  TOP w0.127: v3(237.36,88.22) 237.18,88.4 237,88.4 236.69,88.09 236.27,88.09 R9.2
  IN1 w0.114: v3(237.36,88.22) 237.57,88.44 243.95,88.44 244.23,88.71 255.76,88.71 256.06,89.02 256.06,89.38 v2(256.3,89.62)
  BOTTOM w0.127: v2(256.3,89.62) 256.25,89.56 CN6.32 ; C193.2 235.03,88.04 236.72,88.04 237.08,88.4 237.18,88.4 v3(237.36,88.22)
USB30_TX1-_DC_C: length 3.7
  BOTTOM w0.127: C193.1 233.66,87.91 233.21,87.91 231.77,89.36 231.77,89.59 231.6,89.76 U12.23
USB30_TX3+: length 97.5
  TOP w0.127: v3(16.63,16.01) 18.43,17.81 18.43,24.11 18.7,24.38 18.7,25.62 18.31,26.01 18.31,27.95 16.97,29.29 16.97,35.54 16.9,35.62 16.9,40.63 19.3,43.03 19.3,61.35 23.47,65.52 23.47,68.73 24.63,69.9 24.63,72.17 26.1,73.64 27.18,73.64 29.79,76.26 30.44,76.26 31.2,77.02 32.97,77.02 33.43,77.48 40.73,77.48 44.35,81.09 44.35,84.48 43.58,85.25 43.58,86 v2(43.48,86.1)
  BOTTOM w0.076: U20.C31 44.41,86.47 43.91,86.47 43.54,86.1 v2(43.48,86.1)
  BOTTOM w0.127: v3(16.63,16.01) 16.76,16.01 17.14,16.39 20.24,16.39 20.64,15.98 20.64,15.12 21.07,14.69 C348.2
USB30_TX3+_R: length 5.4
  TOP w0.127: CN14.38 22.2,9.19 21.91,9.48 21.91,9.91 21.34,10.48 21.34,12.01 v2(21.48,12.15)
  BOTTOM w0.127: C348.1 20.87,13.25 20.87,12.98 21.23,12.62 21.23,12.4 v2(21.48,12.15)
USB30_TX3-: length 97.5
  TOP w0.127: v3(44.08,86.07) 44.08,86.07 43.81,85.79 43.81,85.35 44.58,84.57 44.58,81 40.83,77.25 33.52,77.25 33.06,76.79 31.3,76.79 30.54,76.03 29.89,76.03 27.27,73.41 26.19,73.41 24.86,72.08 24.86,69.8 23.69,68.64 23.69,65.42 19.52,61.25 19.52,42.94 17.12,40.54 17.12,35.71 17.2,35.63 17.2,29.38 18.53,28.05 18.53,26.11 18.93,25.72 18.93,24.28 18.66,24.02 18.66,17.72 17.09,16.14 17.09,15.78 v2(17.24,15.63)
  BOTTOM w0.076: v3(44.08,86.07) 45.01,86.07 U20.C30
  BOTTOM w0.127: v2(17.24,15.63) 17.09,15.77 17.09,16.02 17.23,16.16 20.14,16.16 20.41,15.89 20.41,15.02 20.85,14.59 20.85,14.33 20.75,14.24 20.52,14.24 20.44,14.15 C349.2
USB30_TX3-_R: length 5.4
  TOP w0.127: v3(20.85,12.15) 21.11,11.88 21.11,10.39 21.68,9.82 21.68,9.5 21.4,9.22 CN14.36
  BOTTOM w0.127: v3(20.85,12.15) 21,12.3 21,12.53 20.64,12.88 20.64,13.25 C349.1
USB+_CAMERA: length 182.5
  IN1 w0.076: v3(57.57,68.64) 57.6,68.62 58.47,68.62 59.07,69.22 59.75,69.22 60.01,68.95 60.01,68.06 60.38,67.7 61.48,67.7 63.36,65.82 63.39,65.82
  IN1 w0.114: v2(199.15,92.46) 198.96,92.65 198.96,92.78 198.74,93.01 198.15,93.01 197.62,92.47 196.49,92.47 195.97,91.95 195.04,91.95 194.77,91.95 193.45,90.63 192.45,90.63 191.22,89.4 191.22,88.74 190.41,87.94 189.53,87.94 186.64,85.06 186.64,80.38 184.52,78.26 176.75,78.26 175.11,79.9 163.58,79.9 160.71,82.77 137.18,82.77 137.06,82.89 130.37,82.89 127.98,85.27 111.47,85.27 110.57,86.17 96.61,86.17 95.25,87.54 93.86,87.54 93.15,88.26 86.92,88.26 86.07,87.4 84.8,87.4 79.02,81.63 78.74,81.63 77.63,80.51 77.63,79.98 76.61,78.96 76.61,77.36 73.66,74.42 73.66,73.6 72.55,72.48 72.55,71.81 71.09,70.35 71.09,70.08 69.43,68.43 68.29,68.43 67.01,67.15 65.36,67.15 64.02,65.82 63.39,65.82
  BOTTOM w0.114: U20.AP8 58.41,68.66 58.34,68.59 57.63,68.59 v3(57.57,68.64)
  BOTTOM w0.127: R63.1 196.02,102.81 L2.3 196.02,101.9 195.83,101.71 195.83,101.39 195.36,100.92 195.36,100.57 195.67,100.26 196.03,100.26 197.73,98.56 197.73,98.14 198.95,96.92 198.95,92.66 v2(199.15,92.46)
USB+_COMBO: length 163.7
  TOP w0.076: v2(58.11,69.63) 58.34,69.4 58.59,69.4 58.84,69.14 58.84,67.95 59.05,67.75 59.05,67.52 60.52,66.05 60.62,66.05
  TOP w0.127: v2(191.38,83.8) 191.15,83.57 190.93,83.57 190.67,83.31 190.67,82.42 188.95,80.7 186.82,80.7 181.38,75.27 160.67,75.27 160.33,75.61 159.77,75.61 v1(159.25,76.13) 158.73,75.61 157.31,75.61 156.76,75.06 155.46,75.06 152.1,78.43 123.37,78.43 120.41,81.39 104.77,81.39 102.25,83.9 96.12,83.9 94.59,85.43 92.62,85.43 91.93,86.12 89.62,86.12 86.17,82.67 86.17,80.7 78.36,72.9 78.36,67.12 72.72,61.47 71.55,61.47 71.35,61.27 68.24,61.27 68.03,61.47 66.49,61.47 65.22,62.74 64.76,62.74 61.46,66.05 60.62,66.05
  BOTTOM w0.127: U20.AM8 58.18,69.63 v2(58.11,69.63) ; v2(191.38,83.8) 191.52,83.94 CN8.23
USB+_CR: length 179.9
  TOP w0.127: v2(188.71,84.05) 188.76,84 189.3,84 189.63,84.33 190.27,84.33 190.47,84.54 191.73,84.54 192.07,84.2 192.07,81.15 190.5,79.58 187.13,79.58 181.85,74.3 160.18,74.3 159.98,74.1 155.06,74.1 151.7,77.46 122.71,77.46 119.75,80.42 104.22,80.42 103.05,81.59 95.52,81.59 93.08,79.15 85.98,79.15 79.33,72.5 79.33,66.01 75.56,62.24 75.56,61.38 75.12,60.94 73.85,60.94 73.47,60.56 72.48,60.56 72.23,60.3 68.83,60.3 68.32,59.8 68.32,58.81 65.47,55.96 58.84,55.96 54.37,60.43 54.37,60.69 54.37,64.7 55.77,66.1 55.77,67.19 55.65,67.3 v3(55.65,68.01)
  BOTTOM w0.089: U20.AT10 56.99,67.69 56.64,67.34 56.36,67.34 56.31,67.29 56,67.29 55.65,67.64 v3(55.65,68.01)
  BOTTOM w0.127: CN8.20 189.72,84.6 189.17,84.05 v2(188.71,84.05)
USB+_LEFT: length 159.4
  TOP w0.076: v2(59.46,68.01) 59.57,68.13 59.76,68.13 60.24,67.65 60.81,67.65 62.1,66.36 62.1,66.3 62.11,66.29
  TOP w0.127: v2(190.21,83.01) 190.06,83.16 189.83,83.16 189.13,82.46 187.62,82.46 180.96,75.8 161.03,75.8 160.14,76.69 158.21,76.69 157.65,76.13 156.93,76.13 v1(156.41,75.61) 155.88,76.13 155.11,76.13 152.31,78.94 123.73,78.94 120.77,81.89 105.21,81.89 102.67,84.43 96.3,84.43 94.8,85.93 92.83,85.93 92.14,86.63 89.31,86.63 85.66,82.97 85.66,80.91 77.84,73.09 77.84,67.34 72.51,62.01 70.86,62.01 70.68,62.18 69.89,62.18 69.43,61.73 68.42,61.73 68.27,61.88 66.8,61.88 65.97,62.71 64.73,63.95 64.45,63.95 63.81,64.59 62.11,66.29
  BOTTOM w0.127: U20.AT7 59.08,67.85 59.24,68.01 v2(59.46,68.01) ; CN8.11 190.62,82.58 190.75,82.71 190.75,83.22 190.67,83.29 190.49,83.29 v2(190.21,83.01)
USB+_SENSOR: length 228.7
  IN1 w0.076: 63.39,71.17 63.37,71.17 63.36,71.18 62.53,71.18 62.48,71.22 62.16,71.54 60.13,71.54 59.91,71.76 58.35,71.76 57.87,72.24 57.55,72.24 57.32,72.01 57.32,71.73 56.61,71.02 55.45,71.02 55.3,70.87 54.07,70.87 53.94,70.74 53.94,70.49 53.99,70.44 v2(54.17,70.44)
  IN1 w0.114: v3(232.3,97.64) 232.08,97.43 232.08,97.07 231.14,96.13 230.81,95.8 230.64,95.8 230.64,95.8 228.34,95.8 227.98,95.8 227.46,96.32 223.68,96.32 223.26,95.9 221.57,95.9 221.57,95.9 220.4,95.9 220.39,95.9 220.25,95.9 219.93,95.59 218.79,94.44 215.36,94.44 212.83,91.92 208.44,91.92 208.18,92.17 203.97,92.17 201.97,94.16 197.5,94.16 197.1,93.76 193.96,93.76 193.44,93.23 193.44,93.08 192.2,91.84 191.93,91.84 190.11,90.02 189.93,90.02 189.1,90.02 188.03,88.96 188.03,88.17 184.99,85.13 184.99,80.46 184.15,79.62 177.68,79.62 176.19,81.11 164.66,81.11 163.96,81.81 163.38,81.81 160.98,84.21 133.09,84.21 132.43,84.87 130.12,84.87 127.99,86.99 112.11,86.99 110.48,88.63 97.63,88.63 95.88,90.38 86.96,90.38 86.14,89.56 85.81,89.56 84.86,88.61 84.3,88.61 78.55,82.86 78.22,82.86 76.01,80.65 76.01,80.45 74.96,79.39 74.96,77.44 73.96,76.43 73.37,76.43 72.32,75.38 72.32,74.62 71.77,74.07 71.11,74.07 70.48,73.43 70.48,72.8 69.68,72 67.42,72 67.14,71.72 66.58,71.72 66.03,71.17 63.39,71.17
  BOTTOM w0.127: v2(54.17,70.44) 54.3,70.31 54.53,70.31 54.67,70.46 U20.AL15 ; v3(232.3,97.64) 232.1,97.85 232.1,98.2 235.35,101.45 238.42,101.45 239.39,102.42 239.39,108.23 238.97,108.64 238.47,108.64 238.33,108.78 U5.45 236.93,108.78 235.87,109.84 R34.1
USB+_TP: length 179.6
  TOP w0.127: v2(192.52,83.24) 192.75,83.24 192.93,83.06 192.93,82.14 192.58,81.8 192.58,80.94 190.49,78.85 187.15,78.85 182.09,73.79 160.42,73.79 160.22,73.59 154.85,73.59 151.63,76.81 122.49,76.81 119.39,79.91 103.85,79.91 102.88,80.88 95.55,80.88 93.32,78.64 86.19,78.64 79.84,72.29 79.84,64.07 78.99,63.23 77.59,63.23 76.66,62.3 76.66,61.74 74.97,60.05 74.34,60.05 73.79,59.49 69.95,59.49 65.91,55.45 58.52,55.45 53.98,60 53.98,65.22 55.26,66.5 55.26,66.95 55.11,67.11 55.11,69.73 55.54,70.16 56.05,70.16 v3(56.15,70.26)
  BOTTOM w0.127: v2(192.52,83.24) 192.78,83.24 192.98,83.04 192.98,82.91 192.85,82.78 192.57,82.78 192.42,82.63 CN8.8 ; v3(56.15,70.26) 56.05,70.16 55.57,70.16 55.24,69.83 U20.AN13
USB+_TS: length 256
  IN1 w0.076: 63.37,63.45 63.36,63.45 63.34,63.48 63.21,63.48 61.38,65.31 59.29,65.31 58.49,66.11 58.49,66.52 57.9,67.1 55.76,67.1 54.98,67.88 54.98,68.94 55.14,69.09 55.41,69.09 v2(55.64,69.32)
  IN1 w0.114: 63.37,63.45 64.97,63.45 65.93,64.42 67.02,64.42 68.2,63.24 69.3,63.24 69.89,62.64 70.65,62.64 72,63.99 72,66.25 73.24,67.49 73.24,69.45 73.49,69.7 73.98,69.7 74.5,70.22 74.5,71.65 78.58,75.72 78.58,78.03 80.19,79.65 80.4,79.65 81.75,81.01 83.49,81.01 85.18,82.7 85.18,83.14 88.77,86.72 92.52,86.72 93.21,86.04 94.72,86.04 96.22,84.54 101.31,84.54 103.17,82.67 111,82.67 112.15,83.81 127.41,83.81 129.89,81.33 140.04,81.33 140.87,80.5 160.95,80.5 162.79,78.66 174.63,78.66 176.03,77.26 184.83,77.26 187.79,80.22 187.79,84.89 189.58,86.67 190.47,86.67 193.42,89.62 194.23,89.62 194.41,89.62 195.81,91.02 196.32,91.02 196.32,91.03 196.36,91.03 196.62,91.29 197.67,91.29 198.28,91.29 198.81,90.76 198.93,90.64 200.63,90.64 201.15,91.15 202.72,91.15 203.17,90.71 207.51,90.71 207.81,90.4 213.38,90.4 214.89,91.92 217.68,91.92 218.75,92.98 219.49,92.98 220.98,94.48 224.47,94.48 225.27,94.48 225.59,94.8 226.97,94.8 227.39,94.38 227.51,94.38 227.51,94.38 228.75,94.38 228.93,94.38 228.93,94.38 230.05,94.38 230.05,94.38 232.87,94.38 233.81,93.44 233.81,90.42 233.96,90.27 236.71,87.52 237.8,87.52 239.04,86.28 243.01,86.28 244.63,87.9 255.96,87.9 257.01,88.96 257.01,90.28 257.23,90.49 257.43,90.49 257.52,90.4 v3(257.52,90.1)
  BOTTOM w0.127: v3(257.52,90.1) 257.6,90.18 257.6,90.89 257.55,90.94 257.55,94.87 258.06,95.38 259.12,95.38 259.5,94.99 259.5,94.57 259.57,94.5 L12.2 259.55,94.03 R135.1 ; v2(55.64,69.32) 55.31,68.99 U20.AP13
USB+_WLAN: length 263.9
  IN1 w0.076: v2(56.2,69.64) 56.2,69.53 56.41,69.32 56.79,69.32 56.96,69.5 56.96,70.81 57.33,71.18 57.59,71.18 57.92,71.51 58.35,71.51 58.87,70.99 58.87,69.7 59.01,69.56 59.65,69.56 59.88,69.79 59.88,70.24 60.3,70.66 63.39,70.66
  IN1 w0.114: CN5.38 266.3,102.61 265.51,102.61 263.23,100.32 263.23,97.45 263,97.22 263,95.22 263.44,94.77 264.43,94.77 264.94,94.26 264.94,88.91 264.15,88.12 261.51,88.12 257.74,91.89 255.83,91.89 253.79,89.85 243.78,89.85 243.41,89.48 238.51,89.48 238.17,89.82 237.41,89.82 236.89,90.34 235.39,90.34 234.74,90.99 234.74,93.83 233.27,95.31 230.43,95.31 228.37,95.31 227.91,95.31 227.78,95.31 227.35,95.74 225.21,95.74 224.88,95.41 224.08,95.41 221.37,95.41 221.37,95.41 220.6,95.41 220.49,95.41 219.02,93.93 218.31,93.93 217.8,93.43 215.05,93.43 212.97,91.34 208.22,91.34 207.89,91.67 203.62,91.67 202.46,92.84 200.68,92.84 199.85,93.67 197.72,93.67 197.3,93.25 195.06,93.25 193.16,91.34 192.14,91.34 190.62,89.82 190.61,89.82 190.32,89.53 189.73,89.53 189.3,89.53 188.88,89.11 188.88,88.32 185.54,84.98 185.54,80.28 184.3,79.05 177.18,79.05 175.62,80.61 164.44,80.61 163.76,81.3 163.19,81.3 160.82,83.67 130.6,83.67 127.84,86.44 111.84,86.44 110.17,88.11 97.26,88.11 96.7,88.66 95.2,88.66 94.81,88.27 94.25,88.27 93.05,89.48 86.87,89.48 85.98,88.59 85.65,88.59 85.18,88.11 84.5,88.11 78.75,82.36 78.44,82.36 76.51,80.44 76.51,80.18 75.47,79.14 75.47,77.23 72.9,74.67 72.9,74.49 72.45,74.03 72.45,73.78 72.04,73.37 71.76,73.37 69.88,71.49 69.35,71.49 68.94,71.09 67.34,71.09 67,70.74 66.44,70.74 66.23,70.54 64.43,70.54 64.32,70.66 63.39,70.66
  BOTTOM w0.127: U20.AN11 56.52,69.31 v2(56.2,69.64)
USB-_CAMERA: length 182.5
  IN1 w0.076: v2(58.01,68.18) 58.01,68.36 58.11,68.46 58.53,68.46 59.14,69.07 59.68,69.07 59.86,68.89 59.86,68 60.32,67.54 61.42,67.54 63.36,65.6 63.39,65.6
  IN1 w0.114: v3(198.52,92.33) 198.75,92.56 198.75,92.69 198.65,92.79 198.24,92.79 197.71,92.26 196.58,92.26 196.06,91.74 194.86,91.74 193.54,90.42 192.54,90.42 191.43,89.31 191.43,88.65 190.5,87.72 189.61,87.72 186.86,84.97 186.86,80.29 184.61,78.05 176.66,78.05 175.02,79.69 163.49,79.69 160.62,82.56 137.09,82.56 136.97,82.67 130.28,82.67 127.89,85.06 111.38,85.06 110.48,85.96 96.53,85.96 95.16,87.32 93.78,87.32 93.06,88.04 87.01,88.04 86.16,87.18 84.89,87.18 79.11,81.41 78.83,81.41 77.84,80.42 77.84,79.89 76.83,78.87 76.83,77.27 73.88,74.33 73.88,73.51 72.76,72.4 72.76,71.72 71.3,70.26 71.3,70 69.52,68.22 68.38,68.22 67.1,66.93 65.45,66.93 64.11,65.6 63.39,65.6
  BOTTOM w0.127: R64.1 195.22,102.71 L2.2 195.22,101.95 195.6,101.58 195.6,101.48 195.13,101.01 195.13,100.47 195.57,100.03 195.93,100.03 197.5,98.46 197.5,98.05 198.72,96.83 198.72,92.57 198.7,92.54 198.7,92.39 198.65,92.33 v3(198.52,92.33) ; v2(58.01,68.18) 58.21,68.38 58.36,68.38 58.39,68.36 58.54,68.36 58.62,68.28 58.62,68.12 U20.AR8
USB-_COMBO: length 163.7
  TOP w0.076: 60.53,65.82 58.89,67.46 58.89,67.68 58.69,67.89 58.69,69.08 58.53,69.25 58.36,69.25 v2(58.12,69)
  TOP w0.127: 60.53,65.82 61.37,65.82 64.67,62.51 65.12,62.51 66.39,61.24 67.94,61.24 68.14,61.04 71.44,61.04 71.65,61.24 72.81,61.24 78.59,67.02 78.59,72.8 86.4,80.61 86.4,82.58 89.71,85.89 91.83,85.89 92.52,85.2 94.5,85.2 96.02,83.67 102.16,83.67 104.67,81.16 120.31,81.16 123.27,78.2 152,78.2 155.37,74.83 156.86,74.83 157.4,75.38 158.73,75.38 v1(159.25,74.86) 159.77,75.38 160.23,75.38 160.58,75.04 181.48,75.04 186.91,80.47 189.04,80.47 190.9,82.33 190.9,83.22 191.03,83.34 191.17,83.34 v2(191.35,83.16)
  BOTTOM w0.127: v2(58.12,69) 58.42,69.31 U20.AN8 ; CN8.9 191.82,83.01 191.66,83.16 v2(191.35,83.16)
USB-_CR: length 179.9
  TOP w0.127: v2(56.18,67.7) 55.95,67.7 55.88,67.63 55.88,67.4 56,67.28 56,66.05 54.57,64.62 54.57,60.6 54.57,60.52 58.12,56.97 58.12,56.97 58.16,56.97 58.93,56.19 65.37,56.19 68.09,58.91 68.09,59.89 68.73,60.53 72.13,60.53 72.39,60.79 73.37,60.79 73.75,61.17 75.02,61.17 75.33,61.47 75.33,62.33 79.1,66.1 79.1,72.59 85.89,79.38 92.99,79.38 95.43,81.82 103.14,81.82 104.31,80.65 119.85,80.65 122.81,77.69 151.79,77.69 155.16,74.33 159.89,74.33 160.09,74.53 181.75,74.53 187.04,79.81 190.41,79.81 191.84,81.24 191.84,84.1 191.64,84.31 190.57,84.31 190.37,84.1 189.72,84.1 189.39,83.77 189.07,83.77 188.74,83.44 v3(188.74,83.29)
  BOTTOM w0.089: v2(56.18,67.7) 56.18,67.56 56.2,67.53 56.57,67.53 57.03,67.99 57.32,67.99 57.37,68.04 57.37,68.12 U20.AR10
  BOTTOM w0.127: CN8.12 190.02,82.57 189.69,82.9 189.69,83.63 189.6,83.72 189.02,83.72 188.74,83.44 v3(188.74,83.29)
USB-_LEFT: length 159.4
  TOP w0.076: v2(59.46,68.67) 59.46,68.64 60.3,67.8 60.87,67.8 62.21,66.46 62.26,66.46 62.27,66.45
  TOP w0.127: v2(190.21,83.65) 189.95,83.39 189.74,83.39 189.03,82.69 187.53,82.69 180.87,76.03 161.12,76.03 160.23,76.92 158.11,76.92 157.56,76.36 156.93,76.36 v1(156.41,76.88) 155.88,76.36 155.21,76.36 152.4,79.16 123.82,79.16 120.86,82.12 105.3,82.12 102.76,84.66 96.4,84.66 94.9,86.16 92.92,86.16 92.23,86.86 89.22,86.86 85.43,83.07 85.43,81.01 77.61,73.19 77.61,67.44 72.41,62.24 70.95,62.24 70.78,62.41 69.79,62.41 69.33,61.96 68.51,61.96 68.36,62.11 66.9,62.11 64.83,64.18 64.55,64.18 64.04,64.69 62.27,66.45
  BOTTOM w0.127: U20.AR7 59.41,68.67 v2(59.46,68.67) ; v2(190.21,83.65) 190.21,84.03 190.92,84.73 CN8.22
USB-_SENSOR: length 226
  IN1 w0.076: v3(54.12,69.8) 54.12,69.93 53.79,70.26 53.79,70.81 54.01,71.02 55.24,71.02 55.39,71.18 56.55,71.18 57.17,71.8 57.17,72.08 57.49,72.4 57.93,72.4 58.41,71.91 59.97,71.91 60.19,71.69 62.23,71.69 62.59,71.33 63.31,71.33 63.39,71.4
  IN1 w0.114: 63.39,71.4 63.4,71.41 65.96,71.41 66.49,71.94 67.05,71.94 67.33,72.22 69.59,72.22 70.26,72.89 70.26,73.52 71.02,74.29 71.68,74.29 72.1,74.71 72.1,75.47 73.28,76.65 73.87,76.65 74.74,77.53 74.74,79.48 75.8,80.54 75.8,80.74 78.13,83.08 78.46,83.08 84.21,88.82 84.77,88.82 85.72,89.78 86.05,89.78 86.87,90.59 95.97,90.59 97.72,88.84 110.57,88.84 112.2,87.21 128.08,87.21 130.21,85.08 132.52,85.08 133.18,84.42 161.07,84.42 163.47,82.02 164.05,82.02 164.75,81.32 176.28,81.32 177.77,79.84 184.07,79.84 184.78,80.55 184.78,85.22 187.81,88.26 187.81,89.05 189.01,90.24 190.02,90.24 191.84,92.05 192.11,92.05 193.22,93.17 193.22,93.32 193.87,93.97 197.01,93.97 197.41,94.38 202.06,94.38 204.06,92.39 208.27,92.39 208.53,92.13 212.74,92.13 215.27,94.66 218.7,94.66 220.16,96.12 220.31,96.12 220.31,96.12 221.66,96.12 221.66,96.12 223.16,96.12 223.56,96.53 223.58,96.53 223.59,96.54 227.55,96.54 228.07,96.02 230.72,96.02 231.87,97.16 231.87,97.41 v2(231.64,97.64)
  BOTTOM w0.127: U5.44 238.28,108.28 238.41,108.41 238.88,108.41 239.16,108.13 239.16,102.52 238.32,101.68 235.25,101.68 231.87,98.3 231.87,97.87 v2(231.64,97.64) ; U20.AM15 54.28,69.96 v3(54.12,69.8)
USB-_TP: length 179.6
  TOP w0.127: v2(55.64,70.59) 54.88,69.83 54.88,67.01 55.03,66.86 55.03,66.6 53.75,65.31 53.75,59.9 58.43,55.22 66.01,55.22 70.05,59.26 73.88,59.26 74.44,59.82 75.07,59.82 76.89,61.64 76.89,62.2 77.68,63 79.09,63 80.07,63.98 80.07,72.19 86.29,78.42 93.41,78.42 95.65,80.65 102.79,80.65 103.75,79.69 119.3,79.69 122.39,76.59 151.53,76.59 154.76,73.36 160.31,73.36 160.51,73.56 182.19,73.56 187.24,78.62 190.58,78.62 192.81,80.85 192.81,81.7 193.16,82.05 193.16,83.16 192.96,83.36 192.96,83.44 v3(192.52,83.88)
  BOTTOM w0.127: v2(55.64,70.59) 55.34,70.29 U20.AM13 ; v3(192.52,83.88) 192.52,84.5 192.72,84.69 CN8.25
USB-_TS: length 256
  IN1 w0.076: v2(55.63,68.66) 55.63,68.82 55.52,68.94 55.2,68.94 55.14,68.88 55.14,67.95 55.83,67.26 57.96,67.26 58.64,66.58 58.64,66.17 59.35,65.46 61.45,65.46 63.24,63.67 63.37,63.67
  IN1 w0.114: v2(258.16,90.1) 258.13,90.1 257.52,90.71 257.14,90.71 256.8,90.37 256.8,89.05 255.87,88.12 244.54,88.12 242.92,86.49 239.13,86.49 237.89,87.74 236.8,87.74 234.11,90.42 234.03,90.51 234.03,93.53 232.96,94.59 230.14,94.59 230.13,94.59 228.84,94.59 228.84,94.59 228.66,94.59 227.6,94.59 227.6,94.59 227.48,94.59 227.06,95.02 226.91,95.02 225.5,95.02 225.18,94.7 225.09,94.7 225.09,94.7 224.38,94.7 220.9,94.7 219.4,93.2 218.66,93.2 217.59,92.13 214.8,92.13 213.29,90.62 207.9,90.62 207.6,90.92 203.26,90.92 202.81,91.37 201.06,91.37 200.54,90.85 199.02,90.85 198.9,90.98 198.37,91.5 198.35,91.5 197.58,91.5 197.58,91.5 196.53,91.5 196.27,91.24 196.23,91.24 196.23,91.24 195.72,91.24 194.32,89.84 193.33,89.84 190.38,86.89 189.49,86.89 187.58,84.98 187.58,80.31 184.74,77.48 176.12,77.48 174.72,78.87 162.88,78.87 161.04,80.71 140.96,80.71 140.13,81.55 129.98,81.55 127.5,84.03 112.06,84.03 110.91,82.89 103.26,82.89 101.4,84.75 96.31,84.75 94.81,86.25 93.3,86.25 92.61,86.94 88.68,86.94 84.97,83.23 84.97,82.79 83.4,81.22 81.67,81.22 80.31,79.86 80.1,79.86 78.36,78.12 78.36,75.81 74.29,71.73 74.29,70.31 73.89,69.92 73.4,69.92 73.02,69.54 73.02,67.58 71.79,66.34 71.79,64.08 70.57,62.86 69.98,62.86 69.38,63.45 68.29,63.45 67.11,64.64 65.84,64.64 64.88,63.67 63.37,63.67
  BOTTOM w0.127: v2(258.16,90.1) 258.16,90.11 257.83,90.44 257.83,90.99 257.78,91.04 257.78,94.77 258.16,95.15 259.02,95.15 259.28,94.9 259.28,94.72 259.2,94.65 258.85,94.65 258.77,94.57 L12.3 258.79,94.03 R136.1 ; U20.AR13 55.24,68.56 55.37,68.69 55.61,68.69 v2(55.63,68.66)
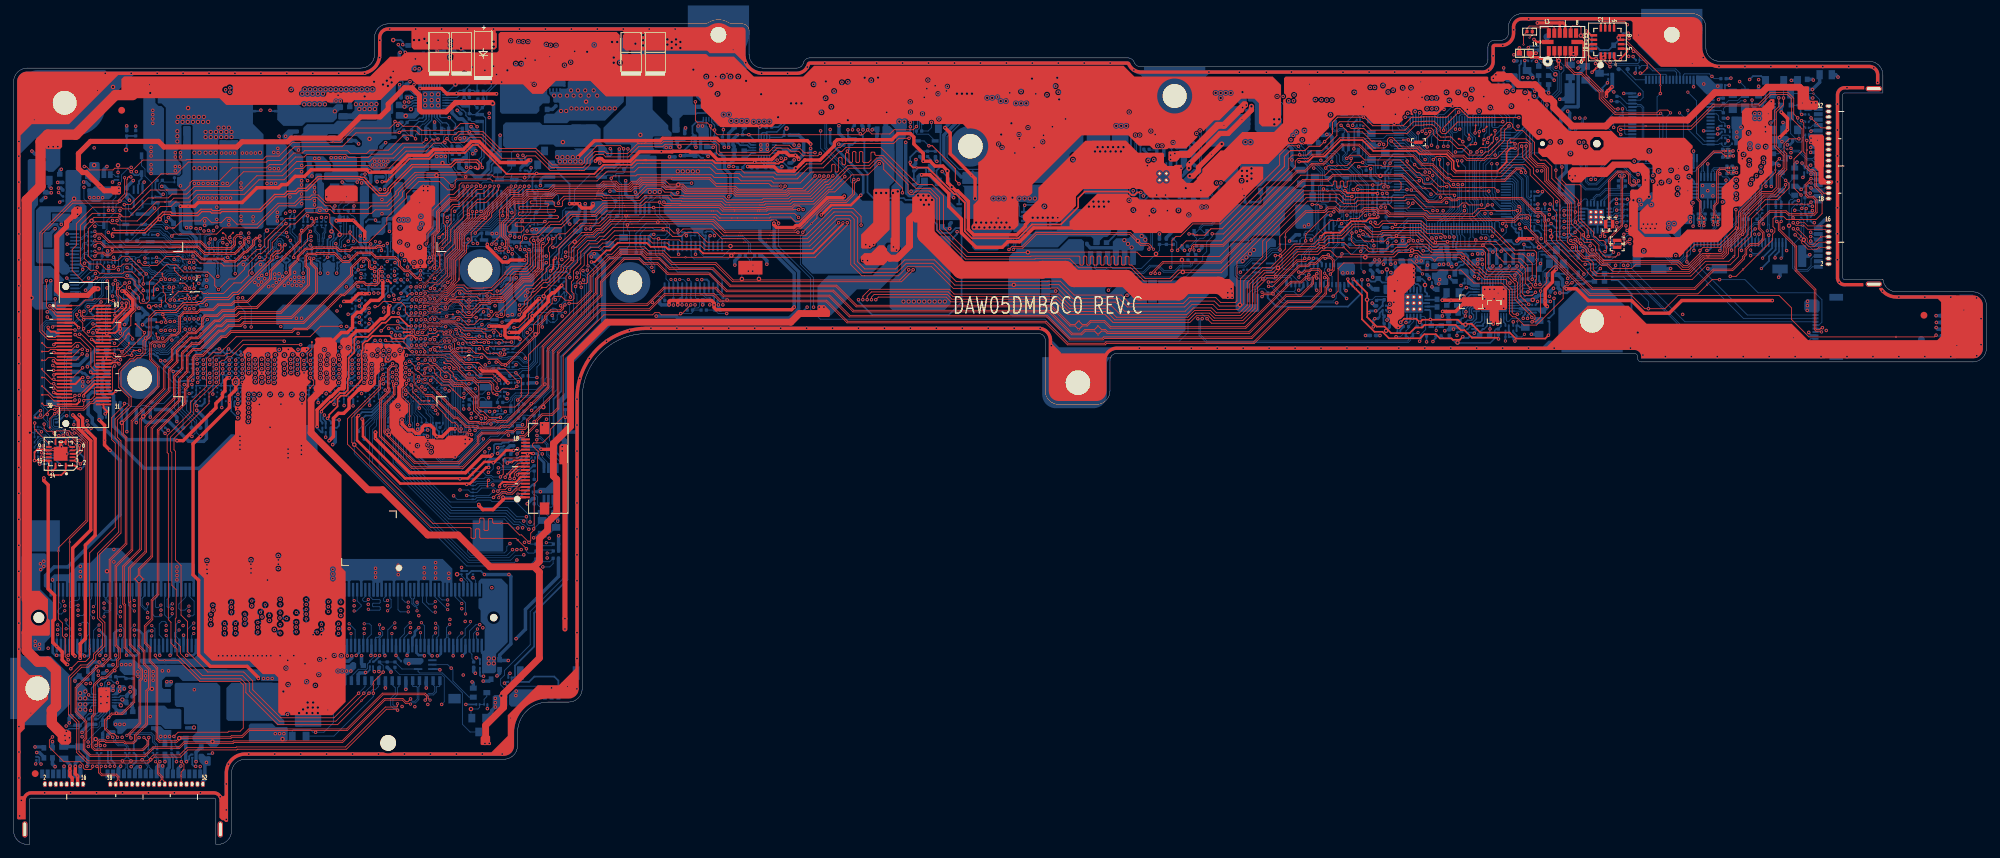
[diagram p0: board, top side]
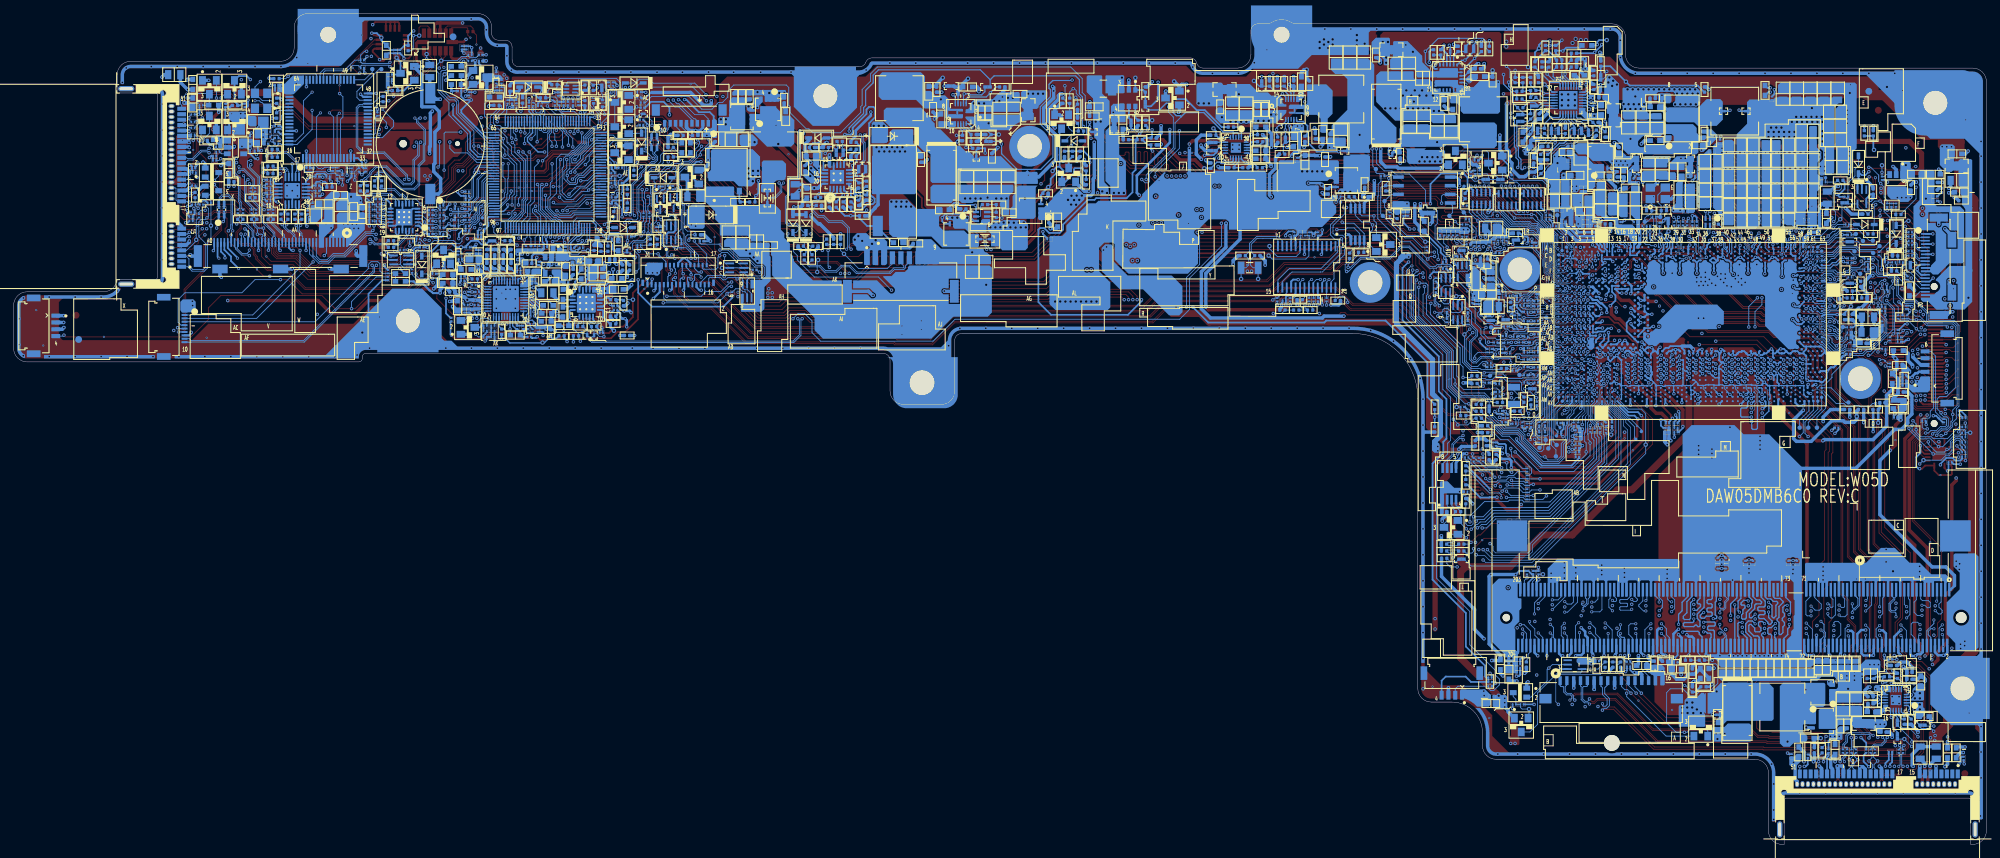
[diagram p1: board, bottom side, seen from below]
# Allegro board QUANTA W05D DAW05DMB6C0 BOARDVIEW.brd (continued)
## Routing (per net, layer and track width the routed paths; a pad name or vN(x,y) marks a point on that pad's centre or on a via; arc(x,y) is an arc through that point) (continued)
USB-_WLAN: length 263.9
  IN1 w0.076: v2(56.19,68.99) 56.37,69.17 56.85,69.17 57.12,69.44 57.12,70.74 57.4,71.02 57.65,71.02 57.98,71.35 58.29,71.35 58.72,70.92 58.72,69.64 58.95,69.41 59.59,69.41 59.72,69.41 60.03,69.72 60.03,70.17 60.37,70.5 63.25,70.5 63.31,70.44 63.39,70.44
  IN1 w0.114: CN5.36 266.15,102.39 265.6,102.39 263.44,100.23 263.44,97.36 263.21,97.13 263.21,95.31 263.53,94.99 264.52,94.99 265.16,94.35 265.16,88.82 264.24,87.9 261.42,87.9 257.65,91.67 255.92,91.67 253.88,89.63 243.87,89.63 243.5,89.26 238.42,89.26 238.08,89.6 237.32,89.6 236.8,90.12 235.3,90.12 234.52,90.9 234.52,93.74 233.18,95.09 230.34,95.09 228.46,95.09 227.82,95.09 227.69,95.09 227.26,95.52 225.89,95.52 225.3,95.52 224.97,95.19 224.17,95.19 220.69,95.19 220.58,95.19 219.11,93.72 218.39,93.72 217.89,93.21 215.14,93.21 213.06,91.13 208.13,91.13 207.8,91.46 203.53,91.46 202.37,92.63 200.59,92.63 199.76,93.45 197.81,93.45 197.39,93.03 195.15,93.03 193.25,91.13 192.23,91.13 190.71,89.6 190.7,89.6 190.41,89.31 189.64,89.31 189.39,89.31 189.1,89.02 189.1,88.23 185.76,84.89 185.76,80.2 184.39,78.83 177.09,78.83 175.53,80.4 164.35,80.4 163.67,81.08 163.1,81.08 160.73,83.46 130.51,83.46 127.75,86.22 111.75,86.22 110.08,87.89 97.17,87.89 96.61,88.45 95.29,88.45 94.9,88.05 94.16,88.05 92.96,89.26 86.96,89.26 86.07,88.37 85.74,88.37 85.27,87.9 84.59,87.9 78.84,82.15 78.53,82.15 76.73,80.35 76.73,80.09 75.68,79.05 75.68,77.15 73.12,74.58 73.12,74.4 72.66,73.94 72.66,73.69 72.13,73.16 71.85,73.16 69.97,71.28 69.44,71.28 69.03,70.87 67.43,70.87 67.09,70.53 66.53,70.53 66.32,70.33 64.34,70.33 64.23,70.44 63.39,70.44
  BOTTOM w0.127: U20.AP11 56.27,68.99 v2(56.19,68.99)
USB_BIAS: length 22.1
  TOP w0.076: v2(57.7,71.84) 57.75,71.89 59.13,71.89 59.24,71.78 60.6,71.78 60.6,71.79 63.39,71.79 63.72,71.46 64.15,71.46
  TOP w0.127: 64.15,71.46 65.52,70.08 65.52,69.7 66.62,68.61 67.64,68.61 68.18,68.06 69.98,68.06 70.51,67.54 70.51,66.83 70.81,66.53 71.37,66.53 71.75,66.91 v1(73.09,66.91) 73.53,66.91 v2(73.91,67.29)
  BOTTOM w0.127: v2(73.91,67.29) 74.41,67.29 R380.1 ; v2(57.7,71.84) 57.45,71.58 57.17,71.58 U20.AJ10 56.98,71.4 56.53,71.4 U20.AJ11
USB_OC1#: length 8.6
  BOTTOM w0.076: 63.39,70.87 63.21,70.87 63.04,71.04 62.69,71.04 62.5,70.85 62.5,70.67 62.29,70.46 62.01,70.46 61.84,70.63 61.6,70.63 U20.AL3
  BOTTOM w0.127: TP92.1 68.5,68.89 R373.1 67.9,69.26 67.61,69.55 65.65,69.55 64.33,70.87 63.39,70.87
USB_OC2#: length 11.4
  BOTTOM w0.127: TP104.1 65.27,58.6 65.27,61.75 65,62.02 R407.1 64.64,62.2 64.64,67.02 64.11,67.54 63.11,67.54 62.94,67.72 U20.AT1
USB_OC3#: length 15.2
  TOP w0.127: v2(64.05,73.06) 64.05,72.79 65.56,71.28 65.8,71.28 66.31,70.77 68.01,70.77 TP52.1 68.32,70.72 69.08,69.96 71.31,69.96 71.42,69.86 72.18,69.86 v2(74.11,67.92)
  BOTTOM w0.076: 62.16,72.28 62.6,72.71 63.03,72.71 63.11,72.62 63.62,72.62 v2(64.05,73.06)
  BOTTOM w0.089: U20.AH2 62.16,72.28
  BOTTOM w0.127: v2(74.11,67.92) 73.98,67.8 R379.1
USB_OC4#: length 7.8
  BOTTOM w0.076: 62.6,64.62 62.1,64.62 61.88,64.84 61.88,65.39 61.82,65.44 61.82,66.08 U20.AV3
  BOTTOM w0.127: 62.6,64.62 62.65,64.62 63.37,63.91 63.37,61.03 R422.1 62.94,60.17 TP101.1
USBP2+_C: length 4.8
  BOTTOM w0.127: R63.2 196.02,103.4 L2.4 196.02,104.35 195.69,104.69 195.69,104.92 195.47,105.14 194.66,105.14 194.41,104.88 193.99,104.88 193.81,105.07 193.81,105.17 194.09,105.46 CN3.10
USBP2-_C: length 4.8
  BOTTOM w0.127: R64.2 195.22,103.5 L2.1 195.22,104.35 195.46,104.59 195.46,104.82 195.38,104.91 194.76,104.91 194.51,104.65 193.9,104.65 193.58,104.97 193.58,105.17 193.29,105.46 CN3.9
USBP7+_C: length 21.7
  TOP w0.127: v2(265.63,75.88) 265.5,75.88 265.22,75.6 264.76,75.6 264.66,75.7 264.66,81.51 261.84,84.33 261.84,87.84 259.38,90.3 259.38,91.29 v3(259.57,91.49)
  BOTTOM w0.127: v2(265.63,75.88) 265.5,75.75 CN11.6 ; R135.2 259.55,92.37 L12.1 v3(259.57,91.49)
USBP7-_C: length 21.8
  TOP w0.127: v2(258.92,91.47) 259.15,91.24 259.15,90.21 261.61,87.74 261.61,84.24 264.43,81.42 264.43,75.6 264.67,75.37 265.39,75.37 v3(265.51,75.25)
  BOTTOM w0.127: v2(258.92,91.47) 258.77,91.62 L12.4 258.77,92.94 R136.2 ; CN11.7 v3(265.51,75.25)
VBOOT: length 3.6
  BOTTOM w0.178: PU3.14 58.96,110.48 58.79,110.65 v2(58.79,111.56) 58.79,112.12 58.04,112.87 PR15.1
VIBRATOR _OUT#: length 367.3
  TOP w0.381: v2(118.61,92.44) 119.37,93.2 120.06,93.88 122.95,93.88 v2(124.4,95.33)
  IN1 w0.381: v2(73.86,87.76) 73.8,87.71 73.8,86.5 71.98,84.67 71.98,84.66 71.92,84.61 71.92,83.39 69.9,81.36 69.18,81.36 69.03,81.21 65.75,81.21 v2(65.5,80.96) ; v2(119.91,104.98) 119.45,105.44 103.45,105.44 102.86,104.86 100.02,104.86 99.03,105.85 98.29,105.85 97.32,104.88 78.1,104.88 77.72,104.5 72.38,104.5 72.15,104.73 69.66,104.73 68.86,103.93 67.31,103.93 66.08,102.7 61.41,102.7 60.77,102.06 58.97,102.06 58.01,101.1 52.47,101.1 51.48,100.11 46.5,100.11 45.89,100.72 45.89,101.15 41.72,105.31 35.43,105.31 32.63,108.11 30.45,108.11 28.55,110 20.03,110 15.07,105.03 15.07,99.56 13.84,98.33 13.84,94.82 10.94,91.93 10.94,91.09 10.51,90.66 10.51,87.25 9.69,86.44 9.69,84.87 9.49,84.66 9.49,83.65 9.97,83.16 v2(11.02,83.16)
  IN2 w0.381: v2(11.02,83.16) 11.02,82.94 11.68,82.28 11.68,81.39 12.34,80.72 12.83,80.72 13.43,80.13 13.43,79.33 11.93,77.83 11.04,77.83 10.13,76.92 9.11,76.92 8.37,76.18 8.37,72.94 9.54,71.77 9.54,69.75 10.08,69.22 10.48,69.22 10.91,68.79 v2(10.91,68.56) ; v2(211.73,101.68) 211.42,101.99 211.42,102.85 210.51,103.77 206.7,103.77 206.59,103.66 205.83,103.66 205,102.82 202.7,102.82 202.09,102.21 198.08,102.21 197.18,101.31 194.52,101.31 194.14,100.93 194.14,100 194.13,99.99 194.13,99.97 192.41,98.24 190.08,98.24 189.81,97.97 186.25,97.97 182.39,94.12 181.8,94.12 174.08,86.39 158.92,86.39 154.96,90.35 148.28,90.35 146.63,92 140.05,92 139.22,91.18 137.56,91.18 137.47,91.09 132.43,91.09 131.08,92.44 v2(118.61,92.44) 118.4,92.65 114.87,92.65 114.69,92.82 114.69,97.02 113.71,98 103.47,98 101.85,96.37 98.76,96.37 97.59,97.54 97.56,97.54 96.96,97.54 96.79,97.72 95.23,97.72 92.32,97.72 90.73,96.14 90.73,95.14 88.87,93.27 85.13,93.27 84.82,92.97 79.44,92.97 78.86,92.39 78.86,89.95 78.45,89.54 76.34,89.54 75.79,88.98 75.79,88.75 75.15,88.12 74.18,88.12 73.92,87.86 73.92,87.83 v2(73.86,87.76)
  BOTTOM w0.203: R38.2 214.01,107.63 213.5,107.11 U7.54 213.5,104.51 214.24,103.76 214.24,103.23 212.69,101.68 v2(211.73,101.68)
  BOTTOM w0.381: CN12.3 9.9,69.4 10.1,69.19 10.41,69.19 10.81,68.79 10.81,68.66 v2(10.91,68.56) 11.44,68.56 C276.1 ; v2(65.5,80.96) 65.65,80.81 R274.1 ; v2(124.4,95.33) 124.76,95.69 124.76,98.2 119.91,103.05 v2(119.91,104.98)
VOL_DOWN#: length 323.2
  TOP w0.127: v2(8.02,27.77) 8.23,27.98 8.23,33.22 8.23,33.22 v1(8.23,44.38) 8.23,44.85 10.89,47.5 10.89,59.09 8.96,61.02 v2(8.68,61.02)
  IN2 w0.127: v2(8.02,27.77) 7.89,27.89 7.89,29.16 8.9,30.17 27.71,30.17 28.65,29.23 50.69,29.23 50.79,29.33 67.19,29.33 69.46,31.6 69.46,32.62 69.26,32.82 69.26,38.63 69.59,38.95 69.59,45.42 76.07,51.9 76.07,55.78 75.2,56.65 75.2,61.85 76.51,63.16 76.51,66.03 76.12,66.43 76.12,69.3 76.75,69.94 76.75,71.61 86.96,81.83 86.96,83.78 89.08,85.9 91.86,85.9 92.3,85.45 94.96,85.45 96.92,83.5 101.97,83.5 102.71,82.76 103.35,82.76 105.87,80.24 112.14,80.24 112.62,80.72 137.92,80.72 138.46,80.18 153.62,80.18 156.7,77.09 172.31,77.09 172.85,77.64 183.09,77.64 186.72,81.27 186.72,86.01 188.75,88.04 191.43,88.04 192.17,88.78 194.56,88.78 196.26,90.48 196.47,90.48 196.68,90.48 197.07,90.86 198.11,90.86 198.86,90.11 200.33,90.11 202.86,92.64 203.05,92.64 203.46,93.05 205.99,93.05 207.23,94.29 208.6,94.29 208.78,94.47 209.62,94.47 210.13,94.98 210.74,94.98 211.98,93.73 v2(213.05,93.73)
  BOTTOM w0.127: R224.2 213.12,89.13 212.7,89.56 U7.109 212.7,92.03 213.5,92.84 213.5,93.27 v2(213.05,93.73) ; CN12.5 7.91,71.4 7.76,71.25 7.76,64.09 8.25,63.61 8.25,62.78 8.42,62.6 9.25,62.6 9.43,62.43 C283.1 9.43,61.26 9.19,61.02 v2(8.68,61.02)
VOL_UP#: length 330.1
  TOP w0.127: v2(8.91,60.41) 9.21,60.41 10.63,58.98 10.63,47.61 6.57,43.54 v1(6.57,43.06) 6.57,33.1 7.19,32.48 7.19,30.61 7.57,30.23 7.57,27.58 7.92,27.24 7.92,27.21 v2(8.02,27.11)
  IN2 w0.127: v2(213.05,93.07) 212.26,93.07 210.61,94.72 210.25,94.72 209.75,94.21 208.91,94.21 208.73,94.04 207.34,94.04 206.09,92.79 203.56,92.79 203.16,92.39 202.96,92.39 200.43,89.86 198.75,89.86 198,90.61 197.17,90.61 196.79,90.23 196.58,90.23 196.58,90.23 196.36,90.23 194.66,88.52 194.45,88.52 192.27,88.52 191.54,87.79 191.33,87.79 188.86,87.79 186.97,85.9 186.97,81.15 182.58,76.75 156.69,76.75 153.51,79.93 138.36,79.93 137.82,80.47 112.72,80.47 112.24,79.99 105.76,79.99 103.35,82.4 96.26,82.4 95.75,82.91 95.75,84.18 94.73,85.2 92.4,85.2 92.19,85.2 91.75,85.64 89.18,85.64 87.22,83.68 87.22,81.72 77,71.51 77,69.83 76.37,69.2 76.37,66.53 76.76,66.14 76.76,62.65 75.46,61.35 75.46,57.36 75.94,56.88 76.57,56.88 76.95,56.49 76.95,53.3 76.4,52.74 76.4,51.87 70.35,45.82 70.35,39.36 69.52,38.52 69.52,35.68 71.48,33.71 71.48,32.89 67.67,29.08 51.1,29.08 51,28.98 28.55,28.98 27.6,29.92 9.08,29.92 8.5,29.34 8.5,27.59 v2(8.02,27.11)
  BOTTOM w0.127: v2(8.91,60.41) 8.53,60.41 8.15,60.79 7.33,60.79 6.75,61.37 6.02,61.37 5.85,61.54 5.85,62.34 5.96,62.45 C284.1 6.43,62.45 7.49,63.51 7.49,71.73 8.15,72.4 CN12.6 ; R225.2 212.49,89.41 212.3,89.61 U7.110 212.3,92.32 v2(213.05,93.07)
VOLMUTE#: length 30.8
  TOP w0.127: v2(208.27,89.06) 208.78,88.55 217.64,88.55 220.2,86 221.34,86 222.37,84.97 222.37,82.89 223,82.25 223,82.05 223.33,81.72 224.35,81.72 225.14,82.5 v1(225.14,83.19) 225.14,83.85 226.23,84.94 226.66,84.94 228.21,83.39 v2(228.21,83.11)
  BOTTOM w0.127: v2(208.27,89.06) 207.9,89.43 U7.121 ; v2(228.21,83.11) 228.31,83.11 228.97,83.77 D10.1
VR_HOT#: length 3.1
  BOTTOM w0.178: PU3.2 62.19,106.74 62.97,105.96 63.56,105.96 63.87,105.64 PR54.1
VR_RDY: length 3.7
  BOTTOM w0.178: PR60.1 58.41,104.92 58.41,105.06 59.5,106.15 60.19,106.15 60.59,106.55 PU3.6
VR_SVID_ALERT#: length 78.1
  TOP w0.127: v2(19.04,81.34) 19.04,81.64 18.41,82.28 18.41,83.06 17.39,84.08 16.27,84.08 16.06,83.86 12.63,83.86 12.18,84.31 11.27,84.31 10.69,84.89 10.23,84.89 9.8,85.33 9.8,90.91 11.55,92.66 15.57,92.66 16.08,92.16 16.99,92.16 19.77,94.94 v1(20.49,94.94) 22.73,94.94 23.28,95.5 25.4,95.5 26.53,96.63 31.62,96.63 33.76,98.77 39.23,98.77 41.4,100.94 42.66,100.94 43.01,101.29 48.79,101.29 49.22,100.86 52.05,100.86 52.56,101.36 55.55,101.36 57.17,102.98 60.04,102.98 v2(60.6,103.54)
  BOTTOM w0.127: R276.2 C235.2 19.12,81.26 v2(19.04,81.34) 18.29,80.58 R277.2 ; PR56.2 60.52,103.61 v2(60.6,103.54)
VR_SVID_CLK: length 83.8
  TOP w0.127: v2(59.02,103.61) 58.49,104.15 57.24,104.15 55.05,101.95 52.31,101.95 51.81,101.44 49.47,101.44 49.03,101.87 42.75,101.87 42.41,101.53 41.13,101.53 39.46,99.85 37.61,99.85 37.12,99.36 32.12,99.36 30.28,97.52 26.28,97.52 25.9,97.13 25.9,96.82 25.17,96.09 v1(22.55,96.09) 20.1,96.09 17.68,93.67 17.68,93.67 17.33,93.32 16.04,93.32 15.79,93.58 11.64,93.58 9.21,91.15 9.21,87.98 8.6,87.37 8.6,84.27 10.21,82.66 11.55,82.66 12.17,83.28 16.22,83.28 16.43,83.08 17.4,83.08 17.82,82.66 17.82,82.03 18.38,81.48 18.38,81.34 19.04,80.68 v2(19.04,79.91)
  BOTTOM w0.076: 23.26,80.48 23.32,80.53 U20.N63
  BOTTOM w0.127: 23.26,80.48 23.21,80.48 23.11,80.37 22.73,80.37 21.9,79.55 19.41,79.55 v2(19.04,79.91) ; PR57.2 59.19,104.39 59.02,104.22 v2(59.02,103.61)
VR_SVID_DATA: length 76.5
  TOP w0.127: v2(19.04,82.3) 19.04,83.38 17.2,85.22 16.07,85.22 15.74,84.89 15.28,84.89 14.84,84.45 13.57,84.45 12.79,85.22 11.19,85.22 10.38,86.04 10.38,90.67 11.8,92.08 15.33,92.08 15.86,91.55 18.16,91.55 20.97,94.35 v1(22.24,94.35) 22.97,94.35 23.53,94.91 25.65,94.91 26.78,96.04 33.56,96.04 35.71,98.19 39.48,98.19 41.56,100.27 52.29,100.27 52.8,100.78 55.8,100.78 57.41,102.39 60.29,102.39 61.49,103.59 v2(62.32,103.59)
  BOTTOM w0.127: PR55.2 R55.2 61.84,104.11 62.32,103.63 v2(62.32,103.59) ; R265.2 19.14,82.4 v2(19.04,82.3)
VREFOUT_C: length 2.3
  BOTTOM w0.203: U18.19 216.02,76.63 215.77,76.38 R322.1
  BOTTOM w0.254: C265.1 R322.1
VRON: length 162.7
  TOP w0.127: v2(64.9,103.62) 65.56,104.29 68.78,104.29 71.36,101.71 76.65,101.71 78.95,99.41 83.3,99.41 83.62,99.41 84.22,100.01 84.22,100.63 85.34,101.75 86.77,101.75 87.06,101.45 90.17,101.45 91.62,102.9 91.82,102.9 91.82,102.9 92.18,102.9 92.18,102.9 92.27,102.9 92.27,102.9 92.63,102.9 92.63,102.9 95.15,102.9 95.49,103.24 103.09,103.24 103.6,102.73 103.6,101.8 103.78,101.63 110.89,101.63 111.93,102.67 113.89,102.67 114.34,102.21 115.47,102.21 116.12,101.57 v1(116.65,101.57) 117.66,101.57 v2(117.68,101.59)
  IN2 w0.127: v2(117.68,101.59) 117.68,101.01 118.57,100.12 124.03,100.12 125.11,99.04 129.84,99.04 131.97,101.17 136.03,101.17 137.88,99.33 144.15,99.33 144.62,98.86 153.63,98.86 156.25,96.25 161.5,96.25 163.61,94.14 164.15,94.14 164.22,94.21 166.34,94.21 166.62,94.49 176.39,94.49 178.26,96.36 178.26,99.69 179.93,101.35 182.49,101.35 183.44,102.3 187.81,102.3 188.52,103.02 189.56,103.02 189.92,103.38 190.14,103.38 192.19,105.44 194.33,105.44 194.63,105.14 195.19,105.14 195.45,105.39 195.45,105.92 195.56,106.04 196.45,106.04 197.57,106.04 197.57,106.04 197.97,106.04 200.03,106.04 202.57,106.04 203.88,107.35 v2(204.72,107.35)
  BOTTOM w0.127: U7.34 205.5,107.12 205.27,107.35 v2(204.72,107.35) ; PR52.2 65.59,104.39 64.9,103.7 v2(64.9,103.62)
WLAN_LED#: length 4.6
  TOP w0.127: v2(263.95,106.69) v1(264.75,105.89) 265.41,105.23 CN5.44
  BOTTOM w0.127: R48.2 263.95,106.85 v2(263.95,106.69) 263.95,106.45 R52.2
XCLK_BIASREF: length 7.2
  IN1 w0.127: v3(48.61,87.91) 48.61,86.25 v3(48.63,86.22)
  BOTTOM w0.127: v3(48.61,87.91) 49.24,87.91 49.45,88.12 50.03,88.12 50.33,88.42 50.33,90.59 R180.2 ; U20.C26 48.5,86.09 v3(48.63,86.22)
XDP_BPM0: length 28.9
  TOP w0.127: v2(9.03,74.86) 9.49,74.4 9.74,74.4 11.35,72.79 11.35,70.16 11.89,69.61 CN1.41
  IN1 w0.127: v2(25.84,83.16) 25.34,82.66 24.84,82.66 24,81.81 24,81.51 23.87,81.39 22.19,81.39 21.81,81.01 19.42,81.01 19.3,80.88 17.89,80.88 16.93,79.93 15.33,79.93 14.82,79.42 13.96,79.42 11.45,76.9 11.23,76.9 9.74,75.42 9.54,75.42 9.03,74.91 v2(9.03,74.86)
  BOTTOM w0.127: U20.J60 26.14,82.86 v2(25.84,83.16)
XDP_BPM1: length 28.1
  TOP w0.127: CN1.42 12.11,70.11 11.85,70.36 11.85,73 9.95,74.91 v2(9.67,74.91)
  IN1 w0.127: v2(9.67,74.91) 9.97,74.91 10.96,75.9 11.75,75.9 14.76,78.91 15.01,78.91 15.09,78.99 16.71,78.99 18.1,80.37 19.51,80.37 19.63,80.5 22.06,80.5 22.45,80.88 24.08,80.88 24.5,81.3 24.5,81.6 25.05,82.15 25.65,82.15 26.47,82.97 v2(26.47,83.16)
  BOTTOM w0.127: v2(26.47,83.16) 26.14,83.49 U20.H60
XDP_DBRESET_N: length 8.9
  TOP w0.127: CN1.7 5.86,76.11 v2(5.72,75.98)
  BOTTOM w0.127: R308.1 C260.2 11.36,77.21 11.19,77.04 v2(10.28,77.04) 9.63,77.04 8.75,76.17 5.91,76.17 v2(5.72,75.98)
XDP_PRDY#_CPU: length 46.6
  TOP w0.127: CN1.33 12.13,65.61 11.5,64.98 11.17,64.98 10.22,64.03 6.19,64.03 v2(6.04,63.89) 5.43,63.89 4.15,62.6 3.28,62.6 TP61.1
  IN1 w0.127: v2(22.93,82.95) 22.46,82.48 21.07,82.48 20.79,82.76 18.69,82.76 16.62,80.69 14.65,80.69 14.53,80.57 13.53,80.57 13.38,80.42 12.12,80.42 11.7,80 11.7,78.23 11.13,77.67 10.86,77.67 9.77,76.57 8.95,76.57 6.85,74.48 6.85,72.5 6.14,71.79 5.45,71.79 5.02,71.35 5.02,66.25 6.04,65.23 v2(6.04,63.89)
  BOTTOM w0.076: U20.J62 24.54,83.07 23.96,83.07 23.74,83.29 23.26,83.29
  BOTTOM w0.127: 23.26,83.29 23.21,83.29 22.93,83.01 v2(22.93,82.95)
XDP_PREQ#_CPU: length 45.6
  TOP w0.127: CN1.32 12.14,65.11 11.75,64.72 11.28,64.72 10.33,63.77 6.56,63.77 v2(6.04,63.25) 5.33,62.54 TP62.1
  IN1 w0.127: v2(6.04,63.25) 6.49,63.71 6.49,65.14 5.28,66.36 5.28,71.23 5.58,71.53 6.24,71.53 7.1,72.39 7.1,74.27 9.16,76.32 9.88,76.32 10.97,77.41 11.24,77.41 11.96,78.13 11.96,79.89 12.23,80.17 13.48,80.17 13.64,80.32 14.64,80.32 14.75,80.43 16.72,80.43 18.13,81.84 19.45,81.84 19.58,81.97 22.71,81.97 v2(22.85,81.83)
  BOTTOM w0.076: U20.K62 24.84,82.01 24.4,81.57 23.86,81.57 23.72,81.44 23.28,81.44 23.26,81.46
  BOTTOM w0.127: v2(22.85,81.83) 22.89,81.83 23.26,81.46
XDP_RST: length 6.3
  TOP w0.127: v2(9.01,75.54) 8.94,75.61 CN1.8
  BOTTOM w0.127: v2(9.01,75.54) 9.16,75.39 9.95,75.39 v2(10.28,75.72) 11.45,76.89 12.63,76.89 R307.2
XDP_TCK0: length 23.6
  TOP w0.127: v2(15.28,82.3) 15.11,82.12 15.11,80.62 15.36,80.37 15.36,79.1 14.87,78.61 CN1.59
  IN1 w0.127: v2(15.28,82.3) 15.28,82.43 15.38,82.53 15.38,83.73 15.99,84.34 15.99,84.77 16.39,85.16 17.4,85.16 17.82,84.74 19.89,84.74 20.03,84.6 21.94,84.6 22.03,84.69 23.74,84.69 24.54,85.49 v2(25.8,85.49)
  BOTTOM w0.127: U20.E60 26.14,85.15 v2(25.8,85.49) ; v2(15.28,82.3) 15.36,82.23 v2(15.36,81.67) 14.96,81.27 R270.2 14.96,80.88 R278.2 15.68,79.93 15.45,79.7 15.45,79.25 15.35,79.15 R295.2
XDP_TCK1: length 5
  TOP w0.127: CN1.58 14.98,78.11 15.91,79.04 v2(15.91,79.48)
  BOTTOM w0.127: v2(15.91,79.48) v2(15.91,78.85) 15.91,78.71 15.51,78.31 R301.2
XDP_TDI: length 25.4
  TOP w0.127: v2(5.33,79.1) 6.32,78.11 CN1.3
  IN1 w0.127: v2(5.33,79.1) 4.95,79.1 3.14,77.3 3.14,62.85 3.95,62.04 3.95,60.71 v2(4.08,60.58)
  BOTTOM w0.127: v2(4.08,60.58) 3.78,60.89 3.24,60.89 3.08,60.73 R424.2 ; R424.2 v4(2.38,60.46) ; R424.2 R427.1
XDP_TDI_CPU: length 47.5
  TOP w0.127: v2(7.28,60.08) 7.64,59.72 7.84,59.72 8.02,59.54 8.02,58.63 8.29,58.36 U3.6
  BOTTOM w0.076: U20.F63 24.13,84.33 23.26,84.33
  BOTTOM w0.127: v2(7.28,60.08) 7.28,60.09 6.51,60.86 5.81,60.86 5.2,61.47 5.2,62.06 4.95,62.32 v2(4.95,63.15) 4.95,63.78 4.3,64.42 4.3,76.14 4.84,76.69 8.55,76.69 8.81,76.94 8.81,78.06 10.44,79.69 11.85,79.69 12.9,80.73 12.9,82.86 13.48,83.44 14.27,83.44 14.47,83.65 15.81,83.65 16.15,83.98 16.15,84.84 16.63,85.32 16.88,85.32 17.14,85.58 17.77,85.58 17.89,85.46 R253.2 18.15,85.2 18.61,84.74 19.86,84.74 20.38,84.22 20.74,84.22 20.95,84.01 21.89,84.01 22.22,84.33 23.26,84.33
XDP_TDI_R: length 10.4
  TOP w0.127: v2(8.53,59.11) 8.7,59.11 9.24,58.58 9.24,58.09 9,57.86 U3.5
  BOTTOM w0.127: R429.1 3.08,59.18 3.56,59.66 R427.2 3.6,59.86 4.58,59.86 5.3,59.14 5.3,58.2 5.5,57.99 v2(5.78,57.99) 6.16,57.61 7.33,57.61 8.53,58.81 v2(8.53,59.11)
XDP_TDO: length 42.4
  TOP w0.127: v2(4.48,61.72) 4.48,61.1 4.91,60.67 6.24,60.67 6.29,60.72 8.13,60.72 8.41,60.44 8.41,60.24 9.17,59.48 9.78,59.48 10.38,58.88 10.38,56.44 v2(9.8,55.86) 9.3,56.36 U3.2 ; v2(4.95,77.45) 5.28,77.11 CN1.5
  IN1 w0.127: v2(4.95,77.45) 3.4,75.9 3.4,62.95 4.48,61.87 v2(4.48,61.72)
  BOTTOM w0.127: R437.2 R436.2 3.08,57.7 3.56,58.18 R433.2 3.88,58.62 3.88,59.19 4.05,59.35 4.37,59.35 4.79,58.93 4.79,57.74 5.47,57.07 6.02,57.07 6.66,56.42 v4(9.24,56.42) v2(9.8,55.86)
XDP_TDO_CPU: length 52.7
  TOP w0.127: v2(7.89,60.28) 8.37,59.8 8.49,59.8 9.07,59.22 9.64,59.22 10.12,58.74 10.12,57.79 9.19,56.86 U3.3
  BOTTOM w0.076: U20.F62 24.51,83.95 24.07,83.95 23.94,84.08 23.26,84.08
  BOTTOM w0.127: v2(7.89,60.28) 7.64,60.53 7.2,60.53 6.61,61.12 5.91,61.12 5.59,61.44 5.59,62.57 5.82,62.79 6.27,62.79 6.65,63.18 6.65,63.4 v2(6.65,63.41) 7.23,63.98 7.23,65.41 6.87,65.77 5.87,65.77 4.56,67.08 4.56,76.04 4.94,76.42 8.65,76.42 9.8,77.58 10.43,77.58 10.79,77.93 10.79,78.47 10.5,78.77 10.5,79.16 10.77,79.43 11.98,79.43 13.15,80.6 13.15,82.75 13.59,83.19 14.37,83.19 14.58,83.39 15.92,83.39 16.58,84.05 17.77,84.05 17.89,84.17 R258.2 17.94,84.49 19.76,84.49 20.28,83.97 20.63,83.97 20.85,83.75 22.12,83.75 22.45,84.08 23.26,84.08
XDP_TMS: length 28.3
  TOP w0.127: U3.9 5.18,58.86 v1(3.25,60.79) 3.09,60.95 v2(3.09,61.88) ; v2(6.11,80.12) 6.09,80.09 6.09,78.85 6.32,78.61 CN1.2
  IN1 w0.127: v2(3.09,61.88) 2.63,62.34 2.63,77.79 4.96,80.12 v2(6.11,80.12)
  BOTTOM w0.127: v2(3.09,61.88) 3.05,61.84 R416.2
XDP_TMS_CPU: length 49.6
  TOP w0.127: U3.8 6.15,59.53 v2(6.65,60.03)
  BOTTOM w0.076: 23.41,85.48 23.56,85.48 23.64,85.4 24.34,85.4 24.53,85.59 24.53,85.8 24.7,85.97 24.96,85.97 25.39,85.54 25.39,85.32 25.49,85.23 U20.E61
  BOTTOM w0.127: 23.41,85.48 23.31,85.48 22.75,86.04 22.37,86.04 21.3,87.1 20.11,87.1 19.56,86.56 18.75,86.56 18.41,86.21 18.14,86.21 R244.2 17.89,86.21 17.76,86.34 17.01,86.34 16.96,86.29 16.46,86.29 15.89,85.72 15.89,84.09 15.71,83.9 14.34,83.9 14.14,83.7 13.38,83.7 11.93,82.25 11.93,80.14 11.73,79.94 10.33,79.94 8.55,78.16 8.55,77.07 8.44,76.95 4.75,76.95 4.02,76.23 4.02,64.34 4.41,63.95 4.41,62.49 4.95,61.96 4.95,61.37 v2(5.96,60.35) 6.29,60.03 v2(6.65,60.03)
XDP_TRST#: length 36.1
  TOP w0.127: v2(4.82,82.78) v1(4.82,81.59) 4.82,78.98 5.21,78.59 5.45,78.59 5.96,78.08 5.96,77.93 6.28,77.61 CN1.4 ; U3.12 4.1,56.86 v2(4.08,56.88)
  IN1 w0.127: v2(4.82,82.78) 4.63,82.59 4.63,82.21 2.1,79.69 2.1,58.86 v2(4.08,56.88)
XDP_TRST#_CPU: length 77.7
  TOP w0.127: v2(4.11,57.51) 4.26,57.36 U3.11
  IN1 w0.127: v2(26.45,85.49) 25.98,85.96 24.63,85.96 23.61,84.94 21.92,84.94 21.83,84.85 20.13,84.85 19.99,84.99 18.36,84.99 16.91,86.44 16.15,86.44 15.06,85.35 13.66,85.35 13.5,85.19 13.5,83.37 13.76,83.11 v2(13.76,82.73) 12.72,82.73 12.51,82.53 10.69,82.53 8.78,80.62 5.11,80.62 2.38,77.89 2.38,59.44 4.06,57.76 4.06,57.56 v2(4.11,57.51)
  BOTTOM w0.127: v2(13.76,82.73) 13.76,82.3 14.17,81.89 14.17,80.88 v2(14.52,80.52) 14.91,80.52 15.18,80.26 15.18,79.57 14.98,79.37 14.49,79.37 13.73,78.62 13.73,75.59 16.44,72.88 16.54,72.88 17.02,72.4 17.49,72.4 18.09,71.8 19.59,71.8 19.83,72.04 R361.2 20.02,71.67 22.67,69.02 22.67,68.55 23.78,67.44 24.44,67.44 U20.AU62 ; v2(26.45,85.49) 26.79,85.15 U20.E59
XTAL24_IN: length 11.3
  BOTTOM w0.127: Y2.1 49.35,94.27 48.94,93.86 48.73,93.86 48.4,93.53 48.4,93.17 48.51,93.07 C137.1 49.13,92.83 49.65,92.31 49.83,92.31 50.16,91.98 TP76.1 49.76,91.45 R154.1 49.03,91.96 48.86,91.8 48.86,89.26 48.16,88.56 48.16,87.78 U20.A25
XTAL24_OUT: length 11.3
  BOTTOM w0.127: U20.B25 48.1,87.26 47.74,87.62 47.74,87.89 47.87,88.02 47.87,88.82 48.48,89.43 48.48,91.84 48.55,91.9 R154.2 48.3,92.18 48.25,92.13 TP74.1 47.9,92.56 47.75,92.71 C138.1 47.75,93.79 48.25,94.29 48.25,95.36 Y2.3
XTL_IN: length 7.9
  BOTTOM w0.127: v2(253.46,112.02) 254.26,111.22 Y1.3 253.18,109.23 251.83,109.23 251.42,108.81 C25.2 250.54,108.28 U5.5
XTL_OUT: length 6.5
  BOTTOM w0.127: v3(254.25,109.21) 254.25,109.21 254.23,109.2 253.61,109.2 253.36,108.95 253.23,108.95 252.46,108.17 Y1.1 252.21,108.35 251.39,108.35 251.07,108.03 C36.2 250.72,107.78 U5.6
N52444: length 4.8
  BOTTOM w0.178: PC140.2 11.69,24.05 11.78,23.96 11.78,23.3 11.42,22.94 11.42,22.23 11.65,22 PU8.5
  BOTTOM w0.508: PC140.2 PR122.2 11.69,25.64 v2(12.18,26.14)
N175071: length 9.4
  BOTTOM w0.178: PR37.2 66.92,108.32 PC60.1 67.18,107.3 67.31,107.17 PR41.1 68.06,107.4 PC47.1 69.49,108.84 69.49,110.24 70.91,111.66 v2(70.91,113.06)
N175281: length 4.8
  BOTTOM w0.178: PR52.1 PR53.2 64.89,105.82 v2(63.97,106.74) 62.76,106.74 62.59,106.9 PU3.1
N180533: length 2.2
  BOTTOM w0.254: PR46.1 125.93,106.67 PU2.5
N220342: length 54.5
  TOP w0.254: v2(131.67,100.16) 131.67,99.8 132.07,99.4 v1(132.63,99.4) 134.24,99.4 138.15,95.48 138.42,95.48 139.69,94.21 139.69,90.05 140.73,89.01 147.53,89.01 149.56,91.04 153.79,91.04 156.33,93.58 156.33,94.9 157.29,95.86 163.7,95.86 164.2,95.36 164.58,95.36 164.97,95.74 v2(165.53,95.74)
  BOTTOM w0.254: v2(165.53,95.74) 165.37,95.59 165.37,94.83 PC120.1 166.07,94.6 166.74,95.28 166.74,96.5 167.05,96.81 PU7.6 ; v2(131.67,100.16) 131.67,100.92 132.54,101.79 PR83.2 PR82.1 PR81.1
N242734: length 18.1
  BOTTOM w0.254: PR17.2 PR11.2 55.21,114.27 v4(52.93,111.99) 52.37,111.44 42.39,111.44 41.42,110.46 PR28.1
N243140: length 4.8
  BOTTOM w0.254: PR35.1 PC29.2 123.83,110.78 PU2.1 v4(124.98,112.58)
N16845323: length 2.9
  BOTTOM w0.127: C28.2 206.23,109.23 206.43,109.03 C33.2 v2(206.82,109.71) 206.82,110.32 206.93,110.43 U4.1
N16845325: length 1.5
  BOTTOM w0.127: U4.3 205.9,111.43 C14.2
N16846403: length 6.3
  BOTTOM w0.127: v2(202.91,107.22) 202.91,107.52 203.23,107.84 Q5.2 202.73,108.32 202.51,108.54 202.51,109.83 202.3,110.04 201.62,110.04 201.41,110.24 201.41,110.72 201.67,110.98 202,110.98 202.3,111.28 R24.2
N16847081: length 3.2
  BOTTOM w0.127: R28.2 203.32,110.21 203.23,110.12 Q5.1 203.31,109.32 203.52,109.53 204.67,109.53 v1(204.84,109.71)
N16889934: length 2.9
  BOTTOM w0.127: U6.3 259.18,101.42 R70.2 259.47,101.85 259.95,102.33 R67.2 260.33,102.09 v1(260.47,102.09)
N16894218: length 4.3
  TOP w0.508: v2(8.27,11.49) v1(8.27,10.8) 8.27,10.09 8.6,9.76 CN14.12
  BOTTOM w0.508: R476.1 7.42,12.57 8.27,11.71 v2(8.27,11.49)
N16894369: length 2.6
  BOTTOM w0.127: R269.2 10.36,80.55 9.75,81.15 CN7.18
N16944248: length 5
  BOTTOM w0.127: PQ4.2 134.61,107.32 PR34.2 134.85,108.81 PR33.1 135.63,109.71 135.3,110.04 135.3,111.38 v2(135.32,111.41)
N16946334: length 2.6
  BOTTOM w0.203: PR51.1 v2(109.59,105.34) 109.4,105.15 PU6.1
N16946514: length 70.6
  TOP w0.254: v2(54.12,97.31) 54.75,97.31 v1(55.19,97.74) 57.41,99.97 58.12,100.68 61.07,100.68 61.92,101.53 66.26,101.53 67.44,102.71 68.15,102.71 72.4,98.46 85.26,98.46 85.99,99.19 85.99,99.19 86.61,99.8 90.73,99.8 91.39,100.46 92.57,100.46 92.89,100.46 101.47,100.46 102.64,100.46 102.84,100.26 103.05,100.06 111.85,100.06 111.92,99.98 112.34,99.98 112.57,100.21 112.88,100.21 113.38,100.71 v2(113.38,100.72)
  BOTTOM w0.127: v2(113.38,100.72) 113.38,100.77 112.23,101.92 PU6.9
  BOTTOM w0.254: v2(54.12,97.31) 54.37,97.31 54.73,97.67 54.73,98.31 54.25,98.79 PC104.1 54.36,98.94 54.96,98.94 55.34,99.32 PQ5.4
N16955305: length 3.9
  BOTTOM w0.127: PR110.1 PR111.2 145.29,93.83 145.41,93.71 PR114.2 146.17,92.83 146.2,92.86 PQ12.6
N16955311: length 2.3
  BOTTOM w0.127: v2(144.57,91.98) 144.64,92.05 PR114.1 145.57,92.21 PQ12.5
N16955315: length 2.5
  BOTTOM w0.127: PR110.2 147.69,93.71 147.69,92.31 147.79,92.21 PQ12.2
N16955333: length 5.6
  BOTTOM w0.254: PR113.1 152.29,93.55 151.92,93.92 151.88,93.92 151.59,94.21 151,94.21 150.69,93.91 148.53,93.91 v2(148.48,93.86) 148.37,93.74 PQ12.1
N17009890: length 2.3
  BOTTOM w0.508: v4(97.78,102.47) 97.45,102.8 PR63.1 98.06,103.51 98.15,103.6 PC77.2
N17010003: length 2.9
  BOTTOM w0.254: PR88.1 148.33,101.58 148.32,101.59 148.32,101.96 PR76.1 147.03,102.21 v2(147.03,101.53)
N17010113: length 2.9
  BOTTOM w0.508: PR30.1 154.26,111.33 PC28.2 154.17,111.66 v4(153.26,112.58)
N17010150: length 2.9
  BOTTOM w0.178: v2(151.24,104.13) PC79.2 150.36,104.73 151.01,105.38 PU5.11
N17010852: length 5.7
  BOTTOM w0.178: 151.01,110.09 PU5.6
  BOTTOM w0.508: PR25.1 151.49,111.23 PC26.2 ; PC26.2 151.01,110.55 151.01,110.09 ; PC26.2 150.33,111.66 v4(149.55,112.45)
N17011739: length 3.5
  BOTTOM w0.178: PR67.1 104.08,104.17 104.23,104.32 v2(104.23,104.96) 104.23,105.24 103.85,105.62 103.45,105.62 102.9,106.16 PU4.3
N17011968: length 6.4
  BOTTOM w0.178: PU5.3 149.81,109.49 149.55,109.76 146.88,109.76 v2(146.28,110.36) 145.41,111.23 PR27.1
N17026582: length 1.7
  BOTTOM w0.254: Q18.2 228.2,84.65 R260.1
N17026606: length 4
  BOTTOM w0.127: U18.1 220.56,81.92 220.97,82.33 220.97,83.09 222.32,84.43 C218.1
N17026675: length 3.4
  BOTTOM w0.305: R252.2 213.6,86.4 213.25,86.75 212.11,86.75 U14.3
N17026679: length 3.1
  BOTTOM w0.254: v2(212.87,86.21) 213.02,86.06 213.02,85.32 212.78,85.08 C209.1 212.5,85.08 211.64,84.22 U14.4
N17026786: length 5.1
  BOTTOM w0.203: U18.25 214.06,79.92 212.95,78.81 212.95,78.59 212.79,78.44 212.79,78.01 v2(213.2,77.6) 212.87,77.27 212.69,77.27 C261.2
N17026790: length 3.9
  BOTTOM w0.203: C256.2 212.13,78.25 212.62,78.73 212.62,78.94 213.99,80.32 U18.26
N17027367: length 2.3
  BOTTOM w0.203: C266.1 214.27,76.17 214.76,76.66 215.38,76.66 215.62,76.89 U18.20
N17027369: length 3.4
  BOTTOM w0.203: C267.1 213.81,75.96 213.81,76.39 214.01,76.59 214.22,76.59 214.82,77.18 U18.21
N17027467: length 2.8
  BOTTOM w0.127: v1(220.82,76.81) 220.82,76.3 R317.2
  BOTTOM w0.254: C270.1 R317.2 220.97,76.18 221.23,75.93 Q23.3
N17027622: length 3
  BOTTOM w0.203: v2(213.35,81.77) 213.82,81.77 213.99,81.59 214.21,81.59 214.28,81.52 U18.29
  BOTTOM w0.254: C238.2 212.34,81.01 213.1,81.77 v2(213.35,81.77)
N17056548: length 12.5
  BOTTOM w0.127: v3(245.86,110.47) 247.13,109.21 247.13,104.45 248.3,103.28 U5.15 250.18,103.28 250.64,103.74 R60.2 250.83,104.01 250.97,104.15 251.8,104.15 R58.1
N17056549: length 10.7
  BOTTOM w0.127: v3(245.86,107.8) 245.86,105.01 248.09,102.78 U5.16 250.37,102.78 250.49,102.9 R66.2 250.83,102.76 251.07,102.52 251.97,102.52 R65.1
N17056550: length 9.1
  BOTTOM w0.127: v2(241.42,96.83) R89.1 241.71,97.78 241.8,97.87 241.8,98.13 241.94,98.26 R88.2 242.45,98.53 243.63,98.53 243.93,98.84 246.91,98.84 247.2,99.13 U5.17
N17056551: length 4.7
  BOTTOM w0.127: U5.20 245.7,100.02 244.92,99.24 v1(244.48,99.24) 244.22,99.24 244.03,99.43 243.22,99.43 243.16,99.38 R76.2 R77.1
N17056552: length 13.3
  BOTTOM w0.127: v3(244.64,107.42) 245.2,106.87 U5.21 245.2,100.78 245.2,99.98 244.96,99.74 240.82,99.74 240.73,99.65 R78.2 R79.1
N17056553: length 9
  BOTTOM w0.127: U5.22 244.7,100.14 244.56,99.99 239.32,99.99 239.01,99.67 R80.2 239.12,99.28 239.6,98.8 R86.1 v2(239.6,97.57)
N17056596: length 3.8
  BOTTOM w0.127: v2(234.61,109.2) 234.75,109.06 R34.2 235.87,109.06 236.82,108.11 236.82,107.88 236.92,107.78 U5.43
N17056616: length 6.6
  BOTTOM w0.127: U5.60 245.2,112.98 245.38,113.16 249.02,113.16 v2(249.39,112.78) 249.72,112.45 R20.2
N17056622: length 4.8
  BOTTOM w0.127: R56.2 252.02,105.2 v2(251.83,105.39) 251.71,105.52 C37.2 251.31,105.86 251.12,106.05 250.77,106.05 250.39,106.43 250.39,106.96 250.07,107.28 U5.7
N17056680: length 3.1
  TOP w0.127: U1.6 229.45,115.75 v2(229.05,115.35)
  BOTTOM w0.127: C8.1 228.59,114.89 v2(229.05,115.35) v4(229.05,116.06)
N17056681: length 7.6
  TOP w0.127: v1(221.73,117.45) 221.73,118.85 222.23,119.35 C1.1 222.23,119.83 222.57,120.17 226,120.17 226.25,119.92 U1.12
N17056682: length 4.7
  TOP w0.127: U1.13 225.45,119.81 225.34,119.92 223.11,119.92 223.01,119.83 C1.2 223.01,118.86 v1(222.62,118.47)
N17057085: length 4.9
  BOTTOM w0.127: v4(11.45,91.57) 11.78,91.57 12.46,90.89 D9.2 13.25,92.45 R143.2 13.28,92.55 R129.2
N17058760: length 28.5
  TOP w0.254: v2(203.7,76.69) 204.21,77.2 v1(205.38,77.2) 205.96,77.2 v2(206.49,76.66) 206.88,77.04 212.08,77.04 212.69,76.43 214.11,76.43 215.38,75.16 219.7,75.16 220.59,74.27 224.91,74.27 225.39,74.76 v2(225.39,74.77)
  BOTTOM w0.254: R318.2 206.88,76.32 206.54,76.66 v2(206.49,76.66) ; v2(225.39,74.77) 225.54,74.93 225.54,76.7 R310.2 ; v2(203.7,76.69) 203.7,76.56 204.07,76.19 R319.2 204.07,75.94 203.64,75.51 R330.2
N17058774: length 7.5
  BOTTOM w0.254: U19.17 205.1,81.99 204.94,82.15 202.68,82.15 202.33,82.5 200.98,82.5 C226.1 199.92,82.66 199.33,82.66 199.08,82.91 v2(198.85,82.91)
N17058778:
  vias: v4(202.81,81.26)
N17058793: length 1.5
  BOTTOM w0.254: U19.4 208.98,78.98 C254.1
N17058795: length 1.5
  BOTTOM w0.254: C240.1 208.98,79.98 U19.2
N17058821: length 6.2
  BOTTOM w0.254: v4(201.67,84.43) 201.67,83.29 C226.2 202.26,83.11 202.84,82.53 205.12,82.53 205.61,82.05 U19.18
N17058851: length 4.6
  BOTTOM w0.127: U19.6 207.12,77.51 207.36,77.27 207.36,75.6 206.71,74.95 R335.1 206.71,74.14 v2(206.47,73.89)
N17096515: length 2.5
  BOTTOM w0.127: R146.2 R137.2 228.95,93.15 229.24,92.86 v2(229.35,92.86) U12.5
N17096516: length 6
  BOTTOM w0.127: U12.7 231.1,94.65 230.98,94.77 230.64,94.77 v2(229.89,94.02) 229.44,93.58 227.51,93.58 R138.2 R130.2
N17096525: length 4.8
  BOTTOM w0.127: v4(237.86,94.59) 237.48,94.59 236.99,94.1 R122.2 R123.2 236.45,93.69 236.36,93.6 235.12,93.6 234.94,93.43 234.94,92.97 234.83,92.86 U12.14
N17099741: length 1.3
  BOTTOM w0.508: C213.2 R234.1
N17099744: length 1.3
  BOTTOM w0.508: C212.2 R233.1
N17099747: length 1.3
  BOTTOM w0.508: C210.2 R231.1
N17099750: length 1.3
  BOTTOM w0.508: R232.1 C211.2
N17118471: length 5.1
  TOP w0.127: v2(24.63,12.15) 25.01,11.77 25.01,11.03 24.6,10.62 v1(24.6,10.09) CN14.44
  BOTTOM w0.127: R472.2 24.63,12.93 v2(24.63,12.15)
N17161794: length 9
  BOTTOM w0.127: v2(230.5,89.49) 230.5,88.94 R484.2 230.53,88.59 230.62,88.5 230.62,88.14 231.31,87.46 231.31,87.08 231.57,86.81 232.74,86.81 232.88,86.67 232.88,85.25 232.95,85.18 ; 232.95,85.18 Q19.3 ; 232.95,85.18 232.92,85.18 232.38,84.64 231.4,84.64 R483.2
N17161796: length 5
  BOTTOM w0.127: v2(230.12,88.24) 230.12,87.8 R221.2
  BOTTOM w0.254: R221.2 230.03,87.66 230.65,87.66 230.95,87.36 230.95,86.48 ; Q19.6 230.95,86.48 ; 230.95,86.48 230.95,85.96 231.08,85.83 Q19.5
N17179576: length 8.1
  BOTTOM w0.127: R193.2 100.7,89.01 100.79,88.92 U15.9 100.79,86.89 101.34,86.34 104.13,86.34 105.28,87.48 v4(105.28,87.86)
N17179620: length 3.2
  BOTTOM w0.127: R297.1 C251.2 103.49,77.96 v2(104.72,77.96)
N17184096: length 4.7
  BOTTOM w0.127: R257.2 181.45,84.38 181.73,84.66 Q20.5 Q20.2 v4(185.67,84.66)
N17184191: length 4.1
  TOP w0.508: v2(9.06,11.46) 9.06,10.37 v1(9.4,10.03) CN14.14
  BOTTOM w0.508: v2(9.06,11.46) 9.06,11.91 R475.1
N17187862: length 3.3
  BOTTOM w0.127: R45.2 215.83,107.54 215.51,107.22 214.44,107.22 214.3,107.07 U7.56
N17232057: length 11
  BOTTOM w0.127: R50.1 197.72,106.79 197.45,107.06 R49.1 197.71,107.29 v2(198.21,106.79) 198.59,107.17 200.12,107.17 200.22,107.27 200.22,110.62 200.14,110.7 198.77,110.7 197.65,111.82 D2.1
N17274037: length 2.9
  TOP w0.127: TP1.1 214.7,105.04 214.62,104.96 v2(214.62,104.48)
  BOTTOM w0.127: v2(214.62,104.48) 214.62,104.53 214.7,104.6 U7.57
N17345972: length 3.1
  BOTTOM w0.127: v3(44.32,23.35) 44.15,23.35 C342.2
  BOTTOM w0.305: R470.2 41.98,23.14 42.75,22.37 C342.2
N17367414: length 5
  TOP w0.127: U23.14 231.57,118.16 v2(230.95,118.78)
  BOTTOM w0.127: v4(230.14,118.78) v2(230.95,118.78) 231.01,118.72 231.01,116.82 231.27,116.56 C363.1
N17439687: length 3.3
  BOTTOM w0.127: U7.91 219.89,94.16 220.36,93.68 220.36,92.74 220.87,92.23 TP75.1
N17486948: length 1.9
  BOTTOM w0.127: U10.8 251.43,95.99 251.71,95.71 R109.1 R105.2
N17486952: length 2.2
  BOTTOM w0.127: R111.1 R106.2 v1(245.86,95.99) U10.18
N17486954: length 3.6
  BOTTOM w0.127: U10.17 246.2,95.49 245.79,95.08 R126.1 246.03,94.17 v1(246.52,93.68) R139.2
N17486955: length 2
  BOTTOM w0.127: R119.2 R115.1 251.56,95.49 U10.9
N17486967: length 4.3
  BOTTOM w0.254: U10.19 246,96.49 245.74,96.75 R99.2 245.34,97.17 245.2,97.31 v2(244.52,97.31) 243.98,97.31 243.71,97.04 R101.1
N17486969: length 3.9
  BOTTOM w0.127: U10.7 251.48,96.49 R98.2 R95.1 251.97,97.76 251.71,98.02 251.02,98.02 v2(250.56,98.48)
N17490098: length 4.4
  TOP w0.127: TP9.1 214.5,102.75 v2(214.67,102.93)
  BOTTOM w0.127: U7.55 213.9,104.57 214.67,103.79 v2(214.67,102.93)
N17490148: length 2.3
  TOP w0.127: v2(215.23,104.65) 215.21,104.63 TP5.1
  BOTTOM w0.127: U7.59 215.5,105.37 215.23,105.11 v2(215.23,104.65)
N17490164: length 2.2
  TOP w0.127: TP2.1 216.32,105.38 215.87,104.92 v2(215.87,104.83)
  BOTTOM w0.127: v2(215.87,104.83) 215.87,104.91 215.9,104.94 U7.60
N17490215: length 3.6
  TOP w0.127: v2(215.94,103.51) 215.79,103.36 TP8.1
  BOTTOM w0.127: v2(215.94,103.51) 215.94,104.17 216.32,104.55 216.32,105.34 216.3,105.36 U7.61
N17490231: length 3.3
  TOP w0.127: TP4.1 216.55,103.76 v2(216.55,103.71)
  BOTTOM w0.127: U7.62 216.7,103.86 v2(216.55,103.71)
N17490548: length 3.1
  BOTTOM w0.127: R39.2 213.48,108.38 v2(213.48,107.93) 213.48,107.55 213.08,107.15 212.52,107.15 212.39,107.02 212.37,107.02 212.3,106.94 U7.51
N17490556: length 3.9
  TOP w0.127: v2(212.82,103.18) 212.39,103.61 TP6.1
  BOTTOM w0.127: U7.52 212.7,105.39 212.82,105.26 v2(212.82,103.18)
N17490564: length 3.5
  TOP w0.127: TP3.1 v2(213.73,103.59)
  BOTTOM w0.127: v2(213.73,103.59) 213.1,104.22 U7.53
N17679694: length 4.9
  BOTTOM w0.254: v3(258.06,105.94) 258.06,105.9 ; 258.06,105.9 258.61,106.46 C34.2 257.94,108.27 257.7,108.51 R43.2 ; 258.06,105.9 258.06,105.14 Q7.2
N19259806: length 6.6
  BOTTOM w0.076: U20.U3 61.72,78.21 61.97,77.95 63.78,77.95 63.92,77.81 65.4,77.81 65.42,77.78
  BOTTOM w0.127: 65.42,77.78 66.03,77.78 66.13,77.68 67.3,77.68 v1(67.35,77.73) 67.39,77.77 R302.1
N19299291: length 4.8
  BOTTOM w0.076: U20.C35 41.96,86.65 42.28,86.97 42.28,88.5
  BOTTOM w0.127: R171.1 42.54,90.66 42.28,90.4 v2(42.28,90.15) 42.28,88.5
N19299303: length 7.4
  TOP w0.127: v2(43.58,90.02) 43.17,89.62 43.17,88.61 v1(42.1,87.54) 41.11,86.55 v2(41.11,86.21)
  BOTTOM w0.127: R170.1 43.17,90.43 v2(43.58,90.02) ; v2(41.11,86.21) 41.24,86.09 U20.C34
N19299315: length 17.4
  IN2 w0.127: v2(57.57,70.64) 57.73,70.49 58.39,70.49 58.82,70.06 58.82,68.03 59.09,67.76 59.09,67.38 60.67,65.79 60.67,63.25 61.59,62.34 61.59,60.69 61.76,60.51 61.76,59.21 61.33,58.78 v2(61.33,58.3)
  BOTTOM w0.089: U20.AK8 58.39,71.38 57.98,71.38 57.57,70.97 v2(57.57,70.64)
  BOTTOM w0.127: v2(61.33,58.3) 61.03,57.99 v2(60.82,57.99) 60.53,57.99 R434.1
N19299327: length 17.7
  IN2 w0.127: v2(60.83,58.68) 61.46,59.31 61.46,60.3 61.33,60.43 61.33,61.98 60.42,62.9 60.42,65.66 60.19,65.89 58.54,65.89 58.29,66.15 58.29,66.65 58.83,67.2 58.83,67.65 58.56,67.92 58.56,69.93 58.26,70.24 57.83,70.24 v2(57.6,70.01)
  BOTTOM w0.127: v2(60.83,59.28) v2(60.83,58.68) 60.48,58.68 R432.1 ; U20.AL8 58.24,70.34 57.93,70.34 v2(57.6,70.01)
N19301607: length 1.3
  TOP w0.127: v2(25.84,80.16) 25.84,80.43 TP22.1
  BOTTOM w0.127: U20.P60 26.14,79.86 v2(25.84,80.16)
N19301610: length 3.5
  BOTTOM w0.127: U20.P61 25.15,79.41 24,79.41 23.92,79.48 22.75,79.48 TP87.1
N19301613: length 1.3
  TOP w0.127: v2(26.48,80.17) 26.59,80.17 TP23.1
  BOTTOM w0.127: v2(26.48,80.17) 26.79,80.47 U20.N59
N19301616: length 1.5
  TOP w0.127: TP26.1 24.44,80.16 v2(25.19,80.16)
  BOTTOM w0.127: v2(25.19,80.16) 25.49,80.46 U20.N61
N19301674: length 7
  BOTTOM w0.076: U20.AW14 54.65,65.44 54.65,64.65
  BOTTOM w0.127: 54.65,64.65 52.6,62.59 52.37,62.59 50.67,60.89 TP95.1
N19301676: length 7
  BOTTOM w0.127: U20.AY14 54.91,65.05 54.91,64.57 51.68,61.35 51.68,59.7 TP100.1
N19341308: length 27.9
  BOTTOM w0.127: R459.1 R460.1 42.17,26.99 41.7,26.52 39.74,26.52 39.44,26.22 39.44,23.65 40.61,22.48 42.08,22.48 42.74,21.82 43.55,21.82 44.57,22.84 46.42,22.84 46.96,22.31 46.96,17.86 45.56,16.46 v2(44.34,16.46) 43.96,16.46 43.55,16.87 41.11,16.87 40.91,16.67 Q27.1
N20856073: length 3.1
  BOTTOM w0.381: C279.2 15.65,64.1 R395.1 v4(15.88,61.91)
N20883509: length 9.3
  BOTTOM w0.203: 202.34,89.3 C185.2 202.66,88.96 203.07,89.36 v2(203.07,89.39) 203.75,90.07 203.78,90.07 204.17,90.47 204.17,90.95 204.82,91.6 206.54,91.6 206.7,91.45 U7.124
  BOTTOM w0.305: 202.34,89.3 202.18,89.46 201.06,89.46 200.91,89.31 C191.2
N20883800: length 7
  BOTTOM w0.127: R207.2 216.77,88.33 217.01,88.09 218.52,88.09 R206.2 ; R207.2 216.5,88.65 216.3,88.45 216.22,88.45 v2(215.77,87.99) ; R207.2 216.68,88.74 216.68,89.24 216.37,89.54 215.64,89.54 215.5,89.68 U7.102
N20883858: length 2.7
  BOTTOM w0.127: U7.106 213.9,90.5 213.9,89.15 213.73,88.98 TP77.1
N20884583: length 10.8
  TOP w0.127: v2(202.46,90.58) v1(204.31,90.58) 206.7,90.58 207.59,89.69 209.72,89.69 v2(210.23,89.18)
  BOTTOM w0.127: v2(210.23,89.18) 209.9,89.52 U7.116 ; D8.2 v2(202.46,90.58)
N20884623: length 3.5
  TOP w0.127: R1.1 205.17,103.1 v2(204.82,103.46) v1(204.06,103.46)
  BOTTOM w0.127: v2(204.82,103.46) 204.52,103.76 U7.30
N21174483: length 1.8
  BOTTOM w0.127: R110.1 263.06,94.26 263,94.2 C128.1 263,93.8 v2(262.6,93.4)
N21758480: length 2.8
  BOTTOM w0.127: Q4.2 198.57,107.96 v2(198.21,108.31) 198.09,108.18 R46.1 R40.1
N21762370: length 6.2
  BOTTOM w0.076: U20.C62 24.71,86.33 24.45,86.07 24.05,86.07 23.74,86.37 23.26,86.37
  BOTTOM w0.127: TP82.1 19.63,87.36 21.43,87.36 22.41,86.37 23.26,86.37
N21762386: length 8.4
  BOTTOM w0.076: U20.C63 24.01,86.4 23.78,86.63 23.26,86.63
  BOTTOM w0.127: 23.26,86.63 22.54,86.63 21.54,87.62 19.16,87.62 18.65,87.11 16.9,87.11 TP83.1
N21762388: length 6
  BOTTOM w0.127: TP99.1 24.88,62.74 23.61,64.01 23.61,65.81 U20.AV63
N21762392: length 4.8
  BOTTOM w0.127: U20.AU63 22.78,67.04 20.64,64.9 TP94.1
N21810180: length 5.2
  BOTTOM w0.254: v2(215.89,109.81) R36.1 C26.2 ; C26.2 216.53,109.43 216.81,109.71 216.81,110.33 ; C26.2 R35.2
  BOTTOM w0.381: D3.2 215.38,110.77 215.55,110.61 R29.1 216.81,110.33
N21813127: length 13.1
  TOP w0.127: CN2.3 74.34,51.98 74.25,52.06 73.9,52.06 73.26,51.43 72.41,51.43 72.26,51.58 71.81,51.58 71.3,51.07 71.3,50.97 v3(71.24,50.91)
  BOTTOM w0.127: v3(71.24,50.91) 71.24,51.35 71.49,51.61 72.95,51.61 75.24,53.9 75.24,54.08 76,54.84 R445.1 R448.1
N21954661: length 1.4
  BOTTOM w0.127: v2(75.3,86.43) 75.56,86.17 75.56,85.58 75.3,85.32 R254.2
N22163425: length 4.3
  BOTTOM w0.127: U21.4 77.88,49.8 77.72,49.64 77.21,49.64 76.95,49.89 76.95,51.03 76.7,51.29 76.45,51.29 76.21,51.53 R451.1
N22182298: length 13.9
  TOP w0.127: v2(14.64,79.86) 14.17,79.86 13.91,80.12 11.8,80.12 11.63,79.94 10.51,79.94 9.68,79.11 CN1.1
  BOTTOM w0.127: v2(14.64,79.86) 14.62,79.86 13.48,78.72 13.48,75.18 v2(13.69,74.97) R344.1
N22183490: length 2.7
  TOP w0.127: CN2.15 74.57,57.97 v2(73.93,57.33)
  BOTTOM w0.127: v2(73.93,57.33) 73.91,57.31 R444.1 R443.1
N22646069: length 5.7
  BOTTOM w0.127: Q25.3 69.49,21.71 69.09,21.32 C345.2 R471.2 68.43,20.12 68.19,19.88 v4(67.16,19.88) 67.16,18.67 Q26.2
N24211466: length 6.7
  BOTTOM w0.127: v2(94.61,91.37) 94.45,91.22 92.88,91.22 91.37,89.71 U13.8 91.37,87.58 91.42,87.53 R235.1
N24211476: length 7.6
  BOTTOM w0.127: v2(95.38,90.29) 94.07,90.29 93.83,90.53 92.85,90.53 92.02,89.7 U13.7 92.02,87.78 92.32,87.48 92.89,87.48 93.51,86.86 R241.1
N24212148: length 7.8
  BOTTOM w0.254: v2(254.93,112.32) 255.44,112.83 256.63,112.83 Q3.3 257.27,109.12 256.8,108.66 R43.1 256.43,108.51 256.19,108.75 R44.2
N24468332: length 1.6
  BOTTOM w0.127: CN5.45 264.24,105.63 263.85,105.24 R54.1
N24811948: length 15.8
  BOTTOM w0.127: U7.69 219.91,102.96 224.4,107.45 224.4,109.2 224.86,109.66 225.57,109.66 226.69,110.77 226.69,112.81 v4(226.41,113.09) 225.44,114.05 R17.1
N31839427: length 1.3
  BOTTOM w0.127: R108.2 C133.1
N33084308: length 3.1
  BOTTOM w0.508: PR102.2 190.75,97.52 191.13,97.89 191.13,98
N38782190: length 2.4
  BOTTOM w0.508: v4(24.33,15.6) PR132.1 25.29,14.99 25.27,14.97 PC152.2
N41545033: length 4.3
  BOTTOM w0.254: PU2.6 124.98,106.73 PR47.2 PR48.2 v4(122.51,106.34)
N41545044: length 12
  IN2 w0.254: v2(123.19,104.93) 123.19,105.15 124.45,106.41 127.2,106.41 128.22,105.39 v2(131.69,105.39)
  BOTTOM w0.254: v2(123.19,104.93) 123.19,105.31 PR48.1 ; PR59.2 131.51,104.63 131.69,104.81 v2(131.69,105.39) v2(131.69,106.02)
N41545080:
  vias: v2(128.21,107.5)
N41583684: length 16.1
  BOTTOM w0.152: PU1.6 80.24,114.64 80.51,114.91 81.07,114.91 81.63,114.36 81.98,114.36 82.39,114.76 v2(82.39,116.46) 80.48,118.37 73.92,118.37 73.47,117.92 73.47,116.91 PR6.2
N41583721: length 2.2
  BOTTOM w0.508: PR16.1 72.63,112.76 PC21.1 v4(72.51,113.67)
N41583760: length 1.5
  BOTTOM w0.508: PR36.1 79.12,107.93 PC42.2
N41915855: length 1.3
  BOTTOM w0.508: PC40.2 49.4,109 49.37,108.96 PR38.1
N41915908: length 30.6
  IN1 w0.254: v2(36.31,107.83) 40.1,111.61 52.85,111.61 56,114.76 56,116.96 v2(56.49,117.45)
  BOTTOM w0.254: PR40.1 36.16,107.68 v2(36.31,107.83) ; v2(56.49,117.45) 56.49,117.35 v2(57.52,116.31) 57.65,116.18 PR10.2
N41916085: length 3.3
  BOTTOM w0.178: v2(69.21,113.67) PR18.2 PC22.2 PR19.1
N41916105: length 39.1
  IN2 w0.254: v2(31.74,110.47) 31.84,110.47 32.81,111.44 53,111.44 55.57,114 55.87,114 58.56,116.69 61.31,116.69 62.07,117.45 64,117.45 v2(64.13,117.33)
  BOTTOM w0.254: PR29.2 32.02,110.47 v2(31.74,110.47) ; PR2.2 64.75,117.33 v2(64.13,117.33) 64.12,117.34 PR3.2 63.15,117.29 v2(62.33,118.1)
N41916134: length 3.2
  BOTTOM w0.178: v2(70.15,111.94) 70.15,111.33 69.41,110.6 PC31.1 PR32.2
N41916242: length 3.2
  BOTTOM w0.178: PR14.2 61.21,113.91 61.21,112.58 61.02,112.39 61.02,112.39 60.59,111.96 PU3.16
N44133821: length 4.3
  TOP w0.127: v2(43.6,70.47) 43.54,70.47 43.12,70.9 43.12,72.06 43.81,72.75 TP40.1
  BOTTOM w0.089: U20.AL32 43.67,70.47 v2(43.6,70.47)
N44134111: length 2.4
  TOP w0.127: TP57.1 44.06,67.54 44.06,68.08 v2(43.6,68.54)
  BOTTOM w0.089: v2(43.6,68.54) 43.91,68.85 U20.AP32
N73864983: length 1.9
  BOTTOM w0.254: PR82.2 134.76,100.45 PQ8.3
N73866209: length 5.2
  BOTTOM w0.254: PR72.1 165.85,102.98 165.85,102.97 165.47,102.6 165.47,101.57 PR87.1 165.9,101 165.9,100.26 v2(166.49,99.67) 166.49,99.17 166.63,99.02 PU7.10
N73866453: length 15.7
  BOTTOM w0.254: 136.1,99.51 136.1,104.82 PQ4.3 ; 136.1,99.51 135.53,98.94 135.53,98.28 135.78,98.02 PQ8.2 135.27,97.29 134,98.56 134,99.14 133.85,99.29 132.81,99.29 132.42,98.9 PR94.2 PR98.2 ; 136.1,99.51 136.5,99.51 v4(137.13,98.89)
N73866532: length 1.4
  BOTTOM w0.508: PC41.1 176.55,108.31 176.32,108.08 PR42.1
N80459806: length 16.1
  BOTTOM w0.127: CN5.5 264.39,86.43 263.95,85.98 263.95,85 263.38,84.43 261.82,84.43 261.49,84.77 261.49,88.24 262.5,89.26 262.5,91.42 262.17,91.75 261.56,91.75 v2(261.31,92) 261.1,92.21 261.1,93.4 261.66,93.96 R124.1
N122990257: length 5.7
  TOP w0.127: CN1.35 14.38,66.61 14.52,66.76 14.52,70.02 14.75,70.25 v2(14.83,70.25)
  BOTTOM w0.127: v2(14.83,70.25) 14.75,70.25 14.65,70.15 R366.2
N124847733: length 11.1
  TOP w0.127: v3(74.06,51.44) 74.09,51.47 CN2.2
  IN2 w0.127: v3(74.06,51.44) 74.06,51.74 72.35,53.45 71.29,53.45 71,53.74 71,54.42 v2(71.19,54.62)
  BOTTOM w0.127: v2(71.19,54.62) 71.62,55.05 74.24,55.05 75.3,56.11 R442.1
N124847739: length 11.7
  TOP w0.127: v2(70.48,50.95) 70.95,51.41 71.28,51.41 71.7,51.83 72.38,51.83 72.53,51.68 73.16,51.68 73.8,52.33 74.31,52.33 74.46,52.47 CN2.4
  BOTTOM w0.127: v2(64.61,51.19) 65.13,50.67 R452.1 67.75,50.67 68.03,50.95 v2(70.48,50.95)
N124847742: length 9.5
  TOP w0.127: CN2.6 74.51,53.47 73.88,52.84 72.28,52.84 v2(72.13,52.68)
  BOTTOM w0.127: v2(72.13,52.68) 71.57,53.24 70.17,53.24 69.91,52.98 68.08,52.98 67.8,52.7 R449.1 67.07,52.7 66.91,52.86 v2(66.54,52.86)
N124847745: length 11.1
  TOP w0.127: CN2.9 74.04,54.97 73.53,54.46 v2(73.53,53.73)
  BOTTOM w0.127: v2(65.55,53.68) 67.39,53.68 R447.1 69.05,53.71 69.26,53.92 70.08,53.92 70.5,53.5 71.72,53.5 71.98,53.24 73.04,53.24 v2(73.53,53.73)
N124847750: length 9.3
  TOP w0.127: CN2.11 74.07,55.97 v1(72.47,54.37) 72.18,54.08 v2(72.18,53.9)
  BOTTOM w0.127: R441.1 75.71,56.46 75.71,56 74.43,54.72 72.99,54.72 v2(72.18,53.9)
N124847755: length 10.6
  TOP w0.127: v2(71.49,53.95) 71.9,54.36 v1(71.9,55.56) 71.9,56.54 72.11,56.75 74.08,56.75 74.31,56.97 CN2.13
  BOTTOM w0.127: v2(71.49,53.95) 70.4,53.95 70.19,54.17 69.41,54.17 68.85,54.73 R446.1
N124847822: length 10.7
  TOP w0.127: CN2.5 74.37,52.98 73.98,52.58 72.66,52.58 72.17,52.09 71.33,52.09 v2(71.11,51.87)
  BOTTOM w0.127: v2(71.11,51.87) 71.11,51.9 70.68,52.33 68.7,52.33 68.05,51.68 R450.1 67.15,51.68 66.78,52.05 v2(65.55,52.05)
N167749240: length 3.6
  TOP w0.127: v2(31.74,89.11) 31.74,89.34 TP11.1
  BOTTOM w0.127: v2(31.74,89.11) 31.88,88.97 32.03,88.97 32.48,88.52 32.48,87.61 U20.B51
N167821380: length 10.7
  BOTTOM w0.076: U20.AV2 62.49,66.07 62.99,66.07 63.24,65.82 63.24,65.66 63.39,65.51
  BOTTOM w0.127: 63.39,65.51 63.57,65.34 63.57,64.67 63.62,64.62 63.62,64.6 63.87,64.35 63.87,58.6 63.21,57.94 TP106.1
N1677602219: length 2.8
  TOP w0.127: TP12.1 30.85,89.77 31.17,89.45 31.17,89.02 31.72,88.47 v2(31.87,88.47)
  BOTTOM w0.127: U20.A51 32,87.78 32,88.35 v2(31.87,88.47)
N1677602244: length 5.1
  BOTTOM w0.076: 23.26,80.73 23.28,80.75 23.92,80.75 23.99,80.83 24.7,80.83 24.78,80.9 25.8,80.9 U20.L60
  BOTTOM w0.127: TP85.1 22.12,80.68 22.88,80.68 22.93,80.73 23.26,80.73

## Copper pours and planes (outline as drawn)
51216VBST on BOTTOM (solid shape): 15.16,20.43 15.16,20.12 15.44,19.84 16.5,19.84 16.64,19.7 16.64,19.14 16.53,19.03 15.36,19.03 15.34,19.04 14.96,19.04 14.81,19.19 14.81,19.75 14.44,20.12 14.44,20.43 14.52,20.5 15.08,20.5
+0.75V_DDR_VTT on BOTTOM (solid shape): 10.84,22.81 10.84,22.33 10.58,22.08 10.58,21.83 11.12,21.3 12.12,21.3 12.15,21.27 12.15,21.12 12.14,21.1 9.27,21.1 9.16,21.21 9.16,23.5 9.31,23.65 10,23.65
+0.75V_DDR_VTT on BOTTOM (solid shape): outline of 159 points within 68.27,25.13 72.56,39.05
+0.75V_DDR_VTT on IN1 (solid shape): outline of 1828 points within 3.6,11.13 72.38,27.67
+1.5V on TOP (solid shape): 69.98,15.85 69.98,14.98 70.1,14.86 70.1,14.71 69.97,14.58 68.7,14.58 68.57,14.71 68.57,15.73 68.83,15.98 69.84,15.98
+1.5V on TOP (solid shape): 119.9,78.36 119.9,77.6 119.75,77.45 118.36,77.45 118.05,77.75 118.05,79.02 118.21,79.18 118.86,79.18 118.86,79.19 119.07,79.19
+1.5V on TOP (solid shape): 130.14,96.09 130.14,87.41 129.76,87.03 128.9,87.03 128.77,87.15 128.77,89.01 128.9,89.13 128.9,96.12 129.02,96.25 129.99,96.25
+1.5V on TOP (solid shape): 219.19,113.26 219.19,112.37 218.81,111.99 217.16,111.99 216.91,112.25 216.91,112.74 217.38,113.09 217.79,113.52 218.94,113.52
+1.5V on TOP (solid shape): 263.62,111.26 263.64,111.26 263.64,109.45 263.87,109.23 264.89,109.23 264.96,109.15 264.96,108.11 264.74,107.88 262.15,107.88 261.97,108.06 261.97,111.1 262.2,111.33 263.54,111.33
+1.5V on TOP (solid shape): outline of 674 points within 44.06,66.15 47.49,74.45
+1.05V on BOTTOM (solid shape): 46.6,99.93 46.6,99.29 46.35,99.04 44.42,99.04 44.34,99.12 44.34,99.93 44.11,100.16 43.02,100.16 42.92,100.26 42.92,101.02 42.96,101.06 45.47,101.06
+1.5V on BOTTOM (solid shape): 264.91,109.1 264.91,108.77 264.74,108.59 264.2,108.59 264.05,108.44 264.05,107.75 264,107.7 263.01,107.7 262.98,107.73 262.98,108.74 263.11,108.87 263.64,108.87 263.92,109.15 264.86,109.15
+1.5V on BOTTOM (solid shape): 129.91,87.61 129.91,84.18 127.25,81.51 123.84,81.51 120.01,77.68 118.53,77.68 118.05,78.16 118.05,81.97 119.63,83.55 126.1,83.55 128.26,85.7 128.26,87.86 128.52,88.12 129.41,88.12
+1.05V on BOTTOM (solid shape): 59.05,95.18 59.05,93.68 58.82,93.45 58.82,90.61 58.77,90.56 57.95,90.56 57.75,90.76 57.75,91.09 57.68,91.17 56.53,91.17 56.33,91.37 56.33,91.72 56.76,92.16 57.22,92.16 57.75,92.69 57.75,95.2 57.85,95.31 58.92,95.31
+1.05V on BOTTOM (solid shape): 85.06,101.99 85.09,101.97 85.11,101.94 85.11,100.55 85.06,100.39 85.08,100.23 84.78,99.93 80,99.93 79.75,100.18 79.75,100.56 79.49,100.82 79.49,101.81 79.67,101.99
+1.05V on BOTTOM (solid shape): 15.97,75.95 17.01,75.95 17.14,75.82 17.14,74.58 17.04,74.48 17.04,74.07 17.26,73.84 17.82,73.84 17.9,73.77 17.9,73.39 17.83,73.32 17.09,73.32 16.78,73.63 16.77,73.63 16.69,73.7 16.63,73.7 15.08,75.25 15.08,76.46 15.46,76.46
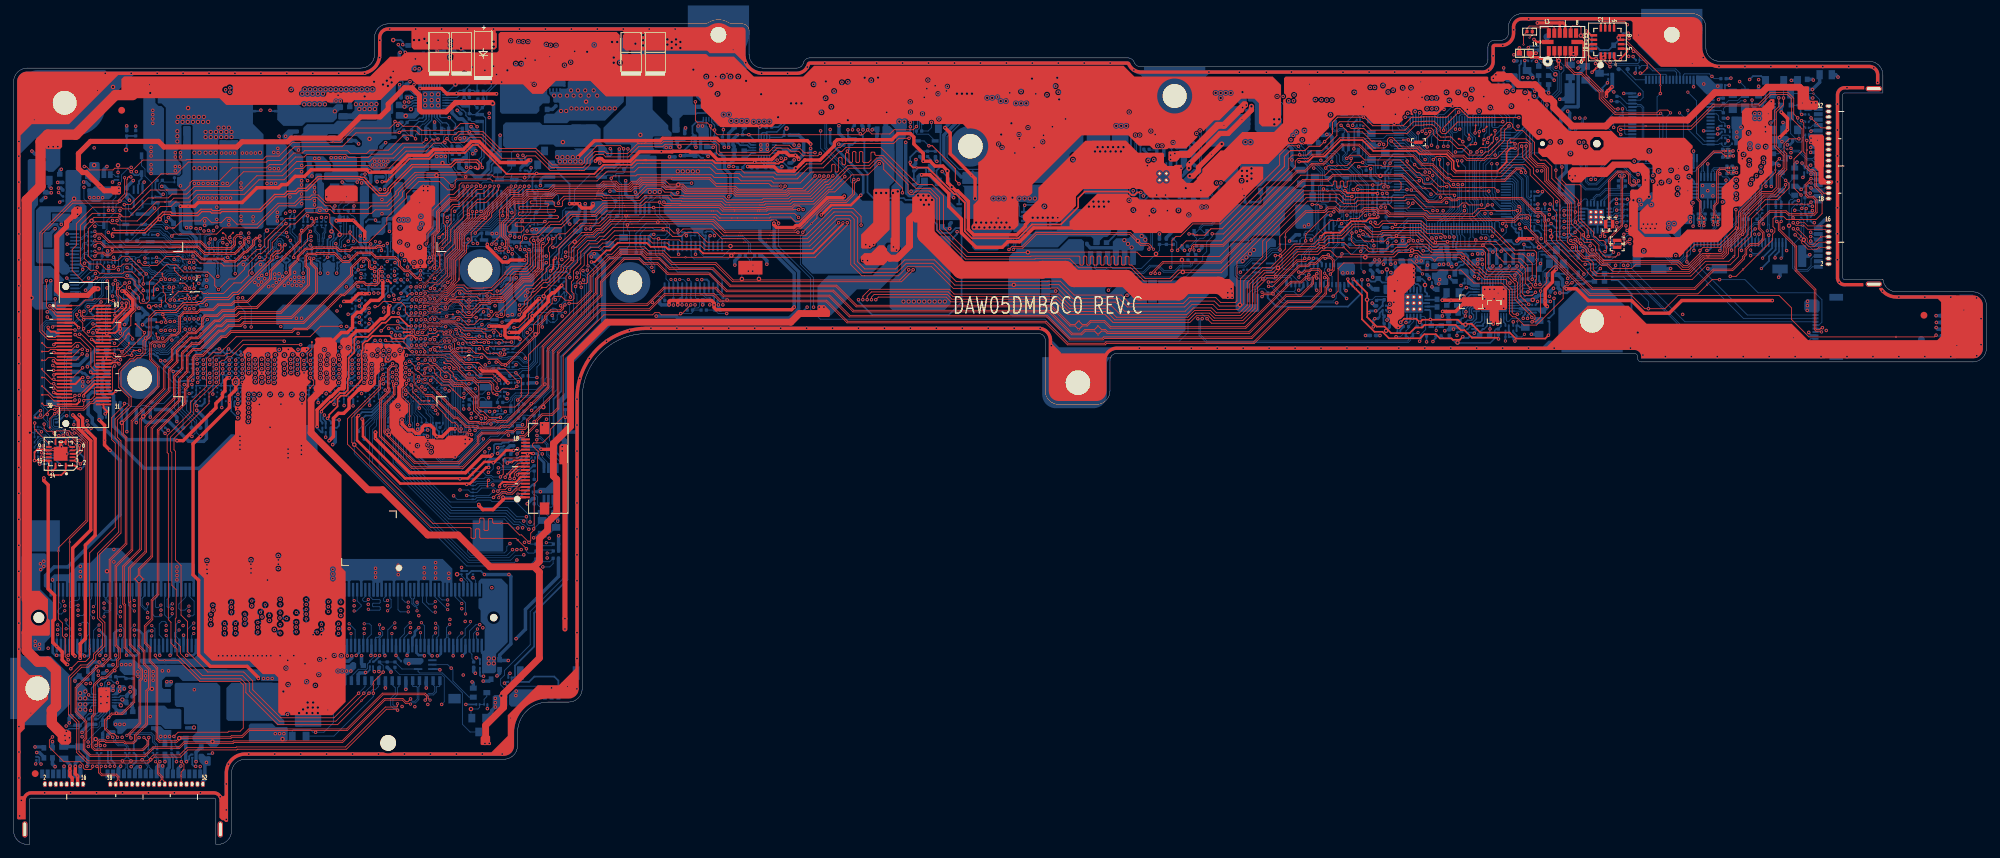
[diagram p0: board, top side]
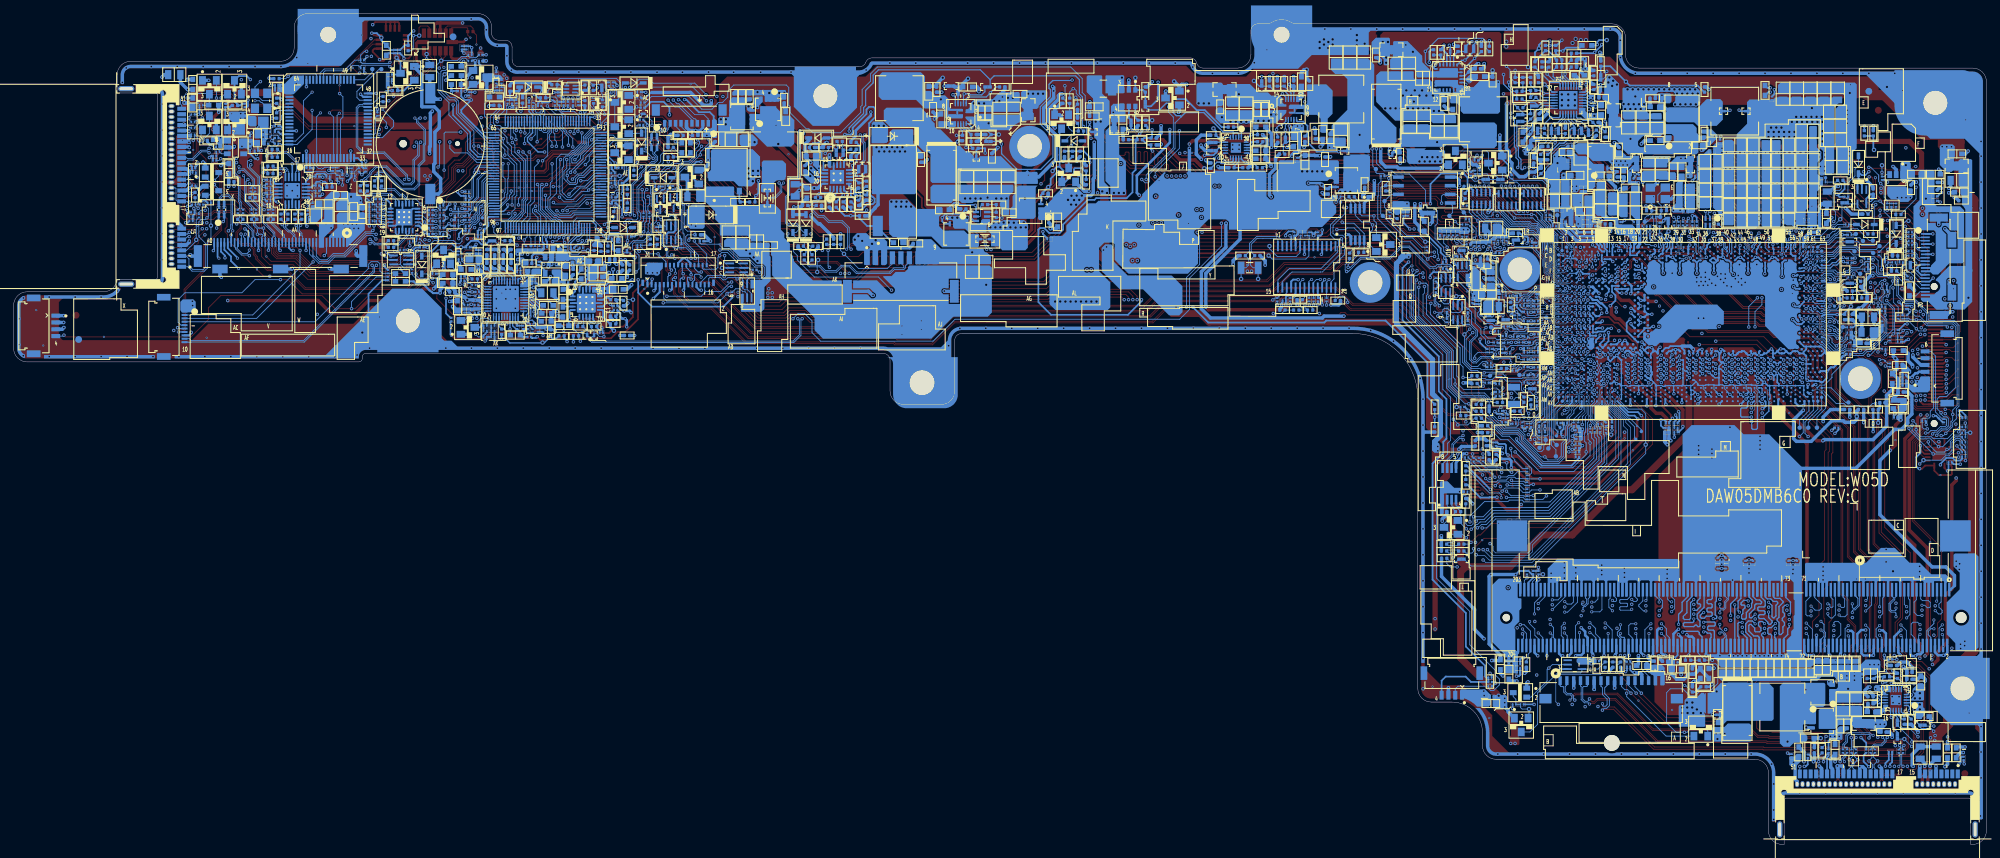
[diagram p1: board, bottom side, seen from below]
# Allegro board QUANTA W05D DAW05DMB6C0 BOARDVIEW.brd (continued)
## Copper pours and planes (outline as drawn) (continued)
+1.05V on BOTTOM (solid shape): 58.67,74.31 58.67,74.05 58.55,73.94 58.55,73.56 58.71,73.4 58.71,73.28 58.71,73.1 58.26,72.64 57.9,72.64 57.57,72.97 57.57,73.54 57.65,73.67 57.65,73.82 57.65,74.36 57.73,74.44 58.54,74.44
+1.5V on BOTTOM (solid shape): 132.12,112.76 132.12,110.47 131.18,109.53 131.18,105.16 131.03,105.01 131.03,103.84 130.62,103.43 130.62,96.47 130.14,95.99 130.14,95.51 129.99,95.36 129.02,95.36 128.9,95.48 128.9,96.63 129.53,97.26 129.53,105.01 128.77,105.77 128.77,109.2 129.84,110.27 129.84,112.83 129.94,112.93 131.95,112.93
+1.05V on BOTTOM (solid shape): 60.19,102.77 61.03,102.77 61.03,102.49 61.02,102.48 61.02,102.38 60.93,102.29 60.67,102.29 60.34,101.96 60.34,101.76 59.91,101.33 58.79,101.33 57.8,100.34 55.52,100.34 54.42,99.24 54.24,99.24 54.21,99.21 54.07,99.21 53.89,99.15 53.8,98.98 53.79,98.97 53.74,98.91 53.74,98.66 53.61,98.53 52.98,98.53 52.87,98.63 52.87,99.01 52.12,99.76 52.12,99.94 51.88,100.18 51.02,100.18 50.97,100.23 50.97,101.05 51.02,101.1 52.82,101.1 53.68,101.95 53.71,101.96 53.77,101.94 53.82,101.93 53.97,101.92 54.12,101.93 54.31,102.01 54.39,102.19 54.4,102.21 54.93,102.75 54.99,102.81 55.03,102.9 55.11,102.98 59.99,102.98
+1.5V on IN1 (solid shape): outline of 131 points within 129.2,105.69 133.42,110.01
+1.05V on IN1 (solid shape): outline of 287 points within 53.64,73.06 58.79,79.1
+1.5V on IN2 (solid shape): 69.97,15.85 69.97,15.01 70.1,14.88 70.1,14.71 69.97,14.58 68.39,14.58 68.06,14.91 68.06,15.55 68.49,15.98 69.84,15.98
+1.5V on IN2 (solid shape): outline of 501 points within 262.63,86.47 267.07,109.17
+1.05V on IN2 (solid shape): outline of 4898 points within 15.2,72.29 84.27,101.58
+1.05V_MODPHY on TOP (solid shape): outline of 653 points within 55.59,84.51 61.9,96.77
+1.05V_MODPHY on BOTTOM (solid shape): 61.64,101.94 61.64,101.12 61.43,100.92 61.26,100.92 61.03,100.69 61.03,99.01 60.9,98.89 60.57,98.89 60.32,98.63 60.32,97.77 60.44,97.64 60.95,97.64 61.08,97.52 61.08,95.86 60.95,95.74 60.19,95.74 59.81,96.12 59.81,96.25 59.8,96.26 57.79,96.26 57.42,96.63 57.42,97.57 57.22,97.77 56.13,97.77 56,97.9 56,98.77 56.15,98.92 56.15,99.84 56.23,99.93 57.65,99.93 58.79,101.07 59.96,101.07 60.57,101.68 60.57,101.81 60.81,102.05 61.52,102.05
+1.05V_MODPHY on IN1 (solid shape): 59.54,85.2 59.74,85.13 59.95,85.18 60.06,85.07 60.06,84.69 59.95,84.58 59.47,84.5 59.43,84.02 59.43,83.85 59.35,83.62 59.43,83.39 59.43,83.22 59.34,82.97 59.43,82.72 59.43,82.53 59.14,82.24 58.82,82.13 58.71,81.81 58.51,81.61 58.32,81.61 57.44,80.73 56.67,80.73 56.63,80.76 56.63,81.77 57.02,82.15 58.03,82.15 58.54,82.66 58.54,85.07 58.57,85.11 58.86,85.05 59.11,85.2
+1.05V_S2 on BOTTOM (solid shape): 77.67,105.64 81.87,105.64 81.95,105.73 85.58,105.73 86.2,105.11 86.2,103.13 87.12,102.21 87.19,101.89 87.44,101.69 87.44,101.5 87.42,101.48 86.78,101.48 86.61,101.3 85.95,101.3 85.87,101.38 85.87,102.37 85.79,102.44 79.6,102.44 79.27,102.77 77.23,102.77 76.67,102.21 72.28,102.21 71.87,102.62 71.87,103.61 71.9,103.64 71.9,103.84 71.89,103.91 71.87,103.99 71.87,105.64 72.26,106.02 77.28,106.02
+1.05VS5 on BOTTOM (solid shape): 20.08,75.37 20.08,74.2 20.06,74.17 19.75,74.17 19.58,74 19.58,73.41 19.68,73.31 19.68,73 19.66,72.99 19.21,72.99 18.86,73.34 18.2,73.34 18.15,73.39 18.15,74.15 18.41,74.4 18.94,74.4 19.04,74.5 19.04,74.61 19.17,74.73 19.4,74.73 19.6,74.94 19.6,75.37 19.65,75.42 20.03,75.42
+1.35VSUS on TOP (solid shape): outline of 4434 points within 27.11,18.97 48.76,73.04
+1.35VSUS on BOTTOM (solid shape): 60.19,27.16 60.19,26.78 59.81,26.4 57.52,26.4 57.27,26.65 57.27,27.18 57.45,27.36 59.99,27.36
+1.35VSUS on BOTTOM (solid shape): 42.61,21.49 43.98,21.49 44.32,21.16 44.32,20.55 44.42,20.45 45.03,20.45 45.18,20.3 45.18,17.35 45.1,17.28 41.39,17.28 41.29,17.38 41.29,19.08 41.42,19.21 41.42,22.26 41.85,22.26
+1.35VSUS on BOTTOM (solid shape): 12.13,20.88 12.13,20.71 12.13,20.7 11.17,20.7 10.79,20.32 10.79,19.28 10.28,18.78 10.28,18.52 10.15,18.39 9.64,18.39 9.06,18.98 9.06,19.92 9.29,20.15 9.29,20.83 9.36,20.9 10.53,20.9 10.53,20.9 11.76,20.9 11.77,20.9 12.11,20.9
+1.35VSUS on BOTTOM (solid shape): outline of 315 points within 18.53,26.04 44.62,61.57
+1.35VSUS on IN2 (solid shape): outline of 782 points within 9.26,13.47 45.05,22.08
+1.35VSUS_S on BOTTOM (solid shape): 40.43,22.28 40.76,22.28 40.76,19.79 40.63,19.66 39.54,19.66 39.29,19.41 39.29,18.67 39.3,18.66 39.73,18.23 39.74,18.22 39.74,18.2 39.74,17.58 39.67,17.51 38.73,17.51 38.09,18.14 31.49,18.14 31.23,18.39 31.23,22.97 32,23.73 38.98,23.73
+3.3VS5_S on BOTTOM (solid shape): 96.26,115.3 96.26,113.77 95.62,113.14 94.61,113.14 93.85,112.37 93.85,107.88 96.14,105.58 96.14,105 96.61,104.53 96.61,104.09 96.49,103.97 93.99,103.97 93.87,103.84 93.87,102.32 94.03,102.16 94.03,101.63 94.02,101.59 93.98,101.58 90.57,101.58 90.52,101.63 90.52,101.88 90.67,102.04 90.67,102.65 90.52,102.8 87.01,102.8 86.63,103.18 86.63,105.26 89.91,108.54 89.91,114.53 90.79,115.42 96.13,115.42
+3V on TOP (solid shape): outline of 180 points within 47.97,66.65 49.72,74.43
+3V on BOTTOM (solid shape): 28.19,12.93 28.82,12.93 28.95,12.81 28.95,11.66 28.82,11.54 27.88,11.54 27.3,12.12 27.3,12.43 27.17,12.55 27.17,13.19 27.3,13.31 27.81,13.31
+3V on BOTTOM (solid shape): 210.23,85.43 210.23,84.97 210.13,84.87 209.31,84.87 208.93,84.49 208.27,84.49 208.17,84.59 208.17,85.3 208.24,85.37 209.14,85.37 209.23,85.46 210.19,85.46
+3V on BOTTOM (solid shape): 249.88,111.71 250.92,111.71 250.97,111.66 250.97,110.55 250.87,110.44 250.13,110.44 249.87,110.18 248.55,110.18 248.55,110.17 247.09,111.63 247.1,111.63 247.1,112.9 247.11,112.91 248.68,112.91
+3V on BOTTOM (solid shape): 187.14,106.33 187.14,105.31 187.32,105.14 188.13,105.14 188.71,104.55 188.71,103.99 188.59,103.87 187.06,103.87 186.94,103.74 186.56,103.74 186.43,103.87 186.43,106.28 186.68,106.53 186.94,106.53
+3V on BOTTOM (solid shape): 80.48,90.56 80.48,89.92 80.38,89.82 77.51,89.82 77.44,89.74 77.44,89.74 77.34,89.64 76.13,89.64 75.79,89.98 75.79,90.28 76.17,90.66 80.38,90.66
+3V on BOTTOM (solid shape): 50.31,26.52 50.31,25.89 49.55,25.13 49.4,25.13 49.15,24.88 49.01,24.88 48.85,24.72 48.85,23.38 48.81,23.35 48.36,23.35 48.36,24.73 47.85,24.73 47.85,23.35 47.36,23.35 47.24,23.47 47.24,25.96 47.67,26.4 49.32,26.4 49.7,26.78 50.06,26.78
+3V on BOTTOM (solid shape): 14.47,96.63 14.51,96.61 14.52,96.58 14.52,95.24 14.08,94.8 14.08,94.77 14.06,94.74 14.03,94.72 13.07,94.72 12.69,94.34 11.49,94.34 10.83,95 10.83,96.26 10.91,96.35 11.57,96.35 11.85,96.63
+3V on BOTTOM (solid shape): 80.25,53.2 80.25,48.29 80.23,48.25 80.2,48.24 80.05,48.24 79.68,48.61 79.68,51.4 79.68,51.43 79.57,51.54 76.7,51.54 76.57,51.67 76.57,51.92 76.64,51.99 76.86,51.99 77.24,52.37 78.16,52.37 79.11,53.32 80.13,53.32
+3V on BOTTOM (solid shape): 253.81,106.84 253.81,105.44 253.99,105.26 254.02,105.26 254.22,105.26 254.32,105.16 254.32,103.79 254.2,103.66 253.38,103.66 253.22,103.5 253.22,102.79 253.08,102.65 252.72,102.65 252.67,102.7 252.67,103.28 252.37,103.59 252.37,105.03 252.27,105.13 252.27,105.3 252.26,105.3 252.26,106.84 252.28,106.87 252.32,106.89 253.76,106.89
+3V on BOTTOM (solid shape): 9.71,68.63 9.72,68.61 9.72,68.59 10,68.16 10.49,68.29 10.5,68.3 10.52,68.31 10.55,68.31 10.57,68.3 10.6,68.26 10.61,68.23 10.6,68.2 10.86,67.5 11.35,68.06 11.37,68.15 11.45,68.19 11.59,68.19 11.7,68.31 11.88,68.31 11.92,68.29 11.93,68.26 11.93,67.04 11.75,66.86 11.34,66.86 10.86,66.38 8.6,66.38 8.25,66.73 8.25,68.56 8.37,68.69 9.64,68.69
+3V on BOTTOM (solid shape): outline of 95 points within 1.16,28.43 5.83,42.73
+3V on BOTTOM (solid shape): 72.51,91.04 72.51,90.04 72.51,90.02 72.48,89.99 72.48,89.39 72.61,89.08 72.99,88.93 73.02,88.85 73.02,88.73 74.41,88.73 74.52,88.63 75,88.63 75.2,88.57 75.41,88.63 75.68,88.63 75.72,88.59 75.73,88.57 75.8,88.44 75.91,88.33 75.93,88.31 75.94,88.29 75.94,87.99 75.81,87.86 75.7,87.86 75.53,88.03 75.53,88.18 75.38,88.18 75.18,88.25 74.97,88.18 73.95,88.18 73.7,88.17 73.5,88.01 73.48,88 73.46,87.99 73.4,87.99 73.36,88.01 73.35,88.04 73.35,88.18 73.29,88.23 72.74,88.23 72.7,88.25 72.69,88.28 72.69,88.67 72.1,88.67 72.07,88.68 72.05,88.72 72.05,88.97 70.31,88.97 70.28,88.99 70.26,89.02 70.26,89.17 69.99,89.44 69.31,89.44 69.21,89.54 69.21,89.64 69.22,89.65 69.22,90.01 69.23,90.02 70.22,90.02 70.29,90.09 70.31,90.09 71.35,91.13 72.42,91.13
+3V on BOTTOM (solid shape): outline of 1008 points within 95.08,78.47 137.6,100.46
+3V on IN1 (solid shape): outline of 108 points within 2.15,21.7 13.07,30.21
+3V on IN1 (solid shape): outline of 611 points within 208.65,78.72 226.69,86.72
+3V on IN2 (solid shape): outline of 1205 points within 8.48,22.71 49.93,28.41
+3V on IN2 (solid shape): outline of 3059 points within 221.05,78.85 254.02,118.56
+3V on IN2 (solid shape): outline of 7045 points within 2.96,39.98 100.98,111.64
+3V on SVCC (solid shape): outline of 137 points within 128.39,65.62 229.99,104.88
+3V_AVDD on BOTTOM (solid shape): 213.45,76.61 213.45,76.15 212.97,75.67 211.78,75.67 211.55,75.44 210.58,75.44 210.3,75.16 210.18,75.16 210.1,75.24 210.1,75.37 210.63,75.9 210.63,76.13 210.79,76.28 211.35,76.28 211.37,76.31 211.62,76.31 211.65,76.28 212.69,76.28 213.1,76.69 213.38,76.69
+3V_AVDD on BOTTOM (solid shape): 210.69,84.31 210.69,83.8 210.43,83.55 210.43,83.22 210.69,82.96 210.69,82.28 210.56,82.15 208.78,82.15 208.65,82.28 208.65,82.66 208.53,82.78 208.53,82.89 208.27,83.14 208.27,83.9 208.35,83.98 208.96,83.98 209.42,84.43 210.56,84.43
+3V_AVDD on IN2 (solid shape): outline of 295 points within 207.03,74.53 220.59,83.42
+3V_AVDD_2 on BOTTOM (solid shape): 213.68,84.36 213.68,83.67 214.9,82.45 215.18,82.45 215.31,82.33 215.31,81.84 215.28,81.82 214.09,81.82 213.76,82.15 213.48,82.15 213.35,82.28 213.35,83.29 212.97,83.67 212.34,83.67 212.21,83.8 212.21,84.36 212.41,84.56 213.48,84.56
+3V_DEEP_SUS on BOTTOM (solid shape): 73.35,82.35 73.35,80.19 73.91,79.63 73.91,79.39 73.9,79.38 73.86,79.2 73.9,79.01 73.91,79 73.91,78.75 73.85,78.54 73.91,78.34 73.91,78.06 73.82,77.9 73.81,77.7 73.79,77.68 73.5,77.39 72.55,77.39 72.26,77.68 72.26,78.12 72.26,78.12 72.26,79.83 71.92,80.16 71.92,80.62 71.86,80.69 71.3,80.69 71.24,80.75 71.24,80.89 71.39,81.06 71.44,81.28 71.44,81.49 71.51,81.56 71.91,81.56 72.21,81.87 72.21,82.44 72.27,82.49 73.21,82.49
+3V_DEEP_SUS on IN2 (solid shape): outline of 263 points within 75.79,83.42 82.01,89.18
+3V_DEEP_SUS on IN2 (solid shape): outline of 2498 points within 51.9,59.3 73.78,79.33
+3V_DVDD on BOTTOM (solid shape): 225.49,79.15 225.49,78.8 225.04,78.34 225.04,77.96 224.15,77.96 223.74,78.36 222.62,78.36 222.5,78.24 222.34,78.24 222.19,78.39 221.18,78.39 220.97,78.59 220.97,78.72 221.15,78.9 222.19,78.9 222.24,78.85 224.6,78.85 224.99,79.23 225.42,79.23
+3V_RTC on BOTTOM (solid shape): 220.85,113.14 220.85,112.2 220.59,111.94 219.24,111.94 219.07,112.12 217.92,112.12 217.87,112.17 217.87,112.6 218.28,113.01 219.12,113.01 219.35,113.24 220.74,113.24
+3V_RTC on BOTTOM (solid shape): 60.22,61.57 60.22,61.26 60,61.04 60,60.51 59.86,60.37 59.86,59.34 59.81,59.29 59.35,59.29 59.24,59.4 59.24,60.57 59.14,60.67 59.14,61.18 59.18,61.23 59.21,61.24 59.22,61.23 59.37,61.22 59.52,61.26 59.53,61.27 59.58,61.27 59.68,61.37 59.68,61.5 59.81,61.63 60.16,61.63
+3V_RTC on IN2 (solid shape): outline of 320 points within 55.69,66.12 58.51,72.83
+3V_WLAN_P on TOP (solid shape): 265.87,103.99 265.87,99.55 265.8,99.48 265.8,97.9 266.18,97.52 267.07,97.52 267.2,97.39 267.2,97.13 266.95,96.88 265.3,96.88 265.04,97.13 265.04,98.85 264.47,99.42 264.47,102.41 264.03,102.85 263.77,102.85 263.64,102.98 263.64,103.1 263.75,103.21 263.75,103.61 263.64,103.71 263.64,103.99 263.9,104.25 265.61,104.25
+3V_WLAN_P on BOTTOM (solid shape): 258.13,107.52 258.13,106.61 257.55,106.02 255.59,106.02 255.01,105.44 254.09,105.44 254.04,105.49 254.04,106.81 254.2,106.96 255.01,106.96 255.64,107.6 258.06,107.6
+3V_WLAN_P on BOTTOM (solid shape): 263.8,104.35 265.65,104.35 265.65,103.71 264.33,103.71 264.28,103.66 264.28,103.54 264.3,103.51 265.63,103.51 265.65,103.48 265.65,102.95 265.63,102.93 264.2,102.93 264.13,102.85 263.75,102.85 263.69,102.9 263.69,103.15 263.75,103.21 263.75,103.51 263.69,103.56 263.69,103.69 263.52,103.87 263.52,104.37 263.54,104.4 263.75,104.4
+3V_WLAN_P on IN2 (solid shape): outline of 1429 points within 255.06,82.78 267.02,111.36
+3VLCD_CON on BOTTOM (solid shape): outline of 256 points within 3.27,83.67 10.71,99.04
+3VPCU on TOP (solid shape): 10.05,93.53 10.05,92.8 9.11,91.85 8.78,91.85 8.45,92.18 8.45,93.15 8.97,93.67 9.91,93.67
+3VPCU on BOTTOM (solid shape): 101.65,105.58 101.78,105.58 101.98,105.38 101.98,105.25 102.1,105.14 102.1,103.48 101.97,103.36 100.83,103.36 100.58,103.61 100.58,104.37 100.2,104.75 100.2,105.52 100.45,105.77 101.47,105.77
+3VPCU on BOTTOM (solid shape): 212.01,88.3 212.01,87.58 212.06,87.53 215.84,87.53 216.02,87.36 216.02,86.59 215.89,86.47 214.88,86.47 214.75,86.59 214.75,86.9 214.62,87.03 212.01,87.03 211.7,87.33 211.7,88.3 211.78,88.37 211.93,88.37
+3VPCU on IN1 (solid shape): 101.47,106.02 101.47,105.44 101.26,105.24 100.27,105.24 99.94,105.57 99.94,106.15 100.07,106.28 101.21,106.28
+3VPCU on IN1 (solid shape): 200.6,111.61 200.6,111.05 200.59,111.01 200.55,111 200.28,110.72 197.78,110.72 197.65,110.85 197.65,111.61 197.71,111.67 200.54,111.67
+3VPCU on IN2 (solid shape): 101.72,105.57 101.72,104.63 101.59,104.5 100.2,104.5 99.94,104.75 99.94,105.64 100.04,105.75 101.54,105.75
+3VPCU on IN2 (solid shape): outline of 180 points within 222.62,88.7 224.78,99.19
+3VPCU on SVCC (solid shape): 216.43,113.26 223.28,113.26 227.2,109.35 227.2,99.81 227.17,99.8 227.13,99.76 227.09,99.73 227.06,99.68 227.03,99.64 227.01,99.59 227,99.54 226.99,99.48 226.99,99.43 227,99.4 226.81,99.21 226.81,98.66 223.57,98.66 221.79,100.44 220.21,100.44 218.05,102.6 213.99,102.6 212.97,101.58 212.97,100.16 210.1,97.29 206.77,97.29 206.78,97.31 206.8,97.37 206.81,97.42 206.81,97.48 206.81,97.54 206.79,97.59 206.77,97.64 206.74,97.69 206.71,97.74 206.66,97.78 206.62,97.81 206.57,97.83 206.51,97.85 206.46,97.86 206.4,97.86 206.34,97.86 206.29,97.84 206.23,97.82 206.19,97.79 206.16,97.77 200.4,97.77 198.11,100.06 198.11,103.2 223.79,103.2 223.79,102.6 224.22,102.16 224.83,102.16 225.26,102.6 225.26,103.21 224.83,103.64 224.22,103.64 223.79,103.2 198.11,103.2 198.11,103.21 197.1,104.23 197.1,104.35 196.95,104.5 196.82,104.5 196.46,104.86 196.46,105.92 197.07,106.53 197.46,106.53 197.86,106.94 197.86,108.84 197.96,108.95 198.32,108.95 198.87,109.5 198.87,112.71 199.33,113.16 199.36,113.19 215.68,113.19 215.68,113.18 216.1,113.27
+3VS5 on TOP (solid shape): 128.64,96.22 128.64,90.28 125.85,87.48 124.6,87.48 124.45,87.64 124.45,89.54 126.23,91.32 126.23,96.09 126.43,96.3 128.57,96.3
+3VS5 on TOP (solid shape): outline of 670 points within 54.42,56.7 67.45,73.49
+3VS5 on TOP (solid shape): outline of 1273 points within 228.24,86.21 258.59,109.45
+3VS5 on BOTTOM (solid shape): 257.62,105.64 257.62,104.35 257.5,104.22 255.74,104.22 255.72,104.25 255.72,105.69 255.82,105.8 257.47,105.8
+3VS5 on BOTTOM (solid shape): 47.49,60.69 47.49,58.98 46.96,58.45 46.75,58.45 46.6,58.6 46.6,58.83 46.98,59.21 46.98,60.69 47.11,60.81 47.36,60.81
+3VS5 on BOTTOM (solid shape): 94.43,101.02 94.43,96.38 94.49,96.32 94.89,96.32 95.19,96.02 95.19,95.69 95.06,95.56 91.94,95.56 91.81,95.69 91.81,96.83 91.7,96.94 91.06,96.94 90.52,97.49 90.52,101.05 90.62,101.15 94.3,101.15
+3VS5 on BOTTOM (solid shape): 75.52,84.94 75.55,84.93 75.57,84.89 75.57,84.26 76.05,83.79 76.38,83.79 76.42,83.77 76.43,83.74 76.43,82.1 75.59,81.27 75.59,79.88 75.58,79.84 75.54,79.83 75.12,79.83 75.12,79.71 75.11,79.67 75.07,79.66 74.26,79.66 73.55,80.37 73.55,82.07 74.22,82.75 74.22,83.11 74.24,83.22 74.22,83.32 74.22,83.99 75.18,84.94
+3VS5 on BOTTOM (solid shape): 129.37,104.77 129.37,97.4 128.64,96.68 128.64,95.53 128.44,95.33 126.51,95.33 126.36,95.48 126.36,99.97 126.74,99.97 126.74,99.91 126.76,99.86 126.78,99.8 126.81,99.76 126.84,99.71 126.89,99.68 126.93,99.65 126.98,99.62 127.04,99.61 127.09,99.6 127.15,99.6 127.2,99.61 127.26,99.62 127.31,99.65 127.35,99.68 127.39,99.71 127.43,99.76 127.46,99.8 127.48,99.86 127.5,99.91 127.5,99.97 127.5,100.02 127.49,100.08 127.47,100.13 127.45,100.18 127.41,100.22 127.37,100.26 127.33,100.3 127.28,100.33 127.23,100.35 127.17,100.36 127.12,100.36 127.06,100.36 127.01,100.35 126.96,100.33 126.91,100.3 126.86,100.26 126.83,100.22 126.79,100.18 126.77,100.13 126.75,100.08 126.74,100.02 126.74,99.97 126.36,99.97 126.36,100.32 127.34,101.3 127.34,104.22 127.58,104.45 127.58,105.39 127.7,105.52 128.62,105.52
+3VS5 on IN2 (solid shape): outline of 216 points within 91.91,87.55 126.61,96.12
+3VS5 on IN2 (solid shape): outline of 318 points within 225.26,89.62 229.71,100.23
+3VS5 on IN2 (solid shape): outline of 1061 points within 65.27,56.75 76.79,81.89
+3VSPI on BOTTOM (solid shape): 87.24,92.94 86.73,92.44 86.33,92.44 86.1,92.66 84.78,92.66 84.68,92.77 84.68,94.25 84.85,94.43 87.24,94.43
+5V on TOP (solid shape): 135.27,94.67 135.27,91.32 132.3,91.32 131.95,91.67 131.95,94.98 132.07,95.1 132.21,95.1 132.69,95.59 134.35,95.59
+5V on TOP (solid shape): 179.19,82.4 179.19,80.24 179.06,80.12 177.54,80.12 176.78,80.88 176.78,82.4 177.41,83.04 178.55,83.04
+5V on TOP (solid shape): 81.45,58.6 81.45,56.06 81.2,55.81 80.18,55.81 80.13,55.86 80.13,58.53 80.38,58.78 81.27,58.78
+5V on TOP (solid shape): 128.26,87.48 128.26,85.58 127.73,85.04 125.16,85.04 124.4,85.8 124.4,86.31 124.91,86.82 125.9,86.82 127.07,87.99 127.75,87.99
+5V on BOTTOM (solid shape): 223.33,86.87 223.33,85.5 223.28,85.45 222.24,85.45 222.17,85.53 222.17,86.82 222.27,86.92 223.28,86.92
+5V on BOTTOM (solid shape): 81.41,59.25 81.41,57.85 81.07,57.51 80.54,57.51 80.31,57.74 80.31,58.81 80.64,59.14 80.64,59.8 80.75,59.91
+5V on BOTTOM (solid shape): 86.4,86.29 86.4,85.53 85.84,85.53 85.34,86.04 84.73,86.04 84.45,86.31 84.45,86.59 84.83,86.97 85.72,86.97
+5V on BOTTOM (solid shape): 215.92,86.01 215.92,85.68 215.86,85.62 215.43,85.62 215.28,85.48 215.28,85.12 215.16,84.99 214.16,84.99 214.09,85.07 214.09,85.83 214.11,85.83 214.24,85.96 214.62,85.96 214.88,86.21 215.71,86.21
+5V on BOTTOM (solid shape): 244.09,94.85 244.09,91.93 244.87,91.14 244.87,87.63 244.85,87.61 244.21,87.61 244.13,87.7 244.13,89.09 242.69,90.53 242.69,94.21 241.8,95.1 241.8,95.61 242.05,95.86 243.07,95.86
+5V on BOTTOM (solid shape): 260.72,103.76 260.72,103.15 260.7,103.13 260.06,103.13 259.66,102.72 259.66,102.32 259.55,102.21 259.12,102.21 259.07,102.27 259.07,102.85 259,102.93 257.8,102.93 257.78,102.95 257.78,103.89 257.93,104.04 260.44,104.04
+5V on BOTTOM (solid shape): 137.16,94.96 137.16,94.79 138.42,93.53 139.21,93.53 139.23,93.5 139.23,91.83 139.08,91.67 135.5,91.67 132.45,94.72 132.45,95.36 133.57,96.47 135.65,96.47
+5V on BOTTOM (solid shape): 77.28,22.64 77.28,21.62 77.28,21.62 76.89,21.52 76.5,21.38 75.85,21.06 75.25,20.67 74.81,20.22 73.07,20.22 72.75,20.54 72.75,21.91 73.6,22.76 77.16,22.76
+5V on BOTTOM (solid shape): 209.92,87.74 209.92,86.91 210.12,86.71 210.12,85.69 210.05,85.62 208.2,85.62 207.98,85.85 207.36,85.85 207.21,85.7 207.21,85.21 207.17,85.17 204.92,85.17 204.72,85.37 204.72,85.96 204.82,86.06 205.45,86.06 205.73,86.34 205.73,86.42 205.85,86.53 206.27,86.47 208.04,86.47 208.49,86.92 208.49,87.27 208.61,87.39 209.05,87.39 209.47,87.81 209.85,87.81
+5V on IN2 (solid shape): 125.87,85.86 125.87,85.35 125.62,85.1 124.6,85.1 124.35,85.35 124.35,85.98 124.48,86.11 125.62,86.11
+5V on IN2 (solid shape): 86.31,87.07 86.3,87.07 86.3,86.9 85.36,85.96 84.68,85.96 84.52,86.11 84.52,86.65 85.02,87.15 86.23,87.15
+5V on IN2 (solid shape): 75.1,22.89 75.1,21.77 74.8,21.47 73.55,21.47 73.4,21.62 73.4,22.64 73.49,22.73 73.73,22.73 74.15,23.14 74.85,23.14
+5V on IN2 (solid shape): outline of 1158 points within 204.79,83.67 244.72,92.05
+5V on SVCC (solid shape): 255.34,105.72 257.74,105.72 258.06,105.55 258.37,105.72 258.49,105.72 260.06,104.15 260.06,103.08 259.38,102.39 258.16,102.39 257.62,101.86 253.92,101.86 253.08,102.7 248.96,102.7 247.29,101.02 247.29,99.95 247.06,99.73 247.06,98.33 246.45,97.72 245.36,97.72 244.82,97.19 244.82,90.12 244.49,89.79 242.36,89.79 242.08,90.07 242.08,94.14 239.51,96.7 239.51,99.8 239.84,100.13 243.71,100.13 244.57,101 244.57,102.6 247.69,105.72 252.24,105.72 253.03,106.51 254.55,106.51
+5V on SVCC (solid shape): 195.45,90.04 195.45,90.02 196.72,88.75 198.34,88.75 198.85,89.26 204.74,89.26 205.19,88.81 205.27,88.37 205.71,88.29 206.64,87.36 206.6,87.09 206.75,86.86 206.75,85.45 205.08,85.45 204.97,85.56 204.97,85.94 204.44,86.47 203.21,86.47 202.96,86.21 202.32,86.21 201.67,85.56 201.67,85.31 201.31,84.94 198.85,84.94 197.96,85.83 194.58,85.83 194.05,85.3 194.05,84.33 194.3,84.08 194.3,82.89 194.18,82.76 194.18,80.39 196.08,78.49 196.08,75.7 196.61,75.16 199.03,75.16 200.68,73.51 200.68,73.15 200.65,73.12 177.91,73.12 177.41,73.62 177.41,80.9 179.93,83.42 186.28,83.42 187.19,84.33 187.19,86.36 190.09,89.26 193.52,89.26 194.41,90.15 195.34,90.15
+5V_AMP on TOP (solid shape): 205.78,84.87 205.78,84.56 205.76,84.54 205.76,82.35 204.23,80.83 204.23,80.49 204.22,80.38 204.23,80.28 204.23,79.59 204.22,79.48 204.23,79.38 204.23,78.69 204.22,78.58 204.23,78.48 204.23,77.65 203.7,77.12 203.68,77.12 203.31,76.51 204.02,76.39 204.02,76.4 204.06,76.42 204.1,76.4 204.13,76.37 204.14,76.33 204.12,76.3 203.55,75.72 202.94,75.72 201.98,76.69 202.01,76.72 202.08,77.16 201.74,77.43 201.69,77.44 201.69,77.8 201.75,77.89 201.85,77.89 202.43,78.21 201.85,78.54 201.75,78.53 201.69,78.62 201.69,78.94 201.75,79.03 201.85,79.02 202.46,79.33 201.85,79.64 201.75,79.63 201.69,79.72 201.69,83.19 202.08,83.58 202.11,83.57 202.56,83.67 202.66,84.12 202.65,84.15 203.8,85.3 205.35,85.3
+5V_AMP on BOTTOM (solid shape): 204.36,85.88 204.36,85.4 204.88,84.88 205.6,84.88 205.68,84.84 205.7,84.74 205.67,84.63 205.66,84.51 205.66,84.05 205.82,83.89 205.83,83.87 205.83,83.85 205.83,83.67 205.83,83.65 205.81,83.62 205.81,83.11 205.55,82.86 205.17,82.86 205.15,82.89 204.61,82.89 204.56,82.84 204.26,82.84 203.78,83.32 203.78,84.92 203.37,85.32 203.37,86.06 203.4,86.09 204.16,86.09
+5V_PVDD on BOTTOM (solid shape): 222.01,86.9 222.01,86.52 221.86,86.37 221.86,85.45 221.73,85.32 221.73,84.49 220.59,83.34 220.29,83.34 220.18,83.44 220.18,83.72 221.18,84.71 221.18,85.3 220.92,85.55 220.92,86.87 220.97,86.92 221.99,86.92
+5V_PVDD on IN2 (solid shape): 220.85,83.9 220.85,83.16 220.69,83.01 216.1,83.01 215.78,82.7 215.63,82.7 215.61,82.68 215.08,82.68 214.8,82.96 214.8,83.05 214.82,83.08 214.94,83.29 214.93,83.53 214.93,83.54 214.93,83.67 215.36,84.1 220.64,84.1
+5VPCU on BOTTOM (solid shape): 235.04,113.21 235.04,111.05 234.97,110.98 234.94,110.98 234.92,111 234.54,111 234.41,111.13 234.41,111.44 234.48,111.51 234.48,113.29 234.51,113.31 234.94,113.31
+5VPCU on IN1 (solid shape): 70.27,107.57 70.27,106.33 69.99,106.05 69.03,106.05 68.85,106.23 68.85,107.27 69.18,107.6 70.25,107.6
+5VPCU on IN1 (solid shape): outline of 92 points within 56.28,102.6 59.12,104.78
+5VPCU on IN2 (solid shape): 70.1,107.55 70.1,106.53 69.84,106.28 68.95,106.28 68.83,106.41 68.83,107.29 69.21,107.68 69.97,107.68
+5VS5 on BOTTOM (solid shape): 142.61,96.5 142.61,95.61 142.99,95.23 142.99,93.71 143.38,93.32 143.38,92.05 143.2,91.88 139.87,91.88 139.62,92.13 139.62,95.38 139.6,95.4 139.6,96.5 139.72,96.61 142.5,96.61
+5VS5_S on BOTTOM (solid shape): 161.92,107.8 161.92,106.28 160.9,105.26 157.22,105.26 157.09,105.14 157.09,102.83 155.96,101.7 155.43,101.7 155.06,101.33 155.06,97.39 154.81,97.13 142.87,97.13 142.74,97.01 139.41,97.01 139.31,97.1 139.31,98.61 139.47,98.77 139.86,98.77 140.54,98.71 141.22,98.78 142.43,98.78 144.72,101.07 147.77,101.07 148.05,100.79 148.58,100.79 148.68,100.89 148.68,101.05 149.45,101.81 149.95,101.81 150.74,102.6 151.17,102.6 153.59,105.01 154.04,105.01 154.42,105.39 154.42,105.87 154.92,106.36 154.92,106.65 156.46,108.18 161.54,108.18
+V1.05S_APLLOPI on BOTTOM (solid shape): 45.29,98.42 45.29,97.35 45.59,97.06 45.59,95.31 45.53,95.1 45.59,94.9 45.59,94.16 46.22,93.53 46.22,92.99 45.99,92.77 44.37,92.77 44.32,92.82 44.32,93.3 44.62,93.61 44.62,96.95 44.57,97.01 44.57,97.39 44.32,97.64 44.32,97.95 44.32,98.45 44.4,98.53 45.18,98.53
+V1.05S_ASATA3PLL on BOTTOM (solid shape): 62.45,98.43 62.45,93.81 62.58,93.68 62.58,92.72 62.53,92.66 62.53,92.08 62.62,91.99 62.62,90.82 62.58,90.78 62.2,90.78 62.12,90.86 62.12,91.78 61.64,92.26 60.77,92.26 60.65,92.39 60.65,93.27 61.21,93.83 61.21,97.64 61.07,97.78 60.71,97.78 60.6,97.9 60.6,98.51 60.75,98.66 62.22,98.66
+V1.05S_AUSB3PLL on BOTTOM (solid shape): 57.24,97.13 57.24,96.14 57.45,95.94 57.45,92.61 57.14,92.31 56.63,92.31 55.92,91.6 54.91,91.6 54.6,91.29 54.6,91.06 54.59,91.05 54.59,89.88 54.21,89.5 53.22,89.5 53.1,89.39 52.7,89.39 52.39,89.08 52.39,88.85 51.88,88.35 51.88,87.41 52.09,87.2 52.09,87.03 52.01,86.95 51.76,86.95 51.6,87.1 51.6,87.91 51.3,88.22 51.3,89.72 51.6,90.02 51.6,90.63 52.01,91.04 53.97,91.04 54.02,91.09 54.02,91.93 54.25,92.16 55.44,92.16 55.82,92.54 55.82,97.16 55.95,97.29 57.09,97.29
+V1.05S_AXCK_DCB on BOTTOM (solid shape): 50.64,98.63 50.64,98.09 50.69,98.04 51.21,98.04 51.35,97.9 51.35,97.67 51.26,97.58 50.93,97.58 50.79,97.44 50.72,97.36 50.72,97.13 50.56,96.98 50.36,96.98 50.11,97.24 48.89,97.24 48.56,97.57 48.27,97.69 47.97,97.59 45.66,97.59 45.59,97.67 45.59,98.56 45.74,98.71 46.68,98.71 46.93,98.96 50.31,98.96
+V1.05S_AXCK_LCPLL on BOTTOM (solid shape): 52.19,96.63 52.19,92.46 51.43,91.7 51.43,90.15 51.17,89.9 51.17,88.12 51.43,87.86 51.43,87.53 51.38,87.48 51.05,87.48 50.87,87.66 50.87,87.86 50.67,88.07 50.67,90.33 50.87,90.53 50.87,91.33 50.85,91.35 50.84,91.37 50.84,96.55 51.05,96.75 52.06,96.75
+V1.05S_SSCF100 on BOTTOM (solid shape): 52.6,99.04 52.6,98.51 52.7,98.4 52.7,97.13 52.44,96.88 50.94,96.88 50.84,96.98 50.84,97.24 51.01,97.4 51.54,97.4 51.55,97.39 52.06,97.39 52.19,97.52 52.19,98.02 52.01,98.2 52.01,98.61 51.78,98.84 51.02,98.84 50.94,98.91 50.94,99.7 51,99.75 51.88,99.75
+V1.05S_SSCFF on BOTTOM (solid shape): 44.06,99.6 44.06,97.95 43.93,97.82 43.32,97.82 43.15,98 43.15,98.43 43.05,98.53 43.05,99.67 43.08,99.71 43.95,99.71
+V1.05S_VCCST on TOP (solid shape): 15.77,96.53 15.77,95.64 15.54,95.41 14.57,95.41 14.27,95.71 14.27,96.58 14.34,96.65 15.64,96.65
+V1.05S_VCCST on BOTTOM (solid shape): outline of 138 points within 38.55,73.17 50.41,79.28
+V1.05S_VCCST on IN1 (solid shape): 16.81,92.46 16.81,91.39 16.64,91.23 14.31,91.23 14.19,91.34 14.19,92.51 14.34,92.66 16.6,92.66
+V1.05S_VCCST on IN2 (solid shape): outline of 260 points within 14.11,83.28 16.83,96.73
+V3.3DX_1.5DX_ADO on IN2 (solid shape): outline of 270 points within 52.82,65.41 54.97,71.38
+VCC_CORE on BOTTOM (solid shape): 41.5,101.4 42.13,101.4 42.54,101 42.54,98.54 42.51,98.51 42.5,98.51 42.5,97.71 42.54,97.67 42.54,93.71 42.26,93.43 41.42,93.43 41.41,93.43 41.24,93.46 41.07,93.43 41.06,93.43 40.78,93.43 40.77,93.43 40.63,93.46 40.48,93.45 40.46,93.46 40.44,93.47 40.33,93.58 40.33,101.33 40.38,101.38 40.38,101.96 40.51,102.09 40.81,102.09
+VCC_CORE on BOTTOM (solid shape): 31.28,109.4 31.97,109.4 32.09,109.4 32.09,109.4 34.77,109.4 35.15,109.02 35.15,108.07 35.12,108.04 35.1,108.04 35.1,107.31 35.12,107.31 35.15,107.28 35.15,105.82 36.7,104.27 36.7,90.66 36.44,90.4 33.9,90.4 33.19,91.11 33.19,103.46 33.11,103.54 33.09,103.54 33.04,103.59 30.22,103.59 30.21,103.57 30.08,103.57 30.08,103.45 30.04,103.41 30.04,91.17 29.91,91.04 29.46,91.04 29.33,90.91 28.57,90.91 28.29,90.63 27.91,90.63 27.63,90.91 27.57,90.91 27.46,90.93 27.36,90.93 27.28,90.93 27.19,90.92 26.65,90.92 26.54,91.04 26.54,93.12 26.28,93.38 26.28,105.52 26.15,105.64 24.76,105.64 24.63,105.52 24.63,105.29 24.66,105.26 24.66,102.47 23.99,101.81 23.99,100.59 24.6,99.98 24.6,98.51 24.38,98.28 22.73,98.28 22.34,98.66 22.34,108.18 21.71,108.82 21.2,108.82 21.2,109.58 21.33,109.71 30.98,109.71
+VCC_CORE on BOTTOM (solid shape): outline of 1189 points within 27.3,72.72 50.29,85.92
+VCC_CORE on IN1 (solid shape): outline of 2194 points within 22.98,81.64 44.06,107.42
+VCC_CORE on IN2 (solid shape): outline of 3109 points within 23.44,80.72 46.35,107.17
+VCC_TS on BOTTOM (solid shape): 265.22,79.69 265.22,78.42 264.94,78.14 263.34,78.14 262.96,78.52 262.96,79.69 263.31,80.04 264.86,80.04
+VCC_TS on BOTTOM (solid shape): 256.66,102.32 256.53,102.19 255.95,102.19 255.92,102.21 255.52,102.21 255.24,101.94 254.83,101.94 254.8,101.96 254.8,102.39 254.58,102.62 253.53,102.62 253.53,103.38 253.59,103.43 254.5,103.43 254.68,103.61 256.66,103.61
+VCC_TS on IN2 (solid shape): outline of 1118 points within 252.67,78.08 264,103.17
+VIN on TOP (solid shape): 7.13,104.65 7.13,102.42 6.82,102.11 4.84,102.11 4.46,102.49 4.46,104.6 4.79,104.93 6.85,104.93
+VIN on TOP (solid shape): 6.37,18.06 7.69,16.74 8.17,16.74 8.45,16.46 8.45,14.99 8.09,14.64 7,14.64 6.47,15.17 6.47,15.75 4.87,17.35 4.87,19.08 5.17,19.39 6.37,19.39
+VIN on TOP (solid shape): outline of 89 points within 1.26,30.64 5.33,37.24
+VIN on TOP (solid shape): outline of 4757 points within 15.82,90.28 186.12,119.31
+VIN on BOTTOM (solid shape): 6.85,102.52 6.85,99.78 5.83,98.76 5.1,98.76 4.77,99.09 4.77,100.74 4.64,100.87 4.64,102.49 4.95,102.8 6.57,102.8
+VIN on BOTTOM (solid shape): 141.72,110.47 141.72,108.31 141.42,108.01 139.41,108.01 139.18,108.23 139.18,108.41 137.89,109.71 137.89,110.55 138.07,110.72 141.47,110.72
+VIN on BOTTOM (solid shape): 115.99,111.64 115.99,108.77 115.61,108.39 112.31,108.39 112.11,108.59 112.11,109.62 112.11,109.62 112.11,111.32 112.11,111.32 112.11,111.64 112.34,111.87 115.77,111.87
+VIN on BOTTOM (solid shape): 90.29,117.84 90.29,116.17 90.16,116.04 89.27,116.04 88.51,115.28 88.51,114.53 88.38,114.41 87.88,114.41 87.75,114.53 87.75,115.55 87.58,115.72 87.58,118.31 87.75,118.47 89.65,118.47
+VIN on BOTTOM (solid shape): 144.41,91.58 144.84,91.58 144.94,91.67 145.79,91.67 146.68,90.78 146.68,90.15 146.17,89.64 146.17,87.86 146.14,87.84 145.1,87.84 144.49,87.23 141.14,87.23 140.76,87.61 140.76,91.09 141.34,91.67 144.31,91.67
+VIN on BOTTOM (solid shape): 17.77,18.27 17.77,17.12 17.65,17 17.01,17 17,16.99 16.67,16.99 15.92,16.24 15.36,16.24 15.23,16.36 15.23,16.87 14.6,17.51 14.6,18.01 14.98,18.39 17.65,18.39
+VIN on BOTTOM (solid shape): 55.67,112.76 55.67,112.63 56.13,112.17 56.13,110.27 56.38,110.01 56.38,109.4 56.27,109.29 56.13,109.29 55.75,108.91 55.75,107.4 55.62,107.27 54.04,107.27 53.94,107.37 53.94,111.71 55.19,112.96 55.47,112.96
+VIN on BOTTOM (solid shape): 184.62,109.23 184.62,106.91 184.75,106.79 186.05,106.79 186.24,106.6 186.24,102.91 185.79,102.47 183.46,102.47 183.28,102.65 183.28,104.35 183.15,104.48 182.72,104.48 182.26,104.93 182.26,108.21 182.25,108.22 182.25,108.73 181.91,109.07 181.4,109.07 181.25,109.23 181.25,109.61 181.35,109.71 184.14,109.71
+VIN on IN1 (solid shape): 16.5,18.9 16.5,17.15 16.25,16.9 9.92,16.9 9.54,16.52 9.54,15.07 8.58,14.1 7.51,14.1 7.21,14.41 7.21,16.26 10.03,19.08 16.32,19.08
+VIN_1.05V on BOTTOM (solid shape): 87.11,117.84 87.11,117.33 87.11,117.32 87.16,117.26 87.16,115.63 87.56,115.23 87.56,113.99 87.34,113.77 84.07,113.77 83.69,113.39 83.69,112.78 83.53,112.63 77.69,112.63 77.61,112.71 77.61,113.21 77.54,113.29 77.44,113.29 77.44,113.3 76.94,113.3 76.93,113.31 76.93,113.4 76.94,113.44 76.98,113.45 77.44,113.45 77.44,113.46 77.47,113.49 77.59,113.49 77.61,113.52 77.61,113.87 77.72,113.98 80.21,113.98 80.26,113.92 80.26,113.57 80.31,113.52 81.48,113.52 82.83,114.88 82.83,115.51 82.85,115.52 82.85,115.8 85.01,117.96 86.99,117.96
+VIN_3VS5 on BOTTOM (solid shape): 111.57,111.56 111.57,108.54 111.37,108.34 107.61,108.34 107.33,108.06 104.44,108.06 104.08,108.41 102.84,108.41 102.81,108.44 102.81,108.64 102.86,108.69 103.12,108.69 103.37,108.95 103.37,109.58 103.75,109.96 105.02,109.96 105.5,110.44 106.93,110.44 108.15,111.66 111.47,111.66
+VIN_5VS5 on BOTTOM (solid shape): 142.11,107.17 146.04,107.17 146.17,107.29 148.23,107.29 148.66,106.86 149.85,106.86 149.9,106.81 149.9,106.61 149.06,105.77 148.84,105.77 148.46,105.39 148.46,105.26 148.19,105 146.6,105 146.49,104.88 143.49,104.88 141.95,106.05 140.03,106.31 139.9,106.44 139.9,107.37 140.14,107.61 141.66,107.61
+VIN_BLIGHT on BOTTOM (solid shape): 4.11,100.39 4.11,96.78 3.83,96.5 3.83,95.51 3.57,95.26 3.57,93.88 3.17,93.48 2.41,93.48 2.07,93.81 2.07,100.46 2.25,100.64 3.85,100.64
+VIN_BLIGHT on BOTTOM (solid shape): outline of 198 points within 2.07,78.53 9.63,84.94
+VIN_DDR on BOTTOM (solid shape): 22.62,19.92 24.43,19.92 24.63,19.72 24.63,17.02 24.58,16.97 22.19,16.97 21.63,17.53 19.83,17.53 19.41,17.11 18.33,17.11 18.26,17.18 18.26,18.61 18.25,18.61 18.25,20.17 18.46,20.38 22.17,20.38
+VIN_VCC_CORE on BOTTOM (solid shape): 55.52,106.66 55.52,105.03 55.49,105.01 55.49,103.69 55.24,103.43 54.35,103.43 53.51,102.6 53.51,102.21 52.62,101.33 42.59,101.33 42.28,101.63 42.28,103.15 42.03,103.41 41.39,103.41 41.14,103.66 41.14,104.02 45.92,104.02 45.92,103.31 46.5,102.72 50.03,102.72 50.36,102.39 50.87,102.39 51.15,102.67 51.15,103.28 50.41,104.02 47.85,104.02 47.54,104.32 46.22,104.32 45.92,104.02 41.14,104.02 41.14,104.04 41.22,104.12 42.16,104.12 42.54,104.5 42.54,105.21 43.1,105.77 47.01,105.77 47.52,106.28 53.26,106.28 53.84,106.86 55.31,106.86
AGND on BOTTOM (solid shape): 207,80.75 207,78.21 206.88,78.08 204.34,78.08 204.21,78.21 204.21,80.75 204.34,80.88 206.88,80.88
AGND on BOTTOM (solid shape): 196.99,85.1 196.99,83.8 196.95,83.72 196.87,83.7 196.58,83.72 196.32,83.61 196.29,83.6 196.26,83.61 195.85,83.69 195.47,83.52 195.06,83.52 194.76,83.83 194.76,84.18 194.38,84.56 194.38,85.4 194.4,85.43 196.66,85.43
AGND on SGND (solid shape): 204.46,85.73 204.46,85.35 204.87,84.94 206.64,84.94 206.75,84.84 206.75,84.33 207.15,83.93 209.01,83.93 209.52,84.44 210.58,84.44 210.81,84.2 210.81,83.82 211.21,83.42 212.08,83.42 212.08,82.66 211.5,82.07 210,82.07 209.16,81.24 209.16,78.11 209.56,77.7 209.94,77.7 210.05,77.6 210.05,76.46 210.45,76.05 212.57,76.05 213.2,76.69 213.76,76.69 214.37,77.3 214.37,78.39 214.44,78.47 215.13,78.47 215.13,78.36 215.66,77.83 218.58,77.83 218.69,77.73 218.69,77.09 219.09,76.69 219.81,76.69 220.06,76.94 220.36,76.94 221.12,76.18 222.64,76.18 223.41,75.42 225.57,75.42 225.77,75.21 225.77,74.58 224.88,73.69 201.21,73.69 199.23,75.67 196.82,75.67 196.59,75.9 196.59,78.7 194.68,80.6 194.68,82.55 194.81,82.68 194.81,84.29 194.56,84.54 194.56,85.09 194.79,85.32 197.75,85.32 198.64,84.43 201.52,84.43 201.92,84.84 201.92,85.47 202.16,85.71 203.09,85.71 203.17,85.71 203.42,85.96 204.23,85.96
AGND on SVCC (solid shape): 204.46,85.73 204.46,85.35 204.86,84.94 206.65,84.94 206.75,84.84 206.75,84.33 207.15,83.93 209.01,83.93 209.4,84.31 210.7,84.31 210.81,84.2 210.81,83.82 211.21,83.42 212.06,83.42 212.08,83.4 212.08,82.68 211.47,82.07 210,82.07 209.16,81.24 209.16,78.11 209.56,77.7 209.89,77.7 210.05,77.55 210.05,76.46 210.45,76.05 212.57,76.05 213.2,76.69 213.73,76.69 214.37,77.32 214.37,78.39 214.44,78.47 215.13,78.47 215.13,78.36 215.66,77.83 218.58,77.83 218.69,77.73 218.69,77.09 219.09,76.69 219.81,76.69 220.06,76.94 220.36,76.94 221.12,76.18 222.64,76.18 223.41,75.42 224.3,75.42 224.66,75.06 224.66,74.15 224.2,73.69 201.21,73.69 199.23,75.67 196.82,75.67 196.59,75.9 196.59,78.7 194.68,80.6 194.68,82.53 194.81,82.66 194.81,84.29 194.56,84.54 194.56,85.09 194.79,85.32 197.75,85.32 198.64,84.43 201.52,84.43 201.91,84.83 201.91,84.83 202.18,85.09 202.18,85.35 202.54,85.7 203.17,85.7 203.43,85.96 204.23,85.96
GND on TOP (solid shape): 109.97,83.67 106.42,83.67 106.42,85.7 109.97,85.7
GND on TOP (solid shape): 14.19,22.94 14.19,19.84 13.71,19.36 12.51,19.36 12.41,19.46 12.41,22.89 12.59,23.07 14.06,23.07
GND on TOP (solid shape): 50.54,96.5 50.54,94.47 50.48,94.4 46.02,94.4 45.71,94.71 45.71,96.09 46.4,96.78 50.26,96.78
GND on TOP (solid shape): 219.32,81.39 219.32,78.72 219.07,78.47 214.75,78.47 214.34,78.87 214.34,80.27 214.44,80.37 215.46,80.37 215.64,80.55 215.64,81.89 215.77,82.02 218.69,82.02
GND on TOP (solid shape): 271.77,110.86 268.9,110.86 268.33,110.62 268.09,110.05 268.09,83.25 268.33,82.68 268.9,82.44 271.58,82.44 271.65,82.38 271.65,81.98 271.6,81.93 268.9,81.93 267.97,82.32 267.58,83.25 267.58,110.05 267.97,110.98 268.9,111.37 271.77,111.37
GND on TOP (solid shape): outline of 87 points within 58.41,116.72 70.96,119.74
GND on TOP (solid shape): outline of 222 points within 0.51,3.28 289.19,121.49
GND on BOTTOM (solid shape): 285.23,71.36 268.98,71.36 268.98,71.87 285.23,71.87
GND on BOTTOM (solid shape): 219.32,81.89 219.32,78.34 219.19,78.21 215.64,78.21 215.51,78.34 215.51,81.89 215.64,82.02 219.19,82.02
GND on BOTTOM (solid shape): 249.93,97.01 249.93,94.98 249.8,94.85 247.77,94.85 247.64,94.98 247.64,97.01 247.77,97.13 249.8,97.13
GND on BOTTOM (solid shape): 163.7,105.9 163.7,102.98 161.54,102.98 161.28,103.23 161.28,105.39 162.04,106.15 163.44,106.15
GND on BOTTOM (solid shape): 72.51,21.87 72.51,20.3 72.13,19.92 70.48,19.92 70.35,20.05 70.35,21.7 70.58,21.93 72.46,21.93
GND on BOTTOM (solid shape): 96.84,103.59 96.84,102.19 96.72,102.06 95.47,102.06 95.27,102.27 94.23,102.27 94.07,102.42 94.07,103.74 94.15,103.82 96.61,103.82
GND on BOTTOM (solid shape): 190.87,93.2 190.87,90.91 190.37,90.4 188.46,90.4 188.21,90.66 188.21,93.83 188.33,93.96 190.11,93.96
GND on BOTTOM (solid shape): 67.53,102.52 67.78,102.52 67.95,102.36 67.95,101.31 67.81,101.17 67.25,101.17 67.15,101.27 67.15,101.71 66.46,102.4 66.46,102.7 66.55,102.78 67.27,102.78
GND on BOTTOM (solid shape): 38.47,17.25 40.12,17.25 40.25,17.12 40.25,15.35 40,15.09 34.66,15.09 34.54,15.22 34.54,17.51 34.79,17.76 37.97,17.76
GND on BOTTOM (solid shape): 50.44,100.79 50.44,99.45 50.39,99.4 46.96,99.4 46.86,99.5 46.86,100.01 46.35,100.51 46.35,100.96 46.46,101.07 50.16,101.07
GND on BOTTOM (solid shape): 33.01,103.36 33.01,90.84 32.81,90.63 30.42,90.63 30.22,90.84 30.22,103.33 30.29,103.41 32.96,103.41
GND on BOTTOM (solid shape): 55.59,95.6 55.59,92.54 55.41,92.36 53.97,92.36 53.71,92.11 52.77,92.11 52.67,92.21 52.67,95.59 52.7,95.61 54.22,95.61 54.36,95.75 55.44,95.75
GND on BOTTOM (solid shape): 113.2,107.88 113.2,106.61 112.46,105.87 104.36,105.87 102.81,107.42 102.81,107.73 102.89,107.8 104.06,107.8 104.07,107.82 111.84,107.82 112.26,108.23 112.84,108.23
GND on BOTTOM (solid shape): 12.59,70.67 12.59,69.93 12.49,69.83 12.49,67.26 12.44,67.21 12.16,67.21 12.16,69.22 12.08,69.3 11.63,69.3 11.4,69.07 11.22,69.07 11.04,69.25 11.04,69.63 12.16,70.74 12.51,70.74
GND on BOTTOM (solid shape): 241.67,94.85 242.31,94.21 242.31,93.2 242.18,93.07 238.24,93.07 237.99,93.32 237.99,93.73 238.5,94.24 238.5,94.95 239.25,95.7 240.42,95.7 240.5,95.79 241.67,95.79
GND on BOTTOM (solid shape): 245.31,94.52 245.31,93.91 245.36,93.86 245.97,93.86 246.03,93.79 246.03,92.37 246.09,92.31 246.35,92.31 246.5,92.16 246.5,91.34 246.25,91.09 245.43,91.09 244.34,92.18 244.34,94.47 244.47,94.59 245.23,94.59
GND on BOTTOM (solid shape): 44.44,96.89 44.44,95.52 44.44,95.52 44.44,95.19 44.44,95.19 44.44,93.67 44.06,93.3 44.06,92.77 43.98,92.69 43.05,92.69 42.79,92.94 42.79,96.96 42.81,96.99 42.84,97.01 44.32,97.01
GND on BOTTOM (solid shape): 182.78,104.26 182.9,104.18 183.03,104.15 183.05,104.15 183.08,104.12 183.08,102.77 182.83,102.53 180.8,102.53 180.43,102.9 180.43,103.51 181.18,104.26
GND on BOTTOM (solid shape): 204.4,89.35 204.4,88.51 204.74,88.17 204.74,87.91 204.54,87.72 204.01,87.72 204,87.71 203.7,87.71 203.62,87.64 203.22,87.64 203.17,87.69 203.17,88.04 203.62,88.5 203.62,89.19 203.85,89.41 204.34,89.41
GND on BOTTOM (solid shape): 145.93,109.44 148.59,109.44 149.31,108.73 149.31,108.22 149.55,107.98 149.8,107.98 149.9,107.88 149.9,107.5 149.89,107.46 149.85,107.45 148.48,107.45 148.35,107.57 142.11,107.57 141.95,107.73 141.95,110.32 142.11,110.47 144.9,110.47
GND on BOTTOM (solid shape): 41.9,104.88 41.9,104.5 41.78,104.37 41.14,104.37 40.94,104.17 40.94,103.54 41.39,103.08 41.95,103.08 42.1,102.93 42.1,101.86 41.95,101.71 41.52,101.71 39.49,103.74 39.49,104.17 40.33,105.01 41.78,105.01
GND on BOTTOM (solid shape): 184.14,110.5 184.14,110.04 184.09,109.99 179.54,109.99 179.34,109.78 179.34,109.12 179.27,109.05 177.33,109.05 177.09,109.29 176.98,109.29 176.89,109.38 176.29,109.38 176.24,109.43 176.24,110.65 176.4,110.8 183.84,110.8
GND on BOTTOM (solid shape): 155.06,96.5 155.06,94.44 154.81,94.19 152.04,94.19 151.76,94.47 150.74,94.47 150.46,94.19 148.86,94.19 148.71,94.34 144.9,94.34 144.77,94.21 144.77,92.56 144.65,92.44 143.63,92.44 143.5,92.56 143.5,95.23 142.87,95.86 142.87,96.75 142.99,96.88 154.68,96.88
GND on BOTTOM (solid shape): 30.6,111.49 30.6,110.34 30.47,110.22 21.07,110.22 20.82,109.96 20.82,108.9 21.28,108.44 21.71,108.44 22.09,108.06 22.09,98.4 21.96,98.28 20.06,98.28 19.55,98.79 19.55,101.71 19.04,102.21 19.04,111.61 19.3,111.87 30.22,111.87
GND on BOTTOM (solid shape): 59.67,96 59.67,95.83 59.89,95.61 60.7,95.61 60.83,95.48 60.83,93.83 60.44,93.45 60.44,91.75 60.29,91.6 60.29,90.85 59.72,90.28 59.3,90.28 59.3,90.3 59,90.61 59,92.72 59.25,92.97 59.25,95.28 59.05,95.48 58.92,95.48 58.54,95.86 58.54,95.99 58.67,96.12 59.56,96.12
GND on BOTTOM (solid shape): 26.03,105.39 26.03,93.2 26.28,92.94 26.28,90.4 26.15,90.28 25.39,90.28 24.88,90.78 24.88,95.86 24,96.75 24,97.9 24.12,98.02 24.38,98.02 24.78,98.43 24.78,100.16 24.25,100.69 24.25,101.71 24.91,102.37 24.91,105.42 25.01,105.52 25.9,105.52
GND on BOTTOM (solid shape): 210.49,88.01 210.72,88.01 210.85,87.88 210.85,87.09 211.1,86.84 211.1,85.71 211.35,85.47 211.35,85.45 211.43,85.36 211.43,84.71 211.29,84.57 211.1,84.57 210.79,84.89 210.56,84.89 210.43,85.02 210.43,85.65 210.3,85.78 210.3,86.82 210.12,87 210.12,87.8 209.95,87.97 209.38,87.97 209,87.59 208.57,87.59 208.46,87.7 208.46,87.87 208.54,87.94 208.92,87.94 209.27,88.3 210.21,88.3
GND on BOTTOM (solid shape): 166.49,89.13 166.49,88.24 165.98,87.74 165.98,87.41 165.75,87.18 164.89,87.18 164.79,87.08 164.79,85.12 164.74,85.07 164.03,85.07 163.97,85.12 163.97,87.15 163.87,87.25 163.64,87.25 163.54,87.15 163.54,85.12 163.49,85.07 162.81,85.07 162.76,85.12 162.76,87.15 162.65,87.25 162.37,87.25 162.3,87.18 162.3,85.15 162.22,85.07 161.66,85.07 161.41,85.32 161.41,88.5 161.92,89.01 163.7,89.01 164.46,89.77 165.85,89.77
GND on BOTTOM (solid shape): 53.43,111.03 53.43,106.76 53.15,106.48 47.77,106.48 47.69,106.56 47.69,107.14 47.9,107.35 49.6,107.35 50.06,107.8 50.06,109.83 49.8,110.09 49.01,110.09 48.84,109.91 48.84,109.38 48.73,109.28 48.48,109.28 48.4,109.35 48.4,110.29 48.2,110.5 45.99,110.5 45.66,110.17 45.66,109.23 46.02,108.87 46.02,108.56 45.84,108.39 42.51,108.39 42,108.9 42,110.6 42.54,111.13 53.33,111.13
GND on BOTTOM (solid shape): 185.36,88.65 185.36,87.76 184.62,87.76 183.13,86.26 181.53,86.26 180.51,85.25 179.67,85.25 179.27,84.84 179.27,83.47 179.82,82.91 181.45,82.91 181.45,81.67 181.04,81.67 180.92,81.54 180.92,79.41 180.99,79.33 182.44,79.33 182.52,79.41 182.52,80.85 182.85,80.85 182.92,80.78 182.92,78.29 182.85,78.21 179.87,78.21 179.44,78.64 179.44,81.84 178.53,82.76 178.53,86.29 178.68,86.44 178.68,88.22 178.83,88.37 181.58,88.37 181.7,88.5 181.7,88.75 181.96,89.01 185.01,89.01
GND on BOTTOM (solid shape): 38.75,103.1 39.62,103.1 40.12,102.6 40.12,93.5 39.37,92.75 39.37,92.41 39.36,92.37 39.33,92.36 38.9,92.05 38.99,91.53 39.02,91.46 39,91.4 38.95,91.31 38.93,91.22 38.93,90.99 38.85,90.91 37.2,90.91 37.08,91.04 37.08,103.21 37.36,103.48 38.37,103.48
GND on BOTTOM (solid shape): 20.29,17.35 20.59,17.35 20.63,17.35 21.27,17.35 21.31,17.35 21.56,17.35 22.04,16.87 22.04,16.82 22.09,16.82 22.12,16.79 23.11,16.79 23.14,16.78 23.16,16.74 23.16,16.13 23.05,15.85 23.16,15.58 22.95,15.37 21.19,15.37 21.15,15.39 21.14,15.42 21.14,16.19 20.44,16.88 20.24,16.88 20.2,16.9 20.19,16.93 20.19,17.3 20.2,17.34 20.24,17.35
GND on BOTTOM (solid shape): 18.51,26.37 25.01,26.37 25.62,25.76 31.36,25.76 31.41,25.71 39.16,25.71 39.24,25.63 39.24,24.36 38.85,23.98 36.42,23.98 36.3,24.11 36.3,24.24 36.29,24.24 35.9,24.74 35.6,24.17 35.6,24.09 35.5,23.98 24.83,23.98 24.2,24.62 22.34,24.62 21.81,24.08 21.81,23.04 22.01,22.84 22.02,22.84 22.04,22.82 23,22.82 23.11,22.71 23.11,20.95 22.97,20.81 18.41,20.81 18.28,20.93 18.28,24.34 17.75,24.87 16.25,24.87 15.56,25.56 15.56,26.9 15.82,27.16 17.72,27.16
GND on BOTTOM (solid shape): 89.6,112.93 89.6,109.05 86.83,106.28 81.64,106.28 81.27,105.91 77.91,105.91 77.87,105.95 77.87,106.96 78.2,107.29 79.37,107.29 80.13,108.06 80.13,108.82 80,108.95 79.39,108.95 79.24,109.1 79.24,109.63 78.66,110.21 78.66,110.93 78.73,111 78.76,111 78.8,110.99 78.81,110.95 78.81,110.52 79.16,110.52 79.16,110.95 79.17,110.99 79.21,111 79.26,111 79.3,110.99 79.31,110.95 79.31,110.52 79.66,110.52 79.66,110.95 79.68,110.99 79.71,111 79.76,111 79.8,110.99 79.81,110.95 79.81,110.52 80.16,110.52 80.16,110.95 80.17,110.99 80.21,111 81.25,111 81.37,111.13 81.37,111.97 81.78,112.37 83.94,112.37 84.09,112.53 84.09,113.44 84.17,113.52 89.02,113.52
GND on BOTTOM (solid shape): 269.49,110.86 268.9,110.86 268.33,110.62 268.09,110.05 268.09,83.25 268.33,82.68 268.9,82.44 269.11,82.44 269.11,81.93 268.9,81.93 267.97,82.32 267.58,83.25 267.58,110.05 267.97,110.98 268.9,111.37 269.49,111.37
GND on BOTTOM (solid shape): 61.82,102.46 62.4,102.46 63.63,101.23 63.63,100.07 64.53,99.18 64.53,99.05 64.97,98.61 64.97,98.38 65.01,98.24 65.12,98.14 65.13,98.13 65.14,98.11 65.14,97.79 65.11,97.76 65.1,97.76 64.47,97.12 64.45,97.11 64.42,97.11 63.97,96.8 64.19,96.29 64.24,96.22 64.21,96.13 64.1,96.02 64.1,94.65 64.09,94.63 64.09,93.5 64.09,93.49 64.09,93.24 63.71,92.86 63.25,92.86 63.04,92.92 62.83,92.89 62.82,92.88 62.79,92.89 62.76,92.92 62.76,93.75 62.63,93.88 62.63,98.5 62.6,98.53 62.6,98.66 62.22,99.04 61.26,99.04 61.21,99.09 61.21,100.62 61.28,100.69 61.64,100.69 61.82,100.87 61.82,102.01 61.82,102.06 61.64,102.24 61.28,102.24 61.21,102.32 61.21,102.77 61.51,102.77
GND on BOTTOM (solid shape): outline of 105 points within 5.45,36.38 26.64,43.54
GND on BOTTOM (solid shape): outline of 106 points within 45.05,36.35 64.43,41.91
GND on BOTTOM (solid shape): 243.85,71.87 266.06,71.87 266.06,71.36 239.01,71.36 239.01,71.6 238.71,72.31 238,72.61 162,72.61 160.93,72.17 160.49,71.1 160.49,66.6 160.06,65.54 159,65.11 153.5,65.11 152.45,65.54 152.01,66.6 152.01,74.02 151.57,75.09 150.5,75.53 93,75.53 85.92,72.6 82.99,65.52 82.99,26.65 82.48,26.65 82.48,65.52 85.56,72.96 93,76.04 150.5,76.04 151.93,75.45 152.52,74.02 153.53,73 161.34,73 161.67,73.09 162,73.12 224.54,73.12 225.39,73.97 226.48,73.97 226.84,74.33 226.84,78.75 229.71,81.62 234.1,81.62
GND on BOTTOM (solid shape): outline of 171 points within 0.51,3.41 273.99,121.49
GND on SGND (solid shape): outline of 1334 points within 0.51,0.54 289.19,121.49
GND on IN1 (solid shape): 109.97,83.93 106.42,83.93 106.42,85.45 109.97,85.45
GND on IN1 (solid shape): 49.94,97.46 50.01,97.42 50.04,97.34 50.1,97.02 50.37,96.84 50.4,96.82 50.41,96.79 50.41,94.4 50.16,94.15 46.28,94.15 45.59,94.85 45.59,96.37 46.67,97.46
GND on IN1 (solid shape): 271.77,110.86 268.9,110.86 268.33,110.62 268.09,110.05 268.09,83.25 268.33,82.68 268.9,82.44 271.52,82.44 271.52,81.93 268.9,81.93 267.97,82.32 267.58,83.25 267.58,110.05 267.97,110.98 268.9,111.37 271.77,111.37
GND on IN1 (solid shape): outline of 1352 points within 0.51,3.28 289.19,121.49
GND on IN2 (solid shape): 70.1,64.24 68.57,64.24 68.57,67.42 70.1,67.42
GND on IN2 (solid shape): 109.97,83.67 106.42,83.67 106.42,85.7 109.97,85.7
GND on IN2 (solid shape): 50.03,97.26 50.03,96.65 50.21,96.47 50.21,93.5 50.03,93.32 47.12,93.32 45.46,94.99 45.46,97.13 45.84,97.52 49.78,97.52
GND on IN2 (solid shape): 271.65,110.86 268.9,110.86 268.33,110.62 268.09,110.05 268.09,83.25 268.33,82.68 268.9,82.44 271.52,82.44 271.52,81.93 268.9,81.93 267.97,82.32 267.58,83.25 267.58,110.05 267.97,110.98 268.9,111.37 271.65,111.37
GND on IN2 (solid shape): outline of 1389 points within 0.51,3.41 289.19,121.49
GND on SVCC (solid shape): outline of 338 points within 224.02,71.87 288.68,120.98
GND on SVCC (solid shape): outline of 849 points within 1.02,1.33 198.35,120.1
1237BSTPCH on BOTTOM (solid shape): 75.76,113.09 75.84,113.02 75.94,112.98 75.95,112.97 76.42,112.5 76.75,112.5 76.78,112.48 76.78,112.3 76.73,112.25 76.53,112.25 76.06,111.78 75.77,111.78 75.3,112.25 74.85,112.25 74.67,112.43 74.67,113.09 74.72,113.14 75.71,113.14
1237LX on BOTTOM (solid shape): 81.04,112.12 81.04,111.31 81.02,111.28 80.74,111.28 80.69,111.33 78.55,111.33 78.35,111.13 78.35,111.11 78.32,111.08 78.31,111.08 78.31,110.52 78.32,110.52 78.35,110.49 78.35,110.17 78.73,109.78 78.73,108.95 78.61,108.82 77.72,108.82 77.21,108.31 77.21,107.7 76.8,107.29 71.7,107.29 71.42,107.57 71.42,110.52 78.16,110.52 78.16,111.08 77.81,111.08 77.81,110.52 71.42,110.52 71.42,112.07 71.56,112.21 72.04,112.21 72.13,112.12 74.41,112.12 75.33,111.2 76.58,111.2 76.6,111.21 76.66,111.23 76.71,111.27 76.75,111.31 76.79,111.35 76.82,111.4 76.85,111.45 76.88,111.45 77.44,111.45 77.44,111.52 77.5,111.57 77.57,111.57 77.57,111.64 77.61,111.69 77.61,112.17 77.69,112.25 80.92,112.25
8008LX1.5V on BOTTOM (solid shape): 129.35,112.88 129.35,110.29 126.71,110.29 126.61,110.4 126.61,112.83 126.71,112.93 129.3,112.93
51216DRVL on BOTTOM (solid shape): 23.39,23.98 23.39,23.5 23.04,23.15 22.24,23.15 22.22,23.17 22.22,23.96 22.39,24.14 23.23,24.14
51216DRVL on BOTTOM (solid shape): 16.53,23.14 16.53,22.69 16.38,22.54 15.9,22.54 15.26,21.9 14.5,21.9 14.44,21.95 14.44,22.05 14.47,22.08 14.62,22.08 15.05,22.51 15.05,23 15.45,23.4 16.27,23.4
51216DRVL on IN1 (solid shape): 16.12,23.86 16.12,22.33 15.99,22.2 15.49,22.2 15.23,22.46 15.23,23.73 15.49,23.98 15.99,23.98
51216DRVL on IN1 (solid shape): 23.36,24.11 23.36,23.47 22.98,23.09 21.96,23.09 21.71,23.35 21.71,24.24 21.96,24.49 22.98,24.49
51216SW on BOTTOM (solid shape): 16.38,21.32 16.76,21.32 16.88,21.19 16.88,20.5 16.81,20.43 16.38,20.43 15.74,21.06 15.74,21.44 15.87,21.57 16.12,21.57
